# iorx74m register map
Registers are 32-bit, access not given, no defined reset value unless marked. A register's access mark holds for its fields unless they carry their own. Addresses are absolute; registers are grouped by the start of their names; [hi:lo] are bit positions; {n}, {i} and the like mark numbered series.

## ADC
0x87438000 ADC_B
  [0] ADCLKENR.CLKEN
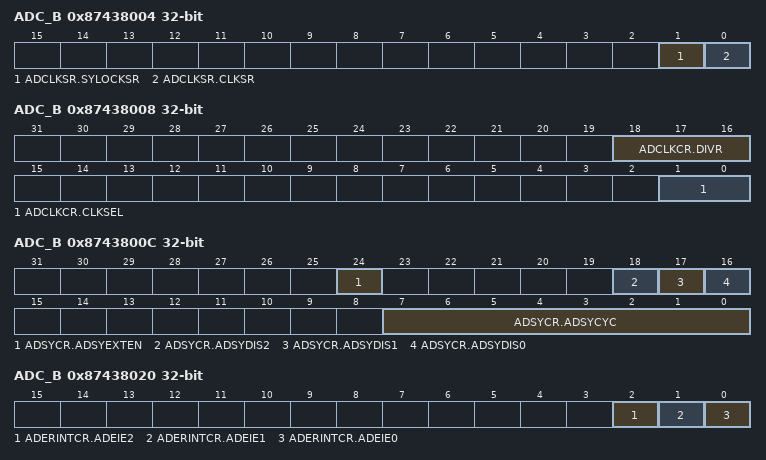
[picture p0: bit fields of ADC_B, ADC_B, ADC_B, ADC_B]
0x87438004 ADC_B
  [1] ADCLKSR.SYLOCKSR, [0] ADCLKSR.CLKSR
0x87438008 ADC_B
  [18:16] ADCLKCR.DIVR, [1:0] ADCLKCR.CLKSEL
0x8743800C ADC_B
  [24] ADSYCR.ADSYEXTEN, [18] ADSYCR.ADSYDIS2, [17] ADSYCR.ADSYDIS1, [16] ADSYCR.ADSYDIS0, [7:0] ADSYCR.ADSYCYC
0x87438010 ADC_B
  [0] ADUSLPCR0.ADUSLP0
0x87438014 ADC_B
  [0] ADUSLPCR1.ADUSLP1
0x87438018 ADC_B
  [0] ADUSLPCR2.ADUSLP2
0x87438020 ADC_B
  [2] ADERINTCR.ADEIE2, [1] ADERINTCR.ADEIE1, [0] ADERINTCR.ADEIE0
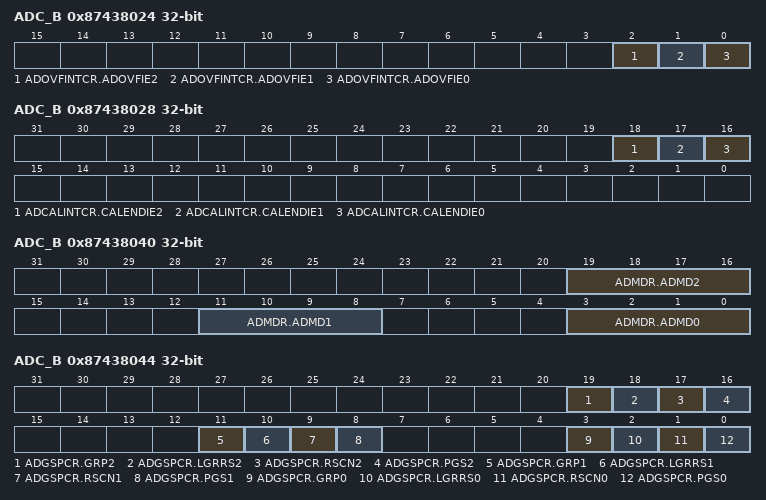
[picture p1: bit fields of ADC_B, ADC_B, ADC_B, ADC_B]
0x87438024 ADC_B
  [2] ADOVFINTCR.ADOVFIE2, [1] ADOVFINTCR.ADOVFIE1, [0] ADOVFINTCR.ADOVFIE0
0x87438028 ADC_B
  [18] ADCALINTCR.CALENDIE2, [17] ADCALINTCR.CALENDIE1, [16] ADCALINTCR.CALENDIE0
0x87438040 ADC_B
  [19:16] ADMDR.ADMD2, [11:8] ADMDR.ADMD1, [3:0] ADMDR.ADMD0
0x87438044 ADC_B
  [19] ADGSPCR.GRP2, [18] ADGSPCR.LGRRS2, [17] ADGSPCR.RSCN2, [16] ADGSPCR.PGS2, [11] ADGSPCR.GRP1, [10] ADGSPCR.LGRRS1, [9] ADGSPCR.RSCN1, [8] ADGSPCR.PGS1, [3] ADGSPCR.GRP0, [2] ADGSPCR.LGRRS0, [1] ADGSPCR.RSCN0, [0] ADGSPCR.PGS0
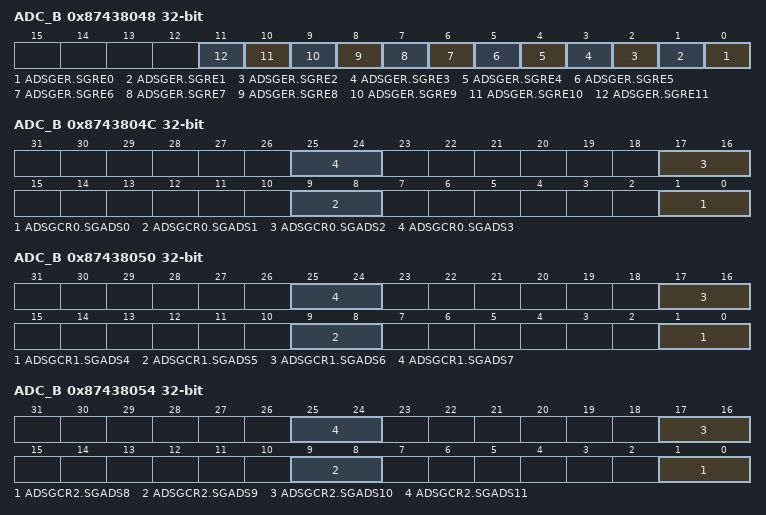
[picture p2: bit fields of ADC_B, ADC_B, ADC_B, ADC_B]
0x87438048 ADC_B
  [n] ADSGER.SGRE{n} (n=0..11)
0x8743804C ADC_B
  [8n+1:8n] ADSGCR0.SGADS{n} (n=0..3)
0x87438050 ADC_B
  [8n-31:8n-32] ADSGCR1.SGADS{n} (n=4..7)
0x87438054 ADC_B
  [8n-63:8n-64] ADSGCR2.SGADS{n} (n=8..11)
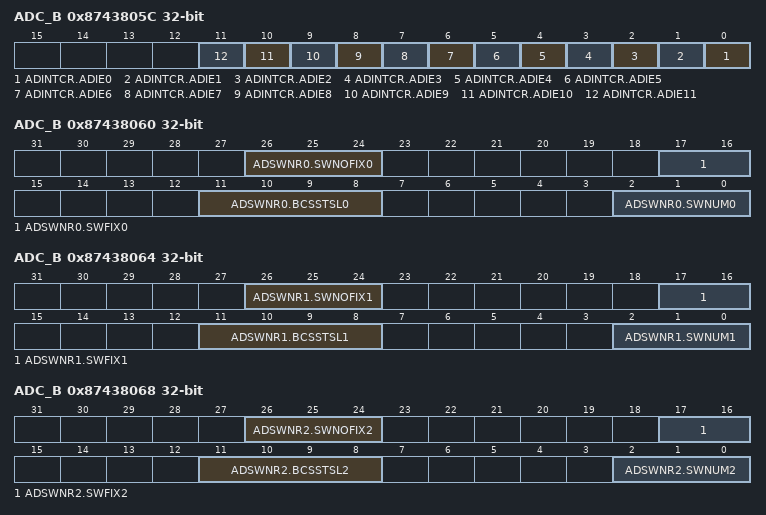
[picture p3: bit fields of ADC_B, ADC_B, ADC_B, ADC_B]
0x8743805C ADC_B
  [n] ADINTCR.ADIE{n} (n=0..11)
0x87438060 ADC_B
  [26:24] ADSWNR0.SWNOFIX0, [17:16] ADSWNR0.SWFIX0, [11:8] ADSWNR0.BCSSTSL0, [2:0] ADSWNR0.SWNUM0
0x87438064 ADC_B
  [26:24] ADSWNR1.SWNOFIX1, [17:16] ADSWNR1.SWFIX1, [11:8] ADSWNR1.BCSSTSL1, [2:0] ADSWNR1.SWNUM1
0x87438068 ADC_B
  [26:24] ADSWNR2.SWNOFIX2, [17:16] ADSWNR2.SWFIX2, [11:8] ADSWNR2.BCSSTSL2, [2:0] ADSWNR2.SWNUM2
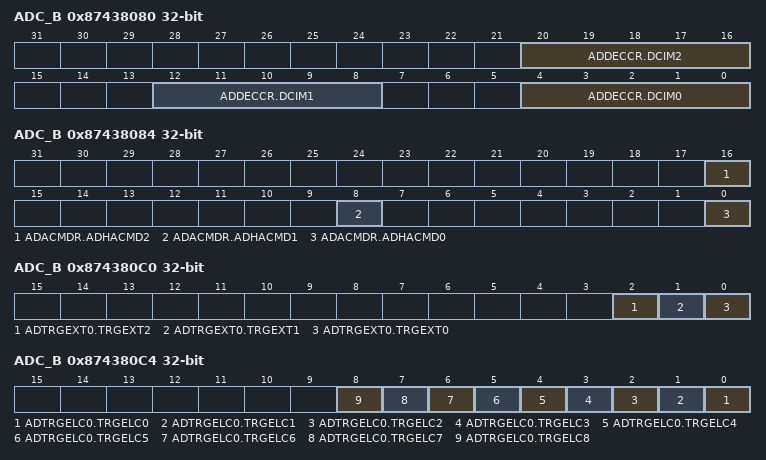
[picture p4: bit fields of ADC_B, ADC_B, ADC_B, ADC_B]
0x87438080 ADC_B
  [20:16] ADDECCR.DCIM2, [12:8] ADDECCR.DCIM1, [4:0] ADDECCR.DCIM0
0x87438084 ADC_B
  [16] ADACMDR.ADHACMD2, [8] ADACMDR.ADHACMD1, [0] ADACMDR.ADHACMD0
0x874380C0 ADC_B
  [2] ADTRGEXT0.TRGEXT2, [1] ADTRGEXT0.TRGEXT1, [0] ADTRGEXT0.TRGEXT0
0x874380C4 ADC_B
  [n] ADTRGELC0.TRGELC{n} (n=0..8)
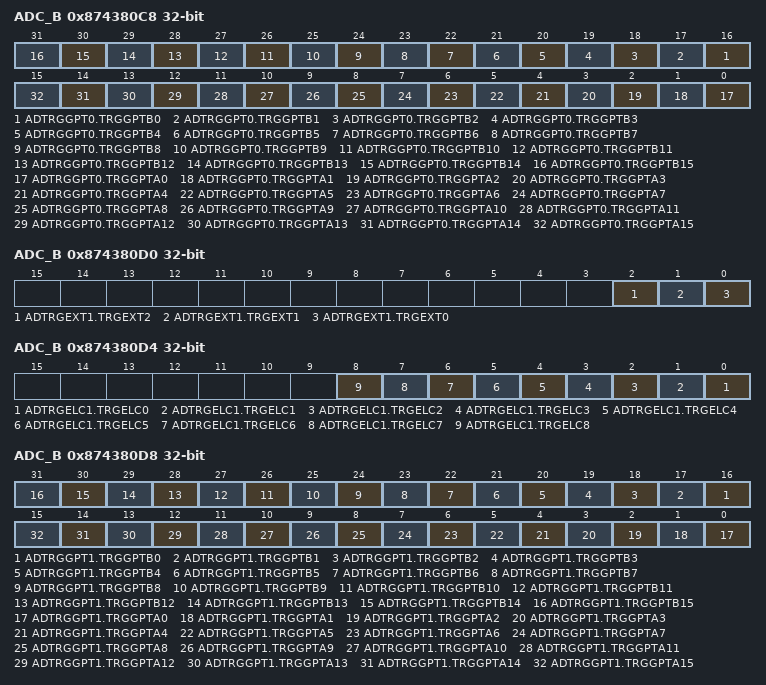
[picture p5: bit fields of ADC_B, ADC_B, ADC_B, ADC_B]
0x874380C8 ADC_B
  [n+16] ADTRGGPT0.TRGGPTB{n} (n=0..15), [n] ADTRGGPT0.TRGGPTA{n} (n=0..15)
0x874380D0 ADC_B
  [2] ADTRGEXT1.TRGEXT2, [1] ADTRGEXT1.TRGEXT1, [0] ADTRGEXT1.TRGEXT0
0x874380D4 ADC_B
  [n] ADTRGELC1.TRGELC{n} (n=0..8)
0x874380D8 ADC_B
  [n+16] ADTRGGPT1.TRGGPTB{n} (n=0..15), [n] ADTRGGPT1.TRGGPTA{n} (n=0..15)
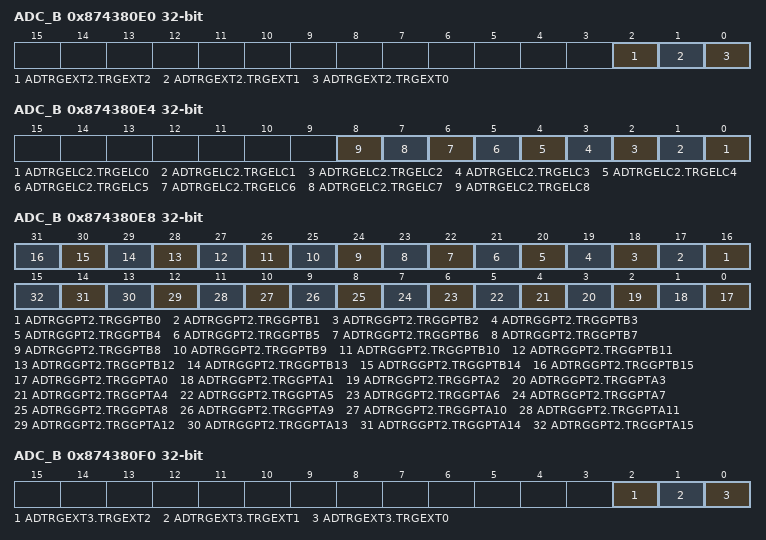
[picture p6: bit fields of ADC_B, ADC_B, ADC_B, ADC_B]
0x874380E0 ADC_B
  [2] ADTRGEXT2.TRGEXT2, [1] ADTRGEXT2.TRGEXT1, [0] ADTRGEXT2.TRGEXT0
0x874380E4 ADC_B
  [n] ADTRGELC2.TRGELC{n} (n=0..8)
0x874380E8 ADC_B
  [n+16] ADTRGGPT2.TRGGPTB{n} (n=0..15), [n] ADTRGGPT2.TRGGPTA{n} (n=0..15)
0x874380F0 ADC_B
  [2] ADTRGEXT3.TRGEXT2, [1] ADTRGEXT3.TRGEXT1, [0] ADTRGEXT3.TRGEXT0
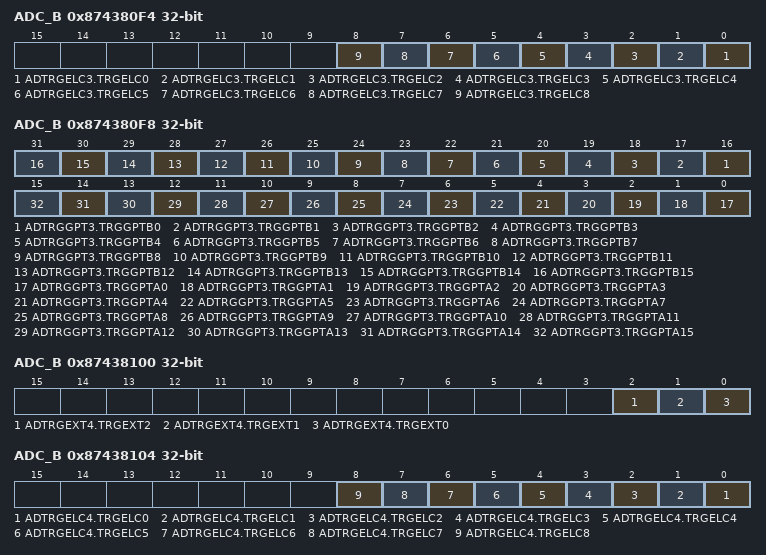
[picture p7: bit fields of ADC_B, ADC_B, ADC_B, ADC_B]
0x874380F4 ADC_B
  [n] ADTRGELC3.TRGELC{n} (n=0..8)
0x874380F8 ADC_B
  [n+16] ADTRGGPT3.TRGGPTB{n} (n=0..15), [n] ADTRGGPT3.TRGGPTA{n} (n=0..15)
0x87438100 ADC_B
  [2] ADTRGEXT4.TRGEXT2, [1] ADTRGEXT4.TRGEXT1, [0] ADTRGEXT4.TRGEXT0
0x87438104 ADC_B
  [n] ADTRGELC4.TRGELC{n} (n=0..8)
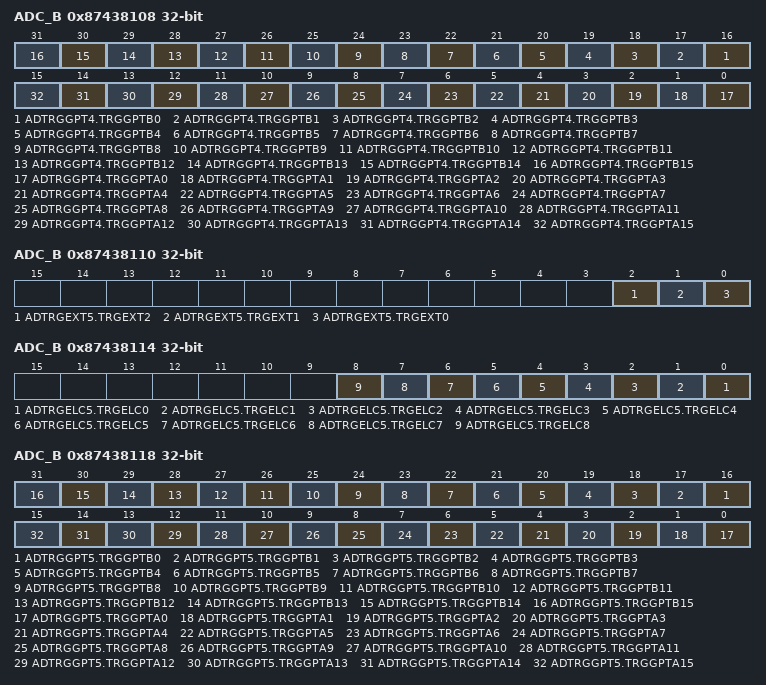
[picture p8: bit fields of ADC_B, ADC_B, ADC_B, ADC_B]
0x87438108 ADC_B
  [n+16] ADTRGGPT4.TRGGPTB{n} (n=0..15), [n] ADTRGGPT4.TRGGPTA{n} (n=0..15)
0x87438110 ADC_B
  [2] ADTRGEXT5.TRGEXT2, [1] ADTRGEXT5.TRGEXT1, [0] ADTRGEXT5.TRGEXT0
0x87438114 ADC_B
  [n] ADTRGELC5.TRGELC{n} (n=0..8)
0x87438118 ADC_B
  [n+16] ADTRGGPT5.TRGGPTB{n} (n=0..15), [n] ADTRGGPT5.TRGGPTA{n} (n=0..15)
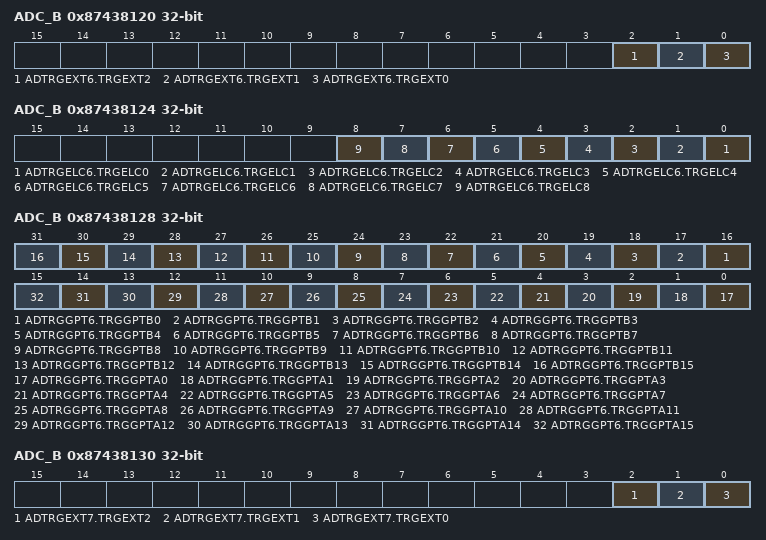
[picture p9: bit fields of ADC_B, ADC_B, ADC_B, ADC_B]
0x87438120 ADC_B
  [2] ADTRGEXT6.TRGEXT2, [1] ADTRGEXT6.TRGEXT1, [0] ADTRGEXT6.TRGEXT0
0x87438124 ADC_B
  [n] ADTRGELC6.TRGELC{n} (n=0..8)
0x87438128 ADC_B
  [n+16] ADTRGGPT6.TRGGPTB{n} (n=0..15), [n] ADTRGGPT6.TRGGPTA{n} (n=0..15)
0x87438130 ADC_B
  [2] ADTRGEXT7.TRGEXT2, [1] ADTRGEXT7.TRGEXT1, [0] ADTRGEXT7.TRGEXT0
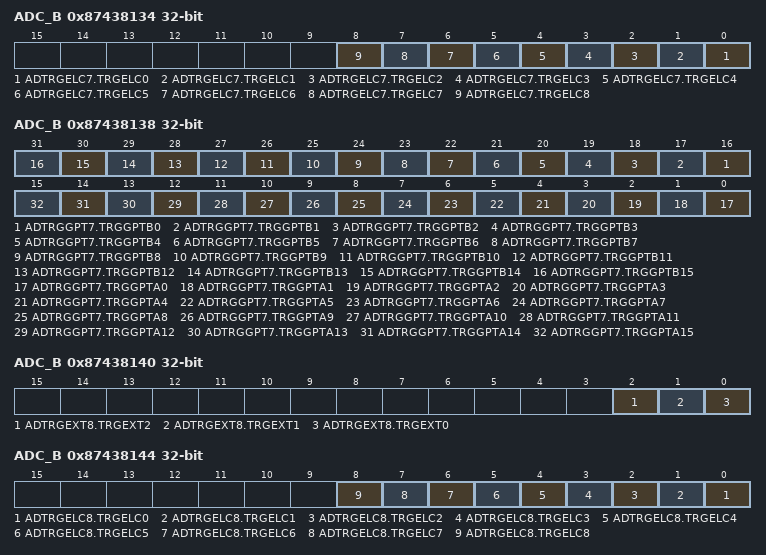
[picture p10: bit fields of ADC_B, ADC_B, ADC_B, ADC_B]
0x87438134 ADC_B
  [n] ADTRGELC7.TRGELC{n} (n=0..8)
0x87438138 ADC_B
  [n+16] ADTRGGPT7.TRGGPTB{n} (n=0..15), [n] ADTRGGPT7.TRGGPTA{n} (n=0..15)
0x87438140 ADC_B
  [2] ADTRGEXT8.TRGEXT2, [1] ADTRGEXT8.TRGEXT1, [0] ADTRGEXT8.TRGEXT0
0x87438144 ADC_B
  [n] ADTRGELC8.TRGELC{n} (n=0..8)
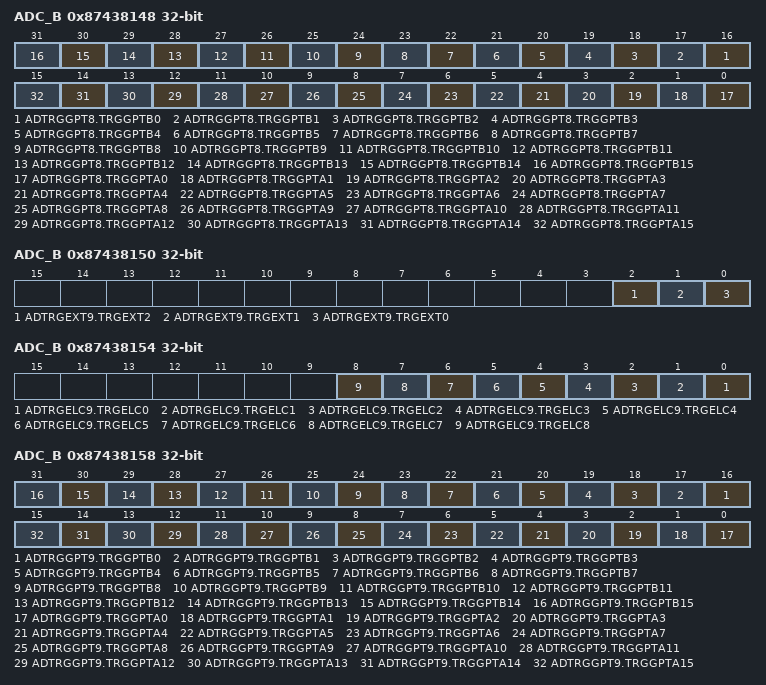
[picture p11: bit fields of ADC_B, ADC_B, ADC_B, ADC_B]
0x87438148 ADC_B
  [n+16] ADTRGGPT8.TRGGPTB{n} (n=0..15), [n] ADTRGGPT8.TRGGPTA{n} (n=0..15)
0x87438150 ADC_B
  [2] ADTRGEXT9.TRGEXT2, [1] ADTRGEXT9.TRGEXT1, [0] ADTRGEXT9.TRGEXT0
0x87438154 ADC_B
  [n] ADTRGELC9.TRGELC{n} (n=0..8)
0x87438158 ADC_B
  [n+16] ADTRGGPT9.TRGGPTB{n} (n=0..15), [n] ADTRGGPT9.TRGGPTA{n} (n=0..15)
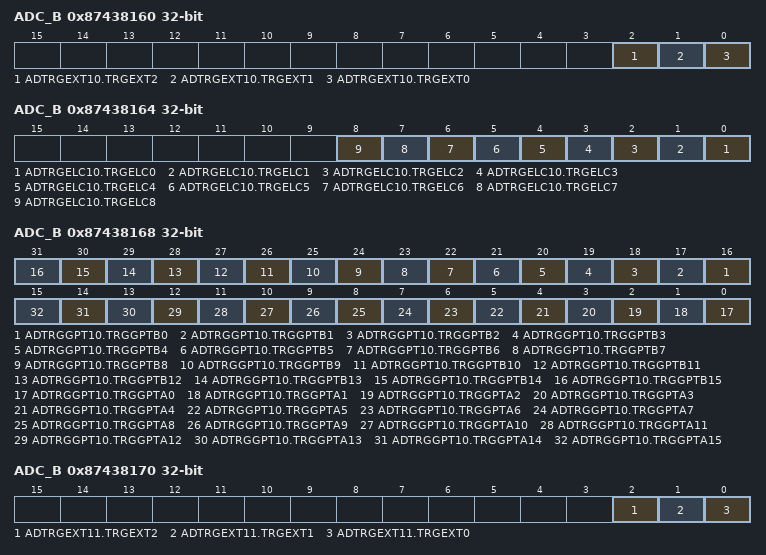
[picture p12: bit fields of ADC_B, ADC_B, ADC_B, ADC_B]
0x87438160 ADC_B
  [2] ADTRGEXT10.TRGEXT2, [1] ADTRGEXT10.TRGEXT1, [0] ADTRGEXT10.TRGEXT0
0x87438164 ADC_B
  [n] ADTRGELC10.TRGELC{n} (n=0..8)
0x87438168 ADC_B
  [n+16] ADTRGGPT10.TRGGPTB{n} (n=0..15), [n] ADTRGGPT10.TRGGPTA{n} (n=0..15)
0x87438170 ADC_B
  [2] ADTRGEXT11.TRGEXT2, [1] ADTRGEXT11.TRGEXT1, [0] ADTRGEXT11.TRGEXT0
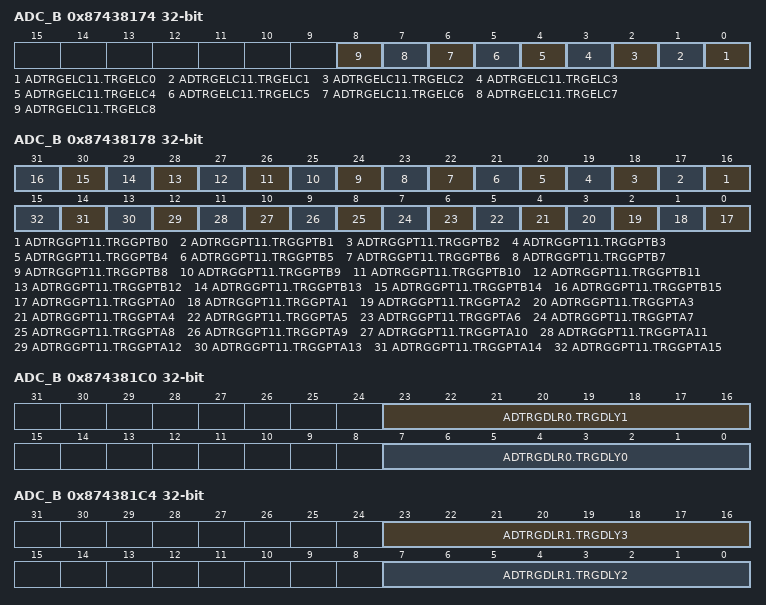
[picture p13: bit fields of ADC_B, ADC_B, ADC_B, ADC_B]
0x87438174 ADC_B
  [n] ADTRGELC11.TRGELC{n} (n=0..8)
0x87438178 ADC_B
  [n+16] ADTRGGPT11.TRGGPTB{n} (n=0..15), [n] ADTRGGPT11.TRGGPTA{n} (n=0..15)
0x874381C0 ADC_B
  [23:16] ADTRGDLR0.TRGDLY1, [7:0] ADTRGDLR0.TRGDLY0
0x874381C4 ADC_B
  [23:16] ADTRGDLR1.TRGDLY3, [7:0] ADTRGDLR1.TRGDLY2
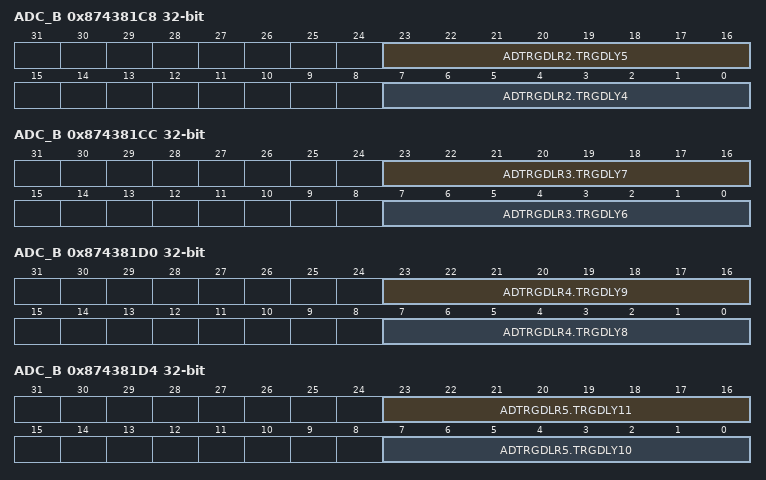
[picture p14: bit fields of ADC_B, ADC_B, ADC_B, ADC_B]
0x874381C8 ADC_B
  [23:16] ADTRGDLR2.TRGDLY5, [7:0] ADTRGDLR2.TRGDLY4
0x874381CC ADC_B
  [23:16] ADTRGDLR3.TRGDLY7, [7:0] ADTRGDLR3.TRGDLY6
0x874381D0 ADC_B
  [23:16] ADTRGDLR4.TRGDLY9, [7:0] ADTRGDLR4.TRGDLY8
0x874381D4 ADC_B
  [23:16] ADTRGDLR5.TRGDLY11, [7:0] ADTRGDLR5.TRGDLY10
0x87438200 ADC_B
  [31:24] ADSGDCR0.ADNDIS, [21] ADSGDCR0.ADDISN, [20] ADSGDCR0.ADDISP, [16] ADSGDCR0.ADDISEN, [2:0] ADSGDCR0.DIAGVAL
0x87438204 ADC_B
  [31:24] ADSGDCR1.ADNDIS, [21] ADSGDCR1.ADDISN, [20] ADSGDCR1.ADDISP, [16] ADSGDCR1.ADDISEN, [2:0] ADSGDCR1.DIAGVAL
0x87438208 ADC_B
  [31:24] ADSGDCR2.ADNDIS, [21] ADSGDCR2.ADDISN, [20] ADSGDCR2.ADDISP, [16] ADSGDCR2.ADDISEN, [2:0] ADSGDCR2.DIAGVAL
0x8743820C ADC_B
  [31:24] ADSGDCR3.ADNDIS, [21] ADSGDCR3.ADDISN, [20] ADSGDCR3.ADDISP, [16] ADSGDCR3.ADDISEN, [2:0] ADSGDCR3.DIAGVAL
0x87438210 ADC_B
  [31:24] ADSGDCR4.ADNDIS, [21] ADSGDCR4.ADDISN, [20] ADSGDCR4.ADDISP, [16] ADSGDCR4.ADDISEN, [2:0] ADSGDCR4.DIAGVAL
0x87438214 ADC_B
  [31:24] ADSGDCR5.ADNDIS, [21] ADSGDCR5.ADDISN, [20] ADSGDCR5.ADDISP, [16] ADSGDCR5.ADDISEN, [2:0] ADSGDCR5.DIAGVAL
0x87438218 ADC_B
  [31:24] ADSGDCR6.ADNDIS, [21] ADSGDCR6.ADDISN, [20] ADSGDCR6.ADDISP, [16] ADSGDCR6.ADDISEN, [2:0] ADSGDCR6.DIAGVAL
0x8743821C ADC_B
  [31:24] ADSGDCR7.ADNDIS, [21] ADSGDCR7.ADDISN, [20] ADSGDCR7.ADDISP, [16] ADSGDCR7.ADDISEN, [2:0] ADSGDCR7.DIAGVAL
0x87438220 ADC_B
  [31:24] ADSGDCR8.ADNDIS, [21] ADSGDCR8.ADDISN, [20] ADSGDCR8.ADDISP, [16] ADSGDCR8.ADDISEN, [2:0] ADSGDCR8.DIAGVAL
0x87438224 ADC_B
  [31:24] ADSGDCR9.ADNDIS, [21] ADSGDCR9.ADDISN, [20] ADSGDCR9.ADDISP, [16] ADSGDCR9.ADDISEN, [2:0] ADSGDCR9.DIAGVAL
0x87438228 ADC_B
  [31:24] ADSGDCR10.ADNDIS, [21] ADSGDCR10.ADDISN, [20] ADSGDCR10.ADDISP, [16] ADSGDCR10.ADDISEN, [2:0] ADSGDCR10.DIAGVAL
0x8743822C ADC_B
  [31:24] ADSGDCR11.ADNDIS, [21] ADSGDCR11.ADDISN, [20] ADSGDCR11.ADDISP, [16] ADSGDCR11.ADDISEN, [2:0] ADSGDCR11.DIAGVAL
0x87438240 ADC_B
  [25:16] ADSSTR0.SST1, [9:0] ADSSTR0.SST0
0x87438244 ADC_B
  [25:16] ADSSTR1.SST3, [9:0] ADSSTR1.SST2
0x87438248 ADC_B
  [25:16] ADSSTR2.SST5, [9:0] ADSSTR2.SST4
0x8743824C ADC_B
  [25:16] ADSSTR3.SST7, [9:0] ADSSTR3.SST6
0x87438250 ADC_B
  [25:16] ADSSTR4.SST9, [9:0] ADSSTR4.SST8
0x87438254 ADC_B
  [25:16] ADSSTR5.SST11, [9:0] ADSSTR5.SST10
0x87438258 ADC_B
  [25:16] ADSSTR6.SST13, [9:0] ADSSTR6.SST12
0x8743825C ADC_B
  [25:16] ADSSTR7.SST15, [9:0] ADSSTR7.SST14
0x87438260 ADC_B
  [21:16] ADCNVSTR.CST2, [13:8] ADCNVSTR.CST1, [5:0] ADCNVSTR.CST0
0x87438264 ADC_B
  [21:16] ADCALSTCR.CALADCST, [9:0] ADCALSTCR.CALADSST
0x87438280 ADC_B
  [18] ADSHCR0.SHMD2, [17] ADSHCR0.SHMD1, [16] ADSHCR0.SHMD0, [2] ADSHCR0.SHEN2, [1] ADSHCR0.SHEN1, [0] ADSHCR0.SHEN0
0x87438284 ADC_B
  [4] ADSHDCR0.SH0DIS, [0] ADSHDCR0.SH0DISEN
0x87438288 ADC_B
  [18:16] ADSHSTR0.SHHST, [7:0] ADSHSTR0.SHSST
0x874382B0 ADC_B
  [18:16] ADCALSHCR.CALSHHST, [7:0] ADCALSHCR.CALSHSST
0x87438310 ADC_B
  [18] ADSHSBPCR.SHSBN2, [17] ADSHSBPCR.SHSBN1, [16] ADSHSBPCR.SHSBN0, [2] ADSHSBPCR.SHSBP2, [1] ADSHSBPCR.SHSBP1, [0] ADSHSBPCR.SHSBP0
0x87438314 ADC_B
  [n] ADSHDBPCR.SHDBP{n} (n=0..11)
0x87438318 ADC_B
  [4n+2:4n] ADSHSDCR0.SHDIAG{n} (n=0..7)
0x8743831C ADC_B
  [4n-30:4n-32] ADSHSDCR1.SHDIAG{n} (n=8..11)
0x87438320 ADC_B
  [0] ADREFCR.VDE
0x87438340 ADC_B
  [8n+1:8n] ADDFSR0.DFSEL{n} (n=0..3)
0x87438344 ADC_B
  [8n+1:8n] ADDFSR1.DFSEL{n} (n=0..3)
0x87438348 ADC_B
  [8n+1:8n] ADDFSR2.DFSEL{n} (n=0..3)
0x87438360 ADC_B
  [15:0] ADUOFTR0.UOFSET
0x87438364 ADC_B
  [15:0] ADUOFTR1.UOFSET
0x87438368 ADC_B
  [15:0] ADUOFTR2.UOFSET
0x8743836C ADC_B
  [15:0] ADUOFTR3.UOFSET
0x87438370 ADC_B
  [15:0] ADUOFTR4.UOFSET
0x87438374 ADC_B
  [15:0] ADUOFTR5.UOFSET
0x87438378 ADC_B
  [15:0] ADUOFTR6.UOFSET
0x8743837C ADC_B
  [15:0] ADUOFTR7.UOFSET
0x87438380 ADC_B
  [15:0] ADUGTR0.UGAIN
0x87438384 ADC_B
  [15:0] ADUGTR1.UGAIN
0x87438388 ADC_B
  [15:0] ADUGTR2.UGAIN
0x8743838C ADC_B
  [15:0] ADUGTR3.UGAIN
0x87438390 ADC_B
  [15:0] ADUGTR4.UGAIN
0x87438394 ADC_B
  [15:0] ADUGTR5.UGAIN
0x87438398 ADC_B
  [15:0] ADUGTR6.UGAIN
0x8743839C ADC_B
  [15:0] ADUGTR7.UGAIN
0x874383A0 ADC_B
  [n] ADLIMINTCR.LIMIE{n} (n=0..11)
0x874383A4 ADC_B
  [31:16] ADLIMTR0.LIMU, [15:0] ADLIMTR0.LIML
0x874383A8 ADC_B
  [31:16] ADLIMTR1.LIMU, [15:0] ADLIMTR1.LIML
0x874383AC ADC_B
  [31:16] ADLIMTR2.LIMU, [15:0] ADLIMTR2.LIML
0x874383B0 ADC_B
  [31:16] ADLIMTR3.LIMU, [15:0] ADLIMTR3.LIML
0x874383B4 ADC_B
  [31:16] ADLIMTR4.LIMU, [15:0] ADLIMTR4.LIML
0x874383B8 ADC_B
  [31:16] ADLIMTR5.LIMU, [15:0] ADLIMTR5.LIML
0x874383BC ADC_B
  [31:16] ADLIMTR6.LIMU, [15:0] ADLIMTR6.LIML
0x874383C0 ADC_B
  [31:16] ADLIMTR7.LIMU, [15:0] ADLIMTR7.LIML
0x87438400 ADC_B
  [n] ADCMPENR.CMPEN{n} (n=0..7)
0x87438404 ADC_B
  [n] ADCMPINTCR.CMPIE{n} (n=0..7)
0x87438408 ADC_B
  [n+16] ADCCMPCR[0].CCMPTBL{n} (n=0..7), [1:0] ADCCMPCR[0].CCMPCND
0x8743840C ADC_B
  [n+16] ADCCMPCR[1].CCMPTBL{n} (n=0..7), [1:0] ADCCMPCR[1].CCMPCND
0x87438410 ADC_B
  [n+16] ADCCMPCR[2].CCMPTBL{n} (n=0..7), [1:0] ADCCMPCR[2].CCMPCND
0x87438414 ADC_B
  [n+16] ADCCMPCR[3].CCMPTBL{n} (n=0..7), [1:0] ADCCMPCR[3].CCMPCND
0x87438418 ADC_B
  [n+16] ADCCMPCR[4].CCMPTBL{n} (n=0..7), [1:0] ADCCMPCR[4].CCMPCND
0x8743841C ADC_B
  [n+16] ADCCMPCR[5].CCMPTBL{n} (n=0..7), [1:0] ADCCMPCR[5].CCMPCND
0x87438420 ADC_B
  [n+16] ADCCMPCR[6].CCMPTBL{n} (n=0..7), [1:0] ADCCMPCR[6].CCMPCND
0x87438424 ADC_B
  [n+16] ADCCMPCR[7].CCMPTBL{n} (n=0..7), [1:0] ADCCMPCR[7].CCMPCND
0x87438448 ADC_B
  [8n+1:8n] ADCMPMDR0.CMPMD{n} (n=0..3)
0x8743844C ADC_B
  [8n-31:8n-32] ADCMPMDR1.CMPMD{n} (n=4..7)
0x87438458 ADC_B
  [31:16] ADCMPTBR[0].CMPTBH, [15:0] ADCMPTBR[0].CMPTBL
0x8743845C ADC_B
  [31:16] ADCMPTBR[1].CMPTBH, [15:0] ADCMPTBR[1].CMPTBL
0x87438460 ADC_B
  [31:16] ADCMPTBR[2].CMPTBH, [15:0] ADCMPTBR[2].CMPTBL
0x87438464 ADC_B
  [31:16] ADCMPTBR[3].CMPTBH, [15:0] ADCMPTBR[3].CMPTBL
0x87438468 ADC_B
  [31:16] ADCMPTBR[4].CMPTBH, [15:0] ADCMPTBR[4].CMPTBL
0x8743846C ADC_B
  [31:16] ADCMPTBR[5].CMPTBH, [15:0] ADCMPTBR[5].CMPTBL
0x87438470 ADC_B
  [31:16] ADCMPTBR[6].CMPTBH, [15:0] ADCMPTBR[6].CMPTBL
0x87438474 ADC_B
  [31:16] ADCMPTBR[7].CMPTBH, [15:0] ADCMPTBR[7].CMPTBL
0x874384C0 ADC_B
  [n+16] ADFIFOCR.FIFOCE{n} (n=0..11), [n] ADFIFOCR.FIFOEN{n} (n=0..11)
0x874384C4 ADC_B
  [n] ADFIFOINTCR.FIFOIE{n} (n=0..11)
0x874384C8 ADC_B
  [20:16] ADFIFOINTLR0.FIFOILV1, [4:0] ADFIFOINTLR0.FIFOILV0
0x874384CC ADC_B
  [20:16] ADFIFOINTLR1.FIFOILV3, [4:0] ADFIFOINTLR1.FIFOILV2
0x874384D0 ADC_B
  [20:16] ADFIFOINTLR2.FIFOILV5, [4:0] ADFIFOINTLR2.FIFOILV4
0x874384D4 ADC_B
  [20:16] ADFIFOINTLR3.FIFOILV7, [4:0] ADFIFOINTLR3.FIFOILV6
0x874384D8 ADC_B
  [20:16] ADFIFOINTLR4.FIFOILV9, [4:0] ADFIFOINTLR4.FIFOILV8
0x874384DC ADC_B
  [20:16] ADFIFOINTLR5.FIFOILV11, [4:0] ADFIFOINTLR5.FIFOILV10
0x87438600 ADC_B
  [19:16] ADCHCR0.SSTSEL, [15] ADCHCR0.AINMD, [14:8] ADCHCR0.CNVCS, [4:0] ADCHCR0.SGSEL
0x87438604 ADC_B
  [27:24] ADDOPCRA0.OFSETSEL, [19:16] ADDOPCRA0.GAINSEL, [2:0] ADDOPCRA0.DFSEL
0x87438608 ADC_B
  [n+16] ADDOPCRB0.CMPTBLE{n} (n=0..7), [11:8] ADDOPCRB0.ADC, [1:0] ADDOPCRB0.AVEMD
0x8743860C ADC_B
  [20] ADDOPCRC0.SIGNSEL, [17:16] ADDOPCRC0.ADPRC, [3:0] ADDOPCRC0.LIMTBLS
0x87438610 ADC_B
  [19:16] ADCHCR1.SSTSEL, [15] ADCHCR1.AINMD, [14:8] ADCHCR1.CNVCS, [4:0] ADCHCR1.SGSEL
0x87438614 ADC_B
  [27:24] ADDOPCRA1.OFSETSEL, [19:16] ADDOPCRA1.GAINSEL, [2:0] ADDOPCRA1.DFSEL
0x87438618 ADC_B
  [n+16] ADDOPCRB1.CMPTBLE{n} (n=0..7), [11:8] ADDOPCRB1.ADC, [1:0] ADDOPCRB1.AVEMD
0x8743861C ADC_B
  [20] ADDOPCRC1.SIGNSEL, [17:16] ADDOPCRC1.ADPRC, [3:0] ADDOPCRC1.LIMTBLS
0x87438620 ADC_B
  [19:16] ADCHCR2.SSTSEL, [15] ADCHCR2.AINMD, [14:8] ADCHCR2.CNVCS, [4:0] ADCHCR2.SGSEL
0x87438624 ADC_B
  [27:24] ADDOPCRA2.OFSETSEL, [19:16] ADDOPCRA2.GAINSEL, [2:0] ADDOPCRA2.DFSEL
0x87438628 ADC_B
  [n+16] ADDOPCRB2.CMPTBLE{n} (n=0..7), [11:8] ADDOPCRB2.ADC, [1:0] ADDOPCRB2.AVEMD
0x8743862C ADC_B
  [20] ADDOPCRC2.SIGNSEL, [17:16] ADDOPCRC2.ADPRC, [3:0] ADDOPCRC2.LIMTBLS
0x87438630 ADC_B
  [19:16] ADCHCR3.SSTSEL, [15] ADCHCR3.AINMD, [14:8] ADCHCR3.CNVCS, [4:0] ADCHCR3.SGSEL
0x87438634 ADC_B
  [27:24] ADDOPCRA3.OFSETSEL, [19:16] ADDOPCRA3.GAINSEL, [2:0] ADDOPCRA3.DFSEL
0x87438638 ADC_B
  [n+16] ADDOPCRB3.CMPTBLE{n} (n=0..7), [11:8] ADDOPCRB3.ADC, [1:0] ADDOPCRB3.AVEMD
0x8743863C ADC_B
  [20] ADDOPCRC3.SIGNSEL, [17:16] ADDOPCRC3.ADPRC, [3:0] ADDOPCRC3.LIMTBLS
0x87438640 ADC_B
  [19:16] ADCHCR4.SSTSEL, [15] ADCHCR4.AINMD, [14:8] ADCHCR4.CNVCS, [4:0] ADCHCR4.SGSEL
0x87438644 ADC_B
  [27:24] ADDOPCRA4.OFSETSEL, [19:16] ADDOPCRA4.GAINSEL, [2:0] ADDOPCRA4.DFSEL
0x87438648 ADC_B
  [n+16] ADDOPCRB4.CMPTBLE{n} (n=0..7), [11:8] ADDOPCRB4.ADC, [1:0] ADDOPCRB4.AVEMD
0x8743864C ADC_B
  [20] ADDOPCRC4.SIGNSEL, [17:16] ADDOPCRC4.ADPRC, [3:0] ADDOPCRC4.LIMTBLS
0x87438650 ADC_B
  [19:16] ADCHCR5.SSTSEL, [15] ADCHCR5.AINMD, [14:8] ADCHCR5.CNVCS, [4:0] ADCHCR5.SGSEL
0x87438654 ADC_B
  [27:24] ADDOPCRA5.OFSETSEL, [19:16] ADDOPCRA5.GAINSEL, [2:0] ADDOPCRA5.DFSEL
0x87438658 ADC_B
  [n+16] ADDOPCRB5.CMPTBLE{n} (n=0..7), [11:8] ADDOPCRB5.ADC, [1:0] ADDOPCRB5.AVEMD
0x8743865C ADC_B
  [20] ADDOPCRC5.SIGNSEL, [17:16] ADDOPCRC5.ADPRC, [3:0] ADDOPCRC5.LIMTBLS
0x87438660 ADC_B
  [19:16] ADCHCR6.SSTSEL, [15] ADCHCR6.AINMD, [14:8] ADCHCR6.CNVCS, [4:0] ADCHCR6.SGSEL
0x87438664 ADC_B
  [27:24] ADDOPCRA6.OFSETSEL, [19:16] ADDOPCRA6.GAINSEL, [2:0] ADDOPCRA6.DFSEL
0x87438668 ADC_B
  [n+16] ADDOPCRB6.CMPTBLE{n} (n=0..7), [11:8] ADDOPCRB6.ADC, [1:0] ADDOPCRB6.AVEMD
0x8743866C ADC_B
  [20] ADDOPCRC6.SIGNSEL, [17:16] ADDOPCRC6.ADPRC, [3:0] ADDOPCRC6.LIMTBLS
0x87438670 ADC_B
  [19:16] ADCHCR7.SSTSEL, [15] ADCHCR7.AINMD, [14:8] ADCHCR7.CNVCS, [4:0] ADCHCR7.SGSEL
0x87438674 ADC_B
  [27:24] ADDOPCRA7.OFSETSEL, [19:16] ADDOPCRA7.GAINSEL, [2:0] ADDOPCRA7.DFSEL
0x87438678 ADC_B
  [n+16] ADDOPCRB7.CMPTBLE{n} (n=0..7), [11:8] ADDOPCRB7.ADC, [1:0] ADDOPCRB7.AVEMD
0x8743867C ADC_B
  [20] ADDOPCRC7.SIGNSEL, [17:16] ADDOPCRC7.ADPRC, [3:0] ADDOPCRC7.LIMTBLS
0x87438680 ADC_B
  [19:16] ADCHCR8.SSTSEL, [15] ADCHCR8.AINMD, [14:8] ADCHCR8.CNVCS, [4:0] ADCHCR8.SGSEL
0x87438684 ADC_B
  [27:24] ADDOPCRA8.OFSETSEL, [19:16] ADDOPCRA8.GAINSEL, [2:0] ADDOPCRA8.DFSEL
0x87438688 ADC_B
  [n+16] ADDOPCRB8.CMPTBLE{n} (n=0..7), [11:8] ADDOPCRB8.ADC, [1:0] ADDOPCRB8.AVEMD
0x8743868C ADC_B
  [20] ADDOPCRC8.SIGNSEL, [17:16] ADDOPCRC8.ADPRC, [3:0] ADDOPCRC8.LIMTBLS
0x87438690 ADC_B
  [19:16] ADCHCR9.SSTSEL, [15] ADCHCR9.AINMD, [14:8] ADCHCR9.CNVCS, [4:0] ADCHCR9.SGSEL
0x87438694 ADC_B
  [27:24] ADDOPCRA9.OFSETSEL, [19:16] ADDOPCRA9.GAINSEL, [2:0] ADDOPCRA9.DFSEL
0x87438698 ADC_B
  [n+16] ADDOPCRB9.CMPTBLE{n} (n=0..7), [11:8] ADDOPCRB9.ADC, [1:0] ADDOPCRB9.AVEMD
0x8743869C ADC_B
  [20] ADDOPCRC9.SIGNSEL, [17:16] ADDOPCRC9.ADPRC, [3:0] ADDOPCRC9.LIMTBLS
0x874386A0 ADC_B
  [19:16] ADCHCR10.SSTSEL, [15] ADCHCR10.AINMD, [14:8] ADCHCR10.CNVCS, [4:0] ADCHCR10.SGSEL
0x874386A4 ADC_B
  [27:24] ADDOPCRA10.OFSETSEL, [19:16] ADDOPCRA10.GAINSEL, [2:0] ADDOPCRA10.DFSEL
0x874386A8 ADC_B
  [n+16] ADDOPCRB10.CMPTBLE{n} (n=0..7), [11:8] ADDOPCRB10.ADC, [1:0] ADDOPCRB10.AVEMD
0x874386AC ADC_B
  [20] ADDOPCRC10.SIGNSEL, [17:16] ADDOPCRC10.ADPRC, [3:0] ADDOPCRC10.LIMTBLS
0x874386B0 ADC_B
  [19:16] ADCHCR11.SSTSEL, [15] ADCHCR11.AINMD, [14:8] ADCHCR11.CNVCS, [4:0] ADCHCR11.SGSEL
0x874386B4 ADC_B
  [27:24] ADDOPCRA11.OFSETSEL, [19:16] ADDOPCRA11.GAINSEL, [2:0] ADDOPCRA11.DFSEL
0x874386B8 ADC_B
  [n+16] ADDOPCRB11.CMPTBLE{n} (n=0..7), [11:8] ADDOPCRB11.ADC, [1:0] ADDOPCRB11.AVEMD
0x874386BC ADC_B
  [20] ADDOPCRC11.SIGNSEL, [17:16] ADDOPCRC11.ADPRC, [3:0] ADDOPCRC11.LIMTBLS
0x874386C0 ADC_B
  [19:16] ADCHCR12.SSTSEL, [15] ADCHCR12.AINMD, [14:8] ADCHCR12.CNVCS, [4:0] ADCHCR12.SGSEL
0x874386C4 ADC_B
  [27:24] ADDOPCRA12.OFSETSEL, [19:16] ADDOPCRA12.GAINSEL, [2:0] ADDOPCRA12.DFSEL
0x874386C8 ADC_B
  [n+16] ADDOPCRB12.CMPTBLE{n} (n=0..7), [11:8] ADDOPCRB12.ADC, [1:0] ADDOPCRB12.AVEMD
0x874386CC ADC_B
  [20] ADDOPCRC12.SIGNSEL, [17:16] ADDOPCRC12.ADPRC, [3:0] ADDOPCRC12.LIMTBLS
0x874386D0 ADC_B
  [19:16] ADCHCR13.SSTSEL, [15] ADCHCR13.AINMD, [14:8] ADCHCR13.CNVCS, [4:0] ADCHCR13.SGSEL
0x874386D4 ADC_B
  [27:24] ADDOPCRA13.OFSETSEL, [19:16] ADDOPCRA13.GAINSEL, [2:0] ADDOPCRA13.DFSEL
0x874386D8 ADC_B
  [n+16] ADDOPCRB13.CMPTBLE{n} (n=0..7), [11:8] ADDOPCRB13.ADC, [1:0] ADDOPCRB13.AVEMD
0x874386DC ADC_B
  [20] ADDOPCRC13.SIGNSEL, [17:16] ADDOPCRC13.ADPRC, [3:0] ADDOPCRC13.LIMTBLS
0x874386E0 ADC_B
  [19:16] ADCHCR14.SSTSEL, [15] ADCHCR14.AINMD, [14:8] ADCHCR14.CNVCS, [4:0] ADCHCR14.SGSEL
0x874386E4 ADC_B
  [27:24] ADDOPCRA14.OFSETSEL, [19:16] ADDOPCRA14.GAINSEL, [2:0] ADDOPCRA14.DFSEL
0x874386E8 ADC_B
  [n+16] ADDOPCRB14.CMPTBLE{n} (n=0..7), [11:8] ADDOPCRB14.ADC, [1:0] ADDOPCRB14.AVEMD
0x874386EC ADC_B
  [20] ADDOPCRC14.SIGNSEL, [17:16] ADDOPCRC14.ADPRC, [3:0] ADDOPCRC14.LIMTBLS
0x874386F0 ADC_B
  [19:16] ADCHCR15.SSTSEL, [15] ADCHCR15.AINMD, [14:8] ADCHCR15.CNVCS, [4:0] ADCHCR15.SGSEL
0x874386F4 ADC_B
  [27:24] ADDOPCRA15.OFSETSEL, [19:16] ADDOPCRA15.GAINSEL, [2:0] ADDOPCRA15.DFSEL
0x874386F8 ADC_B
  [n+16] ADDOPCRB15.CMPTBLE{n} (n=0..7), [11:8] ADDOPCRB15.ADC, [1:0] ADDOPCRB15.AVEMD
0x874386FC ADC_B
  [20] ADDOPCRC15.SIGNSEL, [17:16] ADDOPCRC15.ADPRC, [3:0] ADDOPCRC15.LIMTBLS
0x87438700 ADC_B
  [19:16] ADCHCR16.SSTSEL, [15] ADCHCR16.AINMD, [14:8] ADCHCR16.CNVCS, [4:0] ADCHCR16.SGSEL
0x87438704 ADC_B
  [27:24] ADDOPCRA16.OFSETSEL, [19:16] ADDOPCRA16.GAINSEL, [2:0] ADDOPCRA16.DFSEL
0x87438708 ADC_B
  [n+16] ADDOPCRB16.CMPTBLE{n} (n=0..7), [11:8] ADDOPCRB16.ADC, [1:0] ADDOPCRB16.AVEMD
0x8743870C ADC_B
  [20] ADDOPCRC16.SIGNSEL, [17:16] ADDOPCRC16.ADPRC, [3:0] ADDOPCRC16.LIMTBLS
0x87438710 ADC_B
  [19:16] ADCHCR17.SSTSEL, [15] ADCHCR17.AINMD, [14:8] ADCHCR17.CNVCS, [4:0] ADCHCR17.SGSEL
0x87438714 ADC_B
  [27:24] ADDOPCRA17.OFSETSEL, [19:16] ADDOPCRA17.GAINSEL, [2:0] ADDOPCRA17.DFSEL
0x87438718 ADC_B
  [n+16] ADDOPCRB17.CMPTBLE{n} (n=0..7), [11:8] ADDOPCRB17.ADC, [1:0] ADDOPCRB17.AVEMD
0x8743871C ADC_B
  [20] ADDOPCRC17.SIGNSEL, [17:16] ADDOPCRC17.ADPRC, [3:0] ADDOPCRC17.LIMTBLS
0x87438720 ADC_B
  [19:16] ADCHCR18.SSTSEL, [15] ADCHCR18.AINMD, [14:8] ADCHCR18.CNVCS, [4:0] ADCHCR18.SGSEL
0x87438724 ADC_B
  [27:24] ADDOPCRA18.OFSETSEL, [19:16] ADDOPCRA18.GAINSEL, [2:0] ADDOPCRA18.DFSEL
0x87438728 ADC_B
  [n+16] ADDOPCRB18.CMPTBLE{n} (n=0..7), [11:8] ADDOPCRB18.ADC, [1:0] ADDOPCRB18.AVEMD
0x8743872C ADC_B
  [20] ADDOPCRC18.SIGNSEL, [17:16] ADDOPCRC18.ADPRC, [3:0] ADDOPCRC18.LIMTBLS
0x87438730 ADC_B
  [19:16] ADCHCR19.SSTSEL, [15] ADCHCR19.AINMD, [14:8] ADCHCR19.CNVCS, [4:0] ADCHCR19.SGSEL
0x87438734 ADC_B
  [27:24] ADDOPCRA19.OFSETSEL, [19:16] ADDOPCRA19.GAINSEL, [2:0] ADDOPCRA19.DFSEL
0x87438738 ADC_B
  [n+16] ADDOPCRB19.CMPTBLE{n} (n=0..7), [11:8] ADDOPCRB19.ADC, [1:0] ADDOPCRB19.AVEMD
0x8743873C ADC_B
  [20] ADDOPCRC19.SIGNSEL, [17:16] ADDOPCRC19.ADPRC, [3:0] ADDOPCRC19.LIMTBLS
0x87438740 ADC_B
  [19:16] ADCHCR20.SSTSEL, [15] ADCHCR20.AINMD, [14:8] ADCHCR20.CNVCS, [4:0] ADCHCR20.SGSEL
0x87438744 ADC_B
  [27:24] ADDOPCRA20.OFSETSEL, [19:16] ADDOPCRA20.GAINSEL, [2:0] ADDOPCRA20.DFSEL
0x87438748 ADC_B
  [n+16] ADDOPCRB20.CMPTBLE{n} (n=0..7), [11:8] ADDOPCRB20.ADC, [1:0] ADDOPCRB20.AVEMD
0x8743874C ADC_B
  [20] ADDOPCRC20.SIGNSEL, [17:16] ADDOPCRC20.ADPRC, [3:0] ADDOPCRC20.LIMTBLS
0x87438750 ADC_B
  [19:16] ADCHCR21.SSTSEL, [15] ADCHCR21.AINMD, [14:8] ADCHCR21.CNVCS, [4:0] ADCHCR21.SGSEL
0x87438754 ADC_B
  [27:24] ADDOPCRA21.OFSETSEL, [19:16] ADDOPCRA21.GAINSEL, [2:0] ADDOPCRA21.DFSEL
0x87438758 ADC_B
  [n+16] ADDOPCRB21.CMPTBLE{n} (n=0..7), [11:8] ADDOPCRB21.ADC, [1:0] ADDOPCRB21.AVEMD
0x8743875C ADC_B
  [20] ADDOPCRC21.SIGNSEL, [17:16] ADDOPCRC21.ADPRC, [3:0] ADDOPCRC21.LIMTBLS
0x87438760 ADC_B
  [19:16] ADCHCR22.SSTSEL, [15] ADCHCR22.AINMD, [14:8] ADCHCR22.CNVCS, [4:0] ADCHCR22.SGSEL
0x87438764 ADC_B
  [27:24] ADDOPCRA22.OFSETSEL, [19:16] ADDOPCRA22.GAINSEL, [2:0] ADDOPCRA22.DFSEL
0x87438768 ADC_B
  [n+16] ADDOPCRB22.CMPTBLE{n} (n=0..7), [11:8] ADDOPCRB22.ADC, [1:0] ADDOPCRB22.AVEMD
0x8743876C ADC_B
  [20] ADDOPCRC22.SIGNSEL, [17:16] ADDOPCRC22.ADPRC, [3:0] ADDOPCRC22.LIMTBLS
0x87438770 ADC_B
  [19:16] ADCHCR23.SSTSEL, [15] ADCHCR23.AINMD, [14:8] ADCHCR23.CNVCS, [4:0] ADCHCR23.SGSEL
0x87438774 ADC_B
  [27:24] ADDOPCRA23.OFSETSEL, [19:16] ADDOPCRA23.GAINSEL, [2:0] ADDOPCRA23.DFSEL
0x87438778 ADC_B
  [n+16] ADDOPCRB23.CMPTBLE{n} (n=0..7), [11:8] ADDOPCRB23.ADC, [1:0] ADDOPCRB23.AVEMD
0x8743877C ADC_B
  [20] ADDOPCRC23.SIGNSEL, [17:16] ADDOPCRC23.ADPRC, [3:0] ADDOPCRC23.LIMTBLS
0x87438780 ADC_B
  [19:16] ADCHCR24.SSTSEL, [15] ADCHCR24.AINMD, [14:8] ADCHCR24.CNVCS, [4:0] ADCHCR24.SGSEL
0x87438784 ADC_B
  [27:24] ADDOPCRA24.OFSETSEL, [19:16] ADDOPCRA24.GAINSEL, [2:0] ADDOPCRA24.DFSEL
0x87438788 ADC_B
  [n+16] ADDOPCRB24.CMPTBLE{n} (n=0..7), [11:8] ADDOPCRB24.ADC, [1:0] ADDOPCRB24.AVEMD
0x8743878C ADC_B
  [20] ADDOPCRC24.SIGNSEL, [17:16] ADDOPCRC24.ADPRC, [3:0] ADDOPCRC24.LIMTBLS
0x87438790 ADC_B
  [19:16] ADCHCR25.SSTSEL, [15] ADCHCR25.AINMD, [14:8] ADCHCR25.CNVCS, [4:0] ADCHCR25.SGSEL
0x87438794 ADC_B
  [27:24] ADDOPCRA25.OFSETSEL, [19:16] ADDOPCRA25.GAINSEL, [2:0] ADDOPCRA25.DFSEL
0x87438798 ADC_B
  [n+16] ADDOPCRB25.CMPTBLE{n} (n=0..7), [11:8] ADDOPCRB25.ADC, [1:0] ADDOPCRB25.AVEMD
0x8743879C ADC_B
  [20] ADDOPCRC25.SIGNSEL, [17:16] ADDOPCRC25.ADPRC, [3:0] ADDOPCRC25.LIMTBLS
0x874387A0 ADC_B
  [19:16] ADCHCR26.SSTSEL, [15] ADCHCR26.AINMD, [14:8] ADCHCR26.CNVCS, [4:0] ADCHCR26.SGSEL
0x874387A4 ADC_B
  [27:24] ADDOPCRA26.OFSETSEL, [19:16] ADDOPCRA26.GAINSEL, [2:0] ADDOPCRA26.DFSEL
0x874387A8 ADC_B
  [n+16] ADDOPCRB26.CMPTBLE{n} (n=0..7), [11:8] ADDOPCRB26.ADC, [1:0] ADDOPCRB26.AVEMD
0x874387AC ADC_B
  [20] ADDOPCRC26.SIGNSEL, [17:16] ADDOPCRC26.ADPRC, [3:0] ADDOPCRC26.LIMTBLS
0x874387B0 ADC_B
  [19:16] ADCHCR27.SSTSEL, [15] ADCHCR27.AINMD, [14:8] ADCHCR27.CNVCS, [4:0] ADCHCR27.SGSEL
0x874387B4 ADC_B
  [27:24] ADDOPCRA27.OFSETSEL, [19:16] ADDOPCRA27.GAINSEL, [2:0] ADDOPCRA27.DFSEL
0x874387B8 ADC_B
  [n+16] ADDOPCRB27.CMPTBLE{n} (n=0..7), [11:8] ADDOPCRB27.ADC, [1:0] ADDOPCRB27.AVEMD
0x874387BC ADC_B
  [20] ADDOPCRC27.SIGNSEL, [17:16] ADDOPCRC27.ADPRC, [3:0] ADDOPCRC27.LIMTBLS
0x874387C0 ADC_B
  [19:16] ADCHCR28.SSTSEL, [15] ADCHCR28.AINMD, [14:8] ADCHCR28.CNVCS, [4:0] ADCHCR28.SGSEL
0x874387C4 ADC_B
  [27:24] ADDOPCRA28.OFSETSEL, [19:16] ADDOPCRA28.GAINSEL, [2:0] ADDOPCRA28.DFSEL
0x874387C8 ADC_B
  [n+16] ADDOPCRB28.CMPTBLE{n} (n=0..7), [11:8] ADDOPCRB28.ADC, [1:0] ADDOPCRB28.AVEMD
0x874387CC ADC_B
  [20] ADDOPCRC28.SIGNSEL, [17:16] ADDOPCRC28.ADPRC, [3:0] ADDOPCRC28.LIMTBLS
0x874387D0 ADC_B
  [19:16] ADCHCR29.SSTSEL, [15] ADCHCR29.AINMD, [14:8] ADCHCR29.CNVCS, [4:0] ADCHCR29.SGSEL
0x874387D4 ADC_B
  [27:24] ADDOPCRA29.OFSETSEL, [19:16] ADDOPCRA29.GAINSEL, [2:0] ADDOPCRA29.DFSEL
0x874387D8 ADC_B
  [n+16] ADDOPCRB29.CMPTBLE{n} (n=0..7), [11:8] ADDOPCRB29.ADC, [1:0] ADDOPCRB29.AVEMD
0x874387DC ADC_B
  [20] ADDOPCRC29.SIGNSEL, [17:16] ADDOPCRC29.ADPRC, [3:0] ADDOPCRC29.LIMTBLS
0x874387E0 ADC_B
  [19:16] ADCHCR30.SSTSEL, [15] ADCHCR30.AINMD, [14:8] ADCHCR30.CNVCS, [4:0] ADCHCR30.SGSEL
0x874387E4 ADC_B
  [27:24] ADDOPCRA30.OFSETSEL, [19:16] ADDOPCRA30.GAINSEL, [2:0] ADDOPCRA30.DFSEL
0x874387E8 ADC_B
  [n+16] ADDOPCRB30.CMPTBLE{n} (n=0..7), [11:8] ADDOPCRB30.ADC, [1:0] ADDOPCRB30.AVEMD
0x874387EC ADC_B
  [20] ADDOPCRC30.SIGNSEL, [17:16] ADDOPCRC30.ADPRC, [3:0] ADDOPCRC30.LIMTBLS
0x874387F0 ADC_B
  [19:16] ADCHCR31.SSTSEL, [15] ADCHCR31.AINMD, [14:8] ADCHCR31.CNVCS, [4:0] ADCHCR31.SGSEL
0x874387F4 ADC_B
  [27:24] ADDOPCRA31.OFSETSEL, [19:16] ADDOPCRA31.GAINSEL, [2:0] ADDOPCRA31.DFSEL
0x874387F8 ADC_B
  [n+16] ADDOPCRB31.CMPTBLE{n} (n=0..7), [11:8] ADDOPCRB31.ADC, [1:0] ADDOPCRB31.AVEMD
0x874387FC ADC_B
  [20] ADDOPCRC31.SIGNSEL, [17:16] ADDOPCRC31.ADPRC, [3:0] ADDOPCRC31.LIMTBLS
0x87438800 ADC_B
  [19:16] ADCHCR32.SSTSEL, [15] ADCHCR32.AINMD, [14:8] ADCHCR32.CNVCS, [4:0] ADCHCR32.SGSEL
0x87438804 ADC_B
  [27:24] ADDOPCRA32.OFSETSEL, [19:16] ADDOPCRA32.GAINSEL, [2:0] ADDOPCRA32.DFSEL
0x87438808 ADC_B
  [n+16] ADDOPCRB32.CMPTBLE{n} (n=0..7), [11:8] ADDOPCRB32.ADC, [1:0] ADDOPCRB32.AVEMD
0x8743880C ADC_B
  [20] ADDOPCRC32.SIGNSEL, [17:16] ADDOPCRC32.ADPRC, [3:0] ADDOPCRC32.LIMTBLS
0x87438810 ADC_B
  [19:16] ADCHCR33.SSTSEL, [15] ADCHCR33.AINMD, [14:8] ADCHCR33.CNVCS, [4:0] ADCHCR33.SGSEL
0x87438814 ADC_B
  [27:24] ADDOPCRA33.OFSETSEL, [19:16] ADDOPCRA33.GAINSEL, [2:0] ADDOPCRA33.DFSEL
0x87438818 ADC_B
  [n+16] ADDOPCRB33.CMPTBLE{n} (n=0..7), [11:8] ADDOPCRB33.ADC, [1:0] ADDOPCRB33.AVEMD
0x8743881C ADC_B
  [20] ADDOPCRC33.SIGNSEL, [17:16] ADDOPCRC33.ADPRC, [3:0] ADDOPCRC33.LIMTBLS
0x87438820 ADC_B
  [19:16] ADCHCR34.SSTSEL, [15] ADCHCR34.AINMD, [14:8] ADCHCR34.CNVCS, [4:0] ADCHCR34.SGSEL
0x87438824 ADC_B
  [27:24] ADDOPCRA34.OFSETSEL, [19:16] ADDOPCRA34.GAINSEL, [2:0] ADDOPCRA34.DFSEL
0x87438828 ADC_B
  [n+16] ADDOPCRB34.CMPTBLE{n} (n=0..7), [11:8] ADDOPCRB34.ADC, [1:0] ADDOPCRB34.AVEMD
0x8743882C ADC_B
  [20] ADDOPCRC34.SIGNSEL, [17:16] ADDOPCRC34.ADPRC, [3:0] ADDOPCRC34.LIMTBLS
0x87438830 ADC_B
  [19:16] ADCHCR35.SSTSEL, [15] ADCHCR35.AINMD, [14:8] ADCHCR35.CNVCS, [4:0] ADCHCR35.SGSEL
0x87438834 ADC_B
  [27:24] ADDOPCRA35.OFSETSEL, [19:16] ADDOPCRA35.GAINSEL, [2:0] ADDOPCRA35.DFSEL
0x87438838 ADC_B
  [n+16] ADDOPCRB35.CMPTBLE{n} (n=0..7), [11:8] ADDOPCRB35.ADC, [1:0] ADDOPCRB35.AVEMD
0x8743883C ADC_B
  [20] ADDOPCRC35.SIGNSEL, [17:16] ADDOPCRC35.ADPRC, [3:0] ADDOPCRC35.LIMTBLS
0x87438840 ADC_B
  [19:16] ADCHCR36.SSTSEL, [15] ADCHCR36.AINMD, [14:8] ADCHCR36.CNVCS, [4:0] ADCHCR36.SGSEL
0x87438844 ADC_B
  [27:24] ADDOPCRA36.OFSETSEL, [19:16] ADDOPCRA36.GAINSEL, [2:0] ADDOPCRA36.DFSEL
0x87438848 ADC_B
  [n+16] ADDOPCRB36.CMPTBLE{n} (n=0..7), [11:8] ADDOPCRB36.ADC, [1:0] ADDOPCRB36.AVEMD
0x8743884C ADC_B
  [20] ADDOPCRC36.SIGNSEL, [17:16] ADDOPCRC36.ADPRC, [3:0] ADDOPCRC36.LIMTBLS
0x87438850 ADC_B
  [19:16] ADCHCR37.SSTSEL, [15] ADCHCR37.AINMD, [14:8] ADCHCR37.CNVCS, [4:0] ADCHCR37.SGSEL
0x87438854 ADC_B
  [27:24] ADDOPCRA37.OFSETSEL, [19:16] ADDOPCRA37.GAINSEL, [2:0] ADDOPCRA37.DFSEL
0x87438858 ADC_B
  [n+16] ADDOPCRB37.CMPTBLE{n} (n=0..7), [11:8] ADDOPCRB37.ADC, [1:0] ADDOPCRB37.AVEMD
0x8743885C ADC_B
  [20] ADDOPCRC37.SIGNSEL, [17:16] ADDOPCRC37.ADPRC, [3:0] ADDOPCRC37.LIMTBLS
0x87438860 ADC_B
  [19:16] ADCHCR38.SSTSEL, [15] ADCHCR38.AINMD, [14:8] ADCHCR38.CNVCS, [4:0] ADCHCR38.SGSEL
0x87438864 ADC_B
  [27:24] ADDOPCRA38.OFSETSEL, [19:16] ADDOPCRA38.GAINSEL, [2:0] ADDOPCRA38.DFSEL
0x87438868 ADC_B
  [n+16] ADDOPCRB38.CMPTBLE{n} (n=0..7), [11:8] ADDOPCRB38.ADC, [1:0] ADDOPCRB38.AVEMD
0x8743886C ADC_B
  [20] ADDOPCRC38.SIGNSEL, [17:16] ADDOPCRC38.ADPRC, [3:0] ADDOPCRC38.LIMTBLS
0x87438870 ADC_B
  [19:16] ADCHCR39.SSTSEL, [15] ADCHCR39.AINMD, [14:8] ADCHCR39.CNVCS, [4:0] ADCHCR39.SGSEL
0x87438874 ADC_B
  [27:24] ADDOPCRA39.OFSETSEL, [19:16] ADDOPCRA39.GAINSEL, [2:0] ADDOPCRA39.DFSEL
0x87438878 ADC_B
  [n+16] ADDOPCRB39.CMPTBLE{n} (n=0..7), [11:8] ADDOPCRB39.ADC, [1:0] ADDOPCRB39.AVEMD
0x8743887C ADC_B
  [20] ADDOPCRC39.SIGNSEL, [17:16] ADDOPCRC39.ADPRC, [3:0] ADDOPCRC39.LIMTBLS
0x87438880 ADC_B
  [19:16] ADCHCR40.SSTSEL, [15] ADCHCR40.AINMD, [14:8] ADCHCR40.CNVCS, [4:0] ADCHCR40.SGSEL
0x87438884 ADC_B
  [27:24] ADDOPCRA40.OFSETSEL, [19:16] ADDOPCRA40.GAINSEL, [2:0] ADDOPCRA40.DFSEL
0x87438888 ADC_B
  [n+16] ADDOPCRB40.CMPTBLE{n} (n=0..7), [11:8] ADDOPCRB40.ADC, [1:0] ADDOPCRB40.AVEMD
0x8743888C ADC_B
  [20] ADDOPCRC40.SIGNSEL, [17:16] ADDOPCRC40.ADPRC, [3:0] ADDOPCRC40.LIMTBLS
0x87438890 ADC_B
  [19:16] ADCHCR41.SSTSEL, [15] ADCHCR41.AINMD, [14:8] ADCHCR41.CNVCS, [4:0] ADCHCR41.SGSEL
0x87438894 ADC_B
  [27:24] ADDOPCRA41.OFSETSEL, [19:16] ADDOPCRA41.GAINSEL, [2:0] ADDOPCRA41.DFSEL
0x87438898 ADC_B
  [n+16] ADDOPCRB41.CMPTBLE{n} (n=0..7), [11:8] ADDOPCRB41.ADC, [1:0] ADDOPCRB41.AVEMD
0x8743889C ADC_B
  [20] ADDOPCRC41.SIGNSEL, [17:16] ADDOPCRC41.ADPRC, [3:0] ADDOPCRC41.LIMTBLS
0x874388A0 ADC_B
  [19:16] ADCHCR42.SSTSEL, [15] ADCHCR42.AINMD, [14:8] ADCHCR42.CNVCS, [4:0] ADCHCR42.SGSEL
0x874388A4 ADC_B
  [27:24] ADDOPCRA42.OFSETSEL, [19:16] ADDOPCRA42.GAINSEL, [2:0] ADDOPCRA42.DFSEL
0x874388A8 ADC_B
  [n+16] ADDOPCRB42.CMPTBLE{n} (n=0..7), [11:8] ADDOPCRB42.ADC, [1:0] ADDOPCRB42.AVEMD
0x874388AC ADC_B
  [20] ADDOPCRC42.SIGNSEL, [17:16] ADDOPCRC42.ADPRC, [3:0] ADDOPCRC42.LIMTBLS
0x874388B0 ADC_B
  [19:16] ADCHCR43.SSTSEL, [15] ADCHCR43.AINMD, [14:8] ADCHCR43.CNVCS, [4:0] ADCHCR43.SGSEL
0x874388B4 ADC_B
  [27:24] ADDOPCRA43.OFSETSEL, [19:16] ADDOPCRA43.GAINSEL, [2:0] ADDOPCRA43.DFSEL
0x874388B8 ADC_B
  [n+16] ADDOPCRB43.CMPTBLE{n} (n=0..7), [11:8] ADDOPCRB43.ADC, [1:0] ADDOPCRB43.AVEMD
0x874388BC ADC_B
  [20] ADDOPCRC43.SIGNSEL, [17:16] ADDOPCRC43.ADPRC, [3:0] ADDOPCRC43.LIMTBLS
0x874388C0 ADC_B
  [19:16] ADCHCR44.SSTSEL, [15] ADCHCR44.AINMD, [14:8] ADCHCR44.CNVCS, [4:0] ADCHCR44.SGSEL
0x874388C4 ADC_B
  [27:24] ADDOPCRA44.OFSETSEL, [19:16] ADDOPCRA44.GAINSEL, [2:0] ADDOPCRA44.DFSEL
0x874388C8 ADC_B
  [n+16] ADDOPCRB44.CMPTBLE{n} (n=0..7), [11:8] ADDOPCRB44.ADC, [1:0] ADDOPCRB44.AVEMD
0x874388CC ADC_B
  [20] ADDOPCRC44.SIGNSEL, [17:16] ADDOPCRC44.ADPRC, [3:0] ADDOPCRC44.LIMTBLS
0x874388D0 ADC_B
  [19:16] ADCHCR45.SSTSEL, [15] ADCHCR45.AINMD, [14:8] ADCHCR45.CNVCS, [4:0] ADCHCR45.SGSEL
0x874388D4 ADC_B
  [27:24] ADDOPCRA45.OFSETSEL, [19:16] ADDOPCRA45.GAINSEL, [2:0] ADDOPCRA45.DFSEL
0x874388D8 ADC_B
  [n+16] ADDOPCRB45.CMPTBLE{n} (n=0..7), [11:8] ADDOPCRB45.ADC, [1:0] ADDOPCRB45.AVEMD
0x874388DC ADC_B
  [20] ADDOPCRC45.SIGNSEL, [17:16] ADDOPCRC45.ADPRC, [3:0] ADDOPCRC45.LIMTBLS
0x874388E0 ADC_B
  [19:16] ADCHCR46.SSTSEL, [15] ADCHCR46.AINMD, [14:8] ADCHCR46.CNVCS, [4:0] ADCHCR46.SGSEL
0x874388E4 ADC_B
  [27:24] ADDOPCRA46.OFSETSEL, [19:16] ADDOPCRA46.GAINSEL, [2:0] ADDOPCRA46.DFSEL
0x874388E8 ADC_B
  [n+16] ADDOPCRB46.CMPTBLE{n} (n=0..7), [11:8] ADDOPCRB46.ADC, [1:0] ADDOPCRB46.AVEMD
0x874388EC ADC_B
  [20] ADDOPCRC46.SIGNSEL, [17:16] ADDOPCRC46.ADPRC, [3:0] ADDOPCRC46.LIMTBLS
0x874388F0 ADC_B
  [19:16] ADCHCR47.SSTSEL, [15] ADCHCR47.AINMD, [14:8] ADCHCR47.CNVCS, [4:0] ADCHCR47.SGSEL
0x874388F4 ADC_B
  [27:24] ADDOPCRA47.OFSETSEL, [19:16] ADDOPCRA47.GAINSEL, [2:0] ADDOPCRA47.DFSEL
0x874388F8 ADC_B
  [n+16] ADDOPCRB47.CMPTBLE{n} (n=0..7), [11:8] ADDOPCRB47.ADC, [1:0] ADDOPCRB47.AVEMD
0x874388FC ADC_B
  [20] ADDOPCRC47.SIGNSEL, [17:16] ADDOPCRC47.ADPRC, [3:0] ADDOPCRC47.LIMTBLS
0x87438900 ADC_B
  [19:16] ADCHCR48.SSTSEL, [15] ADCHCR48.AINMD, [14:8] ADCHCR48.CNVCS, [4:0] ADCHCR48.SGSEL
0x87438904 ADC_B
  [27:24] ADDOPCRA48.OFSETSEL, [19:16] ADDOPCRA48.GAINSEL, [2:0] ADDOPCRA48.DFSEL
0x87438908 ADC_B
  [n+16] ADDOPCRB48.CMPTBLE{n} (n=0..7), [11:8] ADDOPCRB48.ADC, [1:0] ADDOPCRB48.AVEMD
0x8743890C ADC_B
  [20] ADDOPCRC48.SIGNSEL, [17:16] ADDOPCRC48.ADPRC, [3:0] ADDOPCRC48.LIMTBLS
0x87438910 ADC_B
  [19:16] ADCHCR49.SSTSEL, [15] ADCHCR49.AINMD, [14:8] ADCHCR49.CNVCS, [4:0] ADCHCR49.SGSEL
0x87438914 ADC_B
  [27:24] ADDOPCRA49.OFSETSEL, [19:16] ADDOPCRA49.GAINSEL, [2:0] ADDOPCRA49.DFSEL
0x87438918 ADC_B
  [n+16] ADDOPCRB49.CMPTBLE{n} (n=0..7), [11:8] ADDOPCRB49.ADC, [1:0] ADDOPCRB49.AVEMD
0x8743891C ADC_B
  [20] ADDOPCRC49.SIGNSEL, [17:16] ADDOPCRC49.ADPRC, [3:0] ADDOPCRC49.LIMTBLS
0x87438C00 ADC_B
  [18:16] ADCALSTR.ADCALST2, [10:8] ADCALSTR.ADCALST1, [2:0] ADCALSTR.ADCALST0
0x87438C04 ADC_B
  [16:9] ADSHCSCR.SHCSST2, [8] ADSHCSCR.SHCSST1, [0] ADSHCSCR.SHCSST0
0x87438C08 ADC_B
  [n] ADTRGENR.STTRGEN{n} (n=0..11)
0x87438C10 ADC_B
  [n] ADSYSTR.ADSYST{n} (n=0..11)
0x87438C20 ADC_B
  [0] ADSTR[0].ADST
0x87438C24 ADC_B
  [0] ADSTR[1].ADST
0x87438C28 ADC_B
  [0] ADSTR[2].ADST
0x87438C2C ADC_B
  [0] ADSTR[3].ADST
0x87438C30 ADC_B
  [0] ADSTR[4].ADST
0x87438C34 ADC_B
  [0] ADSTR[5].ADST
0x87438C38 ADC_B
  [0] ADSTR[6].ADST
0x87438C3C ADC_B
  [0] ADSTR[7].ADST
0x87438C40 ADC_B
  [0] ADSTR[8].ADST
0x87438C44 ADC_B
  [0] ADSTR[9].ADST
0x87438C48 ADC_B
  [0] ADSTR[10].ADST
0x87438C4C ADC_B
  [0] ADSTR[11].ADST
0x87438C60 ADC_B
  [16] ADSTOPR.ADSTOP2, [8] ADSTOPR.ADSTOP1, [0] ADSTOPR.ADSTOP0
0x87438C80 ADC_B
  [18] ADSR.CALACT2, [17] ADSR.CALACT1, [16] ADSR.CALACT0, [2] ADSR.ADACT2, [1] ADSR.ADACT1, [0] ADSR.ADACT0
0x87438C84 ADC_B
  [n] ADGRSR.ACTGR{n} (n=0..11)
0x87438C88 ADC_B
  [2] ADERSR.ADERF2, [1] ADERSR.ADERF1, [0] ADERSR.ADERF0
0x87438C8C ADC_B
  [2] ADERSCR.ADERCLR2, [1] ADERSCR.ADERCLR1, [0] ADERSCR.ADERCLR0
0x87438C98 ADC_B
  [2] ADCALENDSR.CALENDF2, [1] ADCALENDSR.CALENDF1, [0] ADCALENDSR.CALENDF0
0x87438C9C ADC_B
  [2] ADCALENDSCR.CALENDC2, [1] ADCALENDSCR.CALENDC1, [0] ADCALENDSCR.CALENDC0
0x87438CA0 ADC_B
  [2] ADOVFERSR.ADOVFEF2, [1] ADOVFERSR.ADOVFEF1, [0] ADOVFERSR.ADOVFEF0
0x87438CA4 ADC_B
  [n] ADOVFCHSR0.OVFCHF{n} (n=0..31)
0x87438CA8 ADC_B
  [n-32] ADOVFCHSR1.OVFCHF{n} (n=32..35)
0x87438CB0 ADC_B
  [18] ADOVFEXSR.OVFEXF18, [17] ADOVFEXSR.OVFEXF17, [16] ADOVFEXSR.OVFEXF16, [9] ADOVFEXSR.OVFEXF9, [8] ADOVFEXSR.OVFEXF8, [6] ADOVFEXSR.OVFEXF6, [5] ADOVFEXSR.OVFEXF5, [4] ADOVFEXSR.OVFEXF4, [2] ADOVFEXSR.OVFEXF2, [1] ADOVFEXSR.OVFEXF1, [0] ADOVFEXSR.OVFEXF0
0x87438CB4 ADC_B
  [2] ADOVFERSCR.ADOVFEC2, [1] ADOVFERSCR.ADOVFEC1, [0] ADOVFERSCR.ADOVFEC0
0x87438CB8 ADC_B
  [n] ADOVFCHSCR0.OVFCHC{n} (n=0..31)
0x87438CBC ADC_B
  [n-32] ADOVFCHSCR1.OVFCHC{n} (n=32..35)
0x87438CC4 ADC_B
  [18] ADOVFEXSCR.OVFEXC18, [17] ADOVFEXSCR.OVFEXC17, [16] ADOVFEXSCR.OVFEXC16, [9] ADOVFEXSCR.OVFEXC9, [8] ADOVFEXSCR.OVFEXC8, [6] ADOVFEXSCR.OVFEXC6, [5] ADOVFEXSCR.OVFEXC5, [4] ADOVFEXSCR.OVFEXC4, [2] ADOVFEXSCR.OVFEXC2, [1] ADOVFEXSCR.OVFEXC1, [0] ADOVFEXSCR.OVFEXC0
0x87438CD0 ADC_B
  [20:16] ADFIFOSR0.FIFOST1, [4:0] ADFIFOSR0.FIFOST0
0x87438CD4 ADC_B
  [20:16] ADFIFOSR1.FIFOST3, [4:0] ADFIFOSR1.FIFOST2
0x87438CD8 ADC_B
  [20:16] ADFIFOSR2.FIFOST5, [4:0] ADFIFOSR2.FIFOST4
0x87438CDC ADC_B
  [20:16] ADFIFOSR3.FIFOST7, [4:0] ADFIFOSR3.FIFOST6
0x87438CE0 ADC_B
  [20:16] ADFIFOSR4.FIFOST9, [4:0] ADFIFOSR4.FIFOST8
0x87438CE4 ADC_B
  [20:16] ADFIFOSR5.FIFOST11, [4:0] ADFIFOSR5.FIFOST10
0x87438CF0 ADC_B
  [n] ADFIFODCR.FIFODC{n} (n=0..11)
0x87438CF4 ADC_B
  [n+16] ADFIFOERSR.FIFOFLF{n} (n=0..11), [n] ADFIFOERSR.FIFOOVF{n} (n=0..11)
0x87438CF8 ADC_B
  [n+16] ADFIFOERSCR.FIFOFLC{n} (n=0..11), [n] ADFIFOERSCR.FIFOOVFC{n} (n=0..11)
0x87438D00 ADC_B
  [n] ADCMPTBSR.CMPTBF{n} (n=0..7)
0x87438D04 ADC_B
  [n] ADCMPTBSCR.CMPTBC{n} (n=0..7)
0x87438D08 ADC_B
  [n] ADCMPCHSR0.CMPCHF{n} (n=0..31)
0x87438D0C ADC_B
  [n-32] ADCMPCHSR1.CMPCHF{n} (n=32..35)
0x87438D14 ADC_B
  [18] ADCMPEXSR.CMPEXF18, [17] ADCMPEXSR.CMPEXF17, [16] ADCMPEXSR.CMPEXF16, [9] ADCMPEXSR.CMPEXF9, [8] ADCMPEXSR.CMPEXF8, [6] ADCMPEXSR.CMPEXF6, [5] ADCMPEXSR.CMPEXF5, [4] ADCMPEXSR.CMPEXF4, [2] ADCMPEXSR.CMPEXF2, [1] ADCMPEXSR.CMPEXF1, [0] ADCMPEXSR.CMPEXF0
0x87438D18 ADC_B
  [n] ADCMPCHSCR0.CMPCHC{n} (n=0..31)
0x87438D1C ADC_B
  [n-32] ADCMPCHSCR1.CMPCHC{n} (n=32..35)
0x87438D24 ADC_B
  [18] ADCMPEXSCR.CMPEXC18, [17] ADCMPEXSCR.CMPEXC17, [16] ADCMPEXSCR.CMPEXC16, [9] ADCMPEXSCR.CMPEXC9, [8] ADCMPEXSCR.CMPEXC8, [6] ADCMPEXSCR.CMPEXC6, [5] ADCMPEXSCR.CMPEXC5, [4] ADCMPEXSCR.CMPEXC4, [2] ADCMPEXSCR.CMPEXC2, [1] ADCMPEXSCR.CMPEXC1, [0] ADCMPEXSCR.CMPEXC0
0x87438D28 ADC_B
  [n] ADLIMGRSR.LIMGRF{n} (n=0..11)
0x87438D2C ADC_B
  [n] ADLIMCHSR0.LIMCHF{n} (n=0..31)
0x87438D30 ADC_B
  [n-32] ADLIMCHSR1.LIMCHF{n} (n=32..35)
0x87438D38 ADC_B
  [18] ADLIMEXSR.LIMEXF18, [17] ADLIMEXSR.LIMEXF17, [16] ADLIMEXSR.LIMEXF16, [9] ADLIMEXSR.LIMEXF9, [8] ADLIMEXSR.LIMEXF8, [6] ADLIMEXSR.LIMEXF6, [5] ADLIMEXSR.LIMEXF5, [4] ADLIMEXSR.LIMEXF4, [2] ADLIMEXSR.LIMEXF2, [1] ADLIMEXSR.LIMEXF1, [0] ADLIMEXSR.LIMEXF0
0x87438D3C ADC_B
  [n] ADLIMGRSCR.LIMGRC{n} (n=0..11)
0x87438D40 ADC_B
  [n] ADLIMCHSCR0.LIMCHC{n} (n=0..31)
0x87438D44 ADC_B
  [n-32] ADLIMCHSCR1.LIMCHC{n} (n=32..35)
0x87438D4C ADC_B
  [18] ADLIMEXSCR.LIMEXC18, [17] ADLIMEXSCR.LIMEXC17, [16] ADLIMEXSCR.LIMEXC16, [9] ADLIMEXSCR.LIMEXC9, [8] ADLIMEXSCR.LIMEXC8, [6] ADLIMEXSCR.LIMEXC6, [5] ADLIMEXSCR.LIMEXC5, [4] ADLIMEXSCR.LIMEXC4, [2] ADLIMEXSCR.LIMEXC2, [1] ADLIMEXSCR.LIMEXC1, [0] ADLIMEXSCR.LIMEXC0
0x87438D50 ADC_B
  [n] ADSCANENDSR.SCENDF{n} (n=0..11)
0x87438D54 ADC_B
  [n] ADSCANENDSCR.SCENDC{n} (n=0..11)
0x8743A000 ADC_B
  [31] ADDR[0].ERR, [15:0] ADDR[0].DATA
0x8743A004 ADC_B
  [31] ADDR[1].ERR, [15:0] ADDR[1].DATA
0x8743A008 ADC_B
  [31] ADDR[2].ERR, [15:0] ADDR[2].DATA
0x8743A00C ADC_B
  [31] ADDR[3].ERR, [15:0] ADDR[3].DATA
0x8743A010 ADC_B
  [31] ADDR[4].ERR, [15:0] ADDR[4].DATA
0x8743A014 ADC_B
  [31] ADDR[5].ERR, [15:0] ADDR[5].DATA
0x8743A018 ADC_B
  [31] ADDR[6].ERR, [15:0] ADDR[6].DATA
0x8743A01C ADC_B
  [31] ADDR[7].ERR, [15:0] ADDR[7].DATA
0x8743A020 ADC_B
  [31] ADDR[8].ERR, [15:0] ADDR[8].DATA
0x8743A024 ADC_B
  [31] ADDR[9].ERR, [15:0] ADDR[9].DATA
0x8743A028 ADC_B
  [31] ADDR[10].ERR, [15:0] ADDR[10].DATA
0x8743A02C ADC_B
  [31] ADDR[11].ERR, [15:0] ADDR[11].DATA
0x8743A030 ADC_B
  [31] ADDR[12].ERR, [15:0] ADDR[12].DATA
0x8743A034 ADC_B
  [31] ADDR[13].ERR, [15:0] ADDR[13].DATA
0x8743A038 ADC_B
  [31] ADDR[14].ERR, [15:0] ADDR[14].DATA
0x8743A03C ADC_B
  [31] ADDR[15].ERR, [15:0] ADDR[15].DATA
0x8743A040 ADC_B
  [31] ADDR[16].ERR, [15:0] ADDR[16].DATA
0x8743A044 ADC_B
  [31] ADDR[17].ERR, [15:0] ADDR[17].DATA
0x8743A048 ADC_B
  [31] ADDR[18].ERR, [15:0] ADDR[18].DATA
0x8743A04C ADC_B
  [31] ADDR[19].ERR, [15:0] ADDR[19].DATA
0x8743A050 ADC_B
  [31] ADDR[20].ERR, [15:0] ADDR[20].DATA
0x8743A054 ADC_B
  [31] ADDR[21].ERR, [15:0] ADDR[21].DATA
0x8743A058 ADC_B
  [31] ADDR[22].ERR, [15:0] ADDR[22].DATA
0x8743A05C ADC_B
  [31] ADDR[23].ERR, [15:0] ADDR[23].DATA
0x8743A060 ADC_B
  [31] ADDR[24].ERR, [15:0] ADDR[24].DATA
0x8743A064 ADC_B
  [31] ADDR[25].ERR, [15:0] ADDR[25].DATA
0x8743A068 ADC_B
  [31] ADDR[26].ERR, [15:0] ADDR[26].DATA
0x8743A06C ADC_B
  [31] ADDR[27].ERR, [15:0] ADDR[27].DATA
0x8743A070 ADC_B
  [31] ADDR[28].ERR, [15:0] ADDR[28].DATA
0x8743A074 ADC_B
  [31] ADDR[29].ERR, [15:0] ADDR[29].DATA
0x8743A078 ADC_B
  [31] ADDR[30].ERR, [15:0] ADDR[30].DATA
0x8743A07C ADC_B
  [31] ADDR[31].ERR, [15:0] ADDR[31].DATA
0x8743A080 ADC_B
  [31] ADDR[32].ERR, [15:0] ADDR[32].DATA
0x8743A084 ADC_B
  [31] ADDR[33].ERR, [15:0] ADDR[33].DATA
0x8743A088 ADC_B
  [31] ADDR[34].ERR, [15:0] ADDR[34].DATA
0x8743A08C ADC_B
  [31] ADDR[35].ERR, [15:0] ADDR[35].DATA
0x8743A180 ADC_B
  [31] ADEXDR0.ERR, [26:24] ADEXDR0.DIAGSR, [15:0] ADEXDR0.DATA
0x8743A184 ADC_B
  [31] ADEXDR1.ERR, [26:24] ADEXDR1.DIAGSR, [15:0] ADEXDR1.DATA
0x8743A188 ADC_B
  [31] ADEXDR2.ERR, [26:24] ADEXDR2.DIAGSR, [15:0] ADEXDR2.DATA
0x8743A190 ADC_B
  [31] ADEXDR4.ERR, [26:24] ADEXDR4.DIAGSR, [15:0] ADEXDR4.DATA
0x8743A194 ADC_B
  [31] ADEXDR5.ERR, [26:24] ADEXDR5.DIAGSR, [15:0] ADEXDR5.DATA
0x8743A198 ADC_B
  [31] ADEXDR6.ERR, [26:24] ADEXDR6.DIAGSR, [15:0] ADEXDR6.DATA
0x8743A1A0 ADC_B
  [31] ADEXDR8.ERR, [26:24] ADEXDR8.DIAGSR, [15:0] ADEXDR8.DATA
0x8743A1A4 ADC_B
  [31] ADEXDR9.ERR, [26:24] ADEXDR9.DIAGSR, [15:0] ADEXDR9.DATA
0x8743A1C0 ADC_B
  [31] ADEXDR16.ERR, [26:24] ADEXDR16.DIAGSR, [15:0] ADEXDR16.DATA
0x8743A1C4 ADC_B
  [31] ADEXDR17.ERR, [26:24] ADEXDR17.DIAGSR, [15:0] ADEXDR17.DATA
0x8743A1C8 ADC_B
  [31] ADEXDR18.ERR, [26:24] ADEXDR18.DIAGSR, [15:0] ADEXDR18.DATA
0x8743A200 ADC_B
  [31] ADFIFODR[0].ERR, [30:24] ADFIFODR[0].CH, [15:0] ADFIFODR[0].DATA
0x8743A204 ADC_B
  [31] ADFIFODR[1].ERR, [30:24] ADFIFODR[1].CH, [15:0] ADFIFODR[1].DATA
0x8743A208 ADC_B
  [31] ADFIFODR[2].ERR, [30:24] ADFIFODR[2].CH, [15:0] ADFIFODR[2].DATA
0x8743A20C ADC_B
  [31] ADFIFODR[3].ERR, [30:24] ADFIFODR[3].CH, [15:0] ADFIFODR[3].DATA
0x8743A210 ADC_B
  [31] ADFIFODR[4].ERR, [30:24] ADFIFODR[4].CH, [15:0] ADFIFODR[4].DATA
0x8743A214 ADC_B
  [31] ADFIFODR[5].ERR, [30:24] ADFIFODR[5].CH, [15:0] ADFIFODR[5].DATA
0x8743A218 ADC_B
  [31] ADFIFODR[6].ERR, [30:24] ADFIFODR[6].CH, [15:0] ADFIFODR[6].DATA
0x8743A21C ADC_B
  [31] ADFIFODR[7].ERR, [30:24] ADFIFODR[7].CH, [15:0] ADFIFODR[7].DATA
0x8743A220 ADC_B
  [31] ADFIFODR[8].ERR, [30:24] ADFIFODR[8].CH, [15:0] ADFIFODR[8].DATA
0x8743A224 ADC_B
  [31] ADFIFODR[9].ERR, [30:24] ADFIFODR[9].CH, [15:0] ADFIFODR[9].DATA
0x8743A228 ADC_B
  [31] ADFIFODR[10].ERR, [30:24] ADFIFODR[10].CH, [15:0] ADFIFODR[10].DATA
0x8743A22C ADC_B
  [31] ADFIFODR[11].ERR, [30:24] ADFIFODR[11].CH, [15:0] ADFIFODR[11].DATA

## OFSM
0x6C12C38 OFSM_NS
  [31:0] PNR[0].PNR
0x6C12C3C OFSM_NS
  [31:0] PNR[1].PNR
0x6C12C40 OFSM_NS
  [31:0] PNR[2].PNR
0x6C12C44 OFSM_NS
  [31:0] PNR[3].PNR
0x6C12C48 OFSM_NS 8-bit
  [7:0] MCUVER.MCUVE
0x6C2EC60 OFSM_NS
  [2:0] BANKSEL.BANKSWP
0x6C2EC70 OFSM_NS
  [0] BLSEL.BLSWAREA
0x6E20850 OFSM_NS
  [31] OFS1.RODIS, [30:28] OFS1.ROWSEL, [11:9] OFS1.HOCOFRQ0, [8] OFS1.HOCOEN, [5] OFS1.PVDLPSEL, [3] OFS1.PVDAS, [2:0] OFS1.VDSEL
0x6F01000 OFSM_NS
  [31:0] UIDR[0].UID
0x6F01004 OFSM_NS
  [31:0] UIDR[1].UID
0x6F01008 OFSM_NS
  [31:0] UIDR[2].UID
0x6F0100C OFSM_NS
  [31:0] UIDR[3].UID
# iorx74m register map
Registers are 32-bit, access not given, no defined reset value unless marked. A register's access mark holds for its fields unless they carry their own. Addresses are absolute; registers are grouped by the start of their names; [hi:lo] are bit positions; {n}, {i} and the like mark numbered series.

## SFR (part 2 of 10)
0x87006381 ICU 8-bit
  [4:0] IPR[129](PERIAB,INTAB129).IPR
0x87006382 ICU 8-bit
  [4:0] IPR[130](PERIAB,INTAB130).IPR
0x87006383 ICU 8-bit
  [4:0] IPR[131](PERIAB,INTAB131).IPR
0x87006384 ICU 8-bit
  [4:0] IPR[132](PERIAB,INTAB132).IPR
0x87006385 ICU 8-bit
  [4:0] IPR[133](PERIAB,INTAB133).IPR
0x87006386 ICU 8-bit
  [4:0] IPR[134](PERIAB,INTAB134).IPR
0x87006387 ICU 8-bit
  [4:0] IPR[135](PERIAB,INTAB135).IPR
0x87006388 ICU 8-bit
  [4:0] IPR[136](PERIAB,INTAB136).IPR
0x87006389 ICU 8-bit
  [4:0] IPR[137](PERIAB,INTAB137).IPR
0x8700638A ICU 8-bit
  [4:0] IPR[138](PERIAB,INTAB138).IPR
0x8700638B ICU 8-bit
  [4:0] IPR[139](PERIAB,INTAB139).IPR
0x8700638C ICU 8-bit
  [4:0] IPR[140](PERIAB,INTAB140).IPR
0x8700638D ICU 8-bit
  [4:0] IPR[141](PERIAB,INTAB141).IPR
0x8700638E ICU 8-bit
  [4:0] IPR[142](PERIAB,INTAB142).IPR
0x8700638F ICU 8-bit
  [4:0] IPR[143](PERIAB,INTAB143).IPR
0x87006390 ICU 8-bit
  [4:0] IPR[144](PERIAB,INTAB144).IPR
0x87006391 ICU 8-bit
  [4:0] IPR[145](PERIAB,INTAB145).IPR
0x87006392 ICU 8-bit
  [4:0] IPR[146](PERIAB,INTAB146).IPR
0x87006393 ICU 8-bit
  [4:0] IPR[147](PERIAB,INTAB147).IPR
0x87006394 ICU 8-bit
  [4:0] IPR[148](PERIAB,INTAB148).IPR
0x87006395 ICU 8-bit
  [4:0] IPR[149](PERIAB,INTAB149).IPR
0x87006396 ICU 8-bit
  [4:0] IPR[150](PERIAB,INTAB150).IPR
0x87006397 ICU 8-bit
  [4:0] IPR[151](PERIAB,INTAB151).IPR
0x87006398 ICU 8-bit
  [4:0] IPR[152](PERIAB,INTAB152).IPR
0x87006399 ICU 8-bit
  [4:0] IPR[153](PERIAB,INTAB153).IPR
0x8700639A ICU 8-bit
  [4:0] IPR[154](PERIAB,INTAB154).IPR
0x8700639B ICU 8-bit
  [4:0] IPR[155](PERIAB,INTAB155).IPR
0x8700639C ICU 8-bit
  [4:0] IPR[156](PERIAB,INTAB156).IPR
0x8700639D ICU 8-bit
  [4:0] IPR[157](PERIAB,INTAB157).IPR
0x8700639E ICU 8-bit
  [4:0] IPR[158](PERIAB,INTAB158).IPR
0x8700639F ICU 8-bit
  [4:0] IPR[159](PERIAB,INTAB159).IPR
0x870063A0 ICU 8-bit
  [4:0] IPR[160](PERIAB,INTAB160).IPR
0x870063A1 ICU 8-bit
  [4:0] IPR[161](PERIAB,INTAB161).IPR
0x870063A2 ICU 8-bit
  [4:0] IPR[162](PERIAB,INTAB162).IPR
0x870063A3 ICU 8-bit
  [4:0] IPR[163](PERIAB,INTAB163).IPR
0x870063A4 ICU 8-bit
  [4:0] IPR[164](PERIAB,INTAB164).IPR
0x870063A5 ICU 8-bit
  [4:0] IPR[165](PERIAB,INTAB165).IPR
0x870063A6 ICU 8-bit
  [4:0] IPR[166](PERIAB,INTAB166).IPR
0x870063A7 ICU 8-bit
  [4:0] IPR[167](PERIAB,INTAB167).IPR
0x870063A8 ICU 8-bit
  [4:0] IPR[168](PERIAB,INTAB168).IPR
0x870063A9 ICU 8-bit
  [4:0] IPR[169](PERIAB,INTAB169).IPR
0x870063AA ICU 8-bit
  [4:0] IPR[170](PERIAB,INTAB170).IPR
0x870063AB ICU 8-bit
  [4:0] IPR[171](PERIAB,INTAB171).IPR
0x870063AC ICU 8-bit
  [4:0] IPR[172](PERIAB,INTAB172).IPR
0x870063AD ICU 8-bit
  [4:0] IPR[173](PERIAB,INTAB173).IPR
0x870063AE ICU 8-bit
  [4:0] IPR[174](PERIAB,INTAB174).IPR
0x870063AF ICU 8-bit
  [4:0] IPR[175](PERIAB,INTAB175).IPR
0x870063B0 ICU 8-bit
  [4:0] IPR[176](PERIAB,INTAB176).IPR
0x870063B1 ICU 8-bit
  [4:0] IPR[177](PERIAB,INTAB177).IPR
0x870063B2 ICU 8-bit
  [4:0] IPR[178](PERIAB,INTAB178).IPR
0x870063B3 ICU 8-bit
  [4:0] IPR[179](PERIAB,INTAB179).IPR
0x870063B4 ICU 8-bit
  [4:0] IPR[180](PERIAB,INTAB180).IPR
0x870063B5 ICU 8-bit
  [4:0] IPR[181](PERIAB,INTAB181).IPR
0x870063B6 ICU 8-bit
  [4:0] IPR[182](PERIAB,INTAB182).IPR
0x870063B7 ICU 8-bit
  [4:0] IPR[183](PERIAB,INTAB183).IPR
0x870063B8 ICU 8-bit
  [4:0] IPR[184](PERIAB,INTAB184).IPR
0x870063B9 ICU 8-bit
  [4:0] IPR[185](PERIAB,INTAB185).IPR
0x870063BA ICU 8-bit
  [4:0] IPR[186](PERIAB,INTAB186).IPR
0x870063BB ICU 8-bit
  [4:0] IPR[187](PERIAB,INTAB187).IPR
0x870063BC ICU 8-bit
  [4:0] IPR[188](PERIAB,INTAB188).IPR
0x870063BD ICU 8-bit
  [4:0] IPR[189](PERIAB,INTAB189).IPR
0x870063BE ICU 8-bit
  [4:0] IPR[190](PERIAB,INTAB190).IPR
0x870063BF ICU 8-bit
  [4:0] IPR[191](PERIAB,INTAB191).IPR
0x870063C0 ICU 8-bit
  [4:0] IPR[192](PERIAB,INTAB192).IPR
0x870063C1 ICU 8-bit
  [4:0] IPR[193](PERIAB,INTAB193).IPR
0x870063C2 ICU 8-bit
  [4:0] IPR[194](PERIAB,INTAB194).IPR
0x870063C3 ICU 8-bit
  [4:0] IPR[195](PERIAB,INTAB195).IPR
0x870063C4 ICU 8-bit
  [4:0] IPR[196](PERIAB,INTAB196).IPR
0x870063C5 ICU 8-bit
  [4:0] IPR[197](PERIAB,INTAB197).IPR
0x870063C6 ICU 8-bit
  [4:0] IPR[198](PERIAB,INTAB198).IPR
0x870063C7 ICU 8-bit
  [4:0] IPR[199](PERIAB,INTAB199).IPR
0x870063C8 ICU 8-bit
  [4:0] IPR[200](PERIAB,INTAB200).IPR
0x870063C9 ICU 8-bit
  [4:0] IPR[201](PERIAB,INTAB201).IPR
0x870063CA ICU 8-bit
  [4:0] IPR[202](PERIAB,INTAB202).IPR
0x870063CB ICU 8-bit
  [4:0] IPR[203](PERIAB,INTAB203).IPR
0x870063CC ICU 8-bit
  [4:0] IPR[204](PERIAB,INTAB204).IPR
0x870063CD ICU 8-bit
  [4:0] IPR[205](PERIAB,INTAB205).IPR
0x870063CE ICU 8-bit
  [4:0] IPR[206](PERIAB,INTAB206).IPR
0x870063CF ICU 8-bit
  [4:0] IPR[207](PERIAB,INTAB207).IPR
0x870063D0 ICU 8-bit
  [4:0] IPR[208](PERIAB,INTAB208).IPR
0x870063D1 ICU 8-bit
  [4:0] IPR[209](PERIAB,INTAB209).IPR
0x870063D2 ICU 8-bit
  [4:0] IPR[210](PERIAB,INTAB210).IPR
0x870063D3 ICU 8-bit
  [4:0] IPR[211](PERIAB,INTAB211).IPR
0x870063D4 ICU 8-bit
  [4:0] IPR[212](PERIAB,INTAB212).IPR
0x870063D5 ICU 8-bit
  [4:0] IPR[213](PERIAB,INTAB213).IPR
0x870063D6 ICU 8-bit
  [4:0] IPR[214](PERIAB,INTAB214).IPR
0x870063D7 ICU 8-bit
  [4:0] IPR[215](PERIAB,INTAB215).IPR
0x870063D8 ICU 8-bit
  [4:0] IPR[216](PERIAB,INTAB216).IPR
0x870063D9 ICU 8-bit
  [4:0] IPR[217](PERIAB,INTAB217).IPR
0x870063DA ICU 8-bit
  [4:0] IPR[218](PERIAB,INTAB218).IPR
0x870063DB ICU 8-bit
  [4:0] IPR[219](PERIAB,INTAB219).IPR
0x870063DC ICU 8-bit
  [4:0] IPR[220](PERIAB,INTAB220).IPR
0x870063DD ICU 8-bit
  [4:0] IPR[221](PERIAB,INTAB221).IPR
0x870063DE ICU 8-bit
  [4:0] IPR[222](PERIAB,INTAB222).IPR
0x870063DF ICU 8-bit
  [4:0] IPR[223](PERIAB,INTAB223).IPR
0x870063E0 ICU 8-bit
  [4:0] IPR[224](PERIAB,INTAB224).IPR
0x870063E1 ICU 8-bit
  [4:0] IPR[225](PERIAB,INTAB225).IPR
0x870063E2 ICU 8-bit
  [4:0] IPR[226](PERIAB,INTAB226).IPR
0x870063E3 ICU 8-bit
  [4:0] IPR[227](PERIAB,INTAB227).IPR
0x870063E4 ICU 8-bit
  [4:0] IPR[228](PERIAB,INTAB228).IPR
0x870063E5 ICU 8-bit
  [4:0] IPR[229](PERIAB,INTAB229).IPR
0x870063E6 ICU 8-bit
  [4:0] IPR[230](PERIAB,INTAB230).IPR
0x870063E7 ICU 8-bit
  [4:0] IPR[231](PERIAB,INTAB231).IPR
0x870063E8 ICU 8-bit
  [4:0] IPR[232](PERIAB,INTAB232).IPR
0x870063E9 ICU 8-bit
  [4:0] IPR[233](PERIAB,INTAB233).IPR
0x870063EA ICU 8-bit
  [4:0] IPR[234](PERIAB,INTAB234).IPR
0x870063EB ICU 8-bit
  [4:0] IPR[235](PERIAB,INTAB235).IPR
0x870063EC ICU 8-bit
  [4:0] IPR[236](PERIAB,INTAB236).IPR
0x870063ED ICU 8-bit
  [4:0] IPR[237](PERIAB,INTAB237).IPR
0x870063EE ICU 8-bit
  [4:0] IPR[238](PERIAB,INTAB238).IPR
0x870063EF ICU 8-bit
  [4:0] IPR[239](PERIAB,INTAB239).IPR
0x870063F0 ICU 8-bit
  [4:0] IPR[240](PERIAB,INTAB240).IPR
0x870063F1 ICU 8-bit
  [4:0] IPR[241](PERIAB,INTAB241).IPR
0x870063F2 ICU 8-bit
  [4:0] IPR[242](PERIAB,INTAB242).IPR
0x870063F3 ICU 8-bit
  [4:0] IPR[243](PERIAB,INTAB243).IPR
0x870063F4 ICU 8-bit
  [4:0] IPR[244](PERIAB,INTAB244).IPR
0x870063F5 ICU 8-bit
  [4:0] IPR[245](PERIAB,INTAB245).IPR
0x870063F6 ICU 8-bit
  [4:0] IPR[246](PERIAB,INTAB246).IPR
0x870063F7 ICU 8-bit
  [4:0] IPR[247](PERIAB,INTAB247).IPR
0x870063F8 ICU 8-bit
  [4:0] IPR[248](PERIAB,INTAB248).IPR
0x870063F9 ICU 8-bit
  [4:0] IPR[249](PERIAB,INTAB249).IPR
0x870063FA ICU 8-bit
  [4:0] IPR[250](PERIAB,INTAB250).IPR
0x870063FB ICU 8-bit
  [4:0] IPR[251](PERIAB,INTAB251).IPR
0x870063FC ICU 8-bit
  [4:0] IPR[252](PERIAB,INTAB252).IPR
0x870063FD ICU 8-bit
  [4:0] IPR[253](PERIAB,INTAB253).IPR
0x870063FE ICU 8-bit
  [4:0] IPR[254](PERIAB,INTAB254).IPR
0x870063FF ICU 8-bit
  [4:0] IPR[255](PERIAB,INTAB255).IPR
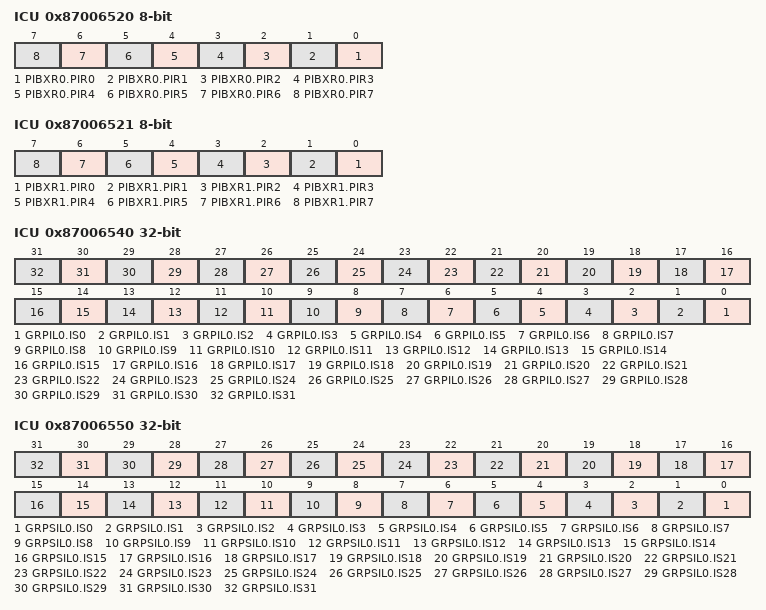
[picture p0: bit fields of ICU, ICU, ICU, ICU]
0x87006520 ICU 8-bit
  [n] PIBXR0.PIR{n} (n=0..7)
0x87006521 ICU 8-bit
  [n] PIBXR1.PIR{n} (n=0..7)
0x87006540 ICU
  [n] GRPIL0.IS{n} (n=0..31)
0x87006550 ICU
  [n] GRPSIL0.IS{n} (n=0..31)
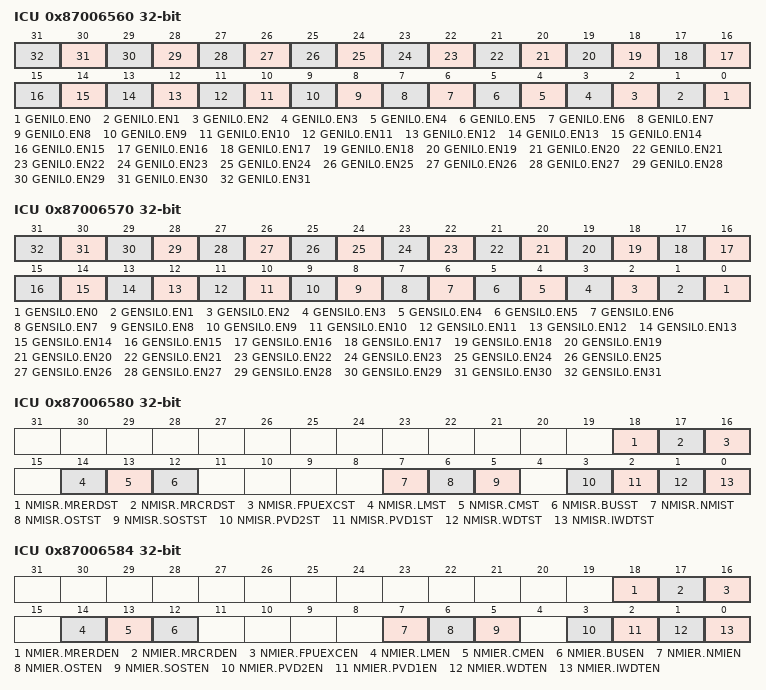
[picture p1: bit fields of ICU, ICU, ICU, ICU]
0x87006560 ICU
  [n] GENIL0.EN{n} (n=0..31)
0x87006570 ICU
  [n] GENSIL0.EN{n} (n=0..31)
0x87006580 ICU
  [18] NMISR.MRERDST, [17] NMISR.MRCRDST, [16] NMISR.FPUEXCST, [14] NMISR.LMST, [13] NMISR.CMST, [12] NMISR.BUSST, [7] NMISR.NMIST, [6] NMISR.OSTST, [5] NMISR.SOSTST, [3] NMISR.PVD2ST, [2] NMISR.PVD1ST, [1] NMISR.WDTST, [0] NMISR.IWDTST
0x87006584 ICU
  [18] NMIER.MRERDEN, [17] NMIER.MRCRDEN, [16] NMIER.FPUEXCEN, [14] NMIER.LMEN, [13] NMIER.CMEN, [12] NMIER.BUSEN, [7] NMIER.NMIEN, [6] NMIER.OSTEN, [5] NMIER.SOSTEN, [3] NMIER.PVD2EN, [2] NMIER.PVD1EN, [1] NMIER.WDTEN, [0] NMIER.IWDTEN
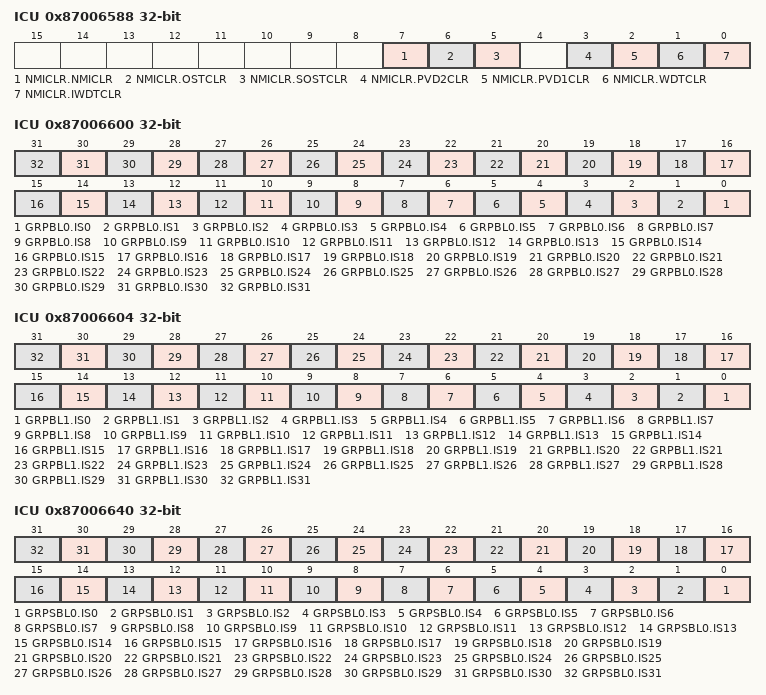
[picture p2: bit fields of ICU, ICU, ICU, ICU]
0x87006588 ICU
  [7] NMICLR.NMICLR, [6] NMICLR.OSTCLR, [5] NMICLR.SOSTCLR, [3] NMICLR.PVD2CLR, [2] NMICLR.PVD1CLR, [1] NMICLR.WDTCLR, [0] NMICLR.IWDTCLR
0x87006600 ICU
  [n] GRPBL0.IS{n} (n=0..31)
0x87006604 ICU
  [n] GRPBL1.IS{n} (n=0..31)
0x87006640 ICU
  [n] GRPSBL0.IS{n} (n=0..31)
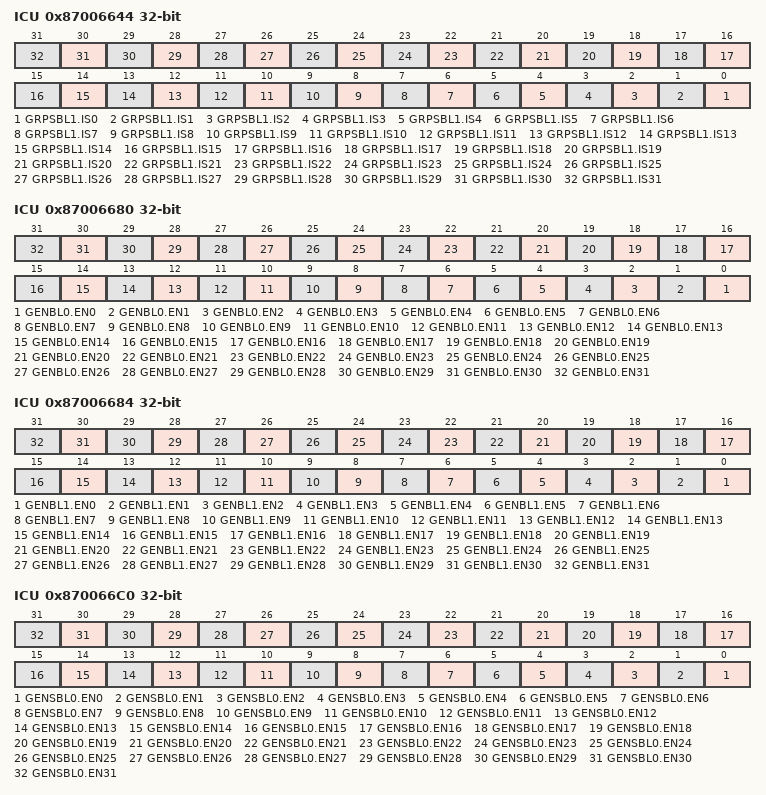
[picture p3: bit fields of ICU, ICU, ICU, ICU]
0x87006644 ICU
  [n] GRPSBL1.IS{n} (n=0..31)
0x87006680 ICU
  [n] GENBL0.EN{n} (n=0..31)
0x87006684 ICU
  [n] GENBL1.EN{n} (n=0..31)
0x870066C0 ICU
  [n] GENSBL0.EN{n} (n=0..31)
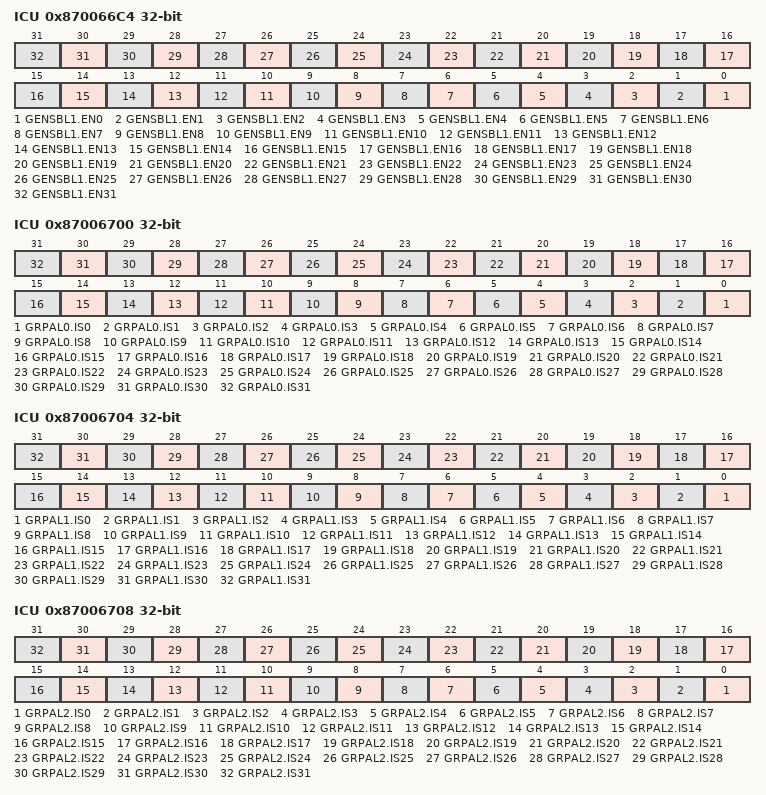
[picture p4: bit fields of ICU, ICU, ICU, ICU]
0x870066C4 ICU
  [n] GENSBL1.EN{n} (n=0..31)
0x87006700 ICU
  [n] GRPAL0.IS{n} (n=0..31)
0x87006704 ICU
  [n] GRPAL1.IS{n} (n=0..31)
0x87006708 ICU
  [n] GRPAL2.IS{n} (n=0..31)
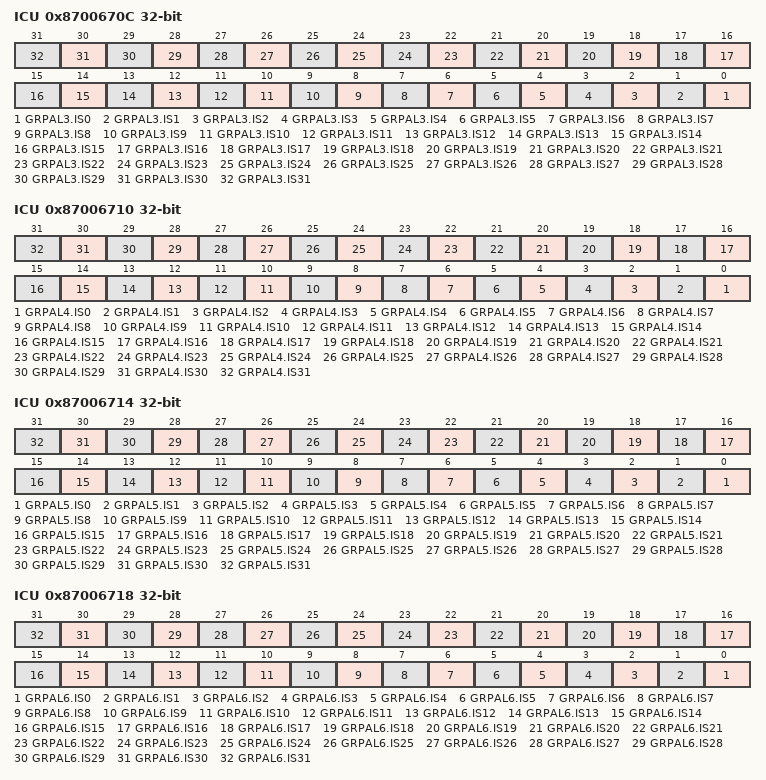
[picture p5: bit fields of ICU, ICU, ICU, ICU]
0x8700670C ICU
  [n] GRPAL3.IS{n} (n=0..31)
0x87006710 ICU
  [n] GRPAL4.IS{n} (n=0..31)
0x87006714 ICU
  [n] GRPAL5.IS{n} (n=0..31)
0x87006718 ICU
  [n] GRPAL6.IS{n} (n=0..31)
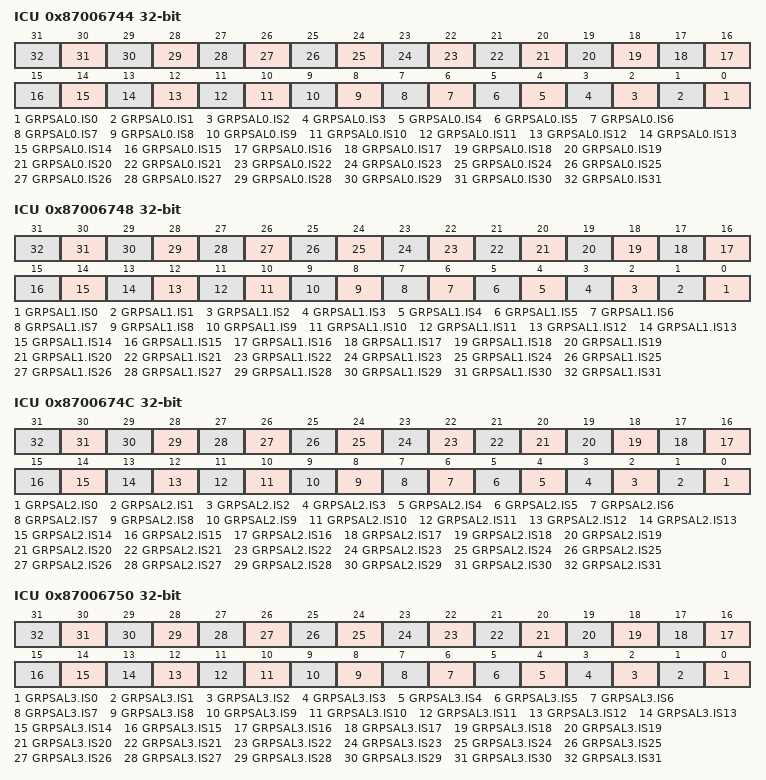
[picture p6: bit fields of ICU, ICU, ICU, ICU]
0x87006744 ICU
  [n] GRPSAL0.IS{n} (n=0..31)
0x87006748 ICU
  [n] GRPSAL1.IS{n} (n=0..31)
0x8700674C ICU
  [n] GRPSAL2.IS{n} (n=0..31)
0x87006750 ICU
  [n] GRPSAL3.IS{n} (n=0..31)
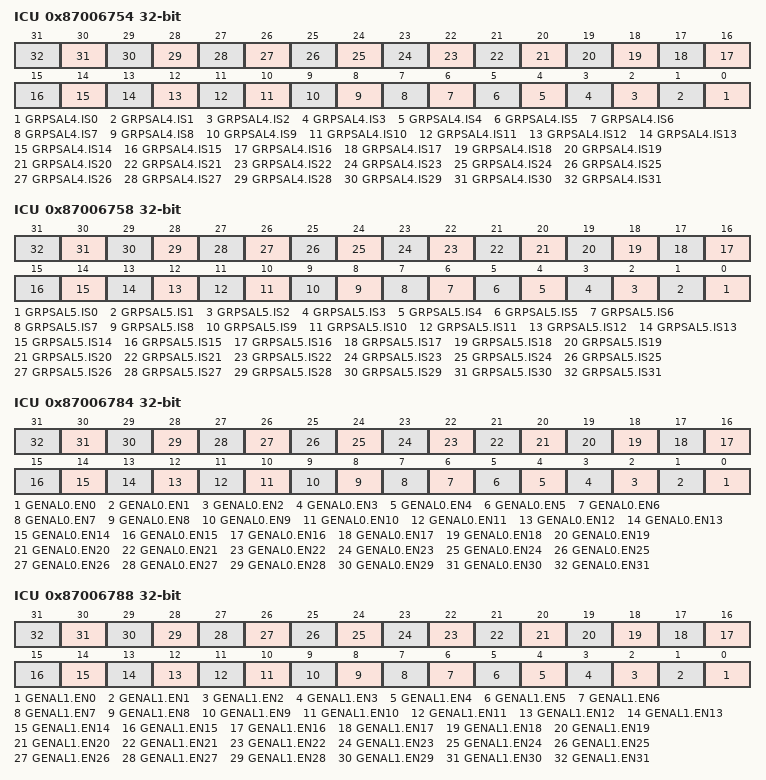
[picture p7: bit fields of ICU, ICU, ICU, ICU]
0x87006754 ICU
  [n] GRPSAL4.IS{n} (n=0..31)
0x87006758 ICU
  [n] GRPSAL5.IS{n} (n=0..31)
0x87006784 ICU
  [n] GENAL0.EN{n} (n=0..31)
0x87006788 ICU
  [n] GENAL1.EN{n} (n=0..31)
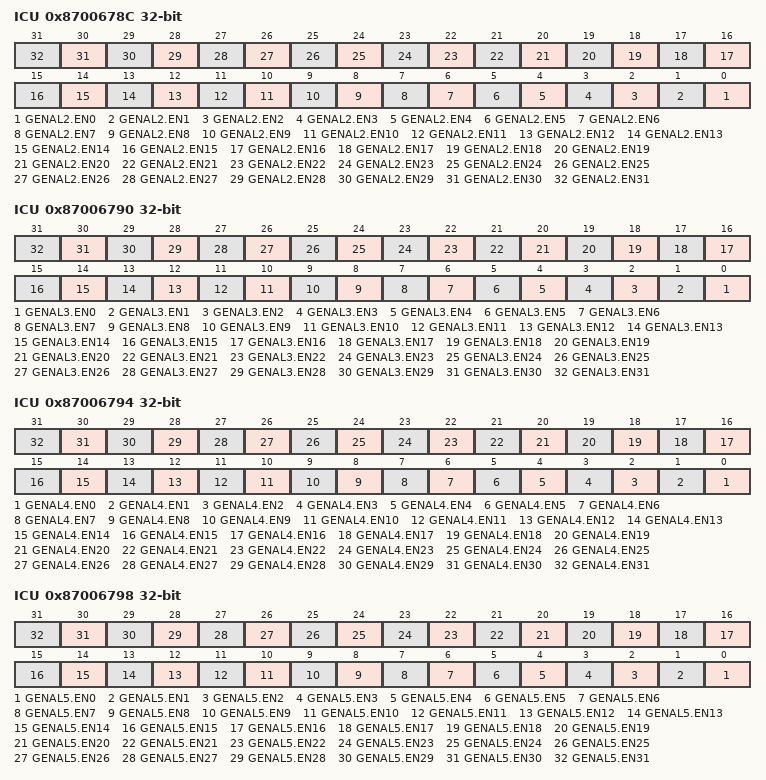
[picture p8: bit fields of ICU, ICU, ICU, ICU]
0x8700678C ICU
  [n] GENAL2.EN{n} (n=0..31)
0x87006790 ICU
  [n] GENAL3.EN{n} (n=0..31)
0x87006794 ICU
  [n] GENAL4.EN{n} (n=0..31)
0x87006798 ICU
  [n] GENAL5.EN{n} (n=0..31)
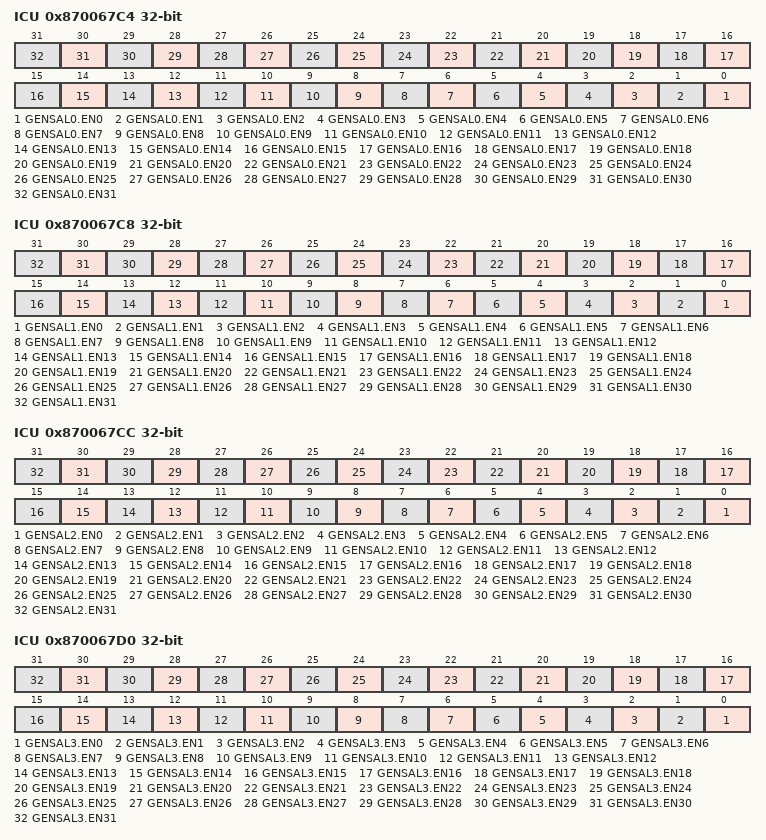
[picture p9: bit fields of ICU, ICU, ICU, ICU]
0x870067C4 ICU
  [n] GENSAL0.EN{n} (n=0..31)
0x870067C8 ICU
  [n] GENSAL1.EN{n} (n=0..31)
0x870067CC ICU
  [n] GENSAL2.EN{n} (n=0..31)
0x870067D0 ICU
  [n] GENSAL3.EN{n} (n=0..31)
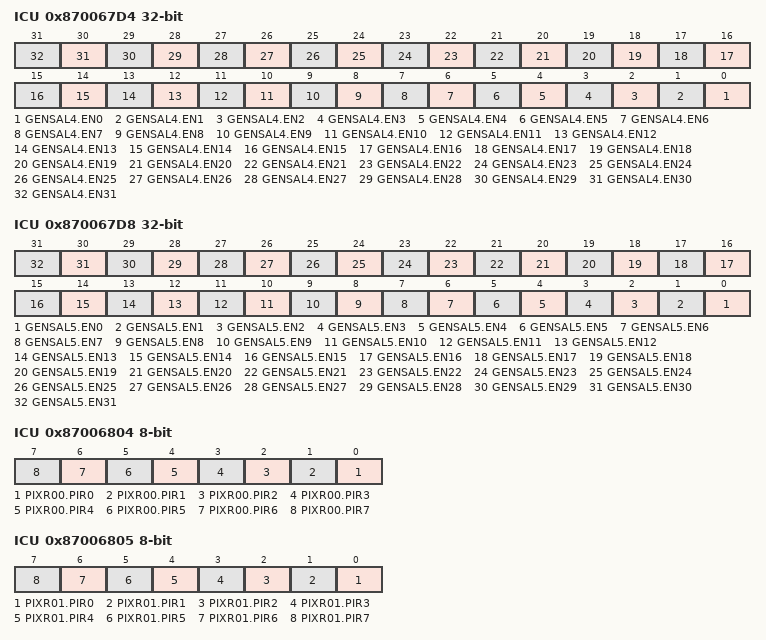
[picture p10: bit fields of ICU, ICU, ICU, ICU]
0x870067D4 ICU
  [n] GENSAL4.EN{n} (n=0..31)
0x870067D8 ICU
  [n] GENSAL5.EN{n} (n=0..31)
0x87006804 ICU 8-bit
  [n] PIXR00.PIR{n} (n=0..7)
0x87006805 ICU 8-bit
  [n] PIXR01.PIR{n} (n=0..7)
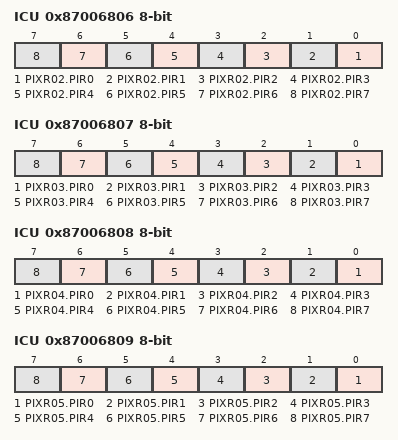
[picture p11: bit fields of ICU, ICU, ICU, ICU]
0x87006806 ICU 8-bit
  [n] PIXR02.PIR{n} (n=0..7)
0x87006807 ICU 8-bit
  [n] PIXR03.PIR{n} (n=0..7)
0x87006808 ICU 8-bit
  [n] PIXR04.PIR{n} (n=0..7)
0x87006809 ICU 8-bit
  [n] PIXR05.PIR{n} (n=0..7)
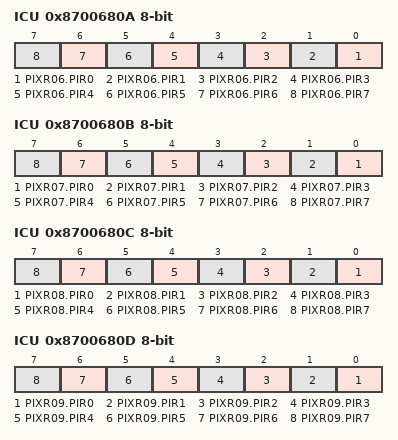
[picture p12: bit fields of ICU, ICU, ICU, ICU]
0x8700680A ICU 8-bit
  [n] PIXR06.PIR{n} (n=0..7)
0x8700680B ICU 8-bit
  [n] PIXR07.PIR{n} (n=0..7)
0x8700680C ICU 8-bit
  [n] PIXR08.PIR{n} (n=0..7)
0x8700680D ICU 8-bit
  [n] PIXR09.PIR{n} (n=0..7)
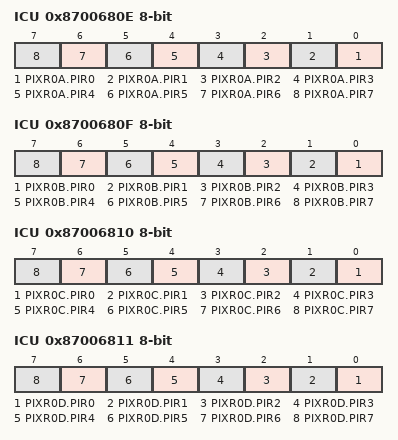
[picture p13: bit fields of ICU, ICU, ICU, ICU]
0x8700680E ICU 8-bit
  [n] PIXR0A.PIR{n} (n=0..7)
0x8700680F ICU 8-bit
  [n] PIXR0B.PIR{n} (n=0..7)
0x87006810 ICU 8-bit
  [n] PIXR0C.PIR{n} (n=0..7)
0x87006811 ICU 8-bit
  [n] PIXR0D.PIR{n} (n=0..7)
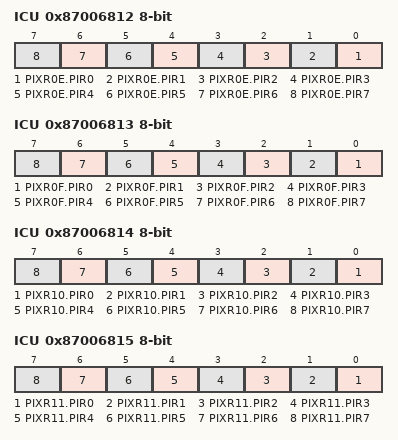
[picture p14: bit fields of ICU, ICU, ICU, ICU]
0x87006812 ICU 8-bit
  [n] PIXR0E.PIR{n} (n=0..7)
0x87006813 ICU 8-bit
  [n] PIXR0F.PIR{n} (n=0..7)
0x87006814 ICU 8-bit
  [n] PIXR10.PIR{n} (n=0..7)
0x87006815 ICU 8-bit
  [n] PIXR11.PIR{n} (n=0..7)
0x87006816 ICU 8-bit
  [n] PIXR12.PIR{n} (n=0..7)
0x87006817 ICU 8-bit
  [n] PIXR13.PIR{n} (n=0..7)
0x87006818 ICU 8-bit
  [n] PIXR14.PIR{n} (n=0..7)
0x87006819 ICU 8-bit
  [n] PIXR15.PIR{n} (n=0..7)
0x8700681A ICU 8-bit
  [n] PIXR16.PIR{n} (n=0..7)
0x8700681B ICU 8-bit
  [n] PIXR17.PIR{n} (n=0..7)
0x8700681C ICU 8-bit
  [n] PIXR18.PIR{n} (n=0..7)
0x8700681D ICU 8-bit
  [n] PIXR19.PIR{n} (n=0..7)
0x8700681E ICU 8-bit
  [n] PIXR1A.PIR{n} (n=0..7)
0x8700681F ICU 8-bit
  [n] PIXR1B.PIR{n} (n=0..7)
0x87006820 ICU 8-bit
  [n] PIXR1C.PIR{n} (n=0..7)
0x87006821 ICU 8-bit
  [n] PIXR1D.PIR{n} (n=0..7)
0x87006822 ICU 8-bit
  [n] PIXR1E.PIR{n} (n=0..7)
0x87006823 ICU 8-bit
  [n] PIXR1F.PIR{n} (n=0..7)
0x87006824 ICU 8-bit
  [n] PIXR20.PIR{n} (n=0..7)
0x87006825 ICU 8-bit
  [n] PIXR21.PIR{n} (n=0..7)
0x87006826 ICU 8-bit
  [n] PIXR22.PIR{n} (n=0..7)
0x87006827 ICU 8-bit
  [n] PIXR23.PIR{n} (n=0..7)
0x87006828 ICU 8-bit
  [n] PIXR24.PIR{n} (n=0..7)
0x87006829 ICU 8-bit
  [n] PIXR25.PIR{n} (n=0..7)
0x8700682A ICU 8-bit
  [n] PIXR26.PIR{n} (n=0..7)
0x8700682B ICU 8-bit
  [n] PIXR27.PIR{n} (n=0..7)
0x8700682C ICU 8-bit
  [n] PIXR28.PIR{n} (n=0..7)
0x8700682D ICU 8-bit
  [n] PIXR29.PIR{n} (n=0..7)
0x8700682E ICU 8-bit
  [n] PIXR2A.PIR{n} (n=0..7)
0x8700682F ICU 8-bit
  [n] PIXR2B.PIR{n} (n=0..7)
0x87006830 ICU 8-bit
  [n] PIXR2C.PIR{n} (n=0..7)
0x87006831 ICU 8-bit
  [n] PIXR2D.PIR{n} (n=0..7)
0x87006832 ICU 8-bit
  [n] PIXR2E.PIR{n} (n=0..7)
0x87006833 ICU 8-bit
  [n] PIXR2F.PIR{n} (n=0..7)
0x87006834 ICU 8-bit
  [n] PIXR30.PIR{n} (n=0..7)
0x87006835 ICU 8-bit
  [n] PIXR31.PIR{n} (n=0..7)
0x87006836 ICU 8-bit
  [n] PIXR32.PIR{n} (n=0..7)
0x87006837 ICU 8-bit
  [n] PIXR33.PIR{n} (n=0..7)
0x87006838 ICU 8-bit
  [n] PIXR34.PIR{n} (n=0..7)
0x87006839 ICU 8-bit
  [n] PIXR35.PIR{n} (n=0..7)
0x8700683A ICU 8-bit
  [n] PIXR36.PIR{n} (n=0..7)
0x8700683B ICU 8-bit
  [n] PIXR37.PIR{n} (n=0..7)
0x8700683C ICU 8-bit
  [n] PIXR38.PIR{n} (n=0..7)
0x8700683D ICU 8-bit
  [n] PIXR39.PIR{n} (n=0..7)
0x8700683E ICU 8-bit
  [n] PIXR3A.PIR{n} (n=0..7)
0x8700683F ICU 8-bit
  [n] PIXR3B.PIR{n} (n=0..7)
0x87006840 ICU 8-bit
  [n] PIXR3C.PIR{n} (n=0..7)
0x87006841 ICU 8-bit
  [n] PIXR3D.PIR{n} (n=0..7)
0x87006842 ICU 8-bit
  [n] PIXR3E.PIR{n} (n=0..7)
0x87006843 ICU 8-bit
  [n] PIXR3F.PIR{n} (n=0..7)
0x87006844 ICU 8-bit
  [n] PIXR40.PIR{n} (n=0..7)
0x87006845 ICU 8-bit
  [n] PIXR41.PIR{n} (n=0..7)
0x87006846 ICU 8-bit
  [n] PIXR42.PIR{n} (n=0..7)
0x87006847 ICU 8-bit
  [n] PIXR43.PIR{n} (n=0..7)
0x87006848 ICU 8-bit
  [n] PIXR44.PIR{n} (n=0..7)
0x87006849 ICU 8-bit
  [n] PIXR45.PIR{n} (n=0..7)
0x8700684A ICU 8-bit
  [n] PIXR46.PIR{n} (n=0..7)
0x8700684B ICU 8-bit
  [n] PIXR47.PIR{n} (n=0..7)
0x8700684C ICU 8-bit
  [n] PIXR48.PIR{n} (n=0..7)
0x8700684D ICU 8-bit
  [n] PIXR49.PIR{n} (n=0..7)
0x8700684E ICU 8-bit
  [n] PIXR4A.PIR{n} (n=0..7)
0x8700684F ICU 8-bit
  [n] PIXR4B.PIR{n} (n=0..7)
0x87006850 ICU 8-bit
  [n] PIXR4C.PIR{n} (n=0..7)
0x87006851 ICU 8-bit
  [n] PIXR4D.PIR{n} (n=0..7)
0x87006852 ICU 8-bit
  [n] PIXR4E.PIR{n} (n=0..7)
0x87006853 ICU 8-bit
  [n] PIXR4F.PIR{n} (n=0..7)
0x87006854 ICU 8-bit
  [n] PIXR50.PIR{n} (n=0..7)
0x87006855 ICU 8-bit
  [n] PIXR51.PIR{n} (n=0..7)
0x87006856 ICU 8-bit
  [n] PIXR52.PIR{n} (n=0..7)
0x87006857 ICU 8-bit
  [n] PIXR53.PIR{n} (n=0..7)
0x87006858 ICU 8-bit
  [n] PIXR54.PIR{n} (n=0..7)
0x87006859 ICU 8-bit
  [n] PIXR55.PIR{n} (n=0..7)
0x8700685A ICU 8-bit
  [n] PIXR56.PIR{n} (n=0..7)
0x8700685B ICU 8-bit
  [n] PIXR57.PIR{n} (n=0..7)
0x8700685C ICU 8-bit
  [n] PIXR58.PIR{n} (n=0..7)
0x8700685D ICU 8-bit
  [n] PIXR59.PIR{n} (n=0..7)
0x8700685E ICU 8-bit
  [n] PIXR5A.PIR{n} (n=0..7)
0x8700685F ICU 8-bit
  [n] PIXR5B.PIR{n} (n=0..7)
0x87006860 ICU 8-bit
  [n] PIXR5C.PIR{n} (n=0..7)
0x87006861 ICU 8-bit
  [n] PIXR5D.PIR{n} (n=0..7)
0x87006862 ICU 8-bit
  [n] PIXR5E.PIR{n} (n=0..7)
0x87006863 ICU 8-bit
  [n] PIXR5F.PIR{n} (n=0..7)
0x87006864 ICU 8-bit
  [n] PIXR60.PIR{n} (n=0..7)
0x87006865 ICU 8-bit
  [n] PIXR61.PIR{n} (n=0..7)
0x87006866 ICU 8-bit
  [n] PIXR62.PIR{n} (n=0..7)
0x87006867 ICU 8-bit
  [n] PIXR63.PIR{n} (n=0..7)
0x87006868 ICU 8-bit
  [n] PIXR64.PIR{n} (n=0..7)
0x87006869 ICU 8-bit
  [n] PIXR65.PIR{n} (n=0..7)
0x8700686A ICU 8-bit
  [n] PIXR66.PIR{n} (n=0..7)
0x8700686B ICU 8-bit
  [n] PIXR67.PIR{n} (n=0..7)
0x8700686C ICU 8-bit
  [n] PIXR68.PIR{n} (n=0..7)
0x8700686D ICU 8-bit
  [n] PIXR69.PIR{n} (n=0..7)
0x8700686E ICU 8-bit
  [n] PIXR6A.PIR{n} (n=0..7)
0x8700686F ICU 8-bit
  [n] PIXR6B.PIR{n} (n=0..7)
0x87006870 ICU 8-bit
  [n] PIXR6C.PIR{n} (n=0..7)
0x87006871 ICU 8-bit
  [n] PIXR6D.PIR{n} (n=0..7)
0x87006872 ICU 8-bit
  [n] PIXR6E.PIR{n} (n=0..7)
0x87006873 ICU 8-bit
  [n] PIXR6F.PIR{n} (n=0..7)
0x87006874 ICU 8-bit
  [n] PIXR70.PIR{n} (n=0..7)
0x87006875 ICU 8-bit
  [n] PIXR71.PIR{n} (n=0..7)
0x87006876 ICU 8-bit
  [n] PIXR72.PIR{n} (n=0..7)
0x87006877 ICU 8-bit
  [n] PIXR73.PIR{n} (n=0..7)
0x87006878 ICU 8-bit
  [n] PIXR74.PIR{n} (n=0..7)
0x87006879 ICU 8-bit
  [n] PIXR75.PIR{n} (n=0..7)
0x8700687A ICU 8-bit
  [n] PIXR76.PIR{n} (n=0..7)
0x8700687B ICU 8-bit
  [n] PIXR77.PIR{n} (n=0..7)
0x8700687C ICU 8-bit
  [n] PIXR78.PIR{n} (n=0..7)
0x8700687D ICU 8-bit
  [n] PIXR79.PIR{n} (n=0..7)
0x8700687E ICU 8-bit
  [n] PIXR7A.PIR{n} (n=0..7)
0x8700687F ICU 8-bit
  [n] PIXR7B.PIR{n} (n=0..7)
0x87006880 ICU 8-bit
  [n] PIXR7C.PIR{n} (n=0..7)
0x87006881 ICU 8-bit
  [n] PIXR7D.PIR{n} (n=0..7)
0x87006882 ICU 8-bit
  [n] PIXR7E.PIR{n} (n=0..7)
0x87006883 ICU 8-bit
  [n] PIXR7F.PIR{n} (n=0..7)
0x87006904 ICU 16-bit
  [9:0] SLIXR128.SLI
0x87006906 ICU 16-bit
  [9:0] SLIXR129.SLI
0x87006908 ICU 16-bit
  [9:0] SLIXR130.SLI
0x8700690A ICU 16-bit
  [9:0] SLIXR131.SLI
0x8700690C ICU 16-bit
  [9:0] SLIXR132.SLI
0x8700690E ICU 16-bit
  [9:0] SLIXR133.SLI
0x87006910 ICU 16-bit
  [9:0] SLIXR134.SLI
0x87006912 ICU 16-bit
  [9:0] SLIXR135.SLI
0x87006914 ICU 16-bit
  [9:0] SLIXR136.SLI
0x87006916 ICU 16-bit
  [9:0] SLIXR137.SLI
0x87006918 ICU 16-bit
  [9:0] SLIXR138.SLI
0x8700691A ICU 16-bit
  [9:0] SLIXR139.SLI
0x8700691C ICU 16-bit
  [9:0] SLIXR140.SLI
0x8700691E ICU 16-bit
  [9:0] SLIXR141.SLI
0x87006920 ICU 16-bit
  [9:0] SLIXR142.SLI
0x87006922 ICU 16-bit
  [9:0] SLIXR143.SLI
0x87006924 ICU 16-bit
  [9:0] SLIR144.SLI
0x87006926 ICU 16-bit
  [9:0] SLIR145.SLI
0x87006928 ICU 16-bit
  [9:0] SLIR146.SLI
0x8700692A ICU 16-bit
  [9:0] SLIR147.SLI
0x8700692C ICU 16-bit
  [9:0] SLIR148.SLI
0x8700692E ICU 16-bit
  [9:0] SLIR149.SLI
0x87006930 ICU 16-bit
  [9:0] SLIR150.SLI
0x87006932 ICU 16-bit
  [9:0] SLIR151.SLI
0x87006934 ICU 16-bit
  [9:0] SLIR152.SLI
0x87006936 ICU 16-bit
  [9:0] SLIR153.SLI
0x87006938 ICU 16-bit
  [9:0] SLIR154.SLI
0x8700693A ICU 16-bit
  [9:0] SLIR155.SLI
0x8700693C ICU 16-bit
  [9:0] SLIR156.SLI
0x8700693E ICU 16-bit
  [9:0] SLIR157.SLI
0x87006940 ICU 16-bit
  [9:0] SLIR158.SLI
0x87006942 ICU 16-bit
  [9:0] SLIR159.SLI
0x87006944 ICU 16-bit
  [9:0] SLIR160.SLI
0x87006946 ICU 16-bit
  [9:0] SLIR161.SLI
0x87006948 ICU 16-bit
  [9:0] SLIR162.SLI
0x8700694A ICU 16-bit
  [9:0] SLIR163.SLI
0x8700694C ICU 16-bit
  [9:0] SLIR164.SLI
0x8700694E ICU 16-bit
  [9:0] SLIR165.SLI
0x87006950 ICU 16-bit
  [9:0] SLIR166.SLI
0x87006952 ICU 16-bit
  [9:0] SLIR167.SLI
0x87006954 ICU 16-bit
  [9:0] SLIR168.SLI
0x87006956 ICU 16-bit
  [9:0] SLIR169.SLI
0x87006958 ICU 16-bit
  [9:0] SLIR170.SLI
0x8700695A ICU 16-bit
  [9:0] SLIR171.SLI
0x8700695C ICU 16-bit
  [9:0] SLIR172.SLI
0x8700695E ICU 16-bit
  [9:0] SLIR173.SLI
0x87006960 ICU 16-bit
  [9:0] SLIR174.SLI
0x87006962 ICU 16-bit
  [9:0] SLIR175.SLI
0x87006964 ICU 16-bit
  [9:0] SLIR176.SLI
0x87006966 ICU 16-bit
  [9:0] SLIR177.SLI
0x87006968 ICU 16-bit
  [9:0] SLIR178.SLI
0x8700696A ICU 16-bit
  [9:0] SLIR179.SLI
0x8700696C ICU 16-bit
  [9:0] SLIR180.SLI
0x8700696E ICU 16-bit
  [9:0] SLIR181.SLI
0x87006970 ICU 16-bit
  [9:0] SLIR182.SLI
0x87006972 ICU 16-bit
  [9:0] SLIR183.SLI
0x87006974 ICU 16-bit
  [9:0] SLIR184.SLI
0x87006976 ICU 16-bit
  [9:0] SLIR185.SLI
0x87006978 ICU 16-bit
  [9:0] SLIR186.SLI
0x8700697A ICU 16-bit
  [9:0] SLIR187.SLI
0x8700697C ICU 16-bit
  [9:0] SLIR188.SLI
0x8700697E ICU 16-bit
  [9:0] SLIR189.SLI
0x87006980 ICU 16-bit
  [9:0] SLIR190.SLI
0x87006982 ICU 16-bit
  [9:0] SLIR191.SLI
0x87006984 ICU 16-bit
  [9:0] SLIR192.SLI
0x87006986 ICU 16-bit
  [9:0] SLIR193.SLI
0x87006988 ICU 16-bit
  [9:0] SLIR194.SLI
0x8700698A ICU 16-bit
  [9:0] SLIR195.SLI
0x8700698C ICU 16-bit
  [9:0] SLIR196.SLI
0x8700698E ICU 16-bit
  [9:0] SLIR197.SLI
0x87006990 ICU 16-bit
  [9:0] SLIR198.SLI
0x87006992 ICU 16-bit
  [9:0] SLIR199.SLI
0x87006994 ICU 16-bit
  [9:0] SLIR200.SLI
0x87006996 ICU 16-bit
  [9:0] SLIR201.SLI
0x87006998 ICU 16-bit
  [9:0] SLIR202.SLI
0x8700699A ICU 16-bit
  [9:0] SLIR203.SLI
0x8700699C ICU 16-bit
  [9:0] SLIR204.SLI
0x8700699E ICU 16-bit
  [9:0] SLIR205.SLI
0x870069A0 ICU 16-bit
  [9:0] SLIR206.SLI
0x870069A2 ICU 16-bit
  [9:0] SLIR207.SLI
0x870069A4 ICU 16-bit
  [9:0] SLIR208.SLI
0x870069A6 ICU 16-bit
  [9:0] SLIR209.SLI
0x870069A8 ICU 16-bit
  [9:0] SLIR210.SLI
0x870069AA ICU 16-bit
  [9:0] SLIR211.SLI
0x870069AC ICU 16-bit
  [9:0] SLIR212.SLI
0x870069AE ICU 16-bit
  [9:0] SLIR213.SLI
0x870069B0 ICU 16-bit
  [9:0] SLIR214.SLI
0x870069B2 ICU 16-bit
  [9:0] SLIR215.SLI
0x870069B4 ICU 16-bit
  [9:0] SLIR216.SLI
0x870069B6 ICU 16-bit
  [9:0] SLIR217.SLI
0x870069B8 ICU 16-bit
  [9:0] SLIR218.SLI
0x870069BA ICU 16-bit
  [9:0] SLIR219.SLI
0x870069BC ICU 16-bit
  [9:0] SLIR220.SLI
0x870069BE ICU 16-bit
  [9:0] SLIR221.SLI
0x870069C0 ICU 16-bit
  [9:0] SLIR222.SLI
0x870069C2 ICU 16-bit
  [9:0] SLIR223.SLI
0x870069C4 ICU 16-bit
  [9:0] SLIR224.SLI
0x870069C6 ICU 16-bit
  [9:0] SLIR225.SLI
0x870069C8 ICU 16-bit
  [9:0] SLIR226.SLI
0x870069CA ICU 16-bit
  [9:0] SLIR227.SLI
0x870069CC ICU 16-bit
  [9:0] SLIR228.SLI
0x870069CE ICU 16-bit
  [9:0] SLIR229.SLI
0x870069D0 ICU 16-bit
  [9:0] SLIR230.SLI
0x870069D2 ICU 16-bit
  [9:0] SLIR231.SLI
0x870069D4 ICU 16-bit
  [9:0] SLIR232.SLI
0x870069D6 ICU 16-bit
  [9:0] SLIR233.SLI
0x870069D8 ICU 16-bit
  [9:0] SLIR234.SLI
0x870069DA ICU 16-bit
  [9:0] SLIR235.SLI
0x870069DC ICU 16-bit
  [9:0] SLIR236.SLI
0x870069DE ICU 16-bit
  [9:0] SLIR237.SLI
0x870069E0 ICU 16-bit
  [9:0] SLIR238.SLI
0x870069E2 ICU 16-bit
  [9:0] SLIR239.SLI
0x870069E4 ICU 16-bit
  [9:0] SLIR240.SLI
0x870069E6 ICU 16-bit
  [9:0] SLIR241.SLI
0x870069E8 ICU 16-bit
  [9:0] SLIR242.SLI
0x870069EA ICU 16-bit
  [9:0] SLIR243.SLI
0x870069EC ICU 16-bit
  [9:0] SLIR244.SLI
0x870069EE ICU 16-bit
  [9:0] SLIR245.SLI
0x870069F0 ICU 16-bit
  [9:0] SLIR246.SLI
0x870069F2 ICU 16-bit
  [9:0] SLIR247.SLI
0x870069F4 ICU 16-bit
  [9:0] SLIR248.SLI
0x870069F6 ICU 16-bit
  [9:0] SLIR249.SLI
0x870069F8 ICU 16-bit
  [9:0] SLIR250.SLI
0x870069FA ICU 16-bit
  [9:0] SLIR251.SLI
0x870069FC ICU 16-bit
  [9:0] SLIR252.SLI
0x870069FE ICU 16-bit
  [9:0] SLIR253.SLI
0x87006A00 ICU 16-bit
  [9:0] SLIR254.SLI
0x87006A02 ICU 16-bit
  [9:0] SLIR255.SLI
0x87006A04 ICU 8-bit
  [0] SLIPRCR.WPRC
0x87006A08 ICU 8-bit
  [0] SLISPRCR.WPRC
0x87006C00 ICU 8-bit
  [0] CLPCR.DEEPSLEEP
0x87006C10 ICU 8-bit
  [7] NMICR.NFLTEN, [6:4] NMICR.NFCLKSEL, [2] NMICR.NFLTMD, [0] NMICR.NMIMD
0x87006C24 ICU 8-bit
  [7] IRQCR[0].FLTEN, [6:4] IRQCR[0].FCLKSEL, [2] IRQCR[0].FLTMD, [1:0] IRQCR[0].IRQMD
0x87006C25 ICU 8-bit
  [7] IRQCR[1].FLTEN, [6:4] IRQCR[1].FCLKSEL, [2] IRQCR[1].FLTMD, [1:0] IRQCR[1].IRQMD
0x87006C26 ICU 8-bit
  [7] IRQCR[2].FLTEN, [6:4] IRQCR[2].FCLKSEL, [2] IRQCR[2].FLTMD, [1:0] IRQCR[2].IRQMD
0x87006C27 ICU 8-bit
  [7] IRQCR[3].FLTEN, [6:4] IRQCR[3].FCLKSEL, [2] IRQCR[3].FLTMD, [1:0] IRQCR[3].IRQMD
0x87006C28 ICU 8-bit
  [7] IRQCR[4].FLTEN, [6:4] IRQCR[4].FCLKSEL, [2] IRQCR[4].FLTMD, [1:0] IRQCR[4].IRQMD
0x87006C29 ICU 8-bit
  [7] IRQCR[5].FLTEN, [6:4] IRQCR[5].FCLKSEL, [2] IRQCR[5].FLTMD, [1:0] IRQCR[5].IRQMD
0x87006C2A ICU 8-bit
  [7] IRQCR[6].FLTEN, [6:4] IRQCR[6].FCLKSEL, [2] IRQCR[6].FLTMD, [1:0] IRQCR[6].IRQMD
0x87006C2B ICU 8-bit
  [7] IRQCR[7].FLTEN, [6:4] IRQCR[7].FCLKSEL, [2] IRQCR[7].FLTMD, [1:0] IRQCR[7].IRQMD
0x87006C2C ICU 8-bit
  [7] IRQCR[8].FLTEN, [6:4] IRQCR[8].FCLKSEL, [2] IRQCR[8].FLTMD, [1:0] IRQCR[8].IRQMD
0x87006C2D ICU 8-bit
  [7] IRQCR[9].FLTEN, [6:4] IRQCR[9].FCLKSEL, [2] IRQCR[9].FLTMD, [1:0] IRQCR[9].IRQMD
0x87006C2E ICU 8-bit
  [7] IRQCR[10].FLTEN, [6:4] IRQCR[10].FCLKSEL, [2] IRQCR[10].FLTMD, [1:0] IRQCR[10].IRQMD
0x87006C2F ICU 8-bit
  [7] IRQCR[11].FLTEN, [6:4] IRQCR[11].FCLKSEL, [2] IRQCR[11].FLTMD, [1:0] IRQCR[11].IRQMD
0x87006C30 ICU 8-bit
  [7] IRQCR[12].FLTEN, [6:4] IRQCR[12].FCLKSEL, [2] IRQCR[12].FLTMD, [1:0] IRQCR[12].IRQMD
0x87006C31 ICU 8-bit
  [7] IRQCR[13].FLTEN, [6:4] IRQCR[13].FCLKSEL, [2] IRQCR[13].FLTMD, [1:0] IRQCR[13].IRQMD
0x87006C32 ICU 8-bit
  [7] IRQCR[14].FLTEN, [6:4] IRQCR[14].FCLKSEL, [2] IRQCR[14].FLTMD, [1:0] IRQCR[14].IRQMD
0x87006C33 ICU 8-bit
  [7] IRQCR[15].FLTEN, [6:4] IRQCR[15].FCLKSEL, [2] IRQCR[15].FLTMD, [1:0] IRQCR[15].IRQMD
0x87006C34 ICU 8-bit
  [7] IRQCR[16].FLTEN, [6:4] IRQCR[16].FCLKSEL, [2] IRQCR[16].FLTMD, [1:0] IRQCR[16].IRQMD
0x87006C35 ICU 8-bit
  [7] IRQCR[17].FLTEN, [6:4] IRQCR[17].FCLKSEL, [2] IRQCR[17].FLTMD, [1:0] IRQCR[17].IRQMD
0x87006C36 ICU 8-bit
  [7] IRQCR[18].FLTEN, [6:4] IRQCR[18].FCLKSEL, [2] IRQCR[18].FLTMD, [1:0] IRQCR[18].IRQMD
0x87006C37 ICU 8-bit
  [7] IRQCR[19].FLTEN, [6:4] IRQCR[19].FCLKSEL, [2] IRQCR[19].FLTMD, [1:0] IRQCR[19].IRQMD
0x87006C38 ICU 8-bit
  [7] IRQCR[20].FLTEN, [6:4] IRQCR[20].FCLKSEL, [2] IRQCR[20].FLTMD, [1:0] IRQCR[20].IRQMD
0x87006C39 ICU 8-bit
  [7] IRQCR[21].FLTEN, [6:4] IRQCR[21].FCLKSEL, [2] IRQCR[21].FLTMD, [1:0] IRQCR[21].IRQMD
0x87006C3A ICU 8-bit
  [7] IRQCR[22].FLTEN, [6:4] IRQCR[22].FCLKSEL, [2] IRQCR[22].FLTMD, [1:0] IRQCR[22].IRQMD
0x87006C3B ICU 8-bit
  [7] IRQCR[23].FLTEN, [6:4] IRQCR[23].FCLKSEL, [2] IRQCR[23].FLTMD, [1:0] IRQCR[23].IRQMD
0x87006C3C ICU 8-bit
  [7] IRQCR[24].FLTEN, [6:4] IRQCR[24].FCLKSEL, [2] IRQCR[24].FLTMD, [1:0] IRQCR[24].IRQMD
0x87006C3D ICU 8-bit
  [7] IRQCR[25].FLTEN, [6:4] IRQCR[25].FCLKSEL, [2] IRQCR[25].FLTMD, [1:0] IRQCR[25].IRQMD
0x87006C3E ICU 8-bit
  [7] IRQCR[26].FLTEN, [6:4] IRQCR[26].FCLKSEL, [2] IRQCR[26].FLTMD, [1:0] IRQCR[26].IRQMD
0x87006C3F ICU 8-bit
  [7] IRQCR[27].FLTEN, [6:4] IRQCR[27].FCLKSEL, [2] IRQCR[27].FLTMD, [1:0] IRQCR[27].IRQMD
0x87006C40 ICU 8-bit
  [7] IRQCR[28].FLTEN, [6:4] IRQCR[28].FCLKSEL, [2] IRQCR[28].FLTMD, [1:0] IRQCR[28].IRQMD
0x87006C41 ICU 8-bit
  [7] IRQCR[29].FLTEN, [6:4] IRQCR[29].FCLKSEL, [2] IRQCR[29].FLTMD, [1:0] IRQCR[29].IRQMD
0x87006C42 ICU 8-bit
  [7] IRQCR[30].FLTEN, [6:4] IRQCR[30].FCLKSEL, [2] IRQCR[30].FLTMD, [1:0] IRQCR[30].IRQMD
0x87006C43 ICU 8-bit
  [7] IRQCR[31].FLTEN, [6:4] IRQCR[31].FCLKSEL, [2] IRQCR[31].FLTMD, [1:0] IRQCR[31].IRQMD
0x87006C44 ICU
  [20:16] SLIDMXR0.SLIR, [9:0] SLIDMXR0.SLI
0x87006C48 ICU
  [20:16] SLIDMXR1.SLIR, [9:0] SLIDMXR1.SLI
{0x87007008+0x40*i} DMAC{i:02} (i=0..7)
  [25:16] DMCRA.DMCRAH, [15:0] DMCRA.DMCRAL
{0x8700700C+0x40*i} DMAC{i:02} (i=0..7)
  [31:16] DMCRB.DMCRBH, [15:0] DMCRB.DMCRBL
{0x87007010+0x40*i} DMAC{i:02} 16-bit (i=0..7)
  [15:14] DMTMD.MD, [13:12] DMTMD.DTS, [10] DMTMD.TKP, [9:8] DMTMD.SZ, [1:0] DMTMD.DCTG
{0x87007013+0x40*i} DMAC{i:02} 8-bit (i=0..7)
  [4] DMINT.DTIE, [3] DMINT.ESIE, [2] DMINT.RPTIE, [1] DMINT.SARIE, [0] DMINT.DARIE
{0x87007014+0x40*i} DMAC{i:02} 16-bit (i=0..7)
  [15:14] DMAMD.SM, [13] DMAMD.SADR, [12:8] DMAMD.SARA, [7:6] DMAMD.DM, [5] DMAMD.DADR, [4:0] DMAMD.DARA
{0x8700701C+0x40*i} DMAC{i:02} 8-bit (i=0..7)
  [0] DMCNT.DTE
{0x8700701D+0x40*i} DMAC{i:02} 8-bit (i=0..7)
  [4] DMREQ.CLRS, [0] DMREQ.SWREQ
{0x8700701E+0x40*i} DMAC{i:02} 8-bit (i=0..7)
  [7] DMSTS.ACT, [4] DMSTS.DTIF, [0] DMSTS.ESIF
{0x8700701F+0x40*i} DMAC{i:02} 8-bit (i=0..7)
  [0] DMCSL.DISEL
{0x87007028+0x40*i} DMAC{i:02} (i=0..7)
  [31:16] DMSBS.DMSBSH, [15:0] DMSBS.DMSBSL
{0x8700702C+0x40*i} DMAC{i:02} (i=0..7)
  [31:16] DMDBS.DMDBSH, [15:0] DMDBS.DMDBSL
{0x87007030+0x40*i} DMAC{i:02} 8-bit (i=0..7)
  [0] DMBWR.BWE
0x87007800 DMA0 8-bit
  [0] DMAST.DMST
0x87007804 DMA0 8-bit
  [n] DMIST.DMIS{n} (n=4..7)
0x87007810 DMA0 8-bit
  [4] DMCTL.ERCH, [0] DMCTL.PR
0x87007840 DMA0
  [16] DMECHR.DMESTA, [12] DMECHR.DMERRW, [8] DMECHR.DMECHSAM, [3:0] DMECHR.DMECH
0x87007C0C DTC0 8-bit
  [0] DTCST.DTCST
0x87007C0E DTC0 16-bit
  [15] DTCSTS.ACT, [7:0] DTCSTS.VECN
0x87007C10 DTC0 8-bit
  [4] DTCCR_SEC.RRSS
0x87007C14 DTC0
  [31:10] DTCVBR_SEC.DTCVBR_SEC
0x87007C18 DTC0
  [31:0] DTCDISP.DTCDISP
0x87007C20 DTC0
  [16] DTEVR.DTESTA, [15] DTEVR.DTEWB, [14:12] DTEVR.DTERRD, [8] DTEVR.DTEVSAM, [7:0] DTEVR.DTEV
0x87007C24 DTC0
  [31:10] DTCIBR.DTCIBR
0x87007C28 DTC0 8-bit
  [0] DTCOR.SQTFRL
0x87007C2C DTC0 16-bit
  [15] DTCSQE.ESPSEL, [7:0] DTCSQE.VECN
0x87010000 BUSMPU 16-bit
  [15:8] MMPUOAD.KEY, [0] MMPUOAD.OAD
0x87010004 BUSMPU 16-bit
  [15:8] MMPUOADPT.KEY, [0] MMPUOADPT.PROTECT
0x87011300 BUSMPU 16-bit
  [15:8] MMPUENXSPI0.KEY, [0] MMPUENXSPI0.ENABLE
0x87011304 BUSMPU 16-bit
  [15:8] MMPUENPTXSPI0.KEY, [0] MMPUENPTXSPI0.PROTECT
0x87011308 BUSMPU 16-bit
  [15:8] MMPURPTXSPI0.KEY, [0] MMPURPTXSPI0.PROTECT
0x87011400 BUSMPU 16-bit
  [2] MMPUACXSPI00.WP, [1] MMPUACXSPI00.RP, [0] MMPUACXSPI00.ENABLE
0x87011410 BUSMPU 16-bit
  [2] MMPUACXSPI01.WP, [1] MMPUACXSPI01.RP, [0] MMPUACXSPI01.ENABLE
0x87011420 BUSMPU 16-bit
  [2] MMPUACXSPI02.WP, [1] MMPUACXSPI02.RP, [0] MMPUACXSPI02.ENABLE
0x87011430 BUSMPU 16-bit
  [2] MMPUACXSPI03.WP, [1] MMPUACXSPI03.RP, [0] MMPUACXSPI03.ENABLE
0x87011500 BUSMPU 16-bit
  [15:8] MMPUENXSPI1.KEY, [0] MMPUENXSPI1.ENABLE
0x87011504 BUSMPU 16-bit
  [15:8] MMPUENPTXSPI1.KEY, [0] MMPUENPTXSPI1.PROTECT
0x87011508 BUSMPU 16-bit
  [15:8] MMPURPTXSPI1.KEY, [0] MMPURPTXSPI1.PROTECT
0x87011600 BUSMPU 16-bit
  [2] MMPUACXSPI10.WP, [1] MMPUACXSPI10.RP, [0] MMPUACXSPI10.ENABLE
0x87011610 BUSMPU 16-bit
  [2] MMPUACXSPI11.WP, [1] MMPUACXSPI11.RP, [0] MMPUACXSPI11.ENABLE
0x87011620 BUSMPU 16-bit
  [2] MMPUACXSPI12.WP, [1] MMPUACXSPI12.RP, [0] MMPUACXSPI12.ENABLE
0x87011630 BUSMPU 16-bit
  [2] MMPUACXSPI13.WP, [1] MMPUACXSPI13.RP, [0] MMPUACXSPI13.ENABLE
0x87018010 CPSCU
  [8] SRAMSAR.SRAMWTSA, [1] SRAMSAR.SRAMSA1, [0] SRAMSAR.SRAMSA0
0x87018030 CPSCU
  [0] DTCSAR.DTCSTSA0
0x87018034 CPSCU
  [0] DMACSAR.DMASTSA0
0x87018038 CPSCU
  [0] EDMACSAR.DMAXSTSA0
0x87018040 CPSCU
  [n] ICUSARA.SAIRQCR{n} (n=0..31)
0x87018044 CPSCU
  [1] ICUSARB.SANMI0, [0] ICUSARB.SANMI
0x87018048 CPSCU
  [1] ICUSARC.SACLPCR0, [0] ICUSARC.SAFIR0
0x8701804C CPSCU
  [12] ICUSARD.SAMEWE, [11] ICUSARD.SAMDWE, [10] ICUSARD.SAMCWE, [9] ICUSARD.SAMEEE, [8] ICUSARD.SAMCEE, [3] ICUSARD.SAHLDTO, [2] ICUSARD.SACM, [1] ICUSARD.SALM, [0] ICUSARD.SAFPU
0x870180A0 CPSCU
  [n] ICU0SARA.SAIR{n} (n=0..31)
0x870180A4 CPSCU
  [n] ICU0SARB.SAIR{n} (n=0..31)
0x870180A8 CPSCU
  [n] ICU0SARC.SAIR{n} (n=0..31)
0x870180AC CPSCU
  [n] ICU0SARD.SAIR{n} (n=0..31)
0x870180B0 CPSCU
  [n] ICU0SARE.SAIR{n} (n=0..31)
0x870180B4 CPSCU
  [n] ICU0SARF.SAIR{n} (n=0..31)
0x870180B8 CPSCU
  [n] ICU0SARG.SAIR{n} (n=0..31)
0x870180BC CPSCU
  [n] ICU0SARH.SAIR{n} (n=0..31)
0x87018100 CPSCU
  [0] BUSSARA.BUSSA0
0x87018104 CPSCU
  [0] BUSSARB.BUSSB0
0x87018110 CPSCU
  [0] BUSSARC.BUSSC0
0x87018134 CPSCU
  [8] MMPUSARB.MMPUBSA8
0x87018140 CPSCU
  [0] TFUSAR.TFUSA
0x87018144 CPSCU
  [0] IFUSAR.IFUSA
0x8701819C CPSCU
  [1] EDMACCHSAR.SADMACX01, [0] EDMACCHSAR.SADMACX00
0x870181A0 CPSCU
  [n] DMACCHSAR.SADMAC{n:03} (n=0..7)
0x87018500 CPSCU
  [2] CACHESAR.CACHEESA, [0] CACHESAR.CACHESA
0x87018504 CPSCU
  [0] LRMSAR.LRMSA
0x87018508 CPSCU
  [18:13] LRMSABAR0.LRMSABA
0x8701850C CPSCU
  [18:13] LRMSABAR1.LRMSABA
0x87018600 CPSCU
  [1] TEVTRCR.TEVTEICU0, [0] TEVTRCR.TEVTE
0x87018604 CPSCU
  [0] ICUNSACR.NSACE
0x87018620 CPSCU
  [0] PRTZCR.PRTZC
0x87019006 SYSC 16-bit
  [15:8] SYSCR0.KEY, [0] SYSCR0.ROME
0x8701900C SYSC 8-bit
  [6] SBYCR.OPE
0x8701900E SYSC 8-bit
  [0] SSCR2.SS2RSF
0x87019014 SYSC 8-bit
  [4] VSCR.VSCMTSF, [2:0] VSCR.VSCM
0x87019020 SYSC
  [31:28] SCKDIVCR.MRPCK, [27:24] SCKDIVCR.ICK, [23:20] SCKDIVCR.PCKE, [19:16] SCKDIVCR.BCK, [15:12] SCKDIVCR.PCKA, [11:8] SCKDIVCR.PCKB, [7:4] SCKDIVCR.PCKC, [3:0] SCKDIVCR.PCKD
0x87019024 SYSC 16-bit
  [15:12] SCKDIVCR2.MRICK, [3:0] SCKDIVCR2.CPUCK0
0x87019026 SYSC 8-bit
  [2:0] SCKSCR.CKSEL
0x8701902A SYSC 8-bit
  [0] PLLCR.PLLSTP
0x87019030 SYSC 8-bit
  [7] BCKCR.EBCKASEL, [0] BCKCR.BCLKDIV
0x87019032 SYSC 8-bit
  [0] MOSCCR.MOSTP
0x87019036 SYSC 8-bit
  [0] HOCOCR.HCSTP
0x87019038 SYSC 8-bit
  [0] MOCOCR.MCSTP
0x87019039 SYSC 8-bit
  [0] FLLCR1.FLLEN
0x8701903A SYSC 16-bit
  [10:0] FLLCR2.FLLCNTL
0x8701903C SYSC 8-bit
  [6] OSCSF.PLL2SF, [5] OSCSF.PLLSF, [3] OSCSF.MOSCSF, [0] OSCSF.HOCOSF
0x8701903E SYSC 8-bit
  [7] CKOCR.CKOEN, [6:4] CKOCR.CKODIV, [2:0] CKOCR.CKOSEL
0x87019040 SYSC 8-bit
  [7] OSTDCR.OSTDE, [0] OSTDCR.OSTDIE
0x87019041 SYSC 8-bit
  [0] OSTDSR.OSTDF
0x87019043 SYSC 8-bit
  [2] OSCMONR.LOCOMON, [1] OSCMONR.MOCOMON
0x8701904A SYSC 8-bit
  [0] PLL2CR.PLL2STP
0x8701904C SYSC 16-bit
  [11:8] PLLCCR2.PLODIVR, [7:4] PLLCCR2.PLODIVQ, [3:0] PLLCCR2.PLODIVP
0x8701904E SYSC 16-bit
  [11:8] PLL2CCR2.PL2ODIVR, [7:4] PLL2CCR2.PL2ODIVQ, [3:0] PLL2CCR2.PL2ODIVP
0x87019052 SYSC 8-bit
  [0] EBCKOCR.EBCKOEN
0x87019053 SYSC 8-bit
  [0] SDCKOCR.SDCKOEN
0x87019054 SYSC 8-bit
  [3:0] SCICKDIVCR.SCICKDIV
0x87019055 SYSC 8-bit
  [7] SCICKCR.SCICKSRDY, [6] SCICKCR.SCICKSREQ, [3:0] SCICKCR.SCICKSEL
0x87019056 SYSC 8-bit
  [3:0] SPICKDIVCR.SPICKDIV
0x87019057 SYSC 8-bit
  [7] SPICKCR.SPICKSRDY, [6] SPICKCR.SPICKSREQ, [3:0] SPICKCR.SPICKSEL
0x8701905A SYSC 8-bit
  [3:0] ADCCKDIVCR.ADCCKDIV
0x8701905B SYSC 8-bit
  [7] ADCCKCR.ADCCKSRDY, [6] ADCCKCR.ADCCKSREQ, [3:0] ADCCKCR.ADCCKSEL
0x8701905C SYSC 8-bit
  [3:0] GPTCKDIVCR.GPTCKDIV
0x8701905D SYSC 8-bit
  [7] GPTCKCR.GPTCKSRDY, [6] GPTCKCR.GPTCKSREQ, [3:0] GPTCKCR.GPTCKSEL
0x87019061 SYSC 8-bit
  [7:0] MOCOUTCR.MOCOUTRM
0x87019062 SYSC 8-bit
  [7:0] HOCOUTCR.HOCOUTRM
0x8701906C SYSC 8-bit
  [3:0] USBCKDIVCR.USBCKDIV
0x8701906D SYSC 8-bit
  [3:0] OCTACKDIVCR.OCTACKDIV
0x8701906E SYSC 8-bit
  [3:0] CANFDCKDIVCR.CANFDCKDIV
0x8701906F SYSC 8-bit
  [3:0] USB60CKDIVCR.USB60CKDIV
0x87019070 SYSC 8-bit
  [3:0] I3CCKDIVCR.I3CCKDIV
0x87019074 SYSC 8-bit
  [7] USBCKCR.USBCKSRDY, [6] USBCKCR.USBCKSREQ, [3:0] USBCKCR.USBCKSEL
0x87019075 SYSC 8-bit
  [7] OCTACKCR.OCTACKSRDY, [6] OCTACKCR.OCTACKSREQ, [3:0] OCTACKCR.OCTACKSEL
0x87019076 SYSC 8-bit
  [7] CANFDCKCR.CANFDCKSRDY, [6] CANFDCKCR.CANFDCKSREQ, [3:0] CANFDCKCR.CANFDCKSEL
0x87019077 SYSC 8-bit
  [7] USB60CKCR.USB60CKSRDY, [6] USB60CKCR.USB60CKSREQ, [3:0] USB60CKCR.USB60CKSEL
0x87019078 SYSC 8-bit
  [7] I3CCKCR.I3CCKSRDY, [6] I3CCKCR.I3CCKREQ, [3:0] I3CCKCR.I3CCKSEL
0x8701907C SYSC 8-bit
  [0] MOSCSCR.MOSCSOKP
0x8701907D SYSC 8-bit
  [0] HOCOSCR.HOCOSOKP
0x87019084 SYSC 8-bit
  [0] MOCOSCR.MOCOSOKP
0x870190A0 SYSC 8-bit
  [4] OPCCR.OPCMTSF, [1:0] OPCCR.OPCM
0x870190A2 SYSC 8-bit
  [3:0] MOSCWTCR.MSTS
0x870190AC SYSC
  [16:8] PLLCCR.PLLMUL, [7:6] PLLCCR.PLLMULNF, [4] PLLCCR.PLSRCSEL, [1:0] PLLCCR.PLIDIV
0x870190B0 SYSC 16-bit
  [15:0] SWRR.SWRR
0x870190C0 SYSC
  [14] RSTSR1.CMRF, [10] RSTSR1.BUSRF, [5] RSTSR1.LM0RF, [2] RSTSR1.SWRF, [1] RSTSR1.WDT0RF, [0] RSTSR1.IWDTRF
0x870190C8 SYSC
  [16:8] PLL2CCR.PLL2MUL, [7:6] PLL2CCR.PLL2MULNF, [4] PLL2CCR.PL2SRCSEL, [1:0] PLL2CCR.PL2IDIV
0x870190CC SYSC 8-bit
  [0] SYRACCR.BUSY
0x870190D4 SYSC 8-bit
  [3:0] BCKADIVCR.BCKACKDIV
0x870190D5 SYSC 8-bit
  [3:0] ESWCKDIVCR.ESWCKDIV
0x870190D6 SYSC 8-bit
  [3:0] ESWPCKDIVCR.ESWPCKDIV
0x870190D7 SYSC 8-bit
  [3:0] ESCCKDIVCR.ESCCKDIV
0x870190D8 SYSC 8-bit
  [3:0] ETHPCKDIVCR.ETHPCKDIV
0x870190D9 SYSC 8-bit
  [3:0] DSMIFCKDIVCR.DSMIFCKDIV
0x870190DA SYSC 8-bit
  [7] BCKACR.BCKACKSRDY, [6] BCKACR.BCKACKSREQ, [3:0] BCKACR.BCKACKSEL
0x870190DB SYSC 8-bit
  [7] ESWCKCR.ESWCKSRDY, [6] ESWCKCR.ESWCKSREQ, [3:0] ESWCKCR.ESWCKSEL
0x870190DC SYSC 8-bit
  [7] ESWPCKCR.ESWPCKSRDY, [6] ESWPCKCR.ESWPCKSREQ, [3:0] ESWPCKCR.ESWPCKSEL
0x870190DD SYSC 8-bit
  [7] ESCCKCR.ESCCKSRDY, [6] ESCCKCR.ESCCKSREQ, [3:0] ESCCKCR.ESCCKSEL
0x870190DE SYSC 8-bit
  [7] ETHPCKCR.ETHPCKSRDY, [6] ETHPCKCR.ETHPCKSREQ, [3:0] ETHPCKCR.ETHPCKSEL
0x870190DF SYSC 8-bit
  [7] DSMIFCKCR.DSMIFCKSRDY, [6] DSMIFCKCR.DSMIFCKSREQ, [3:0] DSMIFCKCR.DSMIFCKSEL
0x870190E0 SYSC 8-bit
  [2] PVD1CR1.IRQSEL, [1:0] PVD1CR1.IDTSEL
0x870190E1 SYSC 8-bit
  [1] PVD1SR.MON, [0] PVD1SR.DET
0x870190E2 SYSC 8-bit
  [2] PVD2CR1.IRQSEL, [1:0] PVD2CR1.IDTSEL
0x870190E3 SYSC 8-bit
  [1] PVD2SR.MON, [0] PVD2SR.DET
0x87019100 SYSC 8-bit
  [0] CPUDSCR.PGD0
0x87019118 SYSC 8-bit
  [7] PDCTRESWM.PDPGSF, [6] PDCTRESWM.PDCSF, [0] PDCTRESWM.PDDE
0x87019140 SYSC 16-bit
  [n] PDRAMSCR0.RKEEP{n} (n=0..11)
0x87019143 SYSC 8-bit
  [0] PDRAMSCR2.RKEEP0
0x870193B0 SYSC 16-bit
  [15:0] VBRSABAR.SABA
0x870193C0 SYSC
  [29] CGFSAR.NONSEC29, [28] CGFSAR.NONSEC28, [27] CGFSAR.NONSEC27, [25] CGFSAR.NONSEC25, [24] CGFSAR.NONSEC24, [n] CGFSAR.NONSEC{n} (n=16..22), [n] CGFSAR.NONSEC{n:02} (n=2..14), [0] CGFSAR.NONSEC00
0x870193C4 SYSC
  [5] RSTSAR.NONSEC5, [n] RSTSAR.NONSEC{n} (n=0..3)
0x870193C8 SYSC
  [21] LPMSAR.NONSEC21, [19] LPMSAR.NONSEC19, [18] LPMSAR.NONSEC18, [17] LPMSAR.NONSEC17, [8] LPMSAR.NONSEC8, [4] LPMSAR.NONSEC4, [2] LPMSAR.NONSEC2, [1] LPMSAR.NONSEC1, [0] LPMSAR.NONSEC0
0x870193CC SYSC
  [1] PVDSAR.NONSEC1, [0] PVDSAR.NONSEC0
0x870193D0 SYSC
  [n] BBFSAR.NONSEC{n} (n=0..6)
0x870193D4 SYSC 16-bit
  [8] MDSAR.NONSEC8
0x870193D8 SYSC
  [7] PGCSAR.NONSEC7, [6] PGCSAR.NONSEC6
0x870193E0 SYSC
  [31] DPFSAR.DFPSA31, [30] DPFSAR.DPFSA30, [29] DPFSAR.DPFSA29, [25] DPFSAR.DPFSA25, [24] DPFSAR.DPFSA24, [n] DPFSAR.DPFSA{n} (n=0..20)
0x870193E4 SYSC
  [25] RSCSAR.RSCSA25, [24] RSCSAR.RSCSA24, [n] RSCSAR.RSCSA{n} (n=0..14)
0x870193E8 SYSC
  [n] DPFSAR1.DPFSA{n} (n=0..15)
0x870193FA SYSC 16-bit
  [15:8] PRCR_S.PRKEY, [5] PRCR_S.PRC5, [4] PRCR_S.PRC4, [3] PRCR_S.PRC3, [1] PRCR_S.PRC1, [0] PRCR_S.PRC0
0x87019400 SYSC 8-bit
  [0] LOCOCR.LCSTP
0x87019402 SYSC 8-bit
  [7:0] LOCOUTCR.LOCOUTRM
0x87019A00 SYSC 8-bit
  [6] DPSBYCR.IOKEEP, [3:2] DPSBYCR.DCSSMODE, [1:0] DPSBYCR.LDOSSMODE
0x87019A08 SYSC 8-bit
  [n] DPSIER0.DIRQ{n}E (n=0..7)
0x87019A0C SYSC 8-bit
  [n-8] DPSIER1.DIRQ{n}E (n=8..15)
0x87019A10 SYSC 8-bit
  [4] DPSIER2.DNMIE, [3] DPSIER2.DRTCAIE, [2] DPSIER2.DRTCIIE, [1] DPSIER2.DPVD2IE, [0] DPSIER2.DPVD1IE
0x87019A14 SYSC 8-bit
  [7] DPSIER3.DVBATTADIE, [6] DPSIER3.DSOSTDIE, [5] DPSIER3.DIWDTIE, [1] DPSIER3.DUSBHSIE, [0] DPSIER3.DUSBFSIE
0x87019A18 SYSC 8-bit
  [n] DPSIFR0.DIRQ{n}F (n=0..7)
0x87019A1C SYSC 8-bit
  [n-8] DPSIFR1.DIRQ{n}F (n=8..15)
0x87019A20 SYSC 8-bit
  [4] DPSIFR2.DNMIF, [3] DPSIFR2.DRTCAIF, [2] DPSIFR2.DRTCIIF, [1] DPSIFR2.DPVD2IF, [0] DPSIFR2.DPVD1IF
0x87019A24 SYSC 8-bit
  [7] DPSIFR3.DVBATTADIF, [6] DPSIFR3.DSOSTDIF, [5] DPSIFR3.DIWDTIF, [1] DPSIFR3.DUSBHSIF, [0] DPSIFR3.DUSBFSIF
0x87019A28 SYSC 8-bit
  [n] DPSIEGR0.DIRQ{n}EG (n=0..7)
0x87019A2C SYSC 8-bit
  [n-8] DPSIEGR1.DIRQ{n}EG (n=8..15)
0x87019A30 SYSC 8-bit
  [4] DPSIEGR2.DNMIEG, [1] DPSIEGR2.DPVD2EG, [0] DPSIEGR2.DPVD1EG
0x87019A34 SYSC 8-bit
  [n-16] DPSIEGR3.DIRQ{n}EG (n=16..23)
0x87019A40 SYSC 8-bit
  [7] RSTSR0.DPSRSTF, [6] RSTSR0.PVD5RF, [5] RSTSR0.PVD4RF, [3] RSTSR0.PVD2RF, [2] RSTSR0.PVD1RF, [1] RSTSR0.PVD0RF, [0] RSTSR0.PORF
0x87019A44 SYSC 8-bit
  [0] RSTSR2.CWSF
0x87019A48 SYSC 8-bit
  [7] RSTSR3.TEMPRF, [0] RSTSR3.CVMRF
0x87019A50 SYSC 8-bit
  [6] MOMCR.MOSEL, [3:1] MOMCR.MODRV0
0x87019A58 SYSC 8-bit
  [7] PVD1CMPCR.PVDE, [4:0] PVD1CMPCR.PVDLVL
0x87019A5C SYSC 8-bit
  [7] PVD2CMPCR.PVDE, [4:0] PVD2CMPCR.PVDLVL
0x87019A64 SYSC 8-bit
  [7] PVD4CMPCR.PVDE, [4:0] PVD4CMPCR.PVDLVL
0x87019A68 SYSC 8-bit
  [7] PVD5CMPCR.PVDE, [4:0] PVD5CMPCR.PVDLVL
0x87019A70 SYSC 8-bit
  [7] PVD1CR0.RN, [6] PVD1CR0.RI, [5:4] PVD1CR0.FSAMP, [2] PVD1CR0.CMPE, [1] PVD1CR0.DFDIS, [0] PVD1CR0.RIE
0x87019A74 SYSC 8-bit
  [7] PVD2CR0.RN, [6] PVD2CR0.RI, [5:4] PVD2CR0.FSAMP, [2] PVD2CR0.CMPE, [1] PVD2CR0.DFDIS, [0] PVD2CR0.RIE
0x87019A7C SYSC 8-bit
  [5:4] PVD4CR0.FSAMP, [2] PVD4CR0.CMPE, [1] PVD4CR0.DFDIS, [0] PVD4CR0.RE
0x87019A80 SYSC 8-bit
  [5:4] PVD5CR0.FSAMP, [2] PVD5CR0.CMPE, [1] PVD5CR0.DFDIS, [0] PVD5CR0.RE
0x87019A84 SYSC 8-bit
  [0] VBATTMNSELR.VBATTMNSEL
0x87019A88 SYSC 8-bit
  [0] VBTBPCR1.BPWSWSTP
0x87019A90 SYSC 8-bit
  [3:0] LPSCR.LPMD
0x87019A98 SYSC 8-bit
  [3:2] SSCR1.SS2LP, [0] SSCR1.SS2FR
0x87019A9C SYSC 8-bit
  [2:0] SVSCR.SVSCM
0x87019AB0 SYSC 8-bit
  [0] LVOCR.LVO0E
0x87019AB4 SYSC 8-bit
  [1:0] MWMCR.MWM
0x87019AB8 SYSC 8-bit
  [7:1] DCCR.WCODE, [0] DCCR.DSTBYCON
0x87019AD0 SYSC 8-bit
  [7] SYRSTMSK0.BUSMASK, [6] SYRSTMSK0.CMMASK, [5] SYRSTMSK0.LM0MASK, [2] SYRSTMSK0.SWMASK, [1] SYRSTMSK0.WDT0MASK, [0] SYRSTMSK0.IWDTMASK
0x87019AD8 SYSC 8-bit
  [1] SYRSTMSK2.PVD2MASK, [0] SYRSTMSK2.PVD1MASK
0x87019ADC SYSC 8-bit
  [3] TEMPRCR.TSNKEEP, [2] TEMPRCR.CMPEN, [1] TEMPRCR.TSNEN, [0] TEMPRCR.TEMPREN
0x87019AE0 SYSC 8-bit
  [0] TEMPRLR.LOCK
0x87019AF4 SYSC 8-bit
  [7] LDOECR.EFUPTSF, [0] LDOECR.EFUPE
0x87019B04 SYSC 8-bit
  [1] PLL1LDOCR.SKEEP, [0] PLL1LDOCR.LDOSTP
0x87019B08 SYSC 8-bit
  [1] PLL2LDOCR.SKEEP, [0] PLL2LDOCR.LDOSTP
0x87019B0C SYSC 8-bit
  [1] HOCOLDOCR.SKEEP, [0] HOCOLDOCR.LDOSTP
0x87019B20 SYSC 8-bit
  [0] PVD1FCR.RHSEL
0x87019B24 SYSC 8-bit
  [0] PVD2FCR.RHSEL
0x87019B2C SYSC 8-bit
  [0] PVD4FCR.RHSEL
0x87019B30 SYSC 8-bit
  [0] PVD5FCR.RHSEL
0x87019B34 SYSC 8-bit
  [0] PVDLR.LOCK
0x87019B40 SYSC 8-bit
  [n-16] DPSIER4.DIRQ{n}E (n=16..23)
0x87019B44 SYSC 8-bit
  [n-24] DPSIER5.DIRQ{n}E (n=24..31)
0x87019B48 SYSC 8-bit
  [n-16] DPSIFR4.DIRQ{n}F (n=16..23)
0x87019B4C SYSC 8-bit
  [n-24] DPSIFR5.DIRQ{n}F (n=24..31)
0x87019B50 SYSC 8-bit
  [n-24] DPSIEGR4.DIRQ{n}EG (n=24..31)
0x87019B78 SYSC 8-bit
  [6] ROUTSR0.ROPVD5RF, [5] ROUTSR0.ROPVD4RF, [3] ROUTSR0.ROPVD2RF, [2] ROUTSR0.ROPVD1RF, [1] ROUTSR0.ROPVD0RF
0x87019B7C SYSC
  [14] ROUTSR1.ROCMRF, [10] ROUTSR1.ROBUSRF, [5] ROUTSR1.ROLM0RF, [2] ROUTSR1.ROSWRF, [1] ROUTSR1.ROWDT0RF, [0] ROUTSR1.ROIWDTRF
0x87019B80 SYSC 8-bit
  [7] ROUTSR2.ROTEMPRF, [0] ROUTSR2.ROCVMRF
0x87019C00 SYSC 8-bit
  [0] SOSCCR.SOSTP
0x87019C01 SYSC 8-bit
  [6] SOMCR.SOSEL, [1:0] SOMCR.SODRV
0x87019C04 SYSC 8-bit
  [7] SOSTDCR.SOSTDE, [0] SOSTDCR.SOSTDIE
0x87019C05 SYSC 8-bit
  [0] SOSTDSR.SOSTDF
0x87019C40 SYSC 8-bit
  [3] VBTBER.VBAE
0x87019C45 SYSC 8-bit
  [4] VBTBPCR2.VDETE, [2:0] VBTBPCR2.VDETLVL
0x87019C46 SYSC 8-bit
  [5] VBTBPSR.BPWSWM, [4] VBTBPSR.VBPORM, [0] VBTBPSR.VBPORF
0x87019C48 SYSC 8-bit
  [2] VBTADSR.VBTADF2, [1] VBTADSR.VBTADF1, [0] VBTADSR.VBTADF0
0x87019C49 SYSC 8-bit
  [6] VBTADCR1.VBTADCE2, [5] VBTADCR1.VBTADCE1, [4] VBTADCR1.VBTADCE0, [2] VBTADCR1.VBTADIE2, [1] VBTADCR1.VBTADIE1, [0] VBTADCR1.VBTADIE0
0x87019C4A SYSC 8-bit
  [2] VBTADCR2.VBRTCES2, [1] VBTADCR2.VBRTCES1, [0] VBTADCR2.VBRTCES0
0x87019C4C SYSC 8-bit
  [2] VBTICTLR.VCH2INEN, [1] VBTICTLR.VCH1INEN, [0] VBTICTLR.VCH0INEN
0x87019C4D SYSC 8-bit
  [6] VBTICTLR2.VCH2EG, [5] VBTICTLR2.VCH1EG, [4] VBTICTLR2.VCH0EG, [2] VBTICTLR2.VCH2NCE, [1] VBTICTLR2.VCH1NCE, [0] VBTICTLR2.VCH0NCE
0x87019C4E SYSC 8-bit
  [2] VBTIMONR.VCH2MON, [1] VBTIMONR.VCH1MON, [0] VBTIMONR.VCH0MON
0x87019C50 SYSC 8-bit
  [2:0] VBTNCWCR.VINCW
0x87019C54 SYSC 8-bit
  [2] VBTADCR3.VBTADZE2, [1] VBTADCR3.VBTADZE1, [0] VBTADCR3.VBTADZE0
# iorx74m register map
Registers are 32-bit, access not given, no defined reset value unless marked. A register's access mark holds for its fields unless they carry their own. Addresses are absolute; registers are grouped by the start of their names; [hi:lo] are bit positions; {n}, {i} and the like mark numbered series.

## SFR (part 3 of 10)
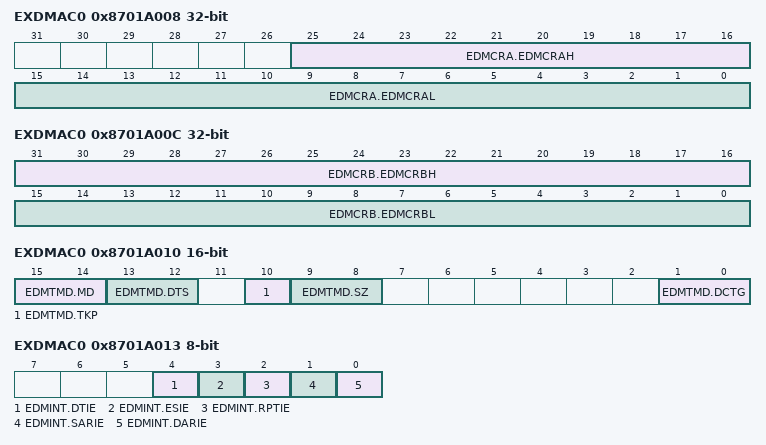
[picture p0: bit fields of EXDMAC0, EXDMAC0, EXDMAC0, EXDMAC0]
0x8701A008 EXDMAC0
  [25:16] EDMCRA.EDMCRAH, [15:0] EDMCRA.EDMCRAL
0x8701A00C EXDMAC0
  [31:16] EDMCRB.EDMCRBH, [15:0] EDMCRB.EDMCRBL
0x8701A010 EXDMAC0 16-bit
  [15:14] EDMTMD.MD, [13:12] EDMTMD.DTS, [10] EDMTMD.TKP, [9:8] EDMTMD.SZ, [1:0] EDMTMD.DCTG
0x8701A013 EXDMAC0 8-bit
  [4] EDMINT.DTIE, [3] EDMINT.ESIE, [2] EDMINT.RPTIE, [1] EDMINT.SARIE, [0] EDMINT.DARIE
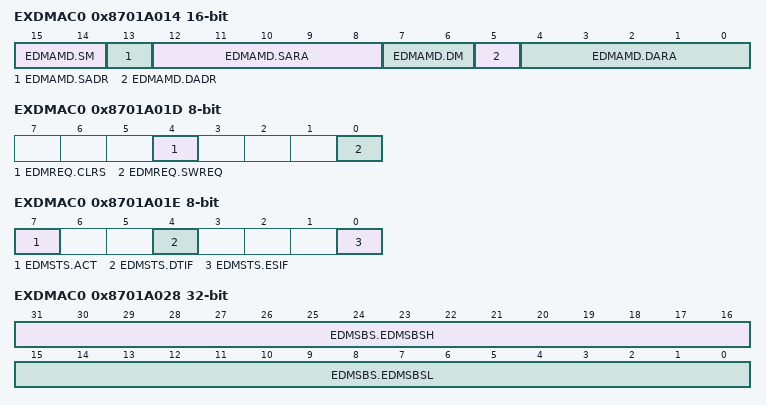
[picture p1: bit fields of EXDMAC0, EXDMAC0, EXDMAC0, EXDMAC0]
0x8701A014 EXDMAC0 16-bit
  [15:14] EDMAMD.SM, [13] EDMAMD.SADR, [12:8] EDMAMD.SARA, [7:6] EDMAMD.DM, [5] EDMAMD.DADR, [4:0] EDMAMD.DARA
0x8701A01C EXDMAC0 8-bit
  [0] EDMCNT.DTE
0x8701A01D EXDMAC0 8-bit
  [4] EDMREQ.CLRS, [0] EDMREQ.SWREQ
0x8701A01E EXDMAC0 8-bit
  [7] EDMSTS.ACT, [4] EDMSTS.DTIF, [0] EDMSTS.ESIF
0x8701A028 EXDMAC0
  [31:16] EDMSBS.EDMSBSH, [15:0] EDMSBS.EDMSBSL
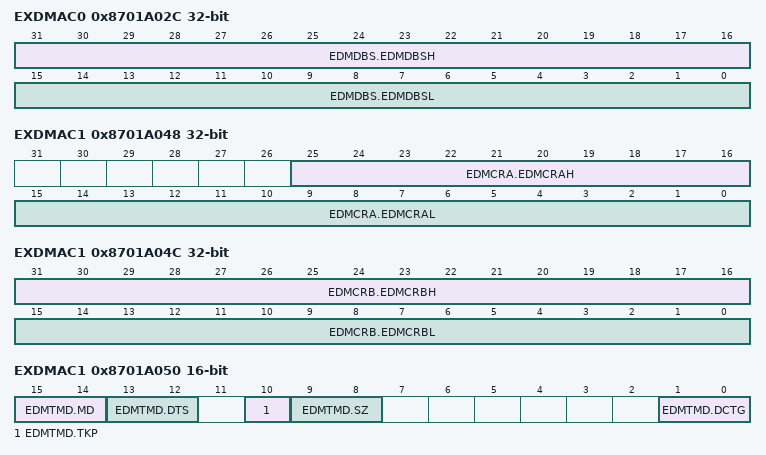
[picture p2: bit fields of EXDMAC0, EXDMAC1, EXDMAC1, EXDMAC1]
0x8701A02C EXDMAC0
  [31:16] EDMDBS.EDMDBSH, [15:0] EDMDBS.EDMDBSL
0x8701A030 EXDMAC0 8-bit
  [0] EDMBWR.BWE
0x8701A03E EXDMAC0 8-bit
  [0] EDMPRF.PREQ
0x8701A048 EXDMAC1
  [25:16] EDMCRA.EDMCRAH, [15:0] EDMCRA.EDMCRAL
0x8701A04C EXDMAC1
  [31:16] EDMCRB.EDMCRBH, [15:0] EDMCRB.EDMCRBL
0x8701A050 EXDMAC1 16-bit
  [15:14] EDMTMD.MD, [13:12] EDMTMD.DTS, [10] EDMTMD.TKP, [9:8] EDMTMD.SZ, [1:0] EDMTMD.DCTG
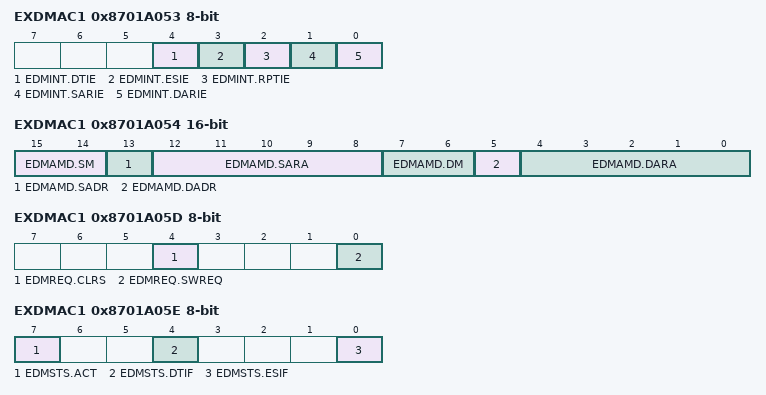
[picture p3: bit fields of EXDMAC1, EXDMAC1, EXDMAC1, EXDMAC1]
0x8701A053 EXDMAC1 8-bit
  [4] EDMINT.DTIE, [3] EDMINT.ESIE, [2] EDMINT.RPTIE, [1] EDMINT.SARIE, [0] EDMINT.DARIE
0x8701A054 EXDMAC1 16-bit
  [15:14] EDMAMD.SM, [13] EDMAMD.SADR, [12:8] EDMAMD.SARA, [7:6] EDMAMD.DM, [5] EDMAMD.DADR, [4:0] EDMAMD.DARA
0x8701A05C EXDMAC1 8-bit
  [0] EDMCNT.DTE
0x8701A05D EXDMAC1 8-bit
  [4] EDMREQ.CLRS, [0] EDMREQ.SWREQ
0x8701A05E EXDMAC1 8-bit
  [7] EDMSTS.ACT, [4] EDMSTS.DTIF, [0] EDMSTS.ESIF
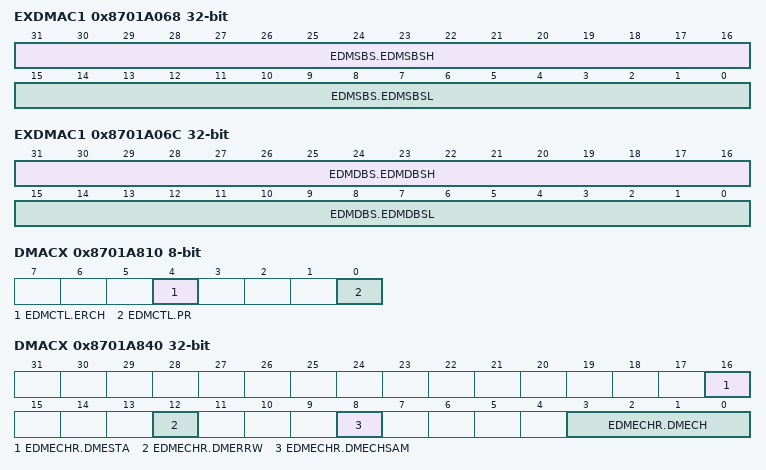
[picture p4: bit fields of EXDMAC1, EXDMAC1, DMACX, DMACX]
0x8701A068 EXDMAC1
  [31:16] EDMSBS.EDMSBSH, [15:0] EDMSBS.EDMSBSL
0x8701A06C EXDMAC1
  [31:16] EDMDBS.EDMDBSH, [15:0] EDMDBS.EDMDBSL
0x8701A070 EXDMAC1 8-bit
  [0] EDMBWR.BWE
0x8701A07E EXDMAC1 8-bit
  [0] EDMPRF.PREQ
0x8701A800 DMACX 8-bit
  [0] EDMAST.DMST
0x8701A810 DMACX 8-bit
  [4] EDMCTL.ERCH, [0] EDMCTL.PR
0x8701A840 DMACX
  [16] EDMECHR.DMESTA, [12] EDMECHR.DMERRW, [8] EDMECHR.DMECHSAM, [3:0] EDMECHR.DMECH
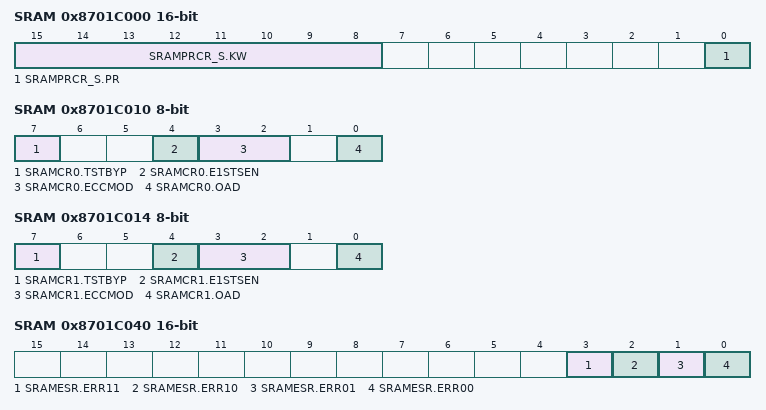
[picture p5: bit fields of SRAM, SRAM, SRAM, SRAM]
0x8701C000 SRAM 16-bit
  [15:8] SRAMPRCR_S.KW, [0] SRAMPRCR_S.PR
0x8701C008 SRAM 8-bit
  [0] SRAMWTSC.WTEN
0x8701C010 SRAM 8-bit
  [7] SRAMCR0.TSTBYP, [4] SRAMCR0.E1STSEN, [3:2] SRAMCR0.ECCMOD, [0] SRAMCR0.OAD
0x8701C014 SRAM 8-bit
  [7] SRAMCR1.TSTBYP, [4] SRAMCR1.E1STSEN, [3:2] SRAMCR1.ECCMOD, [0] SRAMCR1.OAD
0x8701C030 SRAM 8-bit
  [3:0] SRAMECCRGN0.ECCRGN
0x8701C034 SRAM 8-bit
  [3:0] SRAMECCRGN1.ECCRGN
0x8701C040 SRAM 16-bit
  [3] SRAMESR.ERR11, [2] SRAMESR.ERR10, [1] SRAMESR.ERR01, [0] SRAMESR.ERR00
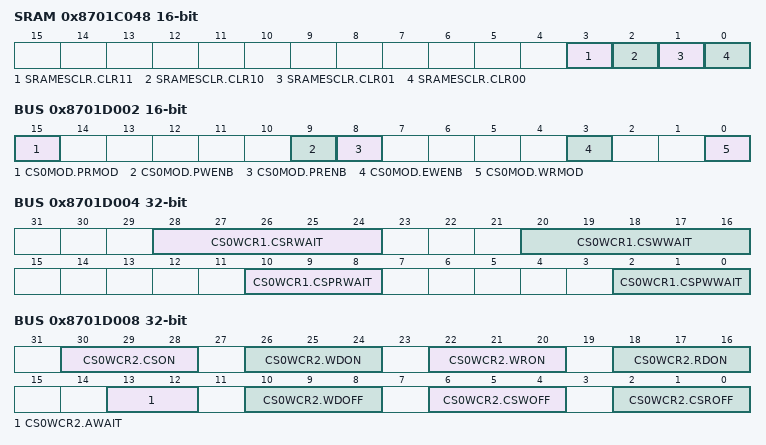
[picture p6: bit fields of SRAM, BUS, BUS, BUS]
0x8701C048 SRAM 16-bit
  [3] SRAMESCLR.CLR11, [2] SRAMESCLR.CLR10, [1] SRAMESCLR.CLR01, [0] SRAMESCLR.CLR00
0x8701D002 BUS 16-bit
  [15] CS0MOD.PRMOD, [9] CS0MOD.PWENB, [8] CS0MOD.PRENB, [3] CS0MOD.EWENB, [0] CS0MOD.WRMOD
0x8701D004 BUS
  [28:24] CS0WCR1.CSRWAIT, [20:16] CS0WCR1.CSWWAIT, [10:8] CS0WCR1.CSPRWAIT, [2:0] CS0WCR1.CSPWWAIT
0x8701D008 BUS
  [30:28] CS0WCR2.CSON, [26:24] CS0WCR2.WDON, [22:20] CS0WCR2.WRON, [18:16] CS0WCR2.RDON, [13:12] CS0WCR2.AWAIT, [10:8] CS0WCR2.WDOFF, [6:4] CS0WCR2.CSWOFF, [2:0] CS0WCR2.CSROFF
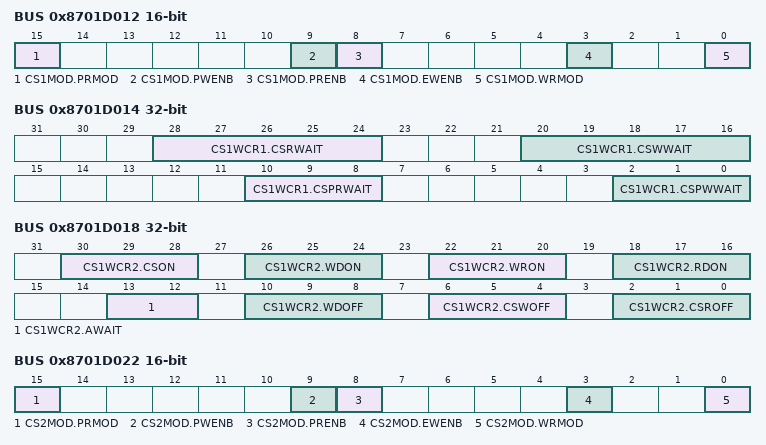
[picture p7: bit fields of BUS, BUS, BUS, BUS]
0x8701D012 BUS 16-bit
  [15] CS1MOD.PRMOD, [9] CS1MOD.PWENB, [8] CS1MOD.PRENB, [3] CS1MOD.EWENB, [0] CS1MOD.WRMOD
0x8701D014 BUS
  [28:24] CS1WCR1.CSRWAIT, [20:16] CS1WCR1.CSWWAIT, [10:8] CS1WCR1.CSPRWAIT, [2:0] CS1WCR1.CSPWWAIT
0x8701D018 BUS
  [30:28] CS1WCR2.CSON, [26:24] CS1WCR2.WDON, [22:20] CS1WCR2.WRON, [18:16] CS1WCR2.RDON, [13:12] CS1WCR2.AWAIT, [10:8] CS1WCR2.WDOFF, [6:4] CS1WCR2.CSWOFF, [2:0] CS1WCR2.CSROFF
0x8701D022 BUS 16-bit
  [15] CS2MOD.PRMOD, [9] CS2MOD.PWENB, [8] CS2MOD.PRENB, [3] CS2MOD.EWENB, [0] CS2MOD.WRMOD
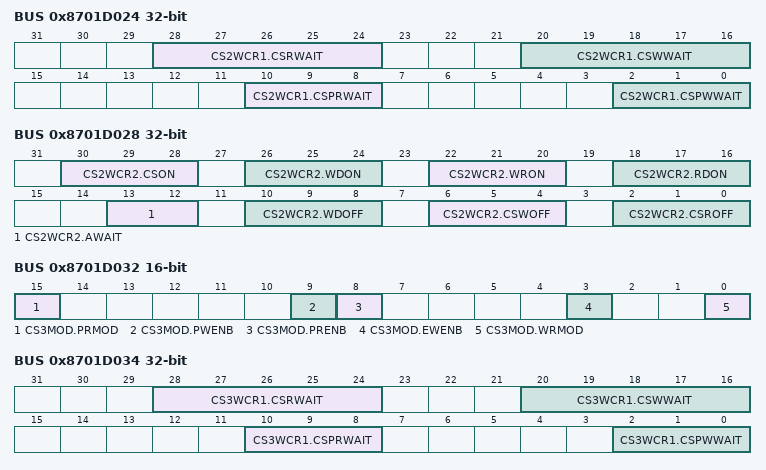
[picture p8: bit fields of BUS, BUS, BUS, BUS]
0x8701D024 BUS
  [28:24] CS2WCR1.CSRWAIT, [20:16] CS2WCR1.CSWWAIT, [10:8] CS2WCR1.CSPRWAIT, [2:0] CS2WCR1.CSPWWAIT
0x8701D028 BUS
  [30:28] CS2WCR2.CSON, [26:24] CS2WCR2.WDON, [22:20] CS2WCR2.WRON, [18:16] CS2WCR2.RDON, [13:12] CS2WCR2.AWAIT, [10:8] CS2WCR2.WDOFF, [6:4] CS2WCR2.CSWOFF, [2:0] CS2WCR2.CSROFF
0x8701D032 BUS 16-bit
  [15] CS3MOD.PRMOD, [9] CS3MOD.PWENB, [8] CS3MOD.PRENB, [3] CS3MOD.EWENB, [0] CS3MOD.WRMOD
0x8701D034 BUS
  [28:24] CS3WCR1.CSRWAIT, [20:16] CS3WCR1.CSWWAIT, [10:8] CS3WCR1.CSPRWAIT, [2:0] CS3WCR1.CSPWWAIT
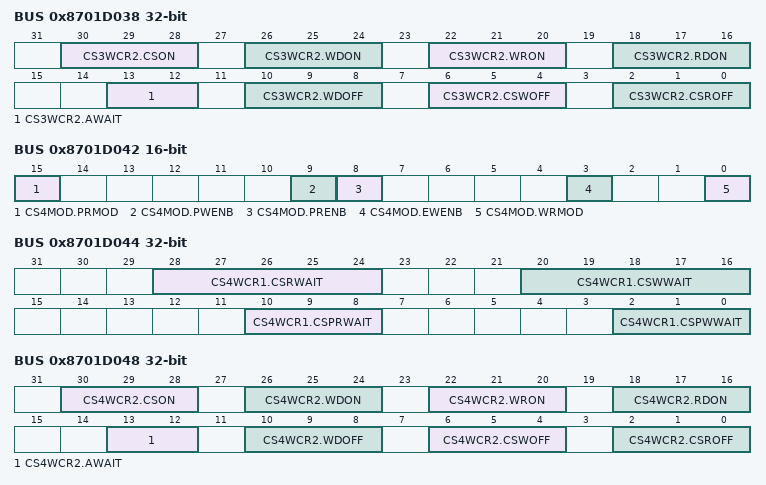
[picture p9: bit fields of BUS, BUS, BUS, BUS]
0x8701D038 BUS
  [30:28] CS3WCR2.CSON, [26:24] CS3WCR2.WDON, [22:20] CS3WCR2.WRON, [18:16] CS3WCR2.RDON, [13:12] CS3WCR2.AWAIT, [10:8] CS3WCR2.WDOFF, [6:4] CS3WCR2.CSWOFF, [2:0] CS3WCR2.CSROFF
0x8701D042 BUS 16-bit
  [15] CS4MOD.PRMOD, [9] CS4MOD.PWENB, [8] CS4MOD.PRENB, [3] CS4MOD.EWENB, [0] CS4MOD.WRMOD
0x8701D044 BUS
  [28:24] CS4WCR1.CSRWAIT, [20:16] CS4WCR1.CSWWAIT, [10:8] CS4WCR1.CSPRWAIT, [2:0] CS4WCR1.CSPWWAIT
0x8701D048 BUS
  [30:28] CS4WCR2.CSON, [26:24] CS4WCR2.WDON, [22:20] CS4WCR2.WRON, [18:16] CS4WCR2.RDON, [13:12] CS4WCR2.AWAIT, [10:8] CS4WCR2.WDOFF, [6:4] CS4WCR2.CSWOFF, [2:0] CS4WCR2.CSROFF
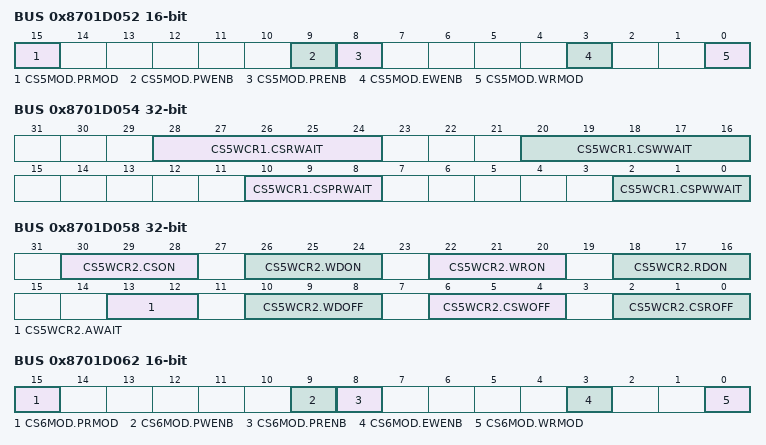
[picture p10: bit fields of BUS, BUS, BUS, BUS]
0x8701D052 BUS 16-bit
  [15] CS5MOD.PRMOD, [9] CS5MOD.PWENB, [8] CS5MOD.PRENB, [3] CS5MOD.EWENB, [0] CS5MOD.WRMOD
0x8701D054 BUS
  [28:24] CS5WCR1.CSRWAIT, [20:16] CS5WCR1.CSWWAIT, [10:8] CS5WCR1.CSPRWAIT, [2:0] CS5WCR1.CSPWWAIT
0x8701D058 BUS
  [30:28] CS5WCR2.CSON, [26:24] CS5WCR2.WDON, [22:20] CS5WCR2.WRON, [18:16] CS5WCR2.RDON, [13:12] CS5WCR2.AWAIT, [10:8] CS5WCR2.WDOFF, [6:4] CS5WCR2.CSWOFF, [2:0] CS5WCR2.CSROFF
0x8701D062 BUS 16-bit
  [15] CS6MOD.PRMOD, [9] CS6MOD.PWENB, [8] CS6MOD.PRENB, [3] CS6MOD.EWENB, [0] CS6MOD.WRMOD
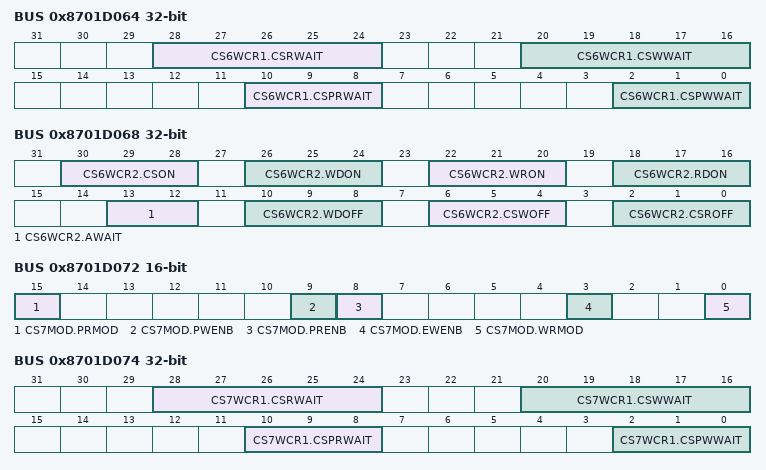
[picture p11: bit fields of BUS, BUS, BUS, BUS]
0x8701D064 BUS
  [28:24] CS6WCR1.CSRWAIT, [20:16] CS6WCR1.CSWWAIT, [10:8] CS6WCR1.CSPRWAIT, [2:0] CS6WCR1.CSPWWAIT
0x8701D068 BUS
  [30:28] CS6WCR2.CSON, [26:24] CS6WCR2.WDON, [22:20] CS6WCR2.WRON, [18:16] CS6WCR2.RDON, [13:12] CS6WCR2.AWAIT, [10:8] CS6WCR2.WDOFF, [6:4] CS6WCR2.CSWOFF, [2:0] CS6WCR2.CSROFF
0x8701D072 BUS 16-bit
  [15] CS7MOD.PRMOD, [9] CS7MOD.PWENB, [8] CS7MOD.PRENB, [3] CS7MOD.EWENB, [0] CS7MOD.WRMOD
0x8701D074 BUS
  [28:24] CS7WCR1.CSRWAIT, [20:16] CS7WCR1.CSWWAIT, [10:8] CS7WCR1.CSPRWAIT, [2:0] CS7WCR1.CSPWWAIT
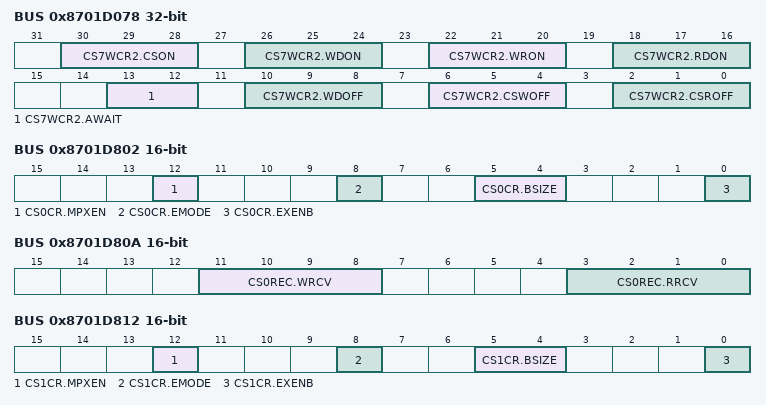
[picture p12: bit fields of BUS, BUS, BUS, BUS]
0x8701D078 BUS
  [30:28] CS7WCR2.CSON, [26:24] CS7WCR2.WDON, [22:20] CS7WCR2.WRON, [18:16] CS7WCR2.RDON, [13:12] CS7WCR2.AWAIT, [10:8] CS7WCR2.WDOFF, [6:4] CS7WCR2.CSWOFF, [2:0] CS7WCR2.CSROFF
0x8701D802 BUS 16-bit
  [12] CS0CR.MPXEN, [8] CS0CR.EMODE, [5:4] CS0CR.BSIZE, [0] CS0CR.EXENB
0x8701D80A BUS 16-bit
  [11:8] CS0REC.WRCV, [3:0] CS0REC.RRCV
0x8701D812 BUS 16-bit
  [12] CS1CR.MPXEN, [8] CS1CR.EMODE, [5:4] CS1CR.BSIZE, [0] CS1CR.EXENB
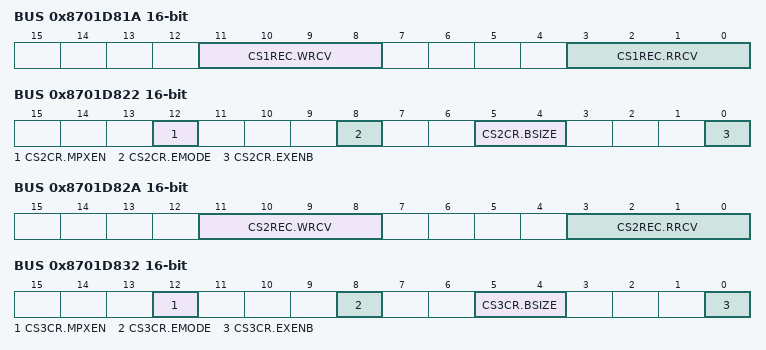
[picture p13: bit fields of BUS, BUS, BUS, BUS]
0x8701D81A BUS 16-bit
  [11:8] CS1REC.WRCV, [3:0] CS1REC.RRCV
0x8701D822 BUS 16-bit
  [12] CS2CR.MPXEN, [8] CS2CR.EMODE, [5:4] CS2CR.BSIZE, [0] CS2CR.EXENB
0x8701D82A BUS 16-bit
  [11:8] CS2REC.WRCV, [3:0] CS2REC.RRCV
0x8701D832 BUS 16-bit
  [12] CS3CR.MPXEN, [8] CS3CR.EMODE, [5:4] CS3CR.BSIZE, [0] CS3CR.EXENB
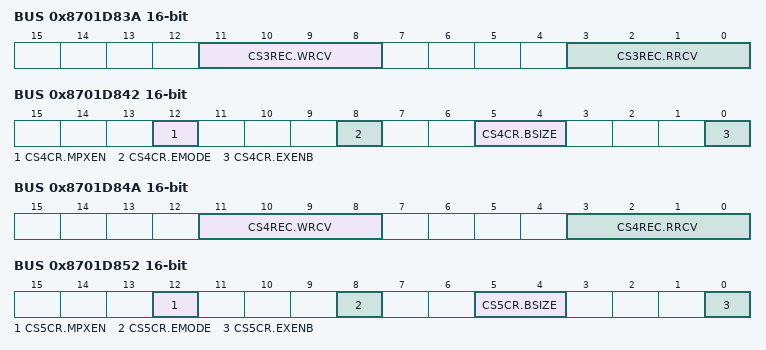
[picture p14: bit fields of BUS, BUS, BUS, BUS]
0x8701D83A BUS 16-bit
  [11:8] CS3REC.WRCV, [3:0] CS3REC.RRCV
0x8701D842 BUS 16-bit
  [12] CS4CR.MPXEN, [8] CS4CR.EMODE, [5:4] CS4CR.BSIZE, [0] CS4CR.EXENB
0x8701D84A BUS 16-bit
  [11:8] CS4REC.WRCV, [3:0] CS4REC.RRCV
0x8701D852 BUS 16-bit
  [12] CS5CR.MPXEN, [8] CS5CR.EMODE, [5:4] CS5CR.BSIZE, [0] CS5CR.EXENB
0x8701D85A BUS 16-bit
  [11:8] CS5REC.WRCV, [3:0] CS5REC.RRCV
0x8701D862 BUS 16-bit
  [12] CS6CR.MPXEN, [8] CS6CR.EMODE, [5:4] CS6CR.BSIZE, [0] CS6CR.EXENB
0x8701D86A BUS 16-bit
  [11:8] CS6REC.WRCV, [3:0] CS6REC.RRCV
0x8701D872 BUS 16-bit
  [12] CS7CR.MPXEN, [8] CS7CR.EMODE, [5:4] CS7CR.BSIZE, [0] CS7CR.EXENB
0x8701D87A BUS 16-bit
  [11:8] CS7REC.WRCV, [3:0] CS7REC.RRCV
0x8701D880 BUS 16-bit
  [n+8] CSRECEN.RCVENM{n} (n=0..7), [n] CSRECEN.RCVEN{n} (n=0..7)
0x8701D8A0 BUS 8-bit
  [2] EXBERR.BCAN, [1] EXBERR.HLDTO, [0] EXBERR.TO
0x8701D8A4 BUS 8-bit
  [0] EXBEREN.TOEN
0x8701D8A8 BUS 8-bit
  [2] EXBECLR.BCANCLR, [1] EXBECLR.HLDTOCLR, [0] EXBECLR.TOCLR
0x8701D8AC BUS
  [31:19] EXBEAD.EADDR
0x8701D8B4 BUS 8-bit
  [0] EXHLDEN.HLDEN
0x8701DC00 BUS 8-bit
  [5:4] SDCCR.BSIZE, [0] SDCCR.EXENB
0x8701DC01 BUS 8-bit
  [0] SDCMOD.EMODE
0x8701DC02 BUS 8-bit
  [0] SDAMOD.BE
0x8701DC10 BUS 8-bit
  [0] SDSELF.SFEN
0x8701DC14 BUS 16-bit
  [15:12] SDRFCR.REFW, [11:0] SDRFCR.RFC
0x8701DC16 BUS 8-bit
  [0] SDRFEN.RFEN
0x8701DC20 BUS 8-bit
  [0] SDICR.INIRQ
0x8701DC24 BUS 16-bit
  [10:8] SDIR.PRC, [7:4] SDIR.ARFC, [3:0] SDIR.ARFI
0x8701DC40 BUS 8-bit
  [1:0] SDADR.MXC
0x8701DC44 BUS
  [18:16] SDTR.RAI, [13:12] SDTR.RCD, [11:9] SDTR.RP, [8] SDTR.WR, [2:0] SDTR.CL
0x8701DC48 BUS 16-bit
  [14:0] SDMOD.MR
0x8701DC50 BUS 8-bit
  [4] SDSR.SRFST, [3] SDSR.INIST, [0] SDSR.MRSST
0x8701E000 BUS 16-bit
  [2] BUSOAD.BWERROAD, [1] BUSOAD.SLERROAD, [0] BUSOAD.ILERROAD
0x8701E004 BUS 16-bit
  [15:8] BUSOADPT.KEY, [0] BUSOADPT.PROTECT
0x8701E100 BUS
  [0] BUSMABTXSPIMBI.ARBS
0x8701E200 BUS
  [1:0] BUSSABT1MRC0BI.ARBS
0x8701E208 BUS
  [1:0] BUSSABT1MRC1BI.ARBS
0x8701E210 BUS
  [0] BUSSABT0MRE0BI.ARBS
0x8701E220 BUS
  [0] BUSSABT0S0BI.ARBS
0x8701E228 BUS
  [0] BUSSABT0S1BI.ARBS
0x8701E250 BUS
  [0] BUSSABT0ECBI.ARBS
0x8701E258 BUS
  [0] BUSSABT0XSPI0BI.ARBS
0x8701E260 BUS
  [0] BUSSABT0XSPI1BI.ARBS
0x8701E278 BUS
  [0] BUSSABT0PBBI.ARBS
0x8701E280 BUS
  [0] BUSSABT0PABI.ARBS
0x8701E288 BUS
  [0] BUSSABT0PIBI.ARBS
0x8701E290 BUS
  [0] BUSSABT0PSBI.ARBS
0x8701E298 BUS
  [0] BUSSABT0PS0BI.ARBS
0x8701E800 BUS 8-bit
  [5] BUSERRSTATCPU0IF.MSERRSTAT, [4] BUSERRSTATCPU0IF.ILERRSTAT, [3] BUSERRSTATCPU0IF.MMERRSTAT, [0] BUSERRSTATCPU0IF.SLERRSTAT
0x8701E804 BUS 8-bit
  [5] BUSERRCLRCPU0IF.MSERRCLR, [4] BUSERRCLRCPU0IF.ILERRCLR, [3] BUSERRCLRCPU0IF.MMERRCLR, [0] BUSERRCLRCPU0IF.SLERRCLR
0x8701E808 BUS 8-bit
  [0] BUSINTENCPU0IF.EN
0x8701E810 BUS 8-bit
  [5] BUSERRSTATCPU0OA.MSERRSTAT, [4] BUSERRSTATCPU0OA.ILERRSTAT, [3] BUSERRSTATCPU0OA.MMERRSTAT, [0] BUSERRSTATCPU0OA.SLERRSTAT
0x8701E814 BUS 8-bit
  [5] BUSERRCLRCPU0OA.MSERRCLR, [4] BUSERRCLRCPU0OA.ILERRCLR, [3] BUSERRCLRCPU0OA.MMERRCLR, [0] BUSERRCLRCPU0OA.SLERRCLR
0x8701E818 BUS 8-bit
  [0] BUSINTENCPU0OA.EN
0x8701E880 BUS 8-bit
  [5] BUSERRSTATDMAC0.MSERRSTAT, [4] BUSERRSTATDMAC0.ILERRSTAT, [3] BUSERRSTATDMAC0.MMERRSTAT, [0] BUSERRSTATDMAC0.SLERRSTAT
0x8701E884 BUS 8-bit
  [5] BUSERRCLRDMAC0.MSERRCLR, [4] BUSERRCLRDMAC0.ILERRCLR, [3] BUSERRCLRDMAC0.MMERRCLR, [0] BUSERRCLRDMAC0.SLERRCLR
0x8701E888 BUS 8-bit
  [0] BUSINTENDMAC0.EN
0x8701E890 BUS 8-bit
  [5] BUSERRSTATEXDMAC.MSERRSTAT, [4] BUSERRSTATEXDMAC.ILERRSTAT, [3] BUSERRSTATEXDMAC.MMERRSTAT, [0] BUSERRSTATEXDMAC.SLERRSTAT
0x8701E894 BUS 8-bit
  [5] BUSERRCLREXDMAC.MSERRCLR, [4] BUSERRCLREXDMAC.ILERRCLR, [3] BUSERRCLREXDMAC.MMERRCLR, [0] BUSERRCLREXDMAC.SLERRCLR
0x8701E898 BUS 8-bit
  [0] BUSINTENEXDMAC.EN
0x8701E8A0 BUS 8-bit
  [5] BUSERRSTATEDMAC.MSERRSTAT, [4] BUSERRSTATEDMAC.ILERRSTAT, [3] BUSERRSTATEDMAC.MMERRSTAT, [0] BUSERRSTATEDMAC.SLERRSTAT
0x8701E8A4 BUS 8-bit
  [5] BUSERRCLREDMAC.MSERRCLR, [4] BUSERRCLREDMAC.ILERRCLR, [3] BUSERRCLREDMAC.MMERRCLR, [0] BUSERRCLREDMAC.SLERRCLR
0x8701E8A8 BUS 8-bit
  [0] BUSINTENEDMAC.EN
0x8701E8B0 BUS 8-bit
  [5] BUSERRSTATXSPI0.MSERRSTAT, [4] BUSERRSTATXSPI0.ILERRSTAT, [3] BUSERRSTATXSPI0.MMERRSTAT, [0] BUSERRSTATXSPI0.SLERRSTAT
0x8701E8B4 BUS 8-bit
  [5] BUSERRCLRXSPI0.MSERRCLR, [4] BUSERRCLRXSPI0.ILERRCLR, [3] BUSERRCLRXSPI0.MMERRCLR, [0] BUSERRCLRXSPI0.SLERRCLR
0x8701E8B8 BUS 8-bit
  [0] BUSINTENXSPI0.EN
0x8701E8C0 BUS 8-bit
  [5] BUSERRSTATXSPI1.MSERRSTAT, [4] BUSERRSTATXSPI1.ILERRSTAT, [3] BUSERRSTATXSPI1.MMERRSTAT, [0] BUSERRSTATXSPI1.SLERRSTAT
0x8701E8C4 BUS 8-bit
  [5] BUSERRCLRXSPI1.MSERRCLR, [4] BUSERRCLRXSPI1.ILERRCLR, [3] BUSERRCLRXSPI1.MMERRCLR, [0] BUSERRCLRXSPI1.SLERRCLR
0x8701E8C8 BUS 8-bit
  [0] BUSINTENXSPI1.EN
0x8701EB00 BUS
  [n] MBWERRSTAT.MBWERR{n} (n=16..19), [8] MBWERRSTAT.MBWERR8, [0] MBWERRSTAT.MBWERR0
0x8701EB08 BUS
  [n] MBWERRCLR.MBWECLR{n} (n=16..19), [8] MBWERRCLR.MBWECLR8, [0] MBWERRCLR.MBWECLR0
0x8709C000 MRAM 8-bit
  [0] MRCPFB.MPFBEN
0x8709C004 MRAM
  [31:24] MRCFREQ.KEY, [9:0] MRCFREQ.MRCMHZ
0x8709C008 MRAM
  [31:24] MREFREQ.KEY, [7:0] MREFREQ.MREMHZ
0x8709C010 MRAM 16-bit
  [15:8] MRCDECC.KEY, [1] MRCDECC.ECCSELC, [0] MRCDECC.DECDISC
0x8709C014 MRAM 8-bit
  [1] MRCRAEINT.INTENBTC, [0] MRCRAEINT.INTENBDC
0x8709C018 MRAM 8-bit
  [1] MRCRAES.TEDERRC, [0] MRCRAES.DECERRC
0x8709C01C MRAM
  [31:5] MRCRTEA.MRCRTEA
0x8709C020 MRAM
  [31:5] MRCRDEA.MRCRDEA
0x8709C030 MRAM 16-bit
  [15:8] MREDECC.KEY, [1] MREDECC.ECCSELE, [0] MREDECC.DECDISE
0x8709C034 MRAM 8-bit
  [1] MRERAEINT.INTENBTE, [0] MRERAEINT.INTENBDE
0x8709C038 MRAM 8-bit
  [1] MRERAES.TEDERRE, [0] MRERAES.DECERRE
0x8709C03C MRAM
  [31:5] MRERTEA.MRERTEA
0x8709C040 MRAM
  [31:5] MRERDEA.MRERDEA
0x8709C100 MRAM 16-bit
  [15] MSAR.MRCPSEQSA, [14] MSAR.MREPSEQSA, [13] MSAR.MRCPSA, [12] MSAR.MRDPSA, [11] MSAR.MACITRSA, [10] MSAR.MACICMRSA, [9] MSAR.MACICMISA, [4] MSAR.MPFBENSA, [3] MSAR.MRCFREQSA, [2] MSAR.MRCECCSA, [1] MSAR.MREFREQSA, [0] MSAR.MREECCSA
0x8709C400 MRAM 8-bit
  [1] MREZS.WHUKEXE, [0] MREZS.WHUKZF
0x8709C404 MRAM 16-bit
  [15:8] MREZC.KEY, [2:0] MREZC.WHUKZE
0x8709E010 MRAM 8-bit
  [4] MASTAT.CMDLK, [3] MASTAT.MREAE
0x8709E014 MRAM 8-bit
  [4] MPAEINT.CMDLKIE, [3] MPAEINT.MREAEIE
0x8709E018 MRAM 8-bit
  [0] MRDYIE.MRDYIE
0x8709E030 MRAM
  [31:0] MSADDR.MSADDR
0x8709E048 MRAM 8-bit
  [2:0] MCNTSELR.CNTSEL
0x8709E04C MRAM
  [31:0] MCNTDTR[0].CNTRDAT
0x8709E050 MRAM
  [31:0] MCNTDTR[1].CNTRDAT
0x8709E060 MRAM 16-bit
  [15:8] MCTRCNTR.KEY, [0] MCTRCNTR.TRTRG
0x8709E06C MRAM 8-bit
  [2] MCTRSTATR.TRMD, [0] MCTRSTATR.TRBUSY
0x8709E080 MRAM
  [23] MSTATR.ILGCOMERR, [21] MSTATR.SECERR, [20] MSTATR.OTERR, [19] MSTATR.PZFERR, [15] MSTATR.MRDY, [14] MSTATR.ILGLERR, [12] MSTATR.PRGERR, [5] MSTATR.CFGSETERR, [4] MSTATR.PROTERR
0x8709E084 MRAM 16-bit
  [15:8] MENTRYR.KEY, [7] MENTRYR.MENTRY
0x8709E08C MRAM 16-bit
  [15:8] MSUINITR.KEY, [0] MSUINITR.SUINIT
0x8709E0A0 MRAM 16-bit
  [15:8] MCMDR.CMDR, [7:0] MCMDR.PCMDR
0x8709E0DC MRAM
  [31] MSUASMON.BTFLG, [30:29] MSUASMON.BTSIZE, [15] MSUASMON.FSPR, [14] MSUASMON.FSPRS
0x8709E0E8 MRAM 16-bit
  [15:8] MSUACR.KEY, [1:0] MSUACR.SAS
0x8709E0F0 MRAM 8-bit
  [0] MRSTTRST.RSTTRER
0x8709E800 MRAM 8-bit
  [0] MRPSC.MHSPEN
0x8709F000 MRAM 16-bit
  [15:8] MRCPC0.KEY, [0] MRCPC0.MRCPNEN
0x8709F004 MRAM 16-bit
  [15:8] MRCPC1.KEY, [0] MRCPC1.MRCPSEN
0x8709F008 MRAM 16-bit
  [15:8] MRCBPROT0.KEY, [0] MRCBPROT0.BPCN0
0x8709F00C MRAM 16-bit
  [15:8] MRCBPROT1.KEY, [0] MRCBPROT1.BPCN1
0x8709F010 MRAM 8-bit
  [7] MRCPS.PRGBSYC, [6] MRCPS.ABUFFULL, [5] MRCPS.ABUFEMP, [4] MRCPS.PRGBSYCB, [3] MRCPS.ABUFFULLB, [2] MRCPS.ABUFEMPB, [1] MRCPS.ECCERRC, [0] MRCPS.PRGERRC
0x8709F014 MRAM 8-bit
  [7] MRCPAEINT.MRCAEIE
0x8709F018 MRAM
  [31:5] MRCPEA.MCPEA
0x8709F030 MRAM 16-bit
  [15:8] MRCFLR.KEY, [1] MRCFLR.MRCBFL, [0] MRCFLR.MRCFL
0x8709F040 MRAM 8-bit
  [7] MRCPRICR.MRCPRRIE, [0] MRCPRICR.MRCINTSEL
0x8709F410 MRAM 8-bit
  [7] MRDPS.PRGBSYD, [6] MRDPS.ABUFFULLD, [5] MRDPS.ABUFEMPD, [1] MRDPS.ECCERRD, [0] MRDPS.PRGERRD
0x8709F414 MRAM 8-bit
  [7] MRDPAEINT.MRDAEIE
0x8709F418 MRAM
  [31:4] MRDPEA.MDPEA
0x8709F430 MRAM 16-bit
  [15:8] MRDFLR.KEY, [0] MRDFLR.MRDFL
0x8709F440 MRAM 8-bit
  [7] MRDPRICR.MRDPRRIE
0x8709F804 MRAM 16-bit
  [15:8] MRCEECC.KEY, [0] MRCEECC.ECCBYPC
0x87410000 CRC 8-bit
  [7] CRCCR.DORCLR, [6] CRCCR.LMS, [2:0] CRCCR.GPS
0x87411000 DOC 8-bit
  [7] DOCR.DOPCIE, [6:4] DOCR.DCSEL, [3] DOCR.DOPSZ, [1:0] DOCR.OMS
0x87411004 DOC 8-bit
  [0] DOSR.DOPCF
0x87411008 DOC 8-bit
  [0] DOSCR.DOPCFCL
0x87412000 POEG
  [31:30] POEGGA.NFCS, [29] POEGGA.NFEN, [28] POEGGA.INV, [27] POEGGA.DERR1E, [26] POEGGA.DERR0E, [25] POEGGA.DERR1ST, [24] POEGGA.DERR0ST, [16] POEGGA.ST, [6] POEGGA.OSTPE, [5] POEGGA.IOCE, [4] POEGGA.PIDE, [3] POEGGA.SSF, [2] POEGGA.OSTPF, [1] POEGGA.IOCF, [0] POEGGA.PIDF
0x87412030 POEG
  [28] POEGPICRA.NFEN, [27:24] POEGPICRA.NFCS, [23:22] POEGPICRA.PIDM, [19:16] POEGPICRA.NFSCS, [12] POEGPICRA.ST, [8] POEGPICRA.INV, [4] POEGPICRA.PIDE, [0] POEGPICRA.PIDF
0x87412100 POEG
  [31:30] POEGGB.NFCS, [29] POEGGB.NFEN, [28] POEGGB.INV, [27] POEGGB.DERR1E, [26] POEGGB.DERR0E, [25] POEGGB.DERR1ST, [24] POEGGB.DERR0ST, [16] POEGGB.ST, [6] POEGGB.OSTPE, [5] POEGGB.IOCE, [4] POEGGB.PIDE, [3] POEGGB.SSF, [2] POEGGB.OSTPF, [1] POEGGB.IOCF, [0] POEGGB.PIDF
0x87412130 POEG
  [28] POEGPICRB.NFEN, [27:24] POEGPICRB.NFCS, [23:22] POEGPICRB.PIDM, [19:16] POEGPICRB.NFSCS, [12] POEGPICRB.ST, [8] POEGPICRB.INV, [4] POEGPICRB.PIDE, [0] POEGPICRB.PIDF
0x87412200 POEG
  [31:30] POEGGC.NFCS, [29] POEGGC.NFEN, [28] POEGGC.INV, [27] POEGGC.DERR1E, [26] POEGGC.DERR0E, [25] POEGGC.DERR1ST, [24] POEGGC.DERR0ST, [16] POEGGC.ST, [6] POEGGC.OSTPE, [5] POEGGC.IOCE, [4] POEGGC.PIDE, [3] POEGGC.SSF, [2] POEGGC.OSTPF, [1] POEGGC.IOCF, [0] POEGGC.PIDF
0x87412230 POEG
  [28] POEGPICRC.NFEN, [27:24] POEGPICRC.NFCS, [23:22] POEGPICRC.PIDM, [19:16] POEGPICRC.NFSCS, [12] POEGPICRC.ST, [8] POEGPICRC.INV, [4] POEGPICRC.PIDE, [0] POEGPICRC.PIDF
0x87412300 POEG
  [31:30] POEGGD.NFCS, [29] POEGGD.NFEN, [28] POEGGD.INV, [27] POEGGD.DERR1E, [26] POEGGD.DERR0E, [25] POEGGD.DERR1ST, [24] POEGGD.DERR0ST, [16] POEGGD.ST, [6] POEGGD.OSTPE, [5] POEGGD.IOCE, [4] POEGGD.PIDE, [3] POEGGD.SSF, [2] POEGGD.OSTPF, [1] POEGGD.IOCF, [0] POEGGD.PIDF
0x87412330 POEG
  [28] POEGPICRD.NFEN, [27:24] POEGPICRD.NFCS, [23:22] POEGPICRD.PIDM, [19:16] POEGPICRD.NFSCS, [12] POEGPICRD.ST, [8] POEGPICRD.INV, [4] POEGPICRD.PIDE, [0] POEGPICRD.PIDF
0x87424000 HRPWM 16-bit
  [8] HROCR.FRANGE, [1] HROCR.HRRST, [0] HROCR.DLLEN
0x87424002 HRPWM 16-bit
  [n+8] HROCR2.HRDIS{n} (n=0..3), [n] HROCR2.HRSEL{n} (n=0..3)
0x87424018 HRPWM 16-bit
  [6:0] HRREAR0A.DLY
0x8742401A HRPWM 16-bit
  [6:0] HRREAR0B.DLY
0x8742401C HRPWM 16-bit
  [6:0] HRREAR1A.DLY
0x8742401E HRPWM 16-bit
  [6:0] HRREAR1B.DLY
0x87424020 HRPWM 16-bit
  [6:0] HRREAR2A.DLY
0x87424022 HRPWM 16-bit
  [6:0] HRREAR2B.DLY
0x87424024 HRPWM 16-bit
  [6:0] HRREAR3A.DLY
0x87424026 HRPWM 16-bit
  [6:0] HRREAR3B.DLY
0x87424028 HRPWM 16-bit
  [6:0] HRFEAR0A.DLY
0x8742402A HRPWM 16-bit
  [6:0] HRFEAR0B.DLY
0x8742402C HRPWM 16-bit
  [6:0] HRFEAR1A.DLY
0x8742402E HRPWM 16-bit
  [6:0] HRFEAR1B.DLY
0x87424030 HRPWM 16-bit
  [6:0] HRFEAR2A.DLY
0x87424032 HRPWM 16-bit
  [6:0] HRFEAR2B.DLY
0x87424034 HRPWM 16-bit
  [6:0] HRFEAR3A.DLY
0x87424036 HRPWM 16-bit
  [6:0] HRFEAR3B.DLY
0x8742A000 DSMIF0
  [1:0] DSCCSCR.CLKSEL
0x8742A080 DSMIF0
  [1] DSSEICR.ISEH, [0] DSSEICR.ISEL
0x8742A084 DSMIF0
  [2:0] DSSECSR.SEDM
0x8742A088 DSMIF0
  [17:0] DSSELTR.SCMPTBL
0x8742A08C DSMIF0
  [17:0] DSSEHTR.SCMPTBH
0x8742A090 DSMIF0
  [1] DSSECR.SEEH, [0] DSSECR.SEEL
0x8742A0A0 DSMIF0
  [15:0] DSSECDR[0].SECDR
0x8742A0A4 DSMIF0
  [15:0] DSSECDR[1].SECDR
0x8742A0A8 DSMIF0
  [15:0] DSSECDR[2].SECDR
0x8742A0C0 DSMIF0
  [2:1] DSCMSR.CISM, [0] DSCMSR.DFS
0x8742A0C4 DSMIF0
  [2] DSCICR.IBUCE, [1] DSCICR.IAUCE, [0] DSCICR.IUCE
0x8742A200 DSMIF0
  [2] DSCSTRTR.STRTRG2, [1] DSCSTRTR.STRTRG1, [0] DSCSTRTR.STRTRG0
0x8742A204 DSMIF0
  [2] DSCSTPTR.STPTRG2, [1] DSCSTPTR.STPTRG1, [0] DSCSTPTR.STPTRG0
0x8742A220 DSMIF0
  [17] DSCESR.SUMERRH, [16] DSCESR.SUMERRL, [2] DSCESR.SCF2, [1] DSCESR.SCF1, [0] DSCESR.SCF0
0x8742A224 DSMIF0
  [22] DSCOCESR.OC2FH2, [21] DSCOCESR.OC2FH1, [20] DSCOCESR.OC2FH0, [18] DSCOCESR.OC2FL2, [17] DSCOCESR.OC2FL1, [16] DSCOCESR.OC2FL0, [14] DSCOCESR.OC1FH2, [13] DSCOCESR.OC1FH1, [12] DSCOCESR.OC1FH0, [10] DSCOCESR.OC1FL2, [9] DSCOCESR.OC1FL1, [8] DSCOCESR.OC1FL0, [6] DSCOCESR.OC0FH2, [5] DSCOCESR.OC0FH1, [4] DSCOCESR.OC0FH0, [2] DSCOCESR.OC0FL2, [1] DSCOCESR.OC0FL1, [0] DSCOCESR.OC0FL0
0x8742A228 DSMIF0
  [4n+2] DSCOCNSR.OWD{n}N2 (n=0..3), [4n+1] DSCOCNSR.OWD{n}N1 (n=0..3), [4n] DSCOCNSR.OWD{n}N0 (n=0..3)
0x8742A22C DSMIF0
  [22] DSCOCRMR.OC2CMPH2, [21] DSCOCRMR.OC2CMPH1, [20] DSCOCRMR.OC2CMPH0, [18] DSCOCRMR.OC2CMPL2, [17] DSCOCRMR.OC2CMPL1, [16] DSCOCRMR.OC2CMPL0, [14] DSCOCRMR.OC1CMPH2, [13] DSCOCRMR.OC1CMPH1, [12] DSCOCRMR.OC1CMPH0, [10] DSCOCRMR.OC1CMPL2, [9] DSCOCRMR.OC1CMPL1, [8] DSCOCRMR.OC1CMPL0, [6] DSCOCRMR.OC0CMPH2, [5] DSCOCRMR.OC0CMPH1, [4] DSCOCRMR.OC0CMPH0, [2] DSCOCRMR.OC0CMPL2, [1] DSCOCRMR.OC0CMPL1, [0] DSCOCRMR.OC0CMPL0
0x8742A240 DSMIF0
  [10] DSCSR.CBUF2, [9] DSCSR.CBUF1, [8] DSCSR.CBUF0, [6] DSCSR.CAUF2, [5] DSCSR.CAUF1, [4] DSCSR.CAUF0, [2] DSCSR.DUF2, [1] DSCSR.DUF1, [0] DSCSR.DUF0
0x8742A244 DSMIF0
  [8] DSCSSR.CHSTATE2, [4] DSCSSR.CHSTATE1, [0] DSCSSR.CHSTATE0
0x8742A260 DSMIF0
  [17] DSCESCR.CLRSUMERRH, [16] DSCESCR.CLRSUMERRL, [2] DSCESCR.CLRSCF2, [1] DSCESCR.CLRSCF1, [0] DSCESCR.CLRSCF0
0x8742A264 DSMIF0
  [22] DSCOCESCR.CLROC2FH2, [21] DSCOCESCR.CLROC2FH1, [20] DSCOCESCR.CLROC2FH0, [18] DSCOCESCR.CLROC2FL2, [17] DSCOCESCR.CLROC2FL1, [16] DSCOCESCR.CLROC2FL0, [14] DSCOCESCR.CLROC1FH2, [13] DSCOCESCR.CLROC1FH1, [12] DSCOCESCR.CLROC1FH0, [10] DSCOCESCR.CLROC1FL2, [9] DSCOCESCR.CLROC1FL1, [8] DSCOCESCR.CLROC1FL0, [6] DSCOCESCR.CLROC0FH2, [5] DSCOCESCR.CLROC0FH1, [4] DSCOCESCR.CLROC0FH0, [2] DSCOCESCR.CLROC0FL2, [1] DSCOCESCR.CLROC0FL1, [0] DSCOCESCR.CLROC0FL0
0x8742A268 DSMIF0
  [4n+2] DSCOCNSCR.CLROWD{n}N2 (n=0..3), [4n+1] DSCOCNSCR.CLROWD{n}N1 (n=0..3), [4n] DSCOCNSCR.CLROWD{n}N0 (n=0..3)
0x8742A280 DSMIF0
  [10] DSCSCR.CLRCBUF2, [9] DSCSCR.CLRCBUF1, [8] DSCSCR.CLRCBUF0, [6] DSCSCR.CLRCAUF2, [5] DSCSCR.CLRCAUF1, [4] DSCSCR.CLRCAUF0, [2] DSCSCR.CLRDUF2, [1] DSCSCR.CLRDUF1, [0] DSCSCR.CLRDUF0
0x8742A300 DSMIF0
  [n+16] DSICRCH0.OWNE{n} (n=0..3), [13] DSICRCH0.IOEH2, [12] DSICRCH0.IOEL2, [11] DSICRCH0.IOEH1, [10] DSICRCH0.IOEL1, [9] DSICRCH0.IOEH0, [8] DSICRCH0.IOEL0, [3] DSICRCH0.ISE, [2] DSICRCH0.IBUE, [1] DSICRCH0.IAUE, [0] DSICRCH0.IUE
0x8742A304 DSMIF0
  [13:8] DSCMCCRCH0.CKDIV, [7] DSCMCCRCH0.SEDGE, [0] DSCMCCRCH0.CKDIR
0x8742A308 DSMIF0
  [20:16] DSCMFCRCH0.CMSH, [15:8] DSCMFCRCH0.CMDEC, [1:0] DSCMFCRCH0.CMSINC
0x8742A30C DSMIF0
  [23] DSCMCTCRCH0.DEDGE, [17:16] DSCMCTCRCH0.DITSEL, [10:8] DSCMCTCRCH0.CTSELB, [2:0] DSCMCTCRCH0.CTSELA
0x8742A320 DSMIF0
  [0] DSEDCRCH0.SDE
0x8742A324 DSMIF0
  [28:16] DSSCTSRCH0.SCNTH, [12:0] DSSCTSRCH0.SCNTL
0x8742A330 DSMIF0
  [20:16] DSOCFCRCH0.OCSH, [15:8] DSOCFCRCH0.OCDEC, [1:0] DSOCFCRCH0.OCSINC
0x8742A334 DSMIF0
  [18] DSODCRCH0.OWFEN2, [17] DSODCRCH0.OWFEN1, [16] DSODCRCH0.OWFEN0, [n+8] DSODCRCH0.OWFE{n} (n=0..3), [5] DSODCRCH0.ODEH2, [4] DSODCRCH0.ODEL2, [3] DSODCRCH0.ODEH1, [2] DSODCRCH0.ODEL1, [1] DSODCRCH0.ODEH0, [0] DSODCRCH0.ODEL0
0x8742A338 DSMIF0
  [14] DSODWCRCH0.OWNHCD2, [13] DSODWCRCH0.OWNHCD1, [12] DSODWCRCH0.OWNHCD0, [10] DSODWCRCH0.OWNM21, [9] DSODWCRCH0.OWNM11, [8] DSODWCRCH0.OWNM01, [6:3] DSODWCRCH0.OWNM3, [2] DSODWCRCH0.OWNM20, [1] DSODWCRCH0.OWNM10, [0] DSODWCRCH0.OWNM00
0x8742A340 DSMIF0
  [31] DSODWN0FCRCH0.OWFINT0, [20:16] DSODWN0FCRCH0.OWDR0, [12:8] DSODWN0FCRCH0.OWTH0, [4:0] DSODWN0FCRCH0.OWSN0
0x8742A344 DSMIF0
  [31] DSODWN1FCRCH0.OWFINT1, [20:16] DSODWN1FCRCH0.OWDR1, [12:8] DSODWN1FCRCH0.OWTH1, [4:0] DSODWN1FCRCH0.OWSN1
0x8742A348 DSMIF0
  [31] DSODWN2FCRCH0.OWFINT2, [20:16] DSODWN2FCRCH0.OWDR2, [12:8] DSODWN2FCRCH0.OWTH2, [4:0] DSODWN2FCRCH0.OWSN2
0x8742A350 DSMIF0
  [0] DSCLOCKCH0.WNFCRL
0x8742A3A0 DSMIF0
  [15:0] DSOCLTR0CH0.OCMPTBL0
0x8742A3A4 DSMIF0
  [15:0] DSOCHTR0CH0.OCMPTBH0
0x8742A3A8 DSMIF0
  [15:0] DSOCLTR1CH0.OCMPTBL1
0x8742A3AC DSMIF0
  [15:0] DSOCHTR1CH0.OCMPTBH1
0x8742A3B0 DSMIF0
  [15:0] DSOCLTR2CH0.OCMPTBL2
0x8742A3B4 DSMIF0
  [15:0] DSOCHTR2CH0.OCMPTBH2
0x8742A3E0 DSMIF0
  [0] DSCSTRTRCH0.STRTRG
0x8742A3E4 DSMIF0
  [0] DSCSTPTRCH0.STPTRG
0x8742A3F0 DSMIF0
  [15:0] DSCDRCH0.ADDR
0x8742A3F4 DSMIF0
  [15:0] DSCCDRACH0.CDRA
0x8742A3F8 DSMIF0
  [15:0] DSCCDRBCH0.CDRB
0x8742A3FC DSMIF0
  [15:0] DSOCDRCH0.ODR
0x8742A400 DSMIF0
  [15:0] DSCOCDR0CH0.CODR0
0x8742A404 DSMIF0
  [15:0] DSCOCDR1CH0.CODR1
0x8742A408 DSMIF0
  [15:0] DSCOCDR2CH0.CODR2
0x8742A420 DSMIF0
  [29] DSCSRCH0.OC2CMPH, [28] DSCSRCH0.OC2CMPL, [27] DSCSRCH0.OC1CMPH, [26] DSCSRCH0.OC1CMPL, [25] DSCSRCH0.OC0CMPH, [24] DSCSRCH0.OC0CMPL, [n+16] DSCSRCH0.OWD{n}N (n=0..3), [13] DSCSRCH0.OC2FH, [12] DSCSRCH0.OC2FL, [11] DSCSRCH0.OC1FH, [10] DSCSRCH0.OC1FL, [9] DSCSRCH0.OC0FH, [8] DSCSRCH0.OC0FL, [7] DSCSRCH0.CHSTATE, [3] DSCSRCH0.SCF, [2] DSCSRCH0.CBUF, [1] DSCSRCH0.CAUF, [0] DSCSRCH0.DUF
0x8742A430 DSMIF0
  [n+16] DSCSCRCH0.CLROWD{n}N (n=0..3), [13] DSCSCRCH0.CLROC2FH, [12] DSCSCRCH0.CLROC2FL, [11] DSCSCRCH0.CLROC1FH, [10] DSCSCRCH0.CLROC1FL, [9] DSCSCRCH0.CLROC0FH, [8] DSCSCRCH0.CLROC0FL, [3] DSCSCRCH0.CLRSCF, [2] DSCSCRCH0.CLRCBUF, [1] DSCSCRCH0.CLRCAUF, [0] DSCSCRCH0.CLRDUF
0x8742A440 DSMIF0
  [n+16] DSICRCH1.OWNE{n} (n=0..3), [13] DSICRCH1.IOEH2, [12] DSICRCH1.IOEL2, [11] DSICRCH1.IOEH1, [10] DSICRCH1.IOEL1, [9] DSICRCH1.IOEH0, [8] DSICRCH1.IOEL0, [3] DSICRCH1.ISE, [2] DSICRCH1.IBUE, [1] DSICRCH1.IAUE, [0] DSICRCH1.IUE
0x8742A444 DSMIF0
  [13:8] DSCMCCRCH1.CKDIV, [7] DSCMCCRCH1.SEDGE, [0] DSCMCCRCH1.CKDIR
0x8742A448 DSMIF0
  [20:16] DSCMFCRCH1.CMSH, [15:8] DSCMFCRCH1.CMDEC, [1:0] DSCMFCRCH1.CMSINC
0x8742A44C DSMIF0
  [23] DSCMCTCRCH1.DEDGE, [17:16] DSCMCTCRCH1.DITSEL, [10:8] DSCMCTCRCH1.CTSELB, [2:0] DSCMCTCRCH1.CTSELA
0x8742A460 DSMIF0
  [0] DSEDCRCH1.SDE
0x8742A464 DSMIF0
  [28:16] DSSCTSRCH1.SCNTH, [12:0] DSSCTSRCH1.SCNTL
0x8742A470 DSMIF0
  [20:16] DSOCFCRCH1.OCSH, [15:8] DSOCFCRCH1.OCDEC, [1:0] DSOCFCRCH1.OCSINC
0x8742A474 DSMIF0
  [18] DSODCRCH1.OWFEN2, [17] DSODCRCH1.OWFEN1, [16] DSODCRCH1.OWFEN0, [n+8] DSODCRCH1.OWFE{n} (n=0..3), [5] DSODCRCH1.ODEH2, [4] DSODCRCH1.ODEL2, [3] DSODCRCH1.ODEH1, [2] DSODCRCH1.ODEL1, [1] DSODCRCH1.ODEH0, [0] DSODCRCH1.ODEL0
0x8742A478 DSMIF0
  [14] DSODWCRCH1.OWNHCD2, [13] DSODWCRCH1.OWNHCD1, [12] DSODWCRCH1.OWNHCD0, [10] DSODWCRCH1.OWNM21, [9] DSODWCRCH1.OWNM11, [8] DSODWCRCH1.OWNM01, [6:3] DSODWCRCH1.OWNM3, [2] DSODWCRCH1.OWNM20, [1] DSODWCRCH1.OWNM10, [0] DSODWCRCH1.OWNM00
0x8742A480 DSMIF0
  [31] DSODWN0FCRCH1.OWFINT0, [20:16] DSODWN0FCRCH1.OWDR0, [12:8] DSODWN0FCRCH1.OWTH0, [4:0] DSODWN0FCRCH1.OWSN0
0x8742A484 DSMIF0
  [31] DSODWN1FCRCH1.OWFINT1, [20:16] DSODWN1FCRCH1.OWDR1, [12:8] DSODWN1FCRCH1.OWTH1, [4:0] DSODWN1FCRCH1.OWSN1
0x8742A488 DSMIF0
  [31] DSODWN2FCRCH1.OWFINT2, [20:16] DSODWN2FCRCH1.OWDR2, [12:8] DSODWN2FCRCH1.OWTH2, [4:0] DSODWN2FCRCH1.OWSN2
0x8742A490 DSMIF0
  [0] DSCLOCKCH1.WNFCRL
0x8742A4E0 DSMIF0
  [15:0] DSOCLTR0CH1.OCMPTBL0
0x8742A4E4 DSMIF0
  [15:0] DSOCHTR0CH1.OCMPTBH0
0x8742A4E8 DSMIF0
  [15:0] DSOCLTR1CH1.OCMPTBL1
0x8742A4EC DSMIF0
  [15:0] DSOCHTR1CH1.OCMPTBH1
0x8742A4F0 DSMIF0
  [15:0] DSOCLTR2CH1.OCMPTBL2
0x8742A4F4 DSMIF0
  [15:0] DSOCHTR2CH1.OCMPTBH2
0x8742A520 DSMIF0
  [0] DSCSTRTRCH1.STRTRG
0x8742A524 DSMIF0
  [0] DSCSTPTRCH1.STPTRG
0x8742A530 DSMIF0
  [15:0] DSCDRCH1.ADDR
0x8742A534 DSMIF0
  [15:0] DSCCDRACH1.CDRA
0x8742A538 DSMIF0
  [15:0] DSCCDRBCH1.CDRB
0x8742A53C DSMIF0
  [15:0] DSOCDRCH1.ODR
0x8742A540 DSMIF0
  [15:0] DSCOCDR0CH1.CODR0
0x8742A544 DSMIF0
  [15:0] DSCOCDR1CH1.CODR1
0x8742A548 DSMIF0
  [15:0] DSCOCDR2CH1.CODR2
0x8742A560 DSMIF0
  [29] DSCSRCH1.OC2CMPH, [28] DSCSRCH1.OC2CMPL, [27] DSCSRCH1.OC1CMPH, [26] DSCSRCH1.OC1CMPL, [25] DSCSRCH1.OC0CMPH, [24] DSCSRCH1.OC0CMPL, [n+16] DSCSRCH1.OWD{n}N (n=0..3), [13] DSCSRCH1.OC2FH, [12] DSCSRCH1.OC2FL, [11] DSCSRCH1.OC1FH, [10] DSCSRCH1.OC1FL, [9] DSCSRCH1.OC0FH, [8] DSCSRCH1.OC0FL, [7] DSCSRCH1.CHSTATE, [3] DSCSRCH1.SCF, [2] DSCSRCH1.CBUF, [1] DSCSRCH1.CAUF, [0] DSCSRCH1.DUF
0x8742A570 DSMIF0
  [n+16] DSCSCRCH1.CLROWD{n}N (n=0..3), [13] DSCSCRCH1.CLROC2FH, [12] DSCSCRCH1.CLROC2FL, [11] DSCSCRCH1.CLROC1FH, [10] DSCSCRCH1.CLROC1FL, [9] DSCSCRCH1.CLROC0FH, [8] DSCSCRCH1.CLROC0FL, [3] DSCSCRCH1.CLRSCF, [2] DSCSCRCH1.CLRCBUF, [1] DSCSCRCH1.CLRCAUF, [0] DSCSCRCH1.CLRDUF
0x8742A580 DSMIF0
  [n+16] DSICRCH2.OWNE{n} (n=0..3), [13] DSICRCH2.IOEH2, [12] DSICRCH2.IOEL2, [11] DSICRCH2.IOEH1, [10] DSICRCH2.IOEL1, [9] DSICRCH2.IOEH0, [8] DSICRCH2.IOEL0, [3] DSICRCH2.ISE, [2] DSICRCH2.IBUE, [1] DSICRCH2.IAUE, [0] DSICRCH2.IUE
0x8742A584 DSMIF0
  [13:8] DSCMCCRCH2.CKDIV, [7] DSCMCCRCH2.SEDGE, [0] DSCMCCRCH2.CKDIR
0x8742A588 DSMIF0
  [20:16] DSCMFCRCH2.CMSH, [15:8] DSCMFCRCH2.CMDEC, [1:0] DSCMFCRCH2.CMSINC
0x8742A58C DSMIF0
  [23] DSCMCTCRCH2.DEDGE, [17:16] DSCMCTCRCH2.DITSEL, [10:8] DSCMCTCRCH2.CTSELB, [2:0] DSCMCTCRCH2.CTSELA
0x8742A5A0 DSMIF0
  [0] DSEDCRCH2.SDE
0x8742A5A4 DSMIF0
  [28:16] DSSCTSRCH2.SCNTH, [12:0] DSSCTSRCH2.SCNTL
0x8742A5B0 DSMIF0
  [20:16] DSOCFCRCH2.OCSH, [15:8] DSOCFCRCH2.OCDEC, [1:0] DSOCFCRCH2.OCSINC
0x8742A5B4 DSMIF0
  [18] DSODCRCH2.OWFEN2, [17] DSODCRCH2.OWFEN1, [16] DSODCRCH2.OWFEN0, [n+8] DSODCRCH2.OWFE{n} (n=0..3), [5] DSODCRCH2.ODEH2, [4] DSODCRCH2.ODEL2, [3] DSODCRCH2.ODEH1, [2] DSODCRCH2.ODEL1, [1] DSODCRCH2.ODEH0, [0] DSODCRCH2.ODEL0
0x8742A5B8 DSMIF0
  [14] DSODWCRCH2.OWNHCD2, [13] DSODWCRCH2.OWNHCD1, [12] DSODWCRCH2.OWNHCD0, [10] DSODWCRCH2.OWNM21, [9] DSODWCRCH2.OWNM11, [8] DSODWCRCH2.OWNM01, [6:3] DSODWCRCH2.OWNM3, [2] DSODWCRCH2.OWNM20, [1] DSODWCRCH2.OWNM10, [0] DSODWCRCH2.OWNM00
0x8742A5C0 DSMIF0
  [31] DSODWN0FCRCH2.OWFINT0, [20:16] DSODWN0FCRCH2.OWDR0, [12:8] DSODWN0FCRCH2.OWTH0, [4:0] DSODWN0FCRCH2.OWSN0
0x8742A5C4 DSMIF0
  [31] DSODWN1FCRCH2.OWFINT1, [20:16] DSODWN1FCRCH2.OWDR1, [12:8] DSODWN1FCRCH2.OWTH1, [4:0] DSODWN1FCRCH2.OWSN1
0x8742A5C8 DSMIF0
  [31] DSODWN2FCRCH2.OWFINT2, [20:16] DSODWN2FCRCH2.OWDR2, [12:8] DSODWN2FCRCH2.OWTH2, [4:0] DSODWN2FCRCH2.OWSN2
0x8742A5D0 DSMIF0
  [0] DSCLOCKCH2.WNFCRL
0x8742A620 DSMIF0
  [15:0] DSOCLTR0CH2.OCMPTBL0
0x8742A624 DSMIF0
  [15:0] DSOCHTR0CH2.OCMPTBH0
0x8742A628 DSMIF0
  [15:0] DSOCLTR1CH2.OCMPTBL1
0x8742A62C DSMIF0
  [15:0] DSOCHTR1CH2.OCMPTBH1
0x8742A630 DSMIF0
  [15:0] DSOCLTR2CH2.OCMPTBL2
0x8742A634 DSMIF0
  [15:0] DSOCHTR2CH2.OCMPTBH2
0x8742A660 DSMIF0
  [0] DSCSTRTRCH2.STRTRG
0x8742A664 DSMIF0
  [0] DSCSTPTRCH2.STPTRG
0x8742A670 DSMIF0
  [15:0] DSCDRCH2.ADDR
0x8742A674 DSMIF0
  [15:0] DSCCDRACH2.CDRA
0x8742A678 DSMIF0
  [15:0] DSCCDRBCH2.CDRB
0x8742A67C DSMIF0
  [15:0] DSOCDRCH2.ODR
0x8742A680 DSMIF0
  [15:0] DSCOCDR0CH2.CODR0
0x8742A684 DSMIF0
  [15:0] DSCOCDR1CH2.CODR1
0x8742A688 DSMIF0
  [15:0] DSCOCDR2CH2.CODR2
0x8742A6A0 DSMIF0
  [29] DSCSRCH2.OC2CMPH, [28] DSCSRCH2.OC2CMPL, [27] DSCSRCH2.OC1CMPH, [26] DSCSRCH2.OC1CMPL, [25] DSCSRCH2.OC0CMPH, [24] DSCSRCH2.OC0CMPL, [n+16] DSCSRCH2.OWD{n}N (n=0..3), [13] DSCSRCH2.OC2FH, [12] DSCSRCH2.OC2FL, [11] DSCSRCH2.OC1FH, [10] DSCSRCH2.OC1FL, [9] DSCSRCH2.OC0FH, [8] DSCSRCH2.OC0FL, [7] DSCSRCH2.CHSTATE, [3] DSCSRCH2.SCF, [2] DSCSRCH2.CBUF, [1] DSCSRCH2.CAUF, [0] DSCSRCH2.DUF
0x8742A6B0 DSMIF0
  [n+16] DSCSCRCH2.CLROWD{n}N (n=0..3), [13] DSCSCRCH2.CLROC2FH, [12] DSCSCRCH2.CLROC2FL, [11] DSCSCRCH2.CLROC1FH, [10] DSCSCRCH2.CLROC1FL, [9] DSCSCRCH2.CLROC0FH, [8] DSCSCRCH2.CLROC0FL, [3] DSCSCRCH2.CLRSCF, [2] DSCSCRCH2.CLRCBUF, [1] DSCSCRCH2.CLRCAUF, [0] DSCSCRCH2.CLRDUF
0x8742A800 DSMIF1
  [1:0] DSCCSCR.CLKSEL
0x8742A880 DSMIF1
  [1] DSSEICR.ISEH, [0] DSSEICR.ISEL
0x8742A884 DSMIF1
  [2:0] DSSECSR.SEDM
0x8742A888 DSMIF1
  [17:0] DSSELTR.SCMPTBL
0x8742A88C DSMIF1
  [17:0] DSSEHTR.SCMPTBH
0x8742A890 DSMIF1
  [1] DSSECR.SEEH, [0] DSSECR.SEEL
0x8742A8A0 DSMIF1
  [15:0] DSSECDR[0].SECDR
0x8742A8A4 DSMIF1
  [15:0] DSSECDR[1].SECDR
0x8742A8A8 DSMIF1
  [15:0] DSSECDR[2].SECDR
0x8742A8C0 DSMIF1
  [2:1] DSCMSR.CISM, [0] DSCMSR.DFS
0x8742A8C4 DSMIF1
  [2] DSCICR.IBUCE, [1] DSCICR.IAUCE, [0] DSCICR.IUCE
0x8742AA00 DSMIF1
  [2] DSCSTRTR.STRTRG2, [1] DSCSTRTR.STRTRG1, [0] DSCSTRTR.STRTRG0
0x8742AA04 DSMIF1
  [2] DSCSTPTR.STPTRG2, [1] DSCSTPTR.STPTRG1, [0] DSCSTPTR.STPTRG0
0x8742AA20 DSMIF1
  [17] DSCESR.SUMERRH, [16] DSCESR.SUMERRL, [2] DSCESR.SCF2, [1] DSCESR.SCF1, [0] DSCESR.SCF0
0x8742AA24 DSMIF1
  [22] DSCOCESR.OC2FH2, [21] DSCOCESR.OC2FH1, [20] DSCOCESR.OC2FH0, [18] DSCOCESR.OC2FL2, [17] DSCOCESR.OC2FL1, [16] DSCOCESR.OC2FL0, [14] DSCOCESR.OC1FH2, [13] DSCOCESR.OC1FH1, [12] DSCOCESR.OC1FH0, [10] DSCOCESR.OC1FL2, [9] DSCOCESR.OC1FL1, [8] DSCOCESR.OC1FL0, [6] DSCOCESR.OC0FH2, [5] DSCOCESR.OC0FH1, [4] DSCOCESR.OC0FH0, [2] DSCOCESR.OC0FL2, [1] DSCOCESR.OC0FL1, [0] DSCOCESR.OC0FL0
0x8742AA28 DSMIF1
  [4n+2] DSCOCNSR.OWD{n}N2 (n=0..3), [4n+1] DSCOCNSR.OWD{n}N1 (n=0..3), [4n] DSCOCNSR.OWD{n}N0 (n=0..3)
0x8742AA2C DSMIF1
  [22] DSCOCRMR.OC2CMPH2, [21] DSCOCRMR.OC2CMPH1, [20] DSCOCRMR.OC2CMPH0, [18] DSCOCRMR.OC2CMPL2, [17] DSCOCRMR.OC2CMPL1, [16] DSCOCRMR.OC2CMPL0, [14] DSCOCRMR.OC1CMPH2, [13] DSCOCRMR.OC1CMPH1, [12] DSCOCRMR.OC1CMPH0, [10] DSCOCRMR.OC1CMPL2, [9] DSCOCRMR.OC1CMPL1, [8] DSCOCRMR.OC1CMPL0, [6] DSCOCRMR.OC0CMPH2, [5] DSCOCRMR.OC0CMPH1, [4] DSCOCRMR.OC0CMPH0, [2] DSCOCRMR.OC0CMPL2, [1] DSCOCRMR.OC0CMPL1, [0] DSCOCRMR.OC0CMPL0
0x8742AA40 DSMIF1
  [10] DSCSR.CBUF2, [9] DSCSR.CBUF1, [8] DSCSR.CBUF0, [6] DSCSR.CAUF2, [5] DSCSR.CAUF1, [4] DSCSR.CAUF0, [2] DSCSR.DUF2, [1] DSCSR.DUF1, [0] DSCSR.DUF0
0x8742AA44 DSMIF1
  [8] DSCSSR.CHSTATE2, [4] DSCSSR.CHSTATE1, [0] DSCSSR.CHSTATE0
0x8742AA60 DSMIF1
  [17] DSCESCR.CLRSUMERRH, [16] DSCESCR.CLRSUMERRL, [2] DSCESCR.CLRSCF2, [1] DSCESCR.CLRSCF1, [0] DSCESCR.CLRSCF0
0x8742AA64 DSMIF1
  [22] DSCOCESCR.CLROC2FH2, [21] DSCOCESCR.CLROC2FH1, [20] DSCOCESCR.CLROC2FH0, [18] DSCOCESCR.CLROC2FL2, [17] DSCOCESCR.CLROC2FL1, [16] DSCOCESCR.CLROC2FL0, [14] DSCOCESCR.CLROC1FH2, [13] DSCOCESCR.CLROC1FH1, [12] DSCOCESCR.CLROC1FH0, [10] DSCOCESCR.CLROC1FL2, [9] DSCOCESCR.CLROC1FL1, [8] DSCOCESCR.CLROC1FL0, [6] DSCOCESCR.CLROC0FH2, [5] DSCOCESCR.CLROC0FH1, [4] DSCOCESCR.CLROC0FH0, [2] DSCOCESCR.CLROC0FL2, [1] DSCOCESCR.CLROC0FL1, [0] DSCOCESCR.CLROC0FL0
0x8742AA68 DSMIF1
  [4n+2] DSCOCNSCR.CLROWD{n}N2 (n=0..3), [4n+1] DSCOCNSCR.CLROWD{n}N1 (n=0..3), [4n] DSCOCNSCR.CLROWD{n}N0 (n=0..3)
0x8742AA80 DSMIF1
  [10] DSCSCR.CLRCBUF2, [9] DSCSCR.CLRCBUF1, [8] DSCSCR.CLRCBUF0, [6] DSCSCR.CLRCAUF2, [5] DSCSCR.CLRCAUF1, [4] DSCSCR.CLRCAUF0, [2] DSCSCR.CLRDUF2, [1] DSCSCR.CLRDUF1, [0] DSCSCR.CLRDUF0
0x8742AB00 DSMIF1
  [n+16] DSICRCH0.OWNE{n} (n=0..3), [13] DSICRCH0.IOEH2, [12] DSICRCH0.IOEL2, [11] DSICRCH0.IOEH1, [10] DSICRCH0.IOEL1, [9] DSICRCH0.IOEH0, [8] DSICRCH0.IOEL0, [3] DSICRCH0.ISE, [2] DSICRCH0.IBUE, [1] DSICRCH0.IAUE, [0] DSICRCH0.IUE
0x8742AB04 DSMIF1
  [13:8] DSCMCCRCH0.CKDIV, [7] DSCMCCRCH0.SEDGE, [0] DSCMCCRCH0.CKDIR
0x8742AB08 DSMIF1
  [20:16] DSCMFCRCH0.CMSH, [15:8] DSCMFCRCH0.CMDEC, [1:0] DSCMFCRCH0.CMSINC
0x8742AB0C DSMIF1
  [23] DSCMCTCRCH0.DEDGE, [17:16] DSCMCTCRCH0.DITSEL, [10:8] DSCMCTCRCH0.CTSELB, [2:0] DSCMCTCRCH0.CTSELA
0x8742AB20 DSMIF1
  [0] DSEDCRCH0.SDE
0x8742AB24 DSMIF1
  [28:16] DSSCTSRCH0.SCNTH, [12:0] DSSCTSRCH0.SCNTL
0x8742AB30 DSMIF1
  [20:16] DSOCFCRCH0.OCSH, [15:8] DSOCFCRCH0.OCDEC, [1:0] DSOCFCRCH0.OCSINC
0x8742AB34 DSMIF1
  [18] DSODCRCH0.OWFEN2, [17] DSODCRCH0.OWFEN1, [16] DSODCRCH0.OWFEN0, [n+8] DSODCRCH0.OWFE{n} (n=0..3), [5] DSODCRCH0.ODEH2, [4] DSODCRCH0.ODEL2, [3] DSODCRCH0.ODEH1, [2] DSODCRCH0.ODEL1, [1] DSODCRCH0.ODEH0, [0] DSODCRCH0.ODEL0
0x8742AB38 DSMIF1
  [14] DSODWCRCH0.OWNHCD2, [13] DSODWCRCH0.OWNHCD1, [12] DSODWCRCH0.OWNHCD0, [10] DSODWCRCH0.OWNM21, [9] DSODWCRCH0.OWNM11, [8] DSODWCRCH0.OWNM01, [6:3] DSODWCRCH0.OWNM3, [2] DSODWCRCH0.OWNM20, [1] DSODWCRCH0.OWNM10, [0] DSODWCRCH0.OWNM00
0x8742AB40 DSMIF1
  [31] DSODWN0FCRCH0.OWFINT0, [20:16] DSODWN0FCRCH0.OWDR0, [12:8] DSODWN0FCRCH0.OWTH0, [4:0] DSODWN0FCRCH0.OWSN0
0x8742AB44 DSMIF1
  [31] DSODWN1FCRCH0.OWFINT1, [20:16] DSODWN1FCRCH0.OWDR1, [12:8] DSODWN1FCRCH0.OWTH1, [4:0] DSODWN1FCRCH0.OWSN1
0x8742AB48 DSMIF1
  [31] DSODWN2FCRCH0.OWFINT2, [20:16] DSODWN2FCRCH0.OWDR2, [12:8] DSODWN2FCRCH0.OWTH2, [4:0] DSODWN2FCRCH0.OWSN2
0x8742AB50 DSMIF1
  [0] DSCLOCKCH0.WNFCRL
0x8742ABA0 DSMIF1
  [15:0] DSOCLTR0CH0.OCMPTBL0
0x8742ABA4 DSMIF1
  [15:0] DSOCHTR0CH0.OCMPTBH0
0x8742ABA8 DSMIF1
  [15:0] DSOCLTR1CH0.OCMPTBL1
0x8742ABAC DSMIF1
  [15:0] DSOCHTR1CH0.OCMPTBH1
0x8742ABB0 DSMIF1
  [15:0] DSOCLTR2CH0.OCMPTBL2
0x8742ABB4 DSMIF1
  [15:0] DSOCHTR2CH0.OCMPTBH2
0x8742ABE0 DSMIF1
  [0] DSCSTRTRCH0.STRTRG
0x8742ABE4 DSMIF1
  [0] DSCSTPTRCH0.STPTRG
0x8742ABF0 DSMIF1
  [15:0] DSCDRCH0.ADDR
0x8742ABF4 DSMIF1
  [15:0] DSCCDRACH0.CDRA
0x8742ABF8 DSMIF1
  [15:0] DSCCDRBCH0.CDRB
0x8742ABFC DSMIF1
  [15:0] DSOCDRCH0.ODR
0x8742AC00 DSMIF1
  [15:0] DSCOCDR0CH0.CODR0
0x8742AC04 DSMIF1
  [15:0] DSCOCDR1CH0.CODR1
0x8742AC08 DSMIF1
  [15:0] DSCOCDR2CH0.CODR2
0x8742AC20 DSMIF1
  [29] DSCSRCH0.OC2CMPH, [28] DSCSRCH0.OC2CMPL, [27] DSCSRCH0.OC1CMPH, [26] DSCSRCH0.OC1CMPL, [25] DSCSRCH0.OC0CMPH, [24] DSCSRCH0.OC0CMPL, [n+16] DSCSRCH0.OWD{n}N (n=0..3), [13] DSCSRCH0.OC2FH, [12] DSCSRCH0.OC2FL, [11] DSCSRCH0.OC1FH, [10] DSCSRCH0.OC1FL, [9] DSCSRCH0.OC0FH, [8] DSCSRCH0.OC0FL, [7] DSCSRCH0.CHSTATE, [3] DSCSRCH0.SCF, [2] DSCSRCH0.CBUF, [1] DSCSRCH0.CAUF, [0] DSCSRCH0.DUF
0x8742AC30 DSMIF1
  [n+16] DSCSCRCH0.CLROWD{n}N (n=0..3), [13] DSCSCRCH0.CLROC2FH, [12] DSCSCRCH0.CLROC2FL, [11] DSCSCRCH0.CLROC1FH, [10] DSCSCRCH0.CLROC1FL, [9] DSCSCRCH0.CLROC0FH, [8] DSCSCRCH0.CLROC0FL, [3] DSCSCRCH0.CLRSCF, [2] DSCSCRCH0.CLRCBUF, [1] DSCSCRCH0.CLRCAUF, [0] DSCSCRCH0.CLRDUF
0x8742AC40 DSMIF1
  [n+16] DSICRCH1.OWNE{n} (n=0..3), [13] DSICRCH1.IOEH2, [12] DSICRCH1.IOEL2, [11] DSICRCH1.IOEH1, [10] DSICRCH1.IOEL1, [9] DSICRCH1.IOEH0, [8] DSICRCH1.IOEL0, [3] DSICRCH1.ISE, [2] DSICRCH1.IBUE, [1] DSICRCH1.IAUE, [0] DSICRCH1.IUE
0x8742AC44 DSMIF1
  [13:8] DSCMCCRCH1.CKDIV, [7] DSCMCCRCH1.SEDGE, [0] DSCMCCRCH1.CKDIR
0x8742AC48 DSMIF1
  [20:16] DSCMFCRCH1.CMSH, [15:8] DSCMFCRCH1.CMDEC, [1:0] DSCMFCRCH1.CMSINC
0x8742AC4C DSMIF1
  [23] DSCMCTCRCH1.DEDGE, [17:16] DSCMCTCRCH1.DITSEL, [10:8] DSCMCTCRCH1.CTSELB, [2:0] DSCMCTCRCH1.CTSELA
0x8742AC60 DSMIF1
  [0] DSEDCRCH1.SDE
0x8742AC64 DSMIF1
  [28:16] DSSCTSRCH1.SCNTH, [12:0] DSSCTSRCH1.SCNTL
0x8742AC70 DSMIF1
  [20:16] DSOCFCRCH1.OCSH, [15:8] DSOCFCRCH1.OCDEC, [1:0] DSOCFCRCH1.OCSINC
0x8742AC74 DSMIF1
  [18] DSODCRCH1.OWFEN2, [17] DSODCRCH1.OWFEN1, [16] DSODCRCH1.OWFEN0, [n+8] DSODCRCH1.OWFE{n} (n=0..3), [5] DSODCRCH1.ODEH2, [4] DSODCRCH1.ODEL2, [3] DSODCRCH1.ODEH1, [2] DSODCRCH1.ODEL1, [1] DSODCRCH1.ODEH0, [0] DSODCRCH1.ODEL0
0x8742AC78 DSMIF1
  [14] DSODWCRCH1.OWNHCD2, [13] DSODWCRCH1.OWNHCD1, [12] DSODWCRCH1.OWNHCD0, [10] DSODWCRCH1.OWNM21, [9] DSODWCRCH1.OWNM11, [8] DSODWCRCH1.OWNM01, [6:3] DSODWCRCH1.OWNM3, [2] DSODWCRCH1.OWNM20, [1] DSODWCRCH1.OWNM10, [0] DSODWCRCH1.OWNM00
0x8742AC80 DSMIF1
  [31] DSODWN0FCRCH1.OWFINT0, [20:16] DSODWN0FCRCH1.OWDR0, [12:8] DSODWN0FCRCH1.OWTH0, [4:0] DSODWN0FCRCH1.OWSN0
0x8742AC84 DSMIF1
  [31] DSODWN1FCRCH1.OWFINT1, [20:16] DSODWN1FCRCH1.OWDR1, [12:8] DSODWN1FCRCH1.OWTH1, [4:0] DSODWN1FCRCH1.OWSN1
0x8742AC88 DSMIF1
  [31] DSODWN2FCRCH1.OWFINT2, [20:16] DSODWN2FCRCH1.OWDR2, [12:8] DSODWN2FCRCH1.OWTH2, [4:0] DSODWN2FCRCH1.OWSN2
0x8742AC90 DSMIF1
  [0] DSCLOCKCH1.WNFCRL
0x8742ACE0 DSMIF1
  [15:0] DSOCLTR0CH1.OCMPTBL0
0x8742ACE4 DSMIF1
  [15:0] DSOCHTR0CH1.OCMPTBH0
0x8742ACE8 DSMIF1
  [15:0] DSOCLTR1CH1.OCMPTBL1
0x8742ACEC DSMIF1
  [15:0] DSOCHTR1CH1.OCMPTBH1
0x8742ACF0 DSMIF1
  [15:0] DSOCLTR2CH1.OCMPTBL2
0x8742ACF4 DSMIF1
  [15:0] DSOCHTR2CH1.OCMPTBH2
0x8742AD20 DSMIF1
  [0] DSCSTRTRCH1.STRTRG
0x8742AD24 DSMIF1
  [0] DSCSTPTRCH1.STPTRG
0x8742AD30 DSMIF1
  [15:0] DSCDRCH1.ADDR
0x8742AD34 DSMIF1
  [15:0] DSCCDRACH1.CDRA
0x8742AD38 DSMIF1
  [15:0] DSCCDRBCH1.CDRB
0x8742AD3C DSMIF1
  [15:0] DSOCDRCH1.ODR
0x8742AD40 DSMIF1
  [15:0] DSCOCDR0CH1.CODR0
0x8742AD44 DSMIF1
  [15:0] DSCOCDR1CH1.CODR1
0x8742AD48 DSMIF1
  [15:0] DSCOCDR2CH1.CODR2
0x8742AD60 DSMIF1
  [29] DSCSRCH1.OC2CMPH, [28] DSCSRCH1.OC2CMPL, [27] DSCSRCH1.OC1CMPH, [26] DSCSRCH1.OC1CMPL, [25] DSCSRCH1.OC0CMPH, [24] DSCSRCH1.OC0CMPL, [n+16] DSCSRCH1.OWD{n}N (n=0..3), [13] DSCSRCH1.OC2FH, [12] DSCSRCH1.OC2FL, [11] DSCSRCH1.OC1FH, [10] DSCSRCH1.OC1FL, [9] DSCSRCH1.OC0FH, [8] DSCSRCH1.OC0FL, [7] DSCSRCH1.CHSTATE, [3] DSCSRCH1.SCF, [2] DSCSRCH1.CBUF, [1] DSCSRCH1.CAUF, [0] DSCSRCH1.DUF
0x8742AD70 DSMIF1
  [n+16] DSCSCRCH1.CLROWD{n}N (n=0..3), [13] DSCSCRCH1.CLROC2FH, [12] DSCSCRCH1.CLROC2FL, [11] DSCSCRCH1.CLROC1FH, [10] DSCSCRCH1.CLROC1FL, [9] DSCSCRCH1.CLROC0FH, [8] DSCSCRCH1.CLROC0FL, [3] DSCSCRCH1.CLRSCF, [2] DSCSCRCH1.CLRCBUF, [1] DSCSCRCH1.CLRCAUF, [0] DSCSCRCH1.CLRDUF
0x8742AD80 DSMIF1
  [n+16] DSICRCH2.OWNE{n} (n=0..3), [13] DSICRCH2.IOEH2, [12] DSICRCH2.IOEL2, [11] DSICRCH2.IOEH1, [10] DSICRCH2.IOEL1, [9] DSICRCH2.IOEH0, [8] DSICRCH2.IOEL0, [3] DSICRCH2.ISE, [2] DSICRCH2.IBUE, [1] DSICRCH2.IAUE, [0] DSICRCH2.IUE
0x8742AD84 DSMIF1
  [13:8] DSCMCCRCH2.CKDIV, [7] DSCMCCRCH2.SEDGE, [0] DSCMCCRCH2.CKDIR
0x8742AD88 DSMIF1
  [20:16] DSCMFCRCH2.CMSH, [15:8] DSCMFCRCH2.CMDEC, [1:0] DSCMFCRCH2.CMSINC
0x8742AD8C DSMIF1
  [23] DSCMCTCRCH2.DEDGE, [17:16] DSCMCTCRCH2.DITSEL, [10:8] DSCMCTCRCH2.CTSELB, [2:0] DSCMCTCRCH2.CTSELA
0x8742ADA0 DSMIF1
  [0] DSEDCRCH2.SDE
0x8742ADA4 DSMIF1
  [28:16] DSSCTSRCH2.SCNTH, [12:0] DSSCTSRCH2.SCNTL
0x8742ADB0 DSMIF1
  [20:16] DSOCFCRCH2.OCSH, [15:8] DSOCFCRCH2.OCDEC, [1:0] DSOCFCRCH2.OCSINC
0x8742ADB4 DSMIF1
  [18] DSODCRCH2.OWFEN2, [17] DSODCRCH2.OWFEN1, [16] DSODCRCH2.OWFEN0, [n+8] DSODCRCH2.OWFE{n} (n=0..3), [5] DSODCRCH2.ODEH2, [4] DSODCRCH2.ODEL2, [3] DSODCRCH2.ODEH1, [2] DSODCRCH2.ODEL1, [1] DSODCRCH2.ODEH0, [0] DSODCRCH2.ODEL0
0x8742ADB8 DSMIF1
  [14] DSODWCRCH2.OWNHCD2, [13] DSODWCRCH2.OWNHCD1, [12] DSODWCRCH2.OWNHCD0, [10] DSODWCRCH2.OWNM21, [9] DSODWCRCH2.OWNM11, [8] DSODWCRCH2.OWNM01, [6:3] DSODWCRCH2.OWNM3, [2] DSODWCRCH2.OWNM20, [1] DSODWCRCH2.OWNM10, [0] DSODWCRCH2.OWNM00
0x8742ADC0 DSMIF1
  [31] DSODWN0FCRCH2.OWFINT0, [20:16] DSODWN0FCRCH2.OWDR0, [12:8] DSODWN0FCRCH2.OWTH0, [4:0] DSODWN0FCRCH2.OWSN0
0x8742ADC4 DSMIF1
  [31] DSODWN1FCRCH2.OWFINT1, [20:16] DSODWN1FCRCH2.OWDR1, [12:8] DSODWN1FCRCH2.OWTH1, [4:0] DSODWN1FCRCH2.OWSN1
0x8742ADC8 DSMIF1
  [31] DSODWN2FCRCH2.OWFINT2, [20:16] DSODWN2FCRCH2.OWDR2, [12:8] DSODWN2FCRCH2.OWTH2, [4:0] DSODWN2FCRCH2.OWSN2
0x8742ADD0 DSMIF1
  [0] DSCLOCKCH2.WNFCRL
0x8742AE20 DSMIF1
  [15:0] DSOCLTR0CH2.OCMPTBL0
0x8742AE24 DSMIF1
  [15:0] DSOCHTR0CH2.OCMPTBH0
0x8742AE28 DSMIF1
  [15:0] DSOCLTR1CH2.OCMPTBL1
0x8742AE2C DSMIF1
  [15:0] DSOCHTR1CH2.OCMPTBH1
0x8742AE30 DSMIF1
  [15:0] DSOCLTR2CH2.OCMPTBL2
0x8742AE34 DSMIF1
  [15:0] DSOCHTR2CH2.OCMPTBH2
0x8742AE60 DSMIF1
  [0] DSCSTRTRCH2.STRTRG
0x8742AE64 DSMIF1
  [0] DSCSTPTRCH2.STPTRG
0x8742AE70 DSMIF1
  [15:0] DSCDRCH2.ADDR
0x8742AE74 DSMIF1
  [15:0] DSCCDRACH2.CDRA
0x8742AE78 DSMIF1
  [15:0] DSCCDRBCH2.CDRB
0x8742AE7C DSMIF1
  [15:0] DSOCDRCH2.ODR
0x8742AE80 DSMIF1
  [15:0] DSCOCDR0CH2.CODR0
0x8742AE84 DSMIF1
  [15:0] DSCOCDR1CH2.CODR1
0x8742AE88 DSMIF1
  [15:0] DSCOCDR2CH2.CODR2
# iorx74m register map
Registers are 32-bit, access not given, no defined reset value unless marked. A register's access mark holds for its fields unless they carry their own. Addresses are absolute; registers are grouped by the start of their names; [hi:lo] are bit positions; {n}, {i} and the like mark numbered series; 'fields as' and 'values as' point back to an identical list.

## SFR (part 4 of 10)
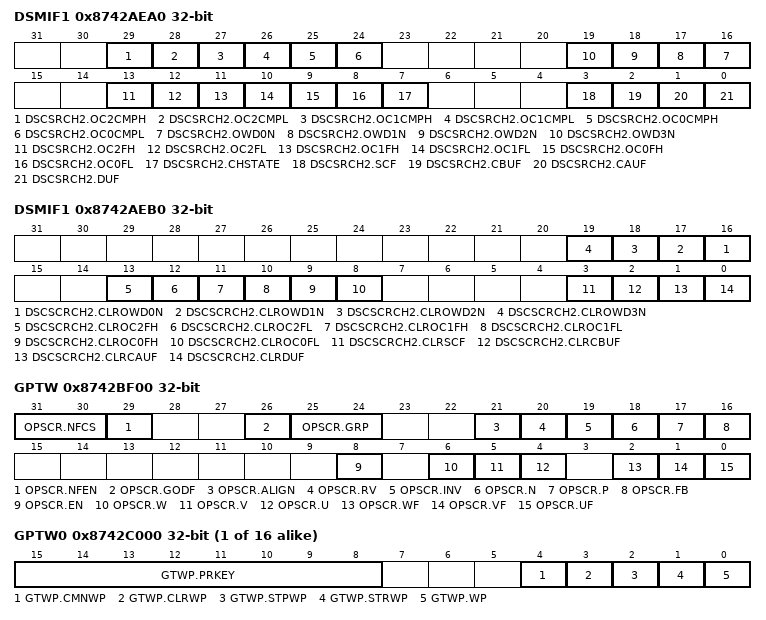
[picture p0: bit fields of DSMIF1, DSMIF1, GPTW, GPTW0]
0x8742AEA0 DSMIF1
  [29] DSCSRCH2.OC2CMPH, [28] DSCSRCH2.OC2CMPL, [27] DSCSRCH2.OC1CMPH, [26] DSCSRCH2.OC1CMPL, [25] DSCSRCH2.OC0CMPH, [24] DSCSRCH2.OC0CMPL, [n+16] DSCSRCH2.OWD{n}N (n=0..3), [13] DSCSRCH2.OC2FH, [12] DSCSRCH2.OC2FL, [11] DSCSRCH2.OC1FH, [10] DSCSRCH2.OC1FL, [9] DSCSRCH2.OC0FH, [8] DSCSRCH2.OC0FL, [7] DSCSRCH2.CHSTATE, [3] DSCSRCH2.SCF, [2] DSCSRCH2.CBUF, [1] DSCSRCH2.CAUF, [0] DSCSRCH2.DUF
0x8742AEB0 DSMIF1
  [n+16] DSCSCRCH2.CLROWD{n}N (n=0..3), [13] DSCSCRCH2.CLROC2FH, [12] DSCSCRCH2.CLROC2FL, [11] DSCSCRCH2.CLROC1FH, [10] DSCSCRCH2.CLROC1FL, [9] DSCSCRCH2.CLROC0FH, [8] DSCSCRCH2.CLROC0FL, [3] DSCSCRCH2.CLRSCF, [2] DSCSCRCH2.CLRCBUF, [1] DSCSCRCH2.CLRCAUF, [0] DSCSCRCH2.CLRDUF
0x8742BF00 GPTW
  [31:30] OPSCR.NFCS, [29] OPSCR.NFEN, [26] OPSCR.GODF, [25:24] OPSCR.GRP, [21] OPSCR.ALIGN, [20] OPSCR.RV, [19] OPSCR.INV, [18] OPSCR.N, [17] OPSCR.P, [16] OPSCR.FB, [8] OPSCR.EN, [6] OPSCR.W, [5] OPSCR.V, [4] OPSCR.U, [2] OPSCR.WF, [1] OPSCR.VF, [0] OPSCR.UF
0x8742BF10 GPT_GTCLK
  [0] GTCLKCR.BPEN
{0x8742C000+0x100*i} GPTW{i} (i=0..15)
  [15:8] GTWP.PRKEY, [4] GTWP.CMNWP, [3] GTWP.CLRWP, [2] GTWP.STPWP, [1] GTWP.STRWP, [0] GTWP.WP
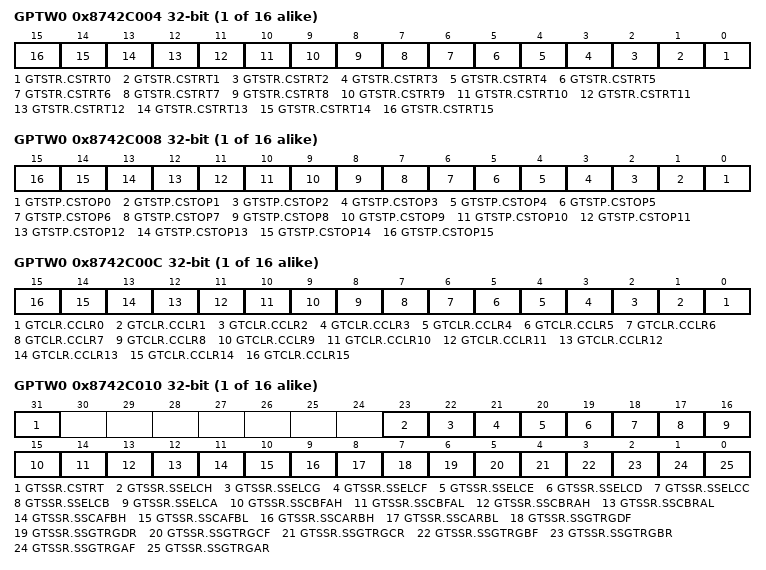
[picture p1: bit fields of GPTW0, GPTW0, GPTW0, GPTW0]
{0x8742C004+0x100*i} GPTW{i} (i=0..15)
  [n] GTSTR.CSTRT{n} (n=0..15)
{0x8742C008+0x100*i} GPTW{i} (i=0..15)
  [n] GTSTP.CSTOP{n} (n=0..15)
{0x8742C00C+0x100*i} GPTW{i} (i=0..15)
  [n] GTCLR.CCLR{n} (n=0..15)
{0x8742C010+0x100*i} GPTW{i} (i=0..15)
  [31] GTSSR.CSTRT, [23] GTSSR.SSELCH, [22] GTSSR.SSELCG, [21] GTSSR.SSELCF, [20] GTSSR.SSELCE, [19] GTSSR.SSELCD, [18] GTSSR.SSELCC, [17] GTSSR.SSELCB, [16] GTSSR.SSELCA, [15] GTSSR.SSCBFAH, [14] GTSSR.SSCBFAL, [13] GTSSR.SSCBRAH, [12] GTSSR.SSCBRAL, [11] GTSSR.SSCAFBH, [10] GTSSR.SSCAFBL, [9] GTSSR.SSCARBH, [8] GTSSR.SSCARBL, [7] GTSSR.SSGTRGDF, [6] GTSSR.SSGTRGDR, [5] GTSSR.SSGTRGCF, [4] GTSSR.SSGTRGCR, [3] GTSSR.SSGTRGBF, [2] GTSSR.SSGTRGBR, [1] GTSSR.SSGTRGAF, [0] GTSSR.SSGTRGAR
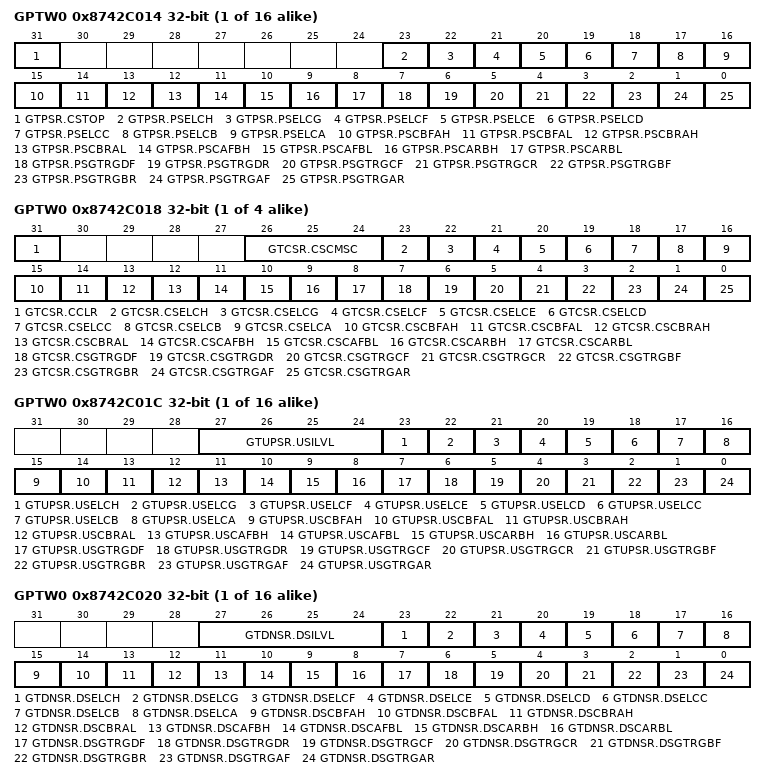
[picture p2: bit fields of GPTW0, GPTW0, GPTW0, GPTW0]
{0x8742C014+0x100*i} GPTW{i} (i=0..15)
  [31] GTPSR.CSTOP, [23] GTPSR.PSELCH, [22] GTPSR.PSELCG, [21] GTPSR.PSELCF, [20] GTPSR.PSELCE, [19] GTPSR.PSELCD, [18] GTPSR.PSELCC, [17] GTPSR.PSELCB, [16] GTPSR.PSELCA, [15] GTPSR.PSCBFAH, [14] GTPSR.PSCBFAL, [13] GTPSR.PSCBRAH, [12] GTPSR.PSCBRAL, [11] GTPSR.PSCAFBH, [10] GTPSR.PSCAFBL, [9] GTPSR.PSCARBH, [8] GTPSR.PSCARBL, [7] GTPSR.PSGTRGDF, [6] GTPSR.PSGTRGDR, [5] GTPSR.PSGTRGCF, [4] GTPSR.PSGTRGCR, [3] GTPSR.PSGTRGBF, [2] GTPSR.PSGTRGBR, [1] GTPSR.PSGTRGAF, [0] GTPSR.PSGTRGAR
{0x8742C018+0x100*i} GPTW{i} (i=0..3)
  [31] GTCSR.CCLR, [26:24] GTCSR.CSCMSC, [23] GTCSR.CSELCH, [22] GTCSR.CSELCG, [21] GTCSR.CSELCF, [20] GTCSR.CSELCE, [19] GTCSR.CSELCD, [18] GTCSR.CSELCC, [17] GTCSR.CSELCB, [16] GTCSR.CSELCA, [15] GTCSR.CSCBFAH, [14] GTCSR.CSCBFAL, [13] GTCSR.CSCBRAH, [12] GTCSR.CSCBRAL, [11] GTCSR.CSCAFBH, [10] GTCSR.CSCAFBL, [9] GTCSR.CSCARBH, [8] GTCSR.CSCARBL, [7] GTCSR.CSGTRGDF, [6] GTCSR.CSGTRGDR, [5] GTCSR.CSGTRGCF, [4] GTCSR.CSGTRGCR, [3] GTCSR.CSGTRGBF, [2] GTCSR.CSGTRGBR, [1] GTCSR.CSGTRGAF, [0] GTCSR.CSGTRGAR
{0x8742C01C+0x100*i} GPTW{i} (i=0..15)
  [27:24] GTUPSR.USILVL, [23] GTUPSR.USELCH, [22] GTUPSR.USELCG, [21] GTUPSR.USELCF, [20] GTUPSR.USELCE, [19] GTUPSR.USELCD, [18] GTUPSR.USELCC, [17] GTUPSR.USELCB, [16] GTUPSR.USELCA, [15] GTUPSR.USCBFAH, [14] GTUPSR.USCBFAL, [13] GTUPSR.USCBRAH, [12] GTUPSR.USCBRAL, [11] GTUPSR.USCAFBH, [10] GTUPSR.USCAFBL, [9] GTUPSR.USCARBH, [8] GTUPSR.USCARBL, [7] GTUPSR.USGTRGDF, [6] GTUPSR.USGTRGDR, [5] GTUPSR.USGTRGCF, [4] GTUPSR.USGTRGCR, [3] GTUPSR.USGTRGBF, [2] GTUPSR.USGTRGBR, [1] GTUPSR.USGTRGAF, [0] GTUPSR.USGTRGAR
{0x8742C020+0x100*i} GPTW{i} (i=0..15)
  [27:24] GTDNSR.DSILVL, [23] GTDNSR.DSELCH, [22] GTDNSR.DSELCG, [21] GTDNSR.DSELCF, [20] GTDNSR.DSELCE, [19] GTDNSR.DSELCD, [18] GTDNSR.DSELCC, [17] GTDNSR.DSELCB, [16] GTDNSR.DSELCA, [15] GTDNSR.DSCBFAH, [14] GTDNSR.DSCBFAL, [13] GTDNSR.DSCBRAH, [12] GTDNSR.DSCBRAL, [11] GTDNSR.DSCAFBH, [10] GTDNSR.DSCAFBL, [9] GTDNSR.DSCARBH, [8] GTDNSR.DSCARBL, [7] GTDNSR.DSGTRGDF, [6] GTDNSR.DSGTRGDR, [5] GTDNSR.DSGTRGCF, [4] GTDNSR.DSGTRGCR, [3] GTDNSR.DSGTRGBF, [2] GTDNSR.DSGTRGBR, [1] GTDNSR.DSGTRGAF, [0] GTDNSR.DSGTRGAR
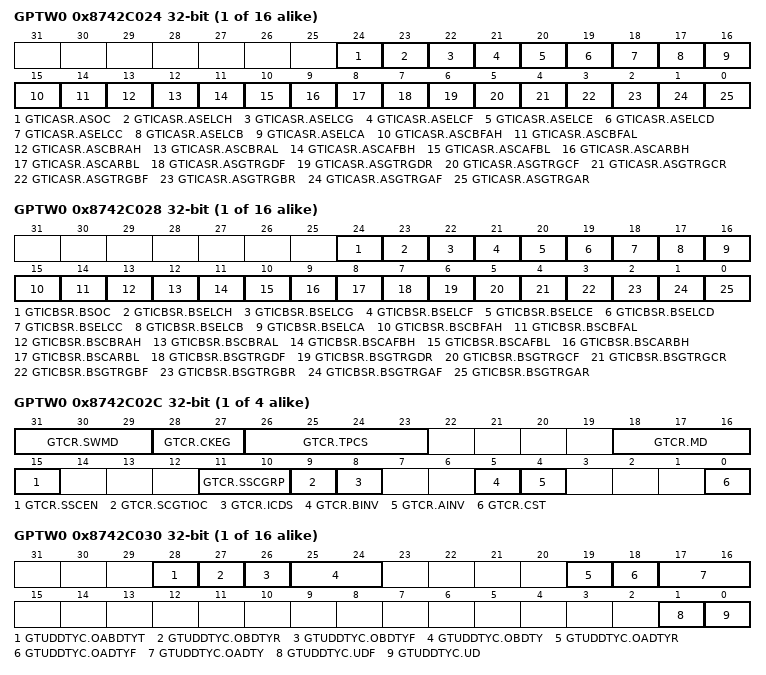
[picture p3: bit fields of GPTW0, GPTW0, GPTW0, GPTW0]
{0x8742C024+0x100*i} GPTW{i} (i=0..15)
  [24] GTICASR.ASOC, [23] GTICASR.ASELCH, [22] GTICASR.ASELCG, [21] GTICASR.ASELCF, [20] GTICASR.ASELCE, [19] GTICASR.ASELCD, [18] GTICASR.ASELCC, [17] GTICASR.ASELCB, [16] GTICASR.ASELCA, [15] GTICASR.ASCBFAH, [14] GTICASR.ASCBFAL, [13] GTICASR.ASCBRAH, [12] GTICASR.ASCBRAL, [11] GTICASR.ASCAFBH, [10] GTICASR.ASCAFBL, [9] GTICASR.ASCARBH, [8] GTICASR.ASCARBL, [7] GTICASR.ASGTRGDF, [6] GTICASR.ASGTRGDR, [5] GTICASR.ASGTRGCF, [4] GTICASR.ASGTRGCR, [3] GTICASR.ASGTRGBF, [2] GTICASR.ASGTRGBR, [1] GTICASR.ASGTRGAF, [0] GTICASR.ASGTRGAR
{0x8742C028+0x100*i} GPTW{i} (i=0..15)
  [24] GTICBSR.BSOC, [23] GTICBSR.BSELCH, [22] GTICBSR.BSELCG, [21] GTICBSR.BSELCF, [20] GTICBSR.BSELCE, [19] GTICBSR.BSELCD, [18] GTICBSR.BSELCC, [17] GTICBSR.BSELCB, [16] GTICBSR.BSELCA, [15] GTICBSR.BSCBFAH, [14] GTICBSR.BSCBFAL, [13] GTICBSR.BSCBRAH, [12] GTICBSR.BSCBRAL, [11] GTICBSR.BSCAFBH, [10] GTICBSR.BSCAFBL, [9] GTICBSR.BSCARBH, [8] GTICBSR.BSCARBL, [7] GTICBSR.BSGTRGDF, [6] GTICBSR.BSGTRGDR, [5] GTICBSR.BSGTRGCF, [4] GTICBSR.BSGTRGCR, [3] GTICBSR.BSGTRGBF, [2] GTICBSR.BSGTRGBR, [1] GTICBSR.BSGTRGAF, [0] GTICBSR.BSGTRGAR
{0x8742C02C+0x100*i} GPTW{i} (i=0..3)
  [31:29] GTCR.SWMD, [28:27] GTCR.CKEG, [26:23] GTCR.TPCS, [18:16] GTCR.MD, [15] GTCR.SSCEN, [11:10] GTCR.SSCGRP, [9] GTCR.SCGTIOC, [8] GTCR.ICDS, [5] GTCR.BINV, [4] GTCR.AINV, [0] GTCR.CST
{0x8742C030+0x100*i} GPTW{i} (i=0..15)
  [28] GTUDDTYC.OABDTYT, [27] GTUDDTYC.OBDTYR, [26] GTUDDTYC.OBDTYF, [25:24] GTUDDTYC.OBDTY, [19] GTUDDTYC.OADTYR, [18] GTUDDTYC.OADTYF, [17:16] GTUDDTYC.OADTY, [1] GTUDDTYC.UDF, [0] GTUDDTYC.UD
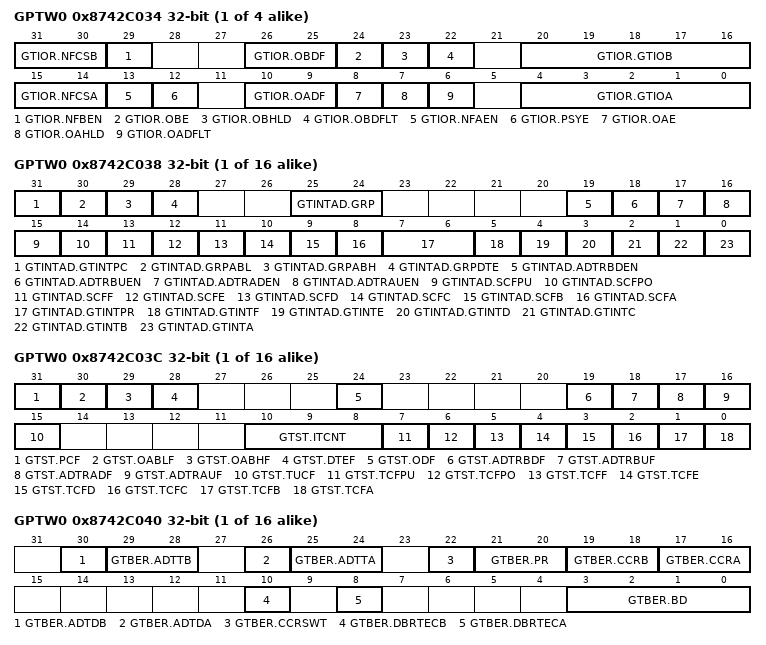
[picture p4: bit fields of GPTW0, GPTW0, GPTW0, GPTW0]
{0x8742C034+0x100*i} GPTW{i} (i=0..3)
  [31:30] GTIOR.NFCSB, [29] GTIOR.NFBEN, [26:25] GTIOR.OBDF, [24] GTIOR.OBE, [23] GTIOR.OBHLD, [22] GTIOR.OBDFLT, [20:16] GTIOR.GTIOB, [15:14] GTIOR.NFCSA, [13] GTIOR.NFAEN, [12] GTIOR.PSYE, [10:9] GTIOR.OADF, [8] GTIOR.OAE, [7] GTIOR.OAHLD, [6] GTIOR.OADFLT, [4:0] GTIOR.GTIOA
{0x8742C038+0x100*i} GPTW{i} (i=0..15)
  [31] GTINTAD.GTINTPC, [30] GTINTAD.GRPABL, [29] GTINTAD.GRPABH, [28] GTINTAD.GRPDTE, [25:24] GTINTAD.GRP, [19] GTINTAD.ADTRBDEN, [18] GTINTAD.ADTRBUEN, [17] GTINTAD.ADTRADEN, [16] GTINTAD.ADTRAUEN, [15] GTINTAD.SCFPU, [14] GTINTAD.SCFPO, [13] GTINTAD.SCFF, [12] GTINTAD.SCFE, [11] GTINTAD.SCFD, [10] GTINTAD.SCFC, [9] GTINTAD.SCFB, [8] GTINTAD.SCFA, [7:6] GTINTAD.GTINTPR, [5] GTINTAD.GTINTF, [4] GTINTAD.GTINTE, [3] GTINTAD.GTINTD, [2] GTINTAD.GTINTC, [1] GTINTAD.GTINTB, [0] GTINTAD.GTINTA
{0x8742C03C+0x100*i} GPTW{i} (i=0..15)
  [31] GTST.PCF, [30] GTST.OABLF, [29] GTST.OABHF, [28] GTST.DTEF, [24] GTST.ODF, [19] GTST.ADTRBDF, [18] GTST.ADTRBUF, [17] GTST.ADTRADF, [16] GTST.ADTRAUF, [15] GTST.TUCF, [10:8] GTST.ITCNT, [7] GTST.TCFPU, [6] GTST.TCFPO, [5] GTST.TCFF, [4] GTST.TCFE, [3] GTST.TCFD, [2] GTST.TCFC, [1] GTST.TCFB, [0] GTST.TCFA
{0x8742C040+0x100*i} GPTW{i} (i=0..15)
  [30] GTBER.ADTDB, [29:28] GTBER.ADTTB, [26] GTBER.ADTDA, [25:24] GTBER.ADTTA, [22] GTBER.CCRSWT, [21:20] GTBER.PR, [19:18] GTBER.CCRB, [17:16] GTBER.CCRA, [10] GTBER.DBRTECB, [8] GTBER.DBRTECA, [3:0] GTBER.BD
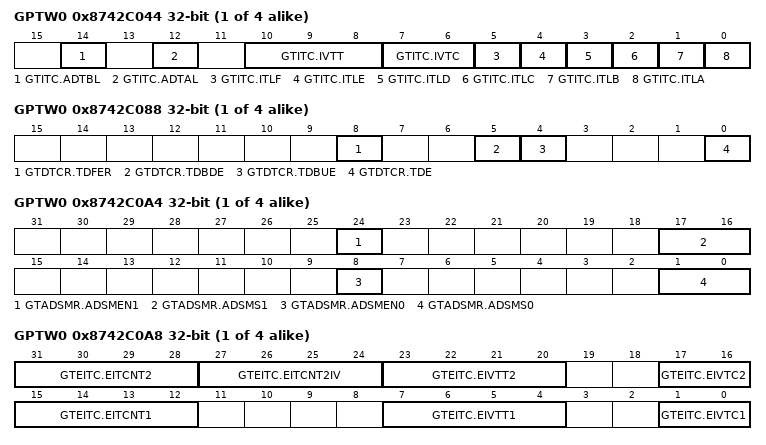
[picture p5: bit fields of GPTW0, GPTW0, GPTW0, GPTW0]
{0x8742C044+0x100*i} GPTW{i} (i=0..3)
  [14] GTITC.ADTBL, [12] GTITC.ADTAL, [10:8] GTITC.IVTT, [7:6] GTITC.IVTC, [5] GTITC.ITLF, [4] GTITC.ITLE, [3] GTITC.ITLD, [2] GTITC.ITLC, [1] GTITC.ITLB, [0] GTITC.ITLA
{0x8742C088+0x100*i} GPTW{i} (i=0..3)
  [8] GTDTCR.TDFER, [5] GTDTCR.TDBDE, [4] GTDTCR.TDBUE, [0] GTDTCR.TDE
{0x8742C09C+0x100*i} GPTW{i} (i=0..3)
  [1:0] GTSOS.SOS
{0x8742C0A0+0x100*i} GPTW{i} (i=0..3)
  [0] GTSOTR.SOTR
{0x8742C0A4+0x100*i} GPTW{i} (i=0..3)
  [24] GTADSMR.ADSMEN1, [17:16] GTADSMR.ADSMS1, [8] GTADSMR.ADSMEN0, [1:0] GTADSMR.ADSMS0
{0x8742C0A8+0x100*i} GPTW{i} (i=0..3)
  [31:28] GTEITC.EITCNT2, [27:24] GTEITC.EITCNT2IV, [23:20] GTEITC.EIVTT2, [17:16] GTEITC.EIVTC2, [15:12] GTEITC.EITCNT1, [7:4] GTEITC.EIVTT1, [1:0] GTEITC.EIVTC1
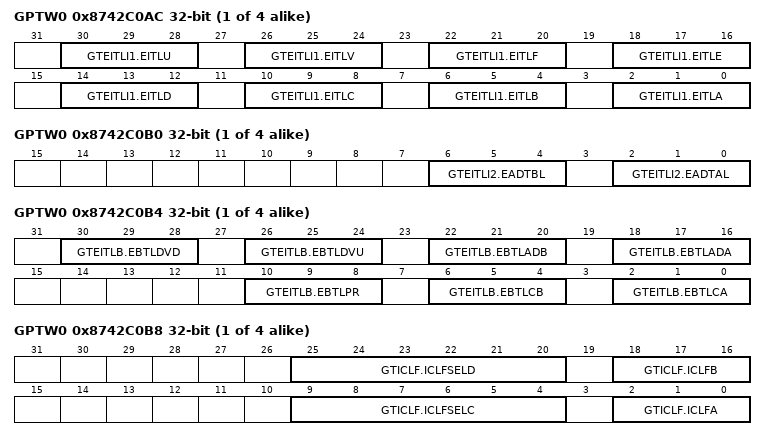
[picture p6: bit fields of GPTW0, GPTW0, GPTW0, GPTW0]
{0x8742C0AC+0x100*i} GPTW{i} (i=0..3)
  [30:28] GTEITLI1.EITLU, [26:24] GTEITLI1.EITLV, [22:20] GTEITLI1.EITLF, [18:16] GTEITLI1.EITLE, [14:12] GTEITLI1.EITLD, [10:8] GTEITLI1.EITLC, [6:4] GTEITLI1.EITLB, [2:0] GTEITLI1.EITLA
{0x8742C0B0+0x100*i} GPTW{i} (i=0..3)
  [6:4] GTEITLI2.EADTBL, [2:0] GTEITLI2.EADTAL
{0x8742C0B4+0x100*i} GPTW{i} (i=0..3)
  [30:28] GTEITLB.EBTLDVD, [26:24] GTEITLB.EBTLDVU, [22:20] GTEITLB.EBTLADB, [18:16] GTEITLB.EBTLADA, [10:8] GTEITLB.EBTLPR, [6:4] GTEITLB.EBTLCB, [2:0] GTEITLB.EBTLCA
{0x8742C0B8+0x100*i} GPTW{i} (i=0..3)
  [25:20] GTICLF.ICLFSELD, [18:16] GTICLF.ICLFB, [9:4] GTICLF.ICLFSELC, [2:0] GTICLF.ICLFA
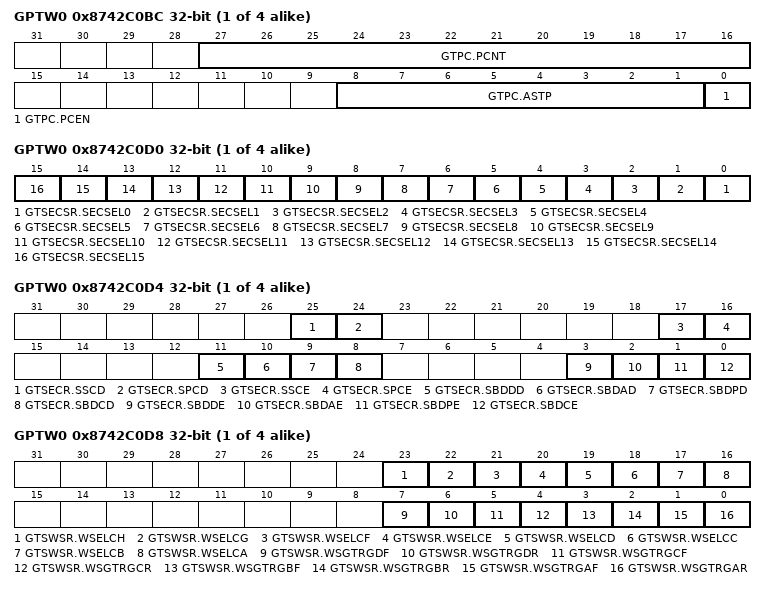
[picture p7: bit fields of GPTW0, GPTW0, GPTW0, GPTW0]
{0x8742C0BC+0x100*i} GPTW{i} (i=0..3)
  [27:16] GTPC.PCNT, [8:1] GTPC.ASTP, [0] GTPC.PCEN
{0x8742C0D0+0x100*i} GPTW{i} (i=0..3)
  [n] GTSECSR.SECSEL{n} (n=0..15)
{0x8742C0D4+0x100*i} GPTW{i} (i=0..3)
  [25] GTSECR.SSCD, [24] GTSECR.SPCD, [17] GTSECR.SSCE, [16] GTSECR.SPCE, [11] GTSECR.SBDDD, [10] GTSECR.SBDAD, [9] GTSECR.SBDPD, [8] GTSECR.SBDCD, [3] GTSECR.SBDDE, [2] GTSECR.SBDAE, [1] GTSECR.SBDPE, [0] GTSECR.SBDCE
{0x8742C0D8+0x100*i} GPTW{i} (i=0..3)
  [23] GTSWSR.WSELCH, [22] GTSWSR.WSELCG, [21] GTSWSR.WSELCF, [20] GTSWSR.WSELCE, [19] GTSWSR.WSELCD, [18] GTSWSR.WSELCC, [17] GTSWSR.WSELCB, [16] GTSWSR.WSELCA, [7] GTSWSR.WSGTRGDF, [6] GTSWSR.WSGTRGDR, [5] GTSWSR.WSGTRGCF, [4] GTSWSR.WSGTRGCR, [3] GTSWSR.WSGTRGBF, [2] GTSWSR.WSGTRGBR, [1] GTSWSR.WSGTRGAF, [0] GTSWSR.WSGTRGAR
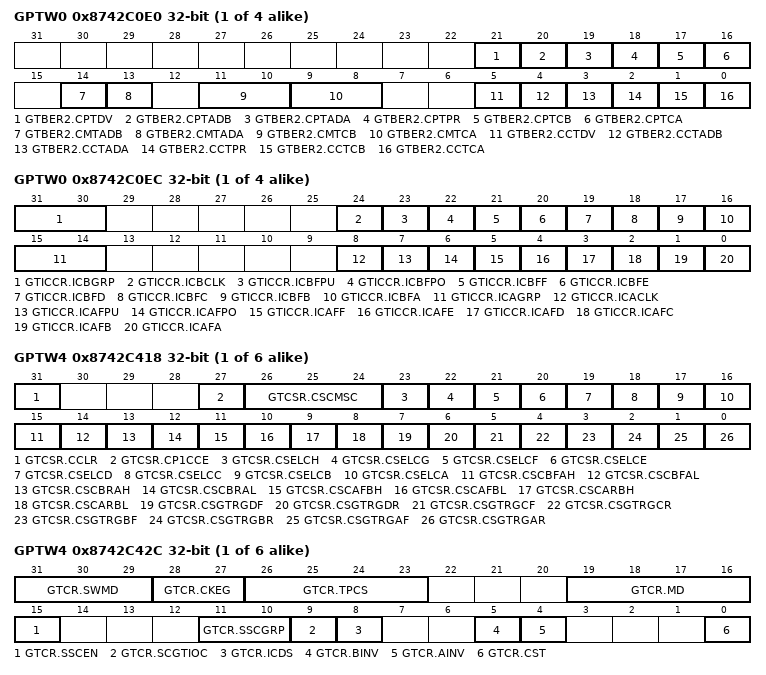
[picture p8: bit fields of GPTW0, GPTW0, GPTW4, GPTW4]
{0x8742C0E0+0x100*i} GPTW{i} (i=0..3)
  [21] GTBER2.CPTDV, [20] GTBER2.CPTADB, [19] GTBER2.CPTADA, [18] GTBER2.CPTPR, [17] GTBER2.CPTCB, [16] GTBER2.CPTCA, [14] GTBER2.CMTADB, [13] GTBER2.CMTADA, [11:10] GTBER2.CMTCB, [9:8] GTBER2.CMTCA, [5] GTBER2.CCTDV, [4] GTBER2.CCTADB, [3] GTBER2.CCTADA, [2] GTBER2.CCTPR, [1] GTBER2.CCTCB, [0] GTBER2.CCTCA
{0x8742C0EC+0x100*i} GPTW{i} (i=0..3)
  [31:30] GTICCR.ICBGRP, [24] GTICCR.ICBCLK, [23] GTICCR.ICBFPU, [22] GTICCR.ICBFPO, [21] GTICCR.ICBFF, [20] GTICCR.ICBFE, [19] GTICCR.ICBFD, [18] GTICCR.ICBFC, [17] GTICCR.ICBFB, [16] GTICCR.ICBFA, [15:14] GTICCR.ICAGRP, [8] GTICCR.ICACLK, [7] GTICCR.ICAFPU, [6] GTICCR.ICAFPO, [5] GTICCR.ICAFF, [4] GTICCR.ICAFE, [3] GTICCR.ICAFD, [2] GTICCR.ICAFC, [1] GTICCR.ICAFB, [0] GTICCR.ICAFA
{0x8742C0F0+0x100*i} GPTW{i} (i=0..3)
  [16] GTSYNCFCR.SYST
{0x8742C018+0x100*i} GPTW{i} (i=4..9)
  [31] GTCSR.CCLR, [27] GTCSR.CP1CCE, [26:24] GTCSR.CSCMSC, [23] GTCSR.CSELCH, [22] GTCSR.CSELCG, [21] GTCSR.CSELCF, [20] GTCSR.CSELCE, [19] GTCSR.CSELCD, [18] GTCSR.CSELCC, [17] GTCSR.CSELCB, [16] GTCSR.CSELCA, [15] GTCSR.CSCBFAH, [14] GTCSR.CSCBFAL, [13] GTCSR.CSCBRAH, [12] GTCSR.CSCBRAL, [11] GTCSR.CSCAFBH, [10] GTCSR.CSCAFBL, [9] GTCSR.CSCARBH, [8] GTCSR.CSCARBL, [7] GTCSR.CSGTRGDF, [6] GTCSR.CSGTRGDR, [5] GTCSR.CSGTRGCF, [4] GTCSR.CSGTRGCR, [3] GTCSR.CSGTRGBF, [2] GTCSR.CSGTRGBR, [1] GTCSR.CSGTRGAF, [0] GTCSR.CSGTRGAR
{0x8742C02C+0x100*i} GPTW{i} (i=4..9)
  [31:29] GTCR.SWMD, [28:27] GTCR.CKEG, [26:23] GTCR.TPCS, [19:16] GTCR.MD, [15] GTCR.SSCEN, [11:10] GTCR.SSCGRP, [9] GTCR.SCGTIOC, [8] GTCR.ICDS, [5] GTCR.BINV, [4] GTCR.AINV, [0] GTCR.CST
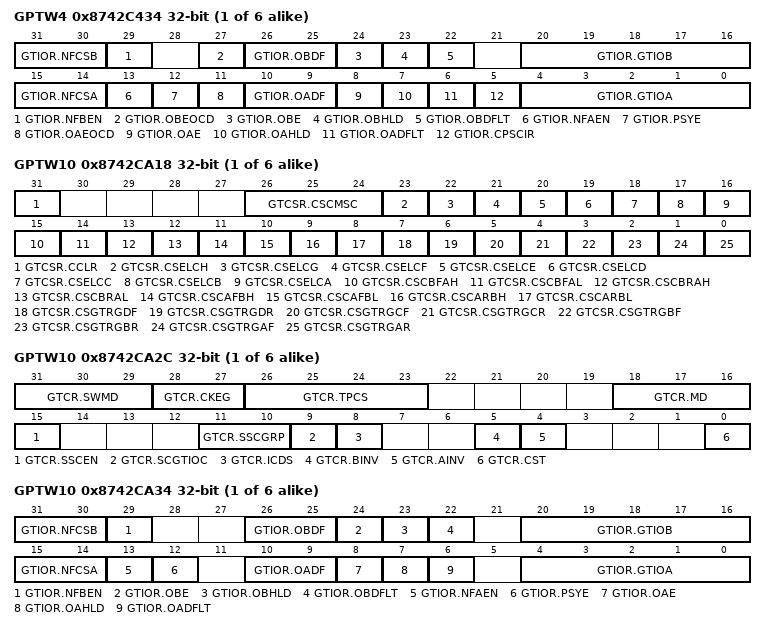
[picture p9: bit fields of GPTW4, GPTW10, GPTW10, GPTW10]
{0x8742C034+0x100*i} GPTW{i} (i=4..9)
  [31:30] GTIOR.NFCSB, [29] GTIOR.NFBEN, [27] GTIOR.OBEOCD, [26:25] GTIOR.OBDF, [24] GTIOR.OBE, [23] GTIOR.OBHLD, [22] GTIOR.OBDFLT, [20:16] GTIOR.GTIOB, [15:14] GTIOR.NFCSA, [13] GTIOR.NFAEN, [12] GTIOR.PSYE, [11] GTIOR.OAEOCD, [10:9] GTIOR.OADF, [8] GTIOR.OAE, [7] GTIOR.OAHLD, [6] GTIOR.OADFLT, [5] GTIOR.CPSCIR, [4:0] GTIOR.GTIOA
{0x8742C018+0x100*i} GPTW{i} (i=10..15)
  [31] GTCSR.CCLR, [26:24] GTCSR.CSCMSC, [23] GTCSR.CSELCH, [22] GTCSR.CSELCG, [21] GTCSR.CSELCF, [20] GTCSR.CSELCE, [19] GTCSR.CSELCD, [18] GTCSR.CSELCC, [17] GTCSR.CSELCB, [16] GTCSR.CSELCA, [15] GTCSR.CSCBFAH, [14] GTCSR.CSCBFAL, [13] GTCSR.CSCBRAH, [12] GTCSR.CSCBRAL, [11] GTCSR.CSCAFBH, [10] GTCSR.CSCAFBL, [9] GTCSR.CSCARBH, [8] GTCSR.CSCARBL, [7] GTCSR.CSGTRGDF, [6] GTCSR.CSGTRGDR, [5] GTCSR.CSGTRGCF, [4] GTCSR.CSGTRGCR, [3] GTCSR.CSGTRGBF, [2] GTCSR.CSGTRGBR, [1] GTCSR.CSGTRGAF, [0] GTCSR.CSGTRGAR
{0x8742C02C+0x100*i} GPTW{i} (i=10..15)
  [31:29] GTCR.SWMD, [28:27] GTCR.CKEG, [26:23] GTCR.TPCS, [18:16] GTCR.MD, [15] GTCR.SSCEN, [11:10] GTCR.SSCGRP, [9] GTCR.SCGTIOC, [8] GTCR.ICDS, [5] GTCR.BINV, [4] GTCR.AINV, [0] GTCR.CST
{0x8742C034+0x100*i} GPTW{i} (i=10..15)
  [31:30] GTIOR.NFCSB, [29] GTIOR.NFBEN, [26:25] GTIOR.OBDF, [24] GTIOR.OBE, [23] GTIOR.OBHLD, [22] GTIOR.OBDFLT, [20:16] GTIOR.GTIOB, [15:14] GTIOR.NFCSA, [13] GTIOR.NFAEN, [12] GTIOR.PSYE, [10:9] GTIOR.OADF, [8] GTIOR.OAE, [7] GTIOR.OAHLD, [6] GTIOR.OADFLT, [4:0] GTIOR.GTIOA
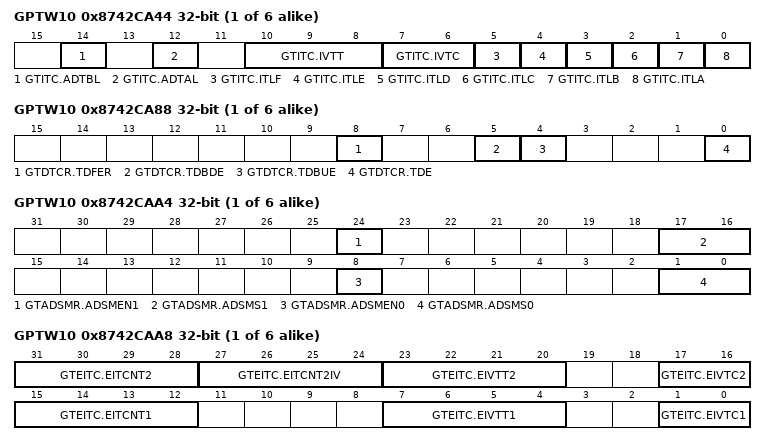
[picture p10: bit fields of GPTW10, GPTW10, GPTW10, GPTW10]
{0x8742C044+0x100*i} GPTW{i} (i=10..15)
  [14] GTITC.ADTBL, [12] GTITC.ADTAL, [10:8] GTITC.IVTT, [7:6] GTITC.IVTC, [5] GTITC.ITLF, [4] GTITC.ITLE, [3] GTITC.ITLD, [2] GTITC.ITLC, [1] GTITC.ITLB, [0] GTITC.ITLA
{0x8742C088+0x100*i} GPTW{i} (i=10..15)
  [8] GTDTCR.TDFER, [5] GTDTCR.TDBDE, [4] GTDTCR.TDBUE, [0] GTDTCR.TDE
{0x8742C09C+0x100*i} GPTW{i} (i=10..15)
  [1:0] GTSOS.SOS
{0x8742C0A0+0x100*i} GPTW{i} (i=10..15)
  [0] GTSOTR.SOTR
{0x8742C0A4+0x100*i} GPTW{i} (i=10..15)
  [24] GTADSMR.ADSMEN1, [17:16] GTADSMR.ADSMS1, [8] GTADSMR.ADSMEN0, [1:0] GTADSMR.ADSMS0
{0x8742C0A8+0x100*i} GPTW{i} (i=10..15)
  [31:28] GTEITC.EITCNT2, [27:24] GTEITC.EITCNT2IV, [23:20] GTEITC.EIVTT2, [17:16] GTEITC.EIVTC2, [15:12] GTEITC.EITCNT1, [7:4] GTEITC.EIVTT1, [1:0] GTEITC.EIVTC1
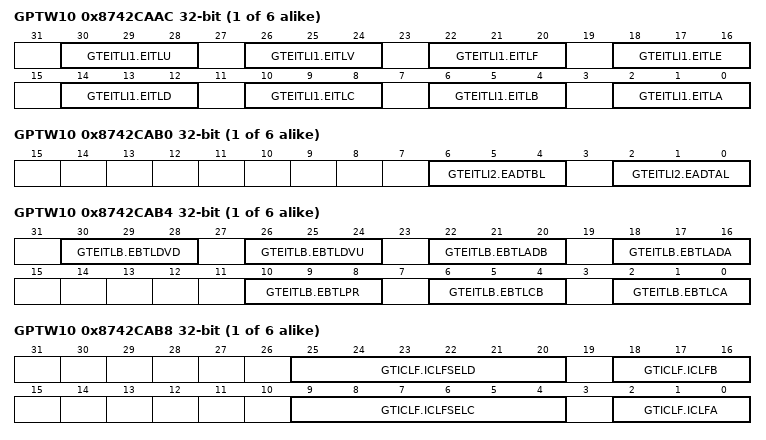
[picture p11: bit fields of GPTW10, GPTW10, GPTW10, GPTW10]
{0x8742C0AC+0x100*i} GPTW{i} (i=10..15)
  [30:28] GTEITLI1.EITLU, [26:24] GTEITLI1.EITLV, [22:20] GTEITLI1.EITLF, [18:16] GTEITLI1.EITLE, [14:12] GTEITLI1.EITLD, [10:8] GTEITLI1.EITLC, [6:4] GTEITLI1.EITLB, [2:0] GTEITLI1.EITLA
{0x8742C0B0+0x100*i} GPTW{i} (i=10..15)
  [6:4] GTEITLI2.EADTBL, [2:0] GTEITLI2.EADTAL
{0x8742C0B4+0x100*i} GPTW{i} (i=10..15)
  [30:28] GTEITLB.EBTLDVD, [26:24] GTEITLB.EBTLDVU, [22:20] GTEITLB.EBTLADB, [18:16] GTEITLB.EBTLADA, [10:8] GTEITLB.EBTLPR, [6:4] GTEITLB.EBTLCB, [2:0] GTEITLB.EBTLCA
{0x8742C0B8+0x100*i} GPTW{i} (i=10..15)
  [25:20] GTICLF.ICLFSELD, [18:16] GTICLF.ICLFB, [9:4] GTICLF.ICLFSELC, [2:0] GTICLF.ICLFA
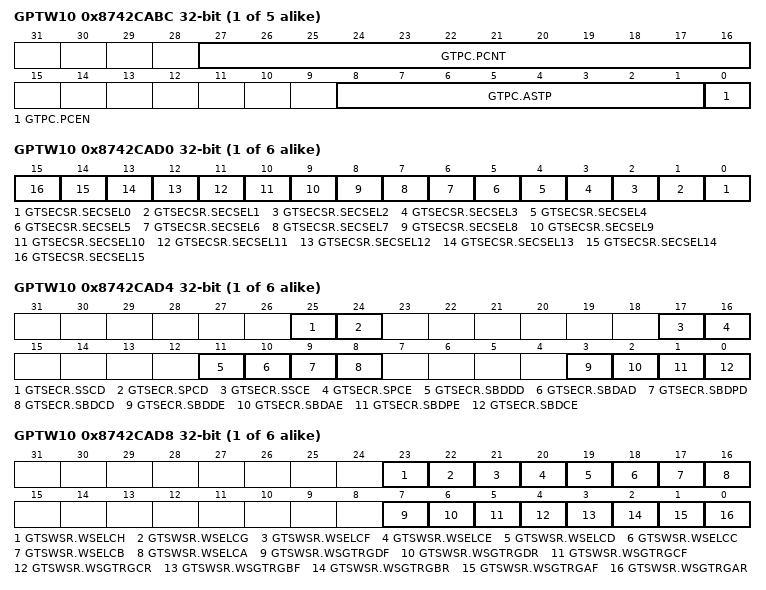
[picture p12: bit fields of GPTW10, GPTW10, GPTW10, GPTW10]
{0x8742C0BC+0x100*i} GPTW{i} (i=10..14)
  [27:16] GTPC.PCNT, [8:1] GTPC.ASTP, [0] GTPC.PCEN
{0x8742C0D0+0x100*i} GPTW{i} (i=10..15)
  [n] GTSECSR.SECSEL{n} (n=0..15)
{0x8742C0D4+0x100*i} GPTW{i} (i=10..15)
  [25] GTSECR.SSCD, [24] GTSECR.SPCD, [17] GTSECR.SSCE, [16] GTSECR.SPCE, [11] GTSECR.SBDDD, [10] GTSECR.SBDAD, [9] GTSECR.SBDPD, [8] GTSECR.SBDCD, [3] GTSECR.SBDDE, [2] GTSECR.SBDAE, [1] GTSECR.SBDPE, [0] GTSECR.SBDCE
{0x8742C0D8+0x100*i} GPTW{i} (i=10..15)
  [23] GTSWSR.WSELCH, [22] GTSWSR.WSELCG, [21] GTSWSR.WSELCF, [20] GTSWSR.WSELCE, [19] GTSWSR.WSELCD, [18] GTSWSR.WSELCC, [17] GTSWSR.WSELCB, [16] GTSWSR.WSELCA, [7] GTSWSR.WSGTRGDF, [6] GTSWSR.WSGTRGDR, [5] GTSWSR.WSGTRGCF, [4] GTSWSR.WSGTRGCR, [3] GTSWSR.WSGTRGBF, [2] GTSWSR.WSGTRGBR, [1] GTSWSR.WSGTRGAF, [0] GTSWSR.WSGTRGAR
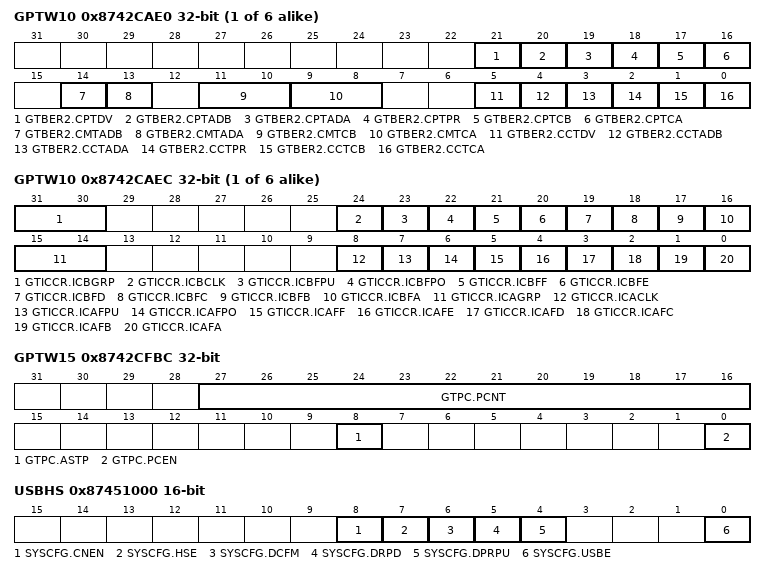
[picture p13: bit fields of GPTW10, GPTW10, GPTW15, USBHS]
{0x8742C0E0+0x100*i} GPTW{i} (i=10..15)
  [21] GTBER2.CPTDV, [20] GTBER2.CPTADB, [19] GTBER2.CPTADA, [18] GTBER2.CPTPR, [17] GTBER2.CPTCB, [16] GTBER2.CPTCA, [14] GTBER2.CMTADB, [13] GTBER2.CMTADA, [11:10] GTBER2.CMTCB, [9:8] GTBER2.CMTCA, [5] GTBER2.CCTDV, [4] GTBER2.CCTADB, [3] GTBER2.CCTADA, [2] GTBER2.CCTPR, [1] GTBER2.CCTCB, [0] GTBER2.CCTCA
{0x8742C0EC+0x100*i} GPTW{i} (i=10..15)
  [31:30] GTICCR.ICBGRP, [24] GTICCR.ICBCLK, [23] GTICCR.ICBFPU, [22] GTICCR.ICBFPO, [21] GTICCR.ICBFF, [20] GTICCR.ICBFE, [19] GTICCR.ICBFD, [18] GTICCR.ICBFC, [17] GTICCR.ICBFB, [16] GTICCR.ICBFA, [15:14] GTICCR.ICAGRP, [8] GTICCR.ICACLK, [7] GTICCR.ICAFPU, [6] GTICCR.ICAFPO, [5] GTICCR.ICAFF, [4] GTICCR.ICAFE, [3] GTICCR.ICAFD, [2] GTICCR.ICAFC, [1] GTICCR.ICAFB, [0] GTICCR.ICAFA
{0x8742C0F0+0x100*i} GPTW{i} (i=10..14)
  [16] GTSYNCFCR.SYST
0x8742CFBC GPTW15
  [27:16] GTPC.PCNT, [8] GTPC.ASTP, [0] GTPC.PCEN
0x8742CFF0 GPTW15
  [1:0] GTSYNCSCR.SYSG
0x87451000 USBHS 16-bit
  [8] SYSCFG.CNEN, [7] SYSCFG.HSE, [6] SYSCFG.DCFM, [5] SYSCFG.DRPD, [4] SYSCFG.DPRPU, [0] SYSCFG.USBE
0x87451002 USBHS 16-bit
  [3:0] BUSWAIT.BWAIT
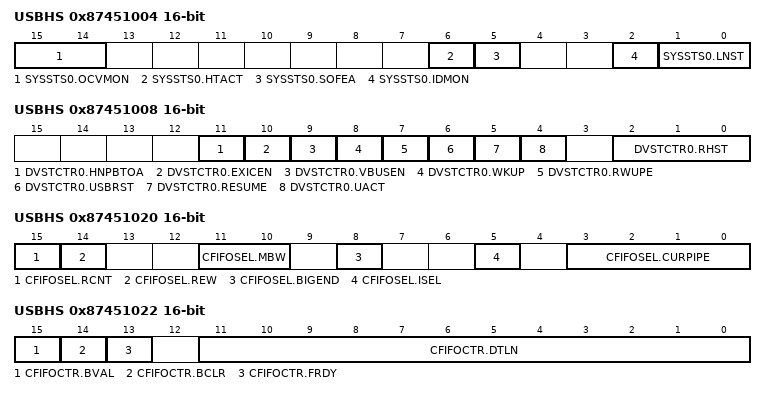
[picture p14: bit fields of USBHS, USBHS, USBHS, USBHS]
0x87451004 USBHS 16-bit
  [15:14] SYSSTS0.OCVMON, [6] SYSSTS0.HTACT, [5] SYSSTS0.SOFEA, [2] SYSSTS0.IDMON, [1:0] SYSSTS0.LNST
0x87451006 USBHS 16-bit
  [0] PLLSTA.PLLLOCK
0x87451008 USBHS 16-bit
  [11] DVSTCTR0.HNPBTOA, [10] DVSTCTR0.EXICEN, [9] DVSTCTR0.VBUSEN, [8] DVSTCTR0.WKUP, [7] DVSTCTR0.RWUPE, [6] DVSTCTR0.USBRST, [5] DVSTCTR0.RESUME, [4] DVSTCTR0.UACT, [2:0] DVSTCTR0.RHST
0x8745100C USBHS 16-bit
  [3:0] TESTMODE.UTST
0x87451020 USBHS 16-bit
  [15] CFIFOSEL.RCNT, [14] CFIFOSEL.REW, [11:10] CFIFOSEL.MBW, [8] CFIFOSEL.BIGEND, [5] CFIFOSEL.ISEL, [3:0] CFIFOSEL.CURPIPE
0x87451022 USBHS 16-bit
  [15] CFIFOCTR.BVAL, [14] CFIFOCTR.BCLR, [13] CFIFOCTR.FRDY, [11:0] CFIFOCTR.DTLN
0x87451028 USBHS 16-bit
  [15] D0FIFOSEL.RCNT, [14] D0FIFOSEL.REW, [13] D0FIFOSEL.DCLRM, [12] D0FIFOSEL.DREQE, [11:10] D0FIFOSEL.MBW, [8] D0FIFOSEL.BIGEND, [3:0] D0FIFOSEL.CURPIPE
0x8745102A USBHS 16-bit
  [15] D0FIFOCTR.BVAL, [14] D0FIFOCTR.BCLR, [13] D0FIFOCTR.FRDY, [11:0] D0FIFOCTR.DTLN
0x8745102C USBHS 16-bit
  [15] D1FIFOSEL.RCNT, [14] D1FIFOSEL.REW, [13] D1FIFOSEL.DCLRM, [12] D1FIFOSEL.DREQE, [11:10] D1FIFOSEL.MBW, [8] D1FIFOSEL.BIGEND, [3:0] D1FIFOSEL.CURPIPE
0x8745102E USBHS 16-bit
  [15] D1FIFOCTR.BVAL, [14] D1FIFOCTR.BCLR, [13] D1FIFOCTR.FRDY, [11:0] D1FIFOCTR.DTLN
0x87451030 USBHS 16-bit
  [15] INTENB0.VBSE, [14] INTENB0.RSME, [13] INTENB0.SOFE, [12] INTENB0.DVSE, [11] INTENB0.CTRE, [10] INTENB0.BEMPE, [9] INTENB0.NRDYE, [8] INTENB0.BRDYE
0x87451032 USBHS 16-bit
  [15] INTENB1.OVRCRE, [14] INTENB1.BCHGE, [12] INTENB1.DTCHE, [11] INTENB1.ATTCHE, [9] INTENB1.L1RSMENDE, [8] INTENB1.LPMENDE, [6] INTENB1.EOFERRE, [5] INTENB1.SIGNE, [4] INTENB1.SACKE, [0] INTENB1.PDDETINTE
0x87451036 USBHS 16-bit
  [9:0] BRDYENB.PIPEBRDYE
0x87451038 USBHS 16-bit
  [9:0] NRDYENB.PIPENRDYE
0x8745103A USBHS 16-bit
  [9:0] BEMPENB.PIPEBEMPE
0x8745103C USBHS 16-bit
  [8] SOFCFG.TRNENSEL, [6] SOFCFG.BRDYM, [5] SOFCFG.INTL, [4] SOFCFG.EDGESTS
0x8745103E USBHS 16-bit
  [15] PHYSET.HSEB, [9:8] PHYSET.REPSEL, [5:4] PHYSET.CLKSEL, [3] PHYSET.CDPEN, [1] PHYSET.PLLRESET, [0] PHYSET.DIRPD
0x87451040 USBHS 16-bit
  [15] INTSTS0.VBINT, [14] INTSTS0.RESM, [13] INTSTS0.SOFR, [12] INTSTS0.DVST, [11] INTSTS0.CTRT, [10] INTSTS0.BEMP, [9] INTSTS0.NRDY, [8] INTSTS0.BRDY, [7] INTSTS0.VBSTS, [6:4] INTSTS0.DVSQ, [3] INTSTS0.VALID, [2:0] INTSTS0.CTSQ
0x87451042 USBHS 16-bit
  [15] INTSTS1.OVRCR, [14] INTSTS1.BCHG, [12] INTSTS1.DTCH, [11] INTSTS1.ATTCH, [9] INTSTS1.L1RSMEND, [8] INTSTS1.LPMEND, [6] INTSTS1.EOFERR, [5] INTSTS1.SIGN, [4] INTSTS1.SACK, [0] INTSTS1.PDDETINT
0x87451046 USBHS 16-bit
  [9:0] BRDYSTS.PIPEBRDY
0x87451048 USBHS 16-bit
  [9:0] NRDYSTS.PIPENRDY
0x8745104A USBHS 16-bit
  [9:0] BEMPSTS.PIPEBEMP
0x8745104C USBHS 16-bit
  [15] FRMNUM.OVRN, [14] FRMNUM.CRCE, [10:0] FRMNUM.FRNM
0x8745104E USBHS 16-bit
  [15] UFRMNUM.DVCHG, [2:0] UFRMNUM.UFRNM
0x87451050 USBHS 16-bit
  [10:8] USBADDR.STSRECOV0, [6:0] USBADDR.USBADDR
0x87451054 USBHS 16-bit
  [15:8] USBREQ.BREQUEST, [7:0] USBREQ.BMREQUESTTYPE
0x87451056 USBHS 16-bit
  [15:0] USBVAL.WVALUE
0x87451058 USBHS 16-bit
  [15:0] USBINDX.WINDEX
0x8745105A USBHS 16-bit
  [15:0] USBLENG.WLENGTH
0x8745105C USBHS 16-bit
  [8] DCPCFG.CNTMD, [7] DCPCFG.SHTNAK, [4] DCPCFG.DIR
0x8745105E USBHS 16-bit
  [15:12] DCPMAXP.DEVSEL, [6:0] DCPMAXP.MXPS
0x87451060 USBHS 16-bit
  [15] DCPCTR.BSTS, [14] DCPCTR.SUREQ, [13] DCPCTR.CSCLR, [12] DCPCTR.CSSTS, [11] DCPCTR.SUREQCLR, [8] DCPCTR.SQCLR, [7] DCPCTR.SQSET, [6] DCPCTR.SQMON, [5] DCPCTR.PBUSY, [4] DCPCTR.PINGE, [2] DCPCTR.CCPL, [1:0] DCPCTR.PID
0x87451064 USBHS 16-bit
  [3:0] PIPESEL.PIPESEL
0x87451068 USBHS 16-bit
  [15:14] PIPECFG.TYPE, [10] PIPECFG.BFRE, [9] PIPECFG.DBLB, [8] PIPECFG.CNTMD, [7] PIPECFG.SHTNAK, [4] PIPECFG.DIR, [3:0] PIPECFG.EPNUM
0x8745106A USBHS 16-bit
  [14:10] PIPEBUF.BUFSIZE, [7:0] PIPEBUF.BUFNMB
0x8745106C USBHS 16-bit
  [15:12] PIPEMAXP.DEVSEL, [10:0] PIPEMAXP.MXPS
0x8745106E USBHS 16-bit
  [12] PIPEPERI.IFIS, [2:0] PIPEPERI.IITV
0x87451070 USBHS 16-bit
  [15] PIPE1CTR.BSTS, [14] PIPE1CTR.INBUFM, [13] PIPE1CTR.CSCLR, [12] PIPE1CTR.CSSTS, [10] PIPE1CTR.ATREPM, [9] PIPE1CTR.ACLRM, [8] PIPE1CTR.SQCLR, [7] PIPE1CTR.SQSET, [6] PIPE1CTR.SQMON, [5] PIPE1CTR.PBUSY, [1:0] PIPE1CTR.PID
0x87451072 USBHS 16-bit
  [15] PIPE2CTR.BSTS, [14] PIPE2CTR.INBUFM, [13] PIPE2CTR.CSCLR, [12] PIPE2CTR.CSSTS, [10] PIPE2CTR.ATREPM, [9] PIPE2CTR.ACLRM, [8] PIPE2CTR.SQCLR, [7] PIPE2CTR.SQSET, [6] PIPE2CTR.SQMON, [5] PIPE2CTR.PBUSY, [1:0] PIPE2CTR.PID
0x87451074 USBHS 16-bit
  [15] PIPE3CTR.BSTS, [14] PIPE3CTR.INBUFM, [13] PIPE3CTR.CSCLR, [12] PIPE3CTR.CSSTS, [10] PIPE3CTR.ATREPM, [9] PIPE3CTR.ACLRM, [8] PIPE3CTR.SQCLR, [7] PIPE3CTR.SQSET, [6] PIPE3CTR.SQMON, [5] PIPE3CTR.PBUSY, [1:0] PIPE3CTR.PID
0x87451076 USBHS 16-bit
  [15] PIPE4CTR.BSTS, [14] PIPE4CTR.INBUFM, [13] PIPE4CTR.CSCLR, [12] PIPE4CTR.CSSTS, [10] PIPE4CTR.ATREPM, [9] PIPE4CTR.ACLRM, [8] PIPE4CTR.SQCLR, [7] PIPE4CTR.SQSET, [6] PIPE4CTR.SQMON, [5] PIPE4CTR.PBUSY, [1:0] PIPE4CTR.PID
0x87451078 USBHS 16-bit
  [15] PIPE5CTR.BSTS, [14] PIPE5CTR.INBUFM, [13] PIPE5CTR.CSCLR, [12] PIPE5CTR.CSSTS, [10] PIPE5CTR.ATREPM, [9] PIPE5CTR.ACLRM, [8] PIPE5CTR.SQCLR, [7] PIPE5CTR.SQSET, [6] PIPE5CTR.SQMON, [5] PIPE5CTR.PBUSY, [1:0] PIPE5CTR.PID
0x8745107A USBHS 16-bit
  [15] PIPE6CTR.BSTS, [14] PIPE6CTR.INBUFM, [13] PIPE6CTR.CSCLR, [12] PIPE6CTR.CSSTS, [10] PIPE6CTR.ATREPM, [9] PIPE6CTR.ACLRM, [8] PIPE6CTR.SQCLR, [7] PIPE6CTR.SQSET, [6] PIPE6CTR.SQMON, [5] PIPE6CTR.PBUSY, [1:0] PIPE6CTR.PID
0x8745107C USBHS 16-bit
  [15] PIPE7CTR.BSTS, [14] PIPE7CTR.INBUFM, [13] PIPE7CTR.CSCLR, [12] PIPE7CTR.CSSTS, [10] PIPE7CTR.ATREPM, [9] PIPE7CTR.ACLRM, [8] PIPE7CTR.SQCLR, [7] PIPE7CTR.SQSET, [6] PIPE7CTR.SQMON, [5] PIPE7CTR.PBUSY, [1:0] PIPE7CTR.PID
0x8745107E USBHS 16-bit
  [15] PIPE8CTR.BSTS, [14] PIPE8CTR.INBUFM, [13] PIPE8CTR.CSCLR, [12] PIPE8CTR.CSSTS, [10] PIPE8CTR.ATREPM, [9] PIPE8CTR.ACLRM, [8] PIPE8CTR.SQCLR, [7] PIPE8CTR.SQSET, [6] PIPE8CTR.SQMON, [5] PIPE8CTR.PBUSY, [1:0] PIPE8CTR.PID
0x87451080 USBHS 16-bit
  [15] PIPE9CTR.BSTS, [14] PIPE9CTR.INBUFM, [13] PIPE9CTR.CSCLR, [12] PIPE9CTR.CSSTS, [10] PIPE9CTR.ATREPM, [9] PIPE9CTR.ACLRM, [8] PIPE9CTR.SQCLR, [7] PIPE9CTR.SQSET, [6] PIPE9CTR.SQMON, [5] PIPE9CTR.PBUSY, [1:0] PIPE9CTR.PID
0x87451090 USBHS 16-bit
  [9] PIPE1TRE.TRENB, [8] PIPE1TRE.TRCLR
0x87451092 USBHS 16-bit
  [15:0] PIPE1TRN.TRNCNT
0x87451094 USBHS 16-bit
  [9] PIPE2TRE.TRENB, [8] PIPE2TRE.TRCLR
0x87451096 USBHS 16-bit
  [15:0] PIPE2TRN.TRNCNT
0x87451098 USBHS 16-bit
  [9] PIPE3TRE.TRENB, [8] PIPE3TRE.TRCLR
0x8745109A USBHS 16-bit
  [15:0] PIPE3TRN.TRNCNT
0x8745109C USBHS 16-bit
  [9] PIPE4TRE.TRENB, [8] PIPE4TRE.TRCLR
0x8745109E USBHS 16-bit
  [15:0] PIPE4TRN.TRNCNT
0x874510A0 USBHS 16-bit
  [9] PIPE5TRE.TRENB, [8] PIPE5TRE.TRCLR
0x874510A2 USBHS 16-bit
  [15:0] PIPE5TRN.TRNCNT
0x874510D0 USBHS 16-bit
  [14:11] DEVADD[0].UPPHUB, [10:8] DEVADD[0].HUBPORT, [7:6] DEVADD[0].USBSPD
0x874510D2 USBHS 16-bit
  [14:11] DEVADD[1].UPPHUB, [10:8] DEVADD[1].HUBPORT, [7:6] DEVADD[1].USBSPD
0x874510D4 USBHS 16-bit
  [14:11] DEVADD[2].UPPHUB, [10:8] DEVADD[2].HUBPORT, [7:6] DEVADD[2].USBSPD
0x874510D6 USBHS 16-bit
  [14:11] DEVADD[3].UPPHUB, [10:8] DEVADD[3].HUBPORT, [7:6] DEVADD[3].USBSPD
0x874510D8 USBHS 16-bit
  [14:11] DEVADD[4].UPPHUB, [10:8] DEVADD[4].HUBPORT, [7:6] DEVADD[4].USBSPD
0x874510DA USBHS 16-bit
  [14:11] DEVADD[5].UPPHUB, [10:8] DEVADD[5].HUBPORT, [7:6] DEVADD[5].USBSPD
0x874510DC USBHS 16-bit
  [14:11] DEVADD[6].UPPHUB, [10:8] DEVADD[6].HUBPORT, [7:6] DEVADD[6].USBSPD
0x874510DE USBHS 16-bit
  [14:11] DEVADD[7].UPPHUB, [10:8] DEVADD[7].HUBPORT, [7:6] DEVADD[7].USBSPD
0x874510E0 USBHS 16-bit
  [14:11] DEVADD[8].UPPHUB, [10:8] DEVADD[8].HUBPORT, [7:6] DEVADD[8].USBSPD
0x874510E2 USBHS 16-bit
  [14:11] DEVADD[9].UPPHUB, [10:8] DEVADD[9].HUBPORT, [7:6] DEVADD[9].USBSPD
0x874510E4 USBHS 16-bit
  [14:11] DEVADDA.UPPHUB, [10:8] DEVADDA.HUBPORT, [7:6] DEVADDA.USBSPD
0x87451100 USBHS 16-bit
  [7] LPCTRL.HWUPM
{0x87458000+0x100*i} RSCI{i} (i=0..12)
  [28] RDR.AFER, [27] RDR.APER, [24] RDR.ORER, [12] RDR.FER, [11] RDR.PER, [10] RDR.DR, [9] RDR.MPB, [8:0] RDR.RDAT
{0x87458004+0x100*i} RSCI{i} (i=0..12)
  [12] TDR.SYNC, [9] TDR.MPBT, [8:0] TDR.TDAT
{0x87458008+0x100*i} RSCI{i} (i=0..12)
  [24] SCR0.SSE, [21] SCR0.TEIE, [20] SCR0.TIE, [16] SCR0.RIE, [10] SCR0.IDSEL, [9] SCR0.DCME, [8] SCR0.MPIE, [4] SCR0.TE, [0] SCR0.RE
{0x8745800C+0x100*i} RSCI{i} (i=0..12)
  [29] SCR1.NFM, [28] SCR1.NFEN, [26:24] SCR1.NFCS, [20] SCR1.HDSEL, [16] SCR1.LOOP, [13] SCR1.RINV, [12] SCR1.TINV, [9] SCR1.PM, [8] SCR1.PE, [5] SCR1.SPB2IO, [4] SCR1.SPB2DT, [1] SCR1.CRSEP, [0] SCR1.CTSE
{0x87458010+0x100*i} RSCI{i} (i=0..12)
  [31:24] SCR2.MDDR, [21:20] SCR2.CKS, [16] SCR2.BRME, [15:8] SCR2.BRR, [7] SCR2.ABCSE2, [6] SCR2.ABCSE, [5] SCR2.ABCS, [4] SCR2.BGDM, [2:0] SCR2.BCP
{0x87458014+0x100*i} RSCI{i} (i=0..12)
  [29] SCR3.BLK, [28] SCR3.GM, [26] SCR3.ACS0, [25:24] SCR3.CKE, [21] SCR3.DEEN, [20] SCR3.FM, [19] SCR3.MP, [18:16] SCR3.MOD, [15] SCR3.RXDESEL, [14] SCR3.STOP, [13] SCR3.DINV, [12] SCR3.DDIR, [9:8] SCR3.CHR, [7] SCR3.SYNDIS, [1] SCR3.CPOL, [0] SCR3.CPHA
{0x87458018+0x100*i} RSCI{i} (i=0..12)
  [31:28] SCR4.TTMG, [27:24] SCR4.RTMG, [17] SCR4.TTADJ, [16] SCR4.RTADJ, [8:0] SCR4.CMPD
{0x8745801C+0x100*i} RSCI{i} 8-bit (i=0..12)
  [4] SISSR.ITEF, [0] SISSR.IREF
{0x8745801E+0x100*i} RSCI{i} 8-bit (i=0..12)
  [3] HBSCR.LPS, [2] HBSCR.AOE, [0] HBSCR.HBSE
{0x87458020+0x100*i} RSCI{i} (i=0..12)
  [23:22] SIMR.IICSCLS, [21:20] SIMR.IICSDAS, [18] SIMR.IICSTPREQ, [17] SIMR.IICRSTAREQ, [16] SIMR.IICSTAREQ, [13] SIMR.IICACKT, [9] SIMR.IICCSC, [8] SIMR.IICINTM, [4:0] SIMR.IICDL
{0x87458024+0x100*i} RSCI{i} (i=0..12)
  [28:24] FCR.RSTRG, [23] FCR.RFRST, [20:16] FCR.RTRG, [15] FCR.TFRST, [12:8] FCR.TTRG, [0] FCR.DRES
{0x8745802C+0x100*i} RSCI{i} (i=0..12)
  [26] MMCR.SBERIE, [25] MMCR.SYERIE, [24] MMCR.PFERIE, [21:20] MMCR.RPPAT, [19:16] MMCR.RPLEN, [13:12] MMCR.TPPAT, [11:8] MMCR.TPLEN, [6] MMCR.SBLEN, [5] MMCR.SYNCE, [4] MMCR.SBPTN, [2] MMCR.SADJE, [1] MMCR.ENCS, [0] MMCR.DECS
{0x87458030+0x100*i} RSCI{i} (i=0..12)
  [20:16] DECR.DEHLD, [12:8] DECR.DESU, [0] DECR.DELVL
{0x87458034+0x100*i} RSCI{i} (i=0..12)
  [25:24] XCR0.BCCS, [22] XCR0.AEDIE, [21] XCR0.COFIE, [20] XCR0.BFDIE, [17] XCR0.BCDIE, [16] XCR0.BFOIE, [15:13] XCR0.PIBS, [12] XCR0.PIBE, [11:10] XCR0.CF1DS, [9] XCR0.CF0RE, [8] XCR0.BFE, [1:0] XCR0.TCSS
{0x87458038+0x100*i} RSCI{i} (i=0..12)
  [31:24] XCR1.CF1CE, [23:16] XCR1.SCF1D, [15:8] XCR1.PCF1D, [5] XCR1.BRME, [4] XCR1.SDST, [0] XCR1.TCST
{0x8745803C+0x100*i} RSCI{i} (i=0..12)
  [31:16] XCR2.BFLW, [15:8] XCR2.CF0CE, [7:0] XCR2.CF0D
{0x87458048+0x100*i} RSCI{i} (i=0..12)
  [31] SSR.RDRF, [30] SSR.TEND, [29] SSR.TDRE, [28] SSR.AFER, [27] SSR.APER, [26] SSR.MFF, [24] SSR.ORER, [18] SSR.DFER, [17] SSR.DPER, [16] SSR.DCMF, [15] SSR.RXDMON, [4] SSR.ERS
{0x8745804C+0x100*i} RSCI{i} (i=0..12)
  [3] SISR.IICSTIF, [0] SISR.IICACKR
{0x87458050+0x100*i} RSCI{i} (i=0..12)
  [29:24] RFSR.FEC, [21:16] RFSR.PEC, [13:8] RFSR.R, [0] RFSR.DR
{0x87458054+0x100*i} RSCI{i} (i=0..12)
  [5:0] TFSR.T
{0x87458058+0x100*i} RSCI{i} (i=0..12)
  [6] MMSR.RSYNC, [4] MMSR.MCER, [2] MMSR.SBER, [1] MMSR.SYER, [0] MMSR.PFER
{0x8745805C+0x100*i} RSCI{i} (i=0..12)
  [31:24] XSR0.CF1RD, [23:16] XSR0.CF0RD, [15] XSR0.AEDF, [14] XSR0.COF, [13] XSR0.PIBDF, [12] XSR0.CF1MF, [11] XSR0.CF0MF, [10] XSR0.BFDF, [9] XSR0.BCDF, [8] XSR0.BFOF, [1] XSR0.RXDSF, [0] XSR0.SFSF
{0x87458060+0x100*i} RSCI{i} (i=0..12)
  [15:0] XSR1.CCV
{0x87458068+0x100*i} RSCI{i} (i=0..12)
  [31] SSCR.RDRFC, [29] SSCR.TDREC, [28] SSCR.AFERC, [27] SSCR.APERC, [26] SSCR.MFFC, [24] SSCR.ORERC, [18] SSCR.DFERC, [17] SSCR.DPERC, [16] SSCR.DCMFC, [4] SSCR.ERSC
{0x8745806C+0x100*i} RSCI{i} (i=0..12)
  [3] SISCR.IICSTIFC
{0x87458070+0x100*i} RSCI{i} (i=0..12)
  [0] RFSCR.DRC
{0x87458074+0x100*i} RSCI{i} (i=0..12)
  [4] MMSCR.MCERC, [2] MMSCR.SBERC, [1] MMSCR.SYERC, [0] MMSCR.PFERC
{0x87458078+0x100*i} RSCI{i} (i=0..12)
  [15] XSCR.AEDCL, [14] XSCR.COFC, [13] XSCR.PIBDCL, [12] XSCR.CF1MCL, [11] XSCR.CF0MCL, [10] XSCR.BFDCL, [9] XSCR.BCDCL, [8] XSCR.BFOC
{0x8745C004+0x100*i} RSPIA{i} 8-bit (i=0..2)
  [2:0] SPCKD.SCKDL
{0x8745C005+0x100*i} RSPIA{i} 8-bit (i=0..2)
  [2:0] SSLND.SLNDL
{0x8745C006+0x100*i} RSPIA{i} 8-bit (i=0..2)
  [2:0] SPND.SPNDL
{0x8745C008+0x100*i} RSPIA{i} (i=0..2)
  [31] SPCR.SYNDIS, [30] SPCR.MSTR, [29:28] SPCR.CMMD, [25] SPCR.FRFS, [24] SPCR.SPMS, [21] SPCR.SPCIE, [20] SPCR.SPTIE, [19] SPCR.RDRIS, [18] SPCR.SPIIE, [17] SPCR.SPRIE, [16] SPCR.SPEIE, [14] SPCR.MODFEN, [13] SPCR.SCKDDIS, [12] SPCR.SCKASE, [11] SPCR.PTE, [9] SPCR.SPOE, [8] SPCR.SPPE, [0] SPCR.SPE
{0x8745C00C+0x100*i} RSPIA{i} 8-bit (i=0..2)
  [7] SPRMCR.START, [6] SPRMCR.TERM, [4:0] SPRMCR.RFC
{0x8745C00E+0x100*i} RSPIA{i} 8-bit (i=0..2)
  [5] SPPCR.MOIFE, [4] SPPCR.MOIFV, [1] SPPCR.SPLP2, [0] SPPCR.SPLP
{0x8745C010+0x100*i} RSPIA{i} 8-bit (i=0..2)
  [n] SSLP.SSL{n}P (n=0..3)
{0x8745C013+0x100*i} RSPIA{i} 8-bit (i=0..2)
  [2:0] SPSCR.SPSLN
0x8745C014 RSPIA0
  [26:24] SPCMD[0].SSLA, [20:16] SPCMD[0].SPB, [15] SPCMD[0].SCKDEN, [14] SPCMD[0].SLNDEN, [13] SPCMD[0].SPNDEN, [12] SPCMD[0].LSBF, [7] SPCMD[0].SSLKP, [3:2] SPCMD[0].BRDV, [1] SPCMD[0].CPOL, [0] SPCMD[0].CPHA
0x8745C018 RSPIA0
  [26:24] SPCMD[1].SSLA, [20:16] SPCMD[1].SPB, [15] SPCMD[1].SCKDEN, [14] SPCMD[1].SLNDEN, [13] SPCMD[1].SPNDEN, [12] SPCMD[1].LSBF, [7] SPCMD[1].SSLKP, [3:2] SPCMD[1].BRDV, [1] SPCMD[1].CPOL, [0] SPCMD[1].CPHA
0x8745C01C RSPIA0
  [26:24] SPCMD[2].SSLA, [20:16] SPCMD[2].SPB, [15] SPCMD[2].SCKDEN, [14] SPCMD[2].SLNDEN, [13] SPCMD[2].SPNDEN, [12] SPCMD[2].LSBF, [7] SPCMD[2].SSLKP, [3:2] SPCMD[2].BRDV, [1] SPCMD[2].CPOL, [0] SPCMD[2].CPHA
0x8745C020 RSPIA0
  [26:24] SPCMD[3].SSLA, [20:16] SPCMD[3].SPB, [15] SPCMD[3].SCKDEN, [14] SPCMD[3].SLNDEN, [13] SPCMD[3].SPNDEN, [12] SPCMD[3].LSBF, [7] SPCMD[3].SSLKP, [3:2] SPCMD[3].BRDV, [1] SPCMD[3].CPOL, [0] SPCMD[3].CPHA
0x8745C024 RSPIA0
  [26:24] SPCMD[4].SSLA, [20:16] SPCMD[4].SPB, [15] SPCMD[4].SCKDEN, [14] SPCMD[4].SLNDEN, [13] SPCMD[4].SPNDEN, [12] SPCMD[4].LSBF, [7] SPCMD[4].SSLKP, [3:2] SPCMD[4].BRDV, [1] SPCMD[4].CPOL, [0] SPCMD[4].CPHA
0x8745C028 RSPIA0
  [26:24] SPCMD[5].SSLA, [20:16] SPCMD[5].SPB, [15] SPCMD[5].SCKDEN, [14] SPCMD[5].SLNDEN, [13] SPCMD[5].SPNDEN, [12] SPCMD[5].LSBF, [7] SPCMD[5].SSLKP, [3:2] SPCMD[5].BRDV, [1] SPCMD[5].CPOL, [0] SPCMD[5].CPHA
0x8745C02C RSPIA0
  [26:24] SPCMD[6].SSLA, [20:16] SPCMD[6].SPB, [15] SPCMD[6].SCKDEN, [14] SPCMD[6].SLNDEN, [13] SPCMD[6].SPNDEN, [12] SPCMD[6].LSBF, [7] SPCMD[6].SSLKP, [3:2] SPCMD[6].BRDV, [1] SPCMD[6].CPOL, [0] SPCMD[6].CPHA
0x8745C030 RSPIA0
  [26:24] SPCMD[7].SSLA, [20:16] SPCMD[7].SPB, [15] SPCMD[7].SCKDEN, [14] SPCMD[7].SLNDEN, [13] SPCMD[7].SPNDEN, [12] SPCMD[7].LSBF, [7] SPCMD[7].SSLKP, [3:2] SPCMD[7].BRDV, [1] SPCMD[7].CPOL, [0] SPCMD[7].CPHA
{0x8745C040+0x100*i} RSPIA{i} 16-bit (i=0..2)
  [9:8] SPDCR.SPFC, [4] SPDCR.DINV, [3] SPDCR.SPRDTD, [0] SPDCR.BYSW
{0x8745C044+0x100*i} RSPIA{i} 16-bit (i=0..2)
  [9:8] SPFCR.TTRG, [1:0] SPFCR.RTRG
{0x8745C051+0x100*i} RSPIA{i} 8-bit (i=0..2)
  [6:4] SPSSR.SPECM, [2:0] SPSSR.SPCP
{0x8745C052+0x100*i} RSPIA{i} 16-bit (i=0..2)
  [15] SPSR.SPRF, [14] SPSR.SPCF, [13] SPSR.SPTEF, [12] SPSR.UDRF, [11] SPSR.PERF, [10] SPSR.MODF, [9] SPSR.IDLNF, [8] SPSR.OVRF, [7] SPSR.RRDYF
{0x8745C058+0x100*i} RSPIA{i} 8-bit (i=0..2)
  [2:0] SPTFSR.FREE
{0x8745C05C+0x100*i} RSPIA{i} 8-bit (i=0..2)
  [2:0] SPRFSR.FILL
{0x8745C060+0x100*i} RSPIA{i} (i=0..2)
  [0] SPPSR.SPEPS
{0x8745C06A+0x100*i} RSPIA{i} 16-bit (i=0..2)
  [15] SPSCLR.SPRFC, [14] SPSCLR.SPCFC, [13] SPSCLR.SPTEFC, [12] SPSCLR.UDRFC, [11] SPSCLR.PERFC, [10] SPSCLR.MODFC, [8] SPSCLR.OVRFC, [7] SPSCLR.RRDYFC
{0x8745C06C+0x100*i} RSPIA{i} 8-bit (i=0..2)
  [0] SPFCLR.FCLR
0x8745C114 RSPIA1
  [26:24] SPCMD[0].SSLA, [20:16] SPCMD[0].SPB, [15] SPCMD[0].SCKDEN, [14] SPCMD[0].SLNDEN, [13] SPCMD[0].SPNDEN, [12] SPCMD[0].LSBF, [7] SPCMD[0].SSLKP, [3:2] SPCMD[0].BRDV, [1] SPCMD[0].CPOL, [0] SPCMD[0].CPHA
0x8745C118 RSPIA1
  [26:24] SPCMD[1].SSLA, [20:16] SPCMD[1].SPB, [15] SPCMD[1].SCKDEN, [14] SPCMD[1].SLNDEN, [13] SPCMD[1].SPNDEN, [12] SPCMD[1].LSBF, [7] SPCMD[1].SSLKP, [3:2] SPCMD[1].BRDV, [1] SPCMD[1].CPOL, [0] SPCMD[1].CPHA
0x8745C11C RSPIA1
  [26:24] SPCMD[2].SSLA, [20:16] SPCMD[2].SPB, [15] SPCMD[2].SCKDEN, [14] SPCMD[2].SLNDEN, [13] SPCMD[2].SPNDEN, [12] SPCMD[2].LSBF, [7] SPCMD[2].SSLKP, [3:2] SPCMD[2].BRDV, [1] SPCMD[2].CPOL, [0] SPCMD[2].CPHA
0x8745C120 RSPIA1
  [26:24] SPCMD[3].SSLA, [20:16] SPCMD[3].SPB, [15] SPCMD[3].SCKDEN, [14] SPCMD[3].SLNDEN, [13] SPCMD[3].SPNDEN, [12] SPCMD[3].LSBF, [7] SPCMD[3].SSLKP, [3:2] SPCMD[3].BRDV, [1] SPCMD[3].CPOL, [0] SPCMD[3].CPHA
0x8745C124 RSPIA1
  [26:24] SPCMD[4].SSLA, [20:16] SPCMD[4].SPB, [15] SPCMD[4].SCKDEN, [14] SPCMD[4].SLNDEN, [13] SPCMD[4].SPNDEN, [12] SPCMD[4].LSBF, [7] SPCMD[4].SSLKP, [3:2] SPCMD[4].BRDV, [1] SPCMD[4].CPOL, [0] SPCMD[4].CPHA
0x8745C128 RSPIA1
  [26:24] SPCMD[5].SSLA, [20:16] SPCMD[5].SPB, [15] SPCMD[5].SCKDEN, [14] SPCMD[5].SLNDEN, [13] SPCMD[5].SPNDEN, [12] SPCMD[5].LSBF, [7] SPCMD[5].SSLKP, [3:2] SPCMD[5].BRDV, [1] SPCMD[5].CPOL, [0] SPCMD[5].CPHA
0x8745C12C RSPIA1
  [26:24] SPCMD[6].SSLA, [20:16] SPCMD[6].SPB, [15] SPCMD[6].SCKDEN, [14] SPCMD[6].SLNDEN, [13] SPCMD[6].SPNDEN, [12] SPCMD[6].LSBF, [7] SPCMD[6].SSLKP, [3:2] SPCMD[6].BRDV, [1] SPCMD[6].CPOL, [0] SPCMD[6].CPHA
0x8745C130 RSPIA1
  [26:24] SPCMD[7].SSLA, [20:16] SPCMD[7].SPB, [15] SPCMD[7].SCKDEN, [14] SPCMD[7].SLNDEN, [13] SPCMD[7].SPNDEN, [12] SPCMD[7].LSBF, [7] SPCMD[7].SSLKP, [3:2] SPCMD[7].BRDV, [1] SPCMD[7].CPOL, [0] SPCMD[7].CPHA
0x8745C214 RSPIA2
  fields as RSPIA1
0x8745C218 RSPIA2
  [26:24] SPCMD[1].SSLA, [20:16] SPCMD[1].SPB, [15] SPCMD[1].SCKDEN, [14] SPCMD[1].SLNDEN, [13] SPCMD[1].SPNDEN, [12] SPCMD[1].LSBF, [7] SPCMD[1].SSLKP, [3:2] SPCMD[1].BRDV, [1] SPCMD[1].CPOL, [0] SPCMD[1].CPHA
0x8745C21C RSPIA2
  [26:24] SPCMD[2].SSLA, [20:16] SPCMD[2].SPB, [15] SPCMD[2].SCKDEN, [14] SPCMD[2].SLNDEN, [13] SPCMD[2].SPNDEN, [12] SPCMD[2].LSBF, [7] SPCMD[2].SSLKP, [3:2] SPCMD[2].BRDV, [1] SPCMD[2].CPOL, [0] SPCMD[2].CPHA
0x8745C220 RSPIA2
  [26:24] SPCMD[3].SSLA, [20:16] SPCMD[3].SPB, [15] SPCMD[3].SCKDEN, [14] SPCMD[3].SLNDEN, [13] SPCMD[3].SPNDEN, [12] SPCMD[3].LSBF, [7] SPCMD[3].SSLKP, [3:2] SPCMD[3].BRDV, [1] SPCMD[3].CPOL, [0] SPCMD[3].CPHA
0x8745C224 RSPIA2
  [26:24] SPCMD[4].SSLA, [20:16] SPCMD[4].SPB, [15] SPCMD[4].SCKDEN, [14] SPCMD[4].SLNDEN, [13] SPCMD[4].SPNDEN, [12] SPCMD[4].LSBF, [7] SPCMD[4].SSLKP, [3:2] SPCMD[4].BRDV, [1] SPCMD[4].CPOL, [0] SPCMD[4].CPHA
0x8745C228 RSPIA2
  [26:24] SPCMD[5].SSLA, [20:16] SPCMD[5].SPB, [15] SPCMD[5].SCKDEN, [14] SPCMD[5].SLNDEN, [13] SPCMD[5].SPNDEN, [12] SPCMD[5].LSBF, [7] SPCMD[5].SSLKP, [3:2] SPCMD[5].BRDV, [1] SPCMD[5].CPOL, [0] SPCMD[5].CPHA
0x8745C22C RSPIA2
  [26:24] SPCMD[6].SSLA, [20:16] SPCMD[6].SPB, [15] SPCMD[6].SCKDEN, [14] SPCMD[6].SLNDEN, [13] SPCMD[6].SPNDEN, [12] SPCMD[6].LSBF, [7] SPCMD[6].SSLKP, [3:2] SPCMD[6].BRDV, [1] SPCMD[6].CPOL, [0] SPCMD[6].CPHA
0x8745C230 RSPIA2
  [26:24] SPCMD[7].SSLA, [20:16] SPCMD[7].SPB, [15] SPCMD[7].SCKDEN, [14] SPCMD[7].SLNDEN, [13] SPCMD[7].SPNDEN, [12] SPCMD[7].LSBF, [7] SPCMD[7].SSLKP, [3:2] SPCMD[7].BRDV, [1] SPCMD[7].CPOL, [0] SPCMD[7].CPHA
0x8745F000 RI3C0
  [0] ICMR.OMS
0x8745F010 RI3C0
  [0] ICCCR.CCE
0x8745F014 RI3C0
  [31] ICCR.ICE, [30] ICCR.RESUME, [29] ICCR.ABORT, [7] ICCR.I2CDS, [1] ICCR.BAEXITMD, [0] ICCR.IBAINC
0x8745F018 RI3C0
  [31] ICCAR.DAV, [22:16] ICCAR.DADR
0x8745F020 RI3C0
  [16] ICRCR.ISRST, [12] ICRCR.HRDBRST, [11] ICRCR.HTDBRST, [10] ICRCR.HRSPQRST, [9] ICRCR.HCMDQRST, [6] ICRCR.SQRST, [5] ICRCR.IQRST, [4] ICRCR.RBRST, [3] ICRCR.TBRST, [2] ICRCR.RQRST, [1] ICRCR.CQRST, [0] ICRCR.MRST
0x8745F024 RI3C0
  [7] ICMMR.WP, [4] ICMMR.TRS, [2] ICMMR.ACF
0x8745F030 RI3C0
  [10] ICISR.BERF
0x8745F034 RI3C0
  [10] ICISER.BERDE
0x8745F038 RI3C0
  [10] ICISIER.BERIE
0x8745F044 RI3C0
  [23:19] ICDCTIR.INDEX
0x8745F058 RI3C0
  [3] ICINCR.RTIRN, [1] ICINCR.RCRRN
0x8745F060 RI3C0
  [15] ICFER.HSME, [14] ICFER.FMPE, [12] ICFER.SMBS, [8] ICFER.SCLE, [2] ICFER.SALE, [1] ICFER.NALE, [0] ICFER.MALE
0x8745F064 RI3C0
  [18] ICTCR.TA2DE, [17] ICTCR.TA1DE, [16] ICTCR.TA0DE, [15] ICTCR.HOAE, [6] ICTCR.DIDE, [5] ICTCR.HSMCE, [0] ICTCR.GCAE
0x8745F070 RI3C0
  [17:16] ICRCCR.MSKCYC, [2:0] ICRCCR.CKS
0x8745F074 RI3C0
  [31] ICSBR.ODDBL, [29:24] ICSBR.PPHW, [21:16] ICSBR.PPLW, [15:8] ICSBR.ODHW, [7:0] ICSBR.ODLW
0x8745F078 RI3C0
  [29:24] ICEBR.PPHW, [21:16] ICEBR.PPLW, [15:8] ICEBR.ODHW, [7:0] ICEBR.ODLW
0x8745F088 RI3C0
  [17:16] ICOCR.SDHDCYC, [2] ICOCR.SOWP, [1] ICOCR.SCLO, [0] ICOCR.SDAO
0x8745F08C RI3C0
  [5] ICICR.ANFE, [4] ICICR.NFE, [3:0] ICICR.NF
0x8745F090 RI3C0
  [7:6] ICTOR.TMOM, [5] ICTOR.TMOH, [4] ICTOR.TMOL, [1:0] ICTOR.TMOS
0x8745F098 RI3C0
  [7] WUCTL.WUFE, [6] WUCTL.WUFSYNE, [4] WUCTL.WUANFS, [0] WUCTL.WUACKS
0x8745F0A0 RI3C0
  [2] ICACKR.ACKWP, [1] ICACKR.ACKBT, [0] ICACKR.ACKBR
0x8745F0A4 RI3C0
  [1] ICCSCR.WAITRE, [0] ICCSCR.WAITAE
0x8745F0B0 RI3C0
  [31] ICSTCR.APSE, [30] ICSTCR.PBSE, [28] ICSTCR.AASE, [15:0] ICSTCR.STT
0x8745F0C0 RI3C0
  [31:16] ICTDLR.DLGTH
0x8745F120 RI3C0
  [0] STCTL.STOE
0x8745F124 RI3C0
  [15:8] ATCTL.CDIV, [2] ATCTL.AMEOE, [1] ATCTL.MREFOE, [0] ATCTL.ATTRGS
0x8745F128 RI3C0
  [0] ATTRG.ATSTRG
0x8745F12C RI3C0
  [0] ATCCNTE.ATCE
0x8745F140 RI3C0
  [2] ICCGR.SP, [1] ICCGR.RS, [0] ICCGR.ST
0x8745F190 RI3C0
  [31:24] ICQBTCR.IQTH, [23:16] ICQBTCR.IDSS, [15:8] ICQBTCR.RQTH, [7:0] ICQBTCR.CQTH
0x8745F194 RI3C0
  [26:24] ICDBTCR.RSTH, [18:16] ICDBTCR.TSTH, [10:8] ICDBTCR.RFTH, [2:0] ICDBTCR.TETH
0x8745F1C0 RI3C0
  [7:0] ICSQTCR.SQTH
0x8745F1C4 RI3C0
  [15:8] HQTHCTL.RSPQTH, [7:0] HQTHCTL.CMDQTH
0x8745F1C8 RI3C0
  [26:24] HTBTHCTL.RXSTTH, [18:16] HTBTHCTL.TXSTTH, [10:8] HTBTHCTL.RXDBTH, [2:0] HTBTHCTL.TXDBTH
0x8745F1D0 RI3C0
  [24] ICSR2.WUCNDDF, [20] ICSR2.TMOF, [2] ICSR2.HDRXDF, [1] ICSR2.STOP, [0] ICSR2.START
0x8745F1D4 RI3C0
  [24] ICSER.WUCNDDE, [20] ICSER.TMOE, [2] ICSER.HDRXDE, [1] ICSER.SPDE, [0] ICSER.STDE
0x8745F1D8 RI3C0
  [24] ICSIER.WUCNDDIE, [20] ICSIER.TMOIE, [2] ICSIER.HDRXIE, [1] ICSIER.SPIE, [0] ICSIER.STIE
0x8745F1E0 RI3C0
  [20] ICCSR.SQFF, [9] ICCSR.DTEF, [5] ICCSR.DTAF, [4] ICCSR.RQFF, [3] ICCSR.CQEF, [2] ICCSR.IQEFF, [1] ICCSR.RDRF, [0] ICCSR.TDRE
0x8745F1E4 RI3C0
  [20] ICCSER.SQFDE, [9] ICCSER.DTEDE, [5] ICCSER.DTADE, [4] ICCSER.RQFDE, [3] ICCSER.CQEDE, [2] ICCSER.IQEFDE, [1] ICCSER.RDE, [0] ICCSER.TDE
0x8745F1E8 RI3C0
  [20] ICCSIER.SQFIE, [9] ICCSIER.DTEIE, [5] ICCSIER.DTAIE, [4] ICCSIER.RQFIE, [3] ICCSIER.CQEIE, [2] ICCSIER.IQEFIE, [1] ICCSIER.RIE, [0] ICCSIER.TIE
0x8745F200 RI3C0
  [9] HTST.TEF, [5] HTST.TABTF, [4] HTST.RSPQFF, [3] HTST.CMDQEF, [1] HTST.RDBFF, [0] HTST.TDBEF
0x8745F204 RI3C0
  [9] HTSTE.TEE, [5] HTSTE.TABTE, [4] HTSTE.RSPQFE, [3] HTSTE.CMDQEE, [1] HTSTE.RDBFE, [0] HTSTE.TDBEE
0x8745F208 RI3C0
  [9] HTIE.TEIE, [5] HTIE.TABTIE, [4] HTIE.RSPQFIE, [3] HTIE.CMDQEIE, [1] HTIE.RDBFIE, [0] HTIE.TDBEIE
0x8745F210 RI3C0
  [2] ICBSR.BIDL, [1] ICBSR.BAVL, [0] ICBSR.BFREE
0x8745F214 RI3C0
  [18] ICSSR.AAS2, [17] ICSSR.AAS1, [16] ICSSR.AAS0, [15] ICSSR.HOA, [6] ICSSR.DID, [5] ICSSR.HSMC, [0] ICSSR.GCA
0x8745F218 RI3C0
  [0] WUST.WUASYNF
0x8745F224 RI3C0
  [31] ICTDATR0.TYPE, [30:29] ICTDATR0.NACKRC, [23:16] ICTDATR0.DADR, [15] ICTDATR0.IBITSE, [14] ICTDATR0.CRRRJ, [13] ICTDATR0.TIRRJ, [12] ICTDATR0.IBIPL, [6:0] ICTDATR0.SADR
0x8745F22C RI3C0
  [31] ICTDATR1.TYPE, [30:29] ICTDATR1.NACKRC, [23:16] ICTDATR1.DADR, [15] ICTDATR1.IBITSE, [14] ICTDATR1.CRRRJ, [13] ICTDATR1.TIRRJ, [12] ICTDATR1.IBIPL, [6:0] ICTDATR1.SADR
0x8745F234 RI3C0
  [31] ICTDATR2.TYPE, [30:29] ICTDATR2.NACKRC, [23:16] ICTDATR2.DADR, [15] ICTDATR2.IBITSE, [14] ICTDATR2.CRRRJ, [13] ICTDATR2.TIRRJ, [12] ICTDATR2.IBIPL, [6:0] ICTDATR2.SADR
0x8745F23C RI3C0
  [31] ICTDATR3.TYPE, [30:29] ICTDATR3.NACKRC, [23:16] ICTDATR3.DADR, [15] ICTDATR3.IBITSE, [14] ICTDATR3.CRRRJ, [13] ICTDATR3.TIRRJ, [12] ICTDATR3.IBIPL, [6:0] ICTDATR3.SADR
0x8745F244 RI3C0
  [31] ICTDATR4.TYPE, [30:29] ICTDATR4.NACKRC, [23:16] ICTDATR4.DADR, [15] ICTDATR4.IBITSE, [14] ICTDATR4.CRRRJ, [13] ICTDATR4.TIRRJ, [12] ICTDATR4.IBIPL, [6:0] ICTDATR4.SADR
0x8745F24C RI3C0
  [31] ICTDATR5.TYPE, [30:29] ICTDATR5.NACKRC, [23:16] ICTDATR5.DADR, [15] ICTDATR5.IBITSE, [14] ICTDATR5.CRRRJ, [13] ICTDATR5.TIRRJ, [12] ICTDATR5.IBIPL, [6:0] ICTDATR5.SADR
0x8745F254 RI3C0
  [31] ICTDATR6.TYPE, [30:29] ICTDATR6.NACKRC, [23:16] ICTDATR6.DADR, [15] ICTDATR6.IBITSE, [14] ICTDATR6.CRRRJ, [13] ICTDATR6.TIRRJ, [12] ICTDATR6.IBIPL, [6:0] ICTDATR6.SADR
0x8745F25C RI3C0
  [31] ICTDATR7.TYPE, [30:29] ICTDATR7.NACKRC, [23:16] ICTDATR7.DADR, [15] ICTDATR7.IBITSE, [14] ICTDATR7.CRRRJ, [13] ICTDATR7.TIRRJ, [12] ICTDATR7.IBIPL, [6:0] ICTDATR7.SADR
0x8745F2A0 RI3C0
  [31] ICEDATR.TYPE, [30:29] ICEDATR.NACKRC, [23:16] ICEDATR.DADR, [6:0] ICEDATR.SADR
0x8745F2B0 RI3C0
  [22:13] ICDAR[0].DADR, [12:11] ICDAR[0].IBIPL, [10] ICDAR[0].FS, [9:0] ICDAR[0].SADR
0x8745F2B4 RI3C0
  [22:13] ICDAR[1].DADR, [12:11] ICDAR[1].IBIPL, [10] ICDAR[1].FS, [9:0] ICDAR[1].SADR
0x8745F2B8 RI3C0
  [22:13] ICDAR[2].DADR, [12:11] ICDAR[2].IBIPL, [10] ICDAR[2].FS, [9:0] ICDAR[2].SADR
0x8745F2D0 RI3C0
  [15:14] ICTDCTR[0].ROLE, [13] ICTDCTR[0].RBCR5, [12] ICTDCTR[0].RBCR4, [11] ICTDCTR[0].OFLC, [10] ICTDCTR[0].IBIPL, [9] ICTDCTR[0].IBIRQC, [8] ICTDCTR[0].LIMIT
0x8745F2D4 RI3C0
  [15:14] ICTDCTR[1].ROLE, [13] ICTDCTR[1].RBCR5, [12] ICTDCTR[1].RBCR4, [11] ICTDCTR[1].OFLC, [10] ICTDCTR[1].IBIPL, [9] ICTDCTR[1].IBIRQC, [8] ICTDCTR[1].LIMIT
0x8745F2D8 RI3C0
  [15:14] ICTDCTR[2].ROLE, [13] ICTDCTR[2].RBCR5, [12] ICTDCTR[2].RBCR4, [11] ICTDCTR[2].OFLC, [10] ICTDCTR[2].IBIPL, [9] ICTDCTR[2].IBIRQC, [8] ICTDCTR[2].LIMIT
0x8745F2DC RI3C0
  [15:14] ICTDCTR[3].ROLE, [13] ICTDCTR[3].RBCR5, [12] ICTDCTR[3].RBCR4, [11] ICTDCTR[3].OFLC, [10] ICTDCTR[3].IBIPL, [9] ICTDCTR[3].IBIRQC, [8] ICTDCTR[3].LIMIT
0x8745F2E0 RI3C0
  [15:14] ICTDCTR[4].ROLE, [13] ICTDCTR[4].RBCR5, [12] ICTDCTR[4].RBCR4, [11] ICTDCTR[4].OFLC, [10] ICTDCTR[4].IBIPL, [9] ICTDCTR[4].IBIRQC, [8] ICTDCTR[4].LIMIT
0x8745F2E4 RI3C0
  [15:14] ICTDCTR[5].ROLE, [13] ICTDCTR[5].RBCR5, [12] ICTDCTR[5].RBCR4, [11] ICTDCTR[5].OFLC, [10] ICTDCTR[5].IBIPL, [9] ICTDCTR[5].IBIRQC, [8] ICTDCTR[5].LIMIT
0x8745F2E8 RI3C0
  [15:14] ICTDCTR[6].ROLE, [13] ICTDCTR[6].RBCR5, [12] ICTDCTR[6].RBCR4, [11] ICTDCTR[6].OFLC, [10] ICTDCTR[6].IBIPL, [9] ICTDCTR[6].IBIRQC, [8] ICTDCTR[6].LIMIT
# iorx74m register map
Registers are 32-bit, access not given, no defined reset value unless marked. A register's access mark holds for its fields unless they carry their own. Addresses are absolute; registers are grouped by the start of their names; [hi:lo] are bit positions; {n}, {i} and the like mark numbered series; 'fields as' and 'values as' point back to an identical list.

## SFR (part 5 of 10)
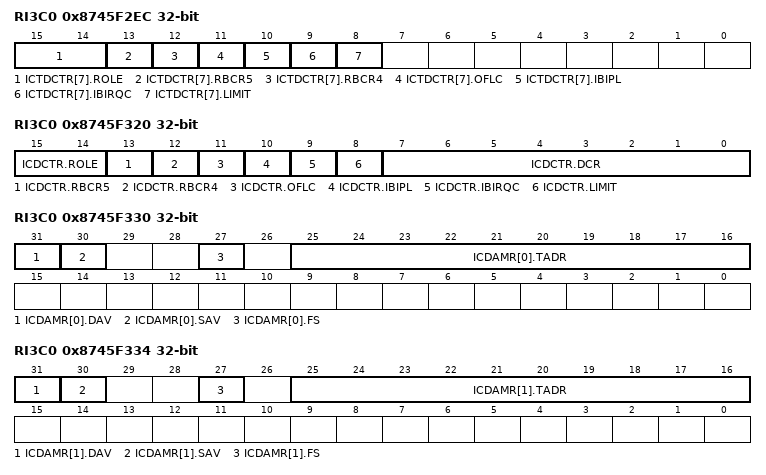
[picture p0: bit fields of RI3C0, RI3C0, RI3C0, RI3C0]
0x8745F2EC RI3C0
  [15:14] ICTDCTR[7].ROLE, [13] ICTDCTR[7].RBCR5, [12] ICTDCTR[7].RBCR4, [11] ICTDCTR[7].OFLC, [10] ICTDCTR[7].IBIPL, [9] ICTDCTR[7].IBIRQC, [8] ICTDCTR[7].LIMIT
0x8745F320 RI3C0
  [15:14] ICDCTR.ROLE, [13] ICDCTR.RBCR5, [12] ICDCTR.RBCR4, [11] ICDCTR.OFLC, [10] ICDCTR.IBIPL, [9] ICDCTR.IBIRQC, [8] ICDCTR.LIMIT, [7:0] ICDCTR.DCR
0x8745F330 RI3C0
  [31] ICDAMR[0].DAV, [30] ICDAMR[0].SAV, [27] ICDAMR[0].FS, [25:16] ICDAMR[0].TADR
0x8745F334 RI3C0
  [31] ICDAMR[1].DAV, [30] ICDAMR[1].SAV, [27] ICDAMR[1].FS, [25:16] ICDAMR[1].TADR
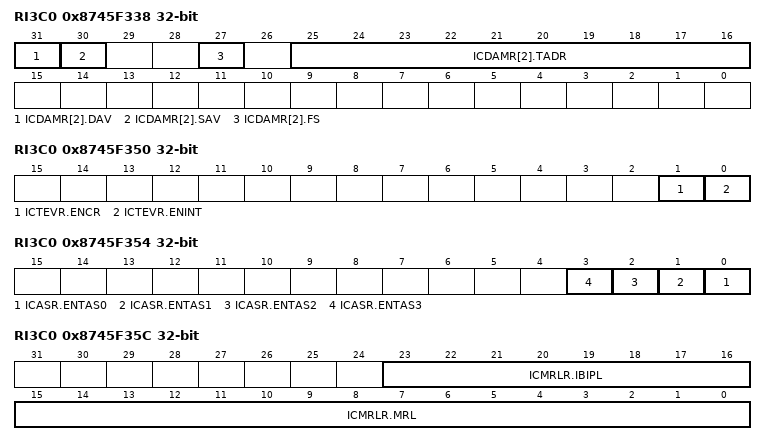
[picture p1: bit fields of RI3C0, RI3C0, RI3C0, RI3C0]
0x8745F338 RI3C0
  [31] ICDAMR[2].DAV, [30] ICDAMR[2].SAV, [27] ICDAMR[2].FS, [25:16] ICDAMR[2].TADR
0x8745F350 RI3C0
  [1] ICTEVR.ENCR, [0] ICTEVR.ENINT
0x8745F354 RI3C0
  [n] ICASR.ENTAS{n} (n=0..3)
0x8745F358 RI3C0
  [15:0] ICMWLR.MWL
0x8745F35C RI3C0
  [23:16] ICMRLR.IBIPL, [15:0] ICMRLR.MRL
0x8745F360 RI3C0
  [7:0] ICTMR.TM
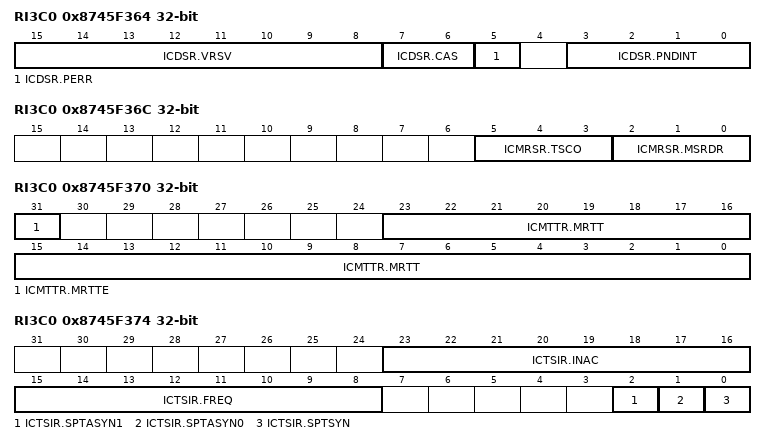
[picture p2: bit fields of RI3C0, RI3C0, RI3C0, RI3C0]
0x8745F364 RI3C0
  [15:8] ICDSR.VRSV, [7:6] ICDSR.CAS, [5] ICDSR.PERR, [3:0] ICDSR.PNDINT
0x8745F368 RI3C0
  [2:0] ICMWSR.MSWDR
0x8745F36C RI3C0
  [5:3] ICMRSR.TSCO, [2:0] ICMRSR.MSRDR
0x8745F370 RI3C0
  [31] ICMTTR.MRTTE, [23:0] ICMTTR.MRTT
0x8745F374 RI3C0
  [23:16] ICTSIR.INAC, [15:8] ICTSIR.FREQ, [2] ICTSIR.SPTASYN1, [1] ICTSIR.SPTASYN0, [0] ICTSIR.SPTSYN
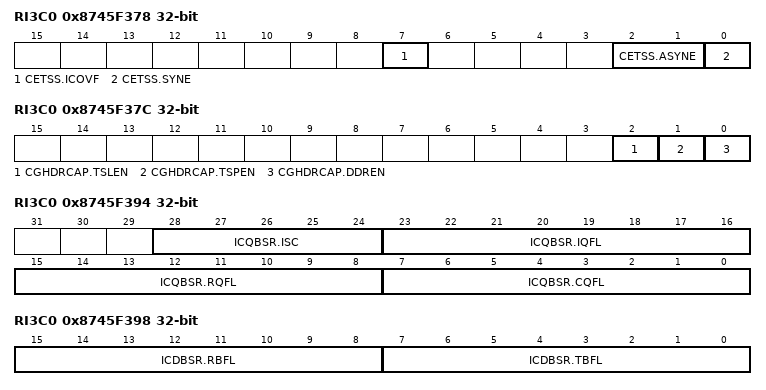
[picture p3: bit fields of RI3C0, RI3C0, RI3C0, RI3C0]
0x8745F378 RI3C0
  [7] CETSS.ICOVF, [2:1] CETSS.ASYNE, [0] CETSS.SYNE
0x8745F37C RI3C0
  [2] CGHDRCAP.TSLEN, [1] CGHDRCAP.TSPEN, [0] CGHDRCAP.DDREN
0x8745F380 RI3C0
  [4:0] ICBCR.BC
0x8745F394 RI3C0
  [28:24] ICQBSR.ISC, [23:16] ICQBSR.IQFL, [15:8] ICQBSR.RQFL, [7:0] ICQBSR.CQFL
0x8745F398 RI3C0
  [15:8] ICDBSR.RBFL, [7:0] ICDBSR.TBFL
0x8745F3C0 RI3C0
  [7:0] ICSQSR.SQFL
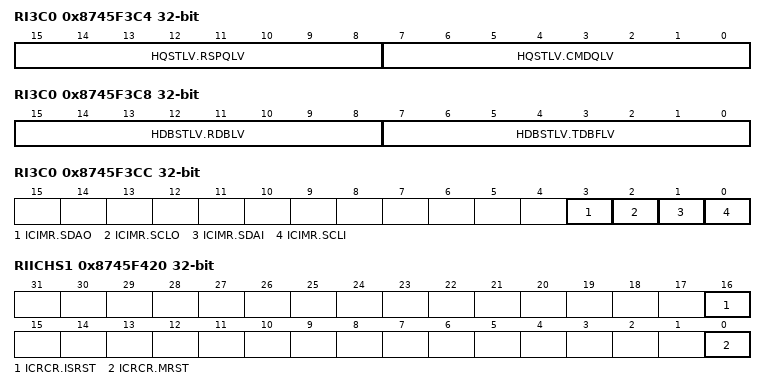
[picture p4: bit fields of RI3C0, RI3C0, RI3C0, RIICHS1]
0x8745F3C4 RI3C0
  [15:8] HQSTLV.RSPQLV, [7:0] HQSTLV.CMDQLV
0x8745F3C8 RI3C0
  [15:8] HDBSTLV.RDBLV, [7:0] HDBSTLV.TDBFLV
0x8745F3CC RI3C0
  [3] ICIMR.SDAO, [2] ICIMR.SCLO, [1] ICIMR.SDAI, [0] ICIMR.SCLI
0x8745F3D0 RI3C0
  [7:0] ICCECR.CE2C
0x8745F3E0 RI3C0
  [15:0] SC1CPT.SC1C
0x8745F3E4 RI3C0
  [15:0] SC2CPT.SC2C
0x8745F414 RIICHS1
  [31] ICCR.ICE
0x8745F420 RIICHS1
  [16] ICRCR.ISRST, [0] ICRCR.MRST
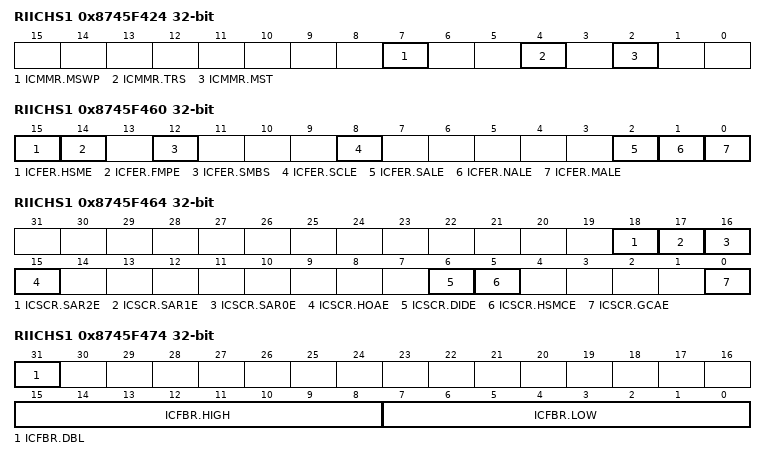
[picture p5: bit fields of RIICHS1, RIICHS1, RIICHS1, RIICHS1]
0x8745F424 RIICHS1
  [7] ICMMR.MSWP, [4] ICMMR.TRS, [2] ICMMR.MST
0x8745F460 RIICHS1
  [15] ICFER.HSME, [14] ICFER.FMPE, [12] ICFER.SMBS, [8] ICFER.SCLE, [2] ICFER.SALE, [1] ICFER.NALE, [0] ICFER.MALE
0x8745F464 RIICHS1
  [18] ICSCR.SAR2E, [17] ICSCR.SAR1E, [16] ICSCR.SAR0E, [15] ICSCR.HOAE, [6] ICSCR.DIDE, [5] ICSCR.HSMCE, [0] ICSCR.GCAE
0x8745F470 RIICHS1
  [2:0] ICRCCR.CKS
0x8745F474 RIICHS1
  [31] ICFBR.DBL, [15:8] ICFBR.HIGH, [7:0] ICFBR.LOW
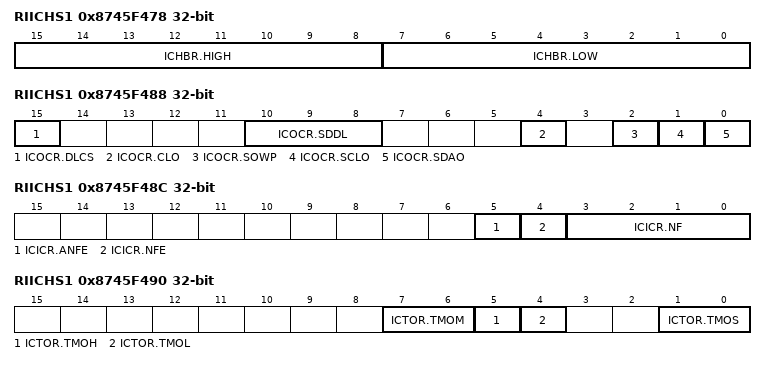
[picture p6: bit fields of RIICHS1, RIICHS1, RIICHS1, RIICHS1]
0x8745F478 RIICHS1
  [15:8] ICHBR.HIGH, [7:0] ICHBR.LOW
0x8745F488 RIICHS1
  [15] ICOCR.DLCS, [10:8] ICOCR.SDDL, [4] ICOCR.CLO, [2] ICOCR.SOWP, [1] ICOCR.SCLO, [0] ICOCR.SDAO
0x8745F48C RIICHS1
  [5] ICICR.ANFE, [4] ICICR.NFE, [3:0] ICICR.NF
0x8745F490 RIICHS1
  [7:6] ICTOR.TMOM, [5] ICTOR.TMOH, [4] ICTOR.TMOL, [1:0] ICTOR.TMOS
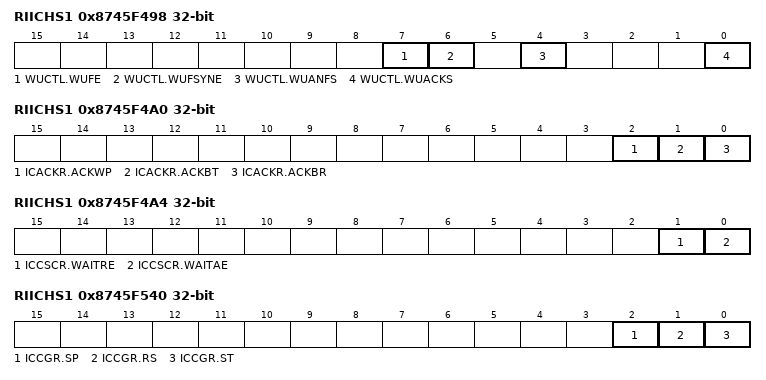
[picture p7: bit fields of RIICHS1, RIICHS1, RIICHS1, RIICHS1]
0x8745F498 RIICHS1
  [7] WUCTL.WUFE, [6] WUCTL.WUFSYNE, [4] WUCTL.WUANFS, [0] WUCTL.WUACKS
0x8745F4A0 RIICHS1
  [2] ICACKR.ACKWP, [1] ICACKR.ACKBT, [0] ICACKR.ACKBR
0x8745F4A4 RIICHS1
  [1] ICCSCR.WAITRE, [0] ICCSCR.WAITAE
0x8745F540 RIICHS1
  [2] ICCGR.SP, [1] ICCGR.RS, [0] ICCGR.ST
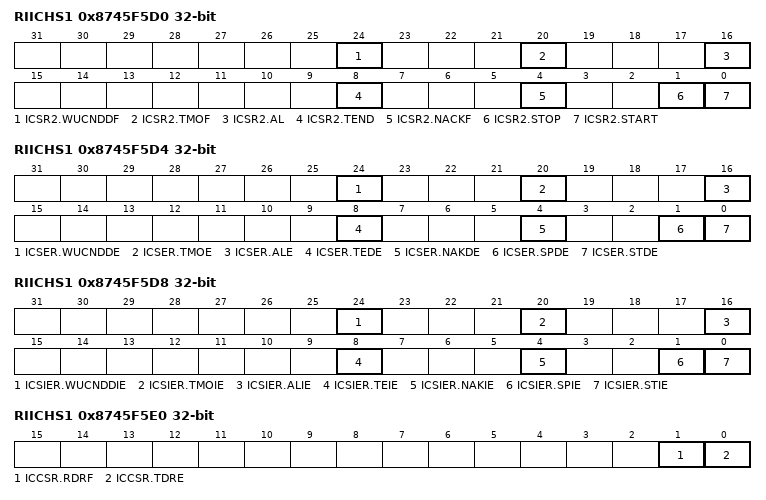
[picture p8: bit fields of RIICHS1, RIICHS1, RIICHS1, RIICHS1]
0x8745F5D0 RIICHS1
  [24] ICSR2.WUCNDDF, [20] ICSR2.TMOF, [16] ICSR2.AL, [8] ICSR2.TEND, [4] ICSR2.NACKF, [1] ICSR2.STOP, [0] ICSR2.START
0x8745F5D4 RIICHS1
  [24] ICSER.WUCNDDE, [20] ICSER.TMOE, [16] ICSER.ALE, [8] ICSER.TEDE, [4] ICSER.NAKDE, [1] ICSER.SPDE, [0] ICSER.STDE
0x8745F5D8 RIICHS1
  [24] ICSIER.WUCNDDIE, [20] ICSIER.TMOIE, [16] ICSIER.ALIE, [8] ICSIER.TEIE, [4] ICSIER.NAKIE, [1] ICSIER.SPIE, [0] ICSIER.STIE
0x8745F5E0 RIICHS1
  [1] ICCSR.RDRF, [0] ICCSR.TDRE
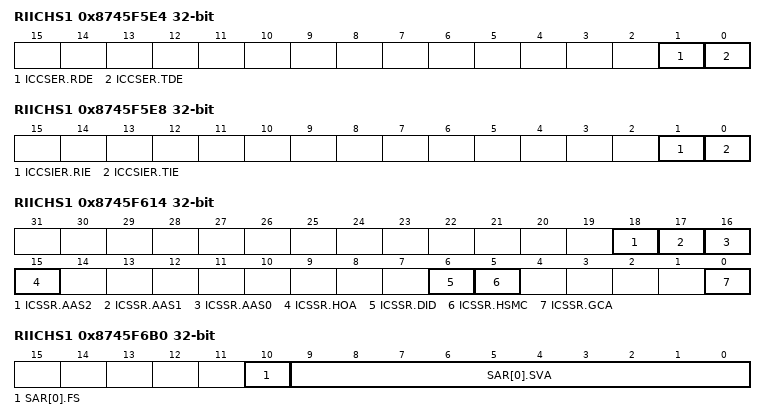
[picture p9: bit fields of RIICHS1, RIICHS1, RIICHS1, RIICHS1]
0x8745F5E4 RIICHS1
  [1] ICCSER.RDE, [0] ICCSER.TDE
0x8745F5E8 RIICHS1
  [1] ICCSIER.RIE, [0] ICCSIER.TIE
0x8745F610 RIICHS1
  [0] ICBSR.BFREE
0x8745F614 RIICHS1
  [18] ICSSR.AAS2, [17] ICSSR.AAS1, [16] ICSSR.AAS0, [15] ICSSR.HOA, [6] ICSSR.DID, [5] ICSSR.HSMC, [0] ICSSR.GCA
0x8745F618 RIICHS1
  [0] WUST.WUASYNF
0x8745F6B0 RIICHS1
  [10] SAR[0].FS, [9:0] SAR[0].SVA
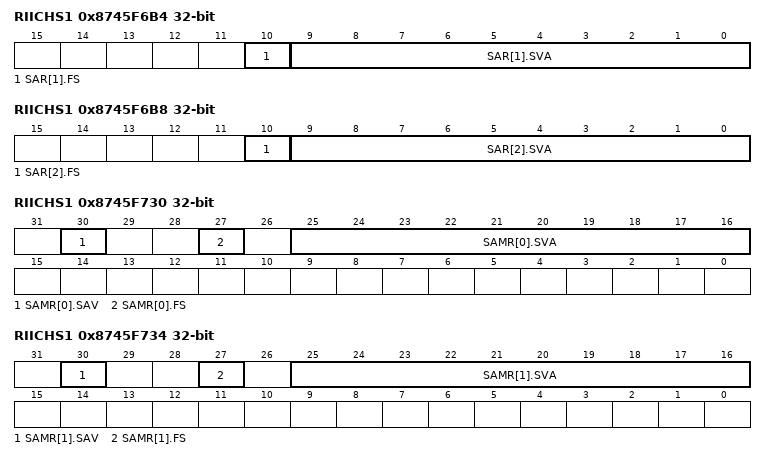
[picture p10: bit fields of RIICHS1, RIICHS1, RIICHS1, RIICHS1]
0x8745F6B4 RIICHS1
  [10] SAR[1].FS, [9:0] SAR[1].SVA
0x8745F6B8 RIICHS1
  [10] SAR[2].FS, [9:0] SAR[2].SVA
0x8745F730 RIICHS1
  [30] SAMR[0].SAV, [27] SAMR[0].FS, [25:16] SAMR[0].SVA
0x8745F734 RIICHS1
  [30] SAMR[1].SAV, [27] SAMR[1].FS, [25:16] SAMR[1].SVA
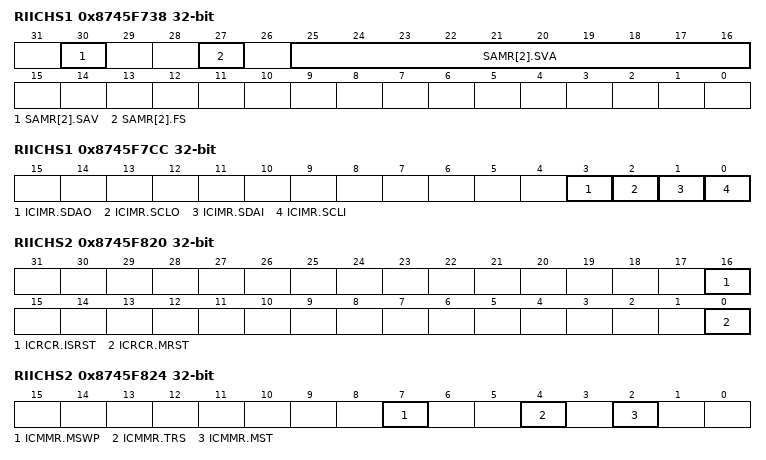
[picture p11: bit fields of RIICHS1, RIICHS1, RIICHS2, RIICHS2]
0x8745F738 RIICHS1
  [30] SAMR[2].SAV, [27] SAMR[2].FS, [25:16] SAMR[2].SVA
0x8745F780 RIICHS1
  [4:0] ICBCR.BC
0x8745F7CC RIICHS1
  [3] ICIMR.SDAO, [2] ICIMR.SCLO, [1] ICIMR.SDAI, [0] ICIMR.SCLI
0x8745F814 RIICHS2
  [31] ICCR.ICE
0x8745F820 RIICHS2
  [16] ICRCR.ISRST, [0] ICRCR.MRST
0x8745F824 RIICHS2
  [7] ICMMR.MSWP, [4] ICMMR.TRS, [2] ICMMR.MST
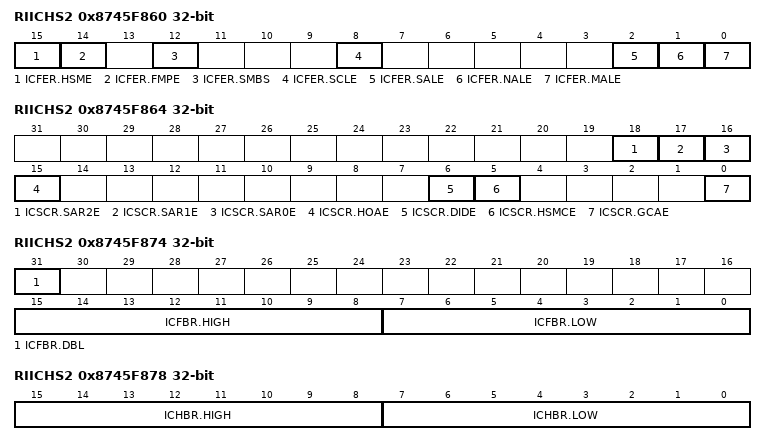
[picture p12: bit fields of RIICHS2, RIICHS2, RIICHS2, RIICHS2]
0x8745F860 RIICHS2
  [15] ICFER.HSME, [14] ICFER.FMPE, [12] ICFER.SMBS, [8] ICFER.SCLE, [2] ICFER.SALE, [1] ICFER.NALE, [0] ICFER.MALE
0x8745F864 RIICHS2
  [18] ICSCR.SAR2E, [17] ICSCR.SAR1E, [16] ICSCR.SAR0E, [15] ICSCR.HOAE, [6] ICSCR.DIDE, [5] ICSCR.HSMCE, [0] ICSCR.GCAE
0x8745F870 RIICHS2
  [2:0] ICRCCR.CKS
0x8745F874 RIICHS2
  [31] ICFBR.DBL, [15:8] ICFBR.HIGH, [7:0] ICFBR.LOW
0x8745F878 RIICHS2
  [15:8] ICHBR.HIGH, [7:0] ICHBR.LOW
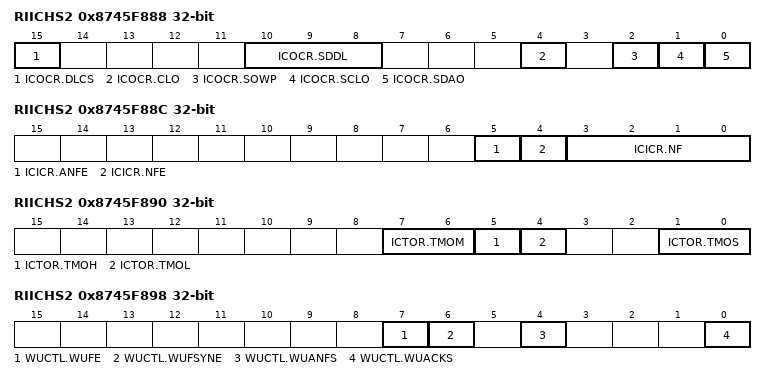
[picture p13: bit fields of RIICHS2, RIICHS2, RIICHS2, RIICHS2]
0x8745F888 RIICHS2
  [15] ICOCR.DLCS, [10:8] ICOCR.SDDL, [4] ICOCR.CLO, [2] ICOCR.SOWP, [1] ICOCR.SCLO, [0] ICOCR.SDAO
0x8745F88C RIICHS2
  [5] ICICR.ANFE, [4] ICICR.NFE, [3:0] ICICR.NF
0x8745F890 RIICHS2
  [7:6] ICTOR.TMOM, [5] ICTOR.TMOH, [4] ICTOR.TMOL, [1:0] ICTOR.TMOS
0x8745F898 RIICHS2
  [7] WUCTL.WUFE, [6] WUCTL.WUFSYNE, [4] WUCTL.WUANFS, [0] WUCTL.WUACKS
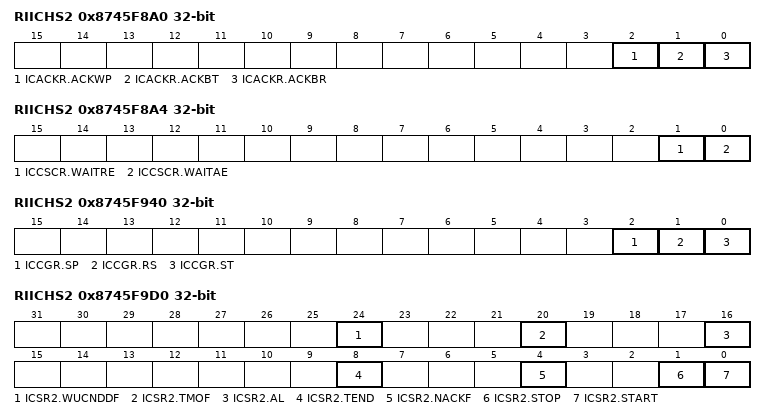
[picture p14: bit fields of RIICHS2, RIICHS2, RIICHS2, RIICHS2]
0x8745F8A0 RIICHS2
  [2] ICACKR.ACKWP, [1] ICACKR.ACKBT, [0] ICACKR.ACKBR
0x8745F8A4 RIICHS2
  [1] ICCSCR.WAITRE, [0] ICCSCR.WAITAE
0x8745F940 RIICHS2
  [2] ICCGR.SP, [1] ICCGR.RS, [0] ICCGR.ST
0x8745F9D0 RIICHS2
  [24] ICSR2.WUCNDDF, [20] ICSR2.TMOF, [16] ICSR2.AL, [8] ICSR2.TEND, [4] ICSR2.NACKF, [1] ICSR2.STOP, [0] ICSR2.START
0x8745F9D4 RIICHS2
  [24] ICSER.WUCNDDE, [20] ICSER.TMOE, [16] ICSER.ALE, [8] ICSER.TEDE, [4] ICSER.NAKDE, [1] ICSER.SPDE, [0] ICSER.STDE
0x8745F9D8 RIICHS2
  [24] ICSIER.WUCNDDIE, [20] ICSIER.TMOIE, [16] ICSIER.ALIE, [8] ICSIER.TEIE, [4] ICSIER.NAKIE, [1] ICSIER.SPIE, [0] ICSIER.STIE
0x8745F9E0 RIICHS2
  [1] ICCSR.RDRF, [0] ICCSR.TDRE
0x8745F9E4 RIICHS2
  [1] ICCSER.RDE, [0] ICCSER.TDE
0x8745F9E8 RIICHS2
  [1] ICCSIER.RIE, [0] ICCSIER.TIE
0x8745FA10 RIICHS2
  [0] ICBSR.BFREE
0x8745FA14 RIICHS2
  [18] ICSSR.AAS2, [17] ICSSR.AAS1, [16] ICSSR.AAS0, [15] ICSSR.HOA, [6] ICSSR.DID, [5] ICSSR.HSMC, [0] ICSSR.GCA
0x8745FA18 RIICHS2
  [0] WUST.WUASYNF
0x8745FAB0 RIICHS2
  [10] SAR[0].FS, [9:0] SAR[0].SVA
0x8745FAB4 RIICHS2
  [10] SAR[1].FS, [9:0] SAR[1].SVA
0x8745FAB8 RIICHS2
  [10] SAR[2].FS, [9:0] SAR[2].SVA
0x8745FB30 RIICHS2
  [30] SAMR[0].SAV, [27] SAMR[0].FS, [25:16] SAMR[0].SVA
0x8745FB34 RIICHS2
  [30] SAMR[1].SAV, [27] SAMR[1].FS, [25:16] SAMR[1].SVA
0x8745FB38 RIICHS2
  [30] SAMR[2].SAV, [27] SAMR[2].FS, [25:16] SAMR[2].SVA
0x8745FB80 RIICHS2
  [4:0] ICBCR.BC
0x8745FBCC RIICHS2
  [3] ICIMR.SDAO, [2] ICIMR.SCLO, [1] ICIMR.SDAI, [0] ICIMR.SCLI
0x8746E000 ECCAFL0
  [17] ECCSR.EC2EAS, [16] ECCSR.EC1EAS, [15:14] ECCSR.ECEDWC, [11] ECCSR.ECOVF, [10] ECCSR.EC2EC, [9] ECCSR.EC1EC, [6] ECCSR.ECEDE, [5] ECCSR.EC1ECD, [4] ECCSR.EC2EIE, [3] ECCSR.EC1EIE, [2] ECCSR.EC2EF, [1] ECCSR.EC1EF, [0] ECCSR.ECEF
0x8746E004 ECCAFL0 16-bit
  [15:14] ECTMR.ECTMWC, [7] ECTMR.ECTME, [1] ECTMR.ECDIS
0x8746E100 ECCAFL1
  fields as ECCAFL0
0x8746E104 ECCAFL1 16-bit
  [15:14] ECTMR.ECTMWC, [7] ECTMR.ECTME, [1] ECTMR.ECDIS
0x8746E200 ECCMB
  fields as ECCAFL0
0x8746E204 ECCMB 16-bit
  [15:14] ECTMR.ECTMWC, [7] ECTMR.ECTME, [1] ECTMR.ECDIS
0x8746F200 CANFD
  fields as ECCAFL0
0x8746F204 CANFD 16-bit
  [15:14] ECTMR.ECTMWC, [7] ECTMR.ECTME, [1] ECTMR.ECDIS
0x87470000 CANFD2
  [31:25] NBCR.TSEG2, [24:17] NBCR.TSEG1, [16:10] NBCR.SJW, [9:0] NBCR.BRP
0x87470004 CANFD2
  [31] CHCR.ROME, [30] CHCR.BFT, [26:25] CHCR.CTMS, [24] CHCR.CTME, [23] CHCR.EDM, [22:21] CHCR.BOM, [19] CHCR.TDCVIE, [18] CHCR.SCOVIE, [17] CHCR.ECOVIE, [16] CHCR.TAIE, [15] CHCR.ALIE, [14] CHCR.BLIE, [13] CHCR.OLIE, [12] CHCR.BORIE, [11] CHCR.BOEIE, [10] CHCR.EPIE, [9] CHCR.EWIE, [8] CHCR.BEIE, [3] CHCR.RTBO, [2] CHCR.SLPRQ, [1:0] CHCR.MDC
0x87470008 CANFD2
  [31:24] CHSR.TEC, [23:16] CHSR.REC, [8] CHSR.RESI, [7] CHSR.CRDY, [6] CHSR.RECST, [5] CHSR.TRMST, [4] CHSR.BOST, [3] CHSR.EPST, [2] CHSR.SLPST, [1] CHSR.HLTST, [0] CHSR.RSTST
0x8747000C CANFD2
  [30:16] CHESR.CRC15, [14] CHESR.ADEDF, [13] CHESR.B0EDF, [12] CHESR.B1EDF, [11] CHESR.CEDF, [10] CHESR.AEDF, [9] CHESR.FEDF, [8] CHESR.SEDF, [7] CHESR.ALDF, [6] CHESR.BLDF, [5] CHESR.OLDF, [4] CHESR.BORDF, [3] CHESR.BOEDF, [2] CHESR.EPDF, [1] CHESR.EWDF, [0] CHESR.BEDF
0x87470014 CANFD
  [31:16] GCFG.ITP, [12] GCFG.TSCS, [11:8] GCFG.TSP, [5] GCFG.OMRC, [4] GCFG.DLLCS, [3] GCFG.MME, [2] GCFG.DRE, [1] GCFG.DCE, [0] GCFG.TPRI
0x87470018 CANFD
  [16] GCR.TSCR, [11] GCR.POIE, [10] GCR.THLIE, [9] GCR.MLIE, [8] GCR.DEIE, [2] GCR.SLPRQ, [1:0] GCR.MDC
0x8747001C CANFD
  [3] GSR.RAMST, [2] GSR.SLPST, [1] GSR.HLTST, [0] GSR.RSTST
0x87470020 CANFD
  [16] GESR.EEDF0, [3] GESR.PODF, [2] GESR.THLDF, [1] GESR.MLDF, [0] GESR.DEDF
0x87470028 CANFD
  [8] AFCR.AFLWE, [0] AFCR.PAGE
0x8747002C CANFD
  [21:16] AFCFG.RN0
0x87470030 CANFD
  [10:8] RMCR.PLS, [5:0] RMCR.NMB
0x87470034 CANFD
  [31:0] RMNDR.NDF
0x87470038 CANFD
  [n] RMIER.RMIE{n} (n=0..31)
0x8747003C CANFD
  [15:13] RFCR[0].RFITH, [12] RFCR[0].RFIM, [10:8] RFCR[0].FDS, [6:4] RFCR[0].PLS, [1] RFCR[0].RFIE, [0] RFCR[0].RFE
0x87470040 CANFD
  [15:13] RFCR[1].RFITH, [12] RFCR[1].RFIM, [10:8] RFCR[1].FDS, [6:4] RFCR[1].PLS, [1] RFCR[1].RFIE, [0] RFCR[1].RFE
0x87470044 CANFD
  [13:8] RFSR[0].FLVL, [3] RFSR[0].RFIF, [2] RFSR[0].LOST, [1] RFSR[0].FULL, [0] RFSR[0].EMPTY
0x87470048 CANFD
  [13:8] RFSR[1].FLVL, [3] RFSR[1].RFIF, [2] RFSR[1].LOST, [1] RFSR[1].FULL, [0] RFSR[1].EMPTY
0x87470054 CANFD
  [31:24] CFCR0.TINT, [23:21] CFCR0.FDS, [17:16] CFCR0.LTM, [15:13] CFCR0.CFITH, [12] CFCR0.CFIM, [11] CFCR0.ITR, [10] CFCR0.ITCS, [8] CFCR0.MODE, [6:4] CFCR0.PLS, [2] CFCR0.CFTIE, [1] CFCR0.CFRIE, [0] CFCR0.CFE
0x87470058 CANFD
  [13:8] CFSR0.FLVL, [4] CFSR0.CFTIF, [3] CFSR0.CFRIF, [2] CFSR0.LOST, [1] CFSR0.FULL, [0] CFSR0.EMPTY
0x87470060 CANFD
  [8] FESR.CFEMP0, [1] FESR.RFEMP1, [0] FESR.RFEMP0
0x87470064 CANFD
  [8] FFSR.CFFUL0, [1] FFSR.RFFUL1, [0] FFSR.RFFUL0
0x87470068 CANFD
  [8] FMLSR.CFML0, [1] FMLSR.RFML1, [0] FMLSR.RFML0
0x8747006C CANFD
  [1] RFISR.RFIF1, [0] RFISR.RFIF0
0x87470070 CANFD 8-bit
  [2] TMCR[0].ONESHOT, [1] TMCR[0].TARQ, [0] TMCR[0].TXRQ
0x87470071 CANFD 8-bit
  [2] TMCR[1].ONESHOT, [1] TMCR[1].TARQ, [0] TMCR[1].TXRQ
0x87470072 CANFD 8-bit
  [2] TMCR[2].ONESHOT, [1] TMCR[2].TARQ, [0] TMCR[2].TXRQ
0x87470073 CANFD 8-bit
  [2] TMCR[3].ONESHOT, [1] TMCR[3].TARQ, [0] TMCR[3].TXRQ
0x87470074 CANFD 8-bit
  [4] TMSR[0].TARQS, [3] TMSR[0].TXRQS, [2:1] TMSR[0].TXRF, [0] TMSR[0].TXSF
0x87470075 CANFD 8-bit
  [4] TMSR[1].TARQS, [3] TMSR[1].TXRQS, [2:1] TMSR[1].TXRF, [0] TMSR[1].TXSF
0x87470076 CANFD 8-bit
  [4] TMSR[2].TARQS, [3] TMSR[2].TXRQS, [2:1] TMSR[2].TXRF, [0] TMSR[2].TXSF
0x87470077 CANFD 8-bit
  [4] TMSR[3].TARQS, [3] TMSR[3].TXRQS, [2:1] TMSR[3].TXRF, [0] TMSR[3].TXSF
0x87470078 CANFD
  [n] TMTRSR0.TXRQS{n} (n=0..3)
0x8747007C CANFD
  [n] TMARSR0.TARQS{n} (n=0..3)
0x87470080 CANFD
  [n] TMTCSR0.TXCF{n} (n=0..3)
0x87470084 CANFD
  [n] TMTASR0.TAF{n} (n=0..3)
0x87470088 CANFD
  [n] TMIER0.TMIE{n} (n=0..3)
0x8747008C CANFD2
  [9:8] TQCR0.QDS, [7] TQCR0.TQIM, [5] TQCR0.TQIE, [0] TQCR0.TQE
0x87470090 CANFD2
  [10:8] TQSR0.FLVL, [2] TQSR0.TQIF, [1] TQSR0.FULL, [0] TQSR0.EMPTY
0x87470098 CANFD2
  [10] THCR.THRC, [9] THCR.THIM, [8] THCR.THIE, [0] THCR.THE
0x8747009C CANFD2
  [11:8] THSR.FLVL, [3] THSR.THIF, [2] THSR.LOST, [1] THSR.FULL, [0] THSR.EMPTY
0x874700A4 CANFD
  [4] TISR.THIF0, [3] TISR.CFTIF0, [2] TISR.TQIF0, [1] TISR.TAIF0, [0] TISR.TSIF0
0x874700A8 CANFD
  [19:16] GTMCR.RTPS
0x874700AC CANFD
  [2] GTMER.RTME
0x874700B0 CANFD
  [9:8] GFDCFG.TSCPS, [0] GFDCFG.PXEDIS
0x874700C0 CANFD
  [4:0] AFIGSR.IGES
0x874700C4 CANFD
  [15:8] AFIGER.KEY, [0] AFIGER.IGEE
0x874700C8 CANFD
  [8] DTCR.CFDTE0, [1] DTCR.RFDTE1, [0] DTCR.RFDTE0
0x874700CC CANFD
  [8] DTSR.CFDTS0, [1] DTSR.RFDTS1, [0] DTSR.RFDTS0
0x874700D8 CANFD
  [15:8] GRCR.KEY, [0] GRCR.SRST
0x87470100 CANFD2
  [27:24] DBCR.SJW, [19:16] DBCR.TSEG2, [12:8] DBCR.TSEG1, [7:0] DBCR.BRP
0x87470104 CANFD2
  [30] FDCFG.CLOE, [29] FDCFG.REFE, [28] FDCFG.FDOE, [23:16] FDCFG.TDCO, [10] FDCFG.TESI, [9] FDCFG.TDCE, [8] FDCFG.SSPC, [2:0] FDCFG.ECC
0x87470108 CANFD2
  [1] FDCTR.SCCL, [0] FDCTR.ECCL
0x8747010C CANFD2
  [31:24] FDSTS.SC, [23:16] FDSTS.EC, [15] FDSTS.TDCV, [9] FDSTS.SCOV, [8] FDSTS.ECOV, [7:0] FDSTS.TDCR
0x87470110 CANFD2
  [27:24] FDCRC.SBC, [20:0] FDCRC.CRC21
0x87470120 CANFD
  [31] AFL[0]_IDR.IDE, [30] AFL[0]_IDR.RTR, [29] AFL[0]_IDR.LPC, [28:0] AFL[0]_IDR.ID
0x87470124 CANFD
  [31] AFL[0]_MASK.IDEM, [30] AFL[0]_MASK.RTRM, [29] AFL[0]_MASK.IFL1, [28:0] AFL[0]_MASK.IDM
0x87470128 CANFD
  [31:16] AFL[0]_PTR0.PTR, [15] AFL[0]_PTR0.DMBE, [12:8] AFL[0]_PTR0.DMB, [7] AFL[0]_PTR0.IFL0, [3:0] AFL[0]_PTR0.DLC
0x8747012C CANFD
  [8] AFL[0]_PTR1.CF0E, [1] AFL[0]_PTR1.RF1E, [0] AFL[0]_PTR1.RF0E
0x87470130 CANFD
  [31] AFL[1]_IDR.IDE, [30] AFL[1]_IDR.RTR, [29] AFL[1]_IDR.LPC, [28:0] AFL[1]_IDR.ID
0x87470134 CANFD
  [31] AFL[1]_MASK.IDEM, [30] AFL[1]_MASK.RTRM, [29] AFL[1]_MASK.IFL1, [28:0] AFL[1]_MASK.IDM
0x87470138 CANFD
  [31:16] AFL[1]_PTR0.PTR, [15] AFL[1]_PTR0.DMBE, [12:8] AFL[1]_PTR0.DMB, [7] AFL[1]_PTR0.IFL0, [3:0] AFL[1]_PTR0.DLC
0x8747013C CANFD
  [8] AFL[1]_PTR1.CF0E, [1] AFL[1]_PTR1.RF1E, [0] AFL[1]_PTR1.RF0E
0x87470140 CANFD
  [31] AFL[2]_IDR.IDE, [30] AFL[2]_IDR.RTR, [29] AFL[2]_IDR.LPC, [28:0] AFL[2]_IDR.ID
0x87470144 CANFD
  [31] AFL[2]_MASK.IDEM, [30] AFL[2]_MASK.RTRM, [29] AFL[2]_MASK.IFL1, [28:0] AFL[2]_MASK.IDM
0x87470148 CANFD
  [31:16] AFL[2]_PTR0.PTR, [15] AFL[2]_PTR0.DMBE, [12:8] AFL[2]_PTR0.DMB, [7] AFL[2]_PTR0.IFL0, [3:0] AFL[2]_PTR0.DLC
0x8747014C CANFD
  [8] AFL[2]_PTR1.CF0E, [1] AFL[2]_PTR1.RF1E, [0] AFL[2]_PTR1.RF0E
0x87470150 CANFD
  [31] AFL[3]_IDR.IDE, [30] AFL[3]_IDR.RTR, [29] AFL[3]_IDR.LPC, [28:0] AFL[3]_IDR.ID
0x87470154 CANFD
  [31] AFL[3]_MASK.IDEM, [30] AFL[3]_MASK.RTRM, [29] AFL[3]_MASK.IFL1, [28:0] AFL[3]_MASK.IDM
0x87470158 CANFD
  [31:16] AFL[3]_PTR0.PTR, [15] AFL[3]_PTR0.DMBE, [12:8] AFL[3]_PTR0.DMB, [7] AFL[3]_PTR0.IFL0, [3:0] AFL[3]_PTR0.DLC
0x8747015C CANFD
  [8] AFL[3]_PTR1.CF0E, [1] AFL[3]_PTR1.RF1E, [0] AFL[3]_PTR1.RF0E
0x87470160 CANFD
  [31] AFL[4]_IDR.IDE, [30] AFL[4]_IDR.RTR, [29] AFL[4]_IDR.LPC, [28:0] AFL[4]_IDR.ID
0x87470164 CANFD
  [31] AFL[4]_MASK.IDEM, [30] AFL[4]_MASK.RTRM, [29] AFL[4]_MASK.IFL1, [28:0] AFL[4]_MASK.IDM
0x87470168 CANFD
  [31:16] AFL[4]_PTR0.PTR, [15] AFL[4]_PTR0.DMBE, [12:8] AFL[4]_PTR0.DMB, [7] AFL[4]_PTR0.IFL0, [3:0] AFL[4]_PTR0.DLC
0x8747016C CANFD
  [8] AFL[4]_PTR1.CF0E, [1] AFL[4]_PTR1.RF1E, [0] AFL[4]_PTR1.RF0E
0x87470170 CANFD
  [31] AFL[5]_IDR.IDE, [30] AFL[5]_IDR.RTR, [29] AFL[5]_IDR.LPC, [28:0] AFL[5]_IDR.ID
0x87470174 CANFD
  [31] AFL[5]_MASK.IDEM, [30] AFL[5]_MASK.RTRM, [29] AFL[5]_MASK.IFL1, [28:0] AFL[5]_MASK.IDM
0x87470178 CANFD
  [31:16] AFL[5]_PTR0.PTR, [15] AFL[5]_PTR0.DMBE, [12:8] AFL[5]_PTR0.DMB, [7] AFL[5]_PTR0.IFL0, [3:0] AFL[5]_PTR0.DLC
0x8747017C CANFD
  [8] AFL[5]_PTR1.CF0E, [1] AFL[5]_PTR1.RF1E, [0] AFL[5]_PTR1.RF0E
0x87470180 CANFD
  [31] AFL[6]_IDR.IDE, [30] AFL[6]_IDR.RTR, [29] AFL[6]_IDR.LPC, [28:0] AFL[6]_IDR.ID
0x87470184 CANFD
  [31] AFL[6]_MASK.IDEM, [30] AFL[6]_MASK.RTRM, [29] AFL[6]_MASK.IFL1, [28:0] AFL[6]_MASK.IDM
0x87470188 CANFD
  [31:16] AFL[6]_PTR0.PTR, [15] AFL[6]_PTR0.DMBE, [12:8] AFL[6]_PTR0.DMB, [7] AFL[6]_PTR0.IFL0, [3:0] AFL[6]_PTR0.DLC
0x8747018C CANFD
  [8] AFL[6]_PTR1.CF0E, [1] AFL[6]_PTR1.RF1E, [0] AFL[6]_PTR1.RF0E
0x87470190 CANFD
  [31] AFL[7]_IDR.IDE, [30] AFL[7]_IDR.RTR, [29] AFL[7]_IDR.LPC, [28:0] AFL[7]_IDR.ID
0x87470194 CANFD
  [31] AFL[7]_MASK.IDEM, [30] AFL[7]_MASK.RTRM, [29] AFL[7]_MASK.IFL1, [28:0] AFL[7]_MASK.IDM
0x87470198 CANFD
  [31:16] AFL[7]_PTR0.PTR, [15] AFL[7]_PTR0.DMBE, [12:8] AFL[7]_PTR0.DMB, [7] AFL[7]_PTR0.IFL0, [3:0] AFL[7]_PTR0.DLC
0x8747019C CANFD
  [8] AFL[7]_PTR1.CF0E, [1] AFL[7]_PTR1.RF1E, [0] AFL[7]_PTR1.RF0E
0x874701A0 CANFD
  [31] AFL[8]_IDR.IDE, [30] AFL[8]_IDR.RTR, [29] AFL[8]_IDR.LPC, [28:0] AFL[8]_IDR.ID
0x874701A4 CANFD
  [31] AFL[8]_MASK.IDEM, [30] AFL[8]_MASK.RTRM, [29] AFL[8]_MASK.IFL1, [28:0] AFL[8]_MASK.IDM
0x874701A8 CANFD
  [31:16] AFL[8]_PTR0.PTR, [15] AFL[8]_PTR0.DMBE, [12:8] AFL[8]_PTR0.DMB, [7] AFL[8]_PTR0.IFL0, [3:0] AFL[8]_PTR0.DLC
0x874701AC CANFD
  [8] AFL[8]_PTR1.CF0E, [1] AFL[8]_PTR1.RF1E, [0] AFL[8]_PTR1.RF0E
0x874701B0 CANFD
  [31] AFL[9]_IDR.IDE, [30] AFL[9]_IDR.RTR, [29] AFL[9]_IDR.LPC, [28:0] AFL[9]_IDR.ID
0x874701B4 CANFD
  [31] AFL[9]_MASK.IDEM, [30] AFL[9]_MASK.RTRM, [29] AFL[9]_MASK.IFL1, [28:0] AFL[9]_MASK.IDM
0x874701B8 CANFD
  [31:16] AFL[9]_PTR0.PTR, [15] AFL[9]_PTR0.DMBE, [12:8] AFL[9]_PTR0.DMB, [7] AFL[9]_PTR0.IFL0, [3:0] AFL[9]_PTR0.DLC
0x874701BC CANFD
  [8] AFL[9]_PTR1.CF0E, [1] AFL[9]_PTR1.RF1E, [0] AFL[9]_PTR1.RF0E
0x874701C0 CANFD
  [31] AFL[10]_IDR.IDE, [30] AFL[10]_IDR.RTR, [29] AFL[10]_IDR.LPC, [28:0] AFL[10]_IDR.ID
0x874701C4 CANFD
  [31] AFL[10]_MASK.IDEM, [30] AFL[10]_MASK.RTRM, [29] AFL[10]_MASK.IFL1, [28:0] AFL[10]_MASK.IDM
0x874701C8 CANFD
  [31:16] AFL[10]_PTR0.PTR, [15] AFL[10]_PTR0.DMBE, [12:8] AFL[10]_PTR0.DMB, [7] AFL[10]_PTR0.IFL0, [3:0] AFL[10]_PTR0.DLC
0x874701CC CANFD
  [8] AFL[10]_PTR1.CF0E, [1] AFL[10]_PTR1.RF1E, [0] AFL[10]_PTR1.RF0E
0x874701D0 CANFD
  [31] AFL[11]_IDR.IDE, [30] AFL[11]_IDR.RTR, [29] AFL[11]_IDR.LPC, [28:0] AFL[11]_IDR.ID
0x874701D4 CANFD
  [31] AFL[11]_MASK.IDEM, [30] AFL[11]_MASK.RTRM, [29] AFL[11]_MASK.IFL1, [28:0] AFL[11]_MASK.IDM
0x874701D8 CANFD
  [31:16] AFL[11]_PTR0.PTR, [15] AFL[11]_PTR0.DMBE, [12:8] AFL[11]_PTR0.DMB, [7] AFL[11]_PTR0.IFL0, [3:0] AFL[11]_PTR0.DLC
0x874701DC CANFD
  [8] AFL[11]_PTR1.CF0E, [1] AFL[11]_PTR1.RF1E, [0] AFL[11]_PTR1.RF0E
0x874701E0 CANFD
  [31] AFL[12]_IDR.IDE, [30] AFL[12]_IDR.RTR, [29] AFL[12]_IDR.LPC, [28:0] AFL[12]_IDR.ID
0x874701E4 CANFD
  [31] AFL[12]_MASK.IDEM, [30] AFL[12]_MASK.RTRM, [29] AFL[12]_MASK.IFL1, [28:0] AFL[12]_MASK.IDM
0x874701E8 CANFD
  [31:16] AFL[12]_PTR0.PTR, [15] AFL[12]_PTR0.DMBE, [12:8] AFL[12]_PTR0.DMB, [7] AFL[12]_PTR0.IFL0, [3:0] AFL[12]_PTR0.DLC
0x874701EC CANFD
  [8] AFL[12]_PTR1.CF0E, [1] AFL[12]_PTR1.RF1E, [0] AFL[12]_PTR1.RF0E
0x874701F0 CANFD
  [31] AFL[13]_IDR.IDE, [30] AFL[13]_IDR.RTR, [29] AFL[13]_IDR.LPC, [28:0] AFL[13]_IDR.ID
0x874701F4 CANFD
  [31] AFL[13]_MASK.IDEM, [30] AFL[13]_MASK.RTRM, [29] AFL[13]_MASK.IFL1, [28:0] AFL[13]_MASK.IDM
0x874701F8 CANFD
  [31:16] AFL[13]_PTR0.PTR, [15] AFL[13]_PTR0.DMBE, [12:8] AFL[13]_PTR0.DMB, [7] AFL[13]_PTR0.IFL0, [3:0] AFL[13]_PTR0.DLC
0x874701FC CANFD
  [8] AFL[13]_PTR1.CF0E, [1] AFL[13]_PTR1.RF1E, [0] AFL[13]_PTR1.RF0E
0x87470200 CANFD
  [31] AFL[14]_IDR.IDE, [30] AFL[14]_IDR.RTR, [29] AFL[14]_IDR.LPC, [28:0] AFL[14]_IDR.ID
0x87470204 CANFD
  [31] AFL[14]_MASK.IDEM, [30] AFL[14]_MASK.RTRM, [29] AFL[14]_MASK.IFL1, [28:0] AFL[14]_MASK.IDM
0x87470208 CANFD
  [31:16] AFL[14]_PTR0.PTR, [15] AFL[14]_PTR0.DMBE, [12:8] AFL[14]_PTR0.DMB, [7] AFL[14]_PTR0.IFL0, [3:0] AFL[14]_PTR0.DLC
0x8747020C CANFD
  [8] AFL[14]_PTR1.CF0E, [1] AFL[14]_PTR1.RF1E, [0] AFL[14]_PTR1.RF0E
0x87470210 CANFD
  [31] AFL[15]_IDR.IDE, [30] AFL[15]_IDR.RTR, [29] AFL[15]_IDR.LPC, [28:0] AFL[15]_IDR.ID
0x87470214 CANFD
  [31] AFL[15]_MASK.IDEM, [30] AFL[15]_MASK.RTRM, [29] AFL[15]_MASK.IFL1, [28:0] AFL[15]_MASK.IDM
0x87470218 CANFD
  [31:16] AFL[15]_PTR0.PTR, [15] AFL[15]_PTR0.DMBE, [12:8] AFL[15]_PTR0.DMB, [7] AFL[15]_PTR0.IFL0, [3:0] AFL[15]_PTR0.DLC
0x8747021C CANFD
  [8] AFL[15]_PTR1.CF0E, [1] AFL[15]_PTR1.RF1E, [0] AFL[15]_PTR1.RF0E
0x87470520 CANFD
  [31] RFB[0]_HF0.IDE, [30] RFB[0]_HF0.RTR, [28:0] RFB[0]_HF0.ID
0x87470524 CANFD
  [31:28] RFB[0]_HF1.DLC, [15:0] RFB[0]_HF1.TS
0x87470528 CANFD
  [31:16] RFB[0]_HF2.PTR, [9:8] RFB[0]_HF2.IFL, [2] RFB[0]_HF2.FDF, [1] RFB[0]_HF2.BRS, [0] RFB[0]_HF2.ESI
0x8747056C CANFD
  [31] RFB[1]_HF0.IDE, [30] RFB[1]_HF0.RTR, [28:0] RFB[1]_HF0.ID
0x87470570 CANFD
  [31:28] RFB[1]_HF1.DLC, [15:0] RFB[1]_HF1.TS
0x87470574 CANFD
  [31:16] RFB[1]_HF2.PTR, [9:8] RFB[1]_HF2.IFL, [2] RFB[1]_HF2.FDF, [1] RFB[1]_HF2.BRS, [0] RFB[1]_HF2.ESI
0x874705B8 CANFD
  [31] CFB[0]_HF0.IDE, [30] CFB[0]_HF0.RTR, [29] CFB[0]_HF0.THENT, [28:0] CFB[0]_HF0.ID
0x874705BC CANFD
  [31:28] CFB[0]_HF1.DLC, [15:0] CFB[0]_HF1.TS
0x874705C0 CANFD
  [31:16] CFB[0]_HF2.PTR, [9:8] CFB[0]_HF2.IFL, [2] CFB[0]_HF2.FDF, [1] CFB[0]_HF2.BRS, [0] CFB[0]_HF2.ESI
0x87470604 CANFD
  [31] TMB[0]_HF0.IDE, [30] TMB[0]_HF0.RTR, [29] TMB[0]_HF0.THENT, [28:0] TMB[0]_HF0.ID
0x87470608 CANFD
  [31:28] TMB[0]_HF1.DLC
0x8747060C CANFD
  [31:16] TMB[0]_HF2.PTR, [9:8] TMB[0]_HF2.IFL, [2] TMB[0]_HF2.FDF, [1] TMB[0]_HF2.BRS, [0] TMB[0]_HF2.ESI
0x87470650 CANFD
  [31] TMB[1]_HF0.IDE, [30] TMB[1]_HF0.RTR, [29] TMB[1]_HF0.THENT, [28:0] TMB[1]_HF0.ID
0x87470654 CANFD
  [31:28] TMB[1]_HF1.DLC
0x87470658 CANFD
  [31:16] TMB[1]_HF2.PTR, [9:8] TMB[1]_HF2.IFL, [2] TMB[1]_HF2.FDF, [1] TMB[1]_HF2.BRS, [0] TMB[1]_HF2.ESI
0x8747069C CANFD
  [31] TMB[2]_HF0.IDE, [30] TMB[2]_HF0.RTR, [29] TMB[2]_HF0.THENT, [28:0] TMB[2]_HF0.ID
0x874706A0 CANFD
  [31:28] TMB[2]_HF1.DLC
0x874706A4 CANFD
  [31:16] TMB[2]_HF2.PTR, [9:8] TMB[2]_HF2.IFL, [2] TMB[2]_HF2.FDF, [1] TMB[2]_HF2.BRS, [0] TMB[2]_HF2.ESI
0x874706E8 CANFD
  [31] TMB[3]_HF0.IDE, [30] TMB[3]_HF0.RTR, [29] TMB[3]_HF0.THENT, [28:0] TMB[3]_HF0.ID
0x874706EC CANFD
  [31:28] TMB[3]_HF1.DLC
0x874706F0 CANFD
  [31:16] TMB[3]_HF2.PTR, [9:8] TMB[3]_HF2.IFL, [2] TMB[3]_HF2.FDF, [1] TMB[3]_HF2.BRS, [0] TMB[3]_HF2.ESI
0x87470740 CANFD2
  [31:16] THACR0.TS, [4:3] THACR0.BN, [2:0] THACR0.BT
0x87470744 CANFD2
  [17:16] THACR1.IFL, [15:0] THACR1.PTR
0x87470920 CANFD
  [31] RMB0.HF0.IDE, [30] RMB0.HF0.RTR, [28:0] RMB0.HF0.ID
0x87470924 CANFD
  [31:28] RMB0.HF1.DLC, [15:0] RMB0.HF1.TS
0x87470928 CANFD
  [31:16] RMB0.HF2.PTR, [9:8] RMB0.HF2.IFL, [2] RMB0.HF2.FDF, [1] RMB0.HF2.BRS, [0] RMB0.HF2.ESI
0x8747096C CANFD
  [31] RMB1.HF0.IDE, [30] RMB1.HF0.RTR, [28:0] RMB1.HF0.ID
0x87470970 CANFD
  [31:28] RMB1.HF1.DLC, [15:0] RMB1.HF1.TS
0x87470974 CANFD
  [31:16] RMB1.HF2.PTR, [9:8] RMB1.HF2.IFL, [2] RMB1.HF2.FDF, [1] RMB1.HF2.BRS, [0] RMB1.HF2.ESI
0x874709B8 CANFD
  [31] RMB2.HF0.IDE, [30] RMB2.HF0.RTR, [28:0] RMB2.HF0.ID
0x874709BC CANFD
  [31:28] RMB2.HF1.DLC, [15:0] RMB2.HF1.TS
0x874709C0 CANFD
  [31:16] RMB2.HF2.PTR, [9:8] RMB2.HF2.IFL, [2] RMB2.HF2.FDF, [1] RMB2.HF2.BRS, [0] RMB2.HF2.ESI
0x87470A04 CANFD
  [31] RMB3.HF0.IDE, [30] RMB3.HF0.RTR, [28:0] RMB3.HF0.ID
0x87470A08 CANFD
  [31:28] RMB3.HF1.DLC, [15:0] RMB3.HF1.TS
0x87470A0C CANFD
  [31:16] RMB3.HF2.PTR, [9:8] RMB3.HF2.IFL, [2] RMB3.HF2.FDF, [1] RMB3.HF2.BRS, [0] RMB3.HF2.ESI
0x87470A50 CANFD
  [31] RMB4.HF0.IDE, [30] RMB4.HF0.RTR, [28:0] RMB4.HF0.ID
0x87470A54 CANFD
  [31:28] RMB4.HF1.DLC, [15:0] RMB4.HF1.TS
0x87470A58 CANFD
  [31:16] RMB4.HF2.PTR, [9:8] RMB4.HF2.IFL, [2] RMB4.HF2.FDF, [1] RMB4.HF2.BRS, [0] RMB4.HF2.ESI
0x87470A9C CANFD
  [31] RMB5.HF0.IDE, [30] RMB5.HF0.RTR, [28:0] RMB5.HF0.ID
0x87470AA0 CANFD
  [31:28] RMB5.HF1.DLC, [15:0] RMB5.HF1.TS
0x87470AA4 CANFD
  [31:16] RMB5.HF2.PTR, [9:8] RMB5.HF2.IFL, [2] RMB5.HF2.FDF, [1] RMB5.HF2.BRS, [0] RMB5.HF2.ESI
0x87470AE8 CANFD
  [31] RMB6.HF0.IDE, [30] RMB6.HF0.RTR, [28:0] RMB6.HF0.ID
0x87470AEC CANFD
  [31:28] RMB6.HF1.DLC, [15:0] RMB6.HF1.TS
0x87470AF0 CANFD
  [31:16] RMB6.HF2.PTR, [9:8] RMB6.HF2.IFL, [2] RMB6.HF2.FDF, [1] RMB6.HF2.BRS, [0] RMB6.HF2.ESI
0x87470B34 CANFD
  [31] RMB7.HF0.IDE, [30] RMB7.HF0.RTR, [28:0] RMB7.HF0.ID
0x87470B38 CANFD
  [31:28] RMB7.HF1.DLC, [15:0] RMB7.HF1.TS
0x87470B3C CANFD
  [31:16] RMB7.HF2.PTR, [9:8] RMB7.HF2.IFL, [2] RMB7.HF2.FDF, [1] RMB7.HF2.BRS, [0] RMB7.HF2.ESI
0x87470D20 CANFD
  [31] RMB8.HF0.IDE, [30] RMB8.HF0.RTR, [28:0] RMB8.HF0.ID
0x87470D24 CANFD
  [31:28] RMB8.HF1.DLC, [15:0] RMB8.HF1.TS
0x87470D28 CANFD
  [31:16] RMB8.HF2.PTR, [9:8] RMB8.HF2.IFL, [2] RMB8.HF2.FDF, [1] RMB8.HF2.BRS, [0] RMB8.HF2.ESI
0x87470D6C CANFD
  [31] RMB9.HF0.IDE, [30] RMB9.HF0.RTR, [28:0] RMB9.HF0.ID
0x87470D70 CANFD
  [31:28] RMB9.HF1.DLC, [15:0] RMB9.HF1.TS
0x87470D74 CANFD
  [31:16] RMB9.HF2.PTR, [9:8] RMB9.HF2.IFL, [2] RMB9.HF2.FDF, [1] RMB9.HF2.BRS, [0] RMB9.HF2.ESI
0x87470DB8 CANFD
  [31] RMB10.HF0.IDE, [30] RMB10.HF0.RTR, [28:0] RMB10.HF0.ID
0x87470DBC CANFD
  [31:28] RMB10.HF1.DLC, [15:0] RMB10.HF1.TS
0x87470DC0 CANFD
  [31:16] RMB10.HF2.PTR, [9:8] RMB10.HF2.IFL, [2] RMB10.HF2.FDF, [1] RMB10.HF2.BRS, [0] RMB10.HF2.ESI
0x87470E04 CANFD
  [31] RMB11.HF0.IDE, [30] RMB11.HF0.RTR, [28:0] RMB11.HF0.ID
0x87470E08 CANFD
  [31:28] RMB11.HF1.DLC, [15:0] RMB11.HF1.TS
0x87470E0C CANFD
  [31:16] RMB11.HF2.PTR, [9:8] RMB11.HF2.IFL, [2] RMB11.HF2.FDF, [1] RMB11.HF2.BRS, [0] RMB11.HF2.ESI
0x87470E50 CANFD
  [31] RMB12.HF0.IDE, [30] RMB12.HF0.RTR, [28:0] RMB12.HF0.ID
0x87470E54 CANFD
  [31:28] RMB12.HF1.DLC, [15:0] RMB12.HF1.TS
0x87470E58 CANFD
  [31:16] RMB12.HF2.PTR, [9:8] RMB12.HF2.IFL, [2] RMB12.HF2.FDF, [1] RMB12.HF2.BRS, [0] RMB12.HF2.ESI
0x87470E9C CANFD
  [31] RMB13.HF0.IDE, [30] RMB13.HF0.RTR, [28:0] RMB13.HF0.ID
0x87470EA0 CANFD
  [31:28] RMB13.HF1.DLC, [15:0] RMB13.HF1.TS
0x87470EA4 CANFD
  [31:16] RMB13.HF2.PTR, [9:8] RMB13.HF2.IFL, [2] RMB13.HF2.FDF, [1] RMB13.HF2.BRS, [0] RMB13.HF2.ESI
0x87470EE8 CANFD
  [31] RMB14.HF0.IDE, [30] RMB14.HF0.RTR, [28:0] RMB14.HF0.ID
0x87470EEC CANFD
  [31:28] RMB14.HF1.DLC, [15:0] RMB14.HF1.TS
0x87470EF0 CANFD
  [31:16] RMB14.HF2.PTR, [9:8] RMB14.HF2.IFL, [2] RMB14.HF2.FDF, [1] RMB14.HF2.BRS, [0] RMB14.HF2.ESI
0x87470F34 CANFD
  [31] RMB15.HF0.IDE, [30] RMB15.HF0.RTR, [28:0] RMB15.HF0.ID
0x87470F38 CANFD
  [31:28] RMB15.HF1.DLC, [15:0] RMB15.HF1.TS
0x87470F3C CANFD
  [31:16] RMB15.HF2.PTR, [9:8] RMB15.HF2.IFL, [2] RMB15.HF2.FDF, [1] RMB15.HF2.BRS, [0] RMB15.HF2.ESI
0x87471120 CANFD
  [31] RMB16.HF0.IDE, [30] RMB16.HF0.RTR, [28:0] RMB16.HF0.ID
0x87471124 CANFD
  [31:28] RMB16.HF1.DLC, [15:0] RMB16.HF1.TS
0x87471128 CANFD
  [31:16] RMB16.HF2.PTR, [9:8] RMB16.HF2.IFL, [2] RMB16.HF2.FDF, [1] RMB16.HF2.BRS, [0] RMB16.HF2.ESI
0x8747116C CANFD
  [31] RMB17.HF0.IDE, [30] RMB17.HF0.RTR, [28:0] RMB17.HF0.ID
0x87471170 CANFD
  [31:28] RMB17.HF1.DLC, [15:0] RMB17.HF1.TS
0x87471174 CANFD
  [31:16] RMB17.HF2.PTR, [9:8] RMB17.HF2.IFL, [2] RMB17.HF2.FDF, [1] RMB17.HF2.BRS, [0] RMB17.HF2.ESI
0x874711B8 CANFD
  [31] RMB18.HF0.IDE, [30] RMB18.HF0.RTR, [28:0] RMB18.HF0.ID
0x874711BC CANFD
  [31:28] RMB18.HF1.DLC, [15:0] RMB18.HF1.TS
0x874711C0 CANFD
  [31:16] RMB18.HF2.PTR, [9:8] RMB18.HF2.IFL, [2] RMB18.HF2.FDF, [1] RMB18.HF2.BRS, [0] RMB18.HF2.ESI
0x87471204 CANFD
  [31] RMB19.HF0.IDE, [30] RMB19.HF0.RTR, [28:0] RMB19.HF0.ID
0x87471208 CANFD
  [31:28] RMB19.HF1.DLC, [15:0] RMB19.HF1.TS
0x8747120C CANFD
  [31:16] RMB19.HF2.PTR, [9:8] RMB19.HF2.IFL, [2] RMB19.HF2.FDF, [1] RMB19.HF2.BRS, [0] RMB19.HF2.ESI
0x87471250 CANFD
  [31] RMB20.HF0.IDE, [30] RMB20.HF0.RTR, [28:0] RMB20.HF0.ID
0x87471254 CANFD
  [31:28] RMB20.HF1.DLC, [15:0] RMB20.HF1.TS
0x87471258 CANFD
  [31:16] RMB20.HF2.PTR, [9:8] RMB20.HF2.IFL, [2] RMB20.HF2.FDF, [1] RMB20.HF2.BRS, [0] RMB20.HF2.ESI
0x8747129C CANFD
  [31] RMB21.HF0.IDE, [30] RMB21.HF0.RTR, [28:0] RMB21.HF0.ID
0x874712A0 CANFD
  [31:28] RMB21.HF1.DLC, [15:0] RMB21.HF1.TS
0x874712A4 CANFD
  [31:16] RMB21.HF2.PTR, [9:8] RMB21.HF2.IFL, [2] RMB21.HF2.FDF, [1] RMB21.HF2.BRS, [0] RMB21.HF2.ESI
0x874712E8 CANFD
  [31] RMB22.HF0.IDE, [30] RMB22.HF0.RTR, [28:0] RMB22.HF0.ID
0x874712EC CANFD
  [31:28] RMB22.HF1.DLC, [15:0] RMB22.HF1.TS
0x874712F0 CANFD
  [31:16] RMB22.HF2.PTR, [9:8] RMB22.HF2.IFL, [2] RMB22.HF2.FDF, [1] RMB22.HF2.BRS, [0] RMB22.HF2.ESI
0x87471334 CANFD
  [31] RMB23.HF0.IDE, [30] RMB23.HF0.RTR, [28:0] RMB23.HF0.ID
0x87471338 CANFD
  [31:28] RMB23.HF1.DLC, [15:0] RMB23.HF1.TS
0x8747133C CANFD
  [31:16] RMB23.HF2.PTR, [9:8] RMB23.HF2.IFL, [2] RMB23.HF2.FDF, [1] RMB23.HF2.BRS, [0] RMB23.HF2.ESI
0x87471520 CANFD
  [31] RMB24.HF0.IDE, [30] RMB24.HF0.RTR, [28:0] RMB24.HF0.ID
0x87471524 CANFD
  [31:28] RMB24.HF1.DLC, [15:0] RMB24.HF1.TS
0x87471528 CANFD
  [31:16] RMB24.HF2.PTR, [9:8] RMB24.HF2.IFL, [2] RMB24.HF2.FDF, [1] RMB24.HF2.BRS, [0] RMB24.HF2.ESI
0x8747156C CANFD
  [31] RMB25.HF0.IDE, [30] RMB25.HF0.RTR, [28:0] RMB25.HF0.ID
0x87471570 CANFD
  [31:28] RMB25.HF1.DLC, [15:0] RMB25.HF1.TS
0x87471574 CANFD
  [31:16] RMB25.HF2.PTR, [9:8] RMB25.HF2.IFL, [2] RMB25.HF2.FDF, [1] RMB25.HF2.BRS, [0] RMB25.HF2.ESI
0x874715B8 CANFD
  [31] RMB26.HF0.IDE, [30] RMB26.HF0.RTR, [28:0] RMB26.HF0.ID
0x874715BC CANFD
  [31:28] RMB26.HF1.DLC, [15:0] RMB26.HF1.TS
0x874715C0 CANFD
  [31:16] RMB26.HF2.PTR, [9:8] RMB26.HF2.IFL, [2] RMB26.HF2.FDF, [1] RMB26.HF2.BRS, [0] RMB26.HF2.ESI
0x87471604 CANFD
  [31] RMB27.HF0.IDE, [30] RMB27.HF0.RTR, [28:0] RMB27.HF0.ID
0x87471608 CANFD
  [31:28] RMB27.HF1.DLC, [15:0] RMB27.HF1.TS
0x8747160C CANFD
  [31:16] RMB27.HF2.PTR, [9:8] RMB27.HF2.IFL, [2] RMB27.HF2.FDF, [1] RMB27.HF2.BRS, [0] RMB27.HF2.ESI
0x87471650 CANFD
  [31] RMB28.HF0.IDE, [30] RMB28.HF0.RTR, [28:0] RMB28.HF0.ID
0x87471654 CANFD
  [31:28] RMB28.HF1.DLC, [15:0] RMB28.HF1.TS
0x87471658 CANFD
  [31:16] RMB28.HF2.PTR, [9:8] RMB28.HF2.IFL, [2] RMB28.HF2.FDF, [1] RMB28.HF2.BRS, [0] RMB28.HF2.ESI
0x8747169C CANFD
  [31] RMB29.HF0.IDE, [30] RMB29.HF0.RTR, [28:0] RMB29.HF0.ID
0x874716A0 CANFD
  [31:28] RMB29.HF1.DLC, [15:0] RMB29.HF1.TS
0x874716A4 CANFD
  [31:16] RMB29.HF2.PTR, [9:8] RMB29.HF2.IFL, [2] RMB29.HF2.FDF, [1] RMB29.HF2.BRS, [0] RMB29.HF2.ESI
0x874716E8 CANFD
  [31] RMB30.HF0.IDE, [30] RMB30.HF0.RTR, [28:0] RMB30.HF0.ID
0x874716EC CANFD
  [31:28] RMB30.HF1.DLC, [15:0] RMB30.HF1.TS
0x874716F0 CANFD
  [31:16] RMB30.HF2.PTR, [9:8] RMB30.HF2.IFL, [2] RMB30.HF2.FDF, [1] RMB30.HF2.BRS, [0] RMB30.HF2.ESI
0x87471734 CANFD
  [31] RMB31.HF0.IDE, [30] RMB31.HF0.RTR, [28:0] RMB31.HF0.ID
0x87471738 CANFD
  [31:28] RMB31.HF1.DLC, [15:0] RMB31.HF1.TS
0x8747173C CANFD
  [31:16] RMB31.HF2.PTR, [9:8] RMB31.HF2.IFL, [2] RMB31.HF2.FDF, [1] RMB31.HF2.BRS, [0] RMB31.HF2.ESI
0x87480000 CANFDG
  [31:25] CFDC0NCFG.NTSEG2, [24:17] CFDC0NCFG.NTSEG1, [16:10] CFDC0NCFG.NSJW, [9:0] CFDC0NCFG.NBRP
0x87480004 CANFDG
  [31] CFDC0CTR.ROM, [30] CFDC0CTR.CRCT, [26:25] CFDC0CTR.CTMS, [24] CFDC0CTR.CTME, [23] CFDC0CTR.ERRD, [22:21] CFDC0CTR.BOM, [19] CFDC0CTR.TDCVFIE, [18] CFDC0CTR.SOCOIE, [17] CFDC0CTR.EOCOIE, [16] CFDC0CTR.TAIE, [15] CFDC0CTR.ALIE, [14] CFDC0CTR.BLIE, [13] CFDC0CTR.OLIE, [12] CFDC0CTR.BORIE, [11] CFDC0CTR.BOEIE, [10] CFDC0CTR.EPIE, [9] CFDC0CTR.EWIE, [8] CFDC0CTR.BEIE, [3] CFDC0CTR.RTBO, [2] CFDC0CTR.CSLPR, [1:0] CFDC0CTR.CHMDC
0x87480008 CANFDG
  [31:24] CFDC0STS.TEC, [23:16] CFDC0STS.REC, [8] CFDC0STS.ESIF, [7] CFDC0STS.COMSTS, [6] CFDC0STS.RECSTS, [5] CFDC0STS.TRMSTS, [4] CFDC0STS.BOSTS, [3] CFDC0STS.EPSTS, [2] CFDC0STS.CSLPSTS, [1] CFDC0STS.CHLTSTS, [0] CFDC0STS.CRSTSTS
0x8748000C CANFDG
  [30:16] CFDC0ERFL.CRCREG, [14] CFDC0ERFL.ADERR, [13] CFDC0ERFL.B0ERR, [12] CFDC0ERFL.B1ERR, [11] CFDC0ERFL.CERR, [10] CFDC0ERFL.AERR, [9] CFDC0ERFL.FERR, [8] CFDC0ERFL.SERR, [7] CFDC0ERFL.ALF, [6] CFDC0ERFL.BLF, [5] CFDC0ERFL.OVLF, [4] CFDC0ERFL.BORF, [3] CFDC0ERFL.BOEF, [2] CFDC0ERFL.EPF, [1] CFDC0ERFL.EWF, [0] CFDC0ERFL.BEF
0x87480010 CANFDG
  [31:25] CFDC1NCFG.NTSEG2, [24:17] CFDC1NCFG.NTSEG1, [16:10] CFDC1NCFG.NSJW, [9:0] CFDC1NCFG.NBRP
0x87480014 CANFDG
  [31] CFDC1CTR.ROM, [30] CFDC1CTR.CRCT, [26:25] CFDC1CTR.CTMS, [24] CFDC1CTR.CTME, [23] CFDC1CTR.ERRD, [22:21] CFDC1CTR.BOM, [19] CFDC1CTR.TDCVFIE, [18] CFDC1CTR.SOCOIE, [17] CFDC1CTR.EOCOIE, [16] CFDC1CTR.TAIE, [15] CFDC1CTR.ALIE, [14] CFDC1CTR.BLIE, [13] CFDC1CTR.OLIE, [12] CFDC1CTR.BORIE, [11] CFDC1CTR.BOEIE, [10] CFDC1CTR.EPIE, [9] CFDC1CTR.EWIE, [8] CFDC1CTR.BEIE, [3] CFDC1CTR.RTBO, [2] CFDC1CTR.CSLPR, [1:0] CFDC1CTR.CHMDC
0x87480018 CANFDG
  [31:24] CFDC1STS.TEC, [23:16] CFDC1STS.REC, [8] CFDC1STS.ESIF, [7] CFDC1STS.COMSTS, [6] CFDC1STS.RECSTS, [5] CFDC1STS.TRMSTS, [4] CFDC1STS.BOSTS, [3] CFDC1STS.EPSTS, [2] CFDC1STS.CSLPSTS, [1] CFDC1STS.CHLTSTS, [0] CFDC1STS.CRSTSTS
0x8748001C CANFDG
  [30:16] CFDC1ERFL.CRCREG, [14] CFDC1ERFL.ADERR, [13] CFDC1ERFL.B0ERR, [12] CFDC1ERFL.B1ERR, [11] CFDC1ERFL.CERR, [10] CFDC1ERFL.AERR, [9] CFDC1ERFL.FERR, [8] CFDC1ERFL.SERR, [7] CFDC1ERFL.ALF, [6] CFDC1ERFL.BLF, [5] CFDC1ERFL.OVLF, [4] CFDC1ERFL.BORF, [3] CFDC1ERFL.BOEF, [2] CFDC1ERFL.EPF, [1] CFDC1ERFL.EWF, [0] CFDC1ERFL.BEF
0x87480084 CANFDG
  [31:16] CFDGCFG.ITRCP, [15:13] CFDGCFG.TSBTCS, [12] CFDGCFG.TSSS, [11:8] CFDGCFG.TSP, [5] CFDGCFG.CMPOC, [4] CFDGCFG.DCS, [3] CFDGCFG.MME, [2] CFDGCFG.DRE, [1] CFDGCFG.DCE, [0] CFDGCFG.TPRI
0x87480088 CANFDG
  [16] CFDGCTR.TSRST, [15] CFDGCTR.MOWEIE, [14] CFDGCTR.QMEIE, [11] CFDGCTR.CMPOFIE, [10] CFDGCTR.THLEIE, [9] CFDGCTR.MEIE, [8] CFDGCTR.DEIE, [2] CFDGCTR.GSLPR, [1:0] CFDGCTR.GMDC
0x8748008C CANFDG
  [3] CFDGSTS.GRAMINIT, [2] CFDGSTS.GSLPSTS, [1] CFDGSTS.GHLTSTS, [0] CFDGSTS.GRSTSTS
0x87480090 CANFDG
  [17] CFDGERFL.EEF1, [16] CFDGERFL.EEF0, [7] CFDGERFL.MOWES, [6] CFDGERFL.QMES, [3] CFDGERFL.CMPOF, [2] CFDGERFL.THLES, [1] CFDGERFL.MES, [0] CFDGERFL.DEF
0x87480094 CANFDG
  [15:0] CFDGTSC.TS
0x87480098 CANFDG
  [8] CFDGAFLECTR.AFLDAE, [6:0] CFDGAFLECTR.AFLPN
0x8748009C CANFDG
  [24:16] CFDGAFLCFG0.RNC0, [8:0] CFDGAFLCFG0.RNC1
0x874800AC CANFDG
  [10:8] CFDRMNB.RMPLS, [7:0] CFDRMNB.NRXMB
0x874800B0 CANFDG
  [31:0] CFDRMND0.RMNSu
0x874800C0 CANFDG
  [16] CFDRFCC[0].RFFIE, [15:13] CFDRFCC[0].RFIGCV, [12] CFDRFCC[0].RFIM, [10:8] CFDRFCC[0].RFDC, [6:4] CFDRFCC[0].RFPLS, [1] CFDRFCC[0].RFIE, [0] CFDRFCC[0].RFE
0x874800C4 CANFDG
  [16] CFDRFCC[1].RFFIE, [15:13] CFDRFCC[1].RFIGCV, [12] CFDRFCC[1].RFIM, [10:8] CFDRFCC[1].RFDC, [6:4] CFDRFCC[1].RFPLS, [1] CFDRFCC[1].RFIE, [0] CFDRFCC[1].RFE
0x874800C8 CANFDG
  [16] CFDRFCC[2].RFFIE, [15:13] CFDRFCC[2].RFIGCV, [12] CFDRFCC[2].RFIM, [10:8] CFDRFCC[2].RFDC, [6:4] CFDRFCC[2].RFPLS, [1] CFDRFCC[2].RFIE, [0] CFDRFCC[2].RFE
0x874800CC CANFDG
  [16] CFDRFCC[3].RFFIE, [15:13] CFDRFCC[3].RFIGCV, [12] CFDRFCC[3].RFIM, [10:8] CFDRFCC[3].RFDC, [6:4] CFDRFCC[3].RFPLS, [1] CFDRFCC[3].RFIE, [0] CFDRFCC[3].RFE
0x874800D0 CANFDG
  [16] CFDRFCC[4].RFFIE, [15:13] CFDRFCC[4].RFIGCV, [12] CFDRFCC[4].RFIM, [10:8] CFDRFCC[4].RFDC, [6:4] CFDRFCC[4].RFPLS, [1] CFDRFCC[4].RFIE, [0] CFDRFCC[4].RFE
0x874800D4 CANFDG
  [16] CFDRFCC[5].RFFIE, [15:13] CFDRFCC[5].RFIGCV, [12] CFDRFCC[5].RFIM, [10:8] CFDRFCC[5].RFDC, [6:4] CFDRFCC[5].RFPLS, [1] CFDRFCC[5].RFIE, [0] CFDRFCC[5].RFE
0x874800D8 CANFDG
  [16] CFDRFCC[6].RFFIE, [15:13] CFDRFCC[6].RFIGCV, [12] CFDRFCC[6].RFIM, [10:8] CFDRFCC[6].RFDC, [6:4] CFDRFCC[6].RFPLS, [1] CFDRFCC[6].RFIE, [0] CFDRFCC[6].RFE
0x874800DC CANFDG
  [16] CFDRFCC[7].RFFIE, [15:13] CFDRFCC[7].RFIGCV, [12] CFDRFCC[7].RFIM, [10:8] CFDRFCC[7].RFDC, [6:4] CFDRFCC[7].RFPLS, [1] CFDRFCC[7].RFIE, [0] CFDRFCC[7].RFE
0x874800E0 CANFDG
  [16] CFDRFSTS[0].RFFIF, [15:8] CFDRFSTS[0].RFMC, [3] CFDRFSTS[0].RFIF, [2] CFDRFSTS[0].RFMLT, [1] CFDRFSTS[0].RFFLL, [0] CFDRFSTS[0].RFEMP
0x874800E4 CANFDG
  [16] CFDRFSTS[1].RFFIF, [15:8] CFDRFSTS[1].RFMC, [3] CFDRFSTS[1].RFIF, [2] CFDRFSTS[1].RFMLT, [1] CFDRFSTS[1].RFFLL, [0] CFDRFSTS[1].RFEMP
0x874800E8 CANFDG
  [16] CFDRFSTS[2].RFFIF, [15:8] CFDRFSTS[2].RFMC, [3] CFDRFSTS[2].RFIF, [2] CFDRFSTS[2].RFMLT, [1] CFDRFSTS[2].RFFLL, [0] CFDRFSTS[2].RFEMP
0x874800EC CANFDG
  [16] CFDRFSTS[3].RFFIF, [15:8] CFDRFSTS[3].RFMC, [3] CFDRFSTS[3].RFIF, [2] CFDRFSTS[3].RFMLT, [1] CFDRFSTS[3].RFFLL, [0] CFDRFSTS[3].RFEMP
0x874800F0 CANFDG
  [16] CFDRFSTS[4].RFFIF, [15:8] CFDRFSTS[4].RFMC, [3] CFDRFSTS[4].RFIF, [2] CFDRFSTS[4].RFMLT, [1] CFDRFSTS[4].RFFLL, [0] CFDRFSTS[4].RFEMP
0x874800F4 CANFDG
  [16] CFDRFSTS[5].RFFIF, [15:8] CFDRFSTS[5].RFMC, [3] CFDRFSTS[5].RFIF, [2] CFDRFSTS[5].RFMLT, [1] CFDRFSTS[5].RFFLL, [0] CFDRFSTS[5].RFEMP
0x874800F8 CANFDG
  [16] CFDRFSTS[6].RFFIF, [15:8] CFDRFSTS[6].RFMC, [3] CFDRFSTS[6].RFIF, [2] CFDRFSTS[6].RFMLT, [1] CFDRFSTS[6].RFFLL, [0] CFDRFSTS[6].RFEMP
0x874800FC CANFDG
  [16] CFDRFSTS[7].RFFIF, [15:8] CFDRFSTS[7].RFMC, [3] CFDRFSTS[7].RFIF, [2] CFDRFSTS[7].RFMLT, [1] CFDRFSTS[7].RFFLL, [0] CFDRFSTS[7].RFEMP
0x87480100 CANFDG
  [7:0] CFDRFPCTR[0].RFPC
0x87480104 CANFDG
  [7:0] CFDRFPCTR[1].RFPC
0x87480108 CANFDG
  [7:0] CFDRFPCTR[2].RFPC
0x8748010C CANFDG
  [7:0] CFDRFPCTR[3].RFPC
0x87480110 CANFDG
  [7:0] CFDRFPCTR[4].RFPC
0x87480114 CANFDG
  [7:0] CFDRFPCTR[5].RFPC
0x87480118 CANFDG
  [7:0] CFDRFPCTR[6].RFPC
0x8748011C CANFDG
  [7:0] CFDRFPCTR[7].RFPC
0x87480120 CANFDG
  [31:24] CFDCFCC[0].CFITT, [23:21] CFDCFCC[0].CFDC, [20:16] CFDCFCC[0].CFTML, [15:13] CFDCFCC[0].CFIGCV, [12] CFDCFCC[0].CFIM, [11] CFDCFCC[0].CFITR, [10] CFDCFCC[0].CFITSS, [9:8] CFDCFCC[0].CFM, [6:4] CFDCFCC[0].CFPLS, [2] CFDCFCC[0].CFTXIE, [1] CFDCFCC[0].CFRXIE, [0] CFDCFCC[0].CFE
0x87480124 CANFDG
  [31:24] CFDCFCC[1].CFITT, [23:21] CFDCFCC[1].CFDC, [20:16] CFDCFCC[1].CFTML, [15:13] CFDCFCC[1].CFIGCV, [12] CFDCFCC[1].CFIM, [11] CFDCFCC[1].CFITR, [10] CFDCFCC[1].CFITSS, [9:8] CFDCFCC[1].CFM, [6:4] CFDCFCC[1].CFPLS, [2] CFDCFCC[1].CFTXIE, [1] CFDCFCC[1].CFRXIE, [0] CFDCFCC[1].CFE
0x87480128 CANFDG
  [31:24] CFDCFCC[2].CFITT, [23:21] CFDCFCC[2].CFDC, [20:16] CFDCFCC[2].CFTML, [15:13] CFDCFCC[2].CFIGCV, [12] CFDCFCC[2].CFIM, [11] CFDCFCC[2].CFITR, [10] CFDCFCC[2].CFITSS, [9:8] CFDCFCC[2].CFM, [6:4] CFDCFCC[2].CFPLS, [2] CFDCFCC[2].CFTXIE, [1] CFDCFCC[2].CFRXIE, [0] CFDCFCC[2].CFE
0x8748012C CANFDG
  [31:24] CFDCFCC[3].CFITT, [23:21] CFDCFCC[3].CFDC, [20:16] CFDCFCC[3].CFTML, [15:13] CFDCFCC[3].CFIGCV, [12] CFDCFCC[3].CFIM, [11] CFDCFCC[3].CFITR, [10] CFDCFCC[3].CFITSS, [9:8] CFDCFCC[3].CFM, [6:4] CFDCFCC[3].CFPLS, [2] CFDCFCC[3].CFTXIE, [1] CFDCFCC[3].CFRXIE, [0] CFDCFCC[3].CFE
0x87480130 CANFDG
  [31:24] CFDCFCC[4].CFITT, [23:21] CFDCFCC[4].CFDC, [20:16] CFDCFCC[4].CFTML, [15:13] CFDCFCC[4].CFIGCV, [12] CFDCFCC[4].CFIM, [11] CFDCFCC[4].CFITR, [10] CFDCFCC[4].CFITSS, [9:8] CFDCFCC[4].CFM, [6:4] CFDCFCC[4].CFPLS, [2] CFDCFCC[4].CFTXIE, [1] CFDCFCC[4].CFRXIE, [0] CFDCFCC[4].CFE
0x87480134 CANFDG
  [31:24] CFDCFCC[5].CFITT, [23:21] CFDCFCC[5].CFDC, [20:16] CFDCFCC[5].CFTML, [15:13] CFDCFCC[5].CFIGCV, [12] CFDCFCC[5].CFIM, [11] CFDCFCC[5].CFITR, [10] CFDCFCC[5].CFITSS, [9:8] CFDCFCC[5].CFM, [6:4] CFDCFCC[5].CFPLS, [2] CFDCFCC[5].CFTXIE, [1] CFDCFCC[5].CFRXIE, [0] CFDCFCC[5].CFE
0x87480180 CANFDG
  [16] CFDCFCCE[0].CFBME, [8] CFDCFCCE[0].CFMOWM, [2] CFDCFCCE[0].CFOFTXIE, [1] CFDCFCCE[0].CFOFRXIE, [0] CFDCFCCE[0].CFFIE
0x87480184 CANFDG
  [16] CFDCFCCE[1].CFBME, [8] CFDCFCCE[1].CFMOWM, [2] CFDCFCCE[1].CFOFTXIE, [1] CFDCFCCE[1].CFOFRXIE, [0] CFDCFCCE[1].CFFIE
0x87480188 CANFDG
  [16] CFDCFCCE[2].CFBME, [8] CFDCFCCE[2].CFMOWM, [2] CFDCFCCE[2].CFOFTXIE, [1] CFDCFCCE[2].CFOFRXIE, [0] CFDCFCCE[2].CFFIE
0x8748018C CANFDG
  [16] CFDCFCCE[3].CFBME, [8] CFDCFCCE[3].CFMOWM, [2] CFDCFCCE[3].CFOFTXIE, [1] CFDCFCCE[3].CFOFRXIE, [0] CFDCFCCE[3].CFFIE
0x87480190 CANFDG
  [16] CFDCFCCE[4].CFBME, [8] CFDCFCCE[4].CFMOWM, [2] CFDCFCCE[4].CFOFTXIE, [1] CFDCFCCE[4].CFOFRXIE, [0] CFDCFCCE[4].CFFIE
0x87480194 CANFDG
  [16] CFDCFCCE[5].CFBME, [8] CFDCFCCE[5].CFMOWM, [2] CFDCFCCE[5].CFOFTXIE, [1] CFDCFCCE[5].CFOFRXIE, [0] CFDCFCCE[5].CFFIE
0x874801E0 CANFDG
  [24] CFDCFSTS[0].CFMOW, [18] CFDCFSTS[0].CFOFTXIF, [17] CFDCFSTS[0].CFOFRXIF, [16] CFDCFSTS[0].CFFIF, [15:8] CFDCFSTS[0].CFMC, [4] CFDCFSTS[0].CFTXIF, [3] CFDCFSTS[0].CFRXIF, [2] CFDCFSTS[0].CFMLT, [1] CFDCFSTS[0].CFFLL, [0] CFDCFSTS[0].CFEMP
0x874801E4 CANFDG
  [24] CFDCFSTS[1].CFMOW, [18] CFDCFSTS[1].CFOFTXIF, [17] CFDCFSTS[1].CFOFRXIF, [16] CFDCFSTS[1].CFFIF, [15:8] CFDCFSTS[1].CFMC, [4] CFDCFSTS[1].CFTXIF, [3] CFDCFSTS[1].CFRXIF, [2] CFDCFSTS[1].CFMLT, [1] CFDCFSTS[1].CFFLL, [0] CFDCFSTS[1].CFEMP
0x874801E8 CANFDG
  [24] CFDCFSTS[2].CFMOW, [18] CFDCFSTS[2].CFOFTXIF, [17] CFDCFSTS[2].CFOFRXIF, [16] CFDCFSTS[2].CFFIF, [15:8] CFDCFSTS[2].CFMC, [4] CFDCFSTS[2].CFTXIF, [3] CFDCFSTS[2].CFRXIF, [2] CFDCFSTS[2].CFMLT, [1] CFDCFSTS[2].CFFLL, [0] CFDCFSTS[2].CFEMP
0x874801EC CANFDG
  [24] CFDCFSTS[3].CFMOW, [18] CFDCFSTS[3].CFOFTXIF, [17] CFDCFSTS[3].CFOFRXIF, [16] CFDCFSTS[3].CFFIF, [15:8] CFDCFSTS[3].CFMC, [4] CFDCFSTS[3].CFTXIF, [3] CFDCFSTS[3].CFRXIF, [2] CFDCFSTS[3].CFMLT, [1] CFDCFSTS[3].CFFLL, [0] CFDCFSTS[3].CFEMP
0x874801F0 CANFDG
  [24] CFDCFSTS[4].CFMOW, [18] CFDCFSTS[4].CFOFTXIF, [17] CFDCFSTS[4].CFOFRXIF, [16] CFDCFSTS[4].CFFIF, [15:8] CFDCFSTS[4].CFMC, [4] CFDCFSTS[4].CFTXIF, [3] CFDCFSTS[4].CFRXIF, [2] CFDCFSTS[4].CFMLT, [1] CFDCFSTS[4].CFFLL, [0] CFDCFSTS[4].CFEMP
0x874801F4 CANFDG
  [24] CFDCFSTS[5].CFMOW, [18] CFDCFSTS[5].CFOFTXIF, [17] CFDCFSTS[5].CFOFRXIF, [16] CFDCFSTS[5].CFFIF, [15:8] CFDCFSTS[5].CFMC, [4] CFDCFSTS[5].CFTXIF, [3] CFDCFSTS[5].CFRXIF, [2] CFDCFSTS[5].CFMLT, [1] CFDCFSTS[5].CFFLL, [0] CFDCFSTS[5].CFEMP
0x87480240 CANFDG
  [7:0] CFDCFPCTR[0].CFPC
0x87480244 CANFDG
  [7:0] CFDCFPCTR[1].CFPC
0x87480248 CANFDG
  [7:0] CFDCFPCTR[2].CFPC
0x8748024C CANFDG
  [7:0] CFDCFPCTR[3].CFPC
0x87480250 CANFDG
  [7:0] CFDCFPCTR[4].CFPC
0x87480254 CANFDG
  [7:0] CFDCFPCTR[5].CFPC
0x874802A0 CANFDG
  [13:8] CFDFESTS.CFxEMP, [7:0] CFDFESTS.RFxEMP
0x874802A4 CANFDG
  [13:8] CFDFFSTS.CFxEMP, [7:0] CFDFFSTS.RFxFLL
0x874802A8 CANFDG
  [13:8] CFDFMSTS.CFxMLT, [7:0] CFDFMSTS.RFxMLT
0x874802AC CANFDG
  [23:16] CFDRFISTS.RFxFFLL, [7:0] CFDRFISTS.RFxIF
0x874802B0 CANFDG
  [5:0] CFDCFRISTS.CFxRXIF
0x874802B4 CANFDG
  [5:0] CFDCFTISTS.CFxTXIF
0x874802B8 CANFDG
  [5:0] CFDCFOFRISTS.CFxOFRXIF
0x874802BC CANFDG
  [5:0] CFDCFOFTISTS.CFxOFTXIF
0x874802C0 CANFDG
  [5:0] CFDCFMOWSTS.CFxMOW
0x874802C4 CANFDG
  [13:8] CFDFFFSTS.CFxFFLL, [7:0] CFDFFFSTS.RFxFFLL
0x874A0007 ESC 8-bit
  [2n+1:2n] PORTDESC.P{n} (n=0..3)
0x874A0008 ESC 16-bit
  [11] FEATURE.FSCONFIG, [10] FEATURE.RWSUPP, [9] FEATURE.LRW, [8] FEATURE.DCSYNC, [7] FEATURE.FCS, [6] FEATURE.LINKDETMII, [3] FEATURE.DCWID, [2] FEATURE.DC, [0] FEATURE.FMMU
0x874A0020 ESC 8-bit
  [0] REGWRENABLE.ENABLE
0x874A0021 ESC 8-bit
  [0] REGWRPROTECT.PROTECT
0x874A0030 ESC 8-bit
  [0] ESCWRENABLE.ENABLE
0x874A0031 ESC 8-bit
  [0] ESCWRPROTECT.PROTECT
# iorx74m register map
Registers are 32-bit, access not given, no defined reset value unless marked. A register's access mark holds for its fields unless they carry their own. Addresses are absolute; registers are grouped by the start of their names; [hi:lo] are bit positions; {n}, {i} and the like mark numbered series.

## SFR (part 6 of 10)
0x874A0040 ESC 8-bit
  [1:0] ESCRESETECAT.RESETECAT
0x874A0041 ESC 8-bit
  [1:0] ESCRESETPDI.RESETPDI
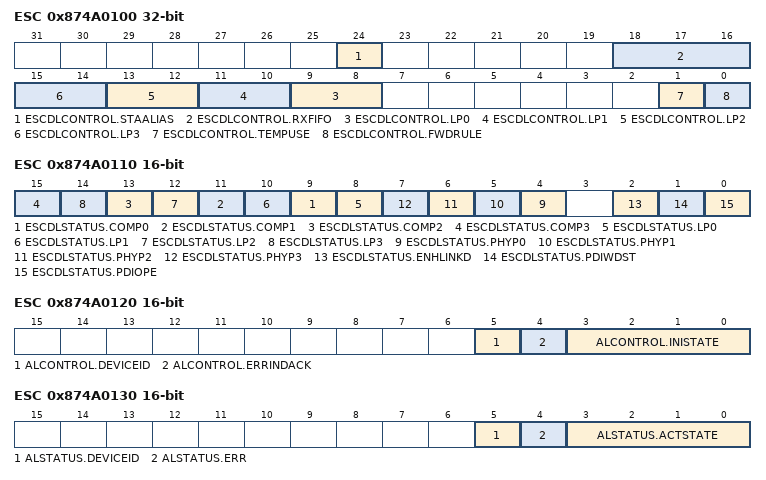
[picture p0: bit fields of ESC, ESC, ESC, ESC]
0x874A0100 ESC
  [24] ESCDLCONTROL.STAALIAS, [18:16] ESCDLCONTROL.RXFIFO, [2n+9:2n+8] ESCDLCONTROL.LP{n} (n=0..3), [1] ESCDLCONTROL.TEMPUSE, [0] ESCDLCONTROL.FWDRULE
0x874A0110 ESC 16-bit
  [2n+9] ESCDLSTATUS.COMP{n} (n=0..3), [2n+8] ESCDLSTATUS.LP{n} (n=0..3), [n+4] ESCDLSTATUS.PHYP{n} (n=0..3), [2] ESCDLSTATUS.ENHLINKD, [1] ESCDLSTATUS.PDIWDST, [0] ESCDLSTATUS.PDIOPE
0x874A0120 ESC 16-bit
  [5] ALCONTROL.DEVICEID, [4] ALCONTROL.ERRINDACK, [3:0] ALCONTROL.INISTATE
0x874A0130 ESC 16-bit
  [5] ALSTATUS.DEVICEID, [4] ALSTATUS.ERR, [3:0] ALSTATUS.ACTSTATE
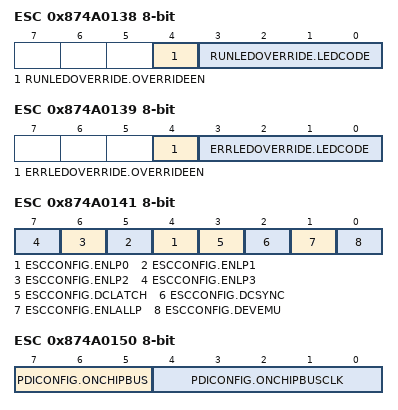
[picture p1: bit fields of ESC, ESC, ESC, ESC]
0x874A0138 ESC 8-bit
  [4] RUNLEDOVERRIDE.OVERRIDEEN, [3:0] RUNLEDOVERRIDE.LEDCODE
0x874A0139 ESC 8-bit
  [4] ERRLEDOVERRIDE.OVERRIDEEN, [3:0] ERRLEDOVERRIDE.LEDCODE
0x874A0141 ESC 8-bit
  [n+4] ESCCONFIG.ENLP{n} (n=0..3), [3] ESCCONFIG.DCLATCH, [2] ESCCONFIG.DCSYNC, [1] ESCCONFIG.ENLALLP, [0] ESCCONFIG.DEVEMU
0x874A0150 ESC 8-bit
  [7:5] PDICONFIG.ONCHIPBUS, [4:0] PDICONFIG.ONCHIPBUSCLK
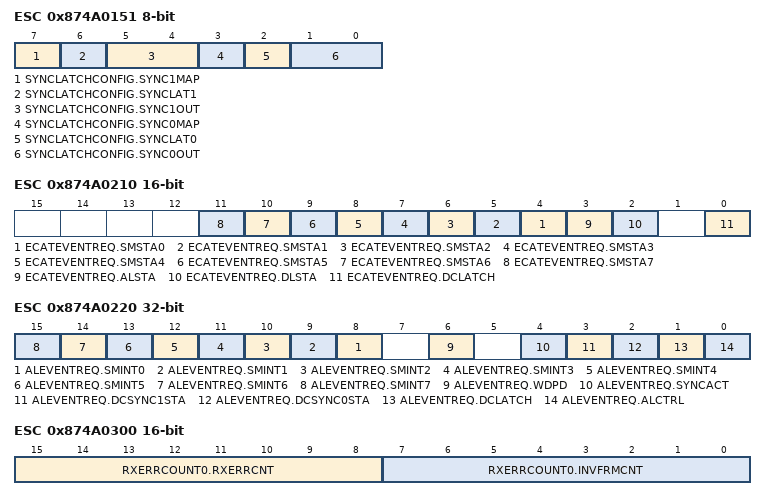
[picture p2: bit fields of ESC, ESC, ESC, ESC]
0x874A0151 ESC 8-bit
  [7] SYNCLATCHCONFIG.SYNC1MAP, [6] SYNCLATCHCONFIG.SYNCLAT1, [5:4] SYNCLATCHCONFIG.SYNC1OUT, [3] SYNCLATCHCONFIG.SYNC0MAP, [2] SYNCLATCHCONFIG.SYNCLAT0, [1:0] SYNCLATCHCONFIG.SYNC0OUT
0x874A0152 ESC 16-bit
  [1:0] EXTPDICONFIG.DATABUSWID
0x874A0210 ESC 16-bit
  [n+4] ECATEVENTREQ.SMSTA{n} (n=0..7), [3] ECATEVENTREQ.ALSTA, [2] ECATEVENTREQ.DLSTA, [0] ECATEVENTREQ.DCLATCH
0x874A0220 ESC
  [n+8] ALEVENTREQ.SMINT{n} (n=0..7), [6] ALEVENTREQ.WDPD, [4] ALEVENTREQ.SYNCACT, [3] ALEVENTREQ.DCSYNC1STA, [2] ALEVENTREQ.DCSYNC0STA, [1] ALEVENTREQ.DCLATCH, [0] ALEVENTREQ.ALCTRL
0x874A0300 ESC 16-bit
  [15:8] RXERRCOUNT0.RXERRCNT, [7:0] RXERRCOUNT0.INVFRMCNT
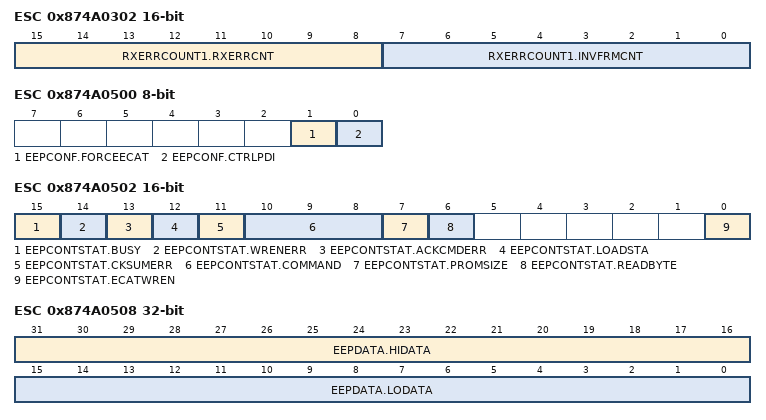
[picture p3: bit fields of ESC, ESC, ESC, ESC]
0x874A0302 ESC 16-bit
  [15:8] RXERRCOUNT1.RXERRCNT, [7:0] RXERRCOUNT1.INVFRMCNT
0x874A0440 ESC 16-bit
  [0] WDSDATA.WDSTAPD
0x874A0500 ESC 8-bit
  [1] EEPCONF.FORCEECAT, [0] EEPCONF.CTRLPDI
0x874A0501 ESC 8-bit
  [0] EEPSTATE.PDIACCESS
0x874A0502 ESC 16-bit
  [15] EEPCONTSTAT.BUSY, [14] EEPCONTSTAT.WRENERR, [13] EEPCONTSTAT.ACKCMDERR, [12] EEPCONTSTAT.LOADSTA, [11] EEPCONTSTAT.CKSUMERR, [10:8] EEPCONTSTAT.COMMAND, [7] EEPCONTSTAT.PROMSIZE, [6] EEPCONTSTAT.READBYTE, [0] EEPCONTSTAT.ECATWREN
0x874A0508 ESC
  [31:16] EEPDATA.HIDATA, [15:0] EEPDATA.LODATA
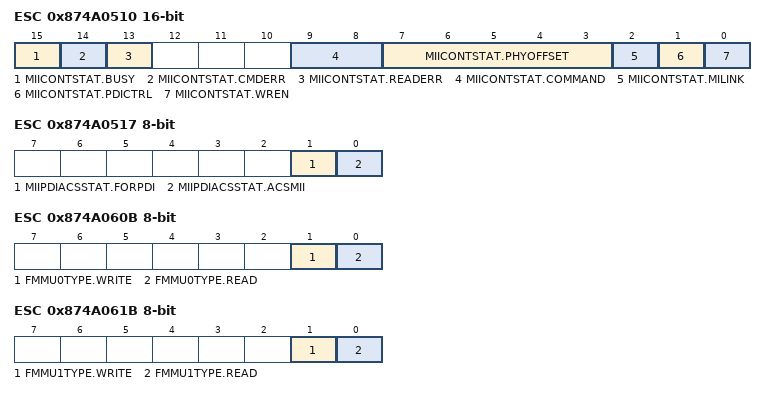
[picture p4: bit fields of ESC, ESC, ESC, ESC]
0x874A0510 ESC 16-bit
  [15] MIICONTSTAT.BUSY, [14] MIICONTSTAT.CMDERR, [13] MIICONTSTAT.READERR, [9:8] MIICONTSTAT.COMMAND, [7:3] MIICONTSTAT.PHYOFFSET, [2] MIICONTSTAT.MILINK, [1] MIICONTSTAT.PDICTRL, [0] MIICONTSTAT.WREN
0x874A0512 ESC 8-bit
  [4:0] PHYADR.PHYADDR
0x874A0513 ESC 8-bit
  [4:0] PHYREGADR.PHYREGADDR
0x874A0516 ESC 8-bit
  [0] MIIECATACSSTAT.ACSMII
0x874A0517 ESC 8-bit
  [1] MIIPDIACSSTAT.FORPDI, [0] MIIPDIACSSTAT.ACSMII
0x874A0606 ESC 8-bit
  [2:0] FMMU0LSTARTBIT.LSTABIT
0x874A0607 ESC 8-bit
  [2:0] FMMU0LSTOPBIT.LSTPBIT
0x874A060A ESC 8-bit
  [2:0] FMMU0PSTARTBIT.PHYSTABIT
0x874A060B ESC 8-bit
  [1] FMMU0TYPE.WRITE, [0] FMMU0TYPE.READ
0x874A060C ESC 8-bit
  [0] FMMU0ACT.ACTIVATE
0x874A0616 ESC 8-bit
  [2:0] FMMU1LSTARTBIT.LSTABIT
0x874A0617 ESC 8-bit
  [2:0] FMMU1LSTOPBIT.LSTPBIT
0x874A061A ESC 8-bit
  [2:0] FMMU1PSTARTBIT.PHYSTABIT
0x874A061B ESC 8-bit
  [1] FMMU1TYPE.WRITE, [0] FMMU1TYPE.READ
0x874A061C ESC 8-bit
  [0] FMMU1ACT.ACTIVATE
0x874A0626 ESC 8-bit
  [2:0] FMMU2LSTARTBIT.LSTABIT
0x874A0627 ESC 8-bit
  [2:0] FMMU2LSTOPBIT.LSTPBIT
0x874A062A ESC 8-bit
  [2:0] FMMU2PSTARTBIT.PHYSTABIT
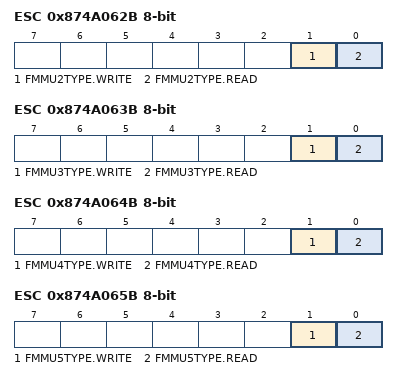
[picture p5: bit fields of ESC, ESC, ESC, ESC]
0x874A062B ESC 8-bit
  [1] FMMU2TYPE.WRITE, [0] FMMU2TYPE.READ
0x874A062C ESC 8-bit
  [0] FMMU2ACT.ACTIVATE
0x874A0636 ESC 8-bit
  [2:0] FMMU3LSTARTBIT.LSTABIT
0x874A0637 ESC 8-bit
  [2:0] FMMU3LSTOPBIT.LSTPBIT
0x874A063A ESC 8-bit
  [2:0] FMMU3PSTARTBIT.PHYSTABIT
0x874A063B ESC 8-bit
  [1] FMMU3TYPE.WRITE, [0] FMMU3TYPE.READ
0x874A063C ESC 8-bit
  [0] FMMU3ACT.ACTIVATE
0x874A0646 ESC 8-bit
  [2:0] FMMU4LSTARTBIT.LSTABIT
0x874A0647 ESC 8-bit
  [2:0] FMMU4LSTOPBIT.LSTPBIT
0x874A064A ESC 8-bit
  [2:0] FMMU4PSTARTBIT.PHYSTABIT
0x874A064B ESC 8-bit
  [1] FMMU4TYPE.WRITE, [0] FMMU4TYPE.READ
0x874A064C ESC 8-bit
  [0] FMMU4ACT.ACTIVATE
0x874A0656 ESC 8-bit
  [2:0] FMMU5LSTARTBIT.LSTABIT
0x874A0657 ESC 8-bit
  [2:0] FMMU5LSTOPBIT.LSTPBIT
0x874A065A ESC 8-bit
  [2:0] FMMU5PSTARTBIT.PHYSTABIT
0x874A065B ESC 8-bit
  [1] FMMU5TYPE.WRITE, [0] FMMU5TYPE.READ
0x874A065C ESC 8-bit
  [0] FMMU5ACT.ACTIVATE
0x874A0666 ESC 8-bit
  [2:0] FMMU6LSTARTBIT.LSTABIT
0x874A0667 ESC 8-bit
  [2:0] FMMU6LSTOPBIT.LSTPBIT
0x874A066A ESC 8-bit
  [2:0] FMMU6PSTARTBIT.PHYSTABIT
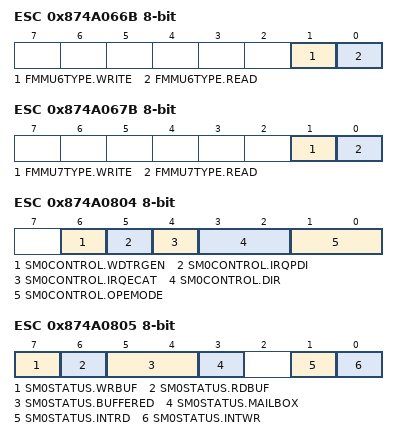
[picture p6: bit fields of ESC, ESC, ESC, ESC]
0x874A066B ESC 8-bit
  [1] FMMU6TYPE.WRITE, [0] FMMU6TYPE.READ
0x874A066C ESC 8-bit
  [0] FMMU6ACT.ACTIVATE
0x874A0676 ESC 8-bit
  [2:0] FMMU7LSTARTBIT.LSTABIT
0x874A0677 ESC 8-bit
  [2:0] FMMU7LSTOPBIT.LSTPBIT
0x874A067A ESC 8-bit
  [2:0] FMMU7PSTARTBIT.PHYSTABIT
0x874A067B ESC 8-bit
  [1] FMMU7TYPE.WRITE, [0] FMMU7TYPE.READ
0x874A067C ESC 8-bit
  [0] FMMU7ACT.ACTIVATE
0x874A0804 ESC 8-bit
  [6] SM0CONTROL.WDTRGEN, [5] SM0CONTROL.IRQPDI, [4] SM0CONTROL.IRQECAT, [3:2] SM0CONTROL.DIR, [1:0] SM0CONTROL.OPEMODE
0x874A0805 ESC 8-bit
  [7] SM0STATUS.WRBUF, [6] SM0STATUS.RDBUF, [5:4] SM0STATUS.BUFFERED, [3] SM0STATUS.MAILBOX, [1] SM0STATUS.INTRD, [0] SM0STATUS.INTWR
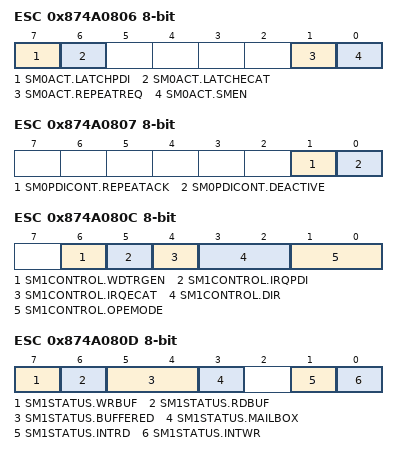
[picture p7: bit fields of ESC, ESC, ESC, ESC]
0x874A0806 ESC 8-bit
  [7] SM0ACT.LATCHPDI, [6] SM0ACT.LATCHECAT, [1] SM0ACT.REPEATREQ, [0] SM0ACT.SMEN
0x874A0807 ESC 8-bit
  [1] SM0PDICONT.REPEATACK, [0] SM0PDICONT.DEACTIVE
0x874A080C ESC 8-bit
  [6] SM1CONTROL.WDTRGEN, [5] SM1CONTROL.IRQPDI, [4] SM1CONTROL.IRQECAT, [3:2] SM1CONTROL.DIR, [1:0] SM1CONTROL.OPEMODE
0x874A080D ESC 8-bit
  [7] SM1STATUS.WRBUF, [6] SM1STATUS.RDBUF, [5:4] SM1STATUS.BUFFERED, [3] SM1STATUS.MAILBOX, [1] SM1STATUS.INTRD, [0] SM1STATUS.INTWR
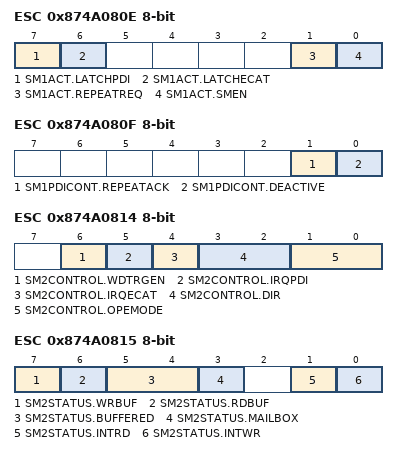
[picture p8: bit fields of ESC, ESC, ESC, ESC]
0x874A080E ESC 8-bit
  [7] SM1ACT.LATCHPDI, [6] SM1ACT.LATCHECAT, [1] SM1ACT.REPEATREQ, [0] SM1ACT.SMEN
0x874A080F ESC 8-bit
  [1] SM1PDICONT.REPEATACK, [0] SM1PDICONT.DEACTIVE
0x874A0814 ESC 8-bit
  [6] SM2CONTROL.WDTRGEN, [5] SM2CONTROL.IRQPDI, [4] SM2CONTROL.IRQECAT, [3:2] SM2CONTROL.DIR, [1:0] SM2CONTROL.OPEMODE
0x874A0815 ESC 8-bit
  [7] SM2STATUS.WRBUF, [6] SM2STATUS.RDBUF, [5:4] SM2STATUS.BUFFERED, [3] SM2STATUS.MAILBOX, [1] SM2STATUS.INTRD, [0] SM2STATUS.INTWR
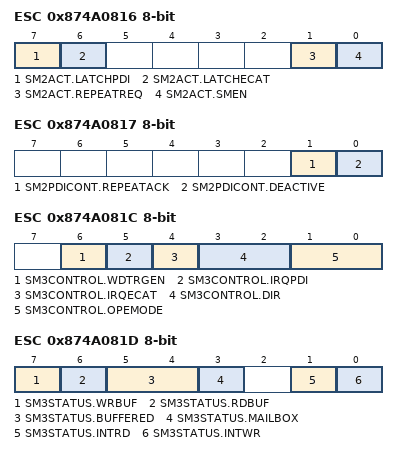
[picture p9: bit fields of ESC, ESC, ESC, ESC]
0x874A0816 ESC 8-bit
  [7] SM2ACT.LATCHPDI, [6] SM2ACT.LATCHECAT, [1] SM2ACT.REPEATREQ, [0] SM2ACT.SMEN
0x874A0817 ESC 8-bit
  [1] SM2PDICONT.REPEATACK, [0] SM2PDICONT.DEACTIVE
0x874A081C ESC 8-bit
  [6] SM3CONTROL.WDTRGEN, [5] SM3CONTROL.IRQPDI, [4] SM3CONTROL.IRQECAT, [3:2] SM3CONTROL.DIR, [1:0] SM3CONTROL.OPEMODE
0x874A081D ESC 8-bit
  [7] SM3STATUS.WRBUF, [6] SM3STATUS.RDBUF, [5:4] SM3STATUS.BUFFERED, [3] SM3STATUS.MAILBOX, [1] SM3STATUS.INTRD, [0] SM3STATUS.INTWR
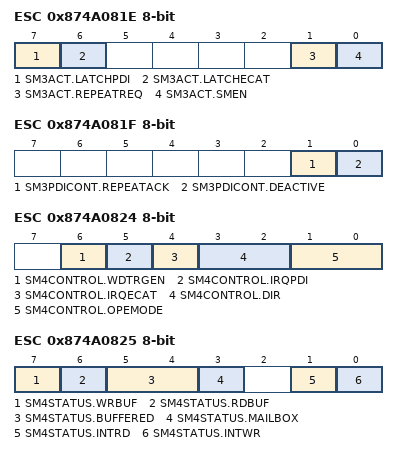
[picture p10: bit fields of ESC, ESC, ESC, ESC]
0x874A081E ESC 8-bit
  [7] SM3ACT.LATCHPDI, [6] SM3ACT.LATCHECAT, [1] SM3ACT.REPEATREQ, [0] SM3ACT.SMEN
0x874A081F ESC 8-bit
  [1] SM3PDICONT.REPEATACK, [0] SM3PDICONT.DEACTIVE
0x874A0824 ESC 8-bit
  [6] SM4CONTROL.WDTRGEN, [5] SM4CONTROL.IRQPDI, [4] SM4CONTROL.IRQECAT, [3:2] SM4CONTROL.DIR, [1:0] SM4CONTROL.OPEMODE
0x874A0825 ESC 8-bit
  [7] SM4STATUS.WRBUF, [6] SM4STATUS.RDBUF, [5:4] SM4STATUS.BUFFERED, [3] SM4STATUS.MAILBOX, [1] SM4STATUS.INTRD, [0] SM4STATUS.INTWR
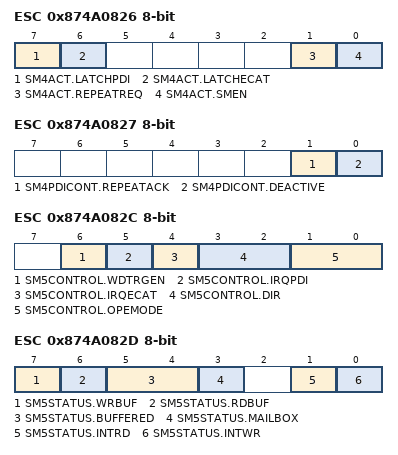
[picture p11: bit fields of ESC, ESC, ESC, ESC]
0x874A0826 ESC 8-bit
  [7] SM4ACT.LATCHPDI, [6] SM4ACT.LATCHECAT, [1] SM4ACT.REPEATREQ, [0] SM4ACT.SMEN
0x874A0827 ESC 8-bit
  [1] SM4PDICONT.REPEATACK, [0] SM4PDICONT.DEACTIVE
0x874A082C ESC 8-bit
  [6] SM5CONTROL.WDTRGEN, [5] SM5CONTROL.IRQPDI, [4] SM5CONTROL.IRQECAT, [3:2] SM5CONTROL.DIR, [1:0] SM5CONTROL.OPEMODE
0x874A082D ESC 8-bit
  [7] SM5STATUS.WRBUF, [6] SM5STATUS.RDBUF, [5:4] SM5STATUS.BUFFERED, [3] SM5STATUS.MAILBOX, [1] SM5STATUS.INTRD, [0] SM5STATUS.INTWR
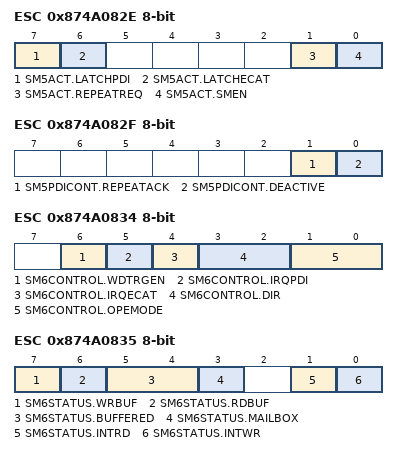
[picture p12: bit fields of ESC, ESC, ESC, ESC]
0x874A082E ESC 8-bit
  [7] SM5ACT.LATCHPDI, [6] SM5ACT.LATCHECAT, [1] SM5ACT.REPEATREQ, [0] SM5ACT.SMEN
0x874A082F ESC 8-bit
  [1] SM5PDICONT.REPEATACK, [0] SM5PDICONT.DEACTIVE
0x874A0834 ESC 8-bit
  [6] SM6CONTROL.WDTRGEN, [5] SM6CONTROL.IRQPDI, [4] SM6CONTROL.IRQECAT, [3:2] SM6CONTROL.DIR, [1:0] SM6CONTROL.OPEMODE
0x874A0835 ESC 8-bit
  [7] SM6STATUS.WRBUF, [6] SM6STATUS.RDBUF, [5:4] SM6STATUS.BUFFERED, [3] SM6STATUS.MAILBOX, [1] SM6STATUS.INTRD, [0] SM6STATUS.INTWR
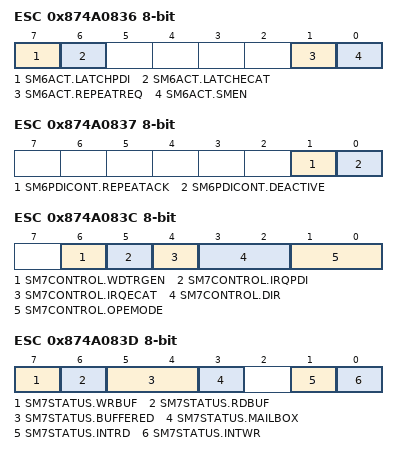
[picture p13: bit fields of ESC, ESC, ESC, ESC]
0x874A0836 ESC 8-bit
  [7] SM6ACT.LATCHPDI, [6] SM6ACT.LATCHECAT, [1] SM6ACT.REPEATREQ, [0] SM6ACT.SMEN
0x874A0837 ESC 8-bit
  [1] SM6PDICONT.REPEATACK, [0] SM6PDICONT.DEACTIVE
0x874A083C ESC 8-bit
  [6] SM7CONTROL.WDTRGEN, [5] SM7CONTROL.IRQPDI, [4] SM7CONTROL.IRQECAT, [3:2] SM7CONTROL.DIR, [1:0] SM7CONTROL.OPEMODE
0x874A083D ESC 8-bit
  [7] SM7STATUS.WRBUF, [6] SM7STATUS.RDBUF, [5:4] SM7STATUS.BUFFERED, [3] SM7STATUS.MAILBOX, [1] SM7STATUS.INTRD, [0] SM7STATUS.INTWR
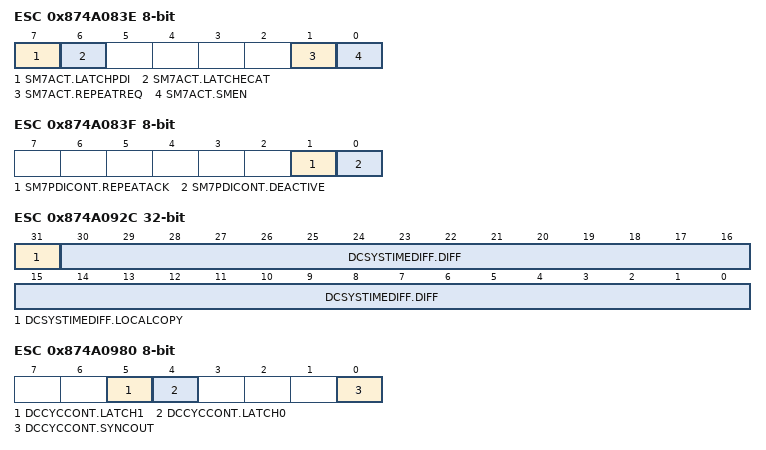
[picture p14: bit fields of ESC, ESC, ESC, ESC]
0x874A083E ESC 8-bit
  [7] SM7ACT.LATCHPDI, [6] SM7ACT.LATCHECAT, [1] SM7ACT.REPEATREQ, [0] SM7ACT.SMEN
0x874A083F ESC 8-bit
  [1] SM7PDICONT.REPEATACK, [0] SM7PDICONT.DEACTIVE
0x874A092C ESC
  [31] DCSYSTIMEDIFF.LOCALCOPY, [30:0] DCSYSTIMEDIFF.DIFF
0x874A0930 ESC 16-bit
  [14:0] DCSCSTART.SCSTART
0x874A0934 ESC 8-bit
  [3:0] DCSYSTIMEFILDP.FILDP
0x874A0935 ESC 8-bit
  [3:0] DCSCFILDP.FILDP
0x874A0980 ESC 8-bit
  [5] DCCYCCONT.LATCH1, [4] DCCYCCONT.LATCH0, [0] DCCYCCONT.SYNCOUT
0x874A0981 ESC 8-bit
  [7] DCACT.DBGPULSE, [6] DCACT.NEARFUTURE, [5] DCACT.STARTTIME, [4] DCACT.EXTSTARTTIME, [3] DCACT.AUTOACT, [2] DCACT.SYNC1, [1] DCACT.SYNC0, [0] DCACT.SYNCACT
0x874A0984 ESC 8-bit
  [2] DCACTSTAT.STARTTIME, [1] DCACTSTAT.SYNC1ACT, [0] DCACTSTAT.SYNC0ACT
0x874A098E ESC 8-bit
  [0] DCSYNC0STAT.SYNC0STA
0x874A098F ESC 8-bit
  [0] DCSYNC1STAT.SYNC1STA
0x874A09A8 ESC 8-bit
  [1] DCLATCH0CONT.NEGEDGE, [0] DCLATCH0CONT.POSEDGE
0x874A09A9 ESC 8-bit
  [1] DCLATCH1CONT.NEGEDGE, [0] DCLATCH1CONT.POSEDGE
0x874A09AE ESC 8-bit
  [2] DCLATCH0STAT.PINSTATE, [1] DCLATCH0STAT.EVENTNEG, [0] DCLATCH0STAT.EVENTPOS
0x874A09AF ESC 8-bit
  [2] DCLATCH1STAT.PINSTATE, [1] DCLATCH1STAT.EVENTNEG, [0] DCLATCH1STAT.EVENTPOS
0x874A4000 ESC
  [1] ESCRST.PHYRST, [0] ESCRST.ESCRST
0x874A4010 ESC
  [1] PHYLINK.LINKPOL1, [0] PHYLINK.LINKPOL0
0x874A4014 ESC
  [5] ESCICR.LAT1S, [4:3] ESCICR.LAT0S, [2] ESCICR.ESCIC, [1] ESCICR.SYNC1C, [0] ESCICR.SYNC0C
0x874A4018 ESC
  [4:0] PHYOFF.OFFSET
0x874A401C ESC
  [0] ESCMR.PROMSIZE
0x874A4020 ESC
  [3:2] TXSFTR.TXSFT1, [1:0] TXSFTR.TXSFT0
0x874C0000 MFWD
  [1:0] FWGC.SVM
0x874C0010 MFWD
  [31:16] FWTTC0.STT, [15:0] FWTTC0.CTT
0x874C0014 MFWD
  [15:0] FWTTC1.RTT
0x874C0020 MFWD
  [24] FWCEPTC.EPSL, [16] FWCEPTC.EPCS, [14:12] FWCEPTC.EPIPV, [5:0] FWCEPTC.EPCSD
0x874C0024 MFWD
  [31] FWCEPRC0.ICL4FEF, [30] FWCEPRC0.ICIP6FEF, [29] FWCEPRC0.ICIP4FEF, [28] FWCEPRC0.ICTFEF, [26] FWCEPRC0.DDFSFEF, [25] FWCEPRC0.DDFEEF, [24] FWCEPRC0.DDEEF, [22] FWCEPRC0.GCKSEEF, [21] FWCEPRC0.GDNEEF, [20] FWCEPRC0.GTFEF, [19] FWCEPRC0.GIIPEEF, [18] FWCEPRC0.GAXEEF, [16] FWCEPRC0.GAREEEF, [13] FWCEPRC0.ECKSEEF, [12] FWCEPRC0.ETFEF, [11] FWCEPRC0.EOEEF, [10] FWCEPRC0.EUEEF, [9] FWCEPRC0.EBOEEF, [8] FWCEPRC0.ERPOOEF, [7] FWCEPRC0.ERFFEF, [6] FWCEPRC0.ECFFCEEF, [5] FWCEPRC0.ECFSEEF, [4] FWCEPRC0.EFFMEEF, [3] FWCEPRC0.EFCSEEF, [2] FWCEPRC0.ENIBEEF, [1] FWCEPRC0.EPCRCEEF, [0] FWCEPRC0.EPHYEEF
0x874C0028 MFWD
  [9] FWCEPRC1.FSFFEF, [8] FWCEPRC1.FIFFEF, [2] FWCEPRC1.FMTRFEF, [1] FWCEPRC1.FGATEFEF, [0] FWCEPRC1.FMSDUFEF
0x874C002C MFWD
  [26] FWCEPRC2.FWMFEF, [25] FWCEPRC2.FIPFSFEF, [24] FWCEPRC2.FLTHFSFEF, [21] FWCEPRC2.FVLANSLFEF, [20] FWCEPRC2.FSMACSLFEF, [19] FWCEPRC2.FDMACSLFEF, [18] FWCEPRC2.FSIPSLFEF, [17] FWCEPRC2.FDIPSLFEF, [16] FWCEPRC2.FLTHSLFEF, [12] FWCEPRC2.FPBNTFEF, [11] FWCEPRC2.FLTWNTFEF, [10] FWCEPRC2.FIPNTFEF, [9] FWCEPRC2.FLTHNTFEF, [8] FWCEPRC2.FDDNTFEF, [5] FWCEPRC2.FVLANUFEF, [4] FWCEPRC2.FSMACUFEF, [3] FWCEPRC2.FDMACUFEF, [2] FWCEPRC2.FSIPUFEF, [1] FWCEPRC2.FDIPUFEF, [0] FWCEPRC2.FLTHUFEF
0x874C0030 MFWD
  [24] FWCLPTC.LPSL, [16] FWCLPTC.LPCS, [14:12] FWCLPTC.LPIPV, [5:0] FWCLPTC.LPCSD
0x874C0034 MFWD
  [7] FWCLPRC.UVLANLF, [6] FWCLPRC.UPSMACLF, [5] FWCLPRC.USMACLF, [4] FWCLPRC.UDMACLF, [3] FWCLPRC.UPSIPLF, [2] FWCLPRC.USIPLF, [1] FWCLPRC.UDIPLF, [0] FWCLPRC.USIDLF
0x874C0040 MFWD
  [24] FWCMPTC.CMPSL, [16] FWCMPTC.CMPCS, [15] FWCMPTC.CMPIPU, [14:12] FWCMPTC.CMPIPV, [5:0] FWCMPTC.CMPCSD
0x874C0044 MFWD
  [24] FWEMPTC.EMPSL, [16] FWEMPTC.EMPPS, [15] FWEMPTC.EMPIPU, [14:12] FWEMPTC.EMPIPV
0x874C0050 MFWD
  [24] FWSDMPTC.SDMPSL, [17:16] FWSDMPTC.SDMPPS, [15] FWSDMPTC.SDMPIPU, [14:12] FWSDMPTC.SDMPIPV, [5:0] FWSDMPTC.SDMPCSD
0x874C0054 MFWD
  [18:16] FWSDMPVC.SDMSV, [2:0] FWSDMPVC.SDMDV
0x874C0080 MFWD
  [n+16] FWLBWMC0.WMFLPR{n} (n=0..15), [n] FWLBWMC0.WMCLPR{n} (n=0..15)
0x874C0084 MFWD
  [n+16] FWLBWMC1.WMFLPR{n} (n=0..15), [n] FWLBWMC1.WMCLPR{n} (n=0..15)
0x874C0088 MFWD
  [n+16] FWLBWMC2.WMFLPR{n} (n=0..15), [n] FWLBWMC2.WMCLPR{n} (n=0..15)
0x874C0100 MFWD
  [30] FWPC00.VLANRUS, [29] FWPC00.VLANRU, [28] FWPC00.VLANSA, [27] FWPC00.MACHMA, [26] FWPC00.MACHLA, [25] FWPC00.MACRUSSA, [24] FWPC00.MACRUSA, [23] FWPC00.MACSSA, [22] FWPC00.MACRUDSA, [21] FWPC00.MACRUDA, [20] FWPC00.MACDSA, [19] FWPC00.IPHMA, [18] FWPC00.IPHLA, [17] FWPC00.IPRUSSA, [16] FWPC00.IPRUSA, [15] FWPC00.IPSSA, [14] FWPC00.IPRUDSA, [13] FWPC00.IPRUDA, [12] FWPC00.IPDSA, [11] FWPC00.IP6EA, [10] FWPC00.IP4EA, [9] FWPC00.L2SE, [8] FWPC00.IP6OE, [7] FWPC00.IP6TE, [6] FWPC00.IP6UE, [5] FWPC00.IP4OE, [4] FWPC00.IP4TE, [3] FWPC00.IP4UE, [2] FWPC00.LTHRUSS, [1] FWPC00.LTHRUS, [0] FWPC00.LTHTA
0x874C0104 MFWD
  [18] FWPC01.LTHFM2, [17] FWPC01.LTHFM1, [16] FWPC01.LTHFM0, [3] FWPC01.UFLTP, [2] FWPC01.FLTP, [1] FWPC01.DDSL, [0] FWPC01.DDE
0x874C0108 MFWD
  [18] FWPC02.LTWFM2, [17] FWPC02.LTWFM1, [16] FWPC02.LTWFM0, [2] FWPC02.IPFM2, [1] FWPC02.IPFM1, [0] FWPC02.IPFM0
0x874C0110 MFWD
  [30] FWPC10.VLANRUS, [29] FWPC10.VLANRU, [28] FWPC10.VLANSA, [27] FWPC10.MACHMA, [26] FWPC10.MACHLA, [25] FWPC10.MACRUSSA, [24] FWPC10.MACRUSA, [23] FWPC10.MACSSA, [22] FWPC10.MACRUDSA, [21] FWPC10.MACRUDA, [20] FWPC10.MACDSA, [19] FWPC10.IPHMA, [18] FWPC10.IPHLA, [17] FWPC10.IPRUSSA, [16] FWPC10.IPRUSA, [15] FWPC10.IPSSA, [14] FWPC10.IPRUDSA, [13] FWPC10.IPRUDA, [12] FWPC10.IPDSA, [11] FWPC10.IP6EA, [10] FWPC10.IP4EA, [9] FWPC10.L2SE, [8] FWPC10.IP6OE, [7] FWPC10.IP6TE, [6] FWPC10.IP6UE, [5] FWPC10.IP4OE, [4] FWPC10.IP4TE, [3] FWPC10.IP4UE, [2] FWPC10.LTHRUSS, [1] FWPC10.LTHRUS, [0] FWPC10.LTHTA
0x874C0114 MFWD
  [18] FWPC11.LTHFM2, [17] FWPC11.LTHFM1, [16] FWPC11.LTHFM0, [3] FWPC11.UFLTP, [2] FWPC11.FLTP, [1] FWPC11.DDSL, [0] FWPC11.DDE
0x874C0118 MFWD
  [18] FWPC12.LTWFM2, [17] FWPC12.LTWFM1, [16] FWPC12.LTWFM0, [2] FWPC12.IPFM2, [1] FWPC12.IPFM1, [0] FWPC12.IPFM0
0x874C0120 MFWD
  [30] FWPC20.VLANRUS, [29] FWPC20.VLANRU, [28] FWPC20.VLANSA, [27] FWPC20.MACHMA, [26] FWPC20.MACHLA, [25] FWPC20.MACRUSSA, [24] FWPC20.MACRUSA, [23] FWPC20.MACSSA, [22] FWPC20.MACRUDSA, [21] FWPC20.MACRUDA, [20] FWPC20.MACDSA, [19] FWPC20.IPHMA, [18] FWPC20.IPHLA, [17] FWPC20.IPRUSSA, [16] FWPC20.IPRUSA, [15] FWPC20.IPSSA, [14] FWPC20.IPRUDSA, [13] FWPC20.IPRUDA, [12] FWPC20.IPDSA, [11] FWPC20.IP6EA, [10] FWPC20.IP4EA, [9] FWPC20.L2SE, [8] FWPC20.IP6OE, [7] FWPC20.IP6TE, [6] FWPC20.IP6UE, [5] FWPC20.IP4OE, [4] FWPC20.IP4TE, [3] FWPC20.IP4UE, [2] FWPC20.LTHRUSS, [1] FWPC20.LTHRUS, [0] FWPC20.LTHTA
0x874C0124 MFWD
  [18] FWPC21.LTHFM2, [17] FWPC21.LTHFM1, [16] FWPC21.LTHFM0, [3] FWPC21.UFLTP, [2] FWPC21.FLTP, [1] FWPC21.DDSL, [0] FWPC21.DDE
0x874C0128 MFWD
  [18] FWPC22.LTWFM2, [17] FWPC22.LTWFM1, [16] FWPC22.LTWFM0, [2] FWPC22.IPFM2, [1] FWPC22.IPFM1, [0] FWPC22.IPFM0
0x874C0400 MFWD
  [14] FWCTGC00.CTRTGI, [13:12] FWCTGC00.CTVCTRL, [11] FWCTGC00.CTFI, [8] FWCTGC00.CTETE, [7] FWCTGC00.CTSDE, [6] FWCTGC00.CTSPE, [5] FWCTGC00.CTSVE, [4] FWCTGC00.CTCDE, [3] FWCTGC00.CTCPE, [2] FWCTGC00.CTCVE, [1] FWCTGC00.CTMSE, [0] FWCTGC00.CTMDE
0x874C0404 MFWD
  [25:0] FWCTGC01.CTMT
0x874C0408 MFWD
  [17] FWCTTC00.CTDFM1, [16] FWCTTC00.CTDFM0, [2:0] FWCTTC00.CTDV
0x874C040C MFWD
  [17] FWCTTC01.CTEME, [16] FWCTTC01.CTCME, [15] FWCTTC01.CTIPU, [14:12] FWCTTC01.CTIPV
0x874C0410 MFWD
  [5:0] FWCTTC020.CTCSD
0x874C0420 MFWD
  [31:0] FWCTSC00.CTDMAU
0x874C0424 MFWD
  [31:16] FWCTSC01.CTDMAL, [15:0] FWCTSC01.CTSMAU
0x874C0428 MFWD
  [31:0] FWCTSC02.CTSMAL
0x874C042C MFWD
  [31] FWCTSC03.CTSD, [30:28] FWCTSC03.CTSP, [27:16] FWCTSC03.CTSV, [15] FWCTSC03.CTCD, [14:12] FWCTSC03.CTCP, [11:0] FWCTSC03.CTCV
0x874C0430 MFWD
  [16] FWCTSC04.CTSPN, [15:0] FWCTSC04.CTET
0x874C0440 MFWD
  [14] FWCTGC10.CTRTGI, [13:12] FWCTGC10.CTVCTRL, [11] FWCTGC10.CTFI, [8] FWCTGC10.CTETE, [7] FWCTGC10.CTSDE, [6] FWCTGC10.CTSPE, [5] FWCTGC10.CTSVE, [4] FWCTGC10.CTCDE, [3] FWCTGC10.CTCPE, [2] FWCTGC10.CTCVE, [1] FWCTGC10.CTMSE, [0] FWCTGC10.CTMDE
0x874C0444 MFWD
  [25:0] FWCTGC11.CTMT
0x874C0448 MFWD
  [17] FWCTTC10.CTDFM1, [16] FWCTTC10.CTDFM0, [2:0] FWCTTC10.CTDV
0x874C044C MFWD
  [17] FWCTTC11.CTEME, [16] FWCTTC11.CTCME, [15] FWCTTC11.CTIPU, [14:12] FWCTTC11.CTIPV
0x874C0450 MFWD
  [5:0] FWCTTC120.CTCSD
0x874C0460 MFWD
  [31:0] FWCTSC10.CTDMAU
0x874C0464 MFWD
  [31:16] FWCTSC11.CTDMAL, [15:0] FWCTSC11.CTSMAU
0x874C0468 MFWD
  [31:0] FWCTSC12.CTSMAL
0x874C046C MFWD
  [31] FWCTSC13.CTSD, [30:28] FWCTSC13.CTSP, [27:16] FWCTSC13.CTSV, [15] FWCTSC13.CTCD, [14:12] FWCTSC13.CTCP, [11:0] FWCTSC13.CTCV
0x874C0470 MFWD
  [16] FWCTSC14.CTSPN, [15:0] FWCTSC14.CTET
0x874C0480 MFWD
  [14] FWCTGC20.CTRTGI, [13:12] FWCTGC20.CTVCTRL, [11] FWCTGC20.CTFI, [8] FWCTGC20.CTETE, [7] FWCTGC20.CTSDE, [6] FWCTGC20.CTSPE, [5] FWCTGC20.CTSVE, [4] FWCTGC20.CTCDE, [3] FWCTGC20.CTCPE, [2] FWCTGC20.CTCVE, [1] FWCTGC20.CTMSE, [0] FWCTGC20.CTMDE
0x874C0484 MFWD
  [25:0] FWCTGC21.CTMT
0x874C0488 MFWD
  [17] FWCTTC20.CTDFM1, [16] FWCTTC20.CTDFM0, [2:0] FWCTTC20.CTDV
0x874C048C MFWD
  [17] FWCTTC21.CTEME, [16] FWCTTC21.CTCME, [15] FWCTTC21.CTIPU, [14:12] FWCTTC21.CTIPV
0x874C0490 MFWD
  [5:0] FWCTTC220.CTCSD
0x874C04A0 MFWD
  [31:0] FWCTSC20.CTDMAU
0x874C04A4 MFWD
  [31:16] FWCTSC21.CTDMAL, [15:0] FWCTSC21.CTSMAU
0x874C04A8 MFWD
  [31:0] FWCTSC22.CTSMAL
0x874C04AC MFWD
  [31] FWCTSC23.CTSD, [30:28] FWCTSC23.CTSP, [27:16] FWCTSC23.CTSV, [15] FWCTSC23.CTCD, [14:12] FWCTSC23.CTCP, [11:0] FWCTSC23.CTCV
0x874C04B0 MFWD
  [16] FWCTSC24.CTSPN, [15:0] FWCTSC24.CTET
0x874C04C0 MFWD
  [14] FWCTGC30.CTRTGI, [13:12] FWCTGC30.CTVCTRL, [11] FWCTGC30.CTFI, [8] FWCTGC30.CTETE, [7] FWCTGC30.CTSDE, [6] FWCTGC30.CTSPE, [5] FWCTGC30.CTSVE, [4] FWCTGC30.CTCDE, [3] FWCTGC30.CTCPE, [2] FWCTGC30.CTCVE, [1] FWCTGC30.CTMSE, [0] FWCTGC30.CTMDE
0x874C04C4 MFWD
  [25:0] FWCTGC31.CTMT
0x874C04C8 MFWD
  [17] FWCTTC30.CTDFM1, [16] FWCTTC30.CTDFM0, [2:0] FWCTTC30.CTDV
0x874C04CC MFWD
  [17] FWCTTC31.CTEME, [16] FWCTTC31.CTCME, [15] FWCTTC31.CTIPU, [14:12] FWCTTC31.CTIPV
0x874C04D0 MFWD
  [5:0] FWCTTC320.CTCSD
0x874C04E0 MFWD
  [31:0] FWCTSC30.CTDMAU
0x874C04E4 MFWD
  [31:16] FWCTSC31.CTDMAL, [15:0] FWCTSC31.CTSMAU
0x874C04E8 MFWD
  [31:0] FWCTSC32.CTSMAL
0x874C04EC MFWD
  [31] FWCTSC33.CTSD, [30:28] FWCTSC33.CTSP, [27:16] FWCTSC33.CTSV, [15] FWCTSC33.CTCD, [14:12] FWCTSC33.CTCP, [11:0] FWCTSC33.CTCV
0x874C04F0 MFWD
  [16] FWCTSC34.CTSPN, [15:0] FWCTSC34.CTET
0x874C0500 MFWD
  [14] FWCTGC40.CTRTGI, [13:12] FWCTGC40.CTVCTRL, [11] FWCTGC40.CTFI, [8] FWCTGC40.CTETE, [7] FWCTGC40.CTSDE, [6] FWCTGC40.CTSPE, [5] FWCTGC40.CTSVE, [4] FWCTGC40.CTCDE, [3] FWCTGC40.CTCPE, [2] FWCTGC40.CTCVE, [1] FWCTGC40.CTMSE, [0] FWCTGC40.CTMDE
0x874C0504 MFWD
  [25:0] FWCTGC41.CTMT
0x874C0508 MFWD
  [17] FWCTTC40.CTDFM1, [16] FWCTTC40.CTDFM0, [2:0] FWCTTC40.CTDV
0x874C050C MFWD
  [17] FWCTTC41.CTEME, [16] FWCTTC41.CTCME, [15] FWCTTC41.CTIPU, [14:12] FWCTTC41.CTIPV
0x874C0510 MFWD
  [5:0] FWCTTC420.CTCSD
0x874C0520 MFWD
  [31:0] FWCTSC40.CTDMAU
0x874C0524 MFWD
  [31:16] FWCTSC41.CTDMAL, [15:0] FWCTSC41.CTSMAU
0x874C0528 MFWD
  [31:0] FWCTSC42.CTSMAL
0x874C052C MFWD
  [31] FWCTSC43.CTSD, [30:28] FWCTSC43.CTSP, [27:16] FWCTSC43.CTSV, [15] FWCTSC43.CTCD, [14:12] FWCTSC43.CTCP, [11:0] FWCTSC43.CTCV
0x874C0530 MFWD
  [16] FWCTSC44.CTSPN, [15:0] FWCTSC44.CTET
0x874C0540 MFWD
  [14] FWCTGC50.CTRTGI, [13:12] FWCTGC50.CTVCTRL, [11] FWCTGC50.CTFI, [8] FWCTGC50.CTETE, [7] FWCTGC50.CTSDE, [6] FWCTGC50.CTSPE, [5] FWCTGC50.CTSVE, [4] FWCTGC50.CTCDE, [3] FWCTGC50.CTCPE, [2] FWCTGC50.CTCVE, [1] FWCTGC50.CTMSE, [0] FWCTGC50.CTMDE
0x874C0544 MFWD
  [25:0] FWCTGC51.CTMT
0x874C0548 MFWD
  [17] FWCTTC50.CTDFM1, [16] FWCTTC50.CTDFM0, [2:0] FWCTTC50.CTDV
0x874C054C MFWD
  [17] FWCTTC51.CTEME, [16] FWCTTC51.CTCME, [15] FWCTTC51.CTIPU, [14:12] FWCTTC51.CTIPV
0x874C0550 MFWD
  [5:0] FWCTTC520.CTCSD
0x874C0560 MFWD
  [31:0] FWCTSC50.CTDMAU
0x874C0564 MFWD
  [31:16] FWCTSC51.CTDMAL, [15:0] FWCTSC51.CTSMAU
0x874C0568 MFWD
  [31:0] FWCTSC52.CTSMAL
0x874C056C MFWD
  [31] FWCTSC53.CTSD, [30:28] FWCTSC53.CTSP, [27:16] FWCTSC53.CTSV, [15] FWCTSC53.CTCD, [14:12] FWCTSC53.CTCP, [11:0] FWCTSC53.CTCV
0x874C0570 MFWD
  [16] FWCTSC54.CTSPN, [15:0] FWCTSC54.CTET
0x874C0580 MFWD
  [14] FWCTGC60.CTRTGI, [13:12] FWCTGC60.CTVCTRL, [11] FWCTGC60.CTFI, [8] FWCTGC60.CTETE, [7] FWCTGC60.CTSDE, [6] FWCTGC60.CTSPE, [5] FWCTGC60.CTSVE, [4] FWCTGC60.CTCDE, [3] FWCTGC60.CTCPE, [2] FWCTGC60.CTCVE, [1] FWCTGC60.CTMSE, [0] FWCTGC60.CTMDE
0x874C0584 MFWD
  [25:0] FWCTGC61.CTMT
0x874C0588 MFWD
  [17] FWCTTC60.CTDFM1, [16] FWCTTC60.CTDFM0, [2:0] FWCTTC60.CTDV
0x874C058C MFWD
  [17] FWCTTC61.CTEME, [16] FWCTTC61.CTCME, [15] FWCTTC61.CTIPU, [14:12] FWCTTC61.CTIPV
0x874C0590 MFWD
  [5:0] FWCTTC620.CTCSD
0x874C05A0 MFWD
  [31:0] FWCTSC60.CTDMAU
0x874C05A4 MFWD
  [31:16] FWCTSC61.CTDMAL, [15:0] FWCTSC61.CTSMAU
0x874C05A8 MFWD
  [31:0] FWCTSC62.CTSMAL
0x874C05AC MFWD
  [31] FWCTSC63.CTSD, [30:28] FWCTSC63.CTSP, [27:16] FWCTSC63.CTSV, [15] FWCTSC63.CTCD, [14:12] FWCTSC63.CTCP, [11:0] FWCTSC63.CTCV
0x874C05B0 MFWD
  [16] FWCTSC64.CTSPN, [15:0] FWCTSC64.CTET
0x874C05C0 MFWD
  [14] FWCTGC70.CTRTGI, [13:12] FWCTGC70.CTVCTRL, [11] FWCTGC70.CTFI, [8] FWCTGC70.CTETE, [7] FWCTGC70.CTSDE, [6] FWCTGC70.CTSPE, [5] FWCTGC70.CTSVE, [4] FWCTGC70.CTCDE, [3] FWCTGC70.CTCPE, [2] FWCTGC70.CTCVE, [1] FWCTGC70.CTMSE, [0] FWCTGC70.CTMDE
0x874C05C4 MFWD
  [25:0] FWCTGC71.CTMT
0x874C05C8 MFWD
  [17] FWCTTC70.CTDFM1, [16] FWCTTC70.CTDFM0, [2:0] FWCTTC70.CTDV
0x874C05CC MFWD
  [17] FWCTTC71.CTEME, [16] FWCTTC71.CTCME, [15] FWCTTC71.CTIPU, [14:12] FWCTTC71.CTIPV
0x874C05D0 MFWD
  [5:0] FWCTTC720.CTCSD
0x874C05E0 MFWD
  [31:0] FWCTSC70.CTDMAU
0x874C05E4 MFWD
  [31:16] FWCTSC71.CTDMAL, [15:0] FWCTSC71.CTSMAU
0x874C05E8 MFWD
  [31:0] FWCTSC72.CTSMAL
0x874C05EC MFWD
  [31] FWCTSC73.CTSD, [30:28] FWCTSC73.CTSP, [27:16] FWCTSC73.CTSV, [15] FWCTSC73.CTCD, [14:12] FWCTSC73.CTCP, [11:0] FWCTSC73.CTCV
0x874C05F0 MFWD
  [16] FWCTSC74.CTSPN, [15:0] FWCTSC74.CTET
0x874C1000 MFWD
  [23:16] FWTWBFC0.TWBFOV, [8] FWTWBFC0.TWBFM, [1:0] FWTWBFC0.TWBFUM
0x874C1004 MFWD
  [31:16] FWTWBFVC0.TWBFV1, [15:0] FWTWBFVC0.TWBFV0
0x874C1010 MFWD
  [23:16] FWTWBFC1.TWBFOV, [8] FWTWBFC1.TWBFM, [1:0] FWTWBFC1.TWBFUM
0x874C1014 MFWD
  [31:16] FWTWBFVC1.TWBFV1, [15:0] FWTWBFVC1.TWBFV0
0x874C1020 MFWD
  [23:16] FWTWBFC2.TWBFOV, [8] FWTWBFC2.TWBFM, [1:0] FWTWBFC2.TWBFUM
0x874C1024 MFWD
  [31:16] FWTWBFVC2.TWBFV1, [15:0] FWTWBFVC2.TWBFV0
0x874C1030 MFWD
  [23:16] FWTWBFC3.TWBFOV, [8] FWTWBFC3.TWBFM, [1:0] FWTWBFC3.TWBFUM
0x874C1034 MFWD
  [31:16] FWTWBFVC3.TWBFV1, [15:0] FWTWBFVC3.TWBFV0
0x874C1040 MFWD
  [23:16] FWTWBFC4.TWBFOV, [8] FWTWBFC4.TWBFM, [1:0] FWTWBFC4.TWBFUM
0x874C1044 MFWD
  [31:16] FWTWBFVC4.TWBFV1, [15:0] FWTWBFVC4.TWBFV0
0x874C1050 MFWD
  [23:16] FWTWBFC5.TWBFOV, [8] FWTWBFC5.TWBFM, [1:0] FWTWBFC5.TWBFUM
0x874C1054 MFWD
  [31:16] FWTWBFVC5.TWBFV1, [15:0] FWTWBFVC5.TWBFV0
0x874C1060 MFWD
  [23:16] FWTWBFC6.TWBFOV, [8] FWTWBFC6.TWBFM, [1:0] FWTWBFC6.TWBFUM
0x874C1064 MFWD
  [31:16] FWTWBFVC6.TWBFV1, [15:0] FWTWBFVC6.TWBFV0
0x874C1070 MFWD
  [23:16] FWTWBFC7.TWBFOV, [8] FWTWBFC7.TWBFM, [1:0] FWTWBFC7.TWBFUM
0x874C1074 MFWD
  [31:16] FWTWBFVC7.TWBFV1, [15:0] FWTWBFVC7.TWBFV0
0x874C1080 MFWD
  [23:16] FWTWBFC8.TWBFOV, [8] FWTWBFC8.TWBFM, [1:0] FWTWBFC8.TWBFUM
0x874C1084 MFWD
  [31:16] FWTWBFVC8.TWBFV1, [15:0] FWTWBFVC8.TWBFV0
0x874C1090 MFWD
  [23:16] FWTWBFC9.TWBFOV, [8] FWTWBFC9.TWBFM, [1:0] FWTWBFC9.TWBFUM
0x874C1094 MFWD
  [31:16] FWTWBFVC9.TWBFV1, [15:0] FWTWBFVC9.TWBFV0
0x874C10A0 MFWD
  [23:16] FWTWBFC10.TWBFOV, [8] FWTWBFC10.TWBFM, [1:0] FWTWBFC10.TWBFUM
0x874C10A4 MFWD
  [31:16] FWTWBFVC10.TWBFV1, [15:0] FWTWBFVC10.TWBFV0
0x874C10B0 MFWD
  [23:16] FWTWBFC11.TWBFOV, [8] FWTWBFC11.TWBFM, [1:0] FWTWBFC11.TWBFUM
0x874C10B4 MFWD
  [31:16] FWTWBFVC11.TWBFV1, [15:0] FWTWBFVC11.TWBFV0
0x874C10C0 MFWD
  [23:16] FWTWBFC12.TWBFOV, [8] FWTWBFC12.TWBFM, [1:0] FWTWBFC12.TWBFUM
0x874C10C4 MFWD
  [31:16] FWTWBFVC12.TWBFV1, [15:0] FWTWBFVC12.TWBFV0
0x874C10D0 MFWD
  [23:16] FWTWBFC13.TWBFOV, [8] FWTWBFC13.TWBFM, [1:0] FWTWBFC13.TWBFUM
0x874C10D4 MFWD
  [31:16] FWTWBFVC13.TWBFV1, [15:0] FWTWBFVC13.TWBFV0
0x874C10E0 MFWD
  [23:16] FWTWBFC14.TWBFOV, [8] FWTWBFC14.TWBFM, [1:0] FWTWBFC14.TWBFUM
0x874C10E4 MFWD
  [31:16] FWTWBFVC14.TWBFV1, [15:0] FWTWBFVC14.TWBFV0
0x874C10F0 MFWD
  [23:16] FWTWBFC15.TWBFOV, [8] FWTWBFC15.TWBFM, [1:0] FWTWBFC15.TWBFUM
0x874C10F4 MFWD
  [31:16] FWTWBFVC15.TWBFV1, [15:0] FWTWBFVC15.TWBFV0
0x874C1400 MFWD
  [23:16] FWTHBFC0.THBFOV, [1:0] FWTHBFC0.THBFUM
0x874C1404 MFWD
  [23:0] FWTHBFV0C0.THBFV0
0x874C1408 MFWD
  [23:0] FWTHBFV1C0.THBFV1
0x874C1410 MFWD
  [23:16] FWTHBFC1.THBFOV, [1:0] FWTHBFC1.THBFUM
0x874C1414 MFWD
  [23:0] FWTHBFV0C1.THBFV0
0x874C1418 MFWD
  [23:0] FWTHBFV1C1.THBFV1
0x874C1420 MFWD
  [23:16] FWTHBFC2.THBFOV, [1:0] FWTHBFC2.THBFUM
0x874C1424 MFWD
  [23:0] FWTHBFV0C2.THBFV0
0x874C1428 MFWD
  [23:0] FWTHBFV1C2.THBFV1
0x874C1430 MFWD
  [23:16] FWTHBFC3.THBFOV, [1:0] FWTHBFC3.THBFUM
0x874C1434 MFWD
  [23:0] FWTHBFV0C3.THBFV0
0x874C1438 MFWD
  [23:0] FWTHBFV1C3.THBFV1
0x874C1440 MFWD
  [23:16] FWTHBFC4.THBFOV, [1:0] FWTHBFC4.THBFUM
0x874C1444 MFWD
  [23:0] FWTHBFV0C4.THBFV0
0x874C1448 MFWD
  [23:0] FWTHBFV1C4.THBFV1
0x874C1450 MFWD
  [23:16] FWTHBFC5.THBFOV, [1:0] FWTHBFC5.THBFUM
0x874C1454 MFWD
  [23:0] FWTHBFV0C5.THBFV0
0x874C1458 MFWD
  [23:0] FWTHBFV1C5.THBFV1
0x874C1460 MFWD
  [23:16] FWTHBFC6.THBFOV, [1:0] FWTHBFC6.THBFUM
0x874C1464 MFWD
  [23:0] FWTHBFV0C6.THBFV0
0x874C1468 MFWD
  [23:0] FWTHBFV1C6.THBFV1
0x874C1470 MFWD
  [23:16] FWTHBFC7.THBFOV, [1:0] FWTHBFC7.THBFUM
0x874C1474 MFWD
  [23:0] FWTHBFV0C7.THBFV0
0x874C1478 MFWD
  [23:0] FWTHBFV1C7.THBFV1
0x874C1480 MFWD
  [23:16] FWTHBFC8.THBFOV, [1:0] FWTHBFC8.THBFUM
0x874C1484 MFWD
  [23:0] FWTHBFV0C8.THBFV0
0x874C1488 MFWD
  [23:0] FWTHBFV1C8.THBFV1
0x874C1490 MFWD
  [23:16] FWTHBFC9.THBFOV, [1:0] FWTHBFC9.THBFUM
0x874C1494 MFWD
  [23:0] FWTHBFV0C9.THBFV0
0x874C1498 MFWD
  [23:0] FWTHBFV1C9.THBFV1
0x874C14A0 MFWD
  [23:16] FWTHBFC10.THBFOV, [1:0] FWTHBFC10.THBFUM
0x874C14A4 MFWD
  [23:0] FWTHBFV0C10.THBFV0
0x874C14A8 MFWD
  [23:0] FWTHBFV1C10.THBFV1
0x874C14B0 MFWD
  [23:16] FWTHBFC11.THBFOV, [1:0] FWTHBFC11.THBFUM
0x874C14B4 MFWD
  [23:0] FWTHBFV0C11.THBFV0
0x874C14B8 MFWD
  [23:0] FWTHBFV1C11.THBFV1
0x874C14C0 MFWD
  [23:16] FWTHBFC12.THBFOV, [1:0] FWTHBFC12.THBFUM
0x874C14C4 MFWD
  [23:0] FWTHBFV0C12.THBFV0
0x874C14C8 MFWD
  [23:0] FWTHBFV1C12.THBFV1
0x874C14D0 MFWD
  [23:16] FWTHBFC13.THBFOV, [1:0] FWTHBFC13.THBFUM
0x874C14D4 MFWD
  [23:0] FWTHBFV0C13.THBFV0
0x874C14D8 MFWD
  [23:0] FWTHBFV1C13.THBFV1
0x874C14E0 MFWD
  [23:16] FWTHBFC14.THBFOV, [1:0] FWTHBFC14.THBFUM
0x874C14E4 MFWD
  [23:0] FWTHBFV0C14.THBFV0
0x874C14E8 MFWD
  [23:0] FWTHBFV1C14.THBFV1
0x874C14F0 MFWD
  [23:16] FWTHBFC15.THBFOV, [1:0] FWTHBFC15.THBFUM
0x874C14F4 MFWD
  [23:0] FWTHBFV0C15.THBFV0
0x874C14F8 MFWD
  [23:0] FWTHBFV1C15.THBFV1
0x874C1800 MFWD
  [23:16] FWFOBFC0.FOBFOV, [1:0] FWFOBFC0.FOBFUM
0x874C1804 MFWD
  [31:0] FWFOBFV0C0.FOBFV0
0x874C1808 MFWD
  [31:0] FWFOBFV1C0.FOBFV1
0x874C1810 MFWD
  [23:16] FWFOBFC1.FOBFOV, [1:0] FWFOBFC1.FOBFUM
0x874C1814 MFWD
  [31:0] FWFOBFV0C1.FOBFV0
0x874C1818 MFWD
  [31:0] FWFOBFV1C1.FOBFV1
0x874C1820 MFWD
  [23:16] FWFOBFC2.FOBFOV, [1:0] FWFOBFC2.FOBFUM
0x874C1824 MFWD
  [31:0] FWFOBFV0C2.FOBFV0
0x874C1828 MFWD
  [31:0] FWFOBFV1C2.FOBFV1
0x874C1830 MFWD
  [23:16] FWFOBFC3.FOBFOV, [1:0] FWFOBFC3.FOBFUM
0x874C1834 MFWD
  [31:0] FWFOBFV0C3.FOBFV0
0x874C1838 MFWD
  [31:0] FWFOBFV1C3.FOBFV1
0x874C1840 MFWD
  [23:16] FWFOBFC4.FOBFOV, [1:0] FWFOBFC4.FOBFUM
0x874C1844 MFWD
  [31:0] FWFOBFV0C4.FOBFV0
0x874C1848 MFWD
  [31:0] FWFOBFV1C4.FOBFV1
0x874C1850 MFWD
  [23:16] FWFOBFC5.FOBFOV, [1:0] FWFOBFC5.FOBFUM
0x874C1854 MFWD
  [31:0] FWFOBFV0C5.FOBFV0
0x874C1858 MFWD
  [31:0] FWFOBFV1C5.FOBFV1
0x874C1860 MFWD
  [23:16] FWFOBFC6.FOBFOV, [1:0] FWFOBFC6.FOBFUM
0x874C1864 MFWD
  [31:0] FWFOBFV0C6.FOBFV0
0x874C1868 MFWD
  [31:0] FWFOBFV1C6.FOBFV1
0x874C1870 MFWD
  [23:16] FWFOBFC7.FOBFOV, [1:0] FWFOBFC7.FOBFUM
0x874C1874 MFWD
  [31:0] FWFOBFV0C7.FOBFV0
0x874C1878 MFWD
  [31:0] FWFOBFV1C7.FOBFV1
0x874C1880 MFWD
  [23:16] FWFOBFC8.FOBFOV, [1:0] FWFOBFC8.FOBFUM
0x874C1884 MFWD
  [31:0] FWFOBFV0C8.FOBFV0
0x874C1888 MFWD
  [31:0] FWFOBFV1C8.FOBFV1
0x874C1890 MFWD
  [23:16] FWFOBFC9.FOBFOV, [1:0] FWFOBFC9.FOBFUM
0x874C1894 MFWD
  [31:0] FWFOBFV0C9.FOBFV0
0x874C1898 MFWD
  [31:0] FWFOBFV1C9.FOBFV1
0x874C18A0 MFWD
  [23:16] FWFOBFC10.FOBFOV, [1:0] FWFOBFC10.FOBFUM
0x874C18A4 MFWD
  [31:0] FWFOBFV0C10.FOBFV0
0x874C18A8 MFWD
  [31:0] FWFOBFV1C10.FOBFV1
0x874C18B0 MFWD
  [23:16] FWFOBFC11.FOBFOV, [1:0] FWFOBFC11.FOBFUM
0x874C18B4 MFWD
  [31:0] FWFOBFV0C11.FOBFV0
0x874C18B8 MFWD
  [31:0] FWFOBFV1C11.FOBFV1
0x874C18C0 MFWD
  [23:16] FWFOBFC12.FOBFOV, [1:0] FWFOBFC12.FOBFUM
0x874C18C4 MFWD
  [31:0] FWFOBFV0C12.FOBFV0
0x874C18C8 MFWD
  [31:0] FWFOBFV1C12.FOBFV1
0x874C18D0 MFWD
  [23:16] FWFOBFC13.FOBFOV, [1:0] FWFOBFC13.FOBFUM
0x874C18D4 MFWD
  [31:0] FWFOBFV0C13.FOBFV0
0x874C18D8 MFWD
  [31:0] FWFOBFV1C13.FOBFV1
0x874C18E0 MFWD
  [23:16] FWFOBFC14.FOBFOV, [1:0] FWFOBFC14.FOBFUM
0x874C18E4 MFWD
  [31:0] FWFOBFV0C14.FOBFV0
0x874C18E8 MFWD
  [31:0] FWFOBFV1C14.FOBFV1
0x874C18F0 MFWD
  [23:16] FWFOBFC15.FOBFOV, [1:0] FWFOBFC15.FOBFUM
0x874C18F4 MFWD
  [31:0] FWFOBFV0C15.FOBFV0
0x874C18F8 MFWD
  [31:0] FWFOBFV1C15.FOBFV1
0x874C1C00 MFWD
  [23:16] FWRFC0.RFOV, [8] FWRFC0.RFM
0x874C1C04 MFWD
  [19:16] FWRFVC0.RFRV, [15:8] FWRFVC0.RFSV1, [7:0] FWRFVC0.RFSV0
0x874C1C10 MFWD
  [23:16] FWRFC1.RFOV, [8] FWRFC1.RFM
0x874C1C14 MFWD
  [19:16] FWRFVC1.RFRV, [15:8] FWRFVC1.RFSV1, [7:0] FWRFVC1.RFSV0
0x874C2000 MFWD
  [17] FWCFC0.CFPFFV1, [16] FWCFC0.CFPFFV0, [2] FWCFC0.CFEFFV2, [1] FWCFC0.CFEFFV1, [0] FWCFC0.CFEFFV0
0x874C2004 MFWD
  [15] FWCFMC00.CFFV, [6:0] FWCFMC00.CFFN
0x874C2008 MFWD
  [15] FWCFMC01.CFFV, [6:0] FWCFMC01.CFFN
0x874C200C MFWD
  [15] FWCFMC02.CFFV, [6:0] FWCFMC02.CFFN
0x874C2010 MFWD
  [15] FWCFMC03.CFFV, [6:0] FWCFMC03.CFFN
0x874C2014 MFWD
  [15] FWCFMC04.CFFV, [6:0] FWCFMC04.CFFN
0x874C2018 MFWD
  [15] FWCFMC05.CFFV, [6:0] FWCFMC05.CFFN
0x874C201C MFWD
  [15] FWCFMC06.CFFV, [6:0] FWCFMC06.CFFN
0x874C2040 MFWD
  [17] FWCFC1.CFPFFV1, [16] FWCFC1.CFPFFV0, [2] FWCFC1.CFEFFV2, [1] FWCFC1.CFEFFV1, [0] FWCFC1.CFEFFV0
0x874C2044 MFWD
  [15] FWCFMC10.CFFV, [6:0] FWCFMC10.CFFN
0x874C2048 MFWD
  [15] FWCFMC11.CFFV, [6:0] FWCFMC11.CFFN
0x874C204C MFWD
  [15] FWCFMC12.CFFV, [6:0] FWCFMC12.CFFN
0x874C2050 MFWD
  [15] FWCFMC13.CFFV, [6:0] FWCFMC13.CFFN
0x874C2054 MFWD
  [15] FWCFMC14.CFFV, [6:0] FWCFMC14.CFFN
0x874C2058 MFWD
  [15] FWCFMC15.CFFV, [6:0] FWCFMC15.CFFN
0x874C205C MFWD
  [15] FWCFMC16.CFFV, [6:0] FWCFMC16.CFFN
0x874C2080 MFWD
  [17] FWCFC2.CFPFFV1, [16] FWCFC2.CFPFFV0, [2] FWCFC2.CFEFFV2, [1] FWCFC2.CFEFFV1, [0] FWCFC2.CFEFFV0
0x874C2084 MFWD
  [15] FWCFMC20.CFFV, [6:0] FWCFMC20.CFFN
0x874C2088 MFWD
  [15] FWCFMC21.CFFV, [6:0] FWCFMC21.CFFN
0x874C208C MFWD
  [15] FWCFMC22.CFFV, [6:0] FWCFMC22.CFFN
0x874C2090 MFWD
  [15] FWCFMC23.CFFV, [6:0] FWCFMC23.CFFN
0x874C2094 MFWD
  [15] FWCFMC24.CFFV, [6:0] FWCFMC24.CFFN
0x874C2098 MFWD
  [15] FWCFMC25.CFFV, [6:0] FWCFMC25.CFFN
0x874C209C MFWD
  [15] FWCFMC26.CFFV, [6:0] FWCFMC26.CFFN
0x874C20C0 MFWD
  [17] FWCFC3.CFPFFV1, [16] FWCFC3.CFPFFV0, [2] FWCFC3.CFEFFV2, [1] FWCFC3.CFEFFV1, [0] FWCFC3.CFEFFV0
0x874C20C4 MFWD
  [15] FWCFMC30.CFFV, [6:0] FWCFMC30.CFFN
0x874C20C8 MFWD
  [15] FWCFMC31.CFFV, [6:0] FWCFMC31.CFFN
0x874C20CC MFWD
  [15] FWCFMC32.CFFV, [6:0] FWCFMC32.CFFN
0x874C20D0 MFWD
  [15] FWCFMC33.CFFV, [6:0] FWCFMC33.CFFN
0x874C20D4 MFWD
  [15] FWCFMC34.CFFV, [6:0] FWCFMC34.CFFN
0x874C20D8 MFWD
  [15] FWCFMC35.CFFV, [6:0] FWCFMC35.CFFN
0x874C20DC MFWD
  [15] FWCFMC36.CFFV, [6:0] FWCFMC36.CFFN
0x874C2100 MFWD
  [17] FWCFC4.CFPFFV1, [16] FWCFC4.CFPFFV0, [2] FWCFC4.CFEFFV2, [1] FWCFC4.CFEFFV1, [0] FWCFC4.CFEFFV0
0x874C2104 MFWD
  [15] FWCFMC40.CFFV, [6:0] FWCFMC40.CFFN
0x874C2108 MFWD
  [15] FWCFMC41.CFFV, [6:0] FWCFMC41.CFFN
0x874C210C MFWD
  [15] FWCFMC42.CFFV, [6:0] FWCFMC42.CFFN
0x874C2110 MFWD
  [15] FWCFMC43.CFFV, [6:0] FWCFMC43.CFFN
0x874C2114 MFWD
  [15] FWCFMC44.CFFV, [6:0] FWCFMC44.CFFN
0x874C2118 MFWD
  [15] FWCFMC45.CFFV, [6:0] FWCFMC45.CFFN
0x874C211C MFWD
  [15] FWCFMC46.CFFV, [6:0] FWCFMC46.CFFN
0x874C2140 MFWD
  [17] FWCFC5.CFPFFV1, [16] FWCFC5.CFPFFV0, [2] FWCFC5.CFEFFV2, [1] FWCFC5.CFEFFV1, [0] FWCFC5.CFEFFV0
0x874C2144 MFWD
  [15] FWCFMC50.CFFV, [6:0] FWCFMC50.CFFN
0x874C2148 MFWD
  [15] FWCFMC51.CFFV, [6:0] FWCFMC51.CFFN
0x874C214C MFWD
  [15] FWCFMC52.CFFV, [6:0] FWCFMC52.CFFN
0x874C2150 MFWD
  [15] FWCFMC53.CFFV, [6:0] FWCFMC53.CFFN
0x874C2154 MFWD
  [15] FWCFMC54.CFFV, [6:0] FWCFMC54.CFFN
0x874C2158 MFWD
  [15] FWCFMC55.CFFV, [6:0] FWCFMC55.CFFN
0x874C215C MFWD
  [15] FWCFMC56.CFFV, [6:0] FWCFMC56.CFFN
0x874C2180 MFWD
  [17] FWCFC6.CFPFFV1, [16] FWCFC6.CFPFFV0, [2] FWCFC6.CFEFFV2, [1] FWCFC6.CFEFFV1, [0] FWCFC6.CFEFFV0
0x874C2184 MFWD
  [15] FWCFMC60.CFFV, [6:0] FWCFMC60.CFFN
0x874C2188 MFWD
  [15] FWCFMC61.CFFV, [6:0] FWCFMC61.CFFN
0x874C218C MFWD
  [15] FWCFMC62.CFFV, [6:0] FWCFMC62.CFFN
0x874C2190 MFWD
  [15] FWCFMC63.CFFV, [6:0] FWCFMC63.CFFN
0x874C2194 MFWD
  [15] FWCFMC64.CFFV, [6:0] FWCFMC64.CFFN
0x874C2198 MFWD
  [15] FWCFMC65.CFFV, [6:0] FWCFMC65.CFFN
0x874C219C MFWD
  [15] FWCFMC66.CFFV, [6:0] FWCFMC66.CFFN
0x874C21C0 MFWD
  [17] FWCFC7.CFPFFV1, [16] FWCFC7.CFPFFV0, [2] FWCFC7.CFEFFV2, [1] FWCFC7.CFEFFV1, [0] FWCFC7.CFEFFV0
0x874C21C4 MFWD
  [15] FWCFMC70.CFFV, [6:0] FWCFMC70.CFFN
0x874C21C8 MFWD
  [15] FWCFMC71.CFFV, [6:0] FWCFMC71.CFFN
0x874C21CC MFWD
  [15] FWCFMC72.CFFV, [6:0] FWCFMC72.CFFN
0x874C21D0 MFWD
  [15] FWCFMC73.CFFV, [6:0] FWCFMC73.CFFN
0x874C21D4 MFWD
  [15] FWCFMC74.CFFV, [6:0] FWCFMC74.CFFN
0x874C21D8 MFWD
  [15] FWCFMC75.CFFV, [6:0] FWCFMC75.CFFN
0x874C21DC MFWD
  [15] FWCFMC76.CFFV, [6:0] FWCFMC76.CFFN
0x874C2200 MFWD
  [17] FWCFC8.CFPFFV1, [16] FWCFC8.CFPFFV0, [2] FWCFC8.CFEFFV2, [1] FWCFC8.CFEFFV1, [0] FWCFC8.CFEFFV0
0x874C2204 MFWD
  [15] FWCFMC80.CFFV, [6:0] FWCFMC80.CFFN
0x874C2208 MFWD
  [15] FWCFMC81.CFFV, [6:0] FWCFMC81.CFFN
0x874C220C MFWD
  [15] FWCFMC82.CFFV, [6:0] FWCFMC82.CFFN
0x874C2210 MFWD
  [15] FWCFMC83.CFFV, [6:0] FWCFMC83.CFFN
0x874C2214 MFWD
  [15] FWCFMC84.CFFV, [6:0] FWCFMC84.CFFN
0x874C2218 MFWD
  [15] FWCFMC85.CFFV, [6:0] FWCFMC85.CFFN
0x874C221C MFWD
  [15] FWCFMC86.CFFV, [6:0] FWCFMC86.CFFN
0x874C2240 MFWD
  [17] FWCFC9.CFPFFV1, [16] FWCFC9.CFPFFV0, [2] FWCFC9.CFEFFV2, [1] FWCFC9.CFEFFV1, [0] FWCFC9.CFEFFV0
0x874C2244 MFWD
  [15] FWCFMC90.CFFV, [6:0] FWCFMC90.CFFN
0x874C2248 MFWD
  [15] FWCFMC91.CFFV, [6:0] FWCFMC91.CFFN
0x874C224C MFWD
  [15] FWCFMC92.CFFV, [6:0] FWCFMC92.CFFN
0x874C2250 MFWD
  [15] FWCFMC93.CFFV, [6:0] FWCFMC93.CFFN
0x874C2254 MFWD
  [15] FWCFMC94.CFFV, [6:0] FWCFMC94.CFFN
0x874C2258 MFWD
  [15] FWCFMC95.CFFV, [6:0] FWCFMC95.CFFN
0x874C225C MFWD
  [15] FWCFMC96.CFFV, [6:0] FWCFMC96.CFFN
0x874C2280 MFWD
  [17] FWCFC10.CFPFFV1, [16] FWCFC10.CFPFFV0, [2] FWCFC10.CFEFFV2, [1] FWCFC10.CFEFFV1, [0] FWCFC10.CFEFFV0
0x874C2284 MFWD
  [15] FWCFMC100.CFFV, [6:0] FWCFMC100.CFFN
0x874C2288 MFWD
  [15] FWCFMC101.CFFV, [6:0] FWCFMC101.CFFN
0x874C228C MFWD
  [15] FWCFMC102.CFFV, [6:0] FWCFMC102.CFFN
0x874C2290 MFWD
  [15] FWCFMC103.CFFV, [6:0] FWCFMC103.CFFN
0x874C2294 MFWD
  [15] FWCFMC104.CFFV, [6:0] FWCFMC104.CFFN
0x874C2298 MFWD
  [15] FWCFMC105.CFFV, [6:0] FWCFMC105.CFFN
0x874C229C MFWD
  [15] FWCFMC106.CFFV, [6:0] FWCFMC106.CFFN
0x874C22C0 MFWD
  [17] FWCFC11.CFPFFV1, [16] FWCFC11.CFPFFV0, [2] FWCFC11.CFEFFV2, [1] FWCFC11.CFEFFV1, [0] FWCFC11.CFEFFV0
0x874C22C4 MFWD
  [15] FWCFMC110.CFFV, [6:0] FWCFMC110.CFFN
0x874C22C8 MFWD
  [15] FWCFMC111.CFFV, [6:0] FWCFMC111.CFFN
0x874C22CC MFWD
  [15] FWCFMC112.CFFV, [6:0] FWCFMC112.CFFN
0x874C22D0 MFWD
  [15] FWCFMC113.CFFV, [6:0] FWCFMC113.CFFN
0x874C22D4 MFWD
  [15] FWCFMC114.CFFV, [6:0] FWCFMC114.CFFN
0x874C22D8 MFWD
  [15] FWCFMC115.CFFV, [6:0] FWCFMC115.CFFN
0x874C22DC MFWD
  [15] FWCFMC116.CFFV, [6:0] FWCFMC116.CFFN
0x874C2300 MFWD
  [17] FWCFC12.CFPFFV1, [16] FWCFC12.CFPFFV0, [2] FWCFC12.CFEFFV2, [1] FWCFC12.CFEFFV1, [0] FWCFC12.CFEFFV0
0x874C2304 MFWD
  [15] FWCFMC120.CFFV, [6:0] FWCFMC120.CFFN
0x874C2308 MFWD
  [15] FWCFMC121.CFFV, [6:0] FWCFMC121.CFFN
0x874C230C MFWD
  [15] FWCFMC122.CFFV, [6:0] FWCFMC122.CFFN
0x874C2310 MFWD
  [15] FWCFMC123.CFFV, [6:0] FWCFMC123.CFFN
0x874C2314 MFWD
  [15] FWCFMC124.CFFV, [6:0] FWCFMC124.CFFN
0x874C2318 MFWD
  [15] FWCFMC125.CFFV, [6:0] FWCFMC125.CFFN
0x874C231C MFWD
  [15] FWCFMC126.CFFV, [6:0] FWCFMC126.CFFN
0x874C2340 MFWD
  [17] FWCFC13.CFPFFV1, [16] FWCFC13.CFPFFV0, [2] FWCFC13.CFEFFV2, [1] FWCFC13.CFEFFV1, [0] FWCFC13.CFEFFV0
0x874C2344 MFWD
  [15] FWCFMC130.CFFV, [6:0] FWCFMC130.CFFN
0x874C2348 MFWD
  [15] FWCFMC131.CFFV, [6:0] FWCFMC131.CFFN
0x874C234C MFWD
  [15] FWCFMC132.CFFV, [6:0] FWCFMC132.CFFN
0x874C2350 MFWD
  [15] FWCFMC133.CFFV, [6:0] FWCFMC133.CFFN
0x874C2354 MFWD
  [15] FWCFMC134.CFFV, [6:0] FWCFMC134.CFFN
0x874C2358 MFWD
  [15] FWCFMC135.CFFV, [6:0] FWCFMC135.CFFN
0x874C235C MFWD
  [15] FWCFMC136.CFFV, [6:0] FWCFMC136.CFFN
0x874C2380 MFWD
  [17] FWCFC14.CFPFFV1, [16] FWCFC14.CFPFFV0, [2] FWCFC14.CFEFFV2, [1] FWCFC14.CFEFFV1, [0] FWCFC14.CFEFFV0
0x874C2384 MFWD
  [15] FWCFMC140.CFFV, [6:0] FWCFMC140.CFFN
0x874C2388 MFWD
  [15] FWCFMC141.CFFV, [6:0] FWCFMC141.CFFN
0x874C238C MFWD
  [15] FWCFMC142.CFFV, [6:0] FWCFMC142.CFFN
0x874C2390 MFWD
  [15] FWCFMC143.CFFV, [6:0] FWCFMC143.CFFN
0x874C2394 MFWD
  [15] FWCFMC144.CFFV, [6:0] FWCFMC144.CFFN
0x874C2398 MFWD
  [15] FWCFMC145.CFFV, [6:0] FWCFMC145.CFFN
0x874C239C MFWD
  [15] FWCFMC146.CFFV, [6:0] FWCFMC146.CFFN
0x874C23C0 MFWD
  [17] FWCFC15.CFPFFV1, [16] FWCFC15.CFPFFV0, [2] FWCFC15.CFEFFV2, [1] FWCFC15.CFEFFV1, [0] FWCFC15.CFEFFV0
0x874C23C4 MFWD
  [15] FWCFMC150.CFFV, [6:0] FWCFMC150.CFFN
0x874C23C8 MFWD
  [15] FWCFMC151.CFFV, [6:0] FWCFMC151.CFFN
0x874C23CC MFWD
  [15] FWCFMC152.CFFV, [6:0] FWCFMC152.CFFN
0x874C23D0 MFWD
  [15] FWCFMC153.CFFV, [6:0] FWCFMC153.CFFN
0x874C23D4 MFWD
  [15] FWCFMC154.CFFV, [6:0] FWCFMC154.CFFN
0x874C23D8 MFWD
  [15] FWCFMC155.CFFV, [6:0] FWCFMC155.CFFN
0x874C23DC MFWD
  [15] FWCFMC156.CFFV, [6:0] FWCFMC156.CFFN
0x874C4008 MFWD
  [24] FWIP4SC.IP4IDPTS, [23] FWIP4SC.IP4IIDS, [22] FWIP4SC.IP4IISS, [21] FWIP4SC.IP4ICDS, [20] FWIP4SC.IP4ICPS, [19] FWIP4SC.IP4ICVS, [18] FWIP4SC.IP4ISDS, [17] FWIP4SC.IP4ISPS, [16] FWIP4SC.IP4ISVS, [12] FWIP4SC.IP4IDPTH, [11] FWIP4SC.IP4ISPTH, [10] FWIP4SC.IP4IPH, [9] FWIP4SC.IP4IIDH, [8] FWIP4SC.IP4IISH, [7] FWIP4SC.IP4ICDH, [6] FWIP4SC.IP4ICPH, [5] FWIP4SC.IP4ICVH, [4] FWIP4SC.IP4ISDH, [3] FWIP4SC.IP4ISPH, [2] FWIP4SC.IP4ISVH, [1] FWIP4SC.IP4IMSH, [0] FWIP4SC.IP4IMDH
0x874C4018 MFWD
  [24] FWIP6SC.IP6IDPTS, [23] FWIP6SC.IP6II1S, [22] FWIP6SC.IP6II0S, [21] FWIP6SC.IP6ICDS, [20] FWIP6SC.IP6ICPS, [19] FWIP6SC.IP6ICVS, [18] FWIP6SC.IP6ISDS, [17] FWIP6SC.IP6ISPS, [16] FWIP6SC.IP6ISVS, [12] FWIP6SC.IP6IDPTH, [11] FWIP6SC.IP6ISPTH, [10] FWIP6SC.IP6IPH, [9] FWIP6SC.IP6IIDH, [8] FWIP6SC.IP6IISH, [7] FWIP6SC.IP6ICDH, [6] FWIP6SC.IP6ICPH, [5] FWIP6SC.IP6ICVH, [4] FWIP6SC.IP6ISDH, [3] FWIP6SC.IP6ISPH, [2] FWIP6SC.IP6ISVH, [1] FWIP6SC.IP6IMSH, [0] FWIP6SC.IP6IMDH
0x874C401C MFWD
  [23:20] FWIP6OC.IP6IPO1, [16] FWIP6OC.IP6IPOM1, [7:4] FWIP6OC.IP6IPO0, [0] FWIP6OC.IP6IPOM0
0x874C4020 MFWD
  [7] FWL2SC.L2ICDS, [6] FWL2SC.L2ICPS, [5] FWL2SC.L2ICVS, [4] FWL2SC.L2ISDS, [3] FWL2SC.L2ISPS, [2] FWL2SC.L2ISVS, [1] FWL2SC.L2IMSS, [0] FWL2SC.L2IMDS
0x874C4030 MFWD
  [n+16] FWSFHEC.IP6HE{n} (n=0..15), [n] FWSFHEC.IP4HE{n} (n=0..15)
0x874C4040 MFWD
  [31:0] FWSHCR0.SHCMDP0
0x874C4044 MFWD
  [31:16] FWSHCR1.SHCMDP1, [15:0] FWSHCR1.SHCMSP0
0x874C4048 MFWD
  [31:0] FWSHCR2.SHCMSP1
0x874C404C MFWD
  [31:29] FWSHCR3.SHCSP, [28] FWSHCR3.SHCSD, [27:16] FWSHCR3.SHCSV, [15:13] FWSHCR3.SHCCP, [12] FWSHCR3.SHCCD, [11:0] FWSHCR3.SHCCV
0x874C4050 MFWD
  [16] FWSHCR4.SHCFF, [7:0] FWSHCR4.SHCP
0x874C4054 MFWD
  [31:0] FWSHCR5.SHCISP0
0x874C4058 MFWD
  [31:0] FWSHCR6.SHCISP1
0x874C405C MFWD
  [31:0] FWSHCR7.SHCISP2
0x874C4060 MFWD
  [31:0] FWSHCR8.SHCISP3
0x874C4064 MFWD
  [31:0] FWSHCR9.SHCIDP0
0x874C4068 MFWD
  [31:0] FWSHCR10.SHCIDP1
0x874C406C MFWD
  [31:0] FWSHCR11.SHCIDP2
0x874C4070 MFWD
  [31:0] FWSHCR12.SHCIDP3
0x874C4074 MFWD
  [31:16] FWSHCR13.SHCSP, [15:0] FWSHCR13.SHCDP
0x874C4078 MFWD
  [31] FWSHCRR.SHC, [15:0] FWSHCRR.SHCR
0x874C4090 MFWD
  [24:16] FWLTHHEC.LTHHMUE, [7:0] FWLTHHEC.LTHHMC
0x874C4094 MFWD
  [17] FWLTHHC.LTHAH, [16] FWLTHHC.LTHCS, [n] FWLTHHC.LTHHE{n} (n=0..7)
0x874C40A0 MFWD
  [24] FWLTHTL0.LTHLDPFS, [16] FWLTHTL0.LTHED, [8] FWLTHTL0.LTHSLL, [2:0] FWLTHTL0.LTHSLP0
0x874C40A4 MFWD
  [31:0] FWLTHTL1.LTHSLP1
0x874C40A8 MFWD
  [31:0] FWLTHTL2.LTHSLP2
0x874C40AC MFWD
  [31:0] FWLTHTL3.LTHSLP3
0x874C40B0 MFWD
  [31:0] FWLTHTL4.LTHSLP4
0x874C40B4 MFWD
  [31] FWLTHTL5.LTHMSDUVL, [19:16] FWLTHTL5.LTHMSDUNL, [15] FWLTHTL5.LTHGATEVL, [0] FWLTHTL5.LTHGATENL
0x874C40B8 MFWD
  [31] FWLTHTL6.LTHMTRVL, [20:16] FWLTHTL6.LTHMTRNL, [15] FWLTHTL6.LTHFRERVL, [6:0] FWLTHTL6.LTHFRERNL
0x874C40BC MFWD
  [18:16] FWLTHTL7.LTHSLVL, [15] FWLTHTL7.LTHRVL, [7:0] FWLTHTL7.LTHRNL
0x874C40C0 MFWD
  [5:0] FWLTHTL80.LTHCSDL
0x874C40D0 MFWD
  [21] FWLTHTL9.LTHCMEL, [20] FWLTHTL9.LTHEMEL, [19] FWLTHTL9.LTHIPUL, [18:16] FWLTHTL9.LTHIPVL, [2:0] FWLTHTL9.LTHDVL
0x874C40D4 MFWD
  [31] FWLTHTLR.LTHTL, [30] FWLTHTLR.LTHHCO, [23:16] FWLTHTLR.LTHLCN, [4] FWLTHTLR.LTHLCF, [3] FWLTHTLR.LTHLO, [2] FWLTHTLR.LTHLEF, [1] FWLTHTLR.LTHLSF, [0] FWLTHTLR.LTHLF
0x874C40E0 MFWD
  [1] FWLTHTIM.LTHTR, [0] FWLTHTIM.LTHTIOG
0x874C40E4 MFWD
  [24:16] FWLTHTEM.LTHTUEN, [8:0] FWLTHTEM.LTHTEN
# iorx74m register map
Registers are 32-bit, access not given, no defined reset value unless marked. A register's access mark holds for its fields unless they carry their own. Addresses are absolute; registers are grouped by the start of their names; [hi:lo] are bit positions; {n}, {i} and the like mark numbered series.

## SFR (part 7 of 10)
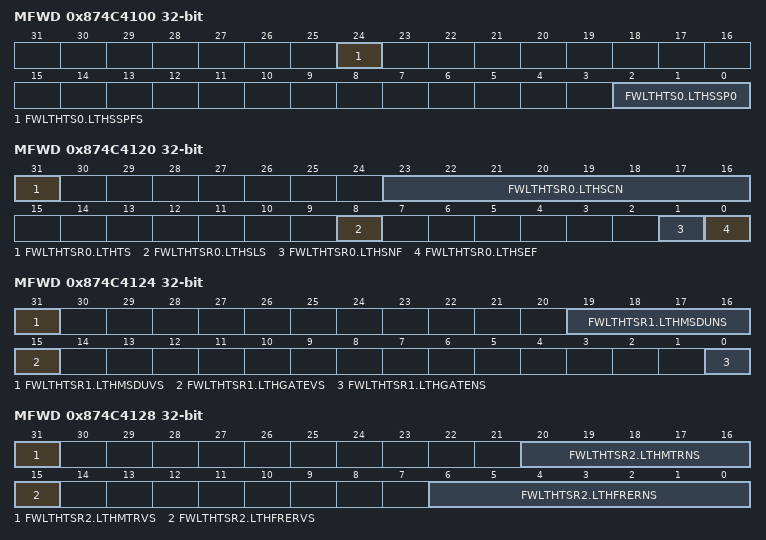
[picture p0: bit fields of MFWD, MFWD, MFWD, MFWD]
0x874C4100 MFWD
  [24] FWLTHTS0.LTHSSPFS, [2:0] FWLTHTS0.LTHSSP0
0x874C4104 MFWD
  [31:0] FWLTHTS1.LTHSSP1
0x874C4108 MFWD
  [31:0] FWLTHTS2.LTHSSP2
0x874C410C MFWD
  [31:0] FWLTHTS3.LTHSSP3
0x874C4110 MFWD
  [31:0] FWLTHTS4.LTHSSP4
0x874C4120 MFWD
  [31] FWLTHTSR0.LTHTS, [23:16] FWLTHTSR0.LTHSCN, [8] FWLTHTSR0.LTHSLS, [1] FWLTHTSR0.LTHSNF, [0] FWLTHTSR0.LTHSEF
0x874C4124 MFWD
  [31] FWLTHTSR1.LTHMSDUVS, [19:16] FWLTHTSR1.LTHMSDUNS, [15] FWLTHTSR1.LTHGATEVS, [0] FWLTHTSR1.LTHGATENS
0x874C4128 MFWD
  [31] FWLTHTSR2.LTHMTRVS, [20:16] FWLTHTSR2.LTHMTRNS, [15] FWLTHTSR2.LTHFRERVS, [6:0] FWLTHTSR2.LTHFRERNS
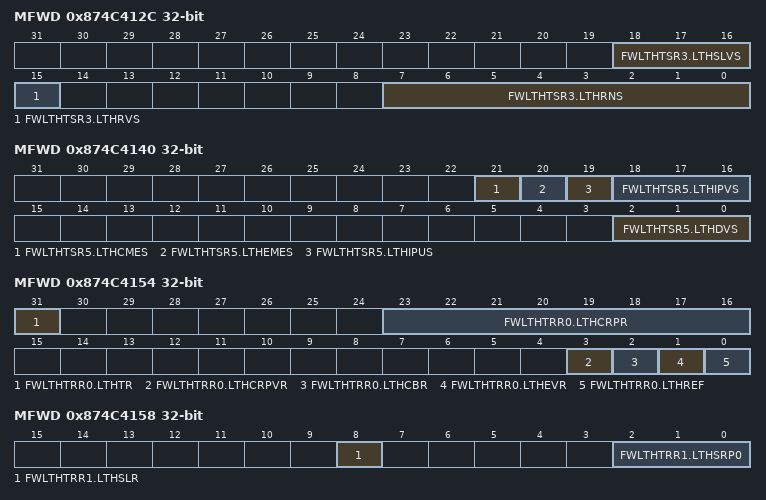
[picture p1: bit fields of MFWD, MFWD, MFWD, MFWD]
0x874C412C MFWD
  [18:16] FWLTHTSR3.LTHSLVS, [15] FWLTHTSR3.LTHRVS, [7:0] FWLTHTSR3.LTHRNS
0x874C4130 MFWD
  [5:0] FWLTHTSR40.LTHCSDS
0x874C4140 MFWD
  [21] FWLTHTSR5.LTHCMES, [20] FWLTHTSR5.LTHEMES, [19] FWLTHTSR5.LTHIPUS, [18:16] FWLTHTSR5.LTHIPVS, [2:0] FWLTHTSR5.LTHDVS
0x874C4150 MFWD
  [7:0] FWLTHTR.LTHAR
0x874C4154 MFWD
  [31] FWLTHTRR0.LTHTR, [23:16] FWLTHTRR0.LTHCRPR, [3] FWLTHTRR0.LTHCRPVR, [2] FWLTHTRR0.LTHCBR, [1] FWLTHTRR0.LTHEVR, [0] FWLTHTRR0.LTHREF
0x874C4158 MFWD
  [8] FWLTHTRR1.LTHSLR, [2:0] FWLTHTRR1.LTHSRP0
0x874C415C MFWD
  [31:0] FWLTHTRR2.LTHSRP1
0x874C4160 MFWD
  [31:0] FWLTHTRR3.LTHSRP2
0x874C4164 MFWD
  [31:0] FWLTHTRR4.LTHSRP3
0x874C4168 MFWD
  [31:0] FWLTHTRR5.LTHSRP4
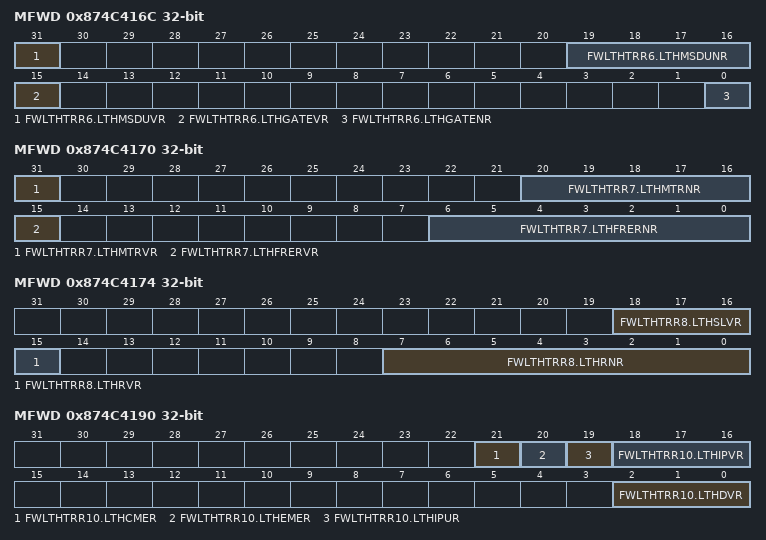
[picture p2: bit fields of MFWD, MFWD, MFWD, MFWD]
0x874C416C MFWD
  [31] FWLTHTRR6.LTHMSDUVR, [19:16] FWLTHTRR6.LTHMSDUNR, [15] FWLTHTRR6.LTHGATEVR, [0] FWLTHTRR6.LTHGATENR
0x874C4170 MFWD
  [31] FWLTHTRR7.LTHMTRVR, [20:16] FWLTHTRR7.LTHMTRNR, [15] FWLTHTRR7.LTHFRERVR, [6:0] FWLTHTRR7.LTHFRERNR
0x874C4174 MFWD
  [18:16] FWLTHTRR8.LTHSLVR, [15] FWLTHTRR8.LTHRVR, [7:0] FWLTHTRR8.LTHRNR
0x874C4180 MFWD
  [5:0] FWLTHTRR90.LTHCSDR
0x874C4190 MFWD
  [21] FWLTHTRR10.LTHCMER, [20] FWLTHTRR10.LTHEMER, [19] FWLTHTRR10.LTHIPUR, [18:16] FWLTHTRR10.LTHIPVR, [2:0] FWLTHTRR10.LTHDVR
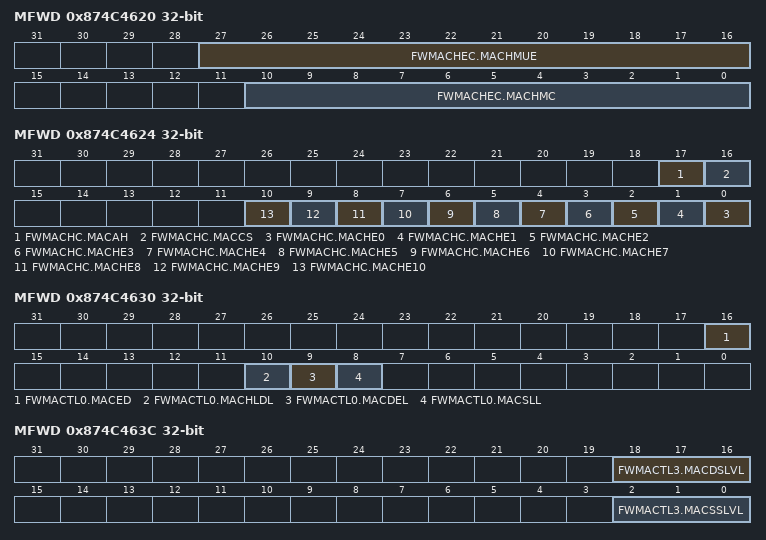
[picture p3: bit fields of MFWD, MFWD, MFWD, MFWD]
0x874C4620 MFWD
  [27:16] FWMACHEC.MACHMUE, [10:0] FWMACHEC.MACHMC
0x874C4624 MFWD
  [17] FWMACHC.MACAH, [16] FWMACHC.MACCS, [n] FWMACHC.MACHE{n} (n=0..10)
0x874C4630 MFWD
  [16] FWMACTL0.MACED, [10] FWMACTL0.MACHLDL, [9] FWMACTL0.MACDEL, [8] FWMACTL0.MACSLL
0x874C4634 MFWD
  [15:0] FWMACTL1.MACMALP0
0x874C4638 MFWD
  [31:0] FWMACTL2.MACMALP1
0x874C463C MFWD
  [18:16] FWMACTL3.MACDSLVL, [2:0] FWMACTL3.MACSSLVL
0x874C4640 MFWD
  [5:0] FWMACTL40.MACCSDL
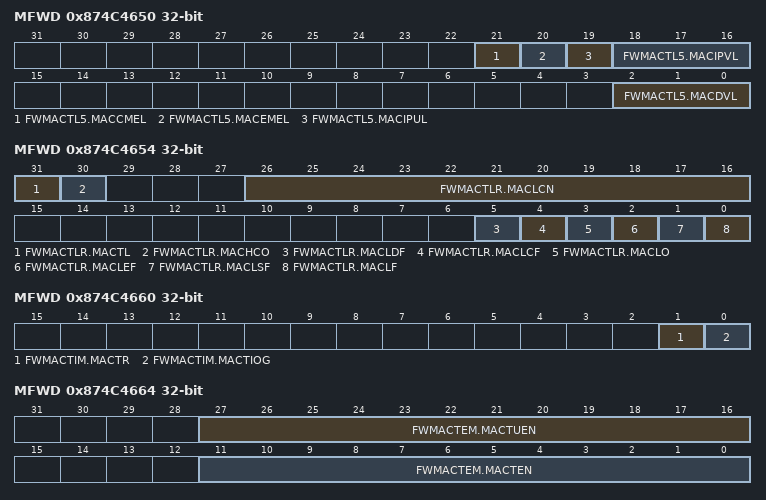
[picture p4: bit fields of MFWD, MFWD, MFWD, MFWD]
0x874C4650 MFWD
  [21] FWMACTL5.MACCMEL, [20] FWMACTL5.MACEMEL, [19] FWMACTL5.MACIPUL, [18:16] FWMACTL5.MACIPVL, [2:0] FWMACTL5.MACDVL
0x874C4654 MFWD
  [31] FWMACTLR.MACTL, [30] FWMACTLR.MACHCO, [26:16] FWMACTLR.MACLCN, [5] FWMACTLR.MACLDF, [4] FWMACTLR.MACLCF, [3] FWMACTLR.MACLO, [2] FWMACTLR.MACLEF, [1] FWMACTLR.MACLSF, [0] FWMACTLR.MACLF
0x874C4660 MFWD
  [1] FWMACTIM.MACTR, [0] FWMACTIM.MACTIOG
0x874C4664 MFWD
  [27:16] FWMACTEM.MACTUEN, [11:0] FWMACTEM.MACTEN
0x874C4670 MFWD
  [15:0] FWMACTS0.MACMASP0
0x874C4674 MFWD
  [31:0] FWMACTS1.MACMASP1
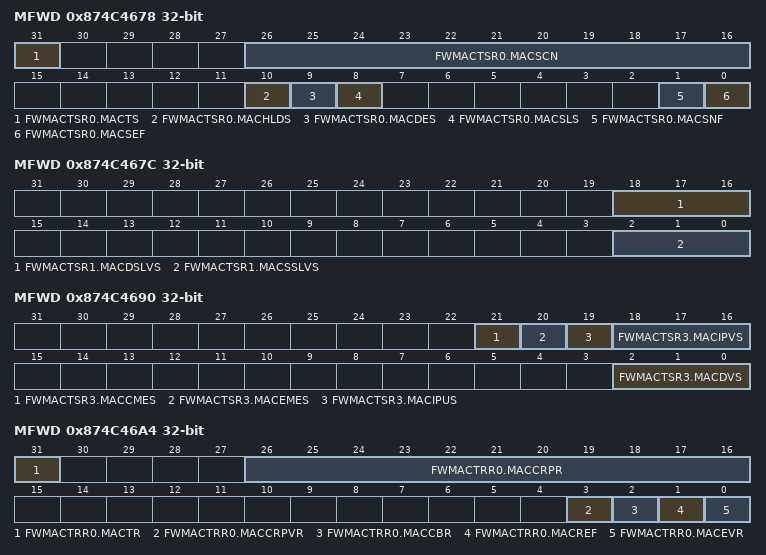
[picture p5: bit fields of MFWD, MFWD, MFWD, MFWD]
0x874C4678 MFWD
  [31] FWMACTSR0.MACTS, [26:16] FWMACTSR0.MACSCN, [10] FWMACTSR0.MACHLDS, [9] FWMACTSR0.MACDES, [8] FWMACTSR0.MACSLS, [1] FWMACTSR0.MACSNF, [0] FWMACTSR0.MACSEF
0x874C467C MFWD
  [18:16] FWMACTSR1.MACDSLVS, [2:0] FWMACTSR1.MACSSLVS
0x874C4680 MFWD
  [5:0] FWMACTSR20.MACCSDS
0x874C4690 MFWD
  [21] FWMACTSR3.MACCMES, [20] FWMACTSR3.MACEMES, [19] FWMACTSR3.MACIPUS, [18:16] FWMACTSR3.MACIPVS, [2:0] FWMACTSR3.MACDVS
0x874C46A0 MFWD
  [10:0] FWMACTR.MACAR
0x874C46A4 MFWD
  [31] FWMACTRR0.MACTR, [26:16] FWMACTRR0.MACCRPR, [3] FWMACTRR0.MACCRPVR, [2] FWMACTRR0.MACCBR, [1] FWMACTRR0.MACREF, [0] FWMACTRR0.MACEVR
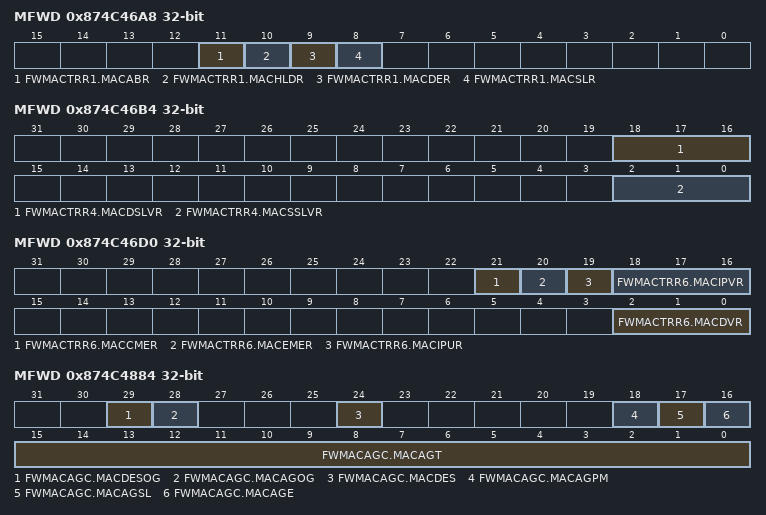
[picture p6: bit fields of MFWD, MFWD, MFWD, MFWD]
0x874C46A8 MFWD
  [11] FWMACTRR1.MACABR, [10] FWMACTRR1.MACHLDR, [9] FWMACTRR1.MACDER, [8] FWMACTRR1.MACSLR
0x874C46AC MFWD
  [15:0] FWMACTRR2.MACMARP0
0x874C46B0 MFWD
  [31:0] FWMACTRR3.MACMARP1
0x874C46B4 MFWD
  [18:16] FWMACTRR4.MACDSLVR, [2:0] FWMACTRR4.MACSSLVR
0x874C46C0 MFWD
  [5:0] FWMACTRR50.MACCSDR
0x874C46D0 MFWD
  [21] FWMACTRR6.MACCMER, [20] FWMACTRR6.MACEMER, [19] FWMACTRR6.MACIPUR, [18:16] FWMACTRR6.MACIPVR, [2:0] FWMACTRR6.MACDVR
0x874C4880 MFWD
  [9:0] FWMACAGUSPC.MACAGUSP
0x874C4884 MFWD
  [29] FWMACAGC.MACDESOG, [28] FWMACAGC.MACAGOG, [24] FWMACAGC.MACDES, [18] FWMACAGC.MACAGPM, [17] FWMACAGC.MACAGSL, [16] FWMACAGC.MACAGE, [15:0] FWMACAGC.MACAGT
0x874C4888 MFWD
  [15:0] FWMACAGM0.AGMACAP0
0x874C488C MFWD
  [31:0] FWMACAGM1.AGMACAP1
0x874C4900 MFWD
  [28:16] FWVLANTEC.VLANTMUE
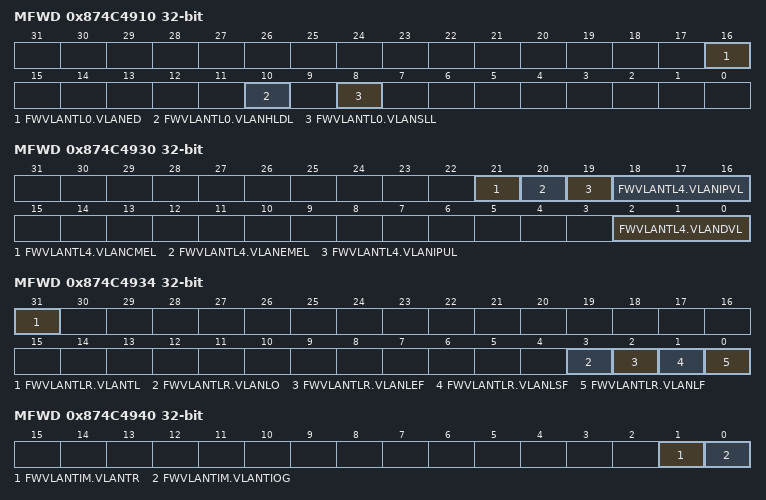
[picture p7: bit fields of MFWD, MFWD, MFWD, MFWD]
0x874C4910 MFWD
  [16] FWVLANTL0.VLANED, [10] FWVLANTL0.VLANHLDL, [8] FWVLANTL0.VLANSLL
0x874C4914 MFWD
  [11:0] FWVLANTL1.VLANVIDL
0x874C4918 MFWD
  [2:0] FWVLANTL2.VLANSLVL
0x874C4920 MFWD
  [5:0] FWVLANTL30.VLANCSDL
0x874C4930 MFWD
  [21] FWVLANTL4.VLANCMEL, [20] FWVLANTL4.VLANEMEL, [19] FWVLANTL4.VLANIPUL, [18:16] FWVLANTL4.VLANIPVL, [2:0] FWVLANTL4.VLANDVL
0x874C4934 MFWD
  [31] FWVLANTLR.VLANTL, [3] FWVLANTLR.VLANLO, [2] FWVLANTLR.VLANLEF, [1] FWVLANTLR.VLANLSF, [0] FWVLANTLR.VLANLF
0x874C4940 MFWD
  [1] FWVLANTIM.VLANTR, [0] FWVLANTIM.VLANTIOG
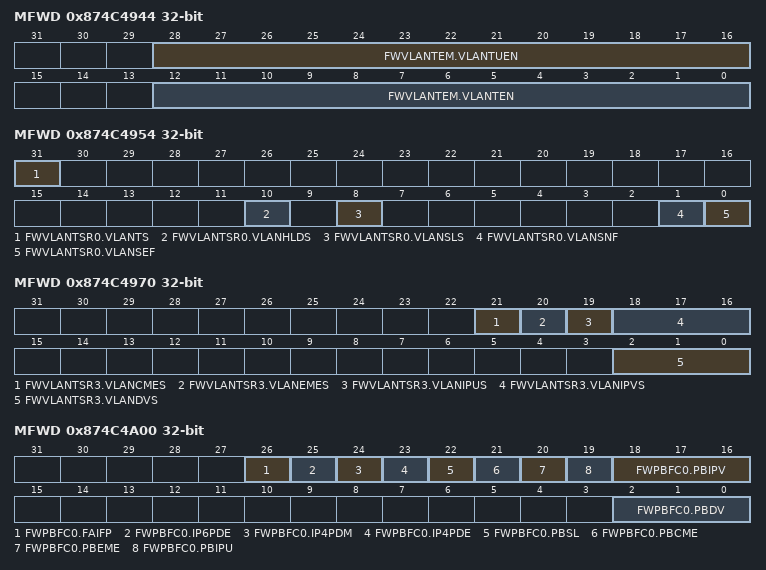
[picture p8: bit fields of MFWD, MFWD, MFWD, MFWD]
0x874C4944 MFWD
  [28:16] FWVLANTEM.VLANTUEN, [12:0] FWVLANTEM.VLANTEN
0x874C4950 MFWD
  [11:0] FWVLANTS.VLANVIDS
0x874C4954 MFWD
  [31] FWVLANTSR0.VLANTS, [10] FWVLANTSR0.VLANHLDS, [8] FWVLANTSR0.VLANSLS, [1] FWVLANTSR0.VLANSNF, [0] FWVLANTSR0.VLANSEF
0x874C4958 MFWD
  [2:0] FWVLANTSR1.VLANSLVS
0x874C4960 MFWD
  [5:0] FWVLANTSR20.VLANCSDS
0x874C4970 MFWD
  [21] FWVLANTSR3.VLANCMES, [20] FWVLANTSR3.VLANEMES, [19] FWVLANTSR3.VLANIPUS, [18:16] FWVLANTSR3.VLANIPVS, [2:0] FWVLANTSR3.VLANDVS
0x874C4A00 MFWD
  [26] FWPBFC0.FAIFP, [25] FWPBFC0.IP6PDE, [24] FWPBFC0.IP4PDM, [23] FWPBFC0.IP4PDE, [22] FWPBFC0.PBSL, [21] FWPBFC0.PBCME, [20] FWPBFC0.PBEME, [19] FWPBFC0.PBIPU, [18:16] FWPBFC0.PBIPV, [2:0] FWPBFC0.PBDV
0x874C4A04 MFWD
  [5:0] FWPBFCSDC00.PBCSD
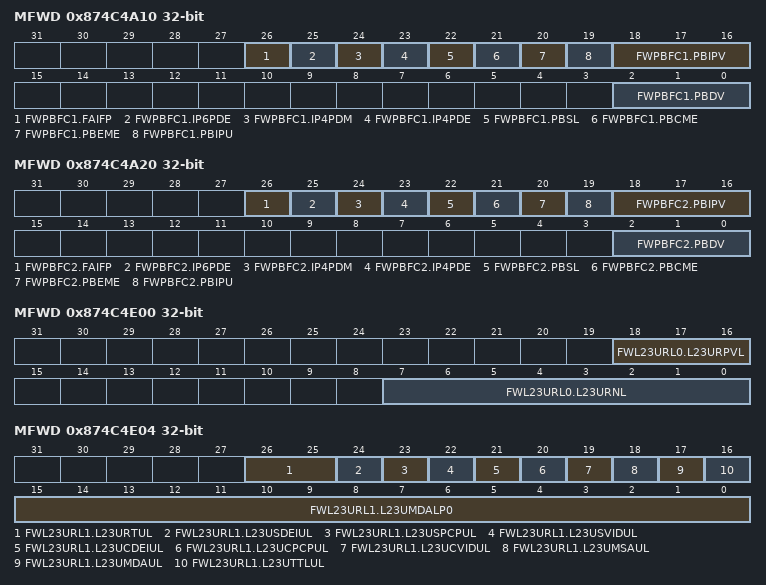
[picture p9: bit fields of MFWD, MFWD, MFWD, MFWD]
0x874C4A10 MFWD
  [26] FWPBFC1.FAIFP, [25] FWPBFC1.IP6PDE, [24] FWPBFC1.IP4PDM, [23] FWPBFC1.IP4PDE, [22] FWPBFC1.PBSL, [21] FWPBFC1.PBCME, [20] FWPBFC1.PBEME, [19] FWPBFC1.PBIPU, [18:16] FWPBFC1.PBIPV, [2:0] FWPBFC1.PBDV
0x874C4A14 MFWD
  [5:0] FWPBFCSDC10.PBCSD
0x874C4A20 MFWD
  [26] FWPBFC2.FAIFP, [25] FWPBFC2.IP6PDE, [24] FWPBFC2.IP4PDM, [23] FWPBFC2.IP4PDE, [22] FWPBFC2.PBSL, [21] FWPBFC2.PBCME, [20] FWPBFC2.PBEME, [19] FWPBFC2.PBIPU, [18:16] FWPBFC2.PBIPV, [2:0] FWPBFC2.PBDV
0x874C4A24 MFWD
  [5:0] FWPBFCSDC20.PBCSD
0x874C4E00 MFWD
  [18:16] FWL23URL0.L23URPVL, [7:0] FWL23URL0.L23URNL
0x874C4E04 MFWD
  [26:25] FWL23URL1.L23URTUL, [24] FWL23URL1.L23USDEIUL, [23] FWL23URL1.L23USPCPUL, [22] FWL23URL1.L23USVIDUL, [21] FWL23URL1.L23UCDEIUL, [20] FWL23URL1.L23UCPCPUL, [19] FWL23URL1.L23UCVIDUL, [18] FWL23URL1.L23UMSAUL, [17] FWL23URL1.L23UMDAUL, [16] FWL23URL1.L23UTTLUL, [15:0] FWL23URL1.L23UMDALP0
0x874C4E08 MFWD
  [31:0] FWL23URL2.L23UMDALP1
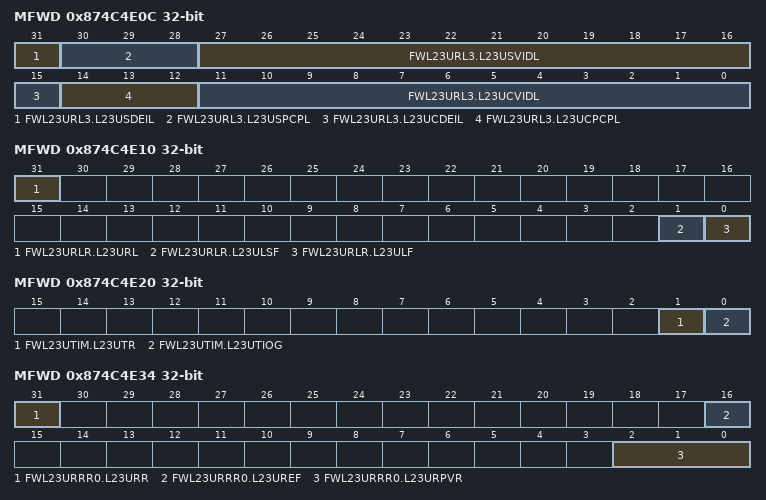
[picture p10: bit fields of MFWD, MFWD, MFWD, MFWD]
0x874C4E0C MFWD
  [31] FWL23URL3.L23USDEIL, [30:28] FWL23URL3.L23USPCPL, [27:16] FWL23URL3.L23USVIDL, [15] FWL23URL3.L23UCDEIL, [14:12] FWL23URL3.L23UCPCPL, [11:0] FWL23URL3.L23UCVIDL
0x874C4E10 MFWD
  [31] FWL23URLR.L23URL, [1] FWL23URLR.L23ULSF, [0] FWL23URLR.L23ULF
0x874C4E20 MFWD
  [1] FWL23UTIM.L23UTR, [0] FWL23UTIM.L23UTIOG
0x874C4E30 MFWD
  [7:0] FWL23URR.L23RNR
0x874C4E34 MFWD
  [31] FWL23URRR0.L23URR, [16] FWL23URRR0.L23UREF, [2:0] FWL23URRR0.L23URPVR
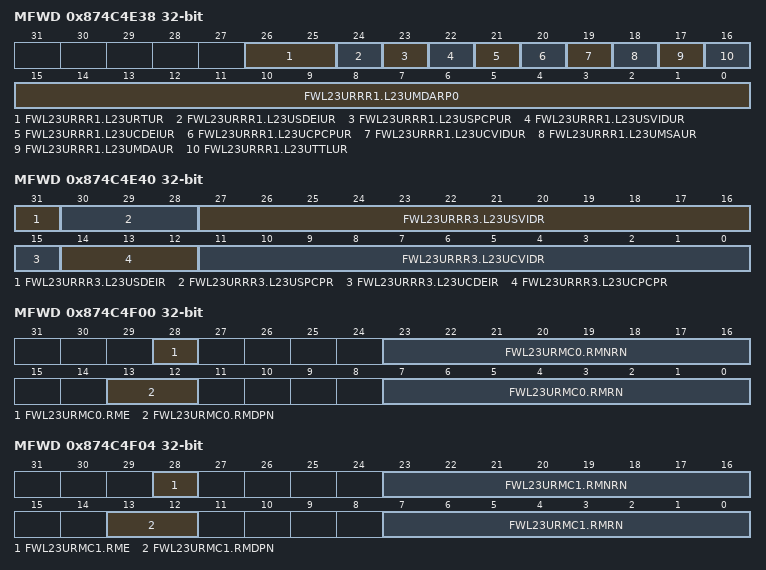
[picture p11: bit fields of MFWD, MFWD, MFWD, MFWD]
0x874C4E38 MFWD
  [26:25] FWL23URRR1.L23URTUR, [24] FWL23URRR1.L23USDEIUR, [23] FWL23URRR1.L23USPCPUR, [22] FWL23URRR1.L23USVIDUR, [21] FWL23URRR1.L23UCDEIUR, [20] FWL23URRR1.L23UCPCPUR, [19] FWL23URRR1.L23UCVIDUR, [18] FWL23URRR1.L23UMSAUR, [17] FWL23URRR1.L23UMDAUR, [16] FWL23URRR1.L23UTTLUR, [15:0] FWL23URRR1.L23UMDARP0
0x874C4E3C MFWD
  [31:0] FWL23URRR2.L23UMDARP1
0x874C4E40 MFWD
  [31] FWL23URRR3.L23USDEIR, [30:28] FWL23URRR3.L23USPCPR, [27:16] FWL23URRR3.L23USVIDR, [15] FWL23URRR3.L23UCDEIR, [14:12] FWL23URRR3.L23UCPCPR, [11:0] FWL23URRR3.L23UCVIDR
0x874C4F00 MFWD
  [28] FWL23URMC0.RME, [23:16] FWL23URMC0.RMNRN, [13:12] FWL23URMC0.RMDPN, [7:0] FWL23URMC0.RMRN
0x874C4F04 MFWD
  [28] FWL23URMC1.RME, [23:16] FWL23URMC1.RMNRN, [13:12] FWL23URMC1.RMDPN, [7:0] FWL23URMC1.RMRN
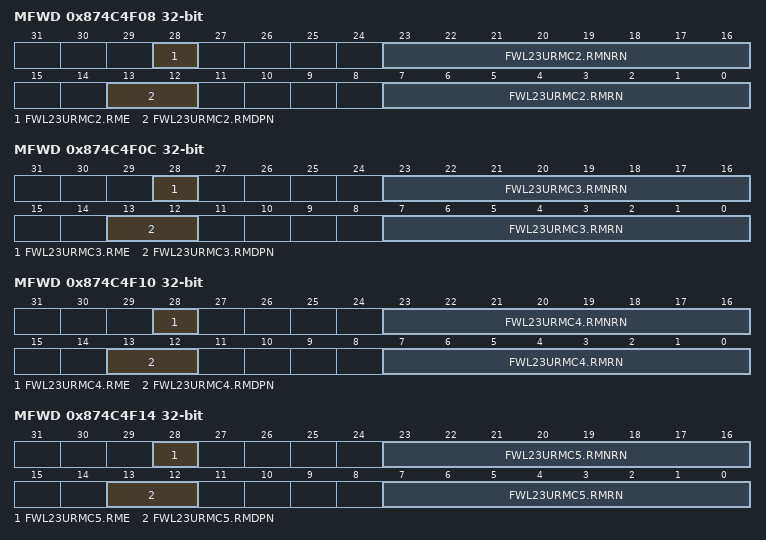
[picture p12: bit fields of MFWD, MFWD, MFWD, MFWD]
0x874C4F08 MFWD
  [28] FWL23URMC2.RME, [23:16] FWL23URMC2.RMNRN, [13:12] FWL23URMC2.RMDPN, [7:0] FWL23URMC2.RMRN
0x874C4F0C MFWD
  [28] FWL23URMC3.RME, [23:16] FWL23URMC3.RMNRN, [13:12] FWL23URMC3.RMDPN, [7:0] FWL23URMC3.RMRN
0x874C4F10 MFWD
  [28] FWL23URMC4.RME, [23:16] FWL23URMC4.RMNRN, [13:12] FWL23URMC4.RMDPN, [7:0] FWL23URMC4.RMRN
0x874C4F14 MFWD
  [28] FWL23URMC5.RME, [23:16] FWL23URMC5.RMNRN, [13:12] FWL23URMC5.RMDPN, [7:0] FWL23URMC5.RMRN
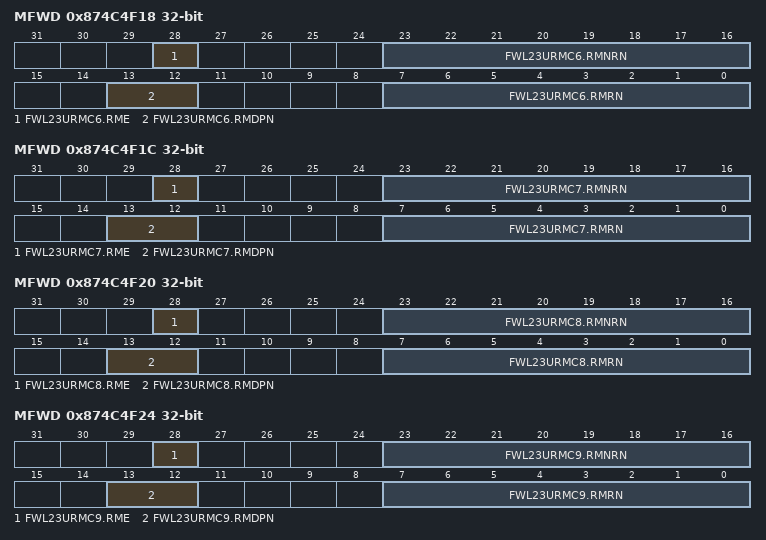
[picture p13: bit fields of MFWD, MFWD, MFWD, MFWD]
0x874C4F18 MFWD
  [28] FWL23URMC6.RME, [23:16] FWL23URMC6.RMNRN, [13:12] FWL23URMC6.RMDPN, [7:0] FWL23URMC6.RMRN
0x874C4F1C MFWD
  [28] FWL23URMC7.RME, [23:16] FWL23URMC7.RMNRN, [13:12] FWL23URMC7.RMDPN, [7:0] FWL23URMC7.RMRN
0x874C4F20 MFWD
  [28] FWL23URMC8.RME, [23:16] FWL23URMC8.RMNRN, [13:12] FWL23URMC8.RMDPN, [7:0] FWL23URMC8.RMRN
0x874C4F24 MFWD
  [28] FWL23URMC9.RME, [23:16] FWL23URMC9.RMNRN, [13:12] FWL23URMC9.RMDPN, [7:0] FWL23URMC9.RMRN
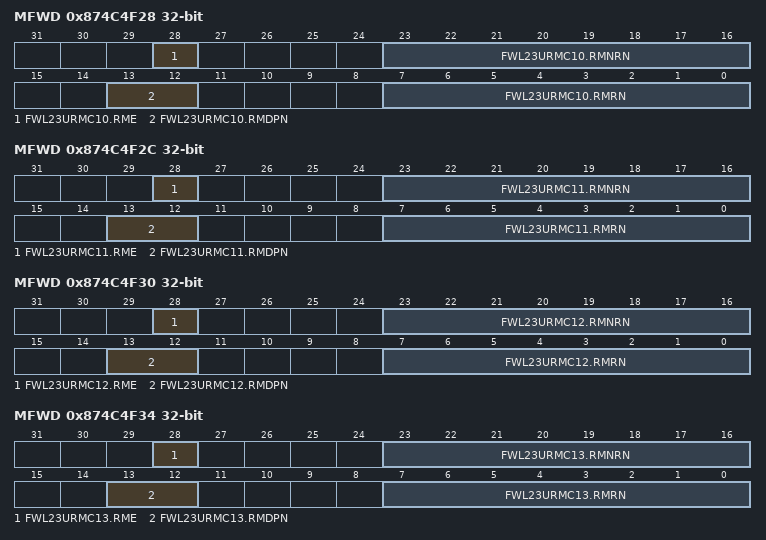
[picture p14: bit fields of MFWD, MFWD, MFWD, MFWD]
0x874C4F28 MFWD
  [28] FWL23URMC10.RME, [23:16] FWL23URMC10.RMNRN, [13:12] FWL23URMC10.RMDPN, [7:0] FWL23URMC10.RMRN
0x874C4F2C MFWD
  [28] FWL23URMC11.RME, [23:16] FWL23URMC11.RMNRN, [13:12] FWL23URMC11.RMDPN, [7:0] FWL23URMC11.RMRN
0x874C4F30 MFWD
  [28] FWL23URMC12.RME, [23:16] FWL23URMC12.RMNRN, [13:12] FWL23URMC12.RMDPN, [7:0] FWL23URMC12.RMRN
0x874C4F34 MFWD
  [28] FWL23URMC13.RME, [23:16] FWL23URMC13.RMNRN, [13:12] FWL23URMC13.RMDPN, [7:0] FWL23URMC13.RMRN
0x874C4F38 MFWD
  [28] FWL23URMC14.RME, [23:16] FWL23URMC14.RMNRN, [13:12] FWL23URMC14.RMDPN, [7:0] FWL23URMC14.RMRN
0x874C4F3C MFWD
  [28] FWL23URMC15.RME, [23:16] FWL23URMC15.RMNRN, [13:12] FWL23URMC15.RMDPN, [7:0] FWL23URMC15.RMRN
0x874C4F40 MFWD
  [28] FWL23URMC16.RME, [23:16] FWL23URMC16.RMNRN, [13:12] FWL23URMC16.RMDPN, [7:0] FWL23URMC16.RMRN
0x874C4F44 MFWD
  [28] FWL23URMC17.RME, [23:16] FWL23URMC17.RMNRN, [13:12] FWL23URMC17.RMDPN, [7:0] FWL23URMC17.RMRN
0x874C4F48 MFWD
  [28] FWL23URMC18.RME, [23:16] FWL23URMC18.RMNRN, [13:12] FWL23URMC18.RMDPN, [7:0] FWL23URMC18.RMRN
0x874C4F4C MFWD
  [28] FWL23URMC19.RME, [23:16] FWL23URMC19.RMNRN, [13:12] FWL23URMC19.RMDPN, [7:0] FWL23URMC19.RMRN
0x874C4F50 MFWD
  [28] FWL23URMC20.RME, [23:16] FWL23URMC20.RMNRN, [13:12] FWL23URMC20.RMDPN, [7:0] FWL23URMC20.RMRN
0x874C4F54 MFWD
  [28] FWL23URMC21.RME, [23:16] FWL23URMC21.RMNRN, [13:12] FWL23URMC21.RMDPN, [7:0] FWL23URMC21.RMRN
0x874C4F58 MFWD
  [28] FWL23URMC22.RME, [23:16] FWL23URMC22.RMNRN, [13:12] FWL23URMC22.RMDPN, [7:0] FWL23URMC22.RMRN
0x874C4F5C MFWD
  [28] FWL23URMC23.RME, [23:16] FWL23URMC23.RMNRN, [13:12] FWL23URMC23.RMDPN, [7:0] FWL23URMC23.RMRN
0x874C4F60 MFWD
  [28] FWL23URMC24.RME, [23:16] FWL23URMC24.RMNRN, [13:12] FWL23URMC24.RMDPN, [7:0] FWL23URMC24.RMRN
0x874C4F64 MFWD
  [28] FWL23URMC25.RME, [23:16] FWL23URMC25.RMNRN, [13:12] FWL23URMC25.RMDPN, [7:0] FWL23URMC25.RMRN
0x874C4F68 MFWD
  [28] FWL23URMC26.RME, [23:16] FWL23URMC26.RMNRN, [13:12] FWL23URMC26.RMDPN, [7:0] FWL23URMC26.RMRN
0x874C4F6C MFWD
  [28] FWL23URMC27.RME, [23:16] FWL23URMC27.RMNRN, [13:12] FWL23URMC27.RMDPN, [7:0] FWL23URMC27.RMRN
0x874C4F70 MFWD
  [28] FWL23URMC28.RME, [23:16] FWL23URMC28.RMNRN, [13:12] FWL23URMC28.RMDPN, [7:0] FWL23URMC28.RMRN
0x874C4F74 MFWD
  [28] FWL23URMC29.RME, [23:16] FWL23URMC29.RMNRN, [13:12] FWL23URMC29.RMDPN, [7:0] FWL23URMC29.RMRN
0x874C4F78 MFWD
  [28] FWL23URMC30.RME, [23:16] FWL23URMC30.RMNRN, [13:12] FWL23URMC30.RMDPN, [7:0] FWL23URMC30.RMRN
0x874C4F7C MFWD
  [28] FWL23URMC31.RME, [23:16] FWL23URMC31.RMNRN, [13:12] FWL23URMC31.RMDPN, [7:0] FWL23URMC31.RMRN
0x874C5000 MFWD
  [31] FWPMFGC0.MFM, [15:0] FWPMFGC0.MSDUV
0x874C5004 MFWD
  [31] FWPMFGC1.MFM, [15:0] FWPMFGC1.MSDUV
0x874C5008 MFWD
  [31] FWPMFGC2.MFM, [15:0] FWPMFGC2.MSDUV
0x874C500C MFWD
  [31] FWPMFGC3.MFM, [15:0] FWPMFGC3.MSDUV
0x874C5010 MFWD
  [31] FWPMFGC4.MFM, [15:0] FWPMFGC4.MSDUV
0x874C5014 MFWD
  [31] FWPMFGC5.MFM, [15:0] FWPMFGC5.MSDUV
0x874C5018 MFWD
  [31] FWPMFGC6.MFM, [15:0] FWPMFGC6.MSDUV
0x874C501C MFWD
  [31] FWPMFGC7.MFM, [15:0] FWPMFGC7.MSDUV
0x874C5020 MFWD
  [31] FWPMFGC8.MFM, [15:0] FWPMFGC8.MSDUV
0x874C5024 MFWD
  [31] FWPMFGC9.MFM, [15:0] FWPMFGC9.MSDUV
0x874C5028 MFWD
  [31] FWPMFGC10.MFM, [15:0] FWPMFGC10.MSDUV
0x874C502C MFWD
  [31] FWPMFGC11.MFM, [15:0] FWPMFGC11.MSDUV
0x874C5030 MFWD
  [31] FWPMFGC12.MFM, [15:0] FWPMFGC12.MSDUV
0x874C5034 MFWD
  [31] FWPMFGC13.MFM, [15:0] FWPMFGC13.MSDUV
0x874C5038 MFWD
  [31] FWPMFGC14.MFM, [15:0] FWPMFGC14.MSDUV
0x874C503C MFWD
  [31] FWPMFGC15.MFM, [15:0] FWPMFGC15.MSDUV
0x874C5600 MFWD
  [n+16] FWPMTRFC0.MTRCM{n} (n=0..15), [4] FWPMTRFC0.MTRCF, [3] FWPMTRFC0.MTRFRFD, [2:1] FWPMTRFC0.MTRFM, [0] FWPMTRFC0.MTRFE
0x874C5604 MFWD
  [17:0] FWPMTRCBSC0.CBS
0x874C5608 MFWD
  [19:0] FWPMTRCIRC0.CIR
0x874C560C MFWD
  [17:0] FWPMTREBSC0.EBS
0x874C5610 MFWD
  [19:0] FWPMTREIRC0.EIR
0x874C5614 MFWD
  [20:16] FWPMTRFM0.MTRARDNMN, [4:0] FWPMTRFM0.MTRARDN
0x874C5620 MFWD
  [n+16] FWPMTRFC1.MTRCM{n} (n=0..15), [4] FWPMTRFC1.MTRCF, [3] FWPMTRFC1.MTRFRFD, [2:1] FWPMTRFC1.MTRFM, [0] FWPMTRFC1.MTRFE
0x874C5624 MFWD
  [17:0] FWPMTRCBSC1.CBS
0x874C5628 MFWD
  [19:0] FWPMTRCIRC1.CIR
0x874C562C MFWD
  [17:0] FWPMTREBSC1.EBS
0x874C5630 MFWD
  [19:0] FWPMTREIRC1.EIR
0x874C5634 MFWD
  [20:16] FWPMTRFM1.MTRARDNMN, [4:0] FWPMTRFM1.MTRARDN
0x874C5640 MFWD
  [n+16] FWPMTRFC2.MTRCM{n} (n=0..15), [4] FWPMTRFC2.MTRCF, [3] FWPMTRFC2.MTRFRFD, [2:1] FWPMTRFC2.MTRFM, [0] FWPMTRFC2.MTRFE
0x874C5644 MFWD
  [17:0] FWPMTRCBSC2.CBS
0x874C5648 MFWD
  [19:0] FWPMTRCIRC2.CIR
0x874C564C MFWD
  [17:0] FWPMTREBSC2.EBS
0x874C5650 MFWD
  [19:0] FWPMTREIRC2.EIR
0x874C5654 MFWD
  [20:16] FWPMTRFM2.MTRARDNMN, [4:0] FWPMTRFM2.MTRARDN
0x874C5660 MFWD
  [n+16] FWPMTRFC3.MTRCM{n} (n=0..15), [4] FWPMTRFC3.MTRCF, [3] FWPMTRFC3.MTRFRFD, [2:1] FWPMTRFC3.MTRFM, [0] FWPMTRFC3.MTRFE
0x874C5664 MFWD
  [17:0] FWPMTRCBSC3.CBS
0x874C5668 MFWD
  [19:0] FWPMTRCIRC3.CIR
0x874C566C MFWD
  [17:0] FWPMTREBSC3.EBS
0x874C5670 MFWD
  [19:0] FWPMTREIRC3.EIR
0x874C5674 MFWD
  [20:16] FWPMTRFM3.MTRARDNMN, [4:0] FWPMTRFM3.MTRARDN
0x874C5680 MFWD
  [n+16] FWPMTRFC4.MTRCM{n} (n=0..15), [4] FWPMTRFC4.MTRCF, [3] FWPMTRFC4.MTRFRFD, [2:1] FWPMTRFC4.MTRFM, [0] FWPMTRFC4.MTRFE
0x874C5684 MFWD
  [17:0] FWPMTRCBSC4.CBS
0x874C5688 MFWD
  [19:0] FWPMTRCIRC4.CIR
0x874C568C MFWD
  [17:0] FWPMTREBSC4.EBS
0x874C5690 MFWD
  [19:0] FWPMTREIRC4.EIR
0x874C5694 MFWD
  [20:16] FWPMTRFM4.MTRARDNMN, [4:0] FWPMTRFM4.MTRARDN
0x874C56A0 MFWD
  [n+16] FWPMTRFC5.MTRCM{n} (n=0..15), [4] FWPMTRFC5.MTRCF, [3] FWPMTRFC5.MTRFRFD, [2:1] FWPMTRFC5.MTRFM, [0] FWPMTRFC5.MTRFE
0x874C56A4 MFWD
  [17:0] FWPMTRCBSC5.CBS
0x874C56A8 MFWD
  [19:0] FWPMTRCIRC5.CIR
0x874C56AC MFWD
  [17:0] FWPMTREBSC5.EBS
0x874C56B0 MFWD
  [19:0] FWPMTREIRC5.EIR
0x874C56B4 MFWD
  [20:16] FWPMTRFM5.MTRARDNMN, [4:0] FWPMTRFM5.MTRARDN
0x874C56C0 MFWD
  [n+16] FWPMTRFC6.MTRCM{n} (n=0..15), [4] FWPMTRFC6.MTRCF, [3] FWPMTRFC6.MTRFRFD, [2:1] FWPMTRFC6.MTRFM, [0] FWPMTRFC6.MTRFE
0x874C56C4 MFWD
  [17:0] FWPMTRCBSC6.CBS
0x874C56C8 MFWD
  [19:0] FWPMTRCIRC6.CIR
0x874C56CC MFWD
  [17:0] FWPMTREBSC6.EBS
0x874C56D0 MFWD
  [19:0] FWPMTREIRC6.EIR
0x874C56D4 MFWD
  [20:16] FWPMTRFM6.MTRARDNMN, [4:0] FWPMTRFM6.MTRARDN
0x874C56E0 MFWD
  [n+16] FWPMTRFC7.MTRCM{n} (n=0..15), [4] FWPMTRFC7.MTRCF, [3] FWPMTRFC7.MTRFRFD, [2:1] FWPMTRFC7.MTRFM, [0] FWPMTRFC7.MTRFE
0x874C56E4 MFWD
  [17:0] FWPMTRCBSC7.CBS
0x874C56E8 MFWD
  [19:0] FWPMTRCIRC7.CIR
0x874C56EC MFWD
  [17:0] FWPMTREBSC7.EBS
0x874C56F0 MFWD
  [19:0] FWPMTREIRC7.EIR
0x874C56F4 MFWD
  [20:16] FWPMTRFM7.MTRARDNMN, [4:0] FWPMTRFM7.MTRARDN
0x874C5700 MFWD
  [n+16] FWPMTRFC8.MTRCM{n} (n=0..15), [4] FWPMTRFC8.MTRCF, [3] FWPMTRFC8.MTRFRFD, [2:1] FWPMTRFC8.MTRFM, [0] FWPMTRFC8.MTRFE
0x874C5704 MFWD
  [17:0] FWPMTRCBSC8.CBS
0x874C5708 MFWD
  [19:0] FWPMTRCIRC8.CIR
0x874C5714 MFWD
  [20:16] FWPMTRFM8.MTRARDNMN, [4:0] FWPMTRFM8.MTRARDN
0x874C5720 MFWD
  [n+16] FWPMTRFC9.MTRCM{n} (n=0..15), [4] FWPMTRFC9.MTRCF, [3] FWPMTRFC9.MTRFRFD, [2:1] FWPMTRFC9.MTRFM, [0] FWPMTRFC9.MTRFE
0x874C5724 MFWD
  [17:0] FWPMTRCBSC9.CBS
0x874C5728 MFWD
  [19:0] FWPMTRCIRC9.CIR
0x874C5734 MFWD
  [20:16] FWPMTRFM9.MTRARDNMN, [4:0] FWPMTRFM9.MTRARDN
0x874C5740 MFWD
  [n+16] FWPMTRFC10.MTRCM{n} (n=0..15), [4] FWPMTRFC10.MTRCF, [3] FWPMTRFC10.MTRFRFD, [2:1] FWPMTRFC10.MTRFM, [0] FWPMTRFC10.MTRFE
0x874C5744 MFWD
  [17:0] FWPMTRCBSC10.CBS
0x874C5748 MFWD
  [19:0] FWPMTRCIRC10.CIR
0x874C5754 MFWD
  [20:16] FWPMTRFM10.MTRARDNMN, [4:0] FWPMTRFM10.MTRARDN
0x874C5760 MFWD
  [n+16] FWPMTRFC11.MTRCM{n} (n=0..15), [4] FWPMTRFC11.MTRCF, [3] FWPMTRFC11.MTRFRFD, [2:1] FWPMTRFC11.MTRFM, [0] FWPMTRFC11.MTRFE
0x874C5764 MFWD
  [17:0] FWPMTRCBSC11.CBS
0x874C5768 MFWD
  [19:0] FWPMTRCIRC11.CIR
0x874C5774 MFWD
  [20:16] FWPMTRFM11.MTRARDNMN, [4:0] FWPMTRFM11.MTRARDN
0x874C5780 MFWD
  [n+16] FWPMTRFC12.MTRCM{n} (n=0..15), [4] FWPMTRFC12.MTRCF, [3] FWPMTRFC12.MTRFRFD, [2:1] FWPMTRFC12.MTRFM, [0] FWPMTRFC12.MTRFE
0x874C5784 MFWD
  [17:0] FWPMTRCBSC12.CBS
0x874C5788 MFWD
  [19:0] FWPMTRCIRC12.CIR
0x874C5794 MFWD
  [20:16] FWPMTRFM12.MTRARDNMN, [4:0] FWPMTRFM12.MTRARDN
0x874C57A0 MFWD
  [n+16] FWPMTRFC13.MTRCM{n} (n=0..15), [4] FWPMTRFC13.MTRCF, [3] FWPMTRFC13.MTRFRFD, [2:1] FWPMTRFC13.MTRFM, [0] FWPMTRFC13.MTRFE
0x874C57A4 MFWD
  [17:0] FWPMTRCBSC13.CBS
0x874C57A8 MFWD
  [19:0] FWPMTRCIRC13.CIR
0x874C57B4 MFWD
  [20:16] FWPMTRFM13.MTRARDNMN, [4:0] FWPMTRFM13.MTRARDN
0x874C57C0 MFWD
  [n+16] FWPMTRFC14.MTRCM{n} (n=0..15), [4] FWPMTRFC14.MTRCF, [3] FWPMTRFC14.MTRFRFD, [2:1] FWPMTRFC14.MTRFM, [0] FWPMTRFC14.MTRFE
0x874C57C4 MFWD
  [17:0] FWPMTRCBSC14.CBS
0x874C57C8 MFWD
  [19:0] FWPMTRCIRC14.CIR
0x874C57D4 MFWD
  [20:16] FWPMTRFM14.MTRARDNMN, [4:0] FWPMTRFM14.MTRARDN
0x874C57E0 MFWD
  [n+16] FWPMTRFC15.MTRCM{n} (n=0..15), [4] FWPMTRFC15.MTRCF, [3] FWPMTRFC15.MTRFRFD, [2:1] FWPMTRFC15.MTRFM, [0] FWPMTRFC15.MTRFE
0x874C57E4 MFWD
  [17:0] FWPMTRCBSC15.CBS
0x874C57E8 MFWD
  [19:0] FWPMTRCIRC15.CIR
0x874C57F4 MFWD
  [20:16] FWPMTRFM15.MTRARDNMN, [4:0] FWPMTRFM15.MTRARDN
0x874C5800 MFWD
  [n+16] FWPMTRFC16.MTRCM{n} (n=0..15), [4] FWPMTRFC16.MTRCF, [3] FWPMTRFC16.MTRFRFD, [2:1] FWPMTRFC16.MTRFM, [0] FWPMTRFC16.MTRFE
0x874C5804 MFWD
  [17:0] FWPMTRCBSC16.CBS
0x874C5808 MFWD
  [19:0] FWPMTRCIRC16.CIR
0x874C5814 MFWD
  [20:16] FWPMTRFM16.MTRARDNMN, [4:0] FWPMTRFM16.MTRARDN
0x874C5820 MFWD
  [n+16] FWPMTRFC17.MTRCM{n} (n=0..15), [4] FWPMTRFC17.MTRCF, [3] FWPMTRFC17.MTRFRFD, [2:1] FWPMTRFC17.MTRFM, [0] FWPMTRFC17.MTRFE
0x874C5824 MFWD
  [17:0] FWPMTRCBSC17.CBS
0x874C5828 MFWD
  [19:0] FWPMTRCIRC17.CIR
0x874C5834 MFWD
  [20:16] FWPMTRFM17.MTRARDNMN, [4:0] FWPMTRFM17.MTRARDN
0x874C5840 MFWD
  [n+16] FWPMTRFC18.MTRCM{n} (n=0..15), [4] FWPMTRFC18.MTRCF, [3] FWPMTRFC18.MTRFRFD, [2:1] FWPMTRFC18.MTRFM, [0] FWPMTRFC18.MTRFE
0x874C5844 MFWD
  [17:0] FWPMTRCBSC18.CBS
0x874C5848 MFWD
  [19:0] FWPMTRCIRC18.CIR
0x874C5854 MFWD
  [20:16] FWPMTRFM18.MTRARDNMN, [4:0] FWPMTRFM18.MTRARDN
0x874C5860 MFWD
  [n+16] FWPMTRFC19.MTRCM{n} (n=0..15), [4] FWPMTRFC19.MTRCF, [3] FWPMTRFC19.MTRFRFD, [2:1] FWPMTRFC19.MTRFM, [0] FWPMTRFC19.MTRFE
0x874C5864 MFWD
  [17:0] FWPMTRCBSC19.CBS
0x874C5868 MFWD
  [19:0] FWPMTRCIRC19.CIR
0x874C5874 MFWD
  [20:16] FWPMTRFM19.MTRARDNMN, [4:0] FWPMTRFM19.MTRARDN
0x874C5880 MFWD
  [n+16] FWPMTRFC20.MTRCM{n} (n=0..15), [4] FWPMTRFC20.MTRCF, [3] FWPMTRFC20.MTRFRFD, [2:1] FWPMTRFC20.MTRFM, [0] FWPMTRFC20.MTRFE
0x874C5884 MFWD
  [17:0] FWPMTRCBSC20.CBS
0x874C5888 MFWD
  [19:0] FWPMTRCIRC20.CIR
0x874C5894 MFWD
  [20:16] FWPMTRFM20.MTRARDNMN, [4:0] FWPMTRFM20.MTRARDN
0x874C58A0 MFWD
  [n+16] FWPMTRFC21.MTRCM{n} (n=0..15), [4] FWPMTRFC21.MTRCF, [3] FWPMTRFC21.MTRFRFD, [2:1] FWPMTRFC21.MTRFM, [0] FWPMTRFC21.MTRFE
0x874C58A4 MFWD
  [17:0] FWPMTRCBSC21.CBS
0x874C58A8 MFWD
  [19:0] FWPMTRCIRC21.CIR
0x874C58B4 MFWD
  [20:16] FWPMTRFM21.MTRARDNMN, [4:0] FWPMTRFM21.MTRARDN
0x874C58C0 MFWD
  [n+16] FWPMTRFC22.MTRCM{n} (n=0..15), [4] FWPMTRFC22.MTRCF, [3] FWPMTRFC22.MTRFRFD, [2:1] FWPMTRFC22.MTRFM, [0] FWPMTRFC22.MTRFE
0x874C58C4 MFWD
  [17:0] FWPMTRCBSC22.CBS
0x874C58C8 MFWD
  [19:0] FWPMTRCIRC22.CIR
0x874C58D4 MFWD
  [20:16] FWPMTRFM22.MTRARDNMN, [4:0] FWPMTRFM22.MTRARDN
0x874C58E0 MFWD
  [n+16] FWPMTRFC23.MTRCM{n} (n=0..15), [4] FWPMTRFC23.MTRCF, [3] FWPMTRFC23.MTRFRFD, [2:1] FWPMTRFC23.MTRFM, [0] FWPMTRFC23.MTRFE
0x874C58E4 MFWD
  [17:0] FWPMTRCBSC23.CBS
0x874C58E8 MFWD
  [19:0] FWPMTRCIRC23.CIR
0x874C58F4 MFWD
  [20:16] FWPMTRFM23.MTRARDNMN, [4:0] FWPMTRFM23.MTRARDN
0x874C5900 MFWD
  [n+16] FWPMTRFC24.MTRCM{n} (n=0..15), [4] FWPMTRFC24.MTRCF, [3] FWPMTRFC24.MTRFRFD, [2:1] FWPMTRFC24.MTRFM, [0] FWPMTRFC24.MTRFE
0x874C5904 MFWD
  [17:0] FWPMTRCBSC24.CBS
0x874C5908 MFWD
  [19:0] FWPMTRCIRC24.CIR
0x874C5914 MFWD
  [20:16] FWPMTRFM24.MTRARDNMN, [4:0] FWPMTRFM24.MTRARDN
0x874C5920 MFWD
  [n+16] FWPMTRFC25.MTRCM{n} (n=0..15), [4] FWPMTRFC25.MTRCF, [3] FWPMTRFC25.MTRFRFD, [2:1] FWPMTRFC25.MTRFM, [0] FWPMTRFC25.MTRFE
0x874C5924 MFWD
  [17:0] FWPMTRCBSC25.CBS
0x874C5928 MFWD
  [19:0] FWPMTRCIRC25.CIR
0x874C5934 MFWD
  [20:16] FWPMTRFM25.MTRARDNMN, [4:0] FWPMTRFM25.MTRARDN
0x874C5940 MFWD
  [n+16] FWPMTRFC26.MTRCM{n} (n=0..15), [4] FWPMTRFC26.MTRCF, [3] FWPMTRFC26.MTRFRFD, [2:1] FWPMTRFC26.MTRFM, [0] FWPMTRFC26.MTRFE
0x874C5944 MFWD
  [17:0] FWPMTRCBSC26.CBS
0x874C5948 MFWD
  [19:0] FWPMTRCIRC26.CIR
0x874C5954 MFWD
  [20:16] FWPMTRFM26.MTRARDNMN, [4:0] FWPMTRFM26.MTRARDN
0x874C5960 MFWD
  [n+16] FWPMTRFC27.MTRCM{n} (n=0..15), [4] FWPMTRFC27.MTRCF, [3] FWPMTRFC27.MTRFRFD, [2:1] FWPMTRFC27.MTRFM, [0] FWPMTRFC27.MTRFE
0x874C5964 MFWD
  [17:0] FWPMTRCBSC27.CBS
0x874C5968 MFWD
  [19:0] FWPMTRCIRC27.CIR
0x874C5974 MFWD
  [20:16] FWPMTRFM27.MTRARDNMN, [4:0] FWPMTRFM27.MTRARDN
0x874C5980 MFWD
  [n+16] FWPMTRFC28.MTRCM{n} (n=0..15), [4] FWPMTRFC28.MTRCF, [3] FWPMTRFC28.MTRFRFD, [2:1] FWPMTRFC28.MTRFM, [0] FWPMTRFC28.MTRFE
0x874C5984 MFWD
  [17:0] FWPMTRCBSC28.CBS
0x874C5988 MFWD
  [19:0] FWPMTRCIRC28.CIR
0x874C5994 MFWD
  [20:16] FWPMTRFM28.MTRARDNMN, [4:0] FWPMTRFM28.MTRARDN
0x874C59A0 MFWD
  [n+16] FWPMTRFC29.MTRCM{n} (n=0..15), [4] FWPMTRFC29.MTRCF, [3] FWPMTRFC29.MTRFRFD, [2:1] FWPMTRFC29.MTRFM, [0] FWPMTRFC29.MTRFE
0x874C59A4 MFWD
  [17:0] FWPMTRCBSC29.CBS
0x874C59A8 MFWD
  [19:0] FWPMTRCIRC29.CIR
0x874C59B4 MFWD
  [20:16] FWPMTRFM29.MTRARDNMN, [4:0] FWPMTRFM29.MTRARDN
0x874C59C0 MFWD
  [n+16] FWPMTRFC30.MTRCM{n} (n=0..15), [4] FWPMTRFC30.MTRCF, [3] FWPMTRFC30.MTRFRFD, [2:1] FWPMTRFC30.MTRFM, [0] FWPMTRFC30.MTRFE
0x874C59C4 MFWD
  [17:0] FWPMTRCBSC30.CBS
0x874C59C8 MFWD
  [19:0] FWPMTRCIRC30.CIR
0x874C59D4 MFWD
  [20:16] FWPMTRFM30.MTRARDNMN, [4:0] FWPMTRFM30.MTRARDN
0x874C59E0 MFWD
  [n+16] FWPMTRFC31.MTRCM{n} (n=0..15), [4] FWPMTRFC31.MTRCF, [3] FWPMTRFC31.MTRFRFD, [2:1] FWPMTRFC31.MTRFM, [0] FWPMTRFC31.MTRFE
0x874C59E4 MFWD
  [17:0] FWPMTRCBSC31.CBS
0x874C59E8 MFWD
  [19:0] FWPMTRCIRC31.CIR
0x874C59F4 MFWD
  [20:16] FWPMTRFM31.MTRARDNMN, [4:0] FWPMTRFM31.MTRARDN
0x874C6000 MFWD
  [22:16] FWFTL0.FSRPL, [6:0] FWFTL0.FEAL
0x874C6004 MFWD
  [25:16] FWFTL1.FSRRTL, [9] FWFTL1.FSRPVL, [8] FWFTL1.FTNSL, [3:0] FWFTL1.FSHLL
0x874C6008 MFWD
  [31] FWFTLR.FTL, [1] FWFTLR.FLSF, [0] FWFTLR.FLF
0x874C6010 MFWD
  [17] FWFTOC.TOOG, [16] FWFTOC.TOCE, [15:0] FWFTOC.TOT
0x874C6014 MFWD
  [9:0] FWFTOPC.USP
0x874C6020 MFWD
  [1] FWFTIM.FTR, [0] FWFTIM.FTIOG
0x874C6030 MFWD
  [6:0] FWFTR.FEAR
0x874C6034 MFWD
  [31] FWFTRR0.FTR, [30] FWFTRR0.FTREF, [25:16] FWFTRR0.FSRRTR, [9] FWFTRR0.FSRPVR, [8] FWFTRR0.FTNSR, [3:0] FWFTRR0.FSHLR
0x874C6038 MFWD
  [22:16] FWFTRR1.FSRPR, [14:0] FWFTRR1.FSHR
0x874C603C MFWD
  [25:16] FWFTRR2.FRRTR, [15:0] FWFTRR2.FRSNR
0x874C6100 MFWD
  [16] FWSEQNGC0.SEQNGE, [7:0] FWSEQNGC0.SEQNGRN
0x874C6104 MFWD
  [15:0] FWSEQNGM0.SEQN
0x874C6108 MFWD
  [16] FWSEQNGC1.SEQNGE, [7:0] FWSEQNGC1.SEQNGRN
0x874C610C MFWD
  [15:0] FWSEQNGM1.SEQN
0x874C6110 MFWD
  [16] FWSEQNGC2.SEQNGE, [7:0] FWSEQNGC2.SEQNGRN
0x874C6114 MFWD
  [15:0] FWSEQNGM2.SEQN
0x874C6118 MFWD
  [16] FWSEQNGC3.SEQNGE, [7:0] FWSEQNGC3.SEQNGRN
0x874C611C MFWD
  [15:0] FWSEQNGM3.SEQN
0x874C6120 MFWD
  [16] FWSEQNGC4.SEQNGE, [7:0] FWSEQNGC4.SEQNGRN
0x874C6124 MFWD
  [15:0] FWSEQNGM4.SEQN
0x874C6128 MFWD
  [16] FWSEQNGC5.SEQNGE, [7:0] FWSEQNGC5.SEQNGRN
0x874C612C MFWD
  [15:0] FWSEQNGM5.SEQN
0x874C6130 MFWD
  [16] FWSEQNGC6.SEQNGE, [7:0] FWSEQNGC6.SEQNGRN
0x874C6134 MFWD
  [15:0] FWSEQNGM6.SEQN
0x874C6138 MFWD
  [16] FWSEQNGC7.SEQNGE, [7:0] FWSEQNGC7.SEQNGRN
0x874C613C MFWD
  [15:0] FWSEQNGM7.SEQN
0x874C6140 MFWD
  [16] FWSEQNGC8.SEQNGE, [7:0] FWSEQNGC8.SEQNGRN
0x874C6144 MFWD
  [15:0] FWSEQNGM8.SEQN
0x874C6148 MFWD
  [16] FWSEQNGC9.SEQNGE, [7:0] FWSEQNGC9.SEQNGRN
0x874C614C MFWD
  [15:0] FWSEQNGM9.SEQN
0x874C6150 MFWD
  [16] FWSEQNGC10.SEQNGE, [7:0] FWSEQNGC10.SEQNGRN
0x874C6154 MFWD
  [15:0] FWSEQNGM10.SEQN
0x874C6158 MFWD
  [16] FWSEQNGC11.SEQNGE, [7:0] FWSEQNGC11.SEQNGRN
0x874C615C MFWD
  [15:0] FWSEQNGM11.SEQN
0x874C6160 MFWD
  [16] FWSEQNGC12.SEQNGE, [7:0] FWSEQNGC12.SEQNGRN
0x874C6164 MFWD
  [15:0] FWSEQNGM12.SEQN
0x874C6168 MFWD
  [16] FWSEQNGC13.SEQNGE, [7:0] FWSEQNGC13.SEQNGRN
0x874C616C MFWD
  [15:0] FWSEQNGM13.SEQN
0x874C6170 MFWD
  [16] FWSEQNGC14.SEQNGE, [7:0] FWSEQNGC14.SEQNGRN
0x874C6174 MFWD
  [15:0] FWSEQNGM14.SEQN
0x874C6178 MFWD
  [16] FWSEQNGC15.SEQNGE, [7:0] FWSEQNGC15.SEQNGRN
0x874C617C MFWD
  [15:0] FWSEQNGM15.SEQN
0x874C6180 MFWD
  [16] FWSEQNGC16.SEQNGE, [7:0] FWSEQNGC16.SEQNGRN
0x874C6184 MFWD
  [15:0] FWSEQNGM16.SEQN
0x874C6188 MFWD
  [16] FWSEQNGC17.SEQNGE, [7:0] FWSEQNGC17.SEQNGRN
0x874C618C MFWD
  [15:0] FWSEQNGM17.SEQN
0x874C6190 MFWD
  [16] FWSEQNGC18.SEQNGE, [7:0] FWSEQNGC18.SEQNGRN
0x874C6194 MFWD
  [15:0] FWSEQNGM18.SEQN
0x874C6198 MFWD
  [16] FWSEQNGC19.SEQNGE, [7:0] FWSEQNGC19.SEQNGRN
0x874C619C MFWD
  [15:0] FWSEQNGM19.SEQN
0x874C61A0 MFWD
  [16] FWSEQNGC20.SEQNGE, [7:0] FWSEQNGC20.SEQNGRN
0x874C61A4 MFWD
  [15:0] FWSEQNGM20.SEQN
0x874C61A8 MFWD
  [16] FWSEQNGC21.SEQNGE, [7:0] FWSEQNGC21.SEQNGRN
0x874C61AC MFWD
  [15:0] FWSEQNGM21.SEQN
0x874C61B0 MFWD
  [16] FWSEQNGC22.SEQNGE, [7:0] FWSEQNGC22.SEQNGRN
0x874C61B4 MFWD
  [15:0] FWSEQNGM22.SEQN
0x874C61B8 MFWD
  [16] FWSEQNGC23.SEQNGE, [7:0] FWSEQNGC23.SEQNGRN
0x874C61BC MFWD
  [15:0] FWSEQNGM23.SEQN
0x874C61C0 MFWD
  [16] FWSEQNGC24.SEQNGE, [7:0] FWSEQNGC24.SEQNGRN
0x874C61C4 MFWD
  [15:0] FWSEQNGM24.SEQN
0x874C61C8 MFWD
  [16] FWSEQNGC25.SEQNGE, [7:0] FWSEQNGC25.SEQNGRN
0x874C61CC MFWD
  [15:0] FWSEQNGM25.SEQN
0x874C61D0 MFWD
  [16] FWSEQNGC26.SEQNGE, [7:0] FWSEQNGC26.SEQNGRN
0x874C61D4 MFWD
  [15:0] FWSEQNGM26.SEQN
0x874C61D8 MFWD
  [16] FWSEQNGC27.SEQNGE, [7:0] FWSEQNGC27.SEQNGRN
0x874C61DC MFWD
  [15:0] FWSEQNGM27.SEQN
0x874C61E0 MFWD
  [16] FWSEQNGC28.SEQNGE, [7:0] FWSEQNGC28.SEQNGRN
0x874C61E4 MFWD
  [15:0] FWSEQNGM28.SEQN
0x874C61E8 MFWD
  [16] FWSEQNGC29.SEQNGE, [7:0] FWSEQNGC29.SEQNGRN
0x874C61EC MFWD
  [15:0] FWSEQNGM29.SEQN
0x874C61F0 MFWD
  [16] FWSEQNGC30.SEQNGE, [7:0] FWSEQNGC30.SEQNGRN
0x874C61F4 MFWD
  [15:0] FWSEQNGM30.SEQN
0x874C61F8 MFWD
  [16] FWSEQNGC31.SEQNGE, [7:0] FWSEQNGC31.SEQNGRN
0x874C61FC MFWD
  [15:0] FWSEQNGM31.SEQN
0x874C6200 MFWD
  [n] FWSEQNRC.SEQNR{n} (n=0..31)
0x874C6300 MFWD
  [31:0] FWCTFDCN0.CTFDN
0x874C6304 MFWD
  [31:0] FWLTHFDCN0.LTHFDN
0x874C630C MFWD
  [31:0] FWLTWFDCN0.LTWFDN
0x874C6310 MFWD
  [31:0] FWPBFDCN0.PBFDN
0x874C6314 MFWD
  [31:0] FWMHLCN0.MHLN
0x874C6320 MFWD
  [31:0] FWCTFDCN1.CTFDN
0x874C6324 MFWD
  [31:0] FWLTHFDCN1.LTHFDN
0x874C632C MFWD
  [31:0] FWLTWFDCN1.LTWFDN
0x874C6330 MFWD
  [31:0] FWPBFDCN1.PBFDN
0x874C6334 MFWD
  [31:0] FWMHLCN1.MHLN
0x874C6340 MFWD
  [31:0] FWDDFDCN2.DDFDN
0x874C6344 MFWD
  [31:0] FWLTHFDCN2.LTHFDN
0x874C634C MFWD
  [31:0] FWLTWFDCN2.LTWFDN
0x874C6350 MFWD
  [31:0] FWPBFDCN2.PBFDN
0x874C6354 MFWD
  [31:0] FWMHLCN2.MHLN
0x874C6504 MFWD
  [15:0] FWWMRDCN0.WMRDN
0x874C6508 MFWD
  [15:0] FWCTRDCN0.CTRDN
0x874C650C MFWD
  [15:0] FWLTHRDCN0.LTHRDN
0x874C6514 MFWD
  [15:0] FWLTWRDCN0.LTWRDN
0x874C6518 MFWD
  [15:0] FWPBRDCN0.PBRDN
0x874C6524 MFWD
  [15:0] FWWMRDCN1.WMRDN
0x874C6528 MFWD
  [15:0] FWCTRDCN1.CTRDN
0x874C652C MFWD
  [15:0] FWLTHRDCN1.LTHRDN
0x874C6534 MFWD
  [15:0] FWLTWRDCN1.LTWRDN
0x874C6538 MFWD
  [15:0] FWPBRDCN1.PBRDN
0x874C6544 MFWD
  [15:0] FWWMRDCN2.WMRDN
0x874C6548 MFWD
  [15:0] FWDDRDCN2.DDRDN
0x874C654C MFWD
  [15:0] FWLTHRDCN2.LTHRDN
0x874C6554 MFWD
  [15:0] FWLTWRDCN2.LTWRDN
0x874C6558 MFWD
  [15:0] FWPBRDCN2.PBRDN
0x874C6700 MFWD
  [15:0] FWPMFDCN0.PMFDN
0x874C6704 MFWD
  [15:0] FWPMFDCN1.PMFDN
0x874C6708 MFWD
  [15:0] FWPMFDCN2.PMFDN
0x874C670C MFWD
  [15:0] FWPMFDCN3.PMFDN
0x874C6710 MFWD
  [15:0] FWPMFDCN4.PMFDN
0x874C6714 MFWD
  [15:0] FWPMFDCN5.PMFDN
0x874C6718 MFWD
  [15:0] FWPMFDCN6.PMFDN
0x874C671C MFWD
  [15:0] FWPMFDCN7.PMFDN
0x874C6720 MFWD
  [15:0] FWPMFDCN8.PMFDN
0x874C6724 MFWD
  [15:0] FWPMFDCN9.PMFDN
0x874C6728 MFWD
  [15:0] FWPMFDCN10.PMFDN
0x874C672C MFWD
  [15:0] FWPMFDCN11.PMFDN
0x874C6730 MFWD
  [15:0] FWPMFDCN12.PMFDN
0x874C6734 MFWD
  [15:0] FWPMFDCN13.PMFDN
0x874C6738 MFWD
  [15:0] FWPMFDCN14.PMFDN
0x874C673C MFWD
  [15:0] FWPMFDCN15.PMFDN
0x874C6800 MFWD
  [15:0] FWPMGDCN0.PMGDN
0x874C6804 MFWD
  [15:0] FWPMYDCN0.PMYDN
0x874C6808 MFWD
  [15:0] FWPMRDCN0.PMRDN
0x874C6810 MFWD
  [15:0] FWPMGDCN1.PMGDN
0x874C6814 MFWD
  [15:0] FWPMYDCN1.PMYDN
0x874C6818 MFWD
  [15:0] FWPMRDCN1.PMRDN
0x874C6820 MFWD
  [15:0] FWPMGDCN2.PMGDN
0x874C6824 MFWD
  [15:0] FWPMYDCN2.PMYDN
0x874C6828 MFWD
  [15:0] FWPMRDCN2.PMRDN
0x874C6830 MFWD
  [15:0] FWPMGDCN3.PMGDN
0x874C6834 MFWD
  [15:0] FWPMYDCN3.PMYDN
0x874C6838 MFWD
  [15:0] FWPMRDCN3.PMRDN
0x874C6840 MFWD
  [15:0] FWPMGDCN4.PMGDN
0x874C6844 MFWD
  [15:0] FWPMYDCN4.PMYDN
0x874C6848 MFWD
  [15:0] FWPMRDCN4.PMRDN
0x874C6850 MFWD
  [15:0] FWPMGDCN5.PMGDN
0x874C6854 MFWD
  [15:0] FWPMYDCN5.PMYDN
0x874C6858 MFWD
  [15:0] FWPMRDCN5.PMRDN
0x874C6860 MFWD
  [15:0] FWPMGDCN6.PMGDN
0x874C6864 MFWD
  [15:0] FWPMYDCN6.PMYDN
0x874C6868 MFWD
  [15:0] FWPMRDCN6.PMRDN
0x874C6870 MFWD
  [15:0] FWPMGDCN7.PMGDN
0x874C6874 MFWD
  [15:0] FWPMYDCN7.PMYDN
0x874C6878 MFWD
  [15:0] FWPMRDCN7.PMRDN
0x874C6880 MFWD
  [15:0] FWPMGDCN8.PMGDN
0x874C6888 MFWD
  [15:0] FWPMRDCN8.PMRDN
0x874C6890 MFWD
  [15:0] FWPMGDCN9.PMGDN
0x874C6898 MFWD
  [15:0] FWPMRDCN9.PMRDN
0x874C68A0 MFWD
  [15:0] FWPMGDCN10.PMGDN
0x874C68A8 MFWD
  [15:0] FWPMRDCN10.PMRDN
0x874C68B0 MFWD
  [15:0] FWPMGDCN11.PMGDN
0x874C68B8 MFWD
  [15:0] FWPMRDCN11.PMRDN
0x874C68C0 MFWD
  [15:0] FWPMGDCN12.PMGDN
0x874C68C8 MFWD
  [15:0] FWPMRDCN12.PMRDN
0x874C68D0 MFWD
  [15:0] FWPMGDCN13.PMGDN
0x874C68D8 MFWD
  [15:0] FWPMRDCN13.PMRDN
0x874C68E0 MFWD
  [15:0] FWPMGDCN14.PMGDN
0x874C68E8 MFWD
  [15:0] FWPMRDCN14.PMRDN
0x874C68F0 MFWD
  [15:0] FWPMGDCN15.PMGDN
0x874C68F8 MFWD
  [15:0] FWPMRDCN15.PMRDN
0x874C6900 MFWD
  [15:0] FWPMGDCN16.PMGDN
0x874C6908 MFWD
  [15:0] FWPMRDCN16.PMRDN
0x874C6910 MFWD
  [15:0] FWPMGDCN17.PMGDN
0x874C6918 MFWD
  [15:0] FWPMRDCN17.PMRDN
0x874C6920 MFWD
  [15:0] FWPMGDCN18.PMGDN
0x874C6928 MFWD
  [15:0] FWPMRDCN18.PMRDN
0x874C6930 MFWD
  [15:0] FWPMGDCN19.PMGDN
0x874C6938 MFWD
  [15:0] FWPMRDCN19.PMRDN
0x874C6940 MFWD
  [15:0] FWPMGDCN20.PMGDN
0x874C6948 MFWD
  [15:0] FWPMRDCN20.PMRDN
0x874C6950 MFWD
  [15:0] FWPMGDCN21.PMGDN
0x874C6958 MFWD
  [15:0] FWPMRDCN21.PMRDN
0x874C6960 MFWD
  [15:0] FWPMGDCN22.PMGDN
0x874C6968 MFWD
  [15:0] FWPMRDCN22.PMRDN
0x874C6970 MFWD
  [15:0] FWPMGDCN23.PMGDN
0x874C6978 MFWD
  [15:0] FWPMRDCN23.PMRDN
0x874C6980 MFWD
  [15:0] FWPMGDCN24.PMGDN
0x874C6988 MFWD
  [15:0] FWPMRDCN24.PMRDN
0x874C6990 MFWD
  [15:0] FWPMGDCN25.PMGDN
0x874C6998 MFWD
  [15:0] FWPMRDCN25.PMRDN
0x874C69A0 MFWD
  [15:0] FWPMGDCN26.PMGDN
0x874C69A8 MFWD
  [15:0] FWPMRDCN26.PMRDN
0x874C69B0 MFWD
  [15:0] FWPMGDCN27.PMGDN
0x874C69B8 MFWD
  [15:0] FWPMRDCN27.PMRDN
0x874C69C0 MFWD
  [15:0] FWPMGDCN28.PMGDN
0x874C69C8 MFWD
  [15:0] FWPMRDCN28.PMRDN
0x874C69D0 MFWD
  [15:0] FWPMGDCN29.PMGDN
0x874C69D8 MFWD
  [15:0] FWPMRDCN29.PMRDN
0x874C69E0 MFWD
  [15:0] FWPMGDCN30.PMGDN
0x874C69E8 MFWD
  [15:0] FWPMRDCN30.PMRDN
0x874C69F0 MFWD
  [15:0] FWPMGDCN31.PMGDN
0x874C69F8 MFWD
  [15:0] FWPMRDCN31.PMRDN
0x874C6A00 MFWD
  [15:0] FWFRPPCN0.PPC
0x874C6A04 MFWD
  [15:0] FWFRDPCN0.DPC
0x874C6A08 MFWD
  [15:0] FWFRPPCN1.PPC
0x874C6A0C MFWD
  [15:0] FWFRDPCN1.DPC
0x874C6A10 MFWD
  [15:0] FWFRPPCN2.PPC
0x874C6A14 MFWD
  [15:0] FWFRDPCN2.DPC
0x874C6A18 MFWD
  [15:0] FWFRPPCN3.PPC
0x874C6A1C MFWD
  [15:0] FWFRDPCN3.DPC
0x874C6A20 MFWD
  [15:0] FWFRPPCN4.PPC
0x874C6A24 MFWD
  [15:0] FWFRDPCN4.DPC
0x874C6A28 MFWD
  [15:0] FWFRPPCN5.PPC
0x874C6A2C MFWD
  [15:0] FWFRDPCN5.DPC
0x874C6A30 MFWD
  [15:0] FWFRPPCN6.PPC
0x874C6A34 MFWD
  [15:0] FWFRDPCN6.DPC
0x874C6A38 MFWD
  [15:0] FWFRPPCN7.PPC
0x874C6A3C MFWD
  [15:0] FWFRDPCN7.DPC
0x874C6A40 MFWD
  [15:0] FWFRPPCN8.PPC
0x874C6A44 MFWD
  [15:0] FWFRDPCN8.DPC
0x874C6A48 MFWD
  [15:0] FWFRPPCN9.PPC
0x874C6A4C MFWD
  [15:0] FWFRDPCN9.DPC
0x874C6A50 MFWD
  [15:0] FWFRPPCN10.PPC
0x874C6A54 MFWD
  [15:0] FWFRDPCN10.DPC
0x874C6A58 MFWD
  [15:0] FWFRPPCN11.PPC
0x874C6A5C MFWD
  [15:0] FWFRDPCN11.DPC
0x874C6A60 MFWD
  [15:0] FWFRPPCN12.PPC
0x874C6A64 MFWD
  [15:0] FWFRDPCN12.DPC
0x874C6A68 MFWD
  [15:0] FWFRPPCN13.PPC
0x874C6A6C MFWD
  [15:0] FWFRDPCN13.DPC
0x874C6A70 MFWD
  [15:0] FWFRPPCN14.PPC
0x874C6A74 MFWD
  [15:0] FWFRDPCN14.DPC
0x874C6A78 MFWD
  [15:0] FWFRPPCN15.PPC
0x874C6A7C MFWD
  [15:0] FWFRDPCN15.DPC
0x874C6A80 MFWD
  [15:0] FWFRPPCN16.PPC
0x874C6A84 MFWD
  [15:0] FWFRDPCN16.DPC
0x874C6A88 MFWD
  [15:0] FWFRPPCN17.PPC
0x874C6A8C MFWD
  [15:0] FWFRDPCN17.DPC
0x874C6A90 MFWD
  [15:0] FWFRPPCN18.PPC
0x874C6A94 MFWD
  [15:0] FWFRDPCN18.DPC
0x874C6A98 MFWD
  [15:0] FWFRPPCN19.PPC
0x874C6A9C MFWD
  [15:0] FWFRDPCN19.DPC
0x874C6AA0 MFWD
  [15:0] FWFRPPCN20.PPC
0x874C6AA4 MFWD
  [15:0] FWFRDPCN20.DPC
0x874C6AA8 MFWD
  [15:0] FWFRPPCN21.PPC
0x874C6AAC MFWD
  [15:0] FWFRDPCN21.DPC
0x874C6AB0 MFWD
  [15:0] FWFRPPCN22.PPC
0x874C6AB4 MFWD
  [15:0] FWFRDPCN22.DPC
0x874C6AB8 MFWD
  [15:0] FWFRPPCN23.PPC
0x874C6ABC MFWD
  [15:0] FWFRDPCN23.DPC
0x874C6AC0 MFWD
  [15:0] FWFRPPCN24.PPC
0x874C6AC4 MFWD
  [15:0] FWFRDPCN24.DPC
0x874C6AC8 MFWD
  [15:0] FWFRPPCN25.PPC
0x874C6ACC MFWD
  [15:0] FWFRDPCN25.DPC
0x874C6AD0 MFWD
  [15:0] FWFRPPCN26.PPC
0x874C6AD4 MFWD
  [15:0] FWFRDPCN26.DPC
0x874C6AD8 MFWD
  [15:0] FWFRPPCN27.PPC
0x874C6ADC MFWD
  [15:0] FWFRDPCN27.DPC
0x874C6AE0 MFWD
  [15:0] FWFRPPCN28.PPC
0x874C6AE4 MFWD
  [15:0] FWFRDPCN28.DPC
0x874C6AE8 MFWD
  [15:0] FWFRPPCN29.PPC
0x874C6AEC MFWD
  [15:0] FWFRDPCN29.DPC
0x874C6AF0 MFWD
  [15:0] FWFRPPCN30.PPC
0x874C6AF4 MFWD
  [15:0] FWFRDPCN30.DPC
0x874C6AF8 MFWD
  [15:0] FWFRPPCN31.PPC
0x874C6AFC MFWD
  [15:0] FWFRDPCN31.DPC
0x874C6B00 MFWD
  [15:0] FWFRPPCN32.PPC
0x874C6B04 MFWD
  [15:0] FWFRDPCN32.DPC
0x874C6B08 MFWD
  [15:0] FWFRPPCN33.PPC
0x874C6B0C MFWD
  [15:0] FWFRDPCN33.DPC
0x874C6B10 MFWD
  [15:0] FWFRPPCN34.PPC
0x874C6B14 MFWD
  [15:0] FWFRDPCN34.DPC
0x874C6B18 MFWD
  [15:0] FWFRPPCN35.PPC
0x874C6B1C MFWD
  [15:0] FWFRDPCN35.DPC
0x874C6B20 MFWD
  [15:0] FWFRPPCN36.PPC
0x874C6B24 MFWD
  [15:0] FWFRDPCN36.DPC
0x874C6B28 MFWD
  [15:0] FWFRPPCN37.PPC
0x874C6B2C MFWD
  [15:0] FWFRDPCN37.DPC
0x874C6B30 MFWD
  [15:0] FWFRPPCN38.PPC
0x874C6B34 MFWD
  [15:0] FWFRDPCN38.DPC
0x874C6B38 MFWD
  [15:0] FWFRPPCN39.PPC
0x874C6B3C MFWD
  [15:0] FWFRDPCN39.DPC
0x874C6B40 MFWD
  [15:0] FWFRPPCN40.PPC
0x874C6B44 MFWD
  [15:0] FWFRDPCN40.DPC
0x874C6B48 MFWD
  [15:0] FWFRPPCN41.PPC
0x874C6B4C MFWD
  [15:0] FWFRDPCN41.DPC
0x874C6B50 MFWD
  [15:0] FWFRPPCN42.PPC
0x874C6B54 MFWD
  [15:0] FWFRDPCN42.DPC
0x874C6B58 MFWD
  [15:0] FWFRPPCN43.PPC
0x874C6B5C MFWD
  [15:0] FWFRDPCN43.DPC
0x874C6B60 MFWD
  [15:0] FWFRPPCN44.PPC
0x874C6B64 MFWD
  [15:0] FWFRDPCN44.DPC
0x874C6B68 MFWD
  [15:0] FWFRPPCN45.PPC
0x874C6B6C MFWD
  [15:0] FWFRDPCN45.DPC
0x874C6B70 MFWD
  [15:0] FWFRPPCN46.PPC
0x874C6B74 MFWD
  [15:0] FWFRDPCN46.DPC
0x874C6B78 MFWD
  [15:0] FWFRPPCN47.PPC
0x874C6B7C MFWD
  [15:0] FWFRDPCN47.DPC
0x874C6B80 MFWD
  [15:0] FWFRPPCN48.PPC
0x874C6B84 MFWD
  [15:0] FWFRDPCN48.DPC
0x874C6B88 MFWD
  [15:0] FWFRPPCN49.PPC
0x874C6B8C MFWD
  [15:0] FWFRDPCN49.DPC
0x874C6B90 MFWD
  [15:0] FWFRPPCN50.PPC
0x874C6B94 MFWD
  [15:0] FWFRDPCN50.DPC
0x874C6B98 MFWD
  [15:0] FWFRPPCN51.PPC
0x874C6B9C MFWD
  [15:0] FWFRDPCN51.DPC
0x874C6BA0 MFWD
  [15:0] FWFRPPCN52.PPC
0x874C6BA4 MFWD
  [15:0] FWFRDPCN52.DPC
0x874C6BA8 MFWD
  [15:0] FWFRPPCN53.PPC
0x874C6BAC MFWD
  [15:0] FWFRDPCN53.DPC
0x874C6BB0 MFWD
  [15:0] FWFRPPCN54.PPC
0x874C6BB4 MFWD
  [15:0] FWFRDPCN54.DPC
0x874C6BB8 MFWD
  [15:0] FWFRPPCN55.PPC
0x874C6BBC MFWD
  [15:0] FWFRDPCN55.DPC
0x874C6BC0 MFWD
  [15:0] FWFRPPCN56.PPC
0x874C6BC4 MFWD
  [15:0] FWFRDPCN56.DPC
0x874C6BC8 MFWD
  [15:0] FWFRPPCN57.PPC
0x874C6BCC MFWD
  [15:0] FWFRDPCN57.DPC
0x874C6BD0 MFWD
  [15:0] FWFRPPCN58.PPC
0x874C6BD4 MFWD
  [15:0] FWFRDPCN58.DPC
0x874C6BD8 MFWD
  [15:0] FWFRPPCN59.PPC
0x874C6BDC MFWD
  [15:0] FWFRDPCN59.DPC
0x874C6BE0 MFWD
  [15:0] FWFRPPCN60.PPC
0x874C6BE4 MFWD
  [15:0] FWFRDPCN60.DPC
0x874C6BE8 MFWD
  [15:0] FWFRPPCN61.PPC
0x874C6BEC MFWD
  [15:0] FWFRDPCN61.DPC
0x874C6BF0 MFWD
  [15:0] FWFRPPCN62.PPC
0x874C6BF4 MFWD
  [15:0] FWFRDPCN62.DPC
0x874C6BF8 MFWD
  [15:0] FWFRPPCN63.PPC
0x874C6BFC MFWD
  [15:0] FWFRDPCN63.DPC
0x874C6C00 MFWD
  [15:0] FWFRPPCN64.PPC
0x874C6C04 MFWD
  [15:0] FWFRDPCN64.DPC
0x874C6C08 MFWD
  [15:0] FWFRPPCN65.PPC
0x874C6C0C MFWD
  [15:0] FWFRDPCN65.DPC
0x874C6C10 MFWD
  [15:0] FWFRPPCN66.PPC
0x874C6C14 MFWD
  [15:0] FWFRDPCN66.DPC
0x874C6C18 MFWD
  [15:0] FWFRPPCN67.PPC
0x874C6C1C MFWD
  [15:0] FWFRDPCN67.DPC
0x874C6C20 MFWD
  [15:0] FWFRPPCN68.PPC
0x874C6C24 MFWD
  [15:0] FWFRDPCN68.DPC
0x874C6C28 MFWD
  [15:0] FWFRPPCN69.PPC
0x874C6C2C MFWD
  [15:0] FWFRDPCN69.DPC
0x874C6C30 MFWD
  [15:0] FWFRPPCN70.PPC
0x874C6C34 MFWD
  [15:0] FWFRDPCN70.DPC
0x874C6C38 MFWD
  [15:0] FWFRPPCN71.PPC
0x874C6C3C MFWD
  [15:0] FWFRDPCN71.DPC
0x874C6C40 MFWD
  [15:0] FWFRPPCN72.PPC
0x874C6C44 MFWD
  [15:0] FWFRDPCN72.DPC
0x874C6C48 MFWD
  [15:0] FWFRPPCN73.PPC
0x874C6C4C MFWD
  [15:0] FWFRDPCN73.DPC
0x874C6C50 MFWD
  [15:0] FWFRPPCN74.PPC
0x874C6C54 MFWD
  [15:0] FWFRDPCN74.DPC
0x874C6C58 MFWD
  [15:0] FWFRPPCN75.PPC
0x874C6C5C MFWD
  [15:0] FWFRDPCN75.DPC
0x874C6C60 MFWD
  [15:0] FWFRPPCN76.PPC
0x874C6C64 MFWD
  [15:0] FWFRDPCN76.DPC
0x874C6C68 MFWD
  [15:0] FWFRPPCN77.PPC
0x874C6C6C MFWD
  [15:0] FWFRDPCN77.DPC
0x874C6C70 MFWD
  [15:0] FWFRPPCN78.PPC
0x874C6C74 MFWD
  [15:0] FWFRDPCN78.DPC
0x874C6C78 MFWD
  [15:0] FWFRPPCN79.PPC
0x874C6C7C MFWD
  [15:0] FWFRDPCN79.DPC
0x874C6C80 MFWD
  [15:0] FWFRPPCN80.PPC
0x874C6C84 MFWD
  [15:0] FWFRDPCN80.DPC
0x874C6C88 MFWD
  [15:0] FWFRPPCN81.PPC
0x874C6C8C MFWD
  [15:0] FWFRDPCN81.DPC
0x874C6C90 MFWD
  [15:0] FWFRPPCN82.PPC
0x874C6C94 MFWD
  [15:0] FWFRDPCN82.DPC
0x874C6C98 MFWD
  [15:0] FWFRPPCN83.PPC
0x874C6C9C MFWD
  [15:0] FWFRDPCN83.DPC
0x874C6CA0 MFWD
  [15:0] FWFRPPCN84.PPC
0x874C6CA4 MFWD
  [15:0] FWFRDPCN84.DPC
0x874C6CA8 MFWD
  [15:0] FWFRPPCN85.PPC
0x874C6CAC MFWD
  [15:0] FWFRDPCN85.DPC
0x874C6CB0 MFWD
  [15:0] FWFRPPCN86.PPC
0x874C6CB4 MFWD
  [15:0] FWFRDPCN86.DPC
0x874C6CB8 MFWD
  [15:0] FWFRPPCN87.PPC
0x874C6CBC MFWD
  [15:0] FWFRDPCN87.DPC
0x874C6CC0 MFWD
  [15:0] FWFRPPCN88.PPC
0x874C6CC4 MFWD
  [15:0] FWFRDPCN88.DPC
0x874C6CC8 MFWD
  [15:0] FWFRPPCN89.PPC
0x874C6CCC MFWD
  [15:0] FWFRDPCN89.DPC
0x874C6CD0 MFWD
  [15:0] FWFRPPCN90.PPC
0x874C6CD4 MFWD
  [15:0] FWFRDPCN90.DPC
0x874C6CD8 MFWD
  [15:0] FWFRPPCN91.PPC
0x874C6CDC MFWD
  [15:0] FWFRDPCN91.DPC
0x874C6CE0 MFWD
  [15:0] FWFRPPCN92.PPC
0x874C6CE4 MFWD
  [15:0] FWFRDPCN92.DPC
0x874C6CE8 MFWD
  [15:0] FWFRPPCN93.PPC
0x874C6CEC MFWD
  [15:0] FWFRDPCN93.DPC
0x874C6CF0 MFWD
  [15:0] FWFRPPCN94.PPC
0x874C6CF4 MFWD
  [15:0] FWFRDPCN94.DPC
0x874C6CF8 MFWD
  [15:0] FWFRPPCN95.PPC
0x874C6CFC MFWD
  [15:0] FWFRDPCN95.DPC
0x874C6D00 MFWD
  [15:0] FWFRPPCN96.PPC
0x874C6D04 MFWD
  [15:0] FWFRDPCN96.DPC
0x874C6D08 MFWD
  [15:0] FWFRPPCN97.PPC
0x874C6D0C MFWD
  [15:0] FWFRDPCN97.DPC
0x874C6D10 MFWD
  [15:0] FWFRPPCN98.PPC
0x874C6D14 MFWD
  [15:0] FWFRDPCN98.DPC
0x874C6D18 MFWD
  [15:0] FWFRPPCN99.PPC
0x874C6D1C MFWD
  [15:0] FWFRDPCN99.DPC
0x874C6D20 MFWD
  [15:0] FWFRPPCN100.PPC
0x874C6D24 MFWD
  [15:0] FWFRDPCN100.DPC
0x874C6D28 MFWD
  [15:0] FWFRPPCN101.PPC
0x874C6D2C MFWD
  [15:0] FWFRDPCN101.DPC
0x874C6D30 MFWD
  [15:0] FWFRPPCN102.PPC
0x874C6D34 MFWD
  [15:0] FWFRDPCN102.DPC
0x874C6D38 MFWD
  [15:0] FWFRPPCN103.PPC
0x874C6D3C MFWD
  [15:0] FWFRDPCN103.DPC
0x874C6D40 MFWD
  [15:0] FWFRPPCN104.PPC
0x874C6D44 MFWD
  [15:0] FWFRDPCN104.DPC
0x874C6D48 MFWD
  [15:0] FWFRPPCN105.PPC
0x874C6D4C MFWD
  [15:0] FWFRDPCN105.DPC
0x874C6D50 MFWD
  [15:0] FWFRPPCN106.PPC
0x874C6D54 MFWD
  [15:0] FWFRDPCN106.DPC
0x874C6D58 MFWD
  [15:0] FWFRPPCN107.PPC
0x874C6D5C MFWD
  [15:0] FWFRDPCN107.DPC
0x874C6D60 MFWD
  [15:0] FWFRPPCN108.PPC
0x874C6D64 MFWD
  [15:0] FWFRDPCN108.DPC
0x874C6D68 MFWD
  [15:0] FWFRPPCN109.PPC
0x874C6D6C MFWD
  [15:0] FWFRDPCN109.DPC
0x874C6D70 MFWD
  [15:0] FWFRPPCN110.PPC
0x874C6D74 MFWD
  [15:0] FWFRDPCN110.DPC
0x874C6D78 MFWD
  [15:0] FWFRPPCN111.PPC
0x874C6D7C MFWD
  [15:0] FWFRDPCN111.DPC
0x874C6D80 MFWD
  [15:0] FWFRPPCN112.PPC
0x874C6D84 MFWD
  [15:0] FWFRDPCN112.DPC
0x874C6D88 MFWD
  [15:0] FWFRPPCN113.PPC
0x874C6D8C MFWD
  [15:0] FWFRDPCN113.DPC
0x874C6D90 MFWD
  [15:0] FWFRPPCN114.PPC
0x874C6D94 MFWD
  [15:0] FWFRDPCN114.DPC
0x874C6D98 MFWD
  [15:0] FWFRPPCN115.PPC
0x874C6D9C MFWD
  [15:0] FWFRDPCN115.DPC
0x874C6DA0 MFWD
  [15:0] FWFRPPCN116.PPC
0x874C6DA4 MFWD
  [15:0] FWFRDPCN116.DPC
0x874C6DA8 MFWD
  [15:0] FWFRPPCN117.PPC
0x874C6DAC MFWD
  [15:0] FWFRDPCN117.DPC
0x874C6DB0 MFWD
  [15:0] FWFRPPCN118.PPC
0x874C6DB4 MFWD
  [15:0] FWFRDPCN118.DPC
0x874C6DB8 MFWD
  [15:0] FWFRPPCN119.PPC
0x874C6DBC MFWD
  [15:0] FWFRDPCN119.DPC
0x874C6DC0 MFWD
  [15:0] FWFRPPCN120.PPC
0x874C6DC4 MFWD
  [15:0] FWFRDPCN120.DPC
0x874C6DC8 MFWD
  [15:0] FWFRPPCN121.PPC
0x874C6DCC MFWD
  [15:0] FWFRDPCN121.DPC
0x874C6DD0 MFWD
  [15:0] FWFRPPCN122.PPC
0x874C6DD4 MFWD
  [15:0] FWFRDPCN122.DPC
0x874C6DD8 MFWD
  [15:0] FWFRPPCN123.PPC
0x874C6DDC MFWD
  [15:0] FWFRDPCN123.DPC
0x874C6DE0 MFWD
  [15:0] FWFRPPCN124.PPC
0x874C6DE4 MFWD
  [15:0] FWFRDPCN124.DPC
0x874C6DE8 MFWD
  [15:0] FWFRPPCN125.PPC
0x874C6DEC MFWD
  [15:0] FWFRDPCN125.DPC
0x874C6DF0 MFWD
  [15:0] FWFRPPCN126.PPC
0x874C6DF4 MFWD
  [15:0] FWFRDPCN126.DPC
# iorx74m register map
Registers are 32-bit, access not given, no defined reset value unless marked. A register's access mark holds for its fields unless they carry their own. Addresses are absolute; registers are grouped by the start of their names; [hi:lo] are bit positions; {n}, {i} and the like mark numbered series; 'fields as' and 'values as' point back to an identical list.

## SFR (part 8 of 10)
0x874C6DF8 MFWD
  [15:0] FWFRPPCN127.PPC
0x874C6DFC MFWD
  [15:0] FWFRDPCN127.DPC
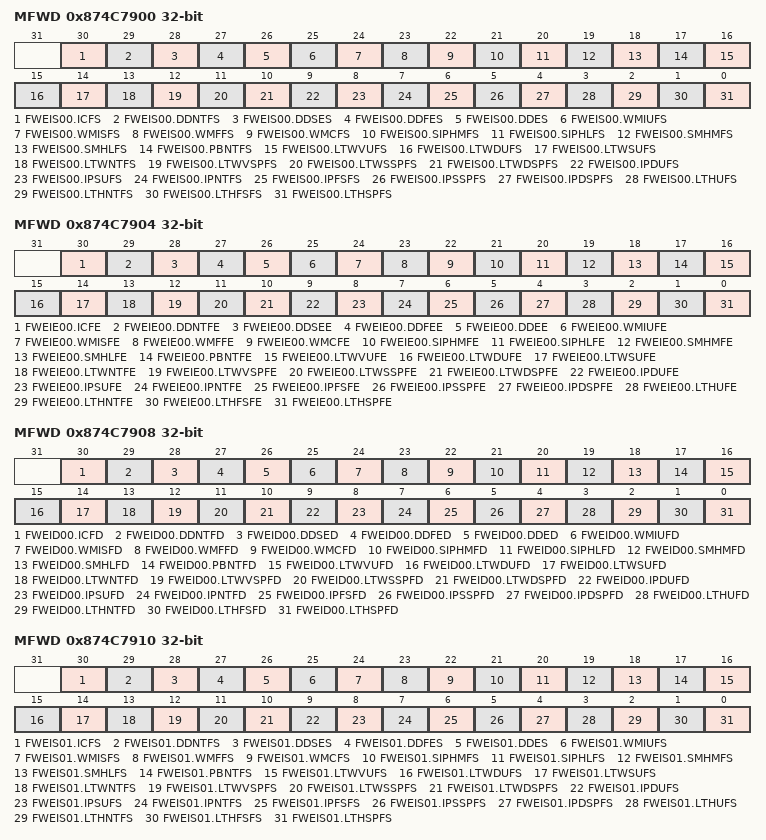
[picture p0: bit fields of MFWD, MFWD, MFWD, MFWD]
0x874C7900 MFWD
  [30] FWEIS00.ICFS, [29] FWEIS00.DDNTFS, [28] FWEIS00.DDSES, [27] FWEIS00.DDFES, [26] FWEIS00.DDES, [25] FWEIS00.WMIUFS, [24] FWEIS00.WMISFS, [23] FWEIS00.WMFFS, [22] FWEIS00.WMCFS, [21] FWEIS00.SIPHMFS, [20] FWEIS00.SIPHLFS, [19] FWEIS00.SMHMFS, [18] FWEIS00.SMHLFS, [17] FWEIS00.PBNTFS, [16] FWEIS00.LTWVUFS, [15] FWEIS00.LTWDUFS, [14] FWEIS00.LTWSUFS, [13] FWEIS00.LTWNTFS, [12] FWEIS00.LTWVSPFS, [11] FWEIS00.LTWSSPFS, [10] FWEIS00.LTWDSPFS, [9] FWEIS00.IPDUFS, [8] FWEIS00.IPSUFS, [7] FWEIS00.IPNTFS, [6] FWEIS00.IPFSFS, [5] FWEIS00.IPSSPFS, [4] FWEIS00.IPDSPFS, [3] FWEIS00.LTHUFS, [2] FWEIS00.LTHNTFS, [1] FWEIS00.LTHFSFS, [0] FWEIS00.LTHSPFS
0x874C7904 MFWD
  [30] FWEIE00.ICFE, [29] FWEIE00.DDNTFE, [28] FWEIE00.DDSEE, [27] FWEIE00.DDFEE, [26] FWEIE00.DDEE, [25] FWEIE00.WMIUFE, [24] FWEIE00.WMISFE, [23] FWEIE00.WMFFE, [22] FWEIE00.WMCFE, [21] FWEIE00.SIPHMFE, [20] FWEIE00.SIPHLFE, [19] FWEIE00.SMHMFE, [18] FWEIE00.SMHLFE, [17] FWEIE00.PBNTFE, [16] FWEIE00.LTWVUFE, [15] FWEIE00.LTWDUFE, [14] FWEIE00.LTWSUFE, [13] FWEIE00.LTWNTFE, [12] FWEIE00.LTWVSPFE, [11] FWEIE00.LTWSSPFE, [10] FWEIE00.LTWDSPFE, [9] FWEIE00.IPDUFE, [8] FWEIE00.IPSUFE, [7] FWEIE00.IPNTFE, [6] FWEIE00.IPFSFE, [5] FWEIE00.IPSSPFE, [4] FWEIE00.IPDSPFE, [3] FWEIE00.LTHUFE, [2] FWEIE00.LTHNTFE, [1] FWEIE00.LTHFSFE, [0] FWEIE00.LTHSPFE
0x874C7908 MFWD
  [30] FWEID00.ICFD, [29] FWEID00.DDNTFD, [28] FWEID00.DDSED, [27] FWEID00.DDFED, [26] FWEID00.DDED, [25] FWEID00.WMIUFD, [24] FWEID00.WMISFD, [23] FWEID00.WMFFD, [22] FWEID00.WMCFD, [21] FWEID00.SIPHMFD, [20] FWEID00.SIPHLFD, [19] FWEID00.SMHMFD, [18] FWEID00.SMHLFD, [17] FWEID00.PBNTFD, [16] FWEID00.LTWVUFD, [15] FWEID00.LTWDUFD, [14] FWEID00.LTWSUFD, [13] FWEID00.LTWNTFD, [12] FWEID00.LTWVSPFD, [11] FWEID00.LTWSSPFD, [10] FWEID00.LTWDSPFD, [9] FWEID00.IPDUFD, [8] FWEID00.IPSUFD, [7] FWEID00.IPNTFD, [6] FWEID00.IPFSFD, [5] FWEID00.IPSSPFD, [4] FWEID00.IPDSPFD, [3] FWEID00.LTHUFD, [2] FWEID00.LTHNTFD, [1] FWEID00.LTHFSFD, [0] FWEID00.LTHSPFD
0x874C7910 MFWD
  [30] FWEIS01.ICFS, [29] FWEIS01.DDNTFS, [28] FWEIS01.DDSES, [27] FWEIS01.DDFES, [26] FWEIS01.DDES, [25] FWEIS01.WMIUFS, [24] FWEIS01.WMISFS, [23] FWEIS01.WMFFS, [22] FWEIS01.WMCFS, [21] FWEIS01.SIPHMFS, [20] FWEIS01.SIPHLFS, [19] FWEIS01.SMHMFS, [18] FWEIS01.SMHLFS, [17] FWEIS01.PBNTFS, [16] FWEIS01.LTWVUFS, [15] FWEIS01.LTWDUFS, [14] FWEIS01.LTWSUFS, [13] FWEIS01.LTWNTFS, [12] FWEIS01.LTWVSPFS, [11] FWEIS01.LTWSSPFS, [10] FWEIS01.LTWDSPFS, [9] FWEIS01.IPDUFS, [8] FWEIS01.IPSUFS, [7] FWEIS01.IPNTFS, [6] FWEIS01.IPFSFS, [5] FWEIS01.IPSSPFS, [4] FWEIS01.IPDSPFS, [3] FWEIS01.LTHUFS, [2] FWEIS01.LTHNTFS, [1] FWEIS01.LTHFSFS, [0] FWEIS01.LTHSPFS
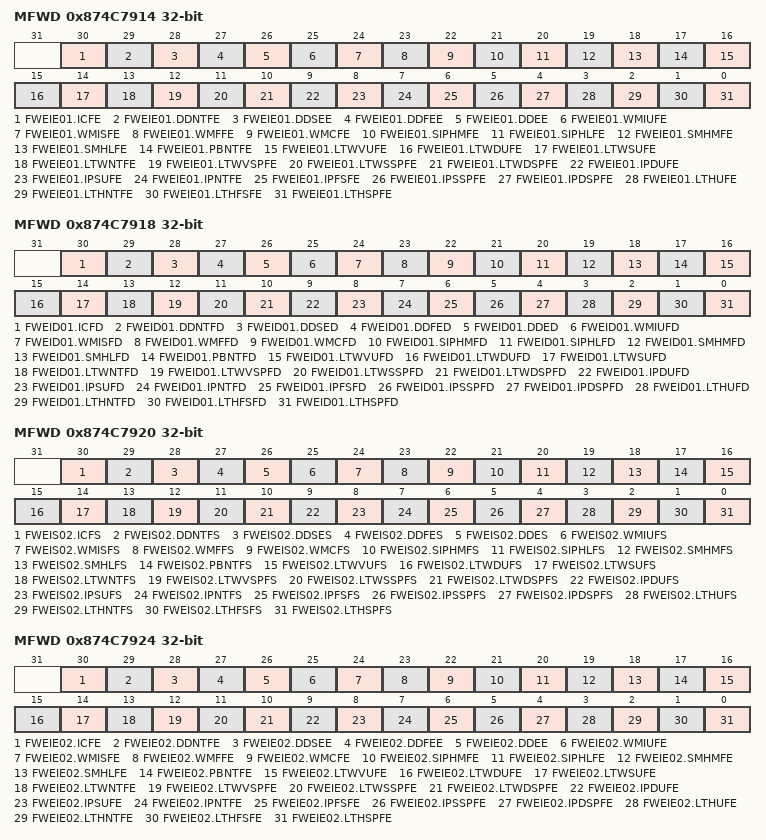
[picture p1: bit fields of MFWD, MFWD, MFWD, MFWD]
0x874C7914 MFWD
  [30] FWEIE01.ICFE, [29] FWEIE01.DDNTFE, [28] FWEIE01.DDSEE, [27] FWEIE01.DDFEE, [26] FWEIE01.DDEE, [25] FWEIE01.WMIUFE, [24] FWEIE01.WMISFE, [23] FWEIE01.WMFFE, [22] FWEIE01.WMCFE, [21] FWEIE01.SIPHMFE, [20] FWEIE01.SIPHLFE, [19] FWEIE01.SMHMFE, [18] FWEIE01.SMHLFE, [17] FWEIE01.PBNTFE, [16] FWEIE01.LTWVUFE, [15] FWEIE01.LTWDUFE, [14] FWEIE01.LTWSUFE, [13] FWEIE01.LTWNTFE, [12] FWEIE01.LTWVSPFE, [11] FWEIE01.LTWSSPFE, [10] FWEIE01.LTWDSPFE, [9] FWEIE01.IPDUFE, [8] FWEIE01.IPSUFE, [7] FWEIE01.IPNTFE, [6] FWEIE01.IPFSFE, [5] FWEIE01.IPSSPFE, [4] FWEIE01.IPDSPFE, [3] FWEIE01.LTHUFE, [2] FWEIE01.LTHNTFE, [1] FWEIE01.LTHFSFE, [0] FWEIE01.LTHSPFE
0x874C7918 MFWD
  [30] FWEID01.ICFD, [29] FWEID01.DDNTFD, [28] FWEID01.DDSED, [27] FWEID01.DDFED, [26] FWEID01.DDED, [25] FWEID01.WMIUFD, [24] FWEID01.WMISFD, [23] FWEID01.WMFFD, [22] FWEID01.WMCFD, [21] FWEID01.SIPHMFD, [20] FWEID01.SIPHLFD, [19] FWEID01.SMHMFD, [18] FWEID01.SMHLFD, [17] FWEID01.PBNTFD, [16] FWEID01.LTWVUFD, [15] FWEID01.LTWDUFD, [14] FWEID01.LTWSUFD, [13] FWEID01.LTWNTFD, [12] FWEID01.LTWVSPFD, [11] FWEID01.LTWSSPFD, [10] FWEID01.LTWDSPFD, [9] FWEID01.IPDUFD, [8] FWEID01.IPSUFD, [7] FWEID01.IPNTFD, [6] FWEID01.IPFSFD, [5] FWEID01.IPSSPFD, [4] FWEID01.IPDSPFD, [3] FWEID01.LTHUFD, [2] FWEID01.LTHNTFD, [1] FWEID01.LTHFSFD, [0] FWEID01.LTHSPFD
0x874C7920 MFWD
  [30] FWEIS02.ICFS, [29] FWEIS02.DDNTFS, [28] FWEIS02.DDSES, [27] FWEIS02.DDFES, [26] FWEIS02.DDES, [25] FWEIS02.WMIUFS, [24] FWEIS02.WMISFS, [23] FWEIS02.WMFFS, [22] FWEIS02.WMCFS, [21] FWEIS02.SIPHMFS, [20] FWEIS02.SIPHLFS, [19] FWEIS02.SMHMFS, [18] FWEIS02.SMHLFS, [17] FWEIS02.PBNTFS, [16] FWEIS02.LTWVUFS, [15] FWEIS02.LTWDUFS, [14] FWEIS02.LTWSUFS, [13] FWEIS02.LTWNTFS, [12] FWEIS02.LTWVSPFS, [11] FWEIS02.LTWSSPFS, [10] FWEIS02.LTWDSPFS, [9] FWEIS02.IPDUFS, [8] FWEIS02.IPSUFS, [7] FWEIS02.IPNTFS, [6] FWEIS02.IPFSFS, [5] FWEIS02.IPSSPFS, [4] FWEIS02.IPDSPFS, [3] FWEIS02.LTHUFS, [2] FWEIS02.LTHNTFS, [1] FWEIS02.LTHFSFS, [0] FWEIS02.LTHSPFS
0x874C7924 MFWD
  [30] FWEIE02.ICFE, [29] FWEIE02.DDNTFE, [28] FWEIE02.DDSEE, [27] FWEIE02.DDFEE, [26] FWEIE02.DDEE, [25] FWEIE02.WMIUFE, [24] FWEIE02.WMISFE, [23] FWEIE02.WMFFE, [22] FWEIE02.WMCFE, [21] FWEIE02.SIPHMFE, [20] FWEIE02.SIPHLFE, [19] FWEIE02.SMHMFE, [18] FWEIE02.SMHLFE, [17] FWEIE02.PBNTFE, [16] FWEIE02.LTWVUFE, [15] FWEIE02.LTWDUFE, [14] FWEIE02.LTWSUFE, [13] FWEIE02.LTWNTFE, [12] FWEIE02.LTWVSPFE, [11] FWEIE02.LTWSSPFE, [10] FWEIE02.LTWDSPFE, [9] FWEIE02.IPDUFE, [8] FWEIE02.IPSUFE, [7] FWEIE02.IPNTFE, [6] FWEIE02.IPFSFE, [5] FWEIE02.IPSSPFE, [4] FWEIE02.IPDSPFE, [3] FWEIE02.LTHUFE, [2] FWEIE02.LTHNTFE, [1] FWEIE02.LTHFSFE, [0] FWEIE02.LTHSPFE
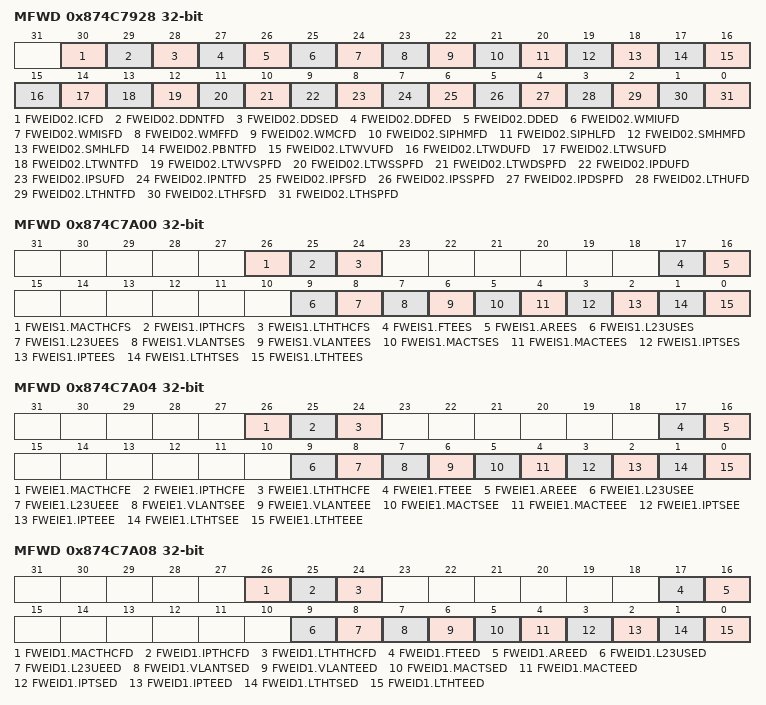
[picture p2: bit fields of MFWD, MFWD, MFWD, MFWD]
0x874C7928 MFWD
  [30] FWEID02.ICFD, [29] FWEID02.DDNTFD, [28] FWEID02.DDSED, [27] FWEID02.DDFED, [26] FWEID02.DDED, [25] FWEID02.WMIUFD, [24] FWEID02.WMISFD, [23] FWEID02.WMFFD, [22] FWEID02.WMCFD, [21] FWEID02.SIPHMFD, [20] FWEID02.SIPHLFD, [19] FWEID02.SMHMFD, [18] FWEID02.SMHLFD, [17] FWEID02.PBNTFD, [16] FWEID02.LTWVUFD, [15] FWEID02.LTWDUFD, [14] FWEID02.LTWSUFD, [13] FWEID02.LTWNTFD, [12] FWEID02.LTWVSPFD, [11] FWEID02.LTWSSPFD, [10] FWEID02.LTWDSPFD, [9] FWEID02.IPDUFD, [8] FWEID02.IPSUFD, [7] FWEID02.IPNTFD, [6] FWEID02.IPFSFD, [5] FWEID02.IPSSPFD, [4] FWEID02.IPDSPFD, [3] FWEID02.LTHUFD, [2] FWEID02.LTHNTFD, [1] FWEID02.LTHFSFD, [0] FWEID02.LTHSPFD
0x874C7A00 MFWD
  [26] FWEIS1.MACTHCFS, [25] FWEIS1.IPTHCFS, [24] FWEIS1.LTHTHCFS, [17] FWEIS1.FTEES, [16] FWEIS1.AREES, [9] FWEIS1.L23USES, [8] FWEIS1.L23UEES, [7] FWEIS1.VLANTSES, [6] FWEIS1.VLANTEES, [5] FWEIS1.MACTSES, [4] FWEIS1.MACTEES, [3] FWEIS1.IPTSES, [2] FWEIS1.IPTEES, [1] FWEIS1.LTHTSES, [0] FWEIS1.LTHTEES
0x874C7A04 MFWD
  [26] FWEIE1.MACTHCFE, [25] FWEIE1.IPTHCFE, [24] FWEIE1.LTHTHCFE, [17] FWEIE1.FTEEE, [16] FWEIE1.AREEE, [9] FWEIE1.L23USEE, [8] FWEIE1.L23UEEE, [7] FWEIE1.VLANTSEE, [6] FWEIE1.VLANTEEE, [5] FWEIE1.MACTSEE, [4] FWEIE1.MACTEEE, [3] FWEIE1.IPTSEE, [2] FWEIE1.IPTEEE, [1] FWEIE1.LTHTSEE, [0] FWEIE1.LTHTEEE
0x874C7A08 MFWD
  [26] FWEID1.MACTHCFD, [25] FWEID1.IPTHCFD, [24] FWEID1.LTHTHCFD, [17] FWEID1.FTEED, [16] FWEID1.AREED, [9] FWEID1.L23USED, [8] FWEID1.L23UEED, [7] FWEID1.VLANTSED, [6] FWEID1.VLANTEED, [5] FWEID1.MACTSED, [4] FWEID1.MACTEED, [3] FWEID1.IPTSED, [2] FWEID1.IPTEED, [1] FWEID1.LTHTSED, [0] FWEID1.LTHTEED
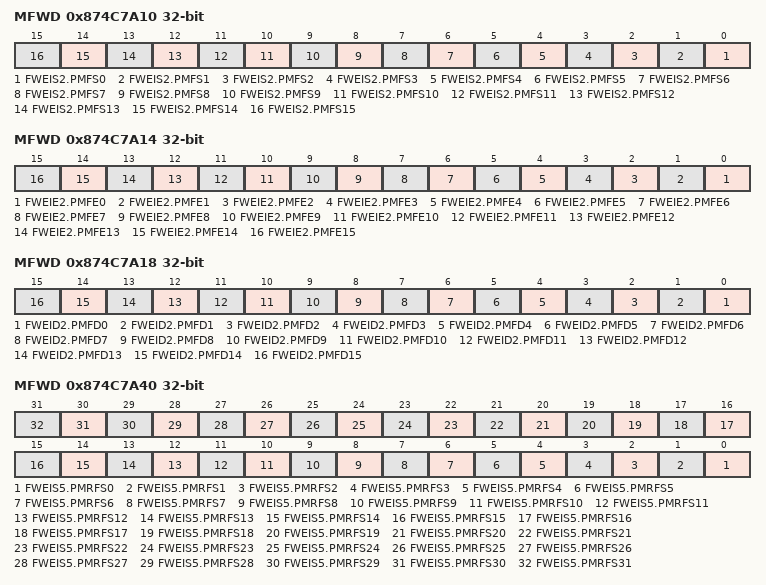
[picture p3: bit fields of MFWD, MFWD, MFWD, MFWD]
0x874C7A10 MFWD
  [n] FWEIS2.PMFS{n} (n=0..15)
0x874C7A14 MFWD
  [n] FWEIE2.PMFE{n} (n=0..15)
0x874C7A18 MFWD
  [n] FWEID2.PMFD{n} (n=0..15)
0x874C7A40 MFWD
  [n] FWEIS5.PMRFS{n} (n=0..31)
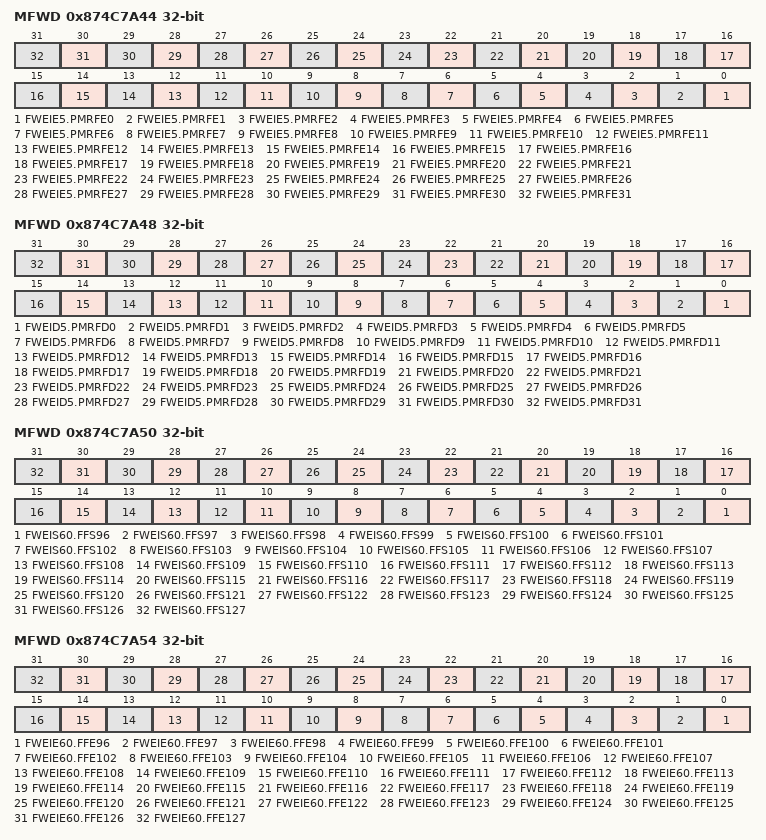
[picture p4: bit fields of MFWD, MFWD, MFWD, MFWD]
0x874C7A44 MFWD
  [n] FWEIE5.PMRFE{n} (n=0..31)
0x874C7A48 MFWD
  [n] FWEID5.PMRFD{n} (n=0..31)
0x874C7A50 MFWD
  [n-96] FWEIS60.FFS{n} (n=96..127)
0x874C7A54 MFWD
  [n-96] FWEIE60.FFE{n} (n=96..127)
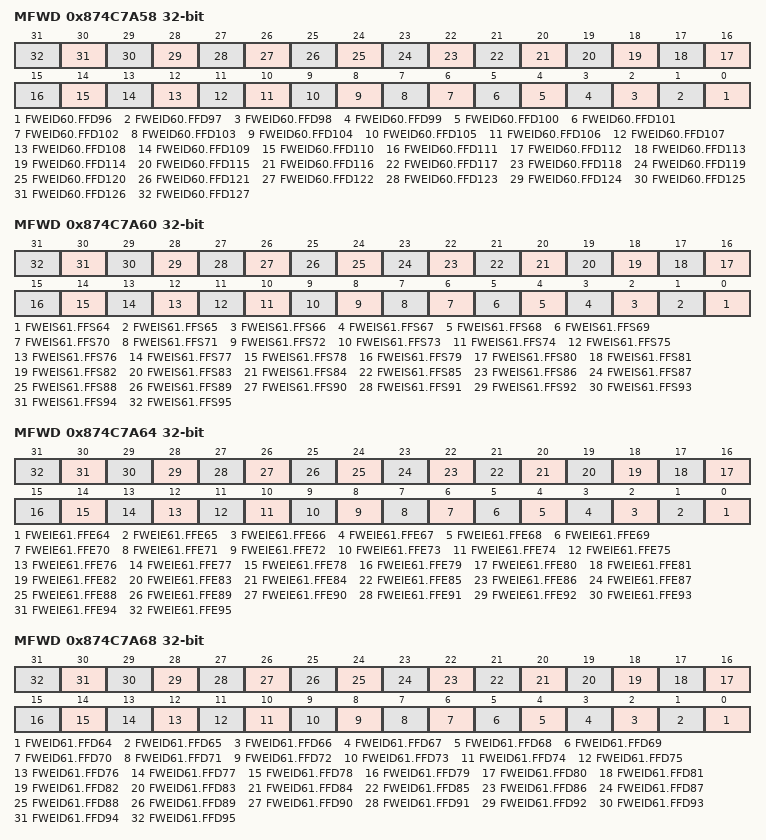
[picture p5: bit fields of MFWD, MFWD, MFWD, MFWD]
0x874C7A58 MFWD
  [n-96] FWEID60.FFD{n} (n=96..127)
0x874C7A60 MFWD
  [n-64] FWEIS61.FFS{n} (n=64..95)
0x874C7A64 MFWD
  [n-64] FWEIE61.FFE{n} (n=64..95)
0x874C7A68 MFWD
  [n-64] FWEID61.FFD{n} (n=64..95)
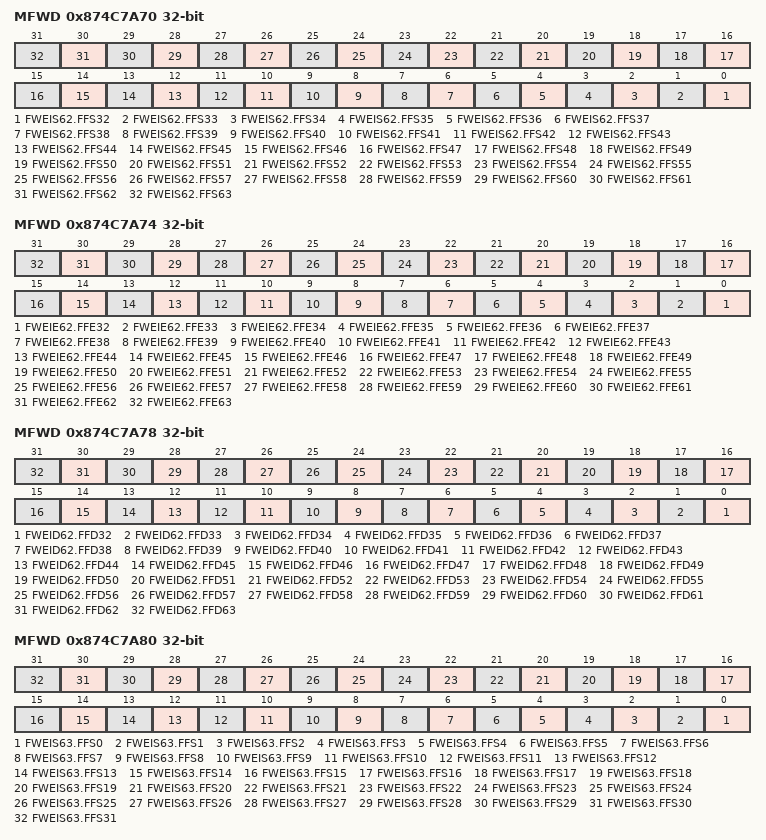
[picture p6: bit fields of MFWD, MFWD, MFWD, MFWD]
0x874C7A70 MFWD
  [n-32] FWEIS62.FFS{n} (n=32..63)
0x874C7A74 MFWD
  [n-32] FWEIE62.FFE{n} (n=32..63)
0x874C7A78 MFWD
  [n-32] FWEID62.FFD{n} (n=32..63)
0x874C7A80 MFWD
  [n] FWEIS63.FFS{n} (n=0..31)
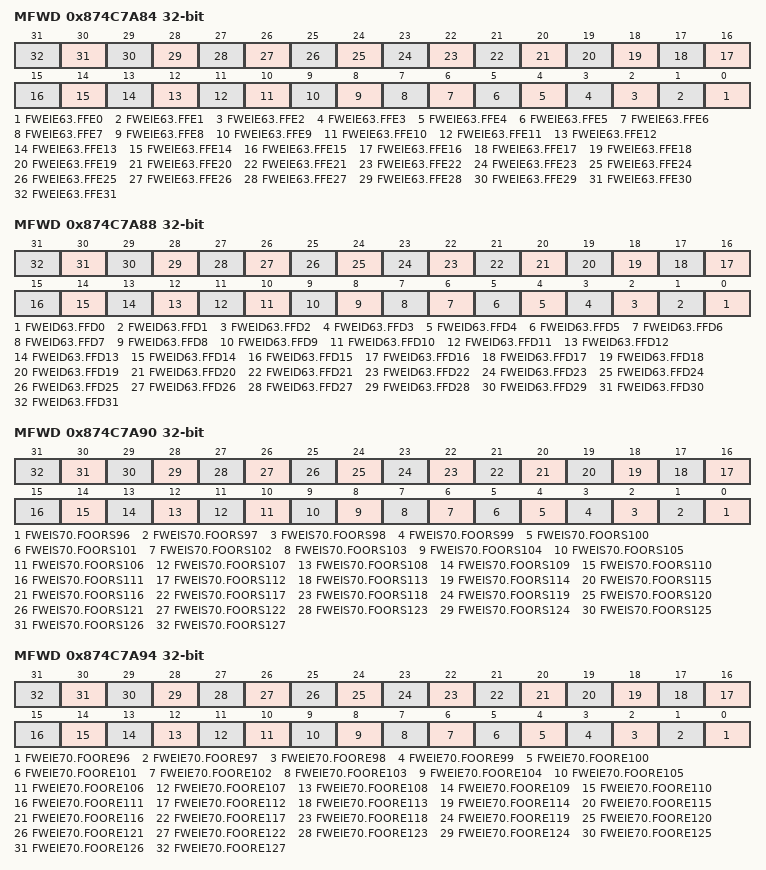
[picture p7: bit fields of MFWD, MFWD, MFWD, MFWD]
0x874C7A84 MFWD
  [n] FWEIE63.FFE{n} (n=0..31)
0x874C7A88 MFWD
  [n] FWEID63.FFD{n} (n=0..31)
0x874C7A90 MFWD
  [n-96] FWEIS70.FOORS{n} (n=96..127)
0x874C7A94 MFWD
  [n-96] FWEIE70.FOORE{n} (n=96..127)
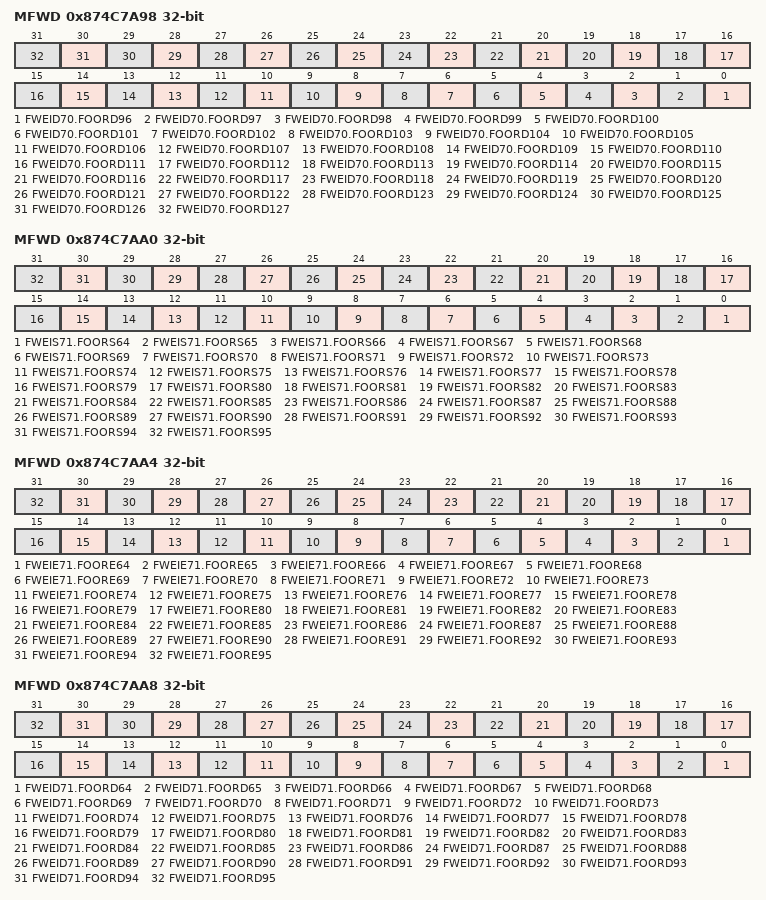
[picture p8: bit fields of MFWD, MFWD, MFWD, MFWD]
0x874C7A98 MFWD
  [n-96] FWEID70.FOORD{n} (n=96..127)
0x874C7AA0 MFWD
  [n-64] FWEIS71.FOORS{n} (n=64..95)
0x874C7AA4 MFWD
  [n-64] FWEIE71.FOORE{n} (n=64..95)
0x874C7AA8 MFWD
  [n-64] FWEID71.FOORD{n} (n=64..95)
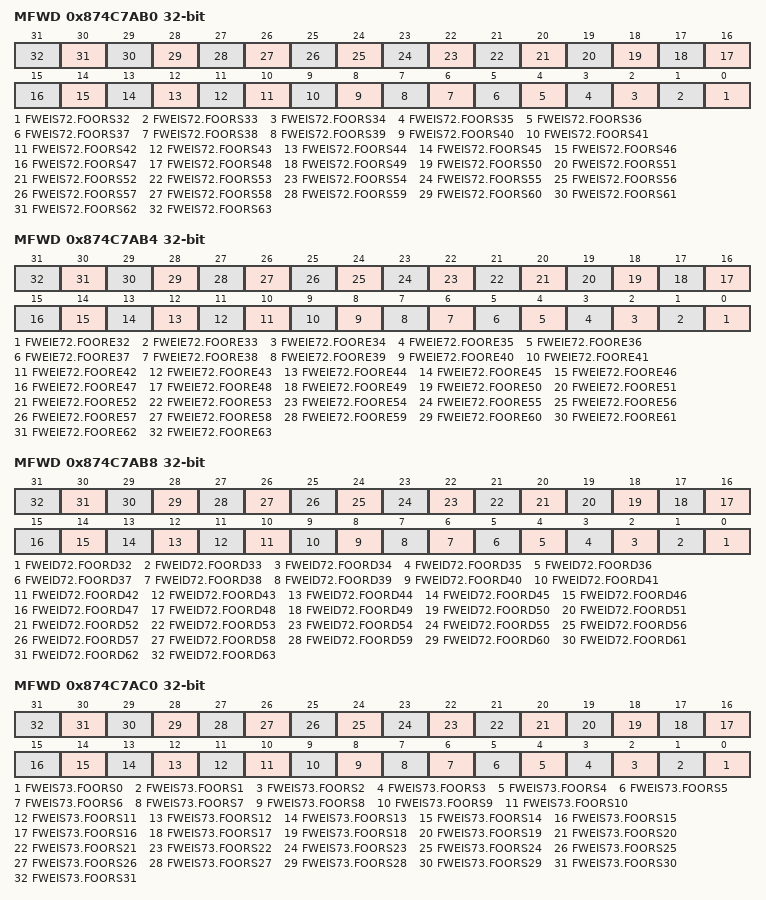
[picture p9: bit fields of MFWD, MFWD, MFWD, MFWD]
0x874C7AB0 MFWD
  [n-32] FWEIS72.FOORS{n} (n=32..63)
0x874C7AB4 MFWD
  [n-32] FWEIE72.FOORE{n} (n=32..63)
0x874C7AB8 MFWD
  [n-32] FWEID72.FOORD{n} (n=32..63)
0x874C7AC0 MFWD
  [n] FWEIS73.FOORS{n} (n=0..31)
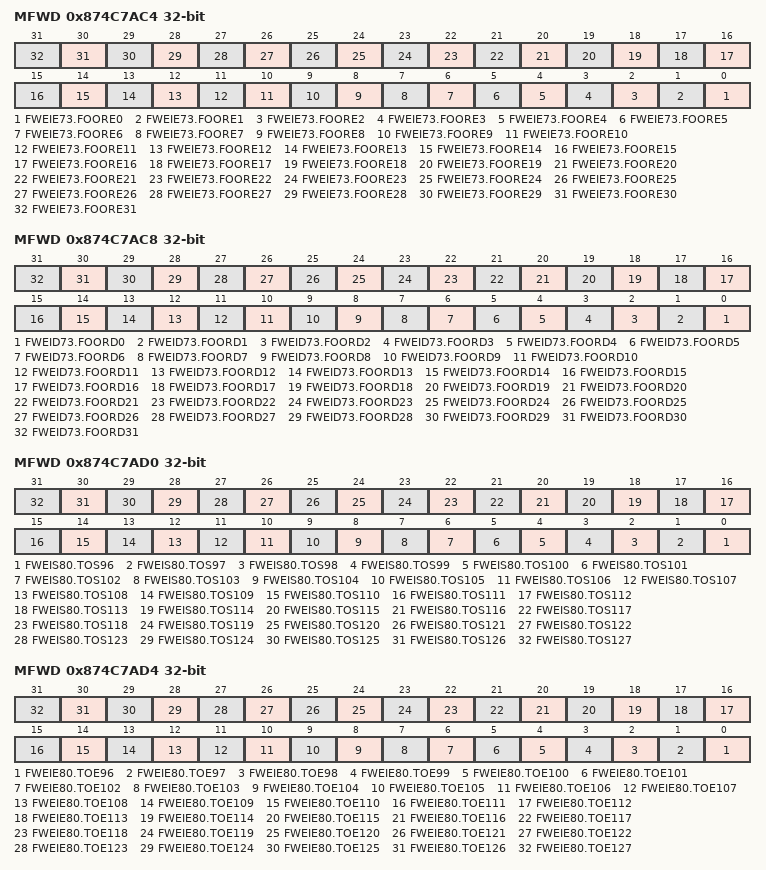
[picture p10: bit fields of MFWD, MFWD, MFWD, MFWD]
0x874C7AC4 MFWD
  [n] FWEIE73.FOORE{n} (n=0..31)
0x874C7AC8 MFWD
  [n] FWEID73.FOORD{n} (n=0..31)
0x874C7AD0 MFWD
  [n-96] FWEIS80.TOS{n} (n=96..127)
0x874C7AD4 MFWD
  [n-96] FWEIE80.TOE{n} (n=96..127)
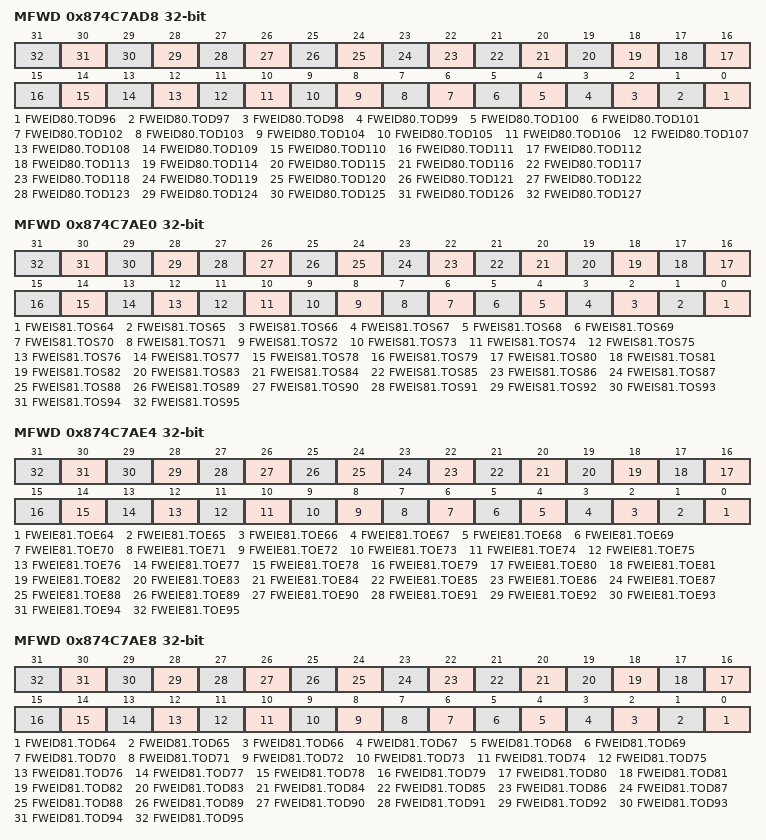
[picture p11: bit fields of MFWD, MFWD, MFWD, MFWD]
0x874C7AD8 MFWD
  [n-96] FWEID80.TOD{n} (n=96..127)
0x874C7AE0 MFWD
  [n-64] FWEIS81.TOS{n} (n=64..95)
0x874C7AE4 MFWD
  [n-64] FWEIE81.TOE{n} (n=64..95)
0x874C7AE8 MFWD
  [n-64] FWEID81.TOD{n} (n=64..95)
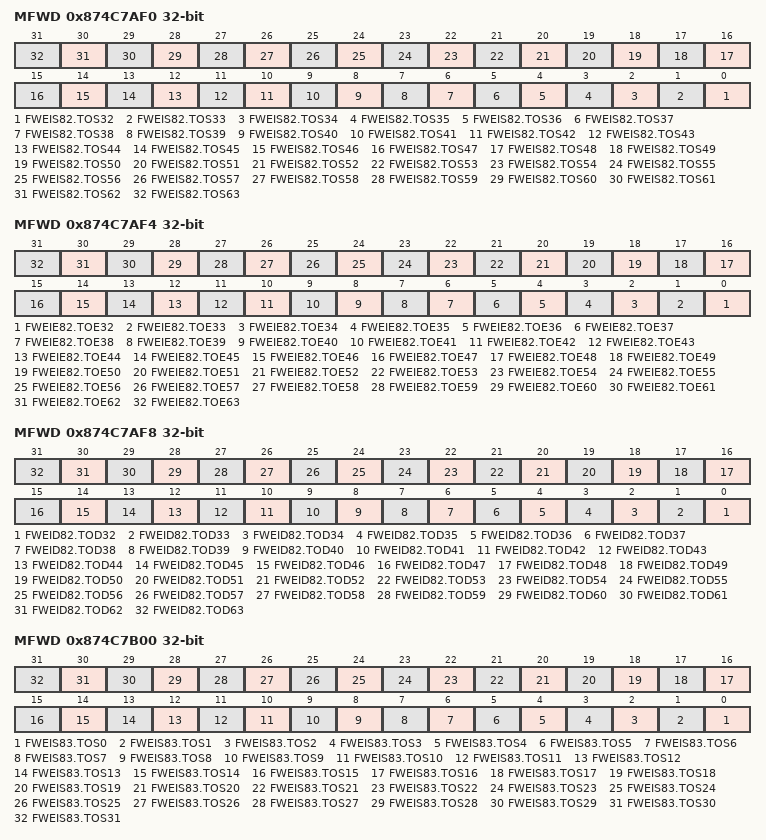
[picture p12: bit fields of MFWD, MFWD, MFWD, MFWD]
0x874C7AF0 MFWD
  [n-32] FWEIS82.TOS{n} (n=32..63)
0x874C7AF4 MFWD
  [n-32] FWEIE82.TOE{n} (n=32..63)
0x874C7AF8 MFWD
  [n-32] FWEID82.TOD{n} (n=32..63)
0x874C7B00 MFWD
  [n] FWEIS83.TOS{n} (n=0..31)
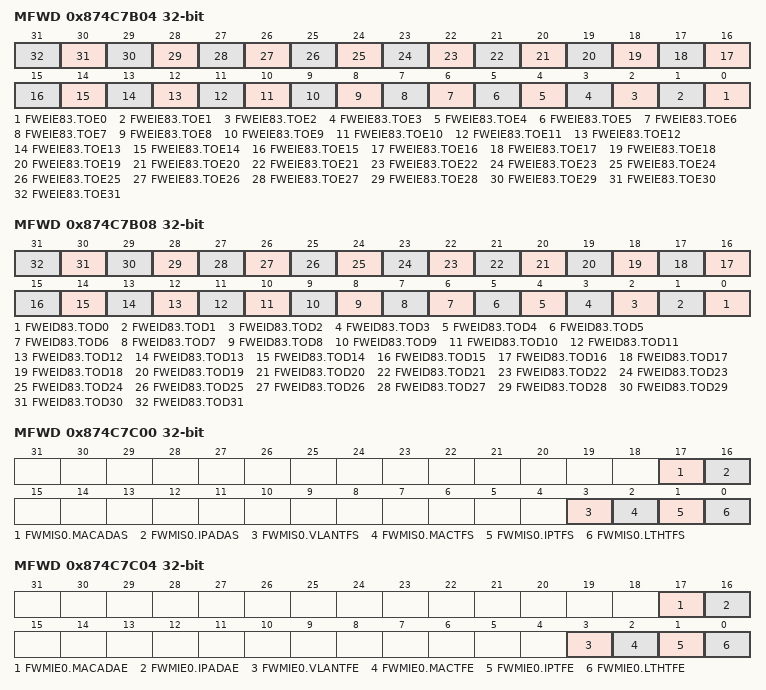
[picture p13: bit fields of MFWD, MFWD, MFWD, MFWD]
0x874C7B04 MFWD
  [n] FWEIE83.TOE{n} (n=0..31)
0x874C7B08 MFWD
  [n] FWEID83.TOD{n} (n=0..31)
0x874C7C00 MFWD
  [17] FWMIS0.MACADAS, [16] FWMIS0.IPADAS, [3] FWMIS0.VLANTFS, [2] FWMIS0.MACTFS, [1] FWMIS0.IPTFS, [0] FWMIS0.LTHTFS
0x874C7C04 MFWD
  [17] FWMIE0.MACADAE, [16] FWMIE0.IPADAE, [3] FWMIE0.VLANTFE, [2] FWMIE0.MACTFE, [1] FWMIE0.IPTFE, [0] FWMIE0.LTHTFE
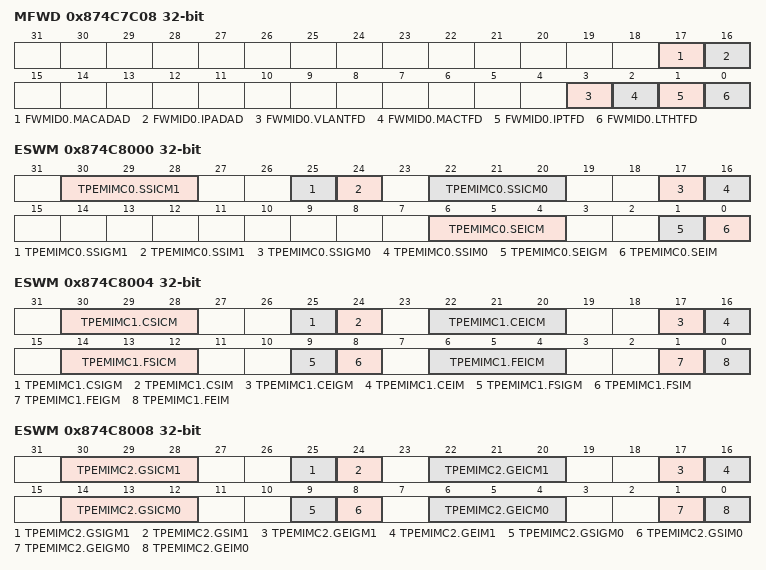
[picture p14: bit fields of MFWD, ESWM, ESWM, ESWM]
0x874C7C08 MFWD
  [17] FWMID0.MACADAD, [16] FWMID0.IPADAD, [3] FWMID0.VLANTFD, [2] FWMID0.MACTFD, [1] FWMID0.IPTFD, [0] FWMID0.LTHTFD
0x874C8000 ESWM
  [30:28] TPEMIMC0.SSICM1, [25] TPEMIMC0.SSIGM1, [24] TPEMIMC0.SSIM1, [22:20] TPEMIMC0.SSICM0, [17] TPEMIMC0.SSIGM0, [16] TPEMIMC0.SSIM0, [6:4] TPEMIMC0.SEICM, [1] TPEMIMC0.SEIGM, [0] TPEMIMC0.SEIM
0x874C8004 ESWM
  [30:28] TPEMIMC1.CSICM, [25] TPEMIMC1.CSIGM, [24] TPEMIMC1.CSIM, [22:20] TPEMIMC1.CEICM, [17] TPEMIMC1.CEIGM, [16] TPEMIMC1.CEIM, [14:12] TPEMIMC1.FSICM, [9] TPEMIMC1.FSIGM, [8] TPEMIMC1.FSIM, [6:4] TPEMIMC1.FEICM, [1] TPEMIMC1.FEIGM, [0] TPEMIMC1.FEIM
0x874C8008 ESWM
  [30:28] TPEMIMC2.GSICM1, [25] TPEMIMC2.GSIGM1, [24] TPEMIMC2.GSIM1, [22:20] TPEMIMC2.GEICM1, [17] TPEMIMC2.GEIGM1, [16] TPEMIMC2.GEIM1, [14:12] TPEMIMC2.GSICM0, [9] TPEMIMC2.GSIGM0, [8] TPEMIMC2.GSIM0, [6:4] TPEMIMC2.GEICM0, [1] TPEMIMC2.GEIGM0, [0] TPEMIMC2.GEIM0
0x874C800C ESWM
  [22:20] TPEMIMC3.RSICM0, [17] TPEMIMC3.RSIGM0, [16] TPEMIMC3.RSIM0, [14:12] TPEMIMC3.ESICM0, [9] TPEMIMC3.ESIGM0, [8] TPEMIMC3.ESIM0, [6:4] TPEMIMC3.EEICM0, [1] TPEMIMC3.EEIGM0, [0] TPEMIMC3.EEIM0
0x874C8010 ESWM
  [22:20] TPEMIMC4.RSICM1, [17] TPEMIMC4.RSIGM1, [16] TPEMIMC4.RSIM1, [14:12] TPEMIMC4.ESICM1, [9] TPEMIMC4.ESIGM1, [8] TPEMIMC4.ESIM1, [6:4] TPEMIMC4.EEICM1, [1] TPEMIMC4.EEIGM1, [0] TPEMIMC4.EEIM1
0x874C8080 ESWM
  [11:9] TPEMIMC60.GTSICM1, [8] TPEMIMC60.GTSIM1, [3:1] TPEMIMC60.GTSICM0, [0] TPEMIMC60.GTSIM0
0x874C8084 ESWM
  [11:9] TPEMIMC61.GTSICM1, [8] TPEMIMC61.GTSIM1, [3:1] TPEMIMC61.GTSICM0, [0] TPEMIMC61.GTSIM0
0x874C8100 ESWM
  [10:8] TPEMIMC70.GDICM1, [2:0] TPEMIMC70.GDICM0
0x874C8104 ESWM
  [10:8] TPEMIMC71.GDICM1, [2:0] TPEMIMC71.GDICM0
0x874C8108 ESWM
  [10:8] TPEMIMC72.GDICM1, [2:0] TPEMIMC72.GDICM0
0x874C810C ESWM
  [10:8] TPEMIMC73.GDICM1, [2:0] TPEMIMC73.GDICM0
0x874C8110 ESWM
  [10:8] TPEMIMC74.GDICM1, [2:0] TPEMIMC74.GDICM0
0x874C8114 ESWM
  [10:8] TPEMIMC75.GDICM1, [2:0] TPEMIMC75.GDICM0
0x874C8118 ESWM
  [10:8] TPEMIMC76.GDICM1, [2:0] TPEMIMC76.GDICM0
0x874C811C ESWM
  [10:8] TPEMIMC77.GDICM1, [2:0] TPEMIMC77.GDICM0
0x874C8120 ESWM
  [10:8] TPEMIMC78.GDICM1, [2:0] TPEMIMC78.GDICM0
0x874C8124 ESWM
  [10:8] TPEMIMC79.GDICM1, [2:0] TPEMIMC79.GDICM0
0x874C8128 ESWM
  [10:8] TPEMIMC710.GDICM1, [2:0] TPEMIMC710.GDICM0
0x874C812C ESWM
  [10:8] TPEMIMC711.GDICM1, [2:0] TPEMIMC711.GDICM0
0x874C8130 ESWM
  [10:8] TPEMIMC712.GDICM1, [2:0] TPEMIMC712.GDICM0
0x874C8134 ESWM
  [10:8] TPEMIMC713.GDICM1, [2:0] TPEMIMC713.GDICM0
0x874C8138 ESWM
  [10:8] TPEMIMC714.GDICM1, [2:0] TPEMIMC714.GDICM0
0x874C813C ESWM
  [10:8] TPEMIMC715.GDICM1, [2:0] TPEMIMC715.GDICM0
0x874C8140 ESWM
  [10:8] TPEMIMC716.GDICM1, [2:0] TPEMIMC716.GDICM0
0x874C8144 ESWM
  [10:8] TPEMIMC717.GDICM1, [2:0] TPEMIMC717.GDICM0
0x874C8148 ESWM
  [10:8] TPEMIMC718.GDICM1, [2:0] TPEMIMC718.GDICM0
0x874C814C ESWM
  [10:8] TPEMIMC719.GDICM1, [2:0] TPEMIMC719.GDICM0
0x874C8150 ESWM
  [10:8] TPEMIMC720.GDICM1, [2:0] TPEMIMC720.GDICM0
0x874C8154 ESWM
  [10:8] TPEMIMC721.GDICM1, [2:0] TPEMIMC721.GDICM0
0x874C8158 ESWM
  [10:8] TPEMIMC722.GDICM1, [2:0] TPEMIMC722.GDICM0
0x874C815C ESWM
  [10:8] TPEMIMC723.GDICM1, [2:0] TPEMIMC723.GDICM0
0x874C8160 ESWM
  [10:8] TPEMIMC724.GDICM1, [2:0] TPEMIMC724.GDICM0
0x874C8164 ESWM
  [10:8] TPEMIMC725.GDICM1, [2:0] TPEMIMC725.GDICM0
0x874C8168 ESWM
  [10:8] TPEMIMC726.GDICM1, [2:0] TPEMIMC726.GDICM0
0x874C816C ESWM
  [10:8] TPEMIMC727.GDICM1, [2:0] TPEMIMC727.GDICM0
0x874C8170 ESWM
  [10:8] TPEMIMC728.GDICM1, [2:0] TPEMIMC728.GDICM0
0x874C8174 ESWM
  [10:8] TPEMIMC729.GDICM1, [2:0] TPEMIMC729.GDICM0
0x874C8178 ESWM
  [10:8] TPEMIMC730.GDICM1, [2:0] TPEMIMC730.GDICM0
0x874C817C ESWM
  [10:8] TPEMIMC731.GDICM1, [2:0] TPEMIMC731.GDICM0
0x874C8180 ESWM
  [10:8] TPEMIMC732.GDICM1, [2:0] TPEMIMC732.GDICM0
0x874C8184 ESWM
  [10:8] TPEMIMC733.GDICM1, [2:0] TPEMIMC733.GDICM0
0x874C8188 ESWM
  [10:8] TPEMIMC734.GDICM1, [2:0] TPEMIMC734.GDICM0
0x874C818C ESWM
  [10:8] TPEMIMC735.GDICM1, [2:0] TPEMIMC735.GDICM0
0x874C8190 ESWM
  [10:8] TPEMIMC736.GDICM1, [2:0] TPEMIMC736.GDICM0
0x874C8194 ESWM
  [10:8] TPEMIMC737.GDICM1, [2:0] TPEMIMC737.GDICM0
0x874C8198 ESWM
  [10:8] TPEMIMC738.GDICM1, [2:0] TPEMIMC738.GDICM0
0x874C819C ESWM
  [10:8] TPEMIMC739.GDICM1, [2:0] TPEMIMC739.GDICM0
0x874C81A0 ESWM
  [10:8] TPEMIMC740.GDICM1, [2:0] TPEMIMC740.GDICM0
0x874C81A4 ESWM
  [10:8] TPEMIMC741.GDICM1, [2:0] TPEMIMC741.GDICM0
0x874C81A8 ESWM
  [10:8] TPEMIMC742.GDICM1, [2:0] TPEMIMC742.GDICM0
0x874C81AC ESWM
  [10:8] TPEMIMC743.GDICM1, [2:0] TPEMIMC743.GDICM0
0x874C81B0 ESWM
  [10:8] TPEMIMC744.GDICM1, [2:0] TPEMIMC744.GDICM0
0x874C81B4 ESWM
  [10:8] TPEMIMC745.GDICM1, [2:0] TPEMIMC745.GDICM0
0x874C81B8 ESWM
  [10:8] TPEMIMC746.GDICM1, [2:0] TPEMIMC746.GDICM0
0x874C81BC ESWM
  [10:8] TPEMIMC747.GDICM1, [2:0] TPEMIMC747.GDICM0
0x874C81C0 ESWM
  [10:8] TPEMIMC748.GDICM1, [2:0] TPEMIMC748.GDICM0
0x874C81C4 ESWM
  [10:8] TPEMIMC749.GDICM1, [2:0] TPEMIMC749.GDICM0
0x874C81C8 ESWM
  [10:8] TPEMIMC750.GDICM1, [2:0] TPEMIMC750.GDICM0
0x874C81CC ESWM
  [10:8] TPEMIMC751.GDICM1, [2:0] TPEMIMC751.GDICM0
0x874C81D0 ESWM
  [10:8] TPEMIMC752.GDICM1, [2:0] TPEMIMC752.GDICM0
0x874C81D4 ESWM
  [10:8] TPEMIMC753.GDICM1, [2:0] TPEMIMC753.GDICM0
0x874C81D8 ESWM
  [10:8] TPEMIMC754.GDICM1, [2:0] TPEMIMC754.GDICM0
0x874C81DC ESWM
  [10:8] TPEMIMC755.GDICM1, [2:0] TPEMIMC755.GDICM0
0x874C81E0 ESWM
  [10:8] TPEMIMC756.GDICM1, [2:0] TPEMIMC756.GDICM0
0x874C81E4 ESWM
  [10:8] TPEMIMC757.GDICM1, [2:0] TPEMIMC757.GDICM0
0x874C81E8 ESWM
  [10:8] TPEMIMC758.GDICM1, [2:0] TPEMIMC758.GDICM0
0x874C81EC ESWM
  [10:8] TPEMIMC759.GDICM1, [2:0] TPEMIMC759.GDICM0
0x874C81F0 ESWM
  [10:8] TPEMIMC760.GDICM1, [2:0] TPEMIMC760.GDICM0
0x874C81F4 ESWM
  [10:8] TPEMIMC761.GDICM1, [2:0] TPEMIMC761.GDICM0
0x874C81F8 ESWM
  [10:8] TPEMIMC762.GDICM1, [2:0] TPEMIMC762.GDICM0
0x874C81FC ESWM
  [10:8] TPEMIMC763.GDICM1, [2:0] TPEMIMC763.GDICM0
0x874C8700 ESWM
  [6] TSIM.EIM2, [5] TSIM.EIM1, [4] TSIM.EIM0, [3] TSIM.GIM1, [2] TSIM.GIM0, [1] TSIM.CIM, [0] TSIM.FWM
0x874C8704 ESWM
  [9] TFIM.FWMISIM0, [n] TFIM.FWEISIM{n} (n=0..8)
0x874C8708 ESWM
  [4] TCIM.CAMISIM1, [3] TCIM.CAMISIM0, [2] TCIM.CAEISIM1, [1] TCIM.CAEISIM0, [0] TCIM.RSSISIM
0x874C8710 ESWM
  [n+2] TGIM0.GWEISIM{n} (n=0..5), [1] TGIM0.GWTSDISIM, [0] TGIM0.GWDISIM
0x874C8720 ESWM
  [4] TEIM0.MMISIM, [3] TEIM0.MEISIM, [2] TEIM0.EAEISIM2, [1] TEIM0.EAEISIM1, [0] TEIM0.EAEISIM0
0x874C8724 ESWM
  [4] TEIM1.MMISIM, [3] TEIM1.MEISIM, [2] TEIM1.EAEISIM2, [1] TEIM1.EAEISIM1, [0] TEIM1.EAEISIM0
0x874C9000 COMA
  [23:21] RIPV.CAIPV, [19:16] RIPV.FBIPV, [15:12] RIPV.EAIPV, [11:8] RIPV.FWIPV, [7:4] RIPV.GWIPV, [3:0] RIPV.TIPV
0x874C9004 COMA
  [0] RRC.RR
0x874C9008 COMA
  [16] RCEC.RCE, [2] RCEC.ACE2, [1] RCEC.ACE1, [0] RCEC.ACE0
0x874C900C COMA
  [16] RCDC.RCD, [2] RCDC.ACD2, [1] RCDC.ACD1, [0] RCDC.ACD0
0x874C9020 COMA
  [25:16] CABPIBWMC0.IBSWMPN, [9:0] CABPIBWMC0.IBUWMPN
0x874C9024 COMA
  [25:16] CABPIBWMC1.IBSWMPN, [9:0] CABPIBWMC1.IBUWMPN
0x874C9028 COMA
  [25:16] CABPIBWMC2.IBSWMPN, [9:0] CABPIBWMC2.IBUWMPN
0x874C902C COMA
  [25:16] CABPIBWMC3.IBSWMPN, [9:0] CABPIBWMC3.IBUWMPN
0x874C9030 COMA
  [25:16] CABPIBWMC4.IBSWMPN, [9:0] CABPIBWMC4.IBUWMPN
0x874C9034 COMA
  [25:16] CABPIBWMC5.IBSWMPN, [9:0] CABPIBWMC5.IBUWMPN
0x874C9038 COMA
  [25:16] CABPIBWMC6.IBSWMPN, [9:0] CABPIBWMC6.IBUWMPN
0x874C903C COMA
  [25:16] CABPIBWMC7.IBSWMPN, [9:0] CABPIBWMC7.IBUWMPN
0x874C9040 COMA
  [25:16] CABPWMLC.WMCL, [9:0] CABPWMLC.WMFL
0x874C9050 COMA
  [25:16] CABPPFLC0.PAL, [9:0] CABPPFLC0.PDL
0x874C9054 COMA
  [25:16] CABPPFLC1.PAL, [9:0] CABPPFLC1.PDL
0x874C9060 COMA
  [25:16] CABPPWMLC0.PWMCL, [9:0] CABPPWMLC0.PWMFL
0x874C9064 COMA
  [25:16] CABPPWMLC1.PWMCL, [9:0] CABPPWMLC1.PWMFL
0x874C9068 COMA
  [25:16] CABPPWMLC2.PWMCL, [9:0] CABPPWMLC2.PWMFL
0x874C90A0 COMA
  [25:16] CABPPPFLC00.PPAL, [9:0] CABPPPFLC00.PPDL
0x874C90A4 COMA
  [25:16] CABPPPFLC01.PPAL, [9:0] CABPPPFLC01.PPDL
0x874C90A8 COMA
  [25:16] CABPPPFLC10.PPAL, [9:0] CABPPPFLC10.PPDL
0x874C90AC COMA
  [25:16] CABPPPFLC11.PPAL, [9:0] CABPPPFLC11.PPDL
0x874C90B0 COMA
  [25:16] CABPPPFLC20.PPAL, [9:0] CABPPPFLC20.PPDL
0x874C90B4 COMA
  [25:16] CABPPPFLC21.PPAL, [9:0] CABPPPFLC21.PPDL
0x874C9100 COMA
  [25:16] CABPULC0.MNNPN, [9:0] CABPULC0.MXNPN
0x874C9104 COMA
  [25:16] CABPULC1.MNNPN, [9:0] CABPULC1.MXNPN
0x874C9108 COMA
  [25:16] CABPULC2.MNNPN, [9:0] CABPULC2.MXNPN
0x874C9140 COMA
  [1] CABPIRM.BPR, [0] CABPIRM.BPIOG
0x874C9144 COMA
  [25:16] CABPPCM.TPC, [9:0] CABPPCM.RPC
0x874C9148 COMA
  [9:0] CABPLCM.LRC
0x874C9180 COMA
  [9:0] CABPCPM0.RPCP
0x874C9184 COMA
  [9:0] CABPCPM1.RPCP
0x874C9188 COMA
  [9:0] CABPCPM2.RPCP
0x874C9200 COMA
  [9:0] CABPMCPM0.RPMCP
0x874C9204 COMA
  [9:0] CABPMCPM1.RPMCP
0x874C9208 COMA
  [9:0] CABPMCPM2.RPMCP
0x874C9300 COMA
  [9:0] CARDNM.RDNRR
0x874C9304 COMA
  [9:0] CARDMNM.RDMNRR
0x874C9310 COMA
  [31:0] CARDCN.RDN
0x874C9400 COMA
  [19:16] CAEIS0.EEIPLN, [10] CAEIS0.WMFLOS, [9] CAEIS0.WMCLOS, [8] CAEIS0.BPOPS, [2] CAEIS0.BPECCES, [1] CAEIS0.DSECCES, [0] CAEIS0.PECCES
0x874C9404 COMA
  [10] CAEIE0.WMFLOE, [9] CAEIE0.WMCLOE, [8] CAEIE0.BPOPE, [2] CAEIE0.BPECCEE, [1] CAEIE0.DSECCEE, [0] CAEIE0.PECCEE
0x874C9408 COMA
  [10] CAEID0.WMFLOD, [9] CAEID0.WMCLOD, [8] CAEID0.BPOPD, [2] CAEID0.BPECCED, [1] CAEID0.DSECCED, [0] CAEID0.PECCED
0x874C9410 COMA
  [18] CAEIS1.PWMFLOS2, [17] CAEIS1.PWMFLOS1, [16] CAEIS1.PWMFLOS0, [2] CAEIS1.PWMCLOS2, [1] CAEIS1.PWMCLOS1, [0] CAEIS1.PWMCLOS0
0x874C9414 COMA
  [18] CAEIE1.PWMFLOE2, [17] CAEIE1.PWMFLOE1, [16] CAEIE1.PWMFLOE0, [2] CAEIE1.PWMCLOE2, [1] CAEIE1.PWMCLOE1, [0] CAEIE1.PWMCLOE0
0x874C9418 COMA
  [18] CAEID1.PWMFLOD2, [17] CAEID1.PWMFLOD1, [16] CAEID1.PWMFLOD0, [2] CAEID1.PWMCLOD2, [1] CAEID1.PWMCLOD1, [0] CAEID1.PWMCLOD0
0x874C9440 COMA
  [1] CAMIS0.PFS1, [0] CAMIS0.PFS0
0x874C9444 COMA
  [1] CAMIE0.PFE1, [0] CAMIE0.PFE0
0x874C9448 COMA
  [1] CAMID0.PFD1, [0] CAMID0.PFD0
0x874C9450 COMA
  [n] CAMIS1.PPFS{n} (n=0..5)
0x874C9454 COMA
  [n] CAMIE1.PPFE{n} (n=0..5)
0x874C9458 COMA
  [n] CAMID1.PPFD{n} (n=0..5)
0x874CA000 ETHA0
  [1:0] EAMC.OPC
0x874CA004 ETHA0
  [1:0] EAMS.OPS
0x874CA010 ETHA0
  [4n+2:4n] EAIRC.IPVR{n} (n=0..7)
0x874CA014 ETHA0
  [n] EATDQSC.TDQSL{n} (n=0..7)
0x874CA018 ETHA0
  [n+16] EATDQC.TDQP{n} (n=0..7), [8] EATDQC.TCTDQD, [n] EATDQC.TDQD{n} (n=0..7)
0x874CA01C ETHA0
  [4n+3:4n] EATDQAC.TDQA{n} (n=0..7)
0x874CA020 ETHA0
  [17:16] EATPEC.AFS, [n] EATPEC.TTQ{n} (n=0..9)
0x874CA040 ETHA0
  [15:0] EATMFSC0.MFS
0x874CA044 ETHA0
  [15:0] EATMFSC1.MFS
0x874CA048 ETHA0
  [15:0] EATMFSC2.MFS
0x874CA04C ETHA0
  [15:0] EATMFSC3.MFS
0x874CA050 ETHA0
  [15:0] EATMFSC4.MFS
0x874CA054 ETHA0
  [15:0] EATMFSC5.MFS
0x874CA058 ETHA0
  [15:0] EATMFSC6.MFS
0x874CA05C ETHA0
  [15:0] EATMFSC7.MFS
0x874CA060 ETHA0
  [9:0] EATDQDC0.DQD
0x874CA064 ETHA0
  [9:0] EATDQDC1.DQD
0x874CA068 ETHA0
  [9:0] EATDQDC2.DQD
0x874CA06C ETHA0
  [9:0] EATDQDC3.DQD
0x874CA070 ETHA0
  [9:0] EATDQDC4.DQD
0x874CA074 ETHA0
  [9:0] EATDQDC5.DQD
0x874CA078 ETHA0
  [9:0] EATDQDC6.DQD
0x874CA07C ETHA0
  [9:0] EATDQDC7.DQD
0x874CA080 ETHA0
  [9:0] EATDQM0.DNQ
0x874CA084 ETHA0
  [9:0] EATDQM1.DNQ
0x874CA088 ETHA0
  [9:0] EATDQM2.DNQ
0x874CA08C ETHA0
  [9:0] EATDQM3.DNQ
0x874CA090 ETHA0
  [9:0] EATDQM4.DNQ
0x874CA094 ETHA0
  [9:0] EATDQM5.DNQ
0x874CA098 ETHA0
  [9:0] EATDQM6.DNQ
0x874CA09C ETHA0
  [9:0] EATDQM7.DNQ
0x874CA0A0 ETHA0
  [9:0] EATDQMLM0.DMLQ
0x874CA0A4 ETHA0
  [9:0] EATDQMLM1.DMLQ
0x874CA0A8 ETHA0
  [9:0] EATDQMLM2.DMLQ
0x874CA0AC ETHA0
  [9:0] EATDQMLM3.DMLQ
0x874CA0B0 ETHA0
  [9:0] EATDQMLM4.DMLQ
0x874CA0B4 ETHA0
  [9:0] EATDQMLM5.DMLQ
0x874CA0B8 ETHA0
  [9:0] EATDQMLM6.DMLQ
0x874CA0BC ETHA0
  [9:0] EATDQMLM7.DMLQ
0x874CA100 ETHA0
  [15:0] EACTQC.CTQD
0x874CA104 ETHA0
  [2:0] EACTDQDC.CTDQD
0x874CA108 ETHA0
  [9:0] EACTDQM.CTQDN
0x874CA10C ETHA0
  [2:0] EACTDQMLM.CTDMLQ
0x874CA130 ETHA0
  [18:16] EAVCC.VEM, [0] EAVCC.VIM
0x874CA134 ETHA0
  [31] EAVTC.STD, [30:28] EAVTC.STP, [27:16] EAVTC.STV, [15] EAVTC.CTD, [14:12] EAVTC.CTP, [11:0] EAVTC.CTV
0x874CA138 ETHA0
  [8] EARTFC.UT, [7] EARTFC.SCRT, [6] EARTFC.SCT, [5] EARTFC.CRT, [4] EARTFC.CT, [3] EARTFC.CSRT, [2] EARTFC.CST, [1] EARTFC.RT, [0] EARTFC.NT
0x874CA200 ETHA0
  [n] EACAEC.CE{n} (n=0..7)
0x874CA204 ETHA0
  [n] EACC.CC{n} (n=0..7)
0x874CA220 ETHA0
  [19:0] EACAIVC0.CIV
0x874CA224 ETHA0
  [19:0] EACAIVC1.CIV
0x874CA228 ETHA0
  [19:0] EACAIVC2.CIV
0x874CA22C ETHA0
  [19:0] EACAIVC3.CIV
0x874CA230 ETHA0
  [19:0] EACAIVC4.CIV
0x874CA234 ETHA0
  [19:0] EACAIVC5.CIV
0x874CA238 ETHA0
  [19:0] EACAIVC6.CIV
0x874CA23C ETHA0
  [19:0] EACAIVC7.CIV
0x874CA240 ETHA0
  [30:0] EACAULC0.CUL
0x874CA244 ETHA0
  [30:0] EACAULC1.CUL
0x874CA248 ETHA0
  [30:0] EACAULC2.CUL
0x874CA24C ETHA0
  [30:0] EACAULC3.CUL
0x874CA250 ETHA0
  [30:0] EACAULC4.CUL
0x874CA254 ETHA0
  [30:0] EACAULC5.CUL
0x874CA258 ETHA0
  [30:0] EACAULC6.CUL
0x874CA25C ETHA0
  [30:0] EACAULC7.CUL
0x874CA260 ETHA0
  [n] EACOEM.CE{n} (n=0..7)
0x874CA280 ETHA0
  [19:0] EACOIVM0.CIV
0x874CA284 ETHA0
  [19:0] EACOIVM1.CIV
0x874CA288 ETHA0
  [19:0] EACOIVM2.CIV
0x874CA28C ETHA0
  [19:0] EACOIVM3.CIV
0x874CA290 ETHA0
  [19:0] EACOIVM4.CIV
0x874CA294 ETHA0
  [19:0] EACOIVM5.CIV
0x874CA298 ETHA0
  [19:0] EACOIVM6.CIV
0x874CA29C ETHA0
  [19:0] EACOIVM7.CIV
0x874CA2A0 ETHA0
  [30:0] EACOULM0.CUL
0x874CA2A4 ETHA0
  [30:0] EACOULM1.CUL
0x874CA2A8 ETHA0
  [30:0] EACOULM2.CUL
0x874CA2AC ETHA0
  [30:0] EACOULM3.CUL
0x874CA2B0 ETHA0
  [30:0] EACOULM4.CUL
0x874CA2B4 ETHA0
  [30:0] EACOULM5.CUL
0x874CA2B8 ETHA0
  [30:0] EACOULM6.CUL
0x874CA2BC ETHA0
  [30:0] EACOULM7.CUL
0x874CA2C0 ETHA0
  [n] EACGSM.CGS{n} (n=0..7)
0x874CA300 ETHA0
  [23:16] EATASC.TASCA, [8] EATASC.TASTS, [2] EATASC.TASCI, [1] EATASC.TASCC, [0] EATASC.TASE
0x874CA304 ETHA0
  [8] EATASIGSC.TASCTIGS, [n] EATASIGSC.TASIGS{n} (n=0..7)
0x874CA320 ETHA0
  [8:0] EATASENC0.TASAEN
0x874CA324 ETHA0
  [8:0] EATASENC1.TASAEN
0x874CA328 ETHA0
  [8:0] EATASENC2.TASAEN
0x874CA32C ETHA0
  [8:0] EATASENC3.TASAEN
0x874CA330 ETHA0
  [8:0] EATASENC4.TASAEN
0x874CA334 ETHA0
  [8:0] EATASENC5.TASAEN
0x874CA338 ETHA0
  [8:0] EATASENC6.TASAEN
0x874CA33C ETHA0
  [8:0] EATASENC7.TASAEN
0x874CA340 ETHA0
  [8:0] EATASCTENC.TASCTAEN
0x874CA360 ETHA0
  [8:0] EATASENM0.TASOEN
0x874CA364 ETHA0
  [8:0] EATASENM1.TASOEN
0x874CA368 ETHA0
  [8:0] EATASENM2.TASOEN
0x874CA36C ETHA0
  [8:0] EATASENM3.TASOEN
0x874CA370 ETHA0
  [8:0] EATASENM4.TASOEN
0x874CA374 ETHA0
  [8:0] EATASENM5.TASOEN
0x874CA378 ETHA0
  [8:0] EATASENM6.TASOEN
0x874CA37C ETHA0
  [8:0] EATASENM7.TASOEN
0x874CA380 ETHA0
  [8:0] EATASCTENM.TASCTOEN
0x874CA3A0 ETHA0
  [31:0] EATASCSTC0.TASACSTP0
0x874CA3A4 ETHA0
  [31:0] EATASCSTC1.TASACSTP1
0x874CA3A8 ETHA0
  [31:0] EATASCSTM0.TASOCSTP0
0x874CA3AC ETHA0
  [31:0] EATASCSTM1.TASOCSTP1
0x874CA3B0 ETHA0
  [31:0] EATASCTC.TASACT
0x874CA3B4 ETHA0
  [31:0] EATASCTM.TASOCT
0x874CA3C0 ETHA0
  [7:0] EATASGL0.TASGAL
0x874CA3C4 ETHA0
  [28] EATASGL1.TASGSL, [27:0] EATASGL1.TASGTL
0x874CA3C8 ETHA0
  [31] EATASGLR.GL
0x874CA3D0 ETHA0
  [7:0] EATASGR.TASGAR
0x874CA3D4 ETHA0
  [31] EATASGRR.GR, [29] EATASGRR.TASREF, [28] EATASGRR.TASGSR, [27:0] EATASGRR.TASGTR
0x874CA3E0 ETHA0
  [15:0] EATASHCC.TASJ
0x874CA3E4 ETHA0
  [1] EATASRIRM.TASRR, [0] EATASRIRM.TASRIOG
0x874CA3E8 ETHA0
  [16] EATASSM.TASSO, [8] EATASSM.TASCTGS, [n] EATASSM.TASGS{n} (n=0..7)
0x874CA400 ETHA0
  [15:0] EAUSMFSECN.USMFSEN
0x874CA404 ETHA0
  [15:0] EATFECN.TFEN
0x874CA408 ETHA0
  [15:0] EAFSECN.FSEN
0x874CA40C ETHA0
  [15:0] EADQOECN.DQOEN
0x874CA410 ETHA0
  [15:0] EADQSECN.DQSEN
0x874CA500 ETHA0
  [24] EAEIS0.TASCTGEES, [n+16] EAEIS0.TASGEES{n} (n=0..7), [n+8] EAEIS0.FSES{n} (n=0..7), [7] EAEIS0.CKSES, [6] EAEIS0.TFES, [5] EAEIS0.USMFSES, [4] EAEIS0.L23UECCES, [3] EAEIS0.DSECCES, [2] EAEIS0.PECCES, [1] EAEIS0.TECCES, [0] EAEIS0.DECCES
0x874CA504 ETHA0
  [24] EAEIE0.TASCTGEEE, [n+16] EAEIE0.TASGEEE{n} (n=0..7), [n+8] EAEIE0.FSEE{n} (n=0..7), [7] EAEIE0.CKSEE, [6] EAEIE0.TFEE, [5] EAEIE0.USMFSEE, [4] EAEIE0.L23UECCEE, [3] EAEIE0.DSECCEE, [2] EAEIE0.PECCEE, [1] EAEIE0.TECCEE, [0] EAEIE0.DECCEE
0x874CA508 ETHA0
  [24] EAEID0.TASCTGEED, [n+16] EAEID0.TASGEED{n} (n=0..7), [n+8] EAEID0.FSED{n} (n=0..7), [7] EAEID0.CKSED, [6] EAEID0.TFED, [5] EAEID0.USMFSED, [4] EAEID0.L23UECCED, [3] EAEID0.DSECCED, [2] EAEID0.PECCED, [1] EAEID0.TECCED, [0] EAEID0.DECCED
0x874CA510 ETHA0
  [24] EAEIS1.TASCTGES, [n+16] EAEIS1.TASGES{n} (n=0..7), [n] EAEIS1.CULES{n} (n=0..7)
0x874CA514 ETHA0
  [24] EAEIE1.TASCTGEE, [n+16] EAEIE1.TASGEE{n} (n=0..7), [n] EAEIE1.CULEE{n} (n=0..7)
0x874CA518 ETHA0
  [24] EAEID1.TASCTGED, [n+16] EAEID1.TASGED{n} (n=0..7), [n] EAEID1.CULED{n} (n=0..7)
0x874CA520 ETHA0
  [n+16] EAEIS2.DQSES{n} (n=0..7), [8] EAEIS2.CTDQOES, [n] EAEIS2.DQOES{n} (n=0..7)
0x874CA524 ETHA0
  [n+16] EAEIE2.DQSEE{n} (n=0..7), [8] EAEIE2.CTDQOEE, [n] EAEIE2.DQOEE{n} (n=0..7)
0x874CA528 ETHA0
  [n+16] EAEID2.DQSED{n} (n=0..7), [8] EAEID2.CTDQOED, [n] EAEID2.DQOED{n} (n=0..7)
0x874CA580 ETHA0
  [n+16] EASCR.DQRSL{n} (n=0..7), [6] EASCR.CRSL, [5] EASCR.EIRSL, [4] EASCR.TASRSL, [3] EASCR.TGRSL, [2] EASCR.MCRSL, [1] EASCR.TRSL, [0] EASCR.MRSL
0x874CB000 RMAC0
  [31:16] MPSM.PRD, [14:13] MPSM.POP, [12:8] MPSM.PRA, [7:3] MPSM.PDA, [2] MPSM.MFF, [0] MPSM.PSME
0x874CB004 RMAC0
  [30:28] MPIC.PSMCT, [26:24] MPIC.PSMHT, [23] MPIC.PSMDP, [22:16] MPIC.PSMCS, [12] MPIC.RPMR, [11] MPIC.RPMT, [10] MPIC.PLSPP, [9] MPIC.PIPP, [8] MPIC.PIP, [6] MPIC.REPP, [5:3] MPIC.LSC, [2:0] MPIC.PIS
0x874CB008 RMAC0
  [1] MPIM.LPIA, [0] MPIM.PLS
0x874CB010 RMAC0
  [31:0] MIOC.MIOC
0x874CB020 RMAC0
  [1] MTFFC.FCM, [0] MTFFC.DPAD
0x874CB024 RMAC0
  [31:27] MTPFC.PFRLV, [26] MTPFC.PFM, [23:16] MTPFC.PFRT, [15:0] MTPFC.PT
0x874CB028 RMAC0
  [17] MTPFC2.MPFR, [16] MTPFC2.PFTTZ, [9] MTPFC2.MPFCFR1, [8] MTPFC2.MPFCFR0, [1:0] MTPFC2.PFCTTZ
0x874CB030 RMAC0
  [7:0] MTPFC30.PFCPG
0x874CB034 RMAC0
  [7:0] MTPFC31.PFCPG
0x874CB050 RMAC0
  [10:8] MTATC0.TRTL, [7:0] MTATC0.TRTP
0x874CB054 RMAC0
  [10:8] MTATC1.TRTL, [7:0] MTATC1.TRTP
0x874CB060 RMAC0
  [0] MTIM.TS
0x874CB080 RMAC0
  [23:16] MRGC.PFCRC, [4] MRGC.RFCFE, [3] MRGC.MPDE, [2] MRGC.PFRTZ, [1] MRGC.PFRC, [0] MRGC.RCPT
0x874CB084 RMAC0
  [15:0] MRMAC0.MAU
0x874CB088 RMAC0
  [31:0] MRMAC1.MAL
0x874CB08C RMAC0
  [26] MRAFC.MSAREP, [25] MRAFC.NSAREP, [24] MRAFC.SDSFREP, [23] MRAFC.NDAREP, [22] MRAFC.BCACP, [21] MRAFC.MCACP, [20] MRAFC.BSTENP, [19] MRAFC.MSTENP, [18] MRAFC.BCENP, [17] MRAFC.MCENP, [16] MRAFC.UCENP, [10] MRAFC.MSAREE, [9] MRAFC.NSAREE, [8] MRAFC.SDSFREE, [7] MRAFC.NDAREE, [6] MRAFC.BCACE, [5] MRAFC.MCACE, [4] MRAFC.BSTENE, [3] MRAFC.MSTENE, [2] MRAFC.BCENE, [1] MRAFC.MCENE, [0] MRAFC.UCENE
0x874CB090 RMAC0
  [31:16] MRSCE.CBFE, [15:0] MRSCE.CMFE
0x874CB094 RMAC0
  [31:16] MRSCP.CBFP, [15:0] MRSCP.CMFP
0x874CB098 RMAC0
  [17] MRSCC.BSCCP, [16] MRSCC.MSCCP, [1] MRSCC.BSCCE, [0] MRSCC.MSCCE
0x874CB09C RMAC0
  [31:16] MRFSCE.EMNS, [15:0] MRFSCE.EMXS
0x874CB0A0 RMAC0
  [31:16] MRFSCP.PMNS, [15:0] MRFSCP.PMXS
0x874CB0A4 RMAC0
  [28] MTRC.DTN, [27] MTRC.TCTSP, [26] MTRC.TCTSE, [25] MTRC.TRDDP, [24] MTRC.TRDDE, [1] MTRC.TRHFME1, [0] MTRC.TRHFME0
0x874CB0AC RMAC0
  [23:16] MRPFM.PFCTCA, [0] MRPFM.PTCA
0x874CB100 RMAC0
  [17] MPFC0.TEF1, [16] MPFC0.TEF0, [15:8] MPFC0.PFBV, [7:0] MPFC0.PFBN
0x874CB104 RMAC0
  [17] MPFC1.TEF1, [16] MPFC1.TEF0, [15:8] MPFC1.PFBV, [7:0] MPFC1.PFBN
0x874CB108 RMAC0
  [17] MPFC2.TEF1, [16] MPFC2.TEF0, [15:8] MPFC2.PFBV, [7:0] MPFC2.PFBN
0x874CB10C RMAC0
  [17] MPFC3.TEF1, [16] MPFC3.TEF0, [15:8] MPFC3.PFBV, [7:0] MPFC3.PFBN
0x874CB110 RMAC0
  [17] MPFC4.TEF1, [16] MPFC4.TEF0, [15:8] MPFC4.PFBV, [7:0] MPFC4.PFBN
0x874CB114 RMAC0
  [17] MPFC5.TEF1, [16] MPFC5.TEF0, [15:8] MPFC5.PFBV, [7:0] MPFC5.PFBN
0x874CB118 RMAC0
  [17] MPFC6.TEF1, [16] MPFC6.TEF0, [15:8] MPFC6.PFBV, [7:0] MPFC6.PFBN
0x874CB11C RMAC0
  [17] MPFC7.TEF1, [16] MPFC7.TEF0, [15:8] MPFC7.PFBV, [7:0] MPFC7.PFBN
0x874CB120 RMAC0
  [17] MPFC8.TEF1, [16] MPFC8.TEF0, [15:8] MPFC8.PFBV, [7:0] MPFC8.PFBN
0x874CB124 RMAC0
  [17] MPFC9.TEF1, [16] MPFC9.TEF0, [15:8] MPFC9.PFBV, [7:0] MPFC9.PFBN
0x874CB128 RMAC0
  [17] MPFC10.TEF1, [16] MPFC10.TEF0, [15:8] MPFC10.PFBV, [7:0] MPFC10.PFBN
0x874CB12C RMAC0
  [17] MPFC11.TEF1, [16] MPFC11.TEF0, [15:8] MPFC11.PFBV, [7:0] MPFC11.PFBN
0x874CB130 RMAC0
  [17] MPFC12.TEF1, [16] MPFC12.TEF0, [15:8] MPFC12.PFBV, [7:0] MPFC12.PFBN
0x874CB134 RMAC0
  [17] MPFC13.TEF1, [16] MPFC13.TEF0, [15:8] MPFC13.PFBV, [7:0] MPFC13.PFBN
0x874CB138 RMAC0
  [17] MPFC14.TEF1, [16] MPFC14.TEF0, [15:8] MPFC14.PFBV, [7:0] MPFC14.PFBN
0x874CB13C RMAC0
  [17] MPFC15.TEF1, [16] MPFC15.TEF0, [15:8] MPFC15.PFBV, [7:0] MPFC15.PFBN
0x874CB180 RMAC0
  [16] MLVC.PLV, [8] MLVC.PASE, [6:0] MLVC.LVT
0x874CB184 RMAC0
  [0] MEEEC.LPITR
0x874CB188 RMAC0
  [16] MLBC.PLBME, [0] MLBC.LBME
0x874CB190 RMAC0
  [1] MXGMIIC.LFS_TXIDLE, [0] MXGMIIC.LFS_TXRFS
0x874CB194 RMAC0
  [17] MPCH.RPHCRCD, [16] MPCH.RXPCH_TSM, [11] MPCH.CTRIOD, [10] MPCH.IETRIOD, [9] MPCH.CTPTE, [8] MPCH.IETPTE, [7:4] MPCH.TXPCH_PID, [3:2] MPCH.TXPCH_ETYPE, [0] MPCH.TXPCH_M
0x874CB19C RMAC0
  [31:16] MANM.TX_AN_MES, [15:0] MANM.RX_AN_MES
0x874CB200 RMAC0
  [29] MEIS.FOES, [28] MEIS.FUES, [27] MEIS.FFS, [26] MEIS.RPOOMS, [25] MEIS.FRCES, [24] MEIS.CFCES, [23] MEIS.FFMES, [22] MEIS.FCMCES, [21] MEIS.PNAES, [20] MEIS.PDES, [13] MEIS.CTLES1, [12] MEIS.CTLES0, [11] MEIS.RPCRES, [10] MEIS.RPOES, [9] MEIS.REOES, [8] MEIS.FCES, [7] MEIS.BFES, [6] MEIS.TBCIS, [5] MEIS.TCES, [4] MEIS.FCDS, [3] MEIS.PFRROS, [2] MEIS.PRES, [1] MEIS.TIES, [0] MEIS.TSLS
0x874CB204 RMAC0
  [29] MEIE.FOEE, [28] MEIE.FUEE, [27] MEIE.FFE, [26] MEIE.RPOOME, [25] MEIE.FRCEE, [24] MEIE.CFCEE, [23] MEIE.FFMEE, [22] MEIE.FCMCEE, [21] MEIE.PNAEE, [20] MEIE.PDEE, [13] MEIE.CTLEE1, [12] MEIE.CTLEE0, [11] MEIE.RPCREE, [10] MEIE.RPOEE, [9] MEIE.REOEE, [8] MEIE.FCEE, [7] MEIE.BFEE, [6] MEIE.TBCIE, [5] MEIE.TCEE, [4] MEIE.FCDE, [3] MEIE.PFRROE, [2] MEIE.PMSEE, [1] MEIE.TIEE, [0] MEIE.TSLE
0x874CB208 RMAC0
  [29] MEID.FOED, [28] MEID.FUED, [27] MEID.FFD, [26] MEID.RPOOMD, [25] MEID.FRCED, [24] MEID.CFCED, [23] MEID.FFMED, [22] MEID.FCMCED, [21] MEID.PNAED, [20] MEID.PDED, [13] MEID.CTLED1, [12] MEID.CTLED0, [11] MEID.RPCRED, [10] MEID.RPOED, [9] MEID.REOED, [8] MEID.FCED, [7] MEID.BFED, [6] MEID.TBCID, [5] MEID.TCED, [4] MEID.FCDD, [3] MEID.PFRROD, [2] MEID.PRED, [1] MEID.TIED, [0] MEID.TSLD
0x874CB210 RMAC0
  [12] MMIS0.XLISDS, [11] MMIS0.XRFSDS, [10] MMIS0.XLFSDS, [9] MMIS0.XLFES, [8] MMIS0.XLFDS, [6] MMIS0.ANDETS, [4] MMIS0.VFRS, [3] MMIS0.LVFS, [2] MMIS0.LVSS, [1] MMIS0.PIDS, [0] MMIS0.PLSCS
0x874CB214 RMAC0
  [12] MMIE0.XLISDE, [11] MMIE0.XRFSDE, [10] MMIE0.XLFSDE, [9] MMIE0.XLFEE, [8] MMIE0.XLFDE, [6] MMIE0.ANDETE, [4] MMIE0.VFRE, [3] MMIE0.LVFE, [2] MMIE0.LVSE, [1] MMIE0.PIDE, [0] MMIE0.PLSCE
0x874CB218 RMAC0
  [12] MMID0.XLISDD, [11] MMID0.XRFSDD, [10] MMID0.XLFSDD, [9] MMID0.XLFED, [8] MMID0.XLFDD, [6] MMID0.ANDETD, [4] MMID0.VFRD, [3] MMID0.LVFD, [2] MMID0.LVSD, [1] MMID0.PIDD, [0] MMID0.PLSCD
0x874CB220 RMAC0
  [3] MMIS1.PPRACS, [2] MMIS1.PAACS, [1] MMIS1.PWACS, [0] MMIS1.PRACS
0x874CB224 RMAC0
  [3] MMIE1.PPRACE, [2] MMIE1.PAACE, [1] MMIE1.PWACE, [0] MMIE1.PRACE
0x874CB228 RMAC0
  [3] MMID1.PPRACD, [2] MMID1.PAACD, [1] MMID1.PWACD, [0] MMID1.PRACD
0x874CB230 RMAC0
  [2] MMIS2.LPIDIS, [1] MMIS2.LPIAIS, [0] MMIS2.MPDIS
0x874CB234 RMAC0
  [2] MMIE2.LPIDIE, [1] MMIE2.LPIAIE, [0] MMIE2.MPDIE
0x874CB238 RMAC0
  [2] MMID2.LPIDID, [1] MMID2.LPIAID, [0] MMID2.MPDID
0x874CB300 RMAC0
  [15:0] MMPFTCT.MPFTC
0x874CB304 RMAC0
  [15:0] MAPFTCT.APFTC
0x874CB308 RMAC0
  [15:0] MPFRCT.PFRC
0x874CB30C RMAC0
  [15:0] MFCICT.FCIC
0x874CB310 RMAC0
  [15:0] MEEECT.EEERC
0x874CB320 RMAC0
  [15:0] MMPCFTCT0.MPCFCTC
0x874CB324 RMAC0
  [15:0] MMPCFTCT1.MPCFCTC
0x874CB330 RMAC0
  [15:0] MAPCFTCT0.APCFCTC
0x874CB334 RMAC0
  [15:0] MAPCFTCT1.APCFCTC
0x874CB340 RMAC0
  [15:0] MPCFRCT0.PCFCRC
0x874CB344 RMAC0
  [15:0] MPCFRCT1.PCFCRC
0x874CB348 RMAC0
  [15:0] MPCFRCT2.PCFCRC
0x874CB34C RMAC0
  [15:0] MPCFRCT3.PCFCRC
0x874CB350 RMAC0
  [15:0] MPCFRCT4.PCFCRC
0x874CB354 RMAC0
  [15:0] MPCFRCT5.PCFCRC
0x874CB358 RMAC0
  [15:0] MPCFRCT6.PCFCRC
0x874CB35C RMAC0
  [15:0] MPCFRCT7.PCFCRC
0x874CB360 RMAC0
  [31:0] MROVFC.ROVFC
0x874CB364 RMAC0
  [15:0] MRHCRCEC.RHCRCEC
0x874CB408 RMAC0
  [31:0] MRGFCE.RGFNE
0x874CB40C RMAC0
  [31:0] MRGFCP.RGFNP
0x874CB410 RMAC0
  [31:0] MRBFC.RBFN
0x874CB414 RMAC0
  [31:0] MRMFC.RMFN
0x874CB418 RMAC0
  [31:0] MRUFC.RUFN
0x874CB41C RMAC0
  [15:0] MRPEFC.RPEFN
0x874CB420 RMAC0
  [15:0] MRNEFC.RNEFN
0x874CB424 RMAC0
  [31:0] MRFMEFC.RFMEFN
0x874CB428 RMAC0
  [15:0] MRFFMEFC.RFFMEFN
0x874CB42C RMAC0
  [15:0] MRCFCEFC.RCFCEFN
0x874CB430 RMAC0
  [15:0] MRFCEFC.RFCEFN
0x874CB434 RMAC0
  [15:0] MRRCFEFC.RRCFEFN
0x874CB438 RMAC0
  [31:0] MRFC.RFN
0x874CB43C RMAC0
  [31:0] MRGUEFC.RUEFN
0x874CB440 RMAC0
  [31:0] MRBUEFC.RUEFN
0x874CB444 RMAC0
  [31:0] MRGOEFC.RGOEFN
0x874CB448 RMAC0
  [31:0] MRBOEFC.RBOEFN
0x874CB44C RMAC0
  [31:0] MRXBCEU.RBNEU
0x874CB450 RMAC0
  [31:0] MRXBCEL.RBNEL
0x874CB454 RMAC0
  [31:0] MRXBCPU.RBNPU
0x874CB458 RMAC0
  [31:0] MRXBCPL.RBNPL
0x874CB508 RMAC0
  [31:0] MTGFCE.TGFNE
0x874CB50C RMAC0
  [31:0] MTGFCP.TGFNP
0x874CB510 RMAC0
  [31:0] MTBFC.TBFN
0x874CB514 RMAC0
  [31:0] MTMFC.TMFN
0x874CB518 RMAC0
  [31:0] MTUFC.TUFN
0x874CB51C RMAC0
  [15:0] MTEFC.TEFN
0x874CB520 RMAC0
  [31:0] MTXBCEU.TBNEU
0x874CB524 RMAC0
  [31:0] MTXBCEL.TBNEL
0x874CB528 RMAC0
  [31:0] MTXBCPU.TBNPU
0x874CB52C RMAC0
  [31:0] MTXBCPL.TBNPL
0x874CC000 ETHA1
  [1:0] EAMC.OPC
0x874CC004 ETHA1
  [1:0] EAMS.OPS
0x874CC010 ETHA1
  [4n+2:4n] EAIRC.IPVR{n} (n=0..7)
0x874CC014 ETHA1
  [n] EATDQSC.TDQSL{n} (n=0..7)
0x874CC018 ETHA1
  [n+16] EATDQC.TDQP{n} (n=0..7), [8] EATDQC.TCTDQD, [n] EATDQC.TDQD{n} (n=0..7)
0x874CC01C ETHA1
  [4n+3:4n] EATDQAC.TDQA{n} (n=0..7)
0x874CC020 ETHA1
  [17:16] EATPEC.AFS, [n] EATPEC.TTQ{n} (n=0..9)
0x874CC040 ETHA1
  [15:0] EATMFSC0.MFS
0x874CC044 ETHA1
  [15:0] EATMFSC1.MFS
0x874CC048 ETHA1
  [15:0] EATMFSC2.MFS
0x874CC04C ETHA1
  [15:0] EATMFSC3.MFS
0x874CC050 ETHA1
  [15:0] EATMFSC4.MFS
0x874CC054 ETHA1
  [15:0] EATMFSC5.MFS
0x874CC058 ETHA1
  [15:0] EATMFSC6.MFS
0x874CC05C ETHA1
  [15:0] EATMFSC7.MFS
0x874CC060 ETHA1
  [9:0] EATDQDC0.DQD
0x874CC064 ETHA1
  [9:0] EATDQDC1.DQD
0x874CC068 ETHA1
  [9:0] EATDQDC2.DQD
0x874CC06C ETHA1
  [9:0] EATDQDC3.DQD
0x874CC070 ETHA1
  [9:0] EATDQDC4.DQD
0x874CC074 ETHA1
  [9:0] EATDQDC5.DQD
0x874CC078 ETHA1
  [9:0] EATDQDC6.DQD
0x874CC07C ETHA1
  [9:0] EATDQDC7.DQD
0x874CC080 ETHA1
  [9:0] EATDQM0.DNQ
0x874CC084 ETHA1
  [9:0] EATDQM1.DNQ
0x874CC088 ETHA1
  [9:0] EATDQM2.DNQ
0x874CC08C ETHA1
  [9:0] EATDQM3.DNQ
0x874CC090 ETHA1
  [9:0] EATDQM4.DNQ
0x874CC094 ETHA1
  [9:0] EATDQM5.DNQ
0x874CC098 ETHA1
  [9:0] EATDQM6.DNQ
0x874CC09C ETHA1
  [9:0] EATDQM7.DNQ
0x874CC0A0 ETHA1
  [9:0] EATDQMLM0.DMLQ
0x874CC0A4 ETHA1
  [9:0] EATDQMLM1.DMLQ
0x874CC0A8 ETHA1
  [9:0] EATDQMLM2.DMLQ
0x874CC0AC ETHA1
  [9:0] EATDQMLM3.DMLQ
0x874CC0B0 ETHA1
  [9:0] EATDQMLM4.DMLQ
0x874CC0B4 ETHA1
  [9:0] EATDQMLM5.DMLQ
0x874CC0B8 ETHA1
  [9:0] EATDQMLM6.DMLQ
0x874CC0BC ETHA1
  [9:0] EATDQMLM7.DMLQ
0x874CC100 ETHA1
  [15:0] EACTQC.CTQD
0x874CC104 ETHA1
  [2:0] EACTDQDC.CTDQD
0x874CC108 ETHA1
  [9:0] EACTDQM.CTQDN
0x874CC10C ETHA1
  [2:0] EACTDQMLM.CTDMLQ
0x874CC130 ETHA1
  [18:16] EAVCC.VEM, [0] EAVCC.VIM
0x874CC134 ETHA1
  [31] EAVTC.STD, [30:28] EAVTC.STP, [27:16] EAVTC.STV, [15] EAVTC.CTD, [14:12] EAVTC.CTP, [11:0] EAVTC.CTV
0x874CC138 ETHA1
  [8] EARTFC.UT, [7] EARTFC.SCRT, [6] EARTFC.SCT, [5] EARTFC.CRT, [4] EARTFC.CT, [3] EARTFC.CSRT, [2] EARTFC.CST, [1] EARTFC.RT, [0] EARTFC.NT
0x874CC200 ETHA1
  [n] EACAEC.CE{n} (n=0..7)
0x874CC204 ETHA1
  [n] EACC.CC{n} (n=0..7)
0x874CC220 ETHA1
  [19:0] EACAIVC0.CIV
0x874CC224 ETHA1
  [19:0] EACAIVC1.CIV
0x874CC228 ETHA1
  [19:0] EACAIVC2.CIV
0x874CC22C ETHA1
  [19:0] EACAIVC3.CIV
0x874CC230 ETHA1
  [19:0] EACAIVC4.CIV
0x874CC234 ETHA1
  [19:0] EACAIVC5.CIV
0x874CC238 ETHA1
  [19:0] EACAIVC6.CIV
0x874CC23C ETHA1
  [19:0] EACAIVC7.CIV
0x874CC240 ETHA1
  [30:0] EACAULC0.CUL
0x874CC244 ETHA1
  [30:0] EACAULC1.CUL
0x874CC248 ETHA1
  [30:0] EACAULC2.CUL
0x874CC24C ETHA1
  [30:0] EACAULC3.CUL
0x874CC250 ETHA1
  [30:0] EACAULC4.CUL
0x874CC254 ETHA1
  [30:0] EACAULC5.CUL
0x874CC258 ETHA1
  [30:0] EACAULC6.CUL
0x874CC25C ETHA1
  [30:0] EACAULC7.CUL
0x874CC260 ETHA1
  [n] EACOEM.CE{n} (n=0..7)
0x874CC280 ETHA1
  [19:0] EACOIVM0.CIV
0x874CC284 ETHA1
  [19:0] EACOIVM1.CIV
0x874CC288 ETHA1
  [19:0] EACOIVM2.CIV
0x874CC28C ETHA1
  [19:0] EACOIVM3.CIV
0x874CC290 ETHA1
  [19:0] EACOIVM4.CIV
0x874CC294 ETHA1
  [19:0] EACOIVM5.CIV
0x874CC298 ETHA1
  [19:0] EACOIVM6.CIV
0x874CC29C ETHA1
  [19:0] EACOIVM7.CIV
0x874CC2A0 ETHA1
  [30:0] EACOULM0.CUL
0x874CC2A4 ETHA1
  [30:0] EACOULM1.CUL
0x874CC2A8 ETHA1
  [30:0] EACOULM2.CUL
0x874CC2AC ETHA1
  [30:0] EACOULM3.CUL
0x874CC2B0 ETHA1
  [30:0] EACOULM4.CUL
0x874CC2B4 ETHA1
  [30:0] EACOULM5.CUL
0x874CC2B8 ETHA1
  [30:0] EACOULM6.CUL
0x874CC2BC ETHA1
  [30:0] EACOULM7.CUL
0x874CC2C0 ETHA1
  [n] EACGSM.CGS{n} (n=0..7)
0x874CC300 ETHA1
  [23:16] EATASC.TASCA, [8] EATASC.TASTS, [2] EATASC.TASCI, [1] EATASC.TASCC, [0] EATASC.TASE
0x874CC304 ETHA1
  [8] EATASIGSC.TASCTIGS, [n] EATASIGSC.TASIGS{n} (n=0..7)
0x874CC320 ETHA1
  [8:0] EATASENC0.TASAEN
0x874CC324 ETHA1
  [8:0] EATASENC1.TASAEN
0x874CC328 ETHA1
  [8:0] EATASENC2.TASAEN
0x874CC32C ETHA1
  [8:0] EATASENC3.TASAEN
0x874CC330 ETHA1
  [8:0] EATASENC4.TASAEN
0x874CC334 ETHA1
  [8:0] EATASENC5.TASAEN
0x874CC338 ETHA1
  [8:0] EATASENC6.TASAEN
0x874CC33C ETHA1
  [8:0] EATASENC7.TASAEN
0x874CC340 ETHA1
  [8:0] EATASCTENC.TASCTAEN
0x874CC360 ETHA1
  [8:0] EATASENM0.TASOEN
0x874CC364 ETHA1
  [8:0] EATASENM1.TASOEN
0x874CC368 ETHA1
  [8:0] EATASENM2.TASOEN
0x874CC36C ETHA1
  [8:0] EATASENM3.TASOEN
0x874CC370 ETHA1
  [8:0] EATASENM4.TASOEN
0x874CC374 ETHA1
  [8:0] EATASENM5.TASOEN
0x874CC378 ETHA1
  [8:0] EATASENM6.TASOEN
0x874CC37C ETHA1
  [8:0] EATASENM7.TASOEN
0x874CC380 ETHA1
  [8:0] EATASCTENM.TASCTOEN
0x874CC3A0 ETHA1
  [31:0] EATASCSTC0.TASACSTP0
0x874CC3A4 ETHA1
  [31:0] EATASCSTC1.TASACSTP1
0x874CC3A8 ETHA1
  [31:0] EATASCSTM0.TASOCSTP0
0x874CC3AC ETHA1
  [31:0] EATASCSTM1.TASOCSTP1
0x874CC3B0 ETHA1
  [31:0] EATASCTC.TASACT
0x874CC3B4 ETHA1
  [31:0] EATASCTM.TASOCT
0x874CC3C0 ETHA1
  [7:0] EATASGL0.TASGAL
0x874CC3C4 ETHA1
  [28] EATASGL1.TASGSL, [27:0] EATASGL1.TASGTL
0x874CC3C8 ETHA1
  [31] EATASGLR.GL
0x874CC3D0 ETHA1
  [7:0] EATASGR.TASGAR
0x874CC3D4 ETHA1
  [31] EATASGRR.GR, [29] EATASGRR.TASREF, [28] EATASGRR.TASGSR, [27:0] EATASGRR.TASGTR
0x874CC3E0 ETHA1
  [15:0] EATASHCC.TASJ
0x874CC3E4 ETHA1
  [1] EATASRIRM.TASRR, [0] EATASRIRM.TASRIOG
0x874CC3E8 ETHA1
  [16] EATASSM.TASSO, [8] EATASSM.TASCTGS, [n] EATASSM.TASGS{n} (n=0..7)
0x874CC400 ETHA1
  [15:0] EAUSMFSECN.USMFSEN
0x874CC404 ETHA1
  [15:0] EATFECN.TFEN
0x874CC408 ETHA1
  [15:0] EAFSECN.FSEN
0x874CC40C ETHA1
  [15:0] EADQOECN.DQOEN
0x874CC410 ETHA1
  [15:0] EADQSECN.DQSEN
0x874CC500 ETHA1
  [24] EAEIS0.TASCTGEES, [n+16] EAEIS0.TASGEES{n} (n=0..7), [n+8] EAEIS0.FSES{n} (n=0..7), [7] EAEIS0.CKSES, [6] EAEIS0.TFES, [5] EAEIS0.USMFSES, [4] EAEIS0.L23UECCES, [3] EAEIS0.DSECCES, [2] EAEIS0.PECCES, [1] EAEIS0.TECCES, [0] EAEIS0.DECCES
0x874CC504 ETHA1
  [24] EAEIE0.TASCTGEEE, [n+16] EAEIE0.TASGEEE{n} (n=0..7), [n+8] EAEIE0.FSEE{n} (n=0..7), [7] EAEIE0.CKSEE, [6] EAEIE0.TFEE, [5] EAEIE0.USMFSEE, [4] EAEIE0.L23UECCEE, [3] EAEIE0.DSECCEE, [2] EAEIE0.PECCEE, [1] EAEIE0.TECCEE, [0] EAEIE0.DECCEE
0x874CC508 ETHA1
  [24] EAEID0.TASCTGEED, [n+16] EAEID0.TASGEED{n} (n=0..7), [n+8] EAEID0.FSED{n} (n=0..7), [7] EAEID0.CKSED, [6] EAEID0.TFED, [5] EAEID0.USMFSED, [4] EAEID0.L23UECCED, [3] EAEID0.DSECCED, [2] EAEID0.PECCED, [1] EAEID0.TECCED, [0] EAEID0.DECCED
0x874CC510 ETHA1
  [24] EAEIS1.TASCTGES, [n+16] EAEIS1.TASGES{n} (n=0..7), [n] EAEIS1.CULES{n} (n=0..7)
0x874CC514 ETHA1
  [24] EAEIE1.TASCTGEE, [n+16] EAEIE1.TASGEE{n} (n=0..7), [n] EAEIE1.CULEE{n} (n=0..7)
0x874CC518 ETHA1
  [24] EAEID1.TASCTGED, [n+16] EAEID1.TASGED{n} (n=0..7), [n] EAEID1.CULED{n} (n=0..7)
0x874CC520 ETHA1
  [n+16] EAEIS2.DQSES{n} (n=0..7), [8] EAEIS2.CTDQOES, [n] EAEIS2.DQOES{n} (n=0..7)
0x874CC524 ETHA1
  [n+16] EAEIE2.DQSEE{n} (n=0..7), [8] EAEIE2.CTDQOEE, [n] EAEIE2.DQOEE{n} (n=0..7)
0x874CC528 ETHA1
  [n+16] EAEID2.DQSED{n} (n=0..7), [8] EAEID2.CTDQOED, [n] EAEID2.DQOED{n} (n=0..7)
0x874CC580 ETHA1
  [n+16] EASCR.DQRSL{n} (n=0..7), [6] EASCR.CRSL, [5] EASCR.EIRSL, [4] EASCR.TASRSL, [3] EASCR.TGRSL, [2] EASCR.MCRSL, [1] EASCR.TRSL, [0] EASCR.MRSL
0x874CD000 RMAC1
  fields as RMAC0
# iorx74m register map
Registers are 32-bit, access not given, no defined reset value unless marked. A register's access mark holds for its fields unless they carry their own. Addresses are absolute; registers are grouped by the start of their names; [hi:lo] are bit positions; {n}, {i} and the like mark numbered series.

## SFR (part 9 of 10)
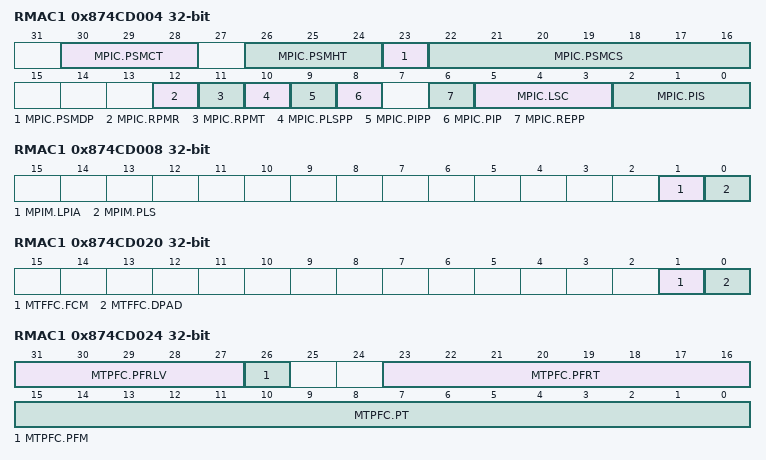
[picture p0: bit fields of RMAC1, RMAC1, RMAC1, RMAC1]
0x874CD004 RMAC1
  [30:28] MPIC.PSMCT, [26:24] MPIC.PSMHT, [23] MPIC.PSMDP, [22:16] MPIC.PSMCS, [12] MPIC.RPMR, [11] MPIC.RPMT, [10] MPIC.PLSPP, [9] MPIC.PIPP, [8] MPIC.PIP, [6] MPIC.REPP, [5:3] MPIC.LSC, [2:0] MPIC.PIS
0x874CD008 RMAC1
  [1] MPIM.LPIA, [0] MPIM.PLS
0x874CD010 RMAC1
  [31:0] MIOC.MIOC
0x874CD020 RMAC1
  [1] MTFFC.FCM, [0] MTFFC.DPAD
0x874CD024 RMAC1
  [31:27] MTPFC.PFRLV, [26] MTPFC.PFM, [23:16] MTPFC.PFRT, [15:0] MTPFC.PT
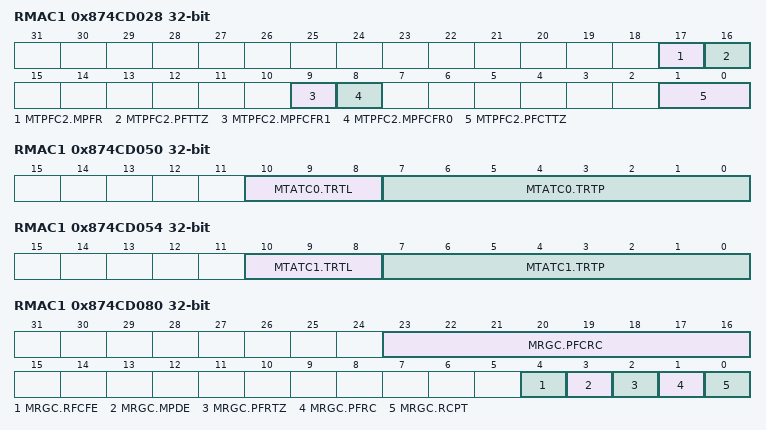
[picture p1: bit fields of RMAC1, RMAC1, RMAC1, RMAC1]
0x874CD028 RMAC1
  [17] MTPFC2.MPFR, [16] MTPFC2.PFTTZ, [9] MTPFC2.MPFCFR1, [8] MTPFC2.MPFCFR0, [1:0] MTPFC2.PFCTTZ
0x874CD030 RMAC1
  [7:0] MTPFC30.PFCPG
0x874CD034 RMAC1
  [7:0] MTPFC31.PFCPG
0x874CD050 RMAC1
  [10:8] MTATC0.TRTL, [7:0] MTATC0.TRTP
0x874CD054 RMAC1
  [10:8] MTATC1.TRTL, [7:0] MTATC1.TRTP
0x874CD060 RMAC1
  [0] MTIM.TS
0x874CD080 RMAC1
  [23:16] MRGC.PFCRC, [4] MRGC.RFCFE, [3] MRGC.MPDE, [2] MRGC.PFRTZ, [1] MRGC.PFRC, [0] MRGC.RCPT
0x874CD084 RMAC1
  [15:0] MRMAC0.MAU
0x874CD088 RMAC1
  [31:0] MRMAC1.MAL
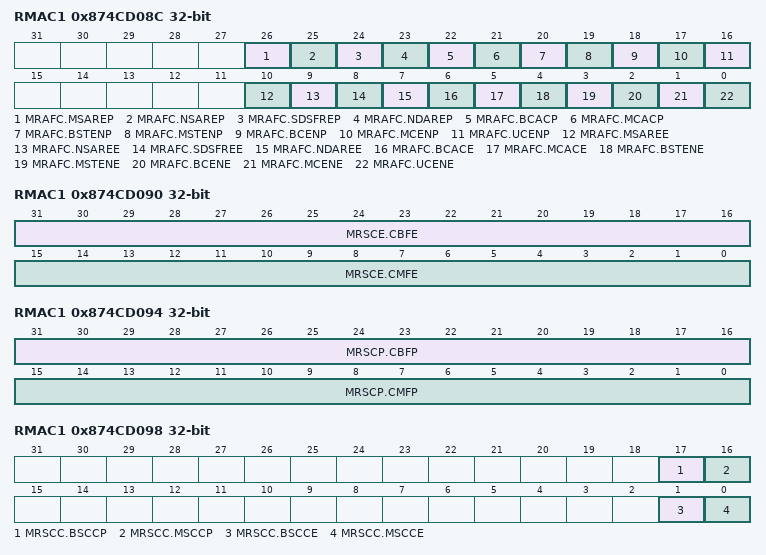
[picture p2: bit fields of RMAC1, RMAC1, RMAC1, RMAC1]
0x874CD08C RMAC1
  [26] MRAFC.MSAREP, [25] MRAFC.NSAREP, [24] MRAFC.SDSFREP, [23] MRAFC.NDAREP, [22] MRAFC.BCACP, [21] MRAFC.MCACP, [20] MRAFC.BSTENP, [19] MRAFC.MSTENP, [18] MRAFC.BCENP, [17] MRAFC.MCENP, [16] MRAFC.UCENP, [10] MRAFC.MSAREE, [9] MRAFC.NSAREE, [8] MRAFC.SDSFREE, [7] MRAFC.NDAREE, [6] MRAFC.BCACE, [5] MRAFC.MCACE, [4] MRAFC.BSTENE, [3] MRAFC.MSTENE, [2] MRAFC.BCENE, [1] MRAFC.MCENE, [0] MRAFC.UCENE
0x874CD090 RMAC1
  [31:16] MRSCE.CBFE, [15:0] MRSCE.CMFE
0x874CD094 RMAC1
  [31:16] MRSCP.CBFP, [15:0] MRSCP.CMFP
0x874CD098 RMAC1
  [17] MRSCC.BSCCP, [16] MRSCC.MSCCP, [1] MRSCC.BSCCE, [0] MRSCC.MSCCE
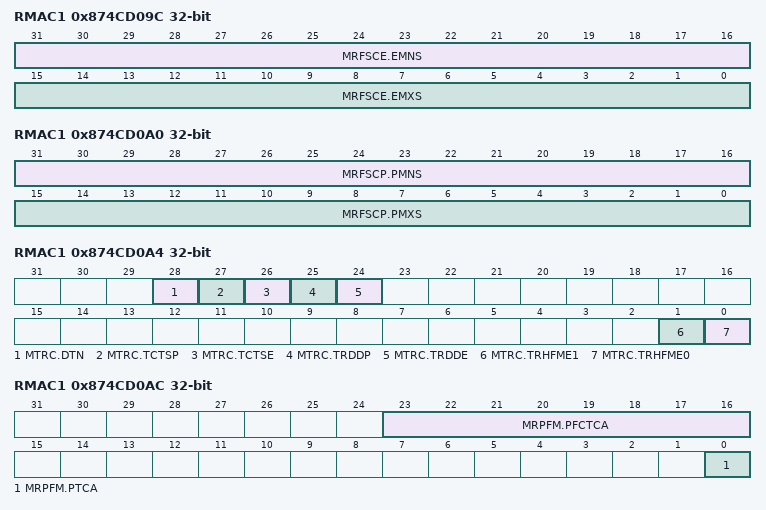
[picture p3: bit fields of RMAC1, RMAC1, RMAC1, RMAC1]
0x874CD09C RMAC1
  [31:16] MRFSCE.EMNS, [15:0] MRFSCE.EMXS
0x874CD0A0 RMAC1
  [31:16] MRFSCP.PMNS, [15:0] MRFSCP.PMXS
0x874CD0A4 RMAC1
  [28] MTRC.DTN, [27] MTRC.TCTSP, [26] MTRC.TCTSE, [25] MTRC.TRDDP, [24] MTRC.TRDDE, [1] MTRC.TRHFME1, [0] MTRC.TRHFME0
0x874CD0AC RMAC1
  [23:16] MRPFM.PFCTCA, [0] MRPFM.PTCA
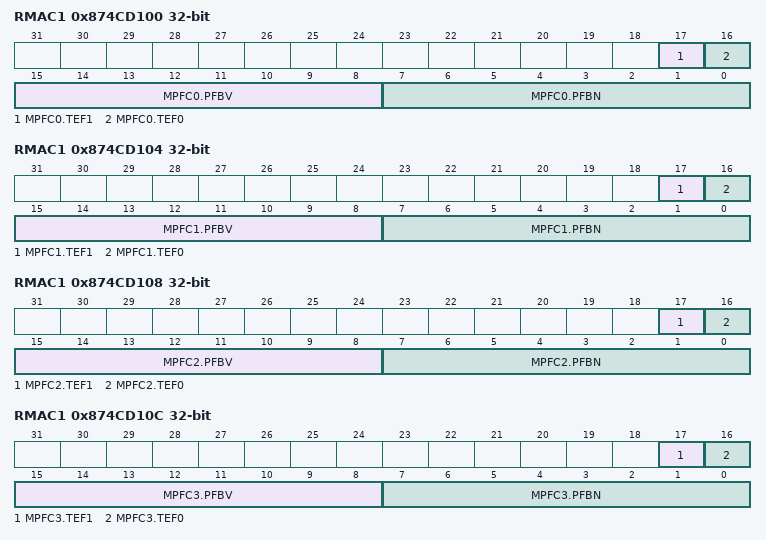
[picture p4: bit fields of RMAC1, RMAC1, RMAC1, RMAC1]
0x874CD100 RMAC1
  [17] MPFC0.TEF1, [16] MPFC0.TEF0, [15:8] MPFC0.PFBV, [7:0] MPFC0.PFBN
0x874CD104 RMAC1
  [17] MPFC1.TEF1, [16] MPFC1.TEF0, [15:8] MPFC1.PFBV, [7:0] MPFC1.PFBN
0x874CD108 RMAC1
  [17] MPFC2.TEF1, [16] MPFC2.TEF0, [15:8] MPFC2.PFBV, [7:0] MPFC2.PFBN
0x874CD10C RMAC1
  [17] MPFC3.TEF1, [16] MPFC3.TEF0, [15:8] MPFC3.PFBV, [7:0] MPFC3.PFBN
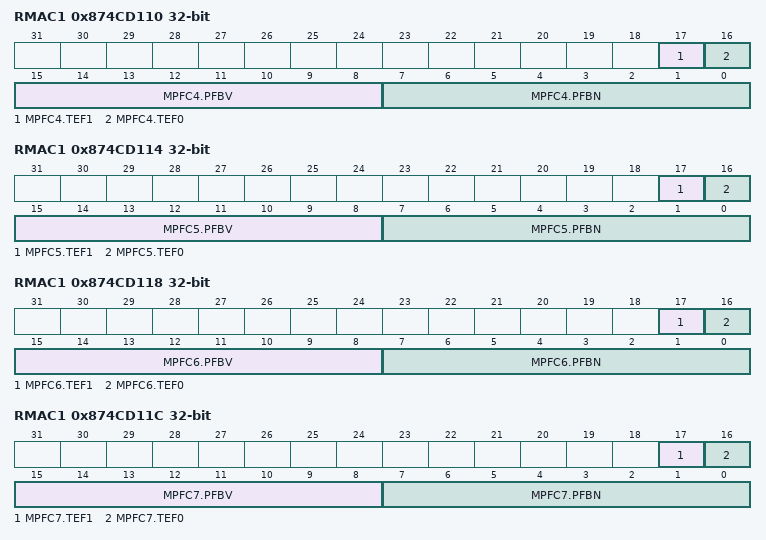
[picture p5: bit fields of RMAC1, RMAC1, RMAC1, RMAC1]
0x874CD110 RMAC1
  [17] MPFC4.TEF1, [16] MPFC4.TEF0, [15:8] MPFC4.PFBV, [7:0] MPFC4.PFBN
0x874CD114 RMAC1
  [17] MPFC5.TEF1, [16] MPFC5.TEF0, [15:8] MPFC5.PFBV, [7:0] MPFC5.PFBN
0x874CD118 RMAC1
  [17] MPFC6.TEF1, [16] MPFC6.TEF0, [15:8] MPFC6.PFBV, [7:0] MPFC6.PFBN
0x874CD11C RMAC1
  [17] MPFC7.TEF1, [16] MPFC7.TEF0, [15:8] MPFC7.PFBV, [7:0] MPFC7.PFBN
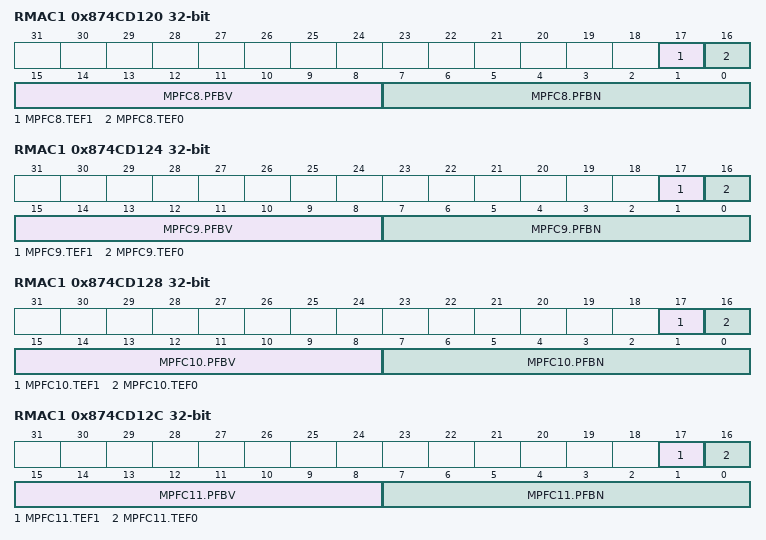
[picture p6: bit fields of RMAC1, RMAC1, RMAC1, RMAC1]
0x874CD120 RMAC1
  [17] MPFC8.TEF1, [16] MPFC8.TEF0, [15:8] MPFC8.PFBV, [7:0] MPFC8.PFBN
0x874CD124 RMAC1
  [17] MPFC9.TEF1, [16] MPFC9.TEF0, [15:8] MPFC9.PFBV, [7:0] MPFC9.PFBN
0x874CD128 RMAC1
  [17] MPFC10.TEF1, [16] MPFC10.TEF0, [15:8] MPFC10.PFBV, [7:0] MPFC10.PFBN
0x874CD12C RMAC1
  [17] MPFC11.TEF1, [16] MPFC11.TEF0, [15:8] MPFC11.PFBV, [7:0] MPFC11.PFBN
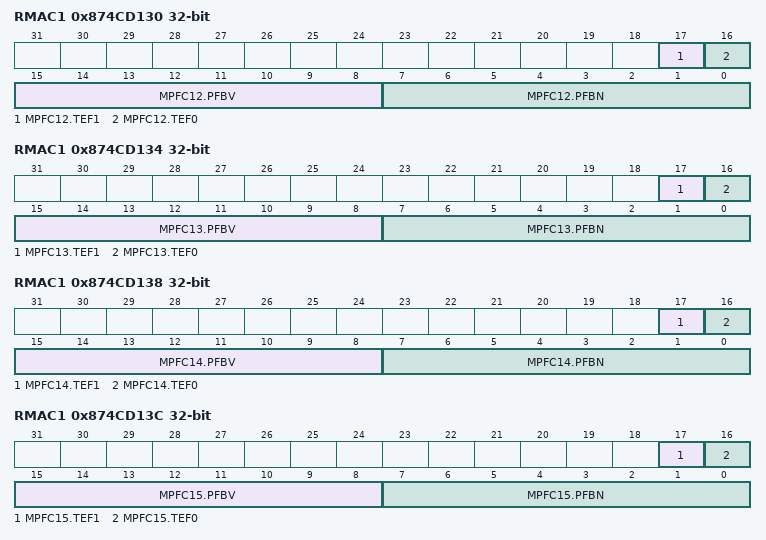
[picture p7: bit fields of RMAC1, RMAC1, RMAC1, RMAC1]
0x874CD130 RMAC1
  [17] MPFC12.TEF1, [16] MPFC12.TEF0, [15:8] MPFC12.PFBV, [7:0] MPFC12.PFBN
0x874CD134 RMAC1
  [17] MPFC13.TEF1, [16] MPFC13.TEF0, [15:8] MPFC13.PFBV, [7:0] MPFC13.PFBN
0x874CD138 RMAC1
  [17] MPFC14.TEF1, [16] MPFC14.TEF0, [15:8] MPFC14.PFBV, [7:0] MPFC14.PFBN
0x874CD13C RMAC1
  [17] MPFC15.TEF1, [16] MPFC15.TEF0, [15:8] MPFC15.PFBV, [7:0] MPFC15.PFBN
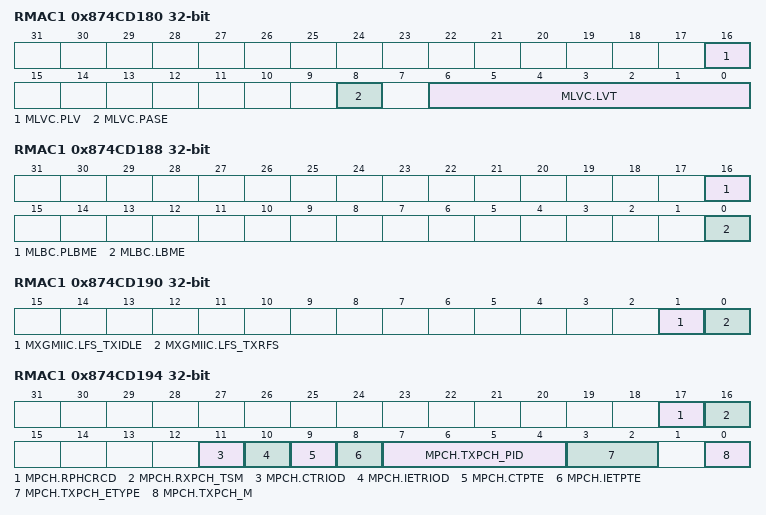
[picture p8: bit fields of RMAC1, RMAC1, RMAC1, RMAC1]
0x874CD180 RMAC1
  [16] MLVC.PLV, [8] MLVC.PASE, [6:0] MLVC.LVT
0x874CD184 RMAC1
  [0] MEEEC.LPITR
0x874CD188 RMAC1
  [16] MLBC.PLBME, [0] MLBC.LBME
0x874CD190 RMAC1
  [1] MXGMIIC.LFS_TXIDLE, [0] MXGMIIC.LFS_TXRFS
0x874CD194 RMAC1
  [17] MPCH.RPHCRCD, [16] MPCH.RXPCH_TSM, [11] MPCH.CTRIOD, [10] MPCH.IETRIOD, [9] MPCH.CTPTE, [8] MPCH.IETPTE, [7:4] MPCH.TXPCH_PID, [3:2] MPCH.TXPCH_ETYPE, [0] MPCH.TXPCH_M
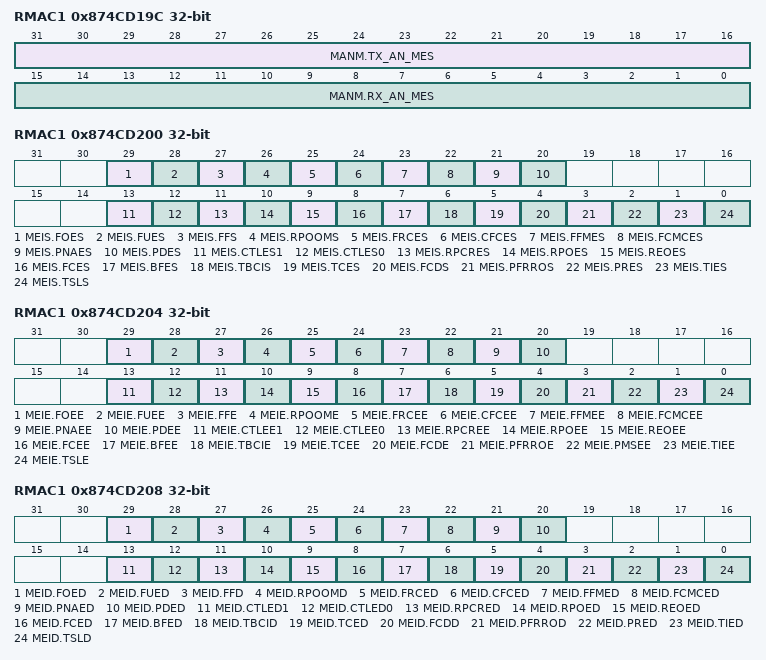
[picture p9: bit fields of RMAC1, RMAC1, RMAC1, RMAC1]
0x874CD19C RMAC1
  [31:16] MANM.TX_AN_MES, [15:0] MANM.RX_AN_MES
0x874CD200 RMAC1
  [29] MEIS.FOES, [28] MEIS.FUES, [27] MEIS.FFS, [26] MEIS.RPOOMS, [25] MEIS.FRCES, [24] MEIS.CFCES, [23] MEIS.FFMES, [22] MEIS.FCMCES, [21] MEIS.PNAES, [20] MEIS.PDES, [13] MEIS.CTLES1, [12] MEIS.CTLES0, [11] MEIS.RPCRES, [10] MEIS.RPOES, [9] MEIS.REOES, [8] MEIS.FCES, [7] MEIS.BFES, [6] MEIS.TBCIS, [5] MEIS.TCES, [4] MEIS.FCDS, [3] MEIS.PFRROS, [2] MEIS.PRES, [1] MEIS.TIES, [0] MEIS.TSLS
0x874CD204 RMAC1
  [29] MEIE.FOEE, [28] MEIE.FUEE, [27] MEIE.FFE, [26] MEIE.RPOOME, [25] MEIE.FRCEE, [24] MEIE.CFCEE, [23] MEIE.FFMEE, [22] MEIE.FCMCEE, [21] MEIE.PNAEE, [20] MEIE.PDEE, [13] MEIE.CTLEE1, [12] MEIE.CTLEE0, [11] MEIE.RPCREE, [10] MEIE.RPOEE, [9] MEIE.REOEE, [8] MEIE.FCEE, [7] MEIE.BFEE, [6] MEIE.TBCIE, [5] MEIE.TCEE, [4] MEIE.FCDE, [3] MEIE.PFRROE, [2] MEIE.PMSEE, [1] MEIE.TIEE, [0] MEIE.TSLE
0x874CD208 RMAC1
  [29] MEID.FOED, [28] MEID.FUED, [27] MEID.FFD, [26] MEID.RPOOMD, [25] MEID.FRCED, [24] MEID.CFCED, [23] MEID.FFMED, [22] MEID.FCMCED, [21] MEID.PNAED, [20] MEID.PDED, [13] MEID.CTLED1, [12] MEID.CTLED0, [11] MEID.RPCRED, [10] MEID.RPOED, [9] MEID.REOED, [8] MEID.FCED, [7] MEID.BFED, [6] MEID.TBCID, [5] MEID.TCED, [4] MEID.FCDD, [3] MEID.PFRROD, [2] MEID.PRED, [1] MEID.TIED, [0] MEID.TSLD
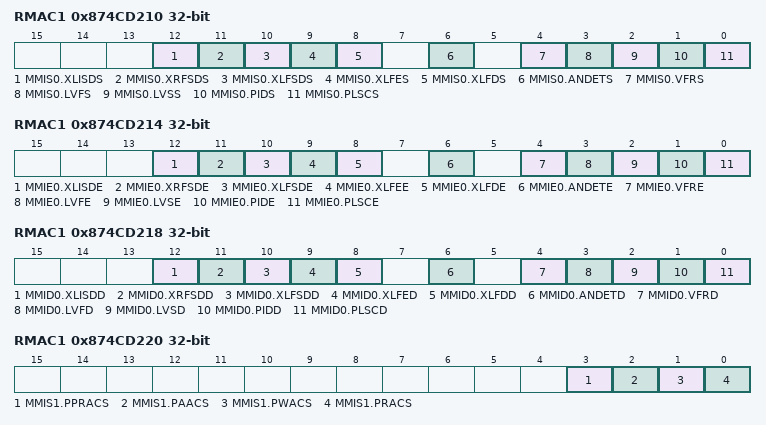
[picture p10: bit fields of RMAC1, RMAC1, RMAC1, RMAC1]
0x874CD210 RMAC1
  [12] MMIS0.XLISDS, [11] MMIS0.XRFSDS, [10] MMIS0.XLFSDS, [9] MMIS0.XLFES, [8] MMIS0.XLFDS, [6] MMIS0.ANDETS, [4] MMIS0.VFRS, [3] MMIS0.LVFS, [2] MMIS0.LVSS, [1] MMIS0.PIDS, [0] MMIS0.PLSCS
0x874CD214 RMAC1
  [12] MMIE0.XLISDE, [11] MMIE0.XRFSDE, [10] MMIE0.XLFSDE, [9] MMIE0.XLFEE, [8] MMIE0.XLFDE, [6] MMIE0.ANDETE, [4] MMIE0.VFRE, [3] MMIE0.LVFE, [2] MMIE0.LVSE, [1] MMIE0.PIDE, [0] MMIE0.PLSCE
0x874CD218 RMAC1
  [12] MMID0.XLISDD, [11] MMID0.XRFSDD, [10] MMID0.XLFSDD, [9] MMID0.XLFED, [8] MMID0.XLFDD, [6] MMID0.ANDETD, [4] MMID0.VFRD, [3] MMID0.LVFD, [2] MMID0.LVSD, [1] MMID0.PIDD, [0] MMID0.PLSCD
0x874CD220 RMAC1
  [3] MMIS1.PPRACS, [2] MMIS1.PAACS, [1] MMIS1.PWACS, [0] MMIS1.PRACS
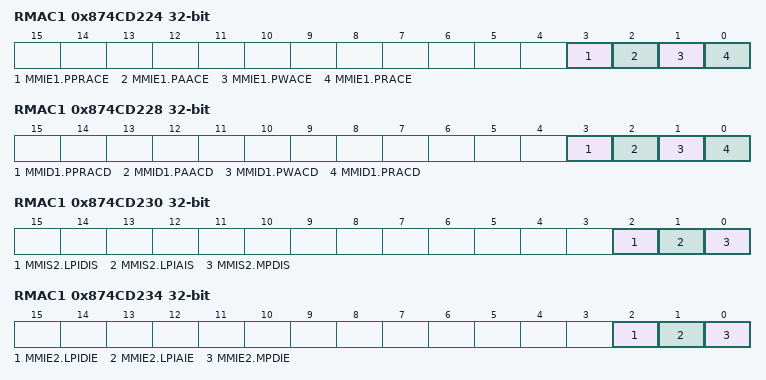
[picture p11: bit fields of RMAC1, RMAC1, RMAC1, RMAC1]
0x874CD224 RMAC1
  [3] MMIE1.PPRACE, [2] MMIE1.PAACE, [1] MMIE1.PWACE, [0] MMIE1.PRACE
0x874CD228 RMAC1
  [3] MMID1.PPRACD, [2] MMID1.PAACD, [1] MMID1.PWACD, [0] MMID1.PRACD
0x874CD230 RMAC1
  [2] MMIS2.LPIDIS, [1] MMIS2.LPIAIS, [0] MMIS2.MPDIS
0x874CD234 RMAC1
  [2] MMIE2.LPIDIE, [1] MMIE2.LPIAIE, [0] MMIE2.MPDIE
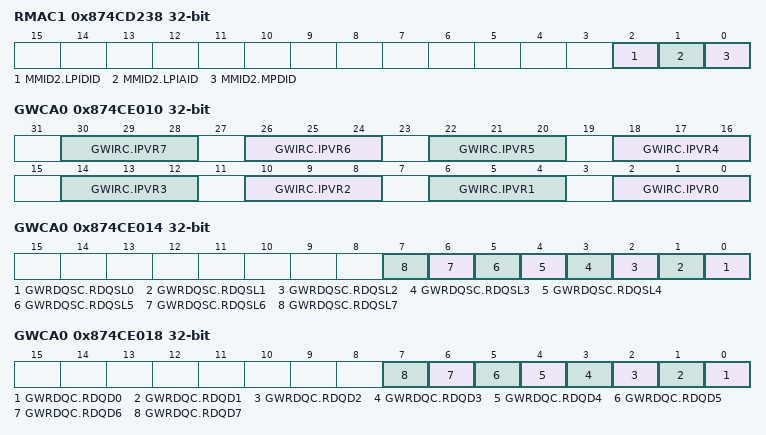
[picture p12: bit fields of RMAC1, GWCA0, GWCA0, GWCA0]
0x874CD238 RMAC1
  [2] MMID2.LPIDID, [1] MMID2.LPIAID, [0] MMID2.MPDID
0x874CD300 RMAC1
  [15:0] MMPFTCT.MPFTC
0x874CD304 RMAC1
  [15:0] MAPFTCT.APFTC
0x874CD308 RMAC1
  [15:0] MPFRCT.PFRC
0x874CD30C RMAC1
  [15:0] MFCICT.FCIC
0x874CD310 RMAC1
  [15:0] MEEECT.EEERC
0x874CD320 RMAC1
  [15:0] MMPCFTCT0.MPCFCTC
0x874CD324 RMAC1
  [15:0] MMPCFTCT1.MPCFCTC
0x874CD330 RMAC1
  [15:0] MAPCFTCT0.APCFCTC
0x874CD334 RMAC1
  [15:0] MAPCFTCT1.APCFCTC
0x874CD340 RMAC1
  [15:0] MPCFRCT0.PCFCRC
0x874CD344 RMAC1
  [15:0] MPCFRCT1.PCFCRC
0x874CD348 RMAC1
  [15:0] MPCFRCT2.PCFCRC
0x874CD34C RMAC1
  [15:0] MPCFRCT3.PCFCRC
0x874CD350 RMAC1
  [15:0] MPCFRCT4.PCFCRC
0x874CD354 RMAC1
  [15:0] MPCFRCT5.PCFCRC
0x874CD358 RMAC1
  [15:0] MPCFRCT6.PCFCRC
0x874CD35C RMAC1
  [15:0] MPCFRCT7.PCFCRC
0x874CD360 RMAC1
  [31:0] MROVFC.ROVFC
0x874CD364 RMAC1
  [15:0] MRHCRCEC.RHCRCEC
0x874CD408 RMAC1
  [31:0] MRGFCE.RGFNE
0x874CD40C RMAC1
  [31:0] MRGFCP.RGFNP
0x874CD410 RMAC1
  [31:0] MRBFC.RBFN
0x874CD414 RMAC1
  [31:0] MRMFC.RMFN
0x874CD418 RMAC1
  [31:0] MRUFC.RUFN
0x874CD41C RMAC1
  [15:0] MRPEFC.RPEFN
0x874CD420 RMAC1
  [15:0] MRNEFC.RNEFN
0x874CD424 RMAC1
  [31:0] MRFMEFC.RFMEFN
0x874CD428 RMAC1
  [15:0] MRFFMEFC.RFFMEFN
0x874CD42C RMAC1
  [15:0] MRCFCEFC.RCFCEFN
0x874CD430 RMAC1
  [15:0] MRFCEFC.RFCEFN
0x874CD434 RMAC1
  [15:0] MRRCFEFC.RRCFEFN
0x874CD438 RMAC1
  [31:0] MRFC.RFN
0x874CD43C RMAC1
  [31:0] MRGUEFC.RUEFN
0x874CD440 RMAC1
  [31:0] MRBUEFC.RUEFN
0x874CD444 RMAC1
  [31:0] MRGOEFC.RGOEFN
0x874CD448 RMAC1
  [31:0] MRBOEFC.RBOEFN
0x874CD44C RMAC1
  [31:0] MRXBCEU.RBNEU
0x874CD450 RMAC1
  [31:0] MRXBCEL.RBNEL
0x874CD454 RMAC1
  [31:0] MRXBCPU.RBNPU
0x874CD458 RMAC1
  [31:0] MRXBCPL.RBNPL
0x874CD508 RMAC1
  [31:0] MTGFCE.TGFNE
0x874CD50C RMAC1
  [31:0] MTGFCP.TGFNP
0x874CD510 RMAC1
  [31:0] MTBFC.TBFN
0x874CD514 RMAC1
  [31:0] MTMFC.TMFN
0x874CD518 RMAC1
  [31:0] MTUFC.TUFN
0x874CD51C RMAC1
  [15:0] MTEFC.TEFN
0x874CD520 RMAC1
  [31:0] MTXBCEU.TBNEU
0x874CD524 RMAC1
  [31:0] MTXBCEL.TBNEL
0x874CD528 RMAC1
  [31:0] MTXBCPU.TBNPU
0x874CD52C RMAC1
  [31:0] MTXBCPL.TBNPL
0x874CE000 GWCA0
  [1:0] GWMC.OPC
0x874CE004 GWCA0
  [1:0] GWMS.OPS
0x874CE010 GWCA0
  [4n+2:4n] GWIRC.IPVR{n} (n=0..7)
0x874CE014 GWCA0
  [n] GWRDQSC.RDQSL{n} (n=0..7)
0x874CE018 GWCA0
  [n] GWRDQC.RDQD{n} (n=0..7)
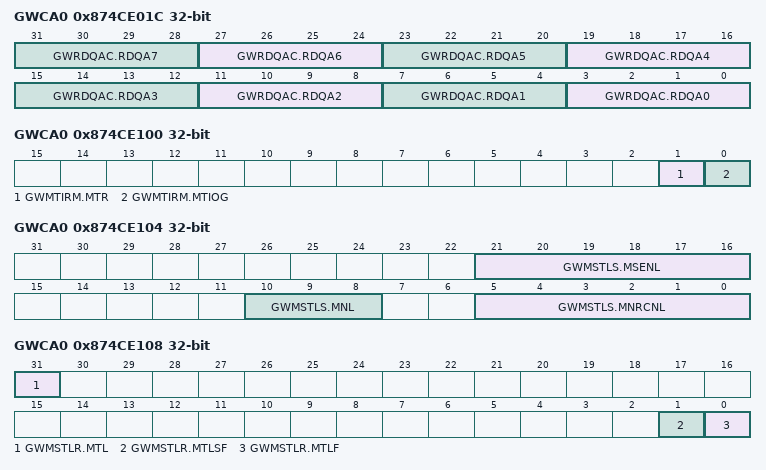
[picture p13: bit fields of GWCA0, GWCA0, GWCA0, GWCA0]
0x874CE01C GWCA0
  [4n+3:4n] GWRDQAC.RDQA{n} (n=0..7)
0x874CE020 GWCA0
  [0] GWRGC.RCPT
0x874CE040 GWCA0
  [15:0] GWRMFSC0.MFS
0x874CE044 GWCA0
  [15:0] GWRMFSC1.MFS
0x874CE048 GWCA0
  [15:0] GWRMFSC2.MFS
0x874CE04C GWCA0
  [15:0] GWRMFSC3.MFS
0x874CE050 GWCA0
  [15:0] GWRMFSC4.MFS
0x874CE054 GWCA0
  [15:0] GWRMFSC5.MFS
0x874CE058 GWCA0
  [15:0] GWRMFSC6.MFS
0x874CE05C GWCA0
  [15:0] GWRMFSC7.MFS
0x874CE060 GWCA0
  [9:0] GWRDQDC0.DQD
0x874CE064 GWCA0
  [9:0] GWRDQDC1.DQD
0x874CE068 GWCA0
  [9:0] GWRDQDC2.DQD
0x874CE06C GWCA0
  [9:0] GWRDQDC3.DQD
0x874CE070 GWCA0
  [9:0] GWRDQDC4.DQD
0x874CE074 GWCA0
  [9:0] GWRDQDC5.DQD
0x874CE078 GWCA0
  [9:0] GWRDQDC6.DQD
0x874CE07C GWCA0
  [9:0] GWRDQDC7.DQD
0x874CE080 GWCA0
  [9:0] GWRDQM0.DNQ
0x874CE084 GWCA0
  [9:0] GWRDQM1.DNQ
0x874CE088 GWCA0
  [9:0] GWRDQM2.DNQ
0x874CE08C GWCA0
  [9:0] GWRDQM3.DNQ
0x874CE090 GWCA0
  [9:0] GWRDQM4.DNQ
0x874CE094 GWCA0
  [9:0] GWRDQM5.DNQ
0x874CE098 GWCA0
  [9:0] GWRDQM6.DNQ
0x874CE09C GWCA0
  [9:0] GWRDQM7.DNQ
0x874CE0A0 GWCA0
  [9:0] GWRDQMLM0.DMLQ
0x874CE0A4 GWCA0
  [9:0] GWRDQMLM1.DMLQ
0x874CE0A8 GWCA0
  [9:0] GWRDQMLM2.DMLQ
0x874CE0AC GWCA0
  [9:0] GWRDQMLM3.DMLQ
0x874CE0B0 GWCA0
  [9:0] GWRDQMLM4.DMLQ
0x874CE0B4 GWCA0
  [9:0] GWRDQMLM5.DMLQ
0x874CE0B8 GWCA0
  [9:0] GWRDQMLM6.DMLQ
0x874CE0BC GWCA0
  [9:0] GWRDQMLM7.DMLQ
0x874CE100 GWCA0
  [1] GWMTIRM.MTR, [0] GWMTIRM.MTIOG
0x874CE104 GWCA0
  [21:16] GWMSTLS.MSENL, [10:8] GWMSTLS.MNL, [5:0] GWMSTLS.MNRCNL
0x874CE108 GWCA0
  [31] GWMSTLR.MTL, [1] GWMSTLR.MTLSF, [0] GWMSTLR.MTLF
0x874CE10C GWCA0
  [5:0] GWMSTSS.MSENS
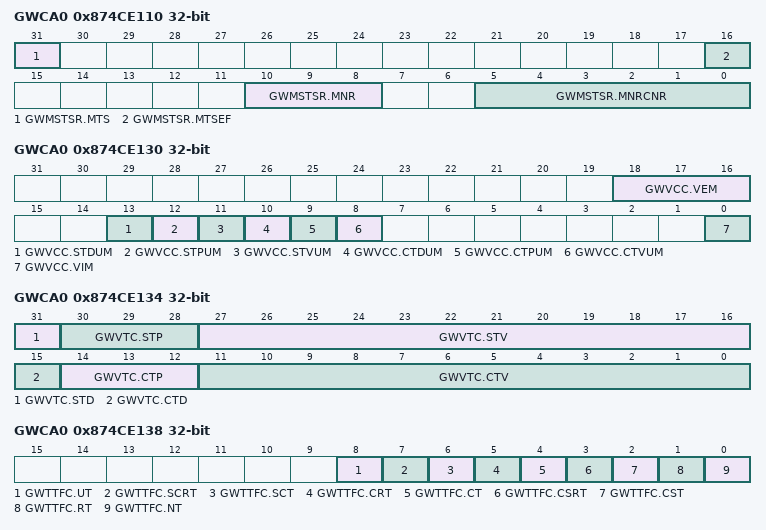
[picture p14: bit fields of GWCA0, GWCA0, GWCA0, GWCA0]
0x874CE110 GWCA0
  [31] GWMSTSR.MTS, [16] GWMSTSR.MTSEF, [10:8] GWMSTSR.MNR, [5:0] GWMSTSR.MNRCNR
0x874CE120 GWCA0
  [15:0] GWMAC0.MAUP
0x874CE124 GWCA0
  [31:0] GWMAC1.MADP
0x874CE130 GWCA0
  [18:16] GWVCC.VEM, [13] GWVCC.STDUM, [12] GWVCC.STPUM, [11] GWVCC.STVUM, [10] GWVCC.CTDUM, [9] GWVCC.CTPUM, [8] GWVCC.CTVUM, [0] GWVCC.VIM
0x874CE134 GWCA0
  [31] GWVTC.STD, [30:28] GWVTC.STP, [27:16] GWVTC.STV, [15] GWVTC.CTD, [14:12] GWVTC.CTP, [11:0] GWVTC.CTV
0x874CE138 GWCA0
  [8] GWTTFC.UT, [7] GWTTFC.SCRT, [6] GWTTFC.SCT, [5] GWTTFC.CRT, [4] GWTTFC.CT, [3] GWTTFC.CSRT, [2] GWTTFC.CST, [1] GWTTFC.RT, [0] GWTTFC.NT
0x874CE140 GWCA0
  [7:0] GWTDCAC00.TSCCAUP
0x874CE144 GWCA0
  [31:0] GWTDCAC01.TSCCADP
0x874CE148 GWCA0
  [7:0] GWTDCAC10.TSCCAUP
0x874CE14C GWCA0
  [31:0] GWTDCAC11.TSCCADP
0x874CE160 GWCA0
  [10:8] GWTSDCC0.OSID, [2:1] GWTSDCC0.DCS, [0] GWTSDCC0.TE
0x874CE164 GWCA0
  [10:8] GWTSDCC1.OSID, [2:1] GWTSDCC1.DCS, [0] GWTSDCC1.TE
0x874CE180 GWCA0
  [4:0] GWTSNM.TNTR
0x874CE184 GWCA0
  [4:0] GWTSMNM.TMNTR
0x874CE190 GWCA0
  [1] GWAC.AMP, [0] GWAC.AMPR
0x874CE194 GWCA0
  [7:0] GWDCBAC0.DCBAUP
0x874CE198 GWCA0
  [31:0] GWDCBAC1.DCBADP
0x874CE1A0 GWCA0
  [17:16] GWMDNC.TSDMN, [12:8] GWMDNC.TXDMN, [4:0] GWMDNC.RXDMN
0x874CE300 GWCA0
  [n] GWTPC0.PPPL{n} (n=0..7)
0x874CE304 GWCA0
  [n] GWTPC1.PPPL{n} (n=0..7)
0x874CE380 GWCA0
  [1] GWARIRM.ARR, [0] GWARIRM.ARIOG
0x874CE400 GWCA0
  [30:28] GWDCC0.OSID, [24] GWDCC0.BALR, [18:16] GWDCC0.DCP, [11] GWDCC0.DQT, [10] GWDCC0.SL, [9] GWDCC0.ETS, [8] GWDCC0.EDE, [1:0] GWDCC0.SM
0x874CE404 GWCA0
  [30:28] GWDCC1.OSID, [24] GWDCC1.BALR, [18:16] GWDCC1.DCP, [11] GWDCC1.DQT, [10] GWDCC1.SL, [9] GWDCC1.ETS, [8] GWDCC1.EDE, [1:0] GWDCC1.SM
0x874CE408 GWCA0
  [30:28] GWDCC2.OSID, [24] GWDCC2.BALR, [18:16] GWDCC2.DCP, [11] GWDCC2.DQT, [10] GWDCC2.SL, [9] GWDCC2.ETS, [8] GWDCC2.EDE, [1:0] GWDCC2.SM
0x874CE40C GWCA0
  [30:28] GWDCC3.OSID, [24] GWDCC3.BALR, [18:16] GWDCC3.DCP, [11] GWDCC3.DQT, [10] GWDCC3.SL, [9] GWDCC3.ETS, [8] GWDCC3.EDE, [1:0] GWDCC3.SM
0x874CE410 GWCA0
  [30:28] GWDCC4.OSID, [24] GWDCC4.BALR, [18:16] GWDCC4.DCP, [11] GWDCC4.DQT, [10] GWDCC4.SL, [9] GWDCC4.ETS, [8] GWDCC4.EDE, [1:0] GWDCC4.SM
0x874CE414 GWCA0
  [30:28] GWDCC5.OSID, [24] GWDCC5.BALR, [18:16] GWDCC5.DCP, [11] GWDCC5.DQT, [10] GWDCC5.SL, [9] GWDCC5.ETS, [8] GWDCC5.EDE, [1:0] GWDCC5.SM
0x874CE418 GWCA0
  [30:28] GWDCC6.OSID, [24] GWDCC6.BALR, [18:16] GWDCC6.DCP, [11] GWDCC6.DQT, [10] GWDCC6.SL, [9] GWDCC6.ETS, [8] GWDCC6.EDE, [1:0] GWDCC6.SM
0x874CE41C GWCA0
  [30:28] GWDCC7.OSID, [24] GWDCC7.BALR, [18:16] GWDCC7.DCP, [11] GWDCC7.DQT, [10] GWDCC7.SL, [9] GWDCC7.ETS, [8] GWDCC7.EDE, [1:0] GWDCC7.SM
0x874CE420 GWCA0
  [30:28] GWDCC8.OSID, [24] GWDCC8.BALR, [18:16] GWDCC8.DCP, [11] GWDCC8.DQT, [10] GWDCC8.SL, [9] GWDCC8.ETS, [8] GWDCC8.EDE, [1:0] GWDCC8.SM
0x874CE424 GWCA0
  [30:28] GWDCC9.OSID, [24] GWDCC9.BALR, [18:16] GWDCC9.DCP, [11] GWDCC9.DQT, [10] GWDCC9.SL, [9] GWDCC9.ETS, [8] GWDCC9.EDE, [1:0] GWDCC9.SM
0x874CE428 GWCA0
  [30:28] GWDCC10.OSID, [24] GWDCC10.BALR, [18:16] GWDCC10.DCP, [11] GWDCC10.DQT, [10] GWDCC10.SL, [9] GWDCC10.ETS, [8] GWDCC10.EDE, [1:0] GWDCC10.SM
0x874CE42C GWCA0
  [30:28] GWDCC11.OSID, [24] GWDCC11.BALR, [18:16] GWDCC11.DCP, [11] GWDCC11.DQT, [10] GWDCC11.SL, [9] GWDCC11.ETS, [8] GWDCC11.EDE, [1:0] GWDCC11.SM
0x874CE430 GWCA0
  [30:28] GWDCC12.OSID, [24] GWDCC12.BALR, [18:16] GWDCC12.DCP, [11] GWDCC12.DQT, [10] GWDCC12.SL, [9] GWDCC12.ETS, [8] GWDCC12.EDE, [1:0] GWDCC12.SM
0x874CE434 GWCA0
  [30:28] GWDCC13.OSID, [24] GWDCC13.BALR, [18:16] GWDCC13.DCP, [11] GWDCC13.DQT, [10] GWDCC13.SL, [9] GWDCC13.ETS, [8] GWDCC13.EDE, [1:0] GWDCC13.SM
0x874CE438 GWCA0
  [30:28] GWDCC14.OSID, [24] GWDCC14.BALR, [18:16] GWDCC14.DCP, [11] GWDCC14.DQT, [10] GWDCC14.SL, [9] GWDCC14.ETS, [8] GWDCC14.EDE, [1:0] GWDCC14.SM
0x874CE43C GWCA0
  [30:28] GWDCC15.OSID, [24] GWDCC15.BALR, [18:16] GWDCC15.DCP, [11] GWDCC15.DQT, [10] GWDCC15.SL, [9] GWDCC15.ETS, [8] GWDCC15.EDE, [1:0] GWDCC15.SM
0x874CE440 GWCA0
  [30:28] GWDCC16.OSID, [24] GWDCC16.BALR, [18:16] GWDCC16.DCP, [11] GWDCC16.DQT, [10] GWDCC16.SL, [9] GWDCC16.ETS, [8] GWDCC16.EDE, [1:0] GWDCC16.SM
0x874CE444 GWCA0
  [30:28] GWDCC17.OSID, [24] GWDCC17.BALR, [18:16] GWDCC17.DCP, [11] GWDCC17.DQT, [10] GWDCC17.SL, [9] GWDCC17.ETS, [8] GWDCC17.EDE, [1:0] GWDCC17.SM
0x874CE448 GWCA0
  [30:28] GWDCC18.OSID, [24] GWDCC18.BALR, [18:16] GWDCC18.DCP, [11] GWDCC18.DQT, [10] GWDCC18.SL, [9] GWDCC18.ETS, [8] GWDCC18.EDE, [1:0] GWDCC18.SM
0x874CE44C GWCA0
  [30:28] GWDCC19.OSID, [24] GWDCC19.BALR, [18:16] GWDCC19.DCP, [11] GWDCC19.DQT, [10] GWDCC19.SL, [9] GWDCC19.ETS, [8] GWDCC19.EDE, [1:0] GWDCC19.SM
0x874CE450 GWCA0
  [30:28] GWDCC20.OSID, [24] GWDCC20.BALR, [18:16] GWDCC20.DCP, [11] GWDCC20.DQT, [10] GWDCC20.SL, [9] GWDCC20.ETS, [8] GWDCC20.EDE, [1:0] GWDCC20.SM
0x874CE454 GWCA0
  [30:28] GWDCC21.OSID, [24] GWDCC21.BALR, [18:16] GWDCC21.DCP, [11] GWDCC21.DQT, [10] GWDCC21.SL, [9] GWDCC21.ETS, [8] GWDCC21.EDE, [1:0] GWDCC21.SM
0x874CE458 GWCA0
  [30:28] GWDCC22.OSID, [24] GWDCC22.BALR, [18:16] GWDCC22.DCP, [11] GWDCC22.DQT, [10] GWDCC22.SL, [9] GWDCC22.ETS, [8] GWDCC22.EDE, [1:0] GWDCC22.SM
0x874CE45C GWCA0
  [30:28] GWDCC23.OSID, [24] GWDCC23.BALR, [18:16] GWDCC23.DCP, [11] GWDCC23.DQT, [10] GWDCC23.SL, [9] GWDCC23.ETS, [8] GWDCC23.EDE, [1:0] GWDCC23.SM
0x874CE460 GWCA0
  [30:28] GWDCC24.OSID, [24] GWDCC24.BALR, [18:16] GWDCC24.DCP, [11] GWDCC24.DQT, [10] GWDCC24.SL, [9] GWDCC24.ETS, [8] GWDCC24.EDE, [1:0] GWDCC24.SM
0x874CE464 GWCA0
  [30:28] GWDCC25.OSID, [24] GWDCC25.BALR, [18:16] GWDCC25.DCP, [11] GWDCC25.DQT, [10] GWDCC25.SL, [9] GWDCC25.ETS, [8] GWDCC25.EDE, [1:0] GWDCC25.SM
0x874CE468 GWCA0
  [30:28] GWDCC26.OSID, [24] GWDCC26.BALR, [18:16] GWDCC26.DCP, [11] GWDCC26.DQT, [10] GWDCC26.SL, [9] GWDCC26.ETS, [8] GWDCC26.EDE, [1:0] GWDCC26.SM
0x874CE46C GWCA0
  [30:28] GWDCC27.OSID, [24] GWDCC27.BALR, [18:16] GWDCC27.DCP, [11] GWDCC27.DQT, [10] GWDCC27.SL, [9] GWDCC27.ETS, [8] GWDCC27.EDE, [1:0] GWDCC27.SM
0x874CE470 GWCA0
  [30:28] GWDCC28.OSID, [24] GWDCC28.BALR, [18:16] GWDCC28.DCP, [11] GWDCC28.DQT, [10] GWDCC28.SL, [9] GWDCC28.ETS, [8] GWDCC28.EDE, [1:0] GWDCC28.SM
0x874CE474 GWCA0
  [30:28] GWDCC29.OSID, [24] GWDCC29.BALR, [18:16] GWDCC29.DCP, [11] GWDCC29.DQT, [10] GWDCC29.SL, [9] GWDCC29.ETS, [8] GWDCC29.EDE, [1:0] GWDCC29.SM
0x874CE478 GWCA0
  [30:28] GWDCC30.OSID, [24] GWDCC30.BALR, [18:16] GWDCC30.DCP, [11] GWDCC30.DQT, [10] GWDCC30.SL, [9] GWDCC30.ETS, [8] GWDCC30.EDE, [1:0] GWDCC30.SM
0x874CE47C GWCA0
  [30:28] GWDCC31.OSID, [24] GWDCC31.BALR, [18:16] GWDCC31.DCP, [11] GWDCC31.DQT, [10] GWDCC31.SL, [9] GWDCC31.ETS, [8] GWDCC31.EDE, [1:0] GWDCC31.SM
0x874CE480 GWCA0
  [30:28] GWDCC32.OSID, [24] GWDCC32.BALR, [18:16] GWDCC32.DCP, [11] GWDCC32.DQT, [10] GWDCC32.SL, [9] GWDCC32.ETS, [8] GWDCC32.EDE, [1:0] GWDCC32.SM
0x874CE484 GWCA0
  [30:28] GWDCC33.OSID, [24] GWDCC33.BALR, [18:16] GWDCC33.DCP, [11] GWDCC33.DQT, [10] GWDCC33.SL, [9] GWDCC33.ETS, [8] GWDCC33.EDE, [1:0] GWDCC33.SM
0x874CE488 GWCA0
  [30:28] GWDCC34.OSID, [24] GWDCC34.BALR, [18:16] GWDCC34.DCP, [11] GWDCC34.DQT, [10] GWDCC34.SL, [9] GWDCC34.ETS, [8] GWDCC34.EDE, [1:0] GWDCC34.SM
0x874CE48C GWCA0
  [30:28] GWDCC35.OSID, [24] GWDCC35.BALR, [18:16] GWDCC35.DCP, [11] GWDCC35.DQT, [10] GWDCC35.SL, [9] GWDCC35.ETS, [8] GWDCC35.EDE, [1:0] GWDCC35.SM
0x874CE490 GWCA0
  [30:28] GWDCC36.OSID, [24] GWDCC36.BALR, [18:16] GWDCC36.DCP, [11] GWDCC36.DQT, [10] GWDCC36.SL, [9] GWDCC36.ETS, [8] GWDCC36.EDE, [1:0] GWDCC36.SM
0x874CE494 GWCA0
  [30:28] GWDCC37.OSID, [24] GWDCC37.BALR, [18:16] GWDCC37.DCP, [11] GWDCC37.DQT, [10] GWDCC37.SL, [9] GWDCC37.ETS, [8] GWDCC37.EDE, [1:0] GWDCC37.SM
0x874CE498 GWCA0
  [30:28] GWDCC38.OSID, [24] GWDCC38.BALR, [18:16] GWDCC38.DCP, [11] GWDCC38.DQT, [10] GWDCC38.SL, [9] GWDCC38.ETS, [8] GWDCC38.EDE, [1:0] GWDCC38.SM
0x874CE49C GWCA0
  [30:28] GWDCC39.OSID, [24] GWDCC39.BALR, [18:16] GWDCC39.DCP, [11] GWDCC39.DQT, [10] GWDCC39.SL, [9] GWDCC39.ETS, [8] GWDCC39.EDE, [1:0] GWDCC39.SM
0x874CE4A0 GWCA0
  [30:28] GWDCC40.OSID, [24] GWDCC40.BALR, [18:16] GWDCC40.DCP, [11] GWDCC40.DQT, [10] GWDCC40.SL, [9] GWDCC40.ETS, [8] GWDCC40.EDE, [1:0] GWDCC40.SM
0x874CE4A4 GWCA0
  [30:28] GWDCC41.OSID, [24] GWDCC41.BALR, [18:16] GWDCC41.DCP, [11] GWDCC41.DQT, [10] GWDCC41.SL, [9] GWDCC41.ETS, [8] GWDCC41.EDE, [1:0] GWDCC41.SM
0x874CE4A8 GWCA0
  [30:28] GWDCC42.OSID, [24] GWDCC42.BALR, [18:16] GWDCC42.DCP, [11] GWDCC42.DQT, [10] GWDCC42.SL, [9] GWDCC42.ETS, [8] GWDCC42.EDE, [1:0] GWDCC42.SM
0x874CE4AC GWCA0
  [30:28] GWDCC43.OSID, [24] GWDCC43.BALR, [18:16] GWDCC43.DCP, [11] GWDCC43.DQT, [10] GWDCC43.SL, [9] GWDCC43.ETS, [8] GWDCC43.EDE, [1:0] GWDCC43.SM
0x874CE4B0 GWCA0
  [30:28] GWDCC44.OSID, [24] GWDCC44.BALR, [18:16] GWDCC44.DCP, [11] GWDCC44.DQT, [10] GWDCC44.SL, [9] GWDCC44.ETS, [8] GWDCC44.EDE, [1:0] GWDCC44.SM
0x874CE4B4 GWCA0
  [30:28] GWDCC45.OSID, [24] GWDCC45.BALR, [18:16] GWDCC45.DCP, [11] GWDCC45.DQT, [10] GWDCC45.SL, [9] GWDCC45.ETS, [8] GWDCC45.EDE, [1:0] GWDCC45.SM
0x874CE4B8 GWCA0
  [30:28] GWDCC46.OSID, [24] GWDCC46.BALR, [18:16] GWDCC46.DCP, [11] GWDCC46.DQT, [10] GWDCC46.SL, [9] GWDCC46.ETS, [8] GWDCC46.EDE, [1:0] GWDCC46.SM
0x874CE4BC GWCA0
  [30:28] GWDCC47.OSID, [24] GWDCC47.BALR, [18:16] GWDCC47.DCP, [11] GWDCC47.DQT, [10] GWDCC47.SL, [9] GWDCC47.ETS, [8] GWDCC47.EDE, [1:0] GWDCC47.SM
0x874CE4C0 GWCA0
  [30:28] GWDCC48.OSID, [24] GWDCC48.BALR, [18:16] GWDCC48.DCP, [11] GWDCC48.DQT, [10] GWDCC48.SL, [9] GWDCC48.ETS, [8] GWDCC48.EDE, [1:0] GWDCC48.SM
0x874CE4C4 GWCA0
  [30:28] GWDCC49.OSID, [24] GWDCC49.BALR, [18:16] GWDCC49.DCP, [11] GWDCC49.DQT, [10] GWDCC49.SL, [9] GWDCC49.ETS, [8] GWDCC49.EDE, [1:0] GWDCC49.SM
0x874CE4C8 GWCA0
  [30:28] GWDCC50.OSID, [24] GWDCC50.BALR, [18:16] GWDCC50.DCP, [11] GWDCC50.DQT, [10] GWDCC50.SL, [9] GWDCC50.ETS, [8] GWDCC50.EDE, [1:0] GWDCC50.SM
0x874CE4CC GWCA0
  [30:28] GWDCC51.OSID, [24] GWDCC51.BALR, [18:16] GWDCC51.DCP, [11] GWDCC51.DQT, [10] GWDCC51.SL, [9] GWDCC51.ETS, [8] GWDCC51.EDE, [1:0] GWDCC51.SM
0x874CE4D0 GWCA0
  [30:28] GWDCC52.OSID, [24] GWDCC52.BALR, [18:16] GWDCC52.DCP, [11] GWDCC52.DQT, [10] GWDCC52.SL, [9] GWDCC52.ETS, [8] GWDCC52.EDE, [1:0] GWDCC52.SM
0x874CE4D4 GWCA0
  [30:28] GWDCC53.OSID, [24] GWDCC53.BALR, [18:16] GWDCC53.DCP, [11] GWDCC53.DQT, [10] GWDCC53.SL, [9] GWDCC53.ETS, [8] GWDCC53.EDE, [1:0] GWDCC53.SM
0x874CE4D8 GWCA0
  [30:28] GWDCC54.OSID, [24] GWDCC54.BALR, [18:16] GWDCC54.DCP, [11] GWDCC54.DQT, [10] GWDCC54.SL, [9] GWDCC54.ETS, [8] GWDCC54.EDE, [1:0] GWDCC54.SM
0x874CE4DC GWCA0
  [30:28] GWDCC55.OSID, [24] GWDCC55.BALR, [18:16] GWDCC55.DCP, [11] GWDCC55.DQT, [10] GWDCC55.SL, [9] GWDCC55.ETS, [8] GWDCC55.EDE, [1:0] GWDCC55.SM
0x874CE4E0 GWCA0
  [30:28] GWDCC56.OSID, [24] GWDCC56.BALR, [18:16] GWDCC56.DCP, [11] GWDCC56.DQT, [10] GWDCC56.SL, [9] GWDCC56.ETS, [8] GWDCC56.EDE, [1:0] GWDCC56.SM
0x874CE4E4 GWCA0
  [30:28] GWDCC57.OSID, [24] GWDCC57.BALR, [18:16] GWDCC57.DCP, [11] GWDCC57.DQT, [10] GWDCC57.SL, [9] GWDCC57.ETS, [8] GWDCC57.EDE, [1:0] GWDCC57.SM
0x874CE4E8 GWCA0
  [30:28] GWDCC58.OSID, [24] GWDCC58.BALR, [18:16] GWDCC58.DCP, [11] GWDCC58.DQT, [10] GWDCC58.SL, [9] GWDCC58.ETS, [8] GWDCC58.EDE, [1:0] GWDCC58.SM
0x874CE4EC GWCA0
  [30:28] GWDCC59.OSID, [24] GWDCC59.BALR, [18:16] GWDCC59.DCP, [11] GWDCC59.DQT, [10] GWDCC59.SL, [9] GWDCC59.ETS, [8] GWDCC59.EDE, [1:0] GWDCC59.SM
0x874CE4F0 GWCA0
  [30:28] GWDCC60.OSID, [24] GWDCC60.BALR, [18:16] GWDCC60.DCP, [11] GWDCC60.DQT, [10] GWDCC60.SL, [9] GWDCC60.ETS, [8] GWDCC60.EDE, [1:0] GWDCC60.SM
0x874CE4F4 GWCA0
  [30:28] GWDCC61.OSID, [24] GWDCC61.BALR, [18:16] GWDCC61.DCP, [11] GWDCC61.DQT, [10] GWDCC61.SL, [9] GWDCC61.ETS, [8] GWDCC61.EDE, [1:0] GWDCC61.SM
0x874CE4F8 GWCA0
  [30:28] GWDCC62.OSID, [24] GWDCC62.BALR, [18:16] GWDCC62.DCP, [11] GWDCC62.DQT, [10] GWDCC62.SL, [9] GWDCC62.ETS, [8] GWDCC62.EDE, [1:0] GWDCC62.SM
0x874CE4FC GWCA0
  [30:28] GWDCC63.OSID, [24] GWDCC63.BALR, [18:16] GWDCC63.DCP, [11] GWDCC63.DQT, [10] GWDCC63.SL, [9] GWDCC63.ETS, [8] GWDCC63.EDE, [1:0] GWDCC63.SM
0x874CE800 GWCA0
  [5:0] GWAARSS.AARA
0x874CE804 GWCA0
  [31] GWAARSR0.AARS, [17] GWAARSR0.AARSSF, [16] GWAARSR0.AARSEF, [7:0] GWAARSR0.ACARU
0x874CE808 GWCA0
  [31:0] GWAARSR1.ACARD
0x874CE840 GWCA0
  [23:0] GWIDAUAS0.IDAUAS
0x874CE844 GWCA0
  [23:0] GWIDAUAS1.IDAUAS
0x874CE848 GWCA0
  [23:0] GWIDAUAS2.IDAUAS
0x874CE84C GWCA0
  [23:0] GWIDAUAS3.IDAUAS
0x874CE880 GWCA0
  [23:0] GWIDASM0.IDAS
0x874CE884 GWCA0
  [23:0] GWIDASM1.IDAS
0x874CE888 GWCA0
  [23:0] GWIDASM2.IDAS
0x874CE88C GWCA0
  [23:0] GWIDASM3.IDAS
0x874CE900 GWCA0
  [7:0] GWIDASAM00.IDASAU
0x874CE904 GWCA0
  [31:0] GWIDASAM01.IDASAL
0x874CE908 GWCA0
  [7:0] GWIDASAM10.IDASAU
0x874CE90C GWCA0
  [31:0] GWIDASAM11.IDASAL
0x874CE910 GWCA0
  [7:0] GWIDASAM20.IDASAU
0x874CE914 GWCA0
  [31:0] GWIDASAM21.IDASAL
0x874CE918 GWCA0
  [7:0] GWIDASAM30.IDASAU
0x874CE91C GWCA0
  [31:0] GWIDASAM31.IDASAL
0x874CE980 GWCA0
  [7:0] GWIDACAM00.IDACAU
0x874CE984 GWCA0
  [31:0] GWIDACAM01.IDACAL
0x874CE988 GWCA0
  [7:0] GWIDACAM10.IDACAU
0x874CE98C GWCA0
  [31:0] GWIDACAM11.IDACAL
0x874CE990 GWCA0
  [7:0] GWIDACAM20.IDACAU
0x874CE994 GWCA0
  [31:0] GWIDACAM21.IDACAL
0x874CE998 GWCA0
  [7:0] GWIDACAM30.IDACAU
0x874CE99C GWCA0
  [31:0] GWIDACAM31.IDACAL
0x874CEA00 GWCA0
  [17] GWGRLC.GRLULRS, [16] GWGRLC.GRLE, [15:0] GWGRLC.GRLIV
0x874CEA04 GWCA0
  [23:0] GWGRLULC.GRLUL
0x874CEA80 GWCA0
  [16] GWRLC0.RLE, [11:0] GWRLC0.RLIV
0x874CEA84 GWCA0
  [23:0] GWRLULC0.RLUL
0x874CEA88 GWCA0
  [16] GWRLC1.RLE, [11:0] GWRLC1.RLIV
0x874CEA8C GWCA0
  [23:0] GWRLULC1.RLUL
0x874CEA90 GWCA0
  [16] GWRLC2.RLE, [11:0] GWRLC2.RLIV
0x874CEA94 GWCA0
  [23:0] GWRLULC2.RLUL
0x874CEA98 GWCA0
  [16] GWRLC3.RLE, [11:0] GWRLC3.RLIV
0x874CEA9C GWCA0
  [23:0] GWRLULC3.RLUL
0x874CEAA0 GWCA0
  [16] GWRLC4.RLE, [11:0] GWRLC4.RLIV
0x874CEAA4 GWCA0
  [23:0] GWRLULC4.RLUL
0x874CEAA8 GWCA0
  [16] GWRLC5.RLE, [11:0] GWRLC5.RLIV
0x874CEAAC GWCA0
  [23:0] GWRLULC5.RLUL
0x874CEAB0 GWCA0
  [16] GWRLC6.RLE, [11:0] GWRLC6.RLIV
0x874CEAB4 GWCA0
  [23:0] GWRLULC6.RLUL
0x874CEAB8 GWCA0
  [16] GWRLC7.RLE, [11:0] GWRLC7.RLIV
0x874CEABC GWCA0
  [23:0] GWRLULC7.RLUL
0x874CEB80 GWCA0
  [9:0] GWIDPC.IDPV
0x874CEC00 GWCA0
  [11:0] GWIDC0.IDV
0x874CEC04 GWCA0
  [11:0] GWIDC1.IDV
0x874CEC08 GWCA0
  [11:0] GWIDC2.IDV
0x874CEC0C GWCA0
  [11:0] GWIDC3.IDV
0x874CEC10 GWCA0
  [11:0] GWIDC4.IDV
0x874CEC14 GWCA0
  [11:0] GWIDC5.IDV
0x874CEC18 GWCA0
  [11:0] GWIDC6.IDV
0x874CEC1C GWCA0
  [11:0] GWIDC7.IDV
0x874CEC20 GWCA0
  [11:0] GWIDC8.IDV
0x874CEC24 GWCA0
  [11:0] GWIDC9.IDV
0x874CEC28 GWCA0
  [11:0] GWIDC10.IDV
0x874CEC2C GWCA0
  [11:0] GWIDC11.IDV
0x874CEC30 GWCA0
  [11:0] GWIDC12.IDV
0x874CEC34 GWCA0
  [11:0] GWIDC13.IDV
0x874CEC38 GWCA0
  [11:0] GWIDC14.IDV
0x874CEC3C GWCA0
  [11:0] GWIDC15.IDV
0x874CEC40 GWCA0
  [11:0] GWIDC16.IDV
0x874CEC44 GWCA0
  [11:0] GWIDC17.IDV
0x874CEC48 GWCA0
  [11:0] GWIDC18.IDV
0x874CEC4C GWCA0
  [11:0] GWIDC19.IDV
0x874CEC50 GWCA0
  [11:0] GWIDC20.IDV
0x874CEC54 GWCA0
  [11:0] GWIDC21.IDV
0x874CEC58 GWCA0
  [11:0] GWIDC22.IDV
0x874CEC5C GWCA0
  [11:0] GWIDC23.IDV
0x874CEC60 GWCA0
  [11:0] GWIDC24.IDV
0x874CEC64 GWCA0
  [11:0] GWIDC25.IDV
0x874CEC68 GWCA0
  [11:0] GWIDC26.IDV
0x874CEC6C GWCA0
  [11:0] GWIDC27.IDV
0x874CEC70 GWCA0
  [11:0] GWIDC28.IDV
0x874CEC74 GWCA0
  [11:0] GWIDC29.IDV
0x874CEC78 GWCA0
  [11:0] GWIDC30.IDV
0x874CEC7C GWCA0
  [11:0] GWIDC31.IDV
0x874CEC80 GWCA0
  [11:0] GWIDC32.IDV
0x874CEC84 GWCA0
  [11:0] GWIDC33.IDV
0x874CEC88 GWCA0
  [11:0] GWIDC34.IDV
0x874CEC8C GWCA0
  [11:0] GWIDC35.IDV
0x874CEC90 GWCA0
  [11:0] GWIDC36.IDV
0x874CEC94 GWCA0
  [11:0] GWIDC37.IDV
0x874CEC98 GWCA0
  [11:0] GWIDC38.IDV
0x874CEC9C GWCA0
  [11:0] GWIDC39.IDV
0x874CECA0 GWCA0
  [11:0] GWIDC40.IDV
0x874CECA4 GWCA0
  [11:0] GWIDC41.IDV
0x874CECA8 GWCA0
  [11:0] GWIDC42.IDV
0x874CECAC GWCA0
  [11:0] GWIDC43.IDV
0x874CECB0 GWCA0
  [11:0] GWIDC44.IDV
0x874CECB4 GWCA0
  [11:0] GWIDC45.IDV
0x874CECB8 GWCA0
  [11:0] GWIDC46.IDV
0x874CECBC GWCA0
  [11:0] GWIDC47.IDV
0x874CECC0 GWCA0
  [11:0] GWIDC48.IDV
0x874CECC4 GWCA0
  [11:0] GWIDC49.IDV
0x874CECC8 GWCA0
  [11:0] GWIDC50.IDV
0x874CECCC GWCA0
  [11:0] GWIDC51.IDV
0x874CECD0 GWCA0
  [11:0] GWIDC52.IDV
0x874CECD4 GWCA0
  [11:0] GWIDC53.IDV
0x874CECD8 GWCA0
  [11:0] GWIDC54.IDV
0x874CECDC GWCA0
  [11:0] GWIDC55.IDV
0x874CECE0 GWCA0
  [11:0] GWIDC56.IDV
0x874CECE4 GWCA0
  [11:0] GWIDC57.IDV
0x874CECE8 GWCA0
  [11:0] GWIDC58.IDV
0x874CECEC GWCA0
  [11:0] GWIDC59.IDV
0x874CECF0 GWCA0
  [11:0] GWIDC60.IDV
0x874CECF4 GWCA0
  [11:0] GWIDC61.IDV
0x874CECF8 GWCA0
  [11:0] GWIDC62.IDV
0x874CECFC GWCA0
  [11:0] GWIDC63.IDV
0x874CED00 GWCA0
  [11:0] GWIDC64.IDV
0x874CF000 GWCA0
  [31:0] GWRDCN.RDN
0x874CF004 GWCA0
  [31:0] GWTDCN.TDN
0x874CF008 GWCA0
  [31:0] GWTSCN.TN
0x874CF00C GWCA0
  [15:0] GWTSOVFECN.TSOVFEN
0x874CF010 GWCA0
  [15:0] GWUSMFSECN.USMFSEN
0x874CF014 GWCA0
  [15:0] GWTFECN.TFEN
0x874CF018 GWCA0
  [15:0] GWSEQECN.SEQEN
0x874CF020 GWCA0
  [15:0] GWTXDNECN.TXDNEN
0x874CF024 GWCA0
  [15:0] GWFSECN.FSEN
0x874CF028 GWCA0
  [15:0] GWTDFECN.TDFEN
0x874CF02C GWCA0
  [15:0] GWTSDNECN.TSDNEN
0x874CF030 GWCA0
  [15:0] GWDQOECN.DQOEN
0x874CF034 GWCA0
  [15:0] GWDQSECN.DQSEN
0x874CF038 GWCA0
  [15:0] GWDFECN.DFEN
0x874CF03C GWCA0
  [15:0] GWDSECN.DSEN
0x874CF040 GWCA0
  [15:0] GWDSZECN.DSZEN
0x874CF044 GWCA0
  [15:0] GWDCTECN.DCTEN
0x874CF048 GWCA0
  [15:0] GWRXDNECN.RXDNEN
0x874CF180 GWCA0
  [1] GWTSDIS.TSDIS1, [0] GWTSDIS.TSDIS0
0x874CF184 GWCA0
  [1] GWTSDIE.TSDIE1, [0] GWTSDIE.TSDIE0
0x874CF188 GWCA0
  [1] GWTSDID.TSDID1, [0] GWTSDID.TSDID0
0x874CF190 GWCA0
  [31] GWEIS0.CKSES, [29] GWEIS0.TSDNES1, [28] GWEIS0.TSDNES0, [25] GWEIS0.TDFES1, [24] GWEIS0.TDFES0, [n+16] GWEIS0.FSES{n} (n=0..7), [15] GWEIS0.TSHES, [14] GWEIS0.TXDNES, [13] GWEIS0.IIPES, [12] GWEIS0.SEQES, [11] GWEIS0.TFES, [10] GWEIS0.USMFSES, [9] GWEIS0.TSOVFES, [8] GWEIS0.L23UECCES, [7] GWEIS0.TSECCES, [6] GWEIS0.AECCES, [5] GWEIS0.MECCES, [4] GWEIS0.DSECCES, [3] GWEIS0.PECCES, [2] GWEIS0.TECCES, [1] GWEIS0.DECCES, [0] GWEIS0.AES
0x874CF194 GWCA0
  [31] GWEIE0.CKSEE, [29] GWEIE0.TSDNEE1, [28] GWEIE0.TSDNEE0, [25] GWEIE0.TDFEE1, [24] GWEIE0.TDFEE0, [n+16] GWEIE0.FSEE{n} (n=0..7), [15] GWEIE0.TSHEE, [14] GWEIE0.TXDNEE, [13] GWEIE0.IIPEE, [12] GWEIE0.SEQEE, [11] GWEIE0.TFEE, [10] GWEIE0.USMFSEE, [9] GWEIE0.TSOVFEE, [8] GWEIE0.L23UECCEE, [7] GWEIE0.TSECCEE, [6] GWEIE0.AECCEE, [5] GWEIE0.MECCEE, [4] GWEIE0.DSECCEE, [3] GWEIE0.PECCEE, [2] GWEIE0.TECCEE, [1] GWEIE0.DECCEE, [0] GWEIE0.AEE
0x874CF198 GWCA0
  [31] GWEID0.CKSED, [29] GWEID0.TSDNED1, [28] GWEID0.TSDNED0, [25] GWEID0.TDFED1, [24] GWEID0.TDFED0, [n+16] GWEID0.FSED{n} (n=0..7), [15] GWEID0.TSHED, [14] GWEID0.TXDNED, [13] GWEID0.IIPED, [12] GWEID0.SEQED, [11] GWEID0.TFED, [10] GWEID0.USMFSED, [9] GWEID0.TSOVFED, [8] GWEID0.L23UECCED, [7] GWEID0.TSECCED, [6] GWEID0.AECCED, [5] GWEID0.MECCED, [4] GWEID0.DSECCED, [3] GWEID0.PECCED, [2] GWEID0.DECCED, [1] GWEID0.TECCED, [0] GWEID0.AED
0x874CF1A0 GWCA0
  [n+16] GWEIS1.DQSES{n} (n=0..7), [n] GWEIS1.DQOES{n} (n=0..7)
0x874CF1A4 GWCA0
  [n+16] GWEIE1.DQSEE{n} (n=0..7), [n] GWEIE1.DQOEE{n} (n=0..7)
0x874CF1A8 GWCA0
  [n+16] GWEID1.DQSED{n} (n=0..7), [n] GWEID1.DQOED{n} (n=0..7)
0x874CF280 GWCA0
  [n] GWEIS3.IAOES{n} (n=0..3)
0x874CF284 GWCA0
  [n] GWEIE3.IAOEE{n} (n=0..3)
0x874CF288 GWCA0
  [n] GWEID3.IAOED{n} (n=0..3)
0x874CF290 GWCA0
  [29:24] GWEIS4.DSECN, [17] GWEIS4.DSEIOS, [16] GWEIS4.DSES, [13:8] GWEIS4.DSSECN, [1] GWEIS4.DSSEIOS, [0] GWEIS4.DSSES
0x874CF294 GWCA0
  [17] GWEIE4.DSEIOE, [16] GWEIE4.DSEE, [1] GWEIE4.DSSEIOE, [0] GWEIE4.DSSEE
0x874CF298 GWCA0
  [17] GWEID4.DSEIOD, [16] GWEID4.DSED, [1] GWEID4.DSSEIOD, [0] GWEID4.DSSED
0x874CF2A0 GWCA0
  [17] GWEIS5.RXDNEIOS, [16] GWEIS5.RXDNES, [13:8] GWEIS5.DCTECN, [1] GWEIS5.DCTEIOS, [0] GWEIS5.DCTES
0x874CF2A4 GWCA0
  [17] GWEIE5.RXDNEIOE, [16] GWEIE5.RXDNEE, [1] GWEIE5.DCTEIOE, [0] GWEIE5.DCTEE
0x874CF2A8 GWCA0
  [16] GWEID5.RXDNEIOD, [15] GWEID5.RXDNED, [1] GWEID5.DCTEIOD, [0] GWEID5.DCTED
0x874E0000 GPTP
  [31:0] PTPIPV.IPV
0x874E0010 GPTP
  [1] PTPTMEC.TE1, [0] PTPTMEC.TE0
0x874E0014 GPTP
  [1] PTPTMDC.TD1, [0] PTPTMDC.TD0
0x874E0020 GPTP
  [31:0] PTPTIVC0.TIV
0x874E0030 GPTP
  [29:0] PTPTOVC0L.TOVPL
0x874E0034 GPTP
  [31:0] PTPTOVC0M.TOVPM
0x874E0038 GPTP
  [15:0] PTPTOVC0U.TOVPU
0x874E0040 GPTP
  [31:0] PTPAVTPTM0L.AVTPL
0x874E0044 GPTP
  [31:0] PTPAVTPTM0U.AVTPU
0x874E0050 GPTP
  [29:0] PTPGPTPTM0L.GPTPL
0x874E0054 GPTP
  [31:0] PTPGPTPTM0M.GPTPM
0x874E0058 GPTP
  [15:0] PTPGPTPTM0U.GPTPU
0x874E0060 GPTP
  [31:0] PTPTIVC1.TIV
0x874E0070 GPTP
  [29:0] PTPTOVC1L.TOVPL
0x874E0074 GPTP
  [31:0] PTPTOVC1M.TOVPM
0x874E0078 GPTP
  [15:0] PTPTOVC1U.TOVPU
0x874E0080 GPTP
  [31:0] PTPAVTPTM1L.AVTPL
0x874E0084 GPTP
  [31:0] PTPAVTPTM1U.AVTPU
0x874E0090 GPTP
  [29:0] PTPGPTPTM1L.GPTPL
0x874E0094 GPTP
  [31:0] PTPGPTPTM1M.GPTPM
0x874E0098 GPTP
  [15:0] PTPGPTPTM1U.GPTPU
0x874E0200 GPTP
  [16] PTPMCCC0.MCCR, [3] PTPMCCC0.MCTNS, [2] PTPMCCC0.MCTTS, [1] PTPMCCC0.MCNEE, [0] PTPMCCC0.MCPEE
0x874E0204 GPTP
  [31:0] PTPMCCM0L.MCCTVP0
0x874E0208 GPTP
  [31:0] PTPMCCM0M.MCCTVM
0x874E020C GPTP
  [25:24] PTPMCCM0U.MCCN, [18] PTPMCCM0U.MCSWC, [17] PTPMCCM0U.MCNEC, [16] PTPMCCM0U.MCPEC, [15:0] PTPMCCM0U.MCCTVU
0x874E0210 GPTP
  [16] PTPMCCC1.MCCR, [3] PTPMCCC1.MCTNS, [2] PTPMCCC1.MCTTS, [1] PTPMCCC1.MCNEE, [0] PTPMCCC1.MCPEE
0x874E0214 GPTP
  [31:0] PTPMCCM1L.MCCTVL
0x874E0218 GPTP
  [31:0] PTPMCCM1M.MCCTVM
0x874E021C GPTP
  [25:24] PTPMCCM1U.MCCN, [18] PTPMCCM1U.MCSWC, [17] PTPMCCM1U.MCNEC, [16] PTPMCCM1U.MCPEC, [15:0] PTPMCCM1U.MCCTVU
0x874E0300 GPTP
  [31:16] PTPMCRC0.MRPL, [2] PTPMCRC0.MRTNS, [1] PTPMCRC0.MRAMS, [0] PTPMCRC0.MRTTS
0x874E0304 GPTP
  [31:0] PTPMCRTC0L.MRTVL
0x874E0308 GPTP
  [31:0] PTPMCRTC0M.MRTVM
0x874E030C GPTP
  [31] PTPMCRTC0U.MRBCR, [20:18] PTPMCRTC0U.MCRN, [17:16] PTPMCRTC0U.MRTT, [15:0] PTPMCRTC0U.MCCTVU
0x874E0310 GPTP
  [31:16] PTPMCRC1.MRPL, [2] PTPMCRC1.MRTNS, [1] PTPMCRC1.MRAMS, [0] PTPMCRC1.MRTTS
0x874E0314 GPTP
  [31:0] PTPMCRTC1L.MRTVL
0x874E0318 GPTP
  [31:0] PTPMCRTC1M.MRTVM
0x874E031C GPTP
  [31] PTPMCRTC1U.MRBCR, [20:18] PTPMCRTC1U.MCRN, [17:16] PTPMCRTC1U.MRTT, [15:0] PTPMCRTC1U.MCCTVU
0x874E0400 GPTP
  [1] PTPMCPC0.MRS, [0] PTPMCPC0.PE
0x874E0404 GPTP
  [1] PTPMCPC1.MRS, [0] PTPMCPC1.PE
0x874E0500 GPTP
  [4] PTPCCC00.CCOPS, [0] PTPCCC00.CCTNS
0x874E0504 GPTP
  [31:0] PTPCCC01.CCV
0x874E0508 GPTP
  [4] PTPCCC10.CCOPS, [0] PTPCCC10.CCTNS
0x874E050C GPTP
  [31:0] PTPCCC11.CCV
0x874E0510 GPTP
  [4] PTPCCC20.CCOPS, [0] PTPCCC20.CCTNS
0x874E0514 GPTP
  [31:0] PTPCCC21.CCV
0x874E0518 GPTP
  [4] PTPCCC30.CCOPS, [0] PTPCCC30.CCTNS
0x874E051C GPTP
  [31:0] PTPCCC31.CCV
0x874E0520 GPTP
  [4] PTPCCC40.CCOPS, [0] PTPCCC40.CCTNS
0x874E0524 GPTP
  [31:0] PTPCCC41.CCV
0x874E0528 GPTP
  [4] PTPCCC50.CCOPS, [0] PTPCCC50.CCTNS
0x874E052C GPTP
  [31:0] PTPCCC51.CCV
0x874E0530 GPTP
  [4] PTPCCC60.CCOPS, [0] PTPCCC60.CCTNS
0x874E0534 GPTP
  [31:0] PTPCCC61.CCV
0x874E0538 GPTP
  [4] PTPCCC70.CCOPS, [0] PTPCCC70.CCTNS
0x874E053C GPTP
  [31:0] PTPCCC71.CCV
0x874E0700 GPTP
  [16] PTPIS0.MCCOES0, [1] PTPIS0.MCCS1, [0] PTPIS0.MCCS0
0x874E0704 GPTP
  [16] PTPIE0.MCCOEE0, [1] PTPIE0.MCCE1, [0] PTPIE0.MCCE0
0x874E0708 GPTP
  [16] PTPID0.MCCOED0, [1] PTPID0.MCCD1, [0] PTPID0.MCCD0
0x874E0710 GPTP
  [1] PTPIS1.MCRMS1, [0] PTPIS1.MCRMS0
0x874E0714 GPTP
  [1] PTPIE1.MCRME1, [0] PTPIE1.MCRME0
0x874E0718 GPTP
  [1] PTPID1.MCRMD1, [0] PTPID1.MCRMD0
0x874E0780 GPTP
  [17] PTPSCR0.MCRSL1, [16] PTPSCR0.MCRSL0, [1] PTPSCR0.TRSL1, [0] PTPSCR0.TRSL0
0x874E0784 GPTP
  [17] PTPSCR1.MRRRSL1, [16] PTPSCR1.MRRRSL0, [1] PTPSCR1.MRRSL1, [0] PTPSCR1.MRRSL0
0x874E0788 GPTP
  [16] PTPSCR2.VRSL, [1] PTPSCR2.CCRSL1, [0] PTPSCR2.CCRSL0
0x874E1000 GPTP
  [0] POTCFGR.REFSEL
0x874E1004 GPTP
  [0] POTCR0.START
0x874E1034 GPTP
  [0] POTCR1.START
0x874E1064 GPTP
  [0] POTCR2.START
0x874E1094 GPTP
  [0] POTCR3.START
0x874E1400 ESWM
  [9] MIIRR.RMRST1, [8] MIIRR.RMRST0, [1] MIIRR.RGRST1, [0] MIIRR.RGRST0
0x874E1404 ESWM
  [12] MIICR0.TXCIDE, [8] MIICR0.DIVSTP, [1:0] MIICR0.MIISEL
0x874E1408 ESWM
  [12] MIICR1.TXCIDE, [8] MIICR1.DIVSTP, [1:0] MIICR1.MIISEL
0x874E1410 ESWM
  [1] MCCESR.MCCES1, [0] MCCESR.MCCES0
0x874E1420 ESWM
  [8n+4:8n] TASSTSR.MSS{n} (n=0..3)
0x87801000 ELC 8-bit
  [7] ELCR.ELCON
0x87801004 ELC 8-bit
  [7] ELSEGR0.WI, [6] ELSEGR0.WE, [0] ELSEGR0.SEG
0x87801008 ELC 8-bit
  [7] ELSEGR1.WI, [6] ELSEGR1.WE, [0] ELSEGR1.SEG
0x8780100C ELC 8-bit
  [7] ELSEGR2.WI, [6] ELSEGR2.WE, [0] ELSEGR2.SEG
0x87801010 ELC 8-bit
  [7] ELSEGR3.WI, [6] ELSEGR3.WE, [0] ELSEGR3.SEG
0x87801030 ELC
  [19] ELCSARA.ELOPD, [18] ELCSARA.ELOPC, [17] ELCSARA.ELOPB, [16] ELCSARA.ELOPA, [n+1] ELCSARA.ELSEGR{n} (n=0..3), [0] ELCSARA.ELCR
0x87801034 ELC
  [n] ELCSARB.ELSR{n} (n=0..26)
0x87801038 ELC
  [n-32] ELCSARC.ELSR{n} (n=50..63), [15] ELCSARC.ELSR47, [14] ELCSARC.ELSR46
0x8780103C ELC
  [n-64] ELCSARD.ELSR{n} (n=88..91), [n-64] ELCSARD.ELSR{n} (n=64..78)
0x87801090 ELC 8-bit
  [3:2] ELOPA.CMT1MD
0x87801094 ELC 8-bit
  [1:0] ELOPB.CMTW0MD
0x87801098 ELC 8-bit
  [3:2] ELOPC.TMR1MD, [1:0] ELOPC.TMR0MD
0x8780109C ELC 8-bit
  [3:2] ELOPD.TMR3MD, [1:0] ELOPD.TMR2MD
0x87801100 ELC 16-bit
  [9:0] ELSR0.ELS
0x87801104 ELC 16-bit
  [9:0] ELSR1.ELS
0x87801108 ELC 16-bit
  [9:0] ELSR2.ELS
0x8780110C ELC 16-bit
  [9:0] ELSR3.ELS
0x87801110 ELC 16-bit
  [9:0] ELSR4.ELS
0x87801114 ELC 16-bit
  [9:0] ELSR5.ELS
0x87801118 ELC 16-bit
  [9:0] ELSR6.ELS
0x8780111C ELC 16-bit
  [9:0] ELSR7.ELS
0x87801120 ELC 16-bit
  [9:0] ELSR8.ELS
0x87801124 ELC 16-bit
  [9:0] ELSR9.ELS
0x87801128 ELC 16-bit
  [9:0] ELSR10.ELS
0x8780112C ELC 16-bit
  [9:0] ELSR11.ELS
0x87801130 ELC 16-bit
  [9:0] ELSR12.ELS
0x87801134 ELC 16-bit
  [9:0] ELSR13.ELS
0x87801138 ELC 16-bit
  [9:0] ELSR14.ELS
0x8780113C ELC 16-bit
  [9:0] ELSR15.ELS
0x87801140 ELC 16-bit
  [9:0] ELSR16.ELS
0x87801144 ELC 16-bit
  [9:0] ELSR17.ELS
0x87801148 ELC 16-bit
  [9:0] ELSR18.ELS
0x8780114C ELC 16-bit
  [9:0] ELSR19.ELS
0x87801150 ELC 16-bit
  [9:0] ELSR20.ELS
0x87801154 ELC 16-bit
  [9:0] ELSR21.ELS
0x87801158 ELC 16-bit
  [9:0] ELSR22.ELS
0x8780115C ELC 16-bit
  [9:0] ELSR23.ELS
0x87801160 ELC 16-bit
  [9:0] ELSR24.ELS
0x87801164 ELC 16-bit
  [9:0] ELSR25.ELS
0x87801168 ELC 16-bit
  [9:0] ELSR26.ELS
0x878011B8 ELC 16-bit
  [9:0] ELSR46.ELS
0x878011BC ELC 16-bit
  [9:0] ELSR47.ELS
0x878011C8 ELC 16-bit
  [9:0] ELSR50.ELS
0x878011CC ELC 16-bit
  [9:0] ELSR51.ELS
0x878011D0 ELC 16-bit
  [9:0] ELSR52.ELS
0x878011D4 ELC 16-bit
  [9:0] ELSR53.ELS
0x878011D8 ELC 16-bit
  [9:0] ELSR54.ELS
0x878011DC ELC 16-bit
  [9:0] ELSR55.ELS
0x878011E0 ELC 16-bit
  [9:0] ELSR56.ELS
0x878011E4 ELC 16-bit
  [9:0] ELSR57.ELS
0x878011E8 ELC 16-bit
  [9:0] ELSR58.ELS
0x878011EC ELC 16-bit
  [9:0] ELSR59.ELS
0x878011F0 ELC 16-bit
  [9:0] ELSR60.ELS
0x878011F4 ELC 16-bit
  [9:0] ELSR61.ELS
0x878011F8 ELC 16-bit
  [9:0] ELSR62.ELS
0x878011FC ELC 16-bit
  [9:0] ELSR63.ELS
0x87801200 ELC 16-bit
  [9:0] ELSR64.ELS
0x87801204 ELC 16-bit
  [9:0] ELSR65.ELS
0x87801208 ELC 16-bit
  [9:0] ELSR66.ELS
0x8780120C ELC 16-bit
  [9:0] ELSR67.ELS
0x87801210 ELC 16-bit
  [9:0] ELSR68.ELS
0x87801214 ELC 16-bit
  [9:0] ELSR69.ELS
0x87801218 ELC 16-bit
  [9:0] ELSR70.ELS
0x8780121C ELC 16-bit
  [9:0] ELSR71.ELS
0x87801220 ELC 16-bit
  [9:0] ELSR72.ELS
0x87801224 ELC 16-bit
  [9:0] ELSR73.ELS
0x87801228 ELC 16-bit
  [9:0] ELSR74.ELS
0x8780122C ELC 16-bit
  [9:0] ELSR75.ELS
0x87801230 ELC 16-bit
  [9:0] ELSR76.ELS
0x87801234 ELC 16-bit
  [9:0] ELSR77.ELS
0x87801238 ELC 16-bit
  [9:0] ELSR78.ELS
0x87801260 ELC 16-bit
  [9:0] ELSR88.ELS
0x87801264 ELC 16-bit
  [9:0] ELSR89.ELS
0x87801268 ELC 16-bit
  [9:0] ELSR90.ELS
0x8780126C ELC 16-bit
  [9:0] ELSR91.ELS
0x87802000 RTC 8-bit
  [6] R64CNT.F1HZ, [5] R64CNT.F2HZ, [4] R64CNT.F4HZ, [3] R64CNT.F8HZ, [2] R64CNT.F16HZ, [1] R64CNT.F32HZ, [0] R64CNT.F64HZ
0x87802002 RTC 8-bit
  [6:4] RSECCNT.SEC10, [7:0] BCNT0.BCNT, [3:0] RSECCNT.SEC1
0x87802004 RTC 8-bit
  [6:4] RMINCNT.MIN10, [7:0] BCNT1.BCNT, [3:0] RMINCNT.MIN1
0x87802006 RTC 8-bit
  [6] RHRCNT.PM, [5:4] RHRCNT.HR10, [7:0] BCNT2.BCNT, [3:0] RHRCNT.HR1
0x87802008 RTC 8-bit
  [2:0] RWKCNT.DAYW
0x87802202 IWDT 16-bit
  [13:12] IWDTCR.RPSS, [9:8] IWDTCR.RPES, [7:4] IWDTCR.CKS, [1:0] IWDTCR.TOPS
0x87802204 IWDT 16-bit
  [15] IWDTSR.REFEF, [14] IWDTSR.UNDFF, [13:0] IWDTSR.CNTVAL
0x87802206 IWDT 8-bit
  [7] IWDTRCR.RSTIRQS
0x87802208 IWDT 8-bit
  [7] IWDTCSTPR.SLCSTP
{0x87802400+0x80*i} CAC{i} 8-bit (i=0..2)
  [0] CACR0.CFME
{0x87802401+0x80*i} CAC{i} 8-bit (i=0..2)
  [7:6] CACR1.EDGES, [5:4] CACR1.TCSS, [3:1] CACR1.FMCS, [0] CACR1.CACREFE
{0x87802402+0x80*i} CAC{i} 8-bit (i=0..2)
  [7:6] CACR2.DFS, [5:4] CACR2.RCDS, [3:1] CACR2.RSCS, [0] CACR2.RPS
{0x87802403+0x80*i} CAC{i} 8-bit (i=0..2)
  [6] CAICR.OVFFCL, [5] CAICR.MENDFCL, [4] CAICR.FERRFCL, [2] CAICR.OVFIE, [1] CAICR.MENDIE, [0] CAICR.FERRIE
{0x87802404+0x80*i} CAC{i} 8-bit (i=0..2)
  [2] CASTR.OVFF, [1] CASTR.MENDF, [0] CASTR.FERRF
0x87802602 WDT 16-bit
  [13:12] WDTCR.RPSS, [9:8] WDTCR.RPES, [7:4] WDTCR.CKS, [1:0] WDTCR.TOPS
0x87802604 WDT 16-bit
  [15] WDTSR.REFEF, [14] WDTSR.UNDFF, [13:0] WDTSR.CNTVAL
0x87802606 WDT 8-bit
  [7] WDTRCR.RSTIRQS
0x87802608 WDT 8-bit
  [7] WDTCSTPR.SLCSTP
0x87803000 MSTPREG
  [29] MSTPCRA.MSTPA29(EXDMAC), [22] MSTPCRA.MSTPA22(DMAC0), [1] MSTPCRA.MSTPA1(SRAM1), [0] MSTPCRA.MSTPA0(SRAM0)
0x87803004 MSTPREG
  [31] MSTPCRB.MSTPB31(RSCI0), [30] MSTPCRB.MSTPB30(RSCI1), [29] MSTPCRB.MSTPB29(RSCI2), [28] MSTPCRB.MSTPB28(RSCI3), [27] MSTPCRB.MSTPB27(RSCI4), [26] MSTPCRB.MSTPB26(RSCI5), [25] MSTPCRB.MSTPB25(RSCI6), [24] MSTPCRB.MSTPB24(RSCI7), [23] MSTPCRB.MSTPB23(RSCI8), [22] MSTPCRB.MSTPB22(RSCI9), [21] MSTPCRB.MSTPB21(RSCI10), [20] MSTPCRB.MSTPB20(RSCI11), [19] MSTPCRB.MSTPB19(RSPI0), [18] MSTPCRB.MSTPB18(RSPI1), [17] MSTPCRB.MSTPB17(XSPI1), [16] MSTPCRB.MSTPB16(XSPI0), [12] MSTPCRB.MSTPB12(USBHS), [11] MSTPCRB.MSTPB11(USB0), [8] MSTPCRB.MSTPB8(RIICHS1), [7] MSTPCRB.MSTPB7(RIICHS2), [4] MSTPCRB.MSTPB4(RI3C0), [0] MSTPCRB.MSTPB0(RSCI12)
0x87803008 MSTPREG
  [31] MSTPCRC.MSTPC31(RSIP), [30] MSTPCRC.MSTPC30(ESWM), [29] MSTPCRC.MSTPC29(ESC), [28] MSTPCRC.MSTPC28(), [27] MSTPCRC.MSTPC27(CANFD), [25] MSTPCRC.MSTPC25(CANFDG), [24] MSTPCRC.MSTPC24(PDM_CTL), [23] MSTPCRC.MSTPC23(RSPI2), [14] MSTPCRC.MSTPC14(ELC), [13] MSTPCRC.MSTPC13(DOC), [12] MSTPCRC.MSTPC12(SDHI0), [8] MSTPCRC.MSTPC8(SSIE0), [7] MSTPCRC.MSTPC7(SSIE1), [2] MSTPCRC.MSTPC2(PDC), [1] MSTPCRC.MSTPC1(CRC), [0] MSTPCRC.MSTPC0(CAC0)
0x8780300C MSTPREG
  [22] MSTPCRD.MSTPD22(TEMPS), [21] MSTPCRD.MSTPD21(ADCH), [20] MSTPCRD.MSTPD20(DA0), [19] MSTPCRD.MSTPD19(DA1), [14] MSTPCRD.MSTPD14(POEGA), [13] MSTPCRD.MSTPD13(POEGB), [12] MSTPCRD.MSTPD12(POEGC), [11] MSTPCRD.MSTPD11(POEGD), [9] MSTPCRD.MSTPD9(DSMIF0), [8] MSTPCRD.MSTPD8(DSMIF1), [6] MSTPCRD.MSTPD6(HRPWM)
0x87803010 MSTPREG
  [31] MSTPCRE.MSTPE31(GPTW)
0x87803014 MSTPREG
  [31] MSTPCRF.MSTPF31(PCIF0), [30] MSTPCRF.MSTPF30(PCIF1), [16] MSTPCRF.MSTPF16(PIO), [15] MSTPCRF.MSTPF15(CMT0), [14] MSTPCRF.MSTPF14(CMT2), [13] MSTPCRF.MSTPF13(CMTW0), [12] MSTPCRF.MSTPF12(CMTW1), [8] MSTPCRF.MSTPF8(MTU), [7] MSTPCRF.MSTPF7(TMR0), [6] MSTPCRF.MSTPF6(TMR2)
0x87804004 PSCU
  [n] PSARB.PSARB{n} (n=16..31), [12] PSARB.PSARB12, [11] PSARB.PSARB11, [8] PSARB.PSARB8, [7] PSARB.PSARB7, [4] PSARB.PSARB4, [0] PSARB.PSARB0
0x87804008 PSCU
  [n] PSARC.PSARC{n} (n=27..31), [25] PSARC.PSARC25, [24] PSARC.PSARC24, [23] PSARC.PSARC23, [13] PSARC.PSARC13, [12] PSARC.PSARC12, [8] PSARC.PSARC8, [7] PSARC.PSARC7, [2] PSARC.PSARC2, [1] PSARC.PSARC1, [0] PSARC.PSARC0
0x8780400C PSCU
  [n] PSARD.PSARD{n} (n=19..22), [n] PSARD.PSARD{n} (n=11..14), [9] PSARD.PSARD9, [8] PSARD.PSARD8, [6] PSARD.PSARD6
0x87804010 PSCU
  [31] PSARE.PSARE31, [15] PSARE.PSARE15, [3] PSARE.PSARE3, [2] PSARE.PSARE2, [1] PSARE.PSARE1
0x87804014 PSCU
  [31] MSSAR.MSSAR31, [29] MSSAR.MSSAR29, [22] MSSAR.MSSAR22, [1] MSSAR.MSSAR1, [0] MSSAR.MSSAR0
0x87804030 PSCU
  [23:15] CMSAMON.CMS
0x87804034 PSCU
  [15:11] DMSAMON.DMS
0x87804038 PSCU
  [3:0] DLMMON.DLMMON
0x87804040 PSCU
  [31] PSARF.PSARF31, [30] PSARF.PSARF30, [n] PSARF.PSARF{n} (n=12..16), [8] PSARF.PSARF8, [7] PSARF.PSARF7, [6] PSARF.PSARF6
# iorx74m register map
Registers are 32-bit, access not given, no defined reset value unless marked. A register's access mark holds for its fields unless they carry their own. Addresses are absolute; registers are grouped by the start of their names; [hi:lo] are bit positions; {n}, {i} and the like mark numbered series; 'fields as' and 'values as' point back to an identical list.

## SFR (part 10 of 10)
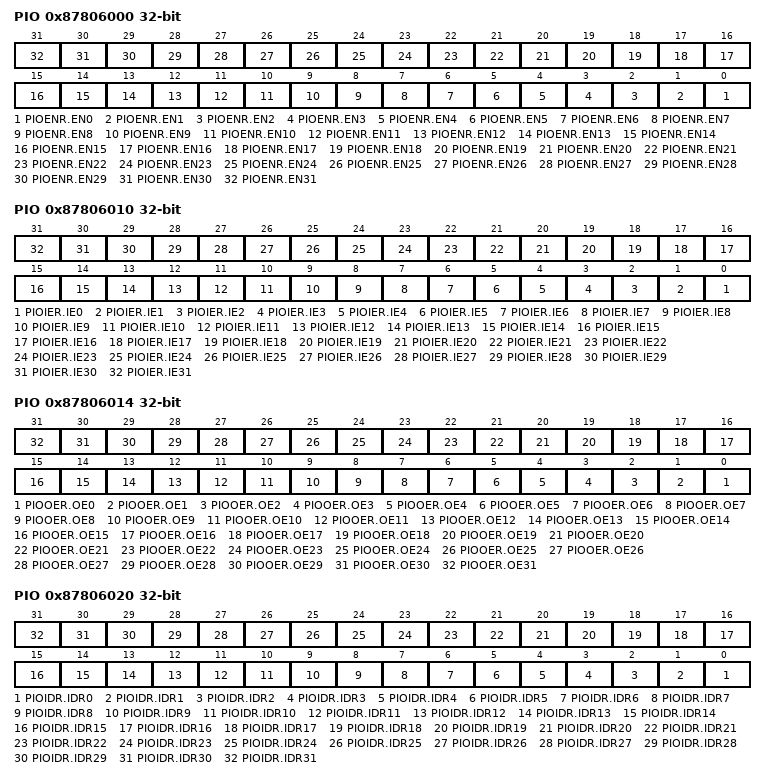
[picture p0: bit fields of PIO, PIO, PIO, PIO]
0x87806000 PIO
  [n] PIOENR.EN{n} (n=0..31)
0x87806010 PIO
  [n] PIOIER.IE{n} (n=0..31)
0x87806014 PIO
  [n] PIOOER.OE{n} (n=0..31)
0x87806020 PIO
  [n] PIOIDR.IDR{n} (n=0..31)
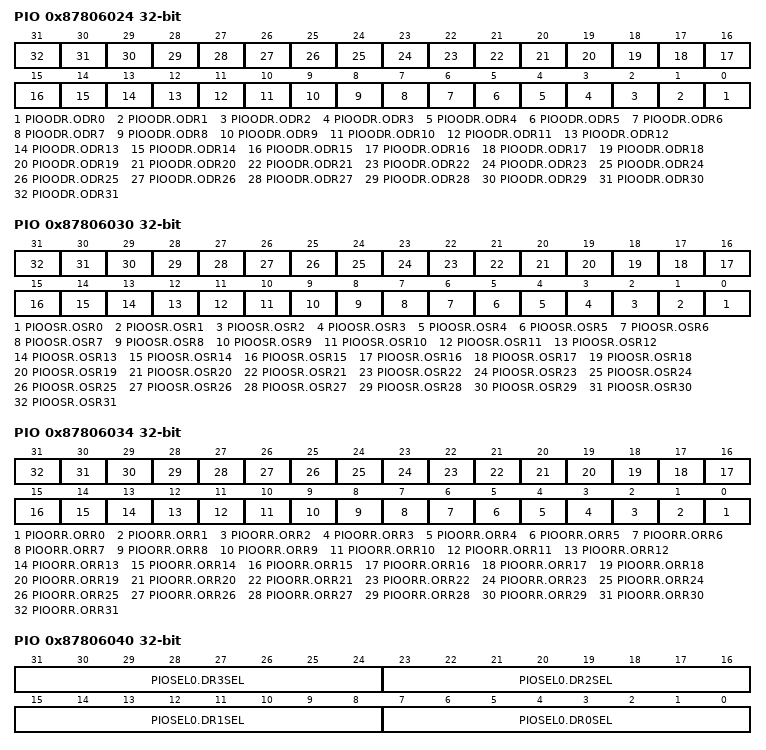
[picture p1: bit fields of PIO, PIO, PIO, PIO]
0x87806024 PIO
  [n] PIOODR.ODR{n} (n=0..31)
0x87806030 PIO
  [n] PIOOSR.OSR{n} (n=0..31)
0x87806034 PIO
  [n] PIOORR.ORR{n} (n=0..31)
0x87806040 PIO
  [8n+7:8n] PIOSEL0.DR{n}SEL (n=0..3)
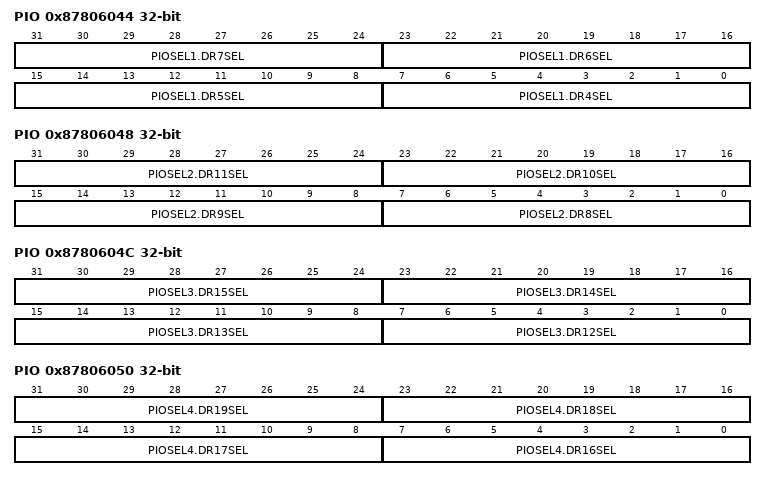
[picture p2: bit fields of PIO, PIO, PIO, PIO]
0x87806044 PIO
  [8n-25:8n-32] PIOSEL1.DR{n}SEL (n=4..7)
0x87806048 PIO
  [8n-57:8n-64] PIOSEL2.DR{n}SEL (n=8..11)
0x8780604C PIO
  [8n-89:8n-96] PIOSEL3.DR{n}SEL (n=12..15)
0x87806050 PIO
  [8n-121:8n-128] PIOSEL4.DR{n}SEL (n=16..19)
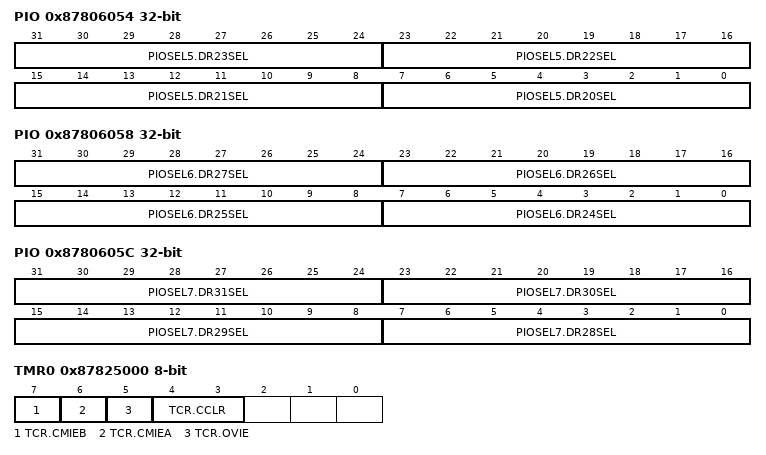
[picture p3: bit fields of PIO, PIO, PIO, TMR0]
0x87806054 PIO
  [8n-153:8n-160] PIOSEL5.DR{n}SEL (n=20..23)
0x87806058 PIO
  [8n-185:8n-192] PIOSEL6.DR{n}SEL (n=24..27)
0x8780605C PIO
  [8n-217:8n-224] PIOSEL7.DR{n}SEL (n=28..31)
0x87807000 RSCI2
  [0] RXDSEL.ISEL
0x87807010 GPTW11
  [0] GTIOCSEL.ISEL
0x87807020 RSCI3
  [0] RXDSEL.ISEL
0x87807030 GPTW13
  [0] GTIOCSEL.ISEL
0x87825000 TMR0 8-bit
  [7] TCR.CMIEB, [6] TCR.CMIEA, [5] TCR.OVIE, [4:3] TCR.CCLR
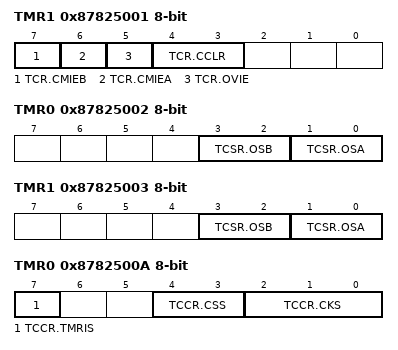
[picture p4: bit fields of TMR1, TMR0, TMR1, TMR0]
0x87825001 TMR1 8-bit
  [7] TCR.CMIEB, [6] TCR.CMIEA, [5] TCR.OVIE, [4:3] TCR.CCLR
0x87825002 TMR0 8-bit
  [3:2] TCSR.OSB, [1:0] TCSR.OSA
0x87825003 TMR1 8-bit
  [3:2] TCSR.OSB, [1:0] TCSR.OSA
0x8782500A TMR0 8-bit
  [7] TCCR.TMRIS, [4:3] TCCR.CSS, [2:0] TCCR.CKS
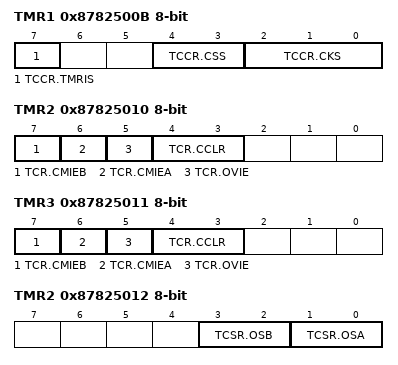
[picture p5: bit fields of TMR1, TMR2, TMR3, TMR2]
0x8782500B TMR1 8-bit
  [7] TCCR.TMRIS, [4:3] TCCR.CSS, [2:0] TCCR.CKS
0x8782500C TMR0 8-bit
  [0] TCSTR.TCS
0x8782500D TMR1 8-bit
  [0] TCSTR.TCS
0x87825010 TMR2 8-bit
  [7] TCR.CMIEB, [6] TCR.CMIEA, [5] TCR.OVIE, [4:3] TCR.CCLR
0x87825011 TMR3 8-bit
  [7] TCR.CMIEB, [6] TCR.CMIEA, [5] TCR.OVIE, [4:3] TCR.CCLR
0x87825012 TMR2 8-bit
  [3:2] TCSR.OSB, [1:0] TCSR.OSA
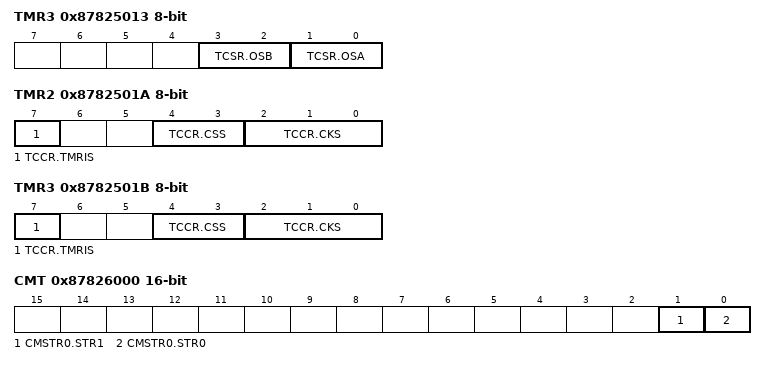
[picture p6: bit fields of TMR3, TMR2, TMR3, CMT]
0x87825013 TMR3 8-bit
  [3:2] TCSR.OSB, [1:0] TCSR.OSA
0x8782501A TMR2 8-bit
  [7] TCCR.TMRIS, [4:3] TCCR.CSS, [2:0] TCCR.CKS
0x8782501B TMR3 8-bit
  [7] TCCR.TMRIS, [4:3] TCCR.CSS, [2:0] TCCR.CKS
0x8782501C TMR2 8-bit
  [0] TCSTR.TCS
0x8782501D TMR3 8-bit
  [0] TCSTR.TCS
0x87826000 CMT 16-bit
  [1] CMSTR0.STR1, [0] CMSTR0.STR0
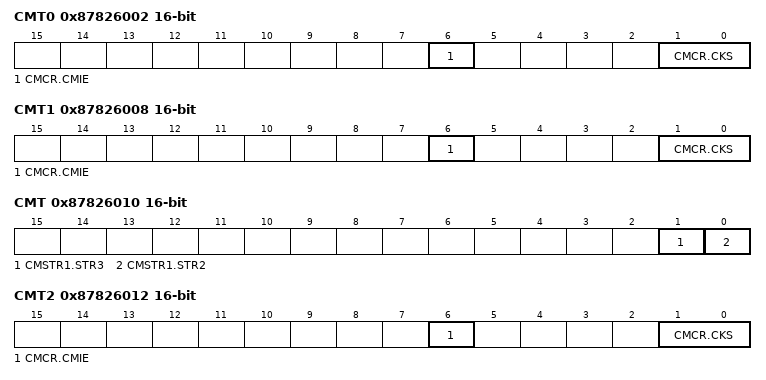
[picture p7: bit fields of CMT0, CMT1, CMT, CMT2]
0x87826002 CMT0 16-bit
  [6] CMCR.CMIE, [1:0] CMCR.CKS
0x87826008 CMT1 16-bit
  [6] CMCR.CMIE, [1:0] CMCR.CKS
0x87826010 CMT 16-bit
  [1] CMSTR1.STR3, [0] CMSTR1.STR2
0x87826012 CMT2 16-bit
  [6] CMCR.CMIE, [1:0] CMCR.CKS
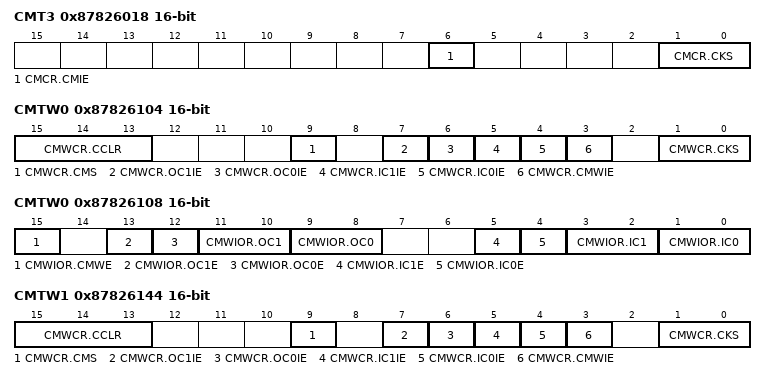
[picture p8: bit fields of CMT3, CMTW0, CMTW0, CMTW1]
0x87826018 CMT3 16-bit
  [6] CMCR.CMIE, [1:0] CMCR.CKS
0x87826100 CMTW0 16-bit
  [0] CMWSTR.STR
0x87826104 CMTW0 16-bit
  [15:13] CMWCR.CCLR, [9] CMWCR.CMS, [7] CMWCR.OC1IE, [6] CMWCR.OC0IE, [5] CMWCR.IC1IE, [4] CMWCR.IC0IE, [3] CMWCR.CMWIE, [1:0] CMWCR.CKS
0x87826108 CMTW0 16-bit
  [15] CMWIOR.CMWE, [13] CMWIOR.OC1E, [12] CMWIOR.OC0E, [11:10] CMWIOR.OC1, [9:8] CMWIOR.OC0, [5] CMWIOR.IC1E, [4] CMWIOR.IC0E, [3:2] CMWIOR.IC1, [1:0] CMWIOR.IC0
0x87826140 CMTW1 16-bit
  [0] CMWSTR.STR
0x87826144 CMTW1 16-bit
  [15:13] CMWCR.CCLR, [9] CMWCR.CMS, [7] CMWCR.OC1IE, [6] CMWCR.OC0IE, [5] CMWCR.IC1IE, [4] CMWCR.IC0IE, [3] CMWCR.CMWIE, [1:0] CMWCR.CKS
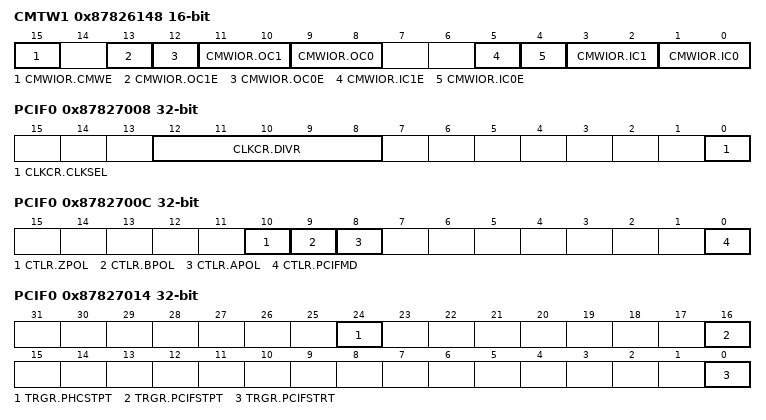
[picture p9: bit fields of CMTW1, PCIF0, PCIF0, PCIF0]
0x87826148 CMTW1 16-bit
  [15] CMWIOR.CMWE, [13] CMWIOR.OC1E, [12] CMWIOR.OC0E, [11:10] CMWIOR.OC1, [9:8] CMWIOR.OC0, [5] CMWIOR.IC1E, [4] CMWIOR.IC0E, [3:2] CMWIOR.IC1, [1:0] CMWIOR.IC0
0x87827000 PCIF0
  [0] CLKER.CLKEN
0x87827004 PCIF0
  [0] CLKSR.CLKS
0x87827008 PCIF0
  [12:8] CLKCR.DIVR, [0] CLKCR.CLKSEL
0x8782700C PCIF0
  [10] CTLR.ZPOL, [9] CTLR.BPOL, [8] CTLR.APOL, [0] CTLR.PCIFMD
0x87827010 PCIF0
  [15:0] POSMAXR.POSMAX
0x87827014 PCIF0
  [24] TRGR.PHCSTPT, [16] TRGR.PCIFSTPT, [0] TRGR.PCIFSTRT
0x87827018 PCIF0
  [0] SR.PCIFPS
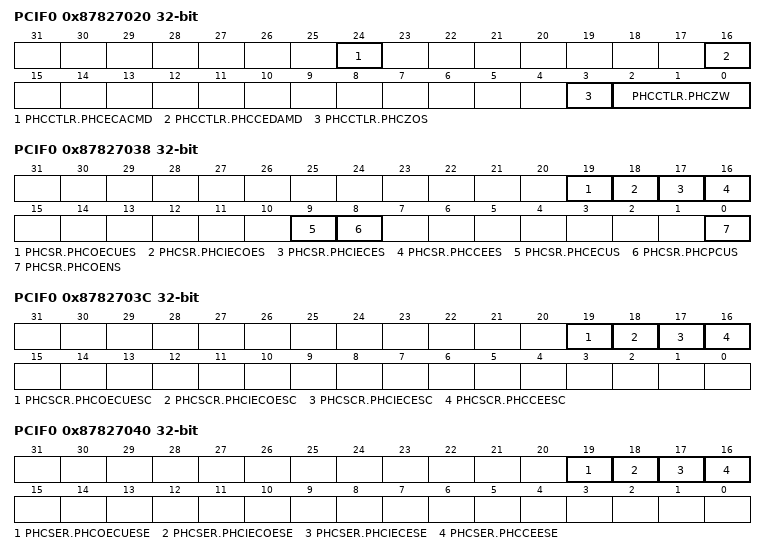
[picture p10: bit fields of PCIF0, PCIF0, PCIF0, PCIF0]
0x87827020 PCIF0
  [24] PHCCTLR.PHCECACMD, [16] PHCCTLR.PHCCEDAMD, [3] PHCCTLR.PHCZOS, [2:0] PHCCTLR.PHCZW
0x87827024 PCIF0
  [15:0] PHCCEDTHR.PHCCEDTH
0x87827028 PCIF0
  [15:0] PHCPERIODR.PHCPERIOD
0x8782702C PCIF0
  [15:0] PHCECR.PHCEDGCNT
0x87827030 PCIF0
  [15:0] PHCPCMR.PHCPOSCNTM
0x87827034 PCIF0
  [15:0] PHCPCWDR.PHCPOSCNTWD
0x87827038 PCIF0
  [19] PHCSR.PHCOECUES, [18] PHCSR.PHCIECOES, [17] PHCSR.PHCIECES, [16] PHCSR.PHCCEES, [9] PHCSR.PHCECUS, [8] PHCSR.PHCPCUS, [0] PHCSR.PHCOENS
0x8782703C PCIF0
  [19] PHCSCR.PHCOECUESC, [18] PHCSCR.PHCIECOESC, [17] PHCSCR.PHCIECESC, [16] PHCSCR.PHCCEESC
0x87827040 PCIF0
  [19] PHCSER.PHCOECUESE, [18] PHCSER.PHCIECOESE, [17] PHCSER.PHCIECESE, [16] PHCSER.PHCCEESE
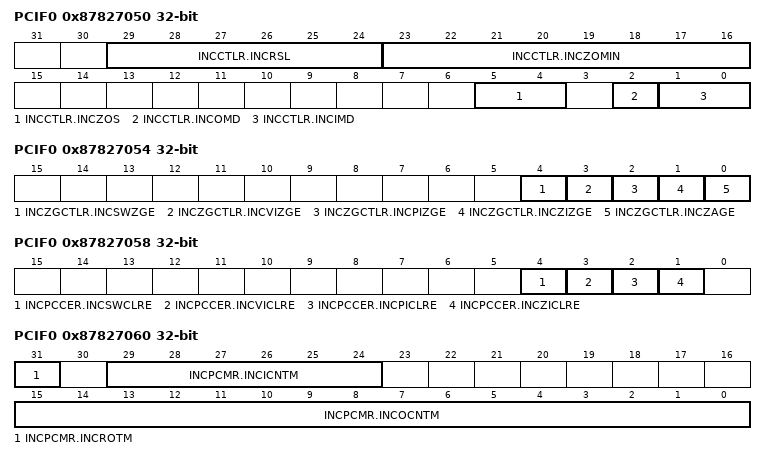
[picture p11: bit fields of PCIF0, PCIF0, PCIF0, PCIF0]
0x87827050 PCIF0
  [29:24] INCCTLR.INCRSL, [23:16] INCCTLR.INCZOMIN, [5:4] INCCTLR.INCZOS, [2] INCCTLR.INCOMD, [1:0] INCCTLR.INCIMD
0x87827054 PCIF0
  [4] INCZGCTLR.INCSWZGE, [3] INCZGCTLR.INCVIZGE, [2] INCZGCTLR.INCPIZGE, [1] INCZGCTLR.INCZIZGE, [0] INCZGCTLR.INCZAGE
0x87827058 PCIF0
  [4] INCPCCER.INCSWCLRE, [3] INCPCCER.INCVICLRE, [2] INCPCCER.INCPICLRE, [1] INCPCCER.INCZICLRE
0x8782705C PCIF0
  [0] INCSWTRGR.INCSWT
0x87827060 PCIF0
  [31] INCPCMR.INCROTM, [29:24] INCPCMR.INCICNTM, [15:0] INCPCMR.INCOCNTM
0x87827070 PCIF0
  [0] SWRSTR.SWRST
0x87827080 PCIF1
  [0] CLKER.CLKEN
0x87827084 PCIF1
  [0] CLKSR.CLKS
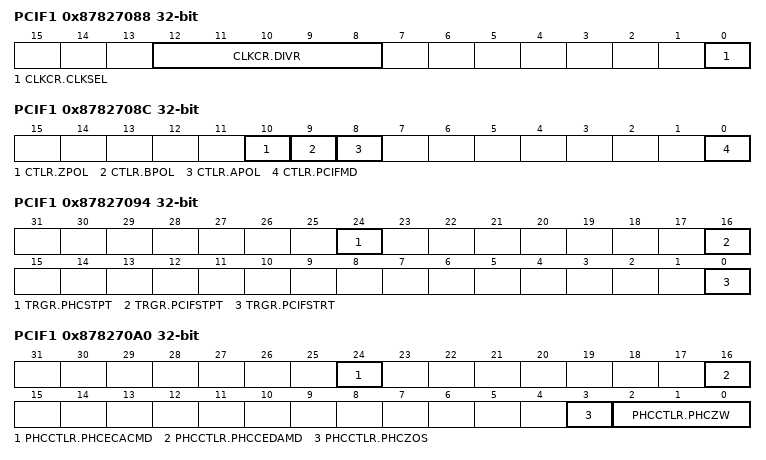
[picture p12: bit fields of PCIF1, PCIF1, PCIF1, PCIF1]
0x87827088 PCIF1
  [12:8] CLKCR.DIVR, [0] CLKCR.CLKSEL
0x8782708C PCIF1
  [10] CTLR.ZPOL, [9] CTLR.BPOL, [8] CTLR.APOL, [0] CTLR.PCIFMD
0x87827090 PCIF1
  [15:0] POSMAXR.POSMAX
0x87827094 PCIF1
  [24] TRGR.PHCSTPT, [16] TRGR.PCIFSTPT, [0] TRGR.PCIFSTRT
0x87827098 PCIF1
  [0] SR.PCIFPS
0x878270A0 PCIF1
  [24] PHCCTLR.PHCECACMD, [16] PHCCTLR.PHCCEDAMD, [3] PHCCTLR.PHCZOS, [2:0] PHCCTLR.PHCZW
0x878270A4 PCIF1
  [15:0] PHCCEDTHR.PHCCEDTH
0x878270A8 PCIF1
  [15:0] PHCPERIODR.PHCPERIOD
0x878270AC PCIF1
  [15:0] PHCECR.PHCEDGCNT
0x878270B0 PCIF1
  [15:0] PHCPCMR.PHCPOSCNTM
0x878270B4 PCIF1
  [15:0] PHCPCWDR.PHCPOSCNTWD
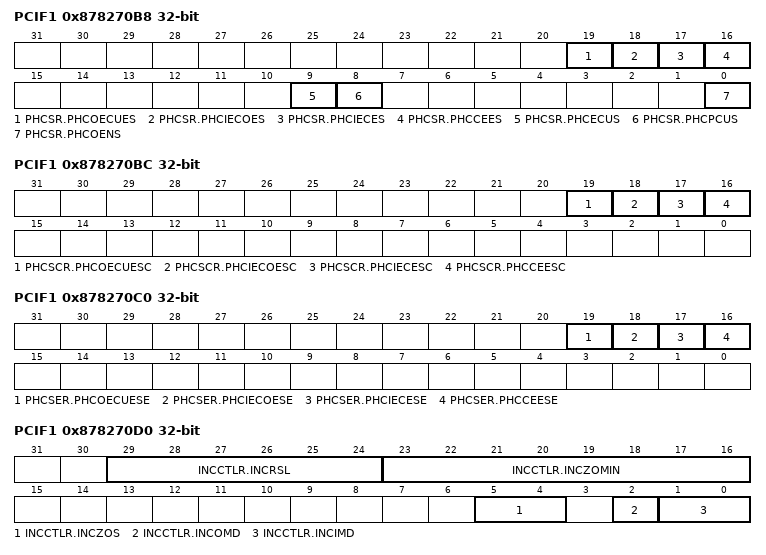
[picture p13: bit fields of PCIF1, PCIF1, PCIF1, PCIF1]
0x878270B8 PCIF1
  [19] PHCSR.PHCOECUES, [18] PHCSR.PHCIECOES, [17] PHCSR.PHCIECES, [16] PHCSR.PHCCEES, [9] PHCSR.PHCECUS, [8] PHCSR.PHCPCUS, [0] PHCSR.PHCOENS
0x878270BC PCIF1
  [19] PHCSCR.PHCOECUESC, [18] PHCSCR.PHCIECOESC, [17] PHCSCR.PHCIECESC, [16] PHCSCR.PHCCEESC
0x878270C0 PCIF1
  [19] PHCSER.PHCOECUESE, [18] PHCSER.PHCIECOESE, [17] PHCSER.PHCIECESE, [16] PHCSER.PHCCEESE
0x878270D0 PCIF1
  [29:24] INCCTLR.INCRSL, [23:16] INCCTLR.INCZOMIN, [5:4] INCCTLR.INCZOS, [2] INCCTLR.INCOMD, [1:0] INCCTLR.INCIMD
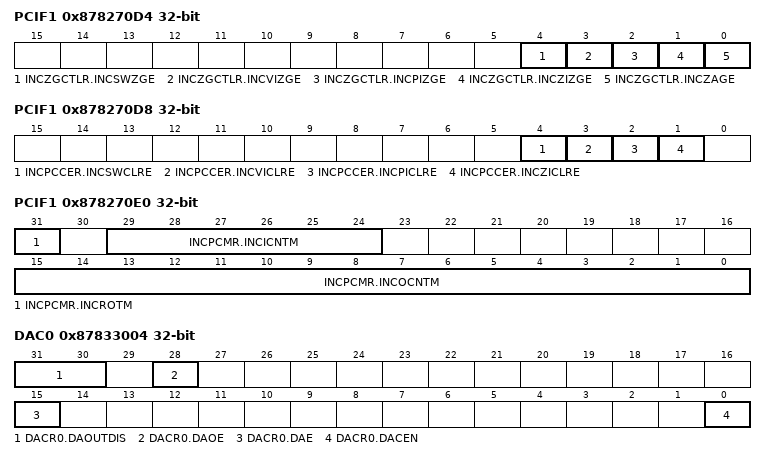
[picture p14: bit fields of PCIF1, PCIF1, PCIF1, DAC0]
0x878270D4 PCIF1
  [4] INCZGCTLR.INCSWZGE, [3] INCZGCTLR.INCVIZGE, [2] INCZGCTLR.INCPIZGE, [1] INCZGCTLR.INCZIZGE, [0] INCZGCTLR.INCZAGE
0x878270D8 PCIF1
  [4] INCPCCER.INCSWCLRE, [3] INCPCCER.INCVICLRE, [2] INCPCCER.INCPICLRE, [1] INCPCCER.INCZICLRE
0x878270DC PCIF1
  [0] INCSWTRGR.INCSWT
0x878270E0 PCIF1
  [31] INCPCMR.INCROTM, [29:24] INCPCMR.INCICNTM, [15:0] INCPCMR.INCOCNTM
0x878270F0 PCIF1
  [0] SWRSTR.SWRST
0x87833004 DAC0
  [31:30] DACR0.DAOUTDIS, [28] DACR0.DAOE, [15] DACR0.DAE, [0] DACR0.DACEN
0x87833008 DAC0
  [16] DACR1.DPSEL
0x8783300C DAC0
  [31] DACR2.DAAMP, [8:0] DACR2.OFSSEL
0x87833104 DAC1
  fields as DAC0
0x87833108 DAC1
  [16] DACR1.DPSEL
0x8783310C DAC1
  [31] DACR2.DAAMP, [8:0] DACR2.OFSSEL
0x87835000 TEMPS 8-bit
  [7] TSCR.TSEN, [4] TSCR.TSOE
0x87841000 PDC
  [14] PCCR0.EDS, [13:11] PCCR0.PCKDIV, [10] PCCR0.PCKOE, [9] PCCR0.HERIE, [8] PCCR0.VERIE, [7] PCCR0.UDRIE, [6] PCCR0.OVIE, [5] PCCR0.FEIE, [4] PCCR0.DFIE, [3] PCCR0.PRST, [2] PCCR0.HPS, [1] PCCR0.VPS, [0] PCCR0.PCKE
0x87841004 PDC
  [0] PCCR1.PCE
0x87841008 PDC
  [6] PCSR.HERF, [5] PCSR.VERF, [4] PCSR.UDRF, [3] PCSR.OVRF, [2] PCSR.FEF, [1] PCSR.FEMPF, [0] PCSR.FBSY
0x8784100C PDC
  [1] PCMONR.HSYNC, [0] PCMONR.VSYNC
0x87841014 PDC
  [27:16] VCR.VSZ, [11:0] VCR.VST
0x87841018 PDC
  [27:16] HCR.HSZ, [11:0] HCR.HST
0x87850000 USB0 16-bit
  [10] SYSCFG.SCKE, [6] SYSCFG.DCFM, [5] SYSCFG.DRPD, [4] SYSCFG.DPRPU, [0] SYSCFG.USBE
0x87850004 USB0 16-bit
  [15:14] SYSSTS0.OVCMON, [6] SYSSTS0.HTACT, [5] SYSSTS0.SOFEA, [2] SYSSTS0.IDMON, [1:0] SYSSTS0.LNST
0x87850008 USB0 16-bit
  [11] DVSTCTR0.HNPBTOA, [10] DVSTCTR0.EXICEN, [9] DVSTCTR0.VBUSEN, [8] DVSTCTR0.WKUP, [7] DVSTCTR0.RWUPE, [6] DVSTCTR0.USBRST, [5] DVSTCTR0.RESUME, [4] DVSTCTR0.UACT, [2:0] DVSTCTR0.RHST
0x87850020 USB0 16-bit
  [15] CFIFOSEL.RCNT, [14] CFIFOSEL.REW, [10] CFIFOSEL.MBW, [8] CFIFOSEL.BIGEND, [5] CFIFOSEL.ISEL, [3:0] CFIFOSEL.CURPIPE
0x87850022 USB0 16-bit
  [15] CFIFOCTR.BVAL, [14] CFIFOCTR.BCLR, [13] CFIFOCTR.FRDY, [8:0] CFIFOCTR.DTLN
0x87850028 USB0 16-bit
  [15] D0FIFOSEL.RCNT, [14] D0FIFOSEL.REW, [13] D0FIFOSEL.DCLRM, [12] D0FIFOSEL.DREQE, [10] D0FIFOSEL.MBW, [8] D0FIFOSEL.BIGEND, [3:0] D0FIFOSEL.CURPIPE
0x8785002A USB0 16-bit
  [15] D0FIFOCTR.BVAL, [14] D0FIFOCTR.BCLR, [13] D0FIFOCTR.FRDY, [8:0] D0FIFOCTR.DTLN
0x8785002C USB0 16-bit
  [15] D1FIFOSEL.RCNT, [14] D1FIFOSEL.REW, [13] D1FIFOSEL.DCLRM, [12] D1FIFOSEL.DREQE, [10] D1FIFOSEL.MBW, [8] D1FIFOSEL.BIGEND, [3:0] D1FIFOSEL.CURPIPE
0x8785002E USB0 16-bit
  [15] D1FIFOCTR.BVAL, [14] D1FIFOCTR.BCLR, [13] D1FIFOCTR.FRDY, [8:0] D1FIFOCTR.DTLN
0x87850030 USB0 16-bit
  [15] INTENB0.VBSE, [14] INTENB0.RSME, [13] INTENB0.SOFE, [12] INTENB0.DVSE, [11] INTENB0.CTRE, [10] INTENB0.BEMPE, [9] INTENB0.NRDYE, [8] INTENB0.BRDYE
0x87850032 USB0 16-bit
  [15] INTENB1.OVRCRE, [14] INTENB1.BCHGE, [12] INTENB1.DTCHE, [11] INTENB1.ATTCHE, [6] INTENB1.EOFERRE, [5] INTENB1.SIGNE, [4] INTENB1.SACKE
0x87850036 USB0 16-bit
  [n] BRDYENB.PIPE{n}BRDYE (n=0..9)
0x87850038 USB0 16-bit
  [n] NRDYENB.PIPE{n}NRDYE (n=0..9)
0x8785003A USB0 16-bit
  [n] BEMPENB.PIPE{n}BEMPE (n=0..9)
0x8785003C USB0 16-bit
  [8] SOFCFG.TRNENSEL, [6] SOFCFG.BRDYM, [4] SOFCFG.EDGESTS
0x87850040 USB0 16-bit
  [15] INTSTS0.VBINT, [14] INTSTS0.RESM, [13] INTSTS0.SOFR, [12] INTSTS0.DVST, [11] INTSTS0.CTRT, [10] INTSTS0.BEMP, [9] INTSTS0.NRDY, [8] INTSTS0.BRDY, [7] INTSTS0.VBSTS, [6:4] INTSTS0.DVSQ, [3] INTSTS0.VALID, [2:0] INTSTS0.CTSQ
0x87850042 USB0 16-bit
  [15] INTSTS1.OVRCR, [14] INTSTS1.BCHG, [12] INTSTS1.DTCH, [11] INTSTS1.ATTCH, [6] INTSTS1.EOFERR, [5] INTSTS1.SIGN, [4] INTSTS1.SACK
0x87850046 USB0 16-bit
  [n] BRDYSTS.PIPE{n}BRDY (n=0..9)
0x87850048 USB0 16-bit
  [n] NRDYSTS.PIPE{n}NRDY (n=0..9)
0x8785004A USB0 16-bit
  [n] BEMPSTS.PIPE{n}BEMP (n=0..9)
0x8785004C USB0 16-bit
  [15] FRMNUM.OVRN, [14] FRMNUM.CRCE, [10:0] FRMNUM.FRNM
0x8785004E USB0 16-bit
  [15] DVCHGR.DVCHG
0x87850050 USB0 16-bit
  [11:8] USBADDR.STSRECOV, [6:0] USBADDR.USBADDR
0x87850054 USB0 16-bit
  [15:8] USBREQ.BREQUEST, [7:0] USBREQ.BMREQUESTTYPE
0x8785005C USB0 16-bit
  [7] DCPCFG.SHTNAK, [4] DCPCFG.DIR
0x8785005E USB0 16-bit
  [15:12] DCPMAXP.DEVSEL, [6:0] DCPMAXP.MXPS
0x87850060 USB0 16-bit
  [15] DCPCTR.BSTS, [14] DCPCTR.SUREQ, [11] DCPCTR.SUREQCLR, [8] DCPCTR.SQCLR, [7] DCPCTR.SQSET, [6] DCPCTR.SQMON, [5] DCPCTR.PBUSY, [2] DCPCTR.CCPL, [1:0] DCPCTR.PID
0x87850064 USB0 16-bit
  [3:0] PIPESEL.PIPESEL
0x87850068 USB0 16-bit
  [15:14] PIPECFG.TYPE, [10] PIPECFG.BFRE, [9] PIPECFG.DBLB, [7] PIPECFG.SHTNAK, [4] PIPECFG.DIR, [3:0] PIPECFG.EPNUM
0x8785006C USB0 16-bit
  [15:12] PIPEMAXP.DEVSEL, [8:0] PIPEMAXP.MXPS
0x8785006E USB0 16-bit
  [12] PIPEPERI.IFIS, [2:0] PIPEPERI.IITV
0x87850070 USB0 16-bit
  [15] PIPE1CTR.BSTS, [14] PIPE1CTR.INBUFM, [10] PIPE1CTR.ATREPM, [9] PIPE1CTR.ACLRM, [8] PIPE1CTR.SQCLR, [7] PIPE1CTR.SQSET, [6] PIPE1CTR.SQMON, [5] PIPE1CTR.PBUSY, [1:0] PIPE1CTR.PID
0x87850072 USB0 16-bit
  [15] PIPE2CTR.BSTS, [14] PIPE2CTR.INBUFM, [10] PIPE2CTR.ATREPM, [9] PIPE2CTR.ACLRM, [8] PIPE2CTR.SQCLR, [7] PIPE2CTR.SQSET, [6] PIPE2CTR.SQMON, [5] PIPE2CTR.PBUSY, [1:0] PIPE2CTR.PID
0x87850074 USB0 16-bit
  [15] PIPE3CTR.BSTS, [14] PIPE3CTR.INBUFM, [10] PIPE3CTR.ATREPM, [9] PIPE3CTR.ACLRM, [8] PIPE3CTR.SQCLR, [7] PIPE3CTR.SQSET, [6] PIPE3CTR.SQMON, [5] PIPE3CTR.PBUSY, [1:0] PIPE3CTR.PID
0x87850076 USB0 16-bit
  [15] PIPE4CTR.BSTS, [14] PIPE4CTR.INBUFM, [10] PIPE4CTR.ATREPM, [9] PIPE4CTR.ACLRM, [8] PIPE4CTR.SQCLR, [7] PIPE4CTR.SQSET, [6] PIPE4CTR.SQMON, [5] PIPE4CTR.PBUSY, [1:0] PIPE4CTR.PID
0x87850078 USB0 16-bit
  [15] PIPE5CTR.BSTS, [14] PIPE5CTR.INBUFM, [10] PIPE5CTR.ATREPM, [9] PIPE5CTR.ACLRM, [8] PIPE5CTR.SQCLR, [7] PIPE5CTR.SQSET, [6] PIPE5CTR.SQMON, [5] PIPE5CTR.PBUSY, [1:0] PIPE5CTR.PID
0x8785007A USB0 16-bit
  [15] PIPE6CTR.BSTS, [9] PIPE6CTR.ACLRM, [8] PIPE6CTR.SQCLR, [7] PIPE6CTR.SQSET, [6] PIPE6CTR.SQMON, [5] PIPE6CTR.PBUSY, [1:0] PIPE6CTR.PID
0x8785007C USB0 16-bit
  [15] PIPE7CTR.BSTS, [9] PIPE7CTR.ACLRM, [8] PIPE7CTR.SQCLR, [7] PIPE7CTR.SQSET, [6] PIPE7CTR.SQMON, [5] PIPE7CTR.PBUSY, [1:0] PIPE7CTR.PID
0x8785007E USB0 16-bit
  [15] PIPE8CTR.BSTS, [9] PIPE8CTR.ACLRM, [8] PIPE8CTR.SQCLR, [7] PIPE8CTR.SQSET, [6] PIPE8CTR.SQMON, [5] PIPE8CTR.PBUSY, [1:0] PIPE8CTR.PID
0x87850080 USB0 16-bit
  [15] PIPE9CTR.BSTS, [9] PIPE9CTR.ACLRM, [8] PIPE9CTR.SQCLR, [7] PIPE9CTR.SQSET, [6] PIPE9CTR.SQMON, [5] PIPE9CTR.PBUSY, [1:0] PIPE9CTR.PID
0x87850090 USB0 16-bit
  [9] PIPE1TRE.TRENB, [8] PIPE1TRE.TRCLR
0x87850094 USB0 16-bit
  [9] PIPE2TRE.TRENB, [8] PIPE2TRE.TRCLR
0x87850098 USB0 16-bit
  [9] PIPE3TRE.TRENB, [8] PIPE3TRE.TRCLR
0x8785009C USB0 16-bit
  [9] PIPE4TRE.TRENB, [8] PIPE4TRE.TRCLR
0x878500A0 USB0 16-bit
  [9] PIPE5TRE.TRENB, [8] PIPE5TRE.TRCLR
0x878500D0 USB0 16-bit
  [7:6] DEVADD[0].USBSPD
0x878500D2 USB0 16-bit
  [7:6] DEVADD[1].USBSPD
0x878500D4 USB0 16-bit
  [7:6] DEVADD[2].USBSPD
0x878500D6 USB0 16-bit
  [7:6] DEVADD[3].USBSPD
0x878500D8 USB0 16-bit
  [7:6] DEVADD[4].USBSPD
0x878500DA USB0 16-bit
  [7:6] DEVADD[5].USBSPD
0x87850400 USB
  [23] DPUSR0R.DVBSTS0, [21] DPUSR0R.DOVCB0, [20] DPUSR0R.DOVCA0, [17] DPUSR0R.DM0, [16] DPUSR0R.DP0, [4] DPUSR0R.FIXPHY0, [3] DPUSR0R.DRPD0, [1] DPUSR0R.RPUE0, [0] DPUSR0R.SRPC0
0x87850404 USB
  [23:22] DPUSR1R.DVBINT0, [21] DPUSR1R.DOVRCRB0, [20] DPUSR1R.DOVRCRA0, [17] DPUSR1R.DMINT0, [16] DPUSR1R.DPINT0, [7:6] DPUSR1R.DVBSE0, [5] DPUSR1R.DOVRCRBE0, [4] DPUSR1R.DOVRCRAE0, [1] DPUSR1R.DMINTE0, [0] DPUSR1R.DPINTE0
0x87852000 SDHI0
  [15:14] SD_CMD.CMD12AT, [13] SD_CMD.TRSTP, [12] SD_CMD.CMDRW, [11] SD_CMD.CMDTP, [10:8] SD_CMD.RSPTP, [7:6] SD_CMD.ACMD, [5:0] SD_CMD.CMDIDX
0x87852010 SDHI0
  [8] SD_STOP.SEC, [0] SD_STOP.STP
0x87852030 SDHI0
  [23:0] SD_RSP76.SD_RSP76
0x87852034 SDHI0
  [7:0] SD_RSP7.SD_RSP7
0x87852038 SDHI0
  [10] SD_INFO1.SDD3MON, [9] SD_INFO1.SDD3IN, [8] SD_INFO1.SDD3RM, [7] SD_INFO1.SDWPMON, [5] SD_INFO1.SDCDMON, [4] SD_INFO1.SDCDIN, [3] SD_INFO1.SDCDRM, [2] SD_INFO1.ACEND, [0] SD_INFO1.RSPEND
0x8785203C SDHI0
  [15] SD_INFO2.ILA, [14] SD_INFO2.CBSY, [13] SD_INFO2.SD_CLK_CTRLEN, [9] SD_INFO2.BWE, [8] SD_INFO2.BRE, [7] SD_INFO2.SDD0MON, [6] SD_INFO2.RSPTO, [5] SD_INFO2.ILR, [4] SD_INFO2.ILW, [3] SD_INFO2.DTO, [2] SD_INFO2.ENDE, [1] SD_INFO2.CRCE, [0] SD_INFO2.CMDE
0x87852040 SDHI0
  [9] SD_INFO1_MASK.SDD3INM, [8] SD_INFO1_MASK.SDD3RMM, [4] SD_INFO1_MASK.SDCDINM, [3] SD_INFO1_MASK.SDCDRMM, [2] SD_INFO1_MASK.ACENDM, [0] SD_INFO1_MASK.RSPENDM
0x87852044 SDHI0
  [15] SD_INFO2_MASK.ILAM, [9] SD_INFO2_MASK.BWEM, [8] SD_INFO2_MASK.BREM, [6] SD_INFO2_MASK.RSPTOM, [5] SD_INFO2_MASK.ILRM, [4] SD_INFO2_MASK.ILWM, [3] SD_INFO2_MASK.DTOM, [2] SD_INFO2_MASK.ENDEM, [1] SD_INFO2_MASK.CRCEM, [0] SD_INFO2_MASK.CMDEM
0x87852048 SDHI0
  [9] SD_CLK_CTRL.CLKCTRLEN, [8] SD_CLK_CTRL.CLKEN, [7:0] SD_CLK_CTRL.CLKSEL
0x8785204C SDHI0
  [9:0] SD_SIZE.LEN
0x87852050 SDHI0
  [15] SD_OPTION.WIDTH, [13] SD_OPTION.WIDTH8, [8] SD_OPTION.TOUTMASK, [7:4] SD_OPTION.TOP, [3:0] SD_OPTION.CTOP
0x87852058 SDHI0
  [14:12] SD_ERR_STS1.CRCTK, [11] SD_ERR_STS1.CRCTKE, [10] SD_ERR_STS1.RDCRCE, [9] SD_ERR_STS1.RSPCRCE1, [8] SD_ERR_STS1.RSPCRCE0, [5] SD_ERR_STS1.CRCLENE, [4] SD_ERR_STS1.RDLENE, [3] SD_ERR_STS1.RSPLENE1, [2] SD_ERR_STS1.RSPLENE0, [1] SD_ERR_STS1.CMDE1, [0] SD_ERR_STS1.CMDE0
0x8785205C SDHI0
  [6] SD_ERR_STS2.CRCBSYTO, [5] SD_ERR_STS2.CRCTO, [4] SD_ERR_STS2.RDTO, [3] SD_ERR_STS2.BSYTO1, [2] SD_ERR_STS2.BSYTO0, [1] SD_ERR_STS2.RSPTO1, [0] SD_ERR_STS2.RSPTO0
0x87852068 SDHI0
  [9] SDIO_MODE.C52PUB, [8] SDIO_MODE.IOABT, [2] SDIO_MODE.RWREQ, [0] SDIO_MODE.INTEN
0x8785206C SDHI0
  [15] SDIO_INFO1.EXWT, [14] SDIO_INFO1.EXPUB52, [0] SDIO_INFO1.IOIRQ
0x87852070 SDHI0
  [15] SDIO_INFO1_MASK.EXWTM, [14] SDIO_INFO1_MASK.EXPUB52M, [0] SDIO_INFO1_MASK.IOIRQM
0x878521B0 SDHI0
  [1] SD_DMAEN.DMAEN
0x878521C0 SDHI0
  [0] SOFT_RST.SDRST
0x878521CC SDHI0
  [8] SDIF_MODE.NOCHKCR
0x878521E0 SDHI0
  [7] EXT_SWAP.BRSWP, [6] EXT_SWAP.BWSWP
0x87856000 PDMIF
  [0] PDCSTRTR.STRTRG0
0x87856004 PDMIF
  [0] PDCSTPTR.STPTRG0
0x87856008 PDMIF
  [0] PDCCHGTR.CHGTRG0
0x8785600C PDMIF
  [24] PDCICR.IEDE0, [16] PDCICR.IDRE0, [8] PDCICR.ISDE0
0x87856010 PDMIF
  [24] PDCSR.EDF0, [16] PDCSR.DRF0, [8] PDCSR.SDF0, [0] PDCSR.STATE0
0x87856014 PDMIF
  [8] PDCSCR.SDFC0
0x87856020 PDMIF
  [0] PDCSDCR.SDE0
0x87856024 PDMIF
  [0] PDCDRCR.DATRE0
0x87856028 PDMIF
  [0] PDCDCR.DATC0
0x87856080 PDMIF
  [11:0] PDVR.VER
0x87856100 PDMIF
  [0] PDSTRTRCH0.STRTRG
0x87856104 PDMIF
  [0] PDSTPTRCH0.STPTRG
0x87856108 PDMIF
  [0] PDCHGTRCH0.CHGTRG
0x8785610C PDMIF
  [16] PDICRCH0.IEDE, [2] PDICRCH0.IDRE, [1] PDICRCH0.ISDE
0x87856110 PDMIF
  [27] PDSDCRCH0.BFOWDE, [18] PDSDCRCH0.OVUDE, [17] PDSDCRCH0.OVLDE, [16] PDSDCRCH0.SCDE, [1] PDSDCRCH0.SDE
0x87856114 PDMIF
  [27] PDSRCH0.BFOWDF, [18] PDSRCH0.OVUDF, [17] PDSRCH0.OVLDF, [16] PDSRCH0.SCDF, [2] PDSRCH0.DRF, [1] PDSRCH0.SDF, [0] PDSRCH0.STATE
0x87856118 PDMIF
  [27] PDSCRCH0.BFOWDFC, [18] PDSCRCH0.OVUDFC, [17] PDSCRCH0.OVLDFC, [16] PDSCRCH0.SCDFC, [1] PDSCRCH0.SDFC
0x87856120 PDMIF
  [31:28] PDMDSRCH0.DBIS, [25:24] PDMDSRCH0.SDMAMD, [17:16] PDMDSRCH0.LFIS, [13:12] PDMDSRCH0.CFIS, [9:8] PDMDSRCH0.HFIS, [6:4] PDMDSRCH0.SFMD, [0] PDMDSRCH0.INPSEL
0x87856124 PDMIF
  [28:24] PDSFCRCH0.SINCRNG, [23:16] PDSFCRCH0.SINCDEC, [3:0] PDSFCRCH0.CKDIV
0x87856128 PDMIF
  [15:0] PDHFCS0RCH0.HFS
0x8785612C PDMIF
  [15:0] PDHFCK1RCH0.HFK
0x87856130 PDMIF
  [15:0] PDHFCH0RCH0.HFH
0x87856134 PDMIF
  [15:0] PDHFCH1RCH0.HFH
0x87856138 PDMIF
  [12:0] PDCFCH00RCH0.CFH
0x8785613C PDMIF
  [12:0] PDCFCH01RCH0.CFH
0x87856140 PDMIF
  [12:0] PDCFCH02RCH0.CFH
0x87856144 PDMIF
  [12:0] PDCFCH03RCH0.CFH
0x87856148 PDMIF
  [12:0] PDCFCH04RCH0.CFH
0x8785614C PDMIF
  [12:0] PDCFCH05RCH0.CFH
0x87856150 PDMIF
  [12:0] PDCFCH06RCH0.CFH
0x87856154 PDMIF
  [12:0] PDCFCH07RCH0.CFH
0x87856158 PDMIF
  [12:0] PDCFCH08RCH0.CFH
0x8785615C PDMIF
  [12:0] PDCFCH09RCH0.CFH
0x87856160 PDMIF
  [12:0] PDCFCH10RCH0.CFH
0x87856164 PDMIF
  [12:0] PDLFCH010RCH0.LFH0
0x87856168 PDMIF
  [12:0] PDLFCH100RCH0.LFH1
0x8785616C PDMIF
  [12:0] PDLFCH101RCH0.LFH1
0x87856170 PDMIF
  [12:0] PDLFCH102RCH0.LFH1
0x87856174 PDMIF
  [12:0] PDLFCH103RCH0.LFH1
0x87856178 PDMIF
  [12:0] PDLFCH104RCH0.LFH1
0x8785617C PDMIF
  [12:0] PDLFCH105RCH0.LFH1
0x87856180 PDMIF
  [12:0] PDLFCH106RCH0.LFH1
0x87856184 PDMIF
  [12:0] PDLFCH107RCH0.LFH1
0x87856188 PDMIF
  [12:0] PDLFCH108RCH0.LFH1
0x8785618C PDMIF
  [12:0] PDLFCH109RCH0.LFH1
0x87856190 PDMIF
  [12:0] PDLFCH110RCH0.LFH1
0x87856194 PDMIF
  [12:0] PDLFCH111RCH0.LFH1
0x87856198 PDMIF
  [12:0] PDLFCH112RCH0.LFH1
0x8785619C PDMIF
  [12:0] PDLFCH113RCH0.LFH1
0x878561A0 PDMIF
  [12:0] PDLFCH114RCH0.LFH1
0x878561A4 PDMIF
  [12:0] PDLFCH115RCH0.LFH1
0x878561A8 PDMIF
  [12:0] PDLFCH116RCH0.LFH1
0x878561AC PDMIF
  [12:0] PDLFCH117RCH0.LFH1
0x878561B0 PDMIF
  [12:0] PDLFCH118RCH0.LFH1
0x878561B4 PDMIF
  [12:0] PDLFCH119RCH0.LFH1
0x878561B8 PDMIF
  [19:0] PDSDLTRCH0.SDETL
0x878561BC PDMIF
  [19:0] PDSDUTRCH0.SDETU
0x878561C0 PDMIF
  [2:0] PDDBCRCH0.DATRITHR
0x878561C4 PDMIF
  [28:16] PDSCTSRCH0.SCDH, [12:0] PDSCTSRCH0.SCDL
0x878561C8 PDMIF
  [19:0] PDOVLTRCH0.OVDL
0x878561CC PDMIF
  [19:0] PDOVUTRCH0.OVDU
0x878561E0 PDMIF
  [0] PDDRCRCH0.DATRE
0x878561E4 PDMIF
  [0] PDDCRCH0.DATC
0x878561E8 PDMIF
  [19:0] PDDRRCH0.DAT
0x878561EC PDMIF
  [7:0] PDDSRCH0.DATNUM
0x8785D000 SSIE0
  [30] SSICR.CKS, [29] SSICR.TUIEN, [28] SSICR.TOIEN, [27] SSICR.RUIEN, [26] SSICR.ROIEN, [25] SSICR.IIEN, [23:22] SSICR.FRM, [21:19] SSICR.DWL, [18:16] SSICR.SWL, [14] SSICR.MST, [13] SSICR.BCKP, [12] SSICR.LRCKP, [11] SSICR.SPDP, [10] SSICR.SDTA, [9] SSICR.PDTA, [8] SSICR.DEL, [7:4] SSICR.CKDV, [3] SSICR.MUEN, [1] SSICR.TEN, [0] SSICR.REN
0x8785D004 SSIE0
  [29] SSISR.TUIRQ, [28] SSISR.TOIRQ, [27] SSISR.RUIRQ, [26] SSISR.ROIRQ, [25] SSISR.IIRQ
0x8785D010 SSIE0
  [31] SSIFCR.AUCKE, [16] SSIFCR.SSIRST, [11] SSIFCR.BSW, [3] SSIFCR.TIE, [2] SSIFCR.RIE, [1] SSIFCR.TFRST, [0] SSIFCR.RFRST
0x8785D014 SSIE0
  [29:24] SSIFSR.TDC, [16] SSIFSR.TDE, [13:8] SSIFSR.RDC, [0] SSIFSR.RDF
0x8785D020 SSIE0
  [9] SSIOFR.BCKASTP, [8] SSIOFR.LRCONT, [1:0] SSIOFR.OMOD
0x8785D024 SSIE0
  [12:8] SSISCR.TDES, [4:0] SSISCR.RDFS
0x8785D100 SSIE1
  fields as SSIE0
0x8785D104 SSIE1
  [29] SSISR.TUIRQ, [28] SSISR.TOIRQ, [27] SSISR.RUIRQ, [26] SSISR.ROIRQ, [25] SSISR.IIRQ
0x8785D110 SSIE1
  [31] SSIFCR.AUCKE, [16] SSIFCR.SSIRST, [11] SSIFCR.BSW, [3] SSIFCR.TIE, [2] SSIFCR.RIE, [1] SSIFCR.TFRST, [0] SSIFCR.RFRST
0x8785D114 SSIE1
  [29:24] SSIFSR.TDC, [16] SSIFSR.TDE, [13:8] SSIFSR.RDC, [0] SSIFSR.RDF
0x8785D120 SSIE1
  [9] SSIOFR.BCKASTP, [8] SSIOFR.LRCONT, [1:0] SSIOFR.OMOD
0x8785D124 SSIE1
  [12:8] SSISCR.TDES, [4:0] SSISCR.RDFS
0x87867000 XSPIS0
  [16] L15CFG0.OEASTEX, [11] L15CFG0.WRMSKMD, [9:0] L15CFG0.PRTMD
0x87867004 XSPIS0
  [19:18] L15CFG1.ADDSIZE, [17:16] L15CFG1.FFMT, [15:8] L15CFG1.RDLATE, [7:0] L15CFG1.WRLATE
0x87867008 XSPIS0
  [26:16] L15CFG2.MRDFSIZE, [10:0] L15CFG2.MWRFSIZE
0x87867040 XSPIS0
  [31:12] L2CFG0.SLVMEMSZU, [11:0] L2CFG0.SLVMEMSZL
0x87867044 XSPIS0
  [31:24] L2CFG1.WRMCMD, [23:16] L2CFG1.WRRCMD, [15:8] L2CFG1.RDMCMD, [7:0] L2CFG1.RDRCMD
0x87867100 XSPIS0
  [31:0] TWADR.WADR
0x87867104 XSPIS0
  [20:0] TWLEN.WLEN
0x87867108 XSPIS0
  [0] TWCNT.WEN
0x87867140 XSPIS0
  [31:0] TRADR.RADR
0x87867144 XSPIS0
  [20:0] TRLEN.RLEN
0x87867148 XSPIS0
  [0] TRCNT.REN
0x87867180 XSPIS0
  [31] TRNSC.RSMSTB
0x87867200 XSPIS0
  [31] TWBS.ERR, [12:0] TWBS.VACSIZE
0x87867204 XSPIS0
  [20:0] TWTS.LWDSIZE
0x87867240 XSPIS0
  [31] TRBS.ERR, [12:0] TRBS.DATSIZE
0x87867244 XSPIS0
  [20:0] TRTS.LRDSIZE
0x87867280 XSPIS0
  [24] TS.SBERR, [21] TS.MFSEERR, [20] TS.UNKCERR, [17] TS.BUDFERR, [16] TS.BOVFERR, [13] TS.EV1, [12] TS.EV0, [9] TS.SRSTO, [8] TS.SRST, [4] TS.TCMP, [0] TS.TIP
0x87867284 XSPIS0
  [24] TSC.SBERRC, [21] TSC.MFSEERRC, [20] TSC.UNKCERRC, [17] TSC.BUDFERRC, [16] TSC.BOVFERRC, [13] TSC.EV1C, [12] TSC.EV0C, [9] TSC.SRSTOC, [8] TSC.SRSTC, [4] TSC.TCMPC
0x87867288 XSPIS0
  [13] TSS.EV1S, [12] TSS.EV0S, [9] TSS.SRSTOS
0x8786728C XSPIS0
  [24] TSXIE.SBERRXIE, [21] TSXIE.MFSEERRXIE, [20] TSXIE.UNKCERRXIE, [17] TSXIE.BUDFERRXIE, [16] TSXIE.BOVFERRXIE, [13] TSXIE.EV1XIE, [12] TSXIE.EV0XIE, [9] TSXIE.SRSTOXIE, [4] TSXIE.TCMPXIE
0x87867290 XSPIS0
  [24] TSSIE.SBERRSIE, [21] TSSIE.MFSEERRSIE, [20] TSSIE.UNKCERRSIE, [17] TSSIE.BUDFERRSIE, [16] TSSIE.BOVFERRSIE, [13] TSSIE.EV1SIE, [12] TSSIE.EV0SIE, [8] TSSIE.SRSTSIE, [4] TSSIE.TCMPSIE
0x878672C0 XSPIS0
  [31:16] TBI.VER, [12:0] TBI.BUFSIZE
0x878673FC XSPIS0
  [0] DIPCFG.SLVEN
0x87867400 XSPIS1
  [16] L15CFG0.OEASTEX, [11] L15CFG0.WRMSKMD, [9:0] L15CFG0.PRTMD
0x87867404 XSPIS1
  [19:18] L15CFG1.ADDSIZE, [17:16] L15CFG1.FFMT, [15:8] L15CFG1.RDLATE, [7:0] L15CFG1.WRLATE
0x87867408 XSPIS1
  [26:16] L15CFG2.MRDFSIZE, [10:0] L15CFG2.MWRFSIZE
0x87867440 XSPIS1
  [31:12] L2CFG0.SLVMEMSZU, [11:0] L2CFG0.SLVMEMSZL
0x87867444 XSPIS1
  [31:24] L2CFG1.WRMCMD, [23:16] L2CFG1.WRRCMD, [15:8] L2CFG1.RDMCMD, [7:0] L2CFG1.RDRCMD
0x87867500 XSPIS1
  [31:0] TWADR.WADR
0x87867504 XSPIS1
  [20:0] TWLEN.WLEN
0x87867508 XSPIS1
  [0] TWCNT.WEN
0x87867540 XSPIS1
  [31:0] TRADR.RADR
0x87867544 XSPIS1
  [20:0] TRLEN.RLEN
0x87867548 XSPIS1
  [0] TRCNT.REN
0x87867580 XSPIS1
  [31] TRNSC.RSMSTB
0x87867600 XSPIS1
  [31] TWBS.ERR, [12:0] TWBS.VACSIZE
0x87867604 XSPIS1
  [20:0] TWTS.LWDSIZE
0x87867640 XSPIS1
  [31] TRBS.ERR, [12:0] TRBS.DATSIZE
0x87867644 XSPIS1
  [20:0] TRTS.LRDSIZE
0x87867680 XSPIS1
  [24] TS.SBERR, [21] TS.MFSEERR, [20] TS.UNKCERR, [17] TS.BUDFERR, [16] TS.BOVFERR, [13] TS.EV1, [12] TS.EV0, [9] TS.SRSTO, [8] TS.SRST, [4] TS.TCMP, [0] TS.TIP
0x87867684 XSPIS1
  [24] TSC.SBERRC, [21] TSC.MFSEERRC, [20] TSC.UNKCERRC, [17] TSC.BUDFERRC, [16] TSC.BOVFERRC, [13] TSC.EV1C, [12] TSC.EV0C, [9] TSC.SRSTOC, [8] TSC.SRSTC, [4] TSC.TCMPC
0x87867688 XSPIS1
  [13] TSS.EV1S, [12] TSS.EV0S, [9] TSS.SRSTOS
0x8786768C XSPIS1
  [24] TSXIE.SBERRXIE, [21] TSXIE.MFSEERRXIE, [20] TSXIE.UNKCERRXIE, [17] TSXIE.BUDFERRXIE, [16] TSXIE.BOVFERRXIE, [13] TSXIE.EV1XIE, [12] TSXIE.EV0XIE, [9] TSXIE.SRSTOXIE, [4] TSXIE.TCMPXIE
0x87867690 XSPIS1
  [24] TSSIE.SBERRSIE, [21] TSSIE.MFSEERRSIE, [20] TSSIE.UNKCERRSIE, [17] TSSIE.BUDFERRSIE, [16] TSSIE.BOVFERRSIE, [13] TSSIE.EV1SIE, [12] TSSIE.EV0SIE, [8] TSSIE.SRSTSIE, [4] TSSIE.TCMPSIE
0x878676C0 XSPIS1
  [31:16] TBI.VER, [12:0] TBI.BUFSIZE
0x878677FC XSPIS1
  [0] DIPCFG.SLVEN
0x87868000 XSPI0
  [28:24] WRAPCFG.DSSFTCS1, [12:8] WRAPCFG.DSSFTCS0
0x87868004 XSPI0
  [17] COMCFG.OENEGEX, [16] COMCFG.OEASTEX
0x87868008 XSPI0
  [31:24] BMCFGCH[0].CMBTIM, [16] BMCFGCH[0].PREEN, [15:8] BMCFGCH[0].MWRSIZE, [7] BMCFGCH[0].MWRCOMB, [0] BMCFGCH[0].WRMD
0x8786800C XSPI0
  [31:24] BMCFGCH[1].CMBTIM, [16] BMCFGCH[1].PREEN, [15:8] BMCFGCH[1].MWRSIZE, [7] BMCFGCH[1].MWRCOMB, [0] BMCFGCH[1].WRMD
0x87868010 XSPI0
  [31:24] CMCFG0CS0.ADDRPCD, [23:16] CMCFG0CS0.ADDRPEN, [5] CMCFG0CS0.ARYAMD, [4] CMCFG0CS0.WPBSTMD, [3:2] CMCFG0CS0.ADDSIZE, [1:0] CMCFG0CS0.FFMT
0x87868014 XSPI0
  [20:16] CMCFG1CS0.RDLATE, [15:0] CMCFG1CS0.RDCMD
0x87868018 XSPI0
  [20:16] CMCFG2CS0.WRLATE, [15:0] CMCFG2CS0.WRCMD
0x87868020 XSPI0
  [31:24] CMCFG0CS1.ADDRPCD, [23:16] CMCFG0CS1.ADDRPEN, [5] CMCFG0CS1.ARYAMD, [4] CMCFG0CS1.WPBSTMD, [3:2] CMCFG0CS1.ADDSIZE, [1:0] CMCFG0CS1.FFMT
0x87868024 XSPI0
  [20:16] CMCFG1CS1.RDLATE, [15:0] CMCFG1CS1.RDCMD
0x87868028 XSPI0
  [20:16] CMCFG2CS1.WRLATE, [15:0] CMCFG2CS1.WRCMD
0x87868050 XSPI0
  [31:28] LIOCFGCS[0].DDRSMPEX, [27:24] LIOCFGCS[0].SDRSMPSFT, [23] LIOCFGCS[0].SDRSMPMD, [22] LIOCFGCS[0].SDRDRV, [21] LIOCFGCS[0].CSNEGEX, [20] LIOCFGCS[0].CSASTEX, [19:16] LIOCFGCS[0].CSMIN, [11] LIOCFGCS[0].WRMSKMD, [10] LIOCFGCS[0].LATEMD, [9:0] LIOCFGCS[0].PRTMD
0x87868054 XSPI0
  [31:28] LIOCFGCS[1].DDRSMPEX, [27:24] LIOCFGCS[1].SDRSMPSFT, [23] LIOCFGCS[1].SDRSMPMD, [22] LIOCFGCS[1].SDRDRV, [21] LIOCFGCS[1].CSNEGEX, [20] LIOCFGCS[1].CSASTEX, [19:16] LIOCFGCS[1].CSMIN, [11] LIOCFGCS[1].WRMSKMD, [10] LIOCFGCS[1].LATEMD, [9:0] LIOCFGCS[1].PRTMD
0x8786805C XSPI0
  [12] MEMEXTCFG.DSVLDMDCS1, [8] MEMEXTCFG.DSEXTMDCS1, [4] MEMEXTCFG.DSVLDMDCS0, [0] MEMEXTCFG.DSEXTMDCS0
0x87868060 XSPI0
  [3:2] BMCTL0.CH0CS1ACC, [1:0] BMCTL0.CH0CS0ACC
0x87868064 XSPI0
  [10] BMCTL1.PBUFCLRCH0, [8] BMCTL1.MWRPUSHCH0
0x87868068 XSPI0
  [16] CMCTLCH[0].XIPEN, [15:8] CMCTLCH[0].XIPEXCODE, [7:0] CMCTLCH[0].XIPENCODE
0x8786806C XSPI0
  [16] CMCTLCH[1].XIPEN, [15:8] CMCTLCH[1].XIPEXCODE, [7:0] CMCTLCH[1].XIPENCODE
0x87868070 XSPI0
  [27:24] CDCTL0.PERREP, [20:16] CDCTL0.PERITV, [5:4] CDCTL0.TRNUM, [3] CDCTL0.CSSEL, [1] CDCTL0.PERMD, [0] CDCTL0.TRREQ
0x87868074 XSPI0
  [31:0] CDCTL1.PEREXP
0x87868078 XSPI0
  [31:0] CDCTL2.PERMSK
0x87868080 XSPI0
  [31:16] CDTBUF0.CMD, [15] CDTBUF0.TRTYPE, [13:9] CDTBUF0.LATE, [8:5] CDTBUF0.DATASIZE, [4:2] CDTBUF0.ADDSIZE, [1:0] CDTBUF0.CMDSIZE
0x87868084 XSPI0
  [31:0] CDABUF0.ADD
0x87868088 XSPI0
  [31:0] CDD0BUF0.DATA
0x8786808C XSPI0
  [31:0] CDD1BUF0.DATA
0x87868090 XSPI0
  [31:16] CDTBUF1.CMD, [15] CDTBUF1.TRTYPE, [13:9] CDTBUF1.LATE, [8:5] CDTBUF1.DATASIZE, [4:2] CDTBUF1.ADDSIZE, [1:0] CDTBUF1.CMDSIZE
0x87868094 XSPI0
  [31:0] CDABUF1.ADD
0x87868098 XSPI0
  [31:0] CDD0BUF1.DATA
0x8786809C XSPI0
  [31:0] CDD1BUF1.DATA
0x878680A0 XSPI0
  [31:16] CDTBUF2.CMD, [15] CDTBUF2.TRTYPE, [13:9] CDTBUF2.LATE, [8:5] CDTBUF2.DATASIZE, [4:2] CDTBUF2.ADDSIZE, [1:0] CDTBUF2.CMDSIZE
0x878680A4 XSPI0
  [31:0] CDABUF2.ADD
0x878680A8 XSPI0
  [31:0] CDD0BUF2.DATA
0x878680AC XSPI0
  [31:0] CDD1BUF2.DATA
0x878680B0 XSPI0
  [31:16] CDTBUF3.CMD, [15] CDTBUF3.TRTYPE, [13:9] CDTBUF3.LATE, [8:5] CDTBUF3.DATASIZE, [4:2] CDTBUF3.ADDSIZE, [1:0] CDTBUF3.CMDSIZE
0x878680B4 XSPI0
  [31:0] CDABUF3.ADD
0x878680B8 XSPI0
  [31:0] CDD0BUF3.DATA
0x878680BC XSPI0
  [31:0] CDD1BUF3.DATA
0x87868100 XSPI0
  [31] LPCTL0.XD2VAL, [28:24] LPCTL0.XD2LEN, [23] LPCTL0.XD1VAL, [20:16] LPCTL0.XD1LEN, [5:4] LPCTL0.XDPIN, [3] LPCTL0.CSSEL, [0] LPCTL0.PATREQ
0x87868104 XSPI0
  [14:12] LPCTL1.RSTSU, [10:8] LPCTL1.RSTWID, [5:4] LPCTL1.RSTREP, [3] LPCTL1.CSSEL, [1:0] LPCTL1.PATREQ
0x87868108 XSPI0
  [17] LIOCTL.RSTCS1, [16] LIOCTL.RSTCS0, [1] LIOCTL.WPCS1, [0] LIOCTL.WPCS0
0x87868130 XSPI0
  [28:24] CCCTL0CS0.CASFTEND, [20:16] CCCTL0CS0.CASFTSTA, [12:8] CCCTL0CS0.CAITV, [1] CCCTL0CS0.CANOWR, [0] CCCTL0CS0.CAEN
0x87868134 XSPI0
  [28:24] CCCTL1CS0.CARDLATE, [20:16] CCCTL1CS0.CAWRLATE, [8:5] CCCTL1CS0.CADATASIZE, [4:2] CCCTL1CS0.CAADDSIZE, [1:0] CCCTL1CS0.CACMDSIZE
0x87868138 XSPI0
  [31:16] CCCTL2CS0.CARDCMD, [15:0] CCCTL2CS0.CAWRCMD
0x8786813C XSPI0
  [31:0] CCCTL3CS0.CAADD
0x87868140 XSPI0
  [31:0] CCCTL4CS0.CADATA
0x87868144 XSPI0
  [31:0] CCCTL5CS0.CADATA
0x87868148 XSPI0
  [31:0] CCCTL6CS0.CADATA
0x8786814C XSPI0
  [31:0] CCCTL7CS0.CADATA
0x87868150 XSPI0
  [28:24] CCCTL0CS1.CASFTEND, [20:16] CCCTL0CS1.CASFTSTA, [12:8] CCCTL0CS1.CAITV, [1] CCCTL0CS1.CANOWR, [0] CCCTL0CS1.CAEN
0x87868154 XSPI0
  [28:24] CCCTL1CS1.CARDLATE, [20:16] CCCTL1CS1.CAWRLATE, [8:5] CCCTL1CS1.CADATASIZE, [4:2] CCCTL1CS1.CAADDSIZE, [1:0] CCCTL1CS1.CACMDSIZE
0x87868158 XSPI0
  [31:16] CCCTL2CS1.CARDCMD, [15:0] CCCTL2CS1.CAWRCMD
0x8786815C XSPI0
  [31:0] CCCTL3CS1.CAADD
0x87868160 XSPI0
  [31:0] CCCTL4CS1.CADATA
0x87868164 XSPI0
  [31:0] CCCTL5CS1.CADATA
0x87868168 XSPI0
  [31:0] CCCTL6CS1.CADATA
0x8786816C XSPI0
  [31:0] CCCTL7CS1.CADATA
0x87868184 XSPI0
  [22] COMSTT.RSTOCS1, [21] COMSTT.INTCS1, [20] COMSTT.ECSCS1, [18] COMSTT.RSTOCS0, [17] COMSTT.INTCS0, [16] COMSTT.ECSCS0, [6] COMSTT.WRBUFNECH0, [4] COMSTT.PBUFNECH0, [0] COMSTT.MEMACCCH0
0x87868188 XSPI0
  [31:0] CASTTCS[0].CASUC
0x8786818C XSPI0
  [31:0] CASTTCS[1].CASUC
0x87868190 XSPI0
  [31] INTS.CASUCCS1, [30] INTS.CASUCCS0, [29] INTS.CAFAILCS1, [28] INTS.CAFAILCS0, [20] INTS.BUSERRCH0, [13] INTS.INTCS1, [12] INTS.INTCS0, [9] INTS.ECSCS1, [8] INTS.ECSCS0, [5] INTS.DSTOCS1, [4] INTS.DSTOCS0, [3] INTS.PERTO, [1] INTS.PATCMP, [0] INTS.CMDCMP
0x87868194 XSPI0
  [31] INTC.CASUCCS1C, [30] INTC.CASUCCS0C, [29] INTC.CAFAILCS1C, [28] INTC.CAFAILCS0C, [20] INTC.BUSERRCH0C, [13] INTC.INTCS1C, [12] INTC.INTCS0C, [9] INTC.ECSCS1C, [8] INTC.ECSCS0C, [5] INTC.DSTOCS1C, [4] INTC.DSTOCS0C, [3] INTC.PERTOC, [1] INTC.PATCMPC, [0] INTC.CMDCMPC
0x87868198 XSPI0
  [31] INTE.CASUCCS1E, [30] INTE.CASUCCS0E, [29] INTE.CAFAILCS1E, [28] INTE.CAFAILCS0E, [20] INTE.BUSERRCH0E, [13] INTE.INTCS1E, [12] INTE.INTCS0E, [9] INTE.ECSCS1E, [8] INTE.ECSCS0E, [5] INTE.DSTOCS1E, [4] INTE.DSTOCS0E, [3] INTE.PERTOE, [1] INTE.PATCMPE, [0] INTE.CMDCMPE
0x87868400 XSPI1
  [28:24] WRAPCFG.DSSFTCS1, [12:8] WRAPCFG.DSSFTCS0
0x87868404 XSPI1
  [17] COMCFG.OENEGEX, [16] COMCFG.OEASTEX
0x87868408 XSPI1
  [31:24] BMCFGCH[0].CMBTIM, [16] BMCFGCH[0].PREEN, [15:8] BMCFGCH[0].MWRSIZE, [7] BMCFGCH[0].MWRCOMB, [0] BMCFGCH[0].WRMD
0x8786840C XSPI1
  [31:24] BMCFGCH[1].CMBTIM, [16] BMCFGCH[1].PREEN, [15:8] BMCFGCH[1].MWRSIZE, [7] BMCFGCH[1].MWRCOMB, [0] BMCFGCH[1].WRMD
0x87868410 XSPI1
  [31:24] CMCFG0CS0.ADDRPCD, [23:16] CMCFG0CS0.ADDRPEN, [5] CMCFG0CS0.ARYAMD, [4] CMCFG0CS0.WPBSTMD, [3:2] CMCFG0CS0.ADDSIZE, [1:0] CMCFG0CS0.FFMT
0x87868414 XSPI1
  [20:16] CMCFG1CS0.RDLATE, [15:0] CMCFG1CS0.RDCMD
0x87868418 XSPI1
  [20:16] CMCFG2CS0.WRLATE, [15:0] CMCFG2CS0.WRCMD
0x87868420 XSPI1
  [31:24] CMCFG0CS1.ADDRPCD, [23:16] CMCFG0CS1.ADDRPEN, [5] CMCFG0CS1.ARYAMD, [4] CMCFG0CS1.WPBSTMD, [3:2] CMCFG0CS1.ADDSIZE, [1:0] CMCFG0CS1.FFMT
0x87868424 XSPI1
  [20:16] CMCFG1CS1.RDLATE, [15:0] CMCFG1CS1.RDCMD
0x87868428 XSPI1
  [20:16] CMCFG2CS1.WRLATE, [15:0] CMCFG2CS1.WRCMD
0x87868450 XSPI1
  [31:28] LIOCFGCS[0].DDRSMPEX, [27:24] LIOCFGCS[0].SDRSMPSFT, [23] LIOCFGCS[0].SDRSMPMD, [22] LIOCFGCS[0].SDRDRV, [21] LIOCFGCS[0].CSNEGEX, [20] LIOCFGCS[0].CSASTEX, [19:16] LIOCFGCS[0].CSMIN, [11] LIOCFGCS[0].WRMSKMD, [10] LIOCFGCS[0].LATEMD, [9:0] LIOCFGCS[0].PRTMD
0x87868454 XSPI1
  [31:28] LIOCFGCS[1].DDRSMPEX, [27:24] LIOCFGCS[1].SDRSMPSFT, [23] LIOCFGCS[1].SDRSMPMD, [22] LIOCFGCS[1].SDRDRV, [21] LIOCFGCS[1].CSNEGEX, [20] LIOCFGCS[1].CSASTEX, [19:16] LIOCFGCS[1].CSMIN, [11] LIOCFGCS[1].WRMSKMD, [10] LIOCFGCS[1].LATEMD, [9:0] LIOCFGCS[1].PRTMD
0x8786845C XSPI1
  [12] MEMEXTCFG.DSVLDMDCS1, [8] MEMEXTCFG.DSEXTMDCS1, [4] MEMEXTCFG.DSVLDMDCS0, [0] MEMEXTCFG.DSEXTMDCS0
0x87868460 XSPI1
  [3:2] BMCTL0.CH0CS1ACC, [1:0] BMCTL0.CH0CS0ACC
0x87868464 XSPI1
  [10] BMCTL1.PBUFCLRCH0, [8] BMCTL1.MWRPUSHCH0
0x87868468 XSPI1
  [16] CMCTLCH[0].XIPEN, [15:8] CMCTLCH[0].XIPEXCODE, [7:0] CMCTLCH[0].XIPENCODE
0x8786846C XSPI1
  [16] CMCTLCH[1].XIPEN, [15:8] CMCTLCH[1].XIPEXCODE, [7:0] CMCTLCH[1].XIPENCODE
0x87868470 XSPI1
  [27:24] CDCTL0.PERREP, [20:16] CDCTL0.PERITV, [5:4] CDCTL0.TRNUM, [3] CDCTL0.CSSEL, [1] CDCTL0.PERMD, [0] CDCTL0.TRREQ
0x87868474 XSPI1
  [31:0] CDCTL1.PEREXP
0x87868478 XSPI1
  [31:0] CDCTL2.PERMSK
0x87868480 XSPI1
  [31:16] CDTBUF0.CMD, [15] CDTBUF0.TRTYPE, [13:9] CDTBUF0.LATE, [8:5] CDTBUF0.DATASIZE, [4:2] CDTBUF0.ADDSIZE, [1:0] CDTBUF0.CMDSIZE
0x87868484 XSPI1
  [31:0] CDABUF0.ADD
0x87868488 XSPI1
  [31:0] CDD0BUF0.DATA
0x8786848C XSPI1
  [31:0] CDD1BUF0.DATA
0x87868490 XSPI1
  [31:16] CDTBUF1.CMD, [15] CDTBUF1.TRTYPE, [13:9] CDTBUF1.LATE, [8:5] CDTBUF1.DATASIZE, [4:2] CDTBUF1.ADDSIZE, [1:0] CDTBUF1.CMDSIZE
0x87868494 XSPI1
  [31:0] CDABUF1.ADD
0x87868498 XSPI1
  [31:0] CDD0BUF1.DATA
0x8786849C XSPI1
  [31:0] CDD1BUF1.DATA
0x878684A0 XSPI1
  [31:16] CDTBUF2.CMD, [15] CDTBUF2.TRTYPE, [13:9] CDTBUF2.LATE, [8:5] CDTBUF2.DATASIZE, [4:2] CDTBUF2.ADDSIZE, [1:0] CDTBUF2.CMDSIZE
0x878684A4 XSPI1
  [31:0] CDABUF2.ADD
0x878684A8 XSPI1
  [31:0] CDD0BUF2.DATA
0x878684AC XSPI1
  [31:0] CDD1BUF2.DATA
0x878684B0 XSPI1
  [31:16] CDTBUF3.CMD, [15] CDTBUF3.TRTYPE, [13:9] CDTBUF3.LATE, [8:5] CDTBUF3.DATASIZE, [4:2] CDTBUF3.ADDSIZE, [1:0] CDTBUF3.CMDSIZE
0x878684B4 XSPI1
  [31:0] CDABUF3.ADD
0x878684B8 XSPI1
  [31:0] CDD0BUF3.DATA
0x878684BC XSPI1
  [31:0] CDD1BUF3.DATA
0x87868500 XSPI1
  [31] LPCTL0.XD2VAL, [28:24] LPCTL0.XD2LEN, [23] LPCTL0.XD1VAL, [20:16] LPCTL0.XD1LEN, [5:4] LPCTL0.XDPIN, [3] LPCTL0.CSSEL, [0] LPCTL0.PATREQ
0x87868504 XSPI1
  [14:12] LPCTL1.RSTSU, [10:8] LPCTL1.RSTWID, [5:4] LPCTL1.RSTREP, [3] LPCTL1.CSSEL, [1:0] LPCTL1.PATREQ
0x87868508 XSPI1
  [17] LIOCTL.RSTCS1, [16] LIOCTL.RSTCS0, [1] LIOCTL.WPCS1, [0] LIOCTL.WPCS0
0x87868530 XSPI1
  [28:24] CCCTL0CS0.CASFTEND, [20:16] CCCTL0CS0.CASFTSTA, [12:8] CCCTL0CS0.CAITV, [1] CCCTL0CS0.CANOWR, [0] CCCTL0CS0.CAEN
0x87868534 XSPI1
  [28:24] CCCTL1CS0.CARDLATE, [20:16] CCCTL1CS0.CAWRLATE, [8:5] CCCTL1CS0.CADATASIZE, [4:2] CCCTL1CS0.CAADDSIZE, [1:0] CCCTL1CS0.CACMDSIZE
0x87868538 XSPI1
  [31:16] CCCTL2CS0.CARDCMD, [15:0] CCCTL2CS0.CAWRCMD
0x8786853C XSPI1
  [31:0] CCCTL3CS0.CAADD
0x87868540 XSPI1
  [31:0] CCCTL4CS0.CADATA
0x87868544 XSPI1
  [31:0] CCCTL5CS0.CADATA
0x87868548 XSPI1
  [31:0] CCCTL6CS0.CADATA
0x8786854C XSPI1
  [31:0] CCCTL7CS0.CADATA
0x87868550 XSPI1
  [28:24] CCCTL0CS1.CASFTEND, [20:16] CCCTL0CS1.CASFTSTA, [12:8] CCCTL0CS1.CAITV, [1] CCCTL0CS1.CANOWR, [0] CCCTL0CS1.CAEN
0x87868554 XSPI1
  [28:24] CCCTL1CS1.CARDLATE, [20:16] CCCTL1CS1.CAWRLATE, [8:5] CCCTL1CS1.CADATASIZE, [4:2] CCCTL1CS1.CAADDSIZE, [1:0] CCCTL1CS1.CACMDSIZE
0x87868558 XSPI1
  [31:16] CCCTL2CS1.CARDCMD, [15:0] CCCTL2CS1.CAWRCMD
0x8786855C XSPI1
  [31:0] CCCTL3CS1.CAADD
0x87868560 XSPI1
  [31:0] CCCTL4CS1.CADATA
0x87868564 XSPI1
  [31:0] CCCTL5CS1.CADATA
0x87868568 XSPI1
  [31:0] CCCTL6CS1.CADATA
0x8786856C XSPI1
  [31:0] CCCTL7CS1.CADATA
0x87868584 XSPI1
  [22] COMSTT.RSTOCS1, [21] COMSTT.INTCS1, [20] COMSTT.ECSCS1, [18] COMSTT.RSTOCS0, [17] COMSTT.INTCS0, [16] COMSTT.ECSCS0, [6] COMSTT.WRBUFNECH0, [4] COMSTT.PBUFNECH0, [0] COMSTT.MEMACCCH0
0x87868588 XSPI1
  [31:0] CASTTCS[0].CASUC
0x8786858C XSPI1
  [31:0] CASTTCS[1].CASUC
0x87868590 XSPI1
  [31] INTS.CASUCCS1, [30] INTS.CASUCCS0, [29] INTS.CAFAILCS1, [28] INTS.CAFAILCS0, [20] INTS.BUSERRCH0, [13] INTS.INTCS1, [12] INTS.INTCS0, [9] INTS.ECSCS1, [8] INTS.ECSCS0, [5] INTS.DSTOCS1, [4] INTS.DSTOCS0, [3] INTS.PERTO, [1] INTS.PATCMP, [0] INTS.CMDCMP
0x87868594 XSPI1
  [31] INTC.CASUCCS1C, [30] INTC.CASUCCS0C, [29] INTC.CAFAILCS1C, [28] INTC.CAFAILCS0C, [20] INTC.BUSERRCH0C, [13] INTC.INTCS1C, [12] INTC.INTCS0C, [9] INTC.ECSCS1C, [8] INTC.ECSCS0C, [5] INTC.DSTOCS1C, [4] INTC.DSTOCS0C, [3] INTC.PERTOC, [1] INTC.PATCMPC, [0] INTC.CMDCMPC
0x87868598 XSPI1
  [31] INTE.CASUCCS1E, [30] INTE.CASUCCS0E, [29] INTE.CAFAILCS1E, [28] INTE.CAFAILCS0E, [20] INTE.BUSERRCH0E, [13] INTE.INTCS1E, [12] INTE.INTCS0E, [9] INTE.ECSCS1E, [8] INTE.ECSCS0E, [5] INTE.DSTOCS1E, [4] INTE.DSTOCS0E, [3] INTE.PERTOE, [1] INTE.PATCMPE, [0] INTE.CMDCMPE
0x87868800 DOTF0
  [31:12] CONVAREAST.CONVAREAST
0x87868804 DOTF0
  [31:12] CONVAREAED.CONVAREAED
0x87868900 DOTF1
  [31:12] CONVAREAST.CONVAREAST
0x87868904 DOTF1
  [31:12] CONVAREAED.CONVAREAED
{0x87C00000+0x20*i} PORT{i} (i=0..9)
  [n+16] PCNTR1.PODR{n:02} (n=0..15), [n] PCNTR1.PDR{n:02} (n=0..15), [n] PDR.PDR{n:02} (n=0..15)
{0x87C00002+0x20*i} PORT{i} 16-bit (i=0..9)
  [n] PODR.PODR{n:02} (n=0..15)
{0x87C00004+0x20*i} PORT{i} (i=0..9)
  [n] PCNTR2.PIDR{n:02} (n=0..15), [n] PIDR.PIDR{n:02} (n=0..15)
{0x87C00008+0x20*i} PORT{i} (i=0..9)
  [n+16] PCNTR3.PORR{n:02} (n=0..15), [n] PCNTR3.POSR{n:02} (n=0..15), [n] POSR.POSR{n:02} (n=0..15)
{0x87C0000A+0x20*i} PORT{i} 16-bit (i=0..9)
  [n] PORR.PORR{n:02} (n=0..15)
0x87C00140 PORTA
  fields as PORT0
0x87C00142 PORTA 16-bit
  [n] PODR.PODR{n:02} (n=0..15)
0x87C00144 PORTA
  [n] PCNTR2.PIDR{n:02} (n=0..15), [n] PIDR.PIDR{n:02} (n=0..15)
0x87C00148 PORTA
  [n+16] PCNTR3.PORR{n:02} (n=0..15), [n] PCNTR3.POSR{n:02} (n=0..15), [n] POSR.POSR{n:02} (n=0..15)
0x87C0014A PORTA 16-bit
  [n] PORR.PORR{n:02} (n=0..15)
0x87C00160 PORTB
  fields as PORT0
0x87C00162 PORTB 16-bit
  [n] PODR.PODR{n:02} (n=0..15)
0x87C00164 PORTB
  [n+16] PCNTR2.EIDR{n:02} (n=0..7), [n] PCNTR2.PIDR{n:02} (n=0..15), [n] PIDR.PIDR{n:02} (n=0..15)
0x87C00166 PORTB 16-bit
  [n] EIDR.EIDR{n:02} (n=0..7)
0x87C00168 PORTB
  [n+16] PCNTR3.PORR{n:02} (n=0..15), [n] PCNTR3.POSR{n:02} (n=0..15), [n] POSR.POSR{n:02} (n=0..15)
0x87C0016A PORTB 16-bit
  [n] PORR.PORR{n:02} (n=0..15)
0x87C0016C PORTB
  [n+16] PCNTR4.EORR{n:02} (n=0..7), [n] PCNTR4.EOSR{n:02} (n=0..7), [n] EOSR.EOSR{n:02} (n=0..7)
0x87C0016E PORTB 16-bit
  [n] EORR.EORR{n:02} (n=0..7)
0x87C00180 PORTC
  fields as PORT0
0x87C00182 PORTC 16-bit
  [n] PODR.PODR{n:02} (n=0..15)
0x87C00184 PORTC
  [n+16] PCNTR2.EIDR{n:02} (n=0..7), [n] PCNTR2.PIDR{n:02} (n=0..15), [n] PIDR.PIDR{n:02} (n=0..15)
0x87C00186 PORTC 16-bit
  [n] EIDR.EIDR{n:02} (n=0..7)
0x87C00188 PORTC
  [n+16] PCNTR3.PORR{n:02} (n=0..15), [n] PCNTR3.POSR{n:02} (n=0..15), [n] POSR.POSR{n:02} (n=0..15)
0x87C0018A PORTC 16-bit
  [n] PORR.PORR{n:02} (n=0..15)
0x87C0018C PORTC
  [n+16] PCNTR4.EORR{n:02} (n=0..7), [n] PCNTR4.EOSR{n:02} (n=0..7), [n] EOSR.EOSR{n:02} (n=0..7)
0x87C0018E PORTC 16-bit
  [n] EORR.EORR{n:02} (n=0..7)
0x87C001A0 PORTD
  fields as PORT0
0x87C001A2 PORTD 16-bit
  [n] PODR.PODR{n:02} (n=0..15)
0x87C001A4 PORTD
  [n+16] PCNTR2.EIDR{n:02} (n=0..7), [n] PCNTR2.PIDR{n:02} (n=0..15), [n] PIDR.PIDR{n:02} (n=0..15)
0x87C001A6 PORTD 16-bit
  [n] EIDR.EIDR{n:02} (n=0..7)
0x87C001A8 PORTD
  [n+16] PCNTR3.PORR{n:02} (n=0..15), [n] PCNTR3.POSR{n:02} (n=0..15), [n] POSR.POSR{n:02} (n=0..15)
0x87C001AA PORTD 16-bit
  [n] PORR.PORR{n:02} (n=0..15)
0x87C001AC PORTD
  [n+16] PCNTR4.EORR{n:02} (n=0..7), [n] PCNTR4.EOSR{n:02} (n=0..7), [n] EOSR.EOSR{n:02} (n=0..7)
0x87C001AE PORTD 16-bit
  [n] EORR.EORR{n:02} (n=0..7)
0x87C001C0 PORTE
  fields as PORT0
0x87C001C2 PORTE 16-bit
  [n] PODR.PODR{n:02} (n=0..15)
0x87C001C4 PORTE
  [n+16] PCNTR2.EIDR{n:02} (n=0..7), [n] PCNTR2.PIDR{n:02} (n=0..15), [n] PIDR.PIDR{n:02} (n=0..15)
0x87C001C6 PORTE 16-bit
  [n] EIDR.EIDR{n:02} (n=0..7)
0x87C001C8 PORTE
  [n+16] PCNTR3.PORR{n:02} (n=0..15), [n] PCNTR3.POSR{n:02} (n=0..15), [n] POSR.POSR{n:02} (n=0..15)
0x87C001CA PORTE 16-bit
  [n] PORR.PORR{n:02} (n=0..15)
0x87C001CC PORTE
  [n+16] PCNTR4.EORR{n:02} (n=0..7), [n] PCNTR4.EOSR{n:02} (n=0..7), [n] EOSR.EOSR{n:02} (n=0..7)
0x87C001CE PORTE 16-bit
  [n] EORR.EORR{n:02} (n=0..7)
0x87C001E0 PORTF
  fields as PORT0
0x87C001E2 PORTF 16-bit
  [n] PODR.PODR{n:02} (n=0..15)
0x87C001E4 PORTF
  [n] PCNTR2.PIDR{n:02} (n=0..15), [n] PIDR.PIDR{n:02} (n=0..15)
0x87C001E8 PORTF
  [n+16] PCNTR3.PORR{n:02} (n=0..15), [n] PCNTR3.POSR{n:02} (n=0..15), [n] POSR.POSR{n:02} (n=0..15)
0x87C001EA PORTF 16-bit
  [n] PORR.PORR{n:02} (n=0..15)
0x87C00200 PORTG
  fields as PORT0
0x87C00202 PORTG 16-bit
  [n] PODR.PODR{n:02} (n=0..15)
0x87C00204 PORTG
  [n] PCNTR2.PIDR{n:02} (n=0..15), [n] PIDR.PIDR{n:02} (n=0..15)
0x87C00208 PORTG
  [n+16] PCNTR3.PORR{n:02} (n=0..15), [n] PCNTR3.POSR{n:02} (n=0..15), [n] POSR.POSR{n:02} (n=0..15)
0x87C0020A PORTG 16-bit
  [n] PORR.PORR{n:02} (n=0..15)
0x87C00800 PFS
  [30:24] P000PFS.PSEL, [16] P000PFS.PMR, [15] P000PFS.ASEL, [14] P000PFS.ISEL, [11:8] P000PFS.DSCR, [6] P000PFS.NCODR, [4] P000PFS.PCR, [2] P000PFS.PDR, [1] P000PFS.PIDR, [0] P000PFS.PODR
0x87C00AC0 PFS
  [30:24] PB00PFS.PSEL, [16] PB00PFS.PMR, [15] PB00PFS.ASEL, [14] PB00PFS.ISEL, [13:12] PB00PFS.EOFR, [11:8] PB00PFS.DSCR, [6] PB00PFS.NCODR, [4] PB00PFS.PCR, [2] PB00PFS.PDR, [1] PB00PFS.PIDR, [0] PB00PFS.PODR
0x87C00D14 PFS 8-bit
  [7] PWPR_S.B0WI, [6] PWPR_S.PFSWE
0x87C00D30 PFS 16-bit
  [n] P0SAR.P{n:03}SA (n=0..15)
0x87C00D34 PFS 16-bit
  [n-100] P1SAR.P{n}SA (n=100..115)
0x87C00D38 PFS 16-bit
  [n-200] P2SAR.P{n}SA (n=200..215)
0x87C00D3C PFS 16-bit
  [n-300] P3SAR.P{n}SA (n=300..315)
0x87C00D40 PFS 16-bit
  [n-400] P4SAR.P{n}SA (n=400..415)
0x87C00D44 PFS 16-bit
  [n-500] P5SAR.P{n}SA (n=500..515)
0x87C00D48 PFS 16-bit
  [n-600] P6SAR.P{n}SA (n=600..615)
0x87C00D4C PFS 16-bit
  [n-700] P7SAR.P{n}SA (n=700..715)
0x87C00D50 PFS 16-bit
  [n-800] P8SAR.P{n}SA (n=800..815)
0x87C00D54 PFS 16-bit
  [n-900] P9SAR.P{n}SA (n=900..915)
0x87C00D58 PFS 16-bit
  [n] PASAR.PA{n:02}SA (n=0..15)
0x87C00D5C PFS 16-bit
  [n] PBSAR.PB{n:02}SA (n=0..15)
0x87C00D60 PFS 16-bit
  [n] PCSAR.PC{n:02}SA (n=0..15)
0x87C00D64 PFS 16-bit
  [n] PDSAR.PD{n:02}SA (n=0..15)
0x87C00D68 PFS 16-bit
  [n] PESAR.PE{n:02}SA (n=0..15)
0x87C00D6C PFS 16-bit
  [n] PFSAR.PF{n:02}SA (n=0..15)
0x87C00D70 PFS 16-bit
  [n] PGSAR.PG{n:02}SA (n=0..15)
